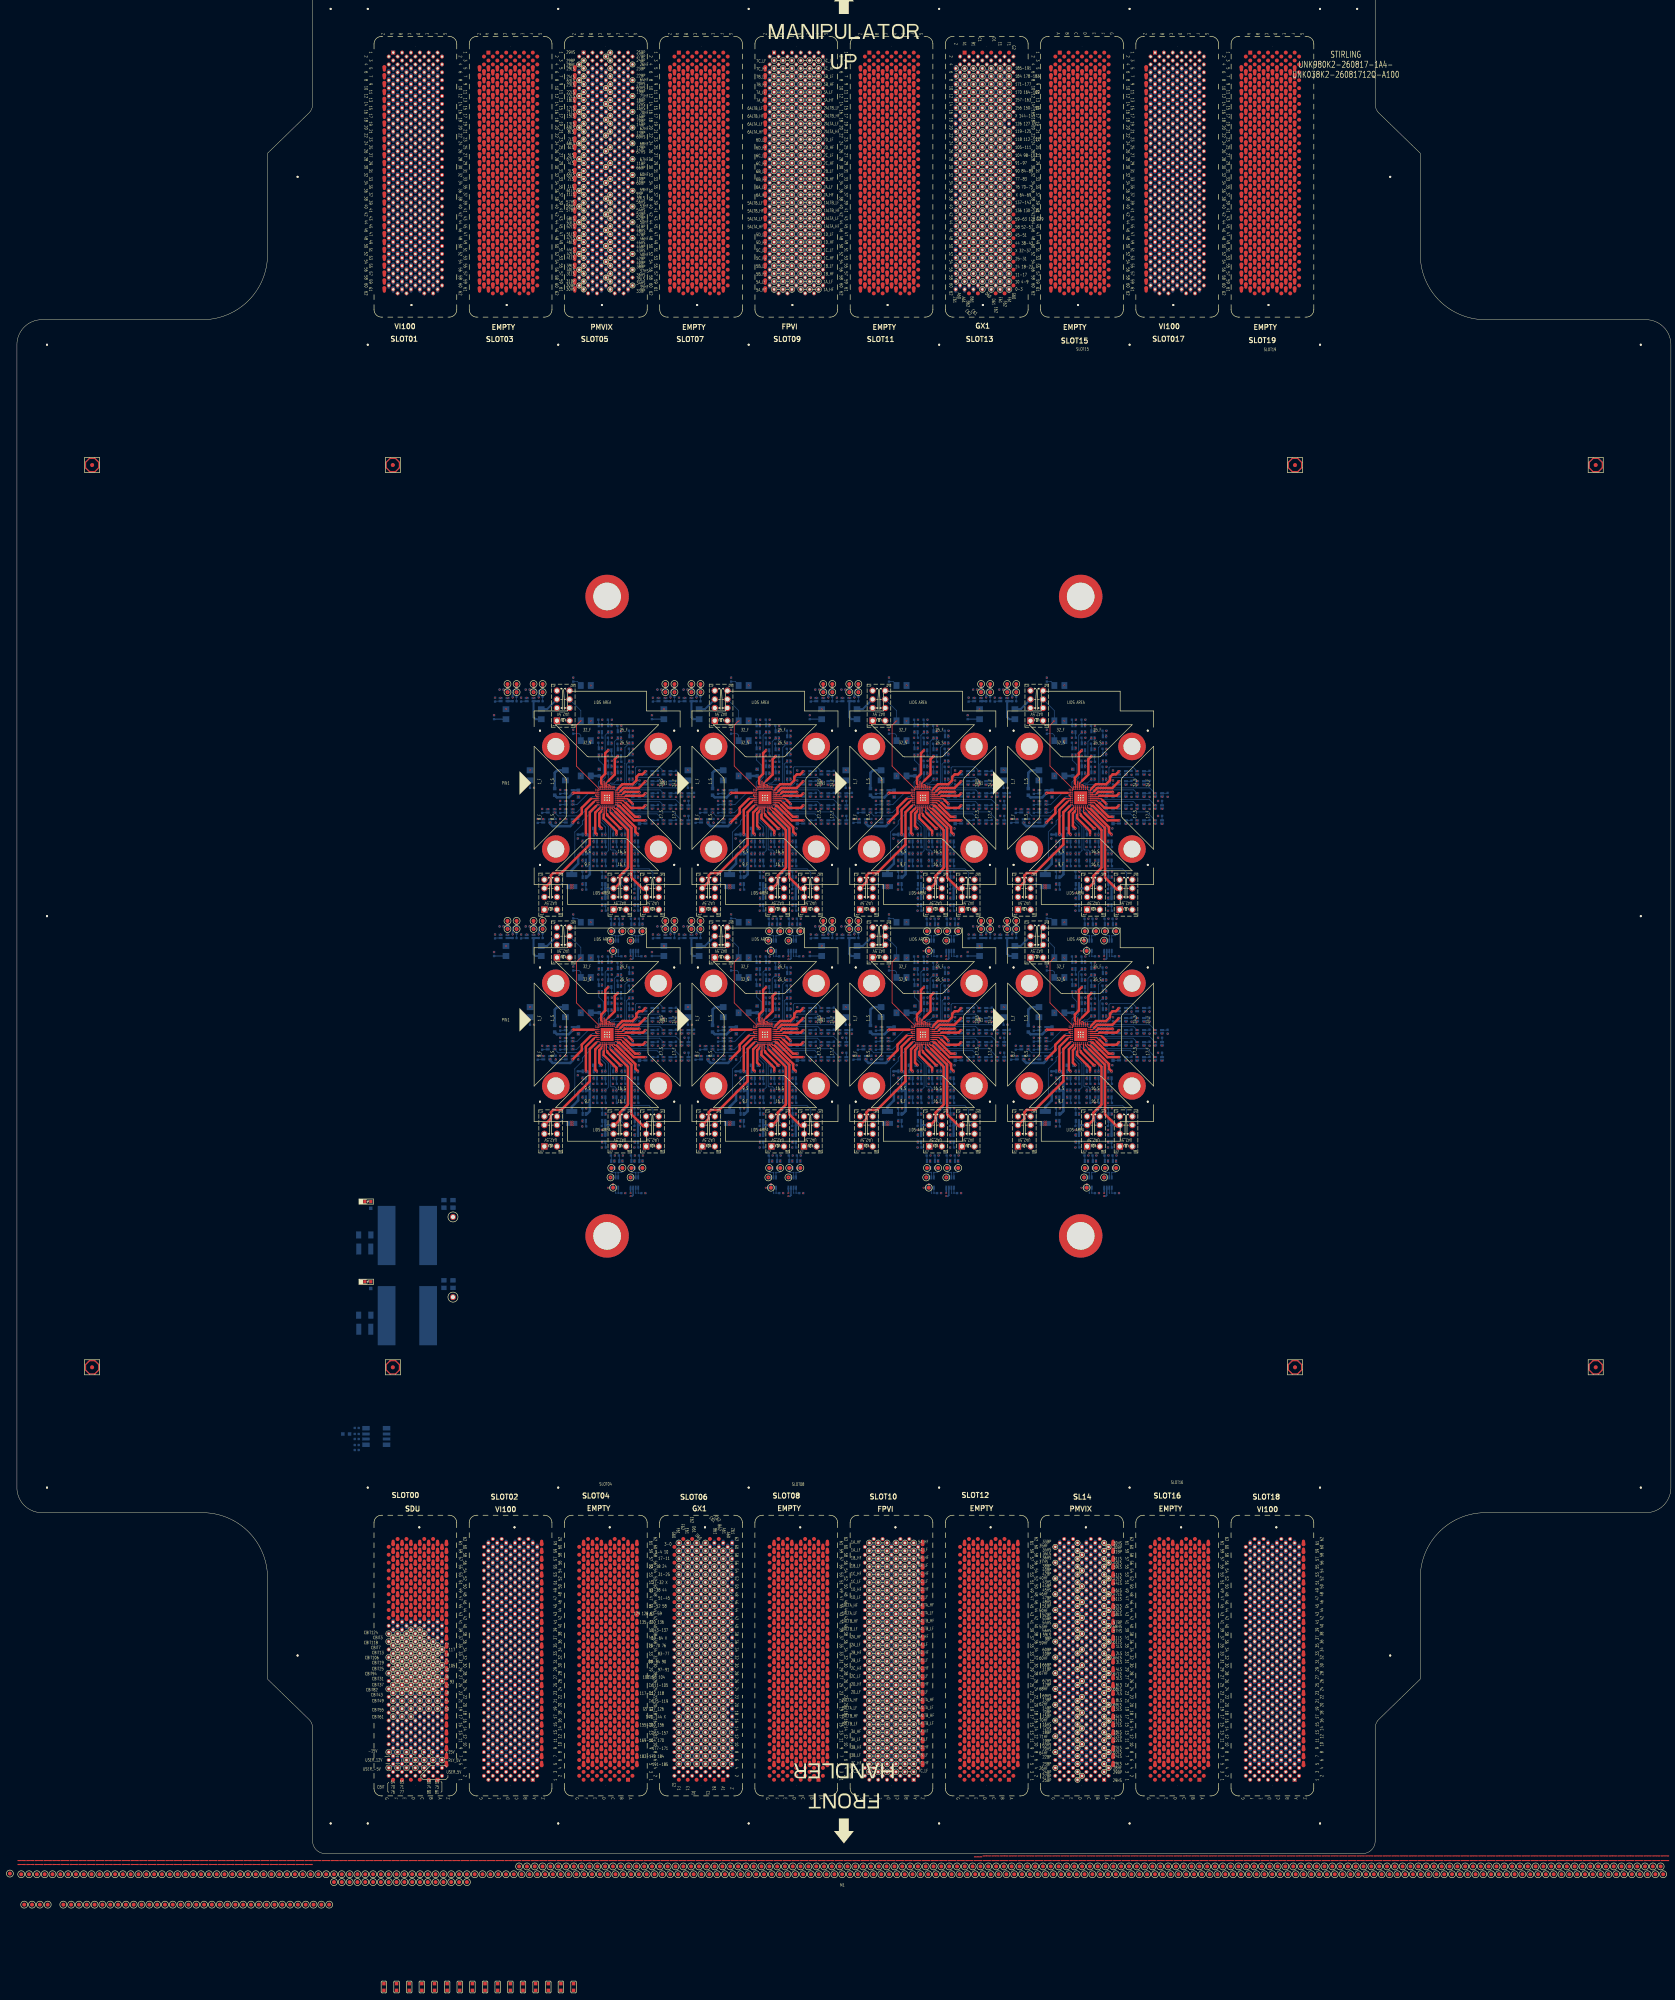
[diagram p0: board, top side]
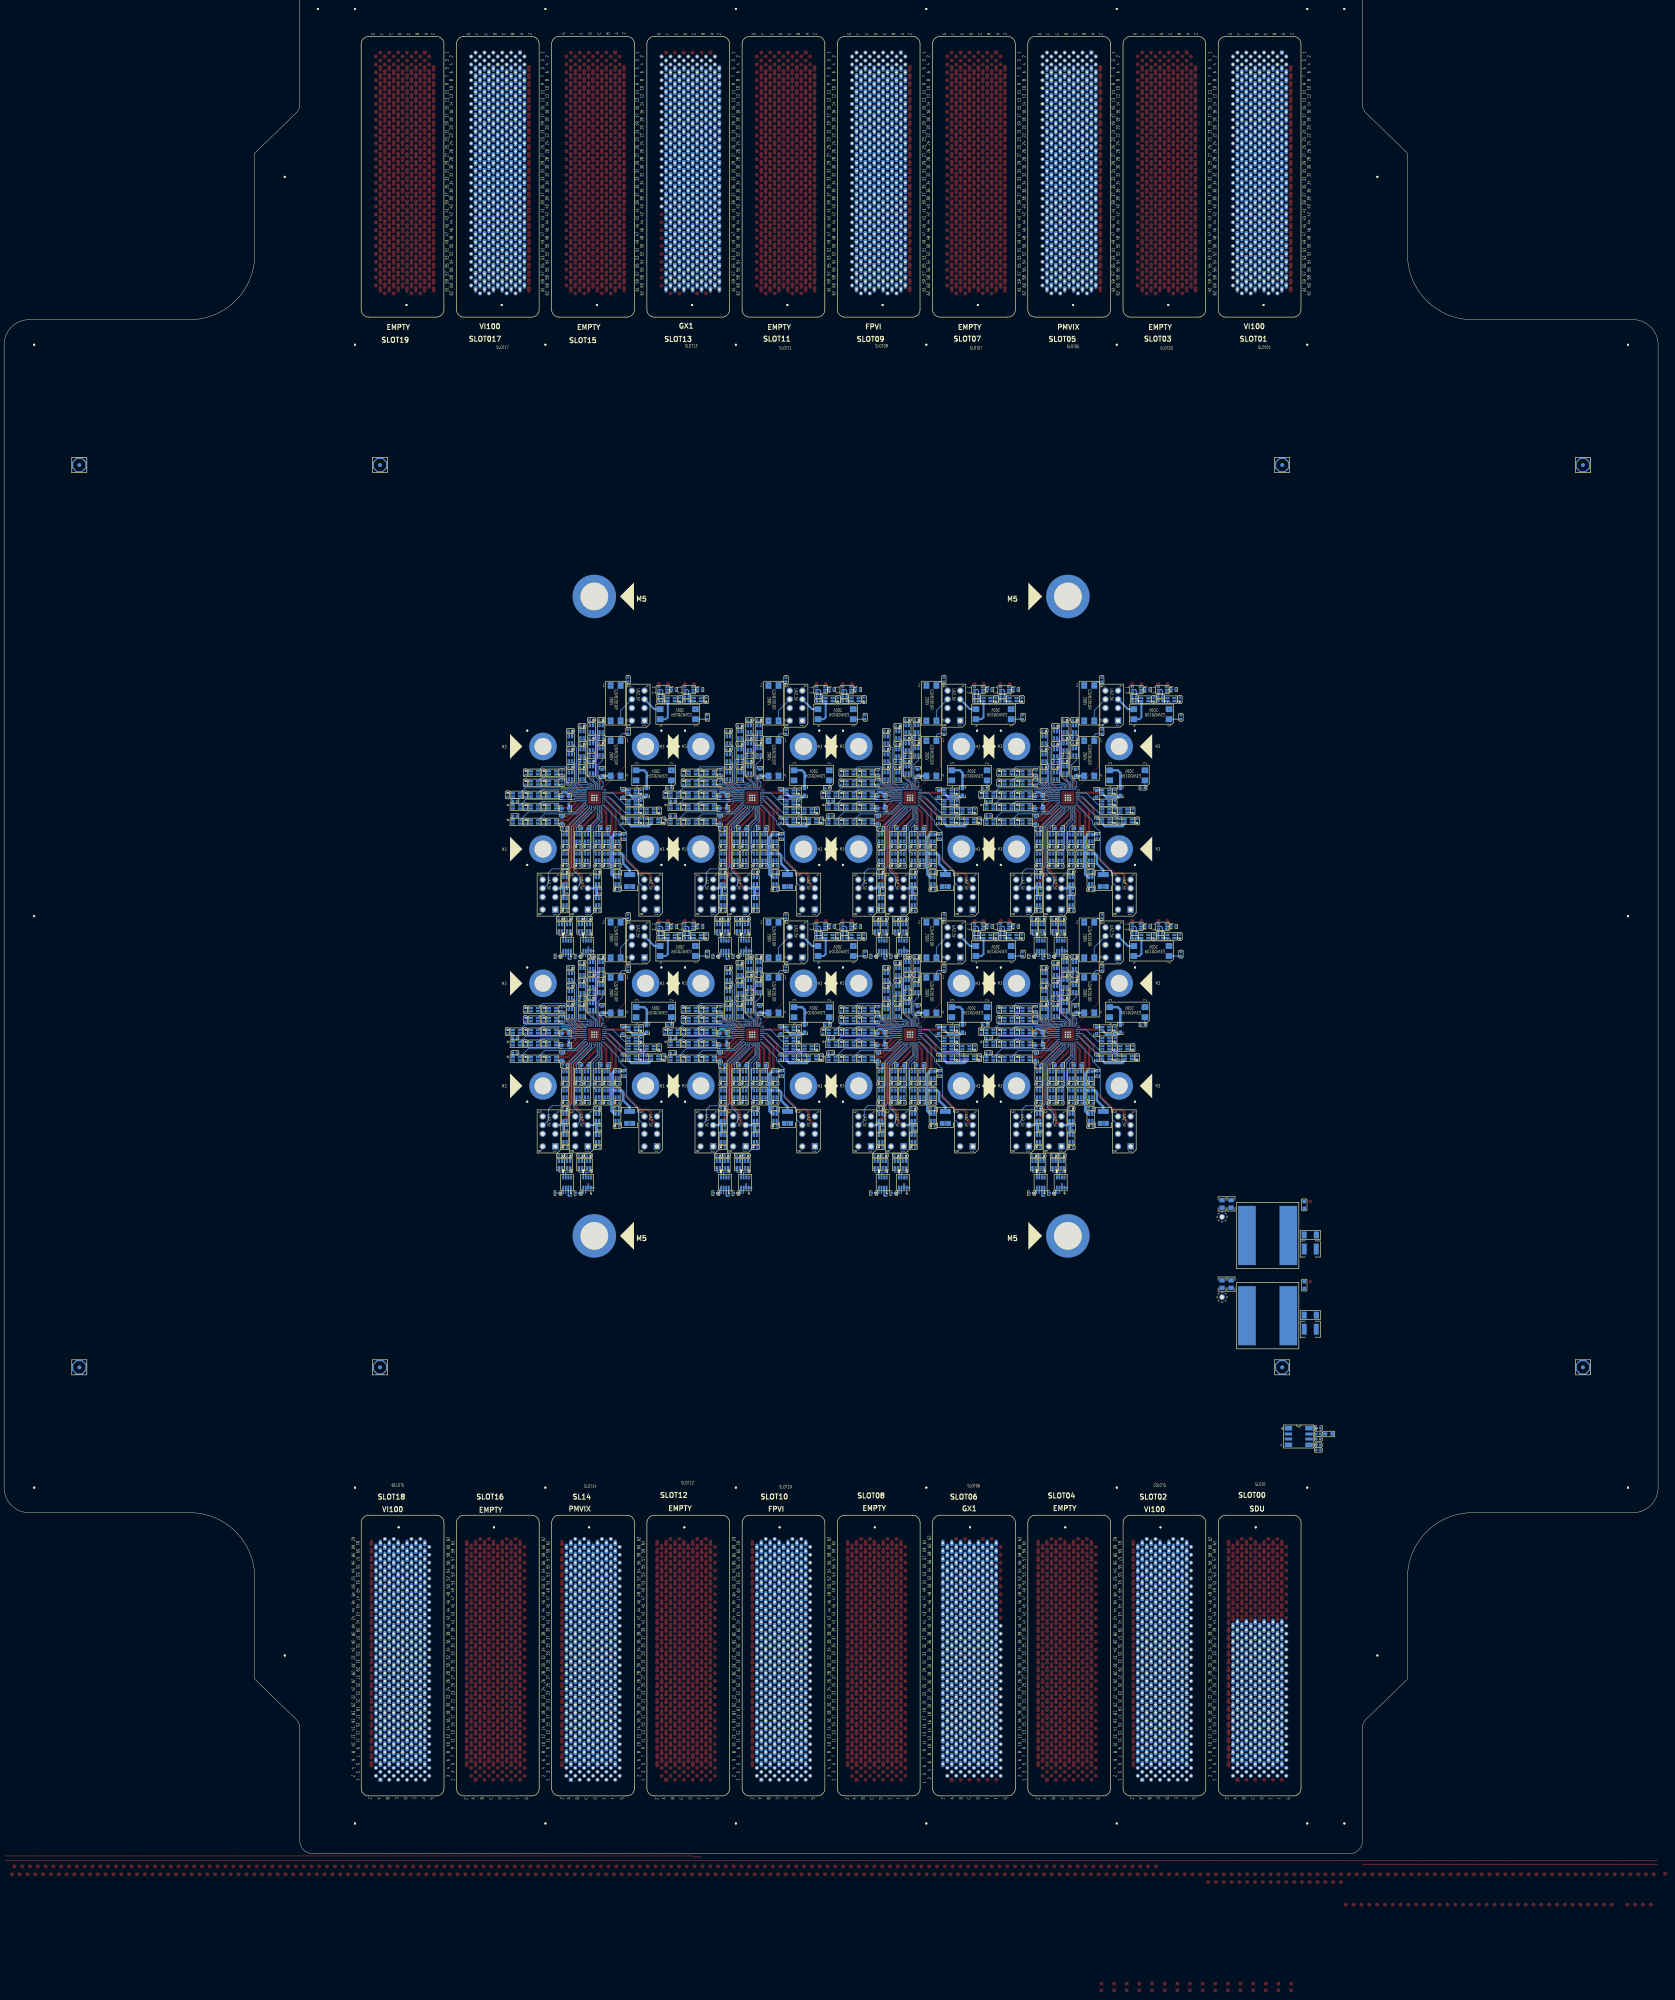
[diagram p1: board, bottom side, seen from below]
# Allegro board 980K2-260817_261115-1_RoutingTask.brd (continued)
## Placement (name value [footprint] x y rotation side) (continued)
NOREF#3645  -  []  244.95 264.23 90 top
NOREF#3646  -  []  271.95 178.07 0 top
NOREF#3647  -  []  269.12 251.6 90 top
NOREF#3648  -  []  163.84 264.78 90 top
NOREF#3649  -  []  188.78 288.49 0 top
NOREF#3650  -  []  277.37 240.3 90 top
NOREF#3651  -  []  168.42 265.58 0 top
NOREF#3652  -  []  279.72 274.65 90 top
NOREF#3653  -  []  146.88 283.95 0 top
NOREF#3654  -  []  152.72 197.6 0 top
NOREF#3655  -  []  237.37 251.6 90 top
NOREF#3656  -  []  216.83 227.03 0 top
NOREF#3657  -  []  133.36 201.22 0 top
NOREF#3658  -  []  268.44 181.72 90 top
NOREF#3659  -  []  195.05 218.82 0 top
NOREF#3660  -  []  149.78 228.3 0 top
NOREF#3661  -  []  243.84 204.78 90 top
NOREF#3662  -  []  180.95 268.91 90 top
NOREF#3663  -  []  232.13 284.66 0 top
NOREF#3664  -  []  268.32 245.63 0 top
NOREF#3665  -  []  159.06 178.07 0 top
NOREF#3666  -  []  196.7 257.85 90 top
NOREF#3667  -  []  209.17 291.95 0 top
NOREF#3668  -  []  271.11 258.18 0 top
NOREF#3669  -  []  176.26 203.76 90 top
NOREF#3670  -  []  192.25 218.02 90 top
NOREF#3671  -  []  164.61 234.89 90 top
NOREF#3672  -  []  150.77 279.22 90 top
NOREF#3673  -  []  272.25 282.59 90 top
NOREF#3674  -  []  268.32 245.63 90 top
NOREF#3675  -  []  142.03 229.03 90 top
NOREF#3676  -  []  169.05 292.28 0 top
NOREF#3677  -  []  269.55 188.99 90 top
NOREF#3678  -  []  188.32 193.35 0 top
NOREF#3679  -  []  148.32 182.05 0 top
NOREF#3680  -  []  228.32 245.63 90 top
NOREF#3681  -  []  269.84 273.7 0 top
NOREF#3682  -  []  270.97 250.88 90 top
NOREF#3683  -  []  251.05 245.49 90 top
NOREF#3684  -  []  214.04 270.63 90 top
NOREF#3685  -  []  179.73 178.35 0 top
NOREF#3686  -  []  201.75 269.17 0 top
NOREF#3687  -  []  266.83 191.93 0 top
NOREF#3688  -  []  147.43 278.27 90 top
NOREF#3689  -  []  237.71 232.86 0 top
NOREF#3690  -  []  147.77 197.6 0 top
NOREF#3691  -  []  232.13 220.09 0 top
NOREF#3692  -  []  219.08 265.79 0 top
NOREF#3693  -  []  147.3 286.19 0 top
NOREF#3694  -  []  253.36 261.22 0 top
NOREF#3695  -  []  203.84 204.78 90 top
NOREF#3696  -  []  149.72 226.19 0 top
NOREF#3697  -  []  233.94 256.75 0 top
NOREF#3698  -  []  251.21 294.89 90 top
NOREF#3699  -  []  192.72 197.6 0 top
NOREF#3700  -  []  170.89 202.32 0 top
NOREF#3701  -  []  213.64 239.09 0 top
NOREF#3702  -  []  156.57 182.05 0 top
NOREF#3703  -  []  138.83 292.23 0 top
NOREF#3704  -  []  199.4 214.54 0 top
NOREF#3705  -  []  228.81 255.7 90 top
NOREF#3706  -  []  179.55 294.49 0 top
NOREF#3707  -  []  234.07 191.6 90 top
NOREF#3708  -  []  265.42 274.72 90 top
NOREF#3709  -  []  189.72 286.19 0 top
NOREF#3710  -  []  154.62 252.5 90 top
NOREF#3711  -  []  143.36 247.38 0 top
NOREF#3712  -  []  100.95 17.15 90 top
NOREF#3713  -  []  148.32 253.35 0 top
NOREF#3714  -  []  135.15 263.21 90 top
NOREF#3715  -  []  242.2 178.35 0 top
NOREF#3716  -  []  163.92 289.94 0 top
NOREF#3717  -  []  200.23 236.17 90 top
NOREF#3718  -  []  208.42 207.82 90 top
NOREF#3719  -  []  191.79 191.93 0 top
NOREF#3720  -  []  214.43 292.23 0 top
NOREF#3721  -  []  136.55 220.49 0 top
NOREF#3722  -  []  195.92 250.88 90 top
NOREF#3723  -  []  157.71 232.86 0 top
NOREF#3724  -  []  134.04 210.63 90 top
NOREF#3725  -  []  163.04 176.5 90 top
NOREF#3726  -  []  191.71 171.3 0 top
NOREF#3727  -  []  117.23 452.29 90 top
NOREF#3728  -  []  293.99 17.15 0 top
NOREF#3729  -  []  191.91 196.43 90 top
NOREF#3730  -  []  241.75 262.32 0 top
NOREF#3731  -  []  307.65 17.78 0 top
NOREF#3732  -  []  276.57 182.05 0 top
NOREF#3733  -  []  243.84 211.67 0 top
NOREF#3734  -  []  243.84 207.82 90 top
NOREF#3735  -  []  279.4 204.45 90 top
NOREF#3736  -  []  188.35 283.79 90 top
NOREF#3737  -  []  261.55 209.94 90 top
NOREF#3738  -  []  196.7 181.72 90 top
NOREF#3739  -  []  231.19 228.49 0 top
NOREF#3740  -  []  133.45 244.35 0 top
NOREF#3741  -  []  233.18 211.85 90 top
NOREF#3742  -  []  148.32 198.18 0 top
NOREF#3743  -  []  143.49 257.85 90 top
NOREF#3744  -  []  155.05 274.25 0 top
NOREF#3745  -  []  186.43 296.46 90 top
NOREF#3746  -  []  151.19 223.92 0 top
NOREF#3747  -  []  261.85 292.49 0 top
NOREF#3748  -  []  193.6 216.55 0 top
NOREF#3749  -  []  277.04 244.35 0 top
NOREF#3750  -  []  272.63 173.69 90 top
NOREF#3751  -  []  279.27 211.67 0 top
NOREF#3752  -  []  214.38 264.09 0 top
NOREF#3753  -  []  164.95 210.32 90 top
NOREF#3754  -  []  144.04 185.96 0 top
NOREF#3755  -  []  228.81 195.7 90 top
R1  10K-0.1-S4  [R0402]  143.76 248.79 0 bottom
R7  4.7K-1-S4-WA  [R0402]  148.21 243.84 90 bottom
R8  4.7K-1-S4-WA  [R0402]  156.46 243.84 90 bottom
R11  5K-1-S4-YA  [R0402]  126.11 293.12 0 bottom
R14  5K-1-S4-YA  [R0402]  132.72 293.12 0 bottom
R15  0-0-S2-KOA  [R0201]  157.14 227.33 0 bottom
R16  5.1-1-S2  [R0201]  157.11 232.54 180 bottom
R17  0-0-S2-KOA  [R0201]  152.06 227.33 0 bottom
R18  5.1-1-S2  [R0201]  152.03 232.54 180 bottom
R19  100K-0.1-S4-YA  [R0402]  126.11 291.95 180 bottom
R20  100K-0.1-S4-YA  [R0402]  132.72 291.95 180 bottom
R41  0-5-S6  [R0603]  92.99 -33.82 270 top
R42  0-5-S6  [R0603]  141.05 -33.82 270 top
REF  VAL  [unnamed#2]  209.55 237.49 0 top
RK2  619-1-S4  [R0402]  140.97 284.23 90 bottom
RK3  619-1-S4  [R0402]  130.52 269.99 0 bottom
RK4  619-1-S4  [R0402]  140.97 297.43 90 bottom
RK5  619-1-S4  [R0402]  137.67 268.99 90 bottom
RK6  619-1-S4  [R0402]  137.67 266.19 90 bottom
RK7  619-1-S4  [R0402]  137.67 264.16 90 bottom
RK8  619-1-S4  [R0402]  137.67 261.62 90 bottom
RK9  619-1-S4  [R0402]  131.95 261.62 90 bottom
RK10  619-1-S4  [R0402]  133.1 264.16 90 bottom
RK11  619-1-S4  [R0402]  143.76 255.02 180 bottom
RK12  619-1-S4  [R0402]  143.76 250.19 180 bottom
RK13  619-1-S4  [R0402]  143.76 244.22 180 bottom
RK14  619-1-S4  [R0402]  146.56 250.19 180 bottom
RK16  619-1-S4  [R0402]  146.56 255.02 180 bottom
RK17  619-1-S4  [R0402]  148.72 255.02 180 bottom
RK18  619-1-S4  [R0402]  148.72 250.19 180 bottom
RK19  619-1-S4  [R0402]  151.51 255.02 180 bottom
RK20  619-1-S4  [R0402]  151.51 250.19 180 bottom
RK21  619-1-S4  [R0402]  153.67 255.02 180 bottom
RK22  619-1-S4  [R0402]  153.67 250.19 180 bottom
RK25  619-1-S4  [R0402]  156.97 255.02 180 bottom
RK26  619-1-S4  [R0402]  156.97 250.19 180 bottom
RK27  619-1-S4  [R0402]  162.43 261.37 270 bottom
RK28  619-1-S4  [R0402]  167 261.37 270 bottom
RK29  619-1-S4  [R0402]  169.67 262.89 180 bottom
RK30  619-1-S4  [R0402]  162.43 265.18 270 bottom
RK31  619-1-S4  [R0402]  167 265.18 270 bottom
RK32  619-1-S4  [R0402]  169.67 266.7 180 bottom
RK33  619-1-S4  [R0402]  162.43 268.22 270 bottom
RK34  619-1-S4  [R0402]  167 268.22 270 bottom
RK35  619-1-S4  [R0402]  171.58 268.22 270 bottom
RK36  619-1-S4  [R0402]  162.43 271.27 270 bottom
RK37  619-1-S4  [R0402]  167 271.27 270 bottom
RK38  619-1-S4  [R0402]  162.43 273.81 270 bottom
RK39  619-1-S4  [R0402]  167 273.81 270 bottom
RK40  619-1-S4  [R0402]  155.58 275.34 0 bottom
RK41  619-1-S4  [R0402]  155.58 279.91 0 bottom
RK42  619-1-S4  [R0402]  155.58 284.48 0 bottom
RK43  619-1-S4  [R0402]  152.65 275.34 0 bottom
RK44  619-1-S4  [R0402]  152.65 281.18 0 bottom
RK45  619-1-S4  [R0402]  152.65 285.75 0 bottom
RK46  619-1-S4  [R0402]  150.24 276.86 0 bottom
RK47  619-1-S4  [R0402]  150.24 282.7 0 bottom
RK48  619-1-S4  [R0402]  150.24 287.27 0 bottom
RK49  619-1-S4  [R0402]  147.83 287.27 0 bottom
RK50  619-1-S4  [R0402]  147.83 281.43 0 bottom
RK51  619-1-S4  [R0402]  148.72 248.79 0 bottom
RK52  619-1-S4  [R0402]  148.72 238.89 180 bottom
RK53  619-1-S4  [R0402]  156.97 248.79 0 bottom
RK54  619-1-S4  [R0402]  156.97 238.89 180 bottom
RK55  619-1-S4  [R0402]  158.12 236.86 180 bottom
RK56  619-1-S4  [R0402]  156.08 236.86 180 bottom
RK57  619-1-S4  [R0402]  153.04 236.86 180 bottom
RK58  619-1-S4  [R0402]  151 236.86 180 bottom
RK59  619-1-S4  [R0402]  121.16 292.35 90 bottom
RK60  619-1-S4  [R0402]  120.9 287.9 90 bottom
RK61  619-1-S4  [R0402]  127.76 292.35 90 bottom
RT1  330-1-S6  [R0603]  89.66 164.34 90 bottom
RT2  330-1-S6  [R0603]  89.66 144.02 90 bottom
SH1  SHORT  [DEFAULT_SHORT_SMALL]  36.45 -2.78 0 top
SH2  SHORT  [DEFAULT_SHORT_SMALL]  38.66 -2.78 0 top
SH3  SHORT  [DEFAULT_SHORT_SMALL]  40.86 -2.78 0 top
SH4  SHORT  [DEFAULT_SHORT_SMALL]  43.06 -2.78 0 top
SHORT1  SHORT  [DEFAULT_SHORT_SMALL]  45.27 -2.78 0 top
SHORT2  SHORT  [DEFAULT_SHORT_SMALL]  51.88 -2.78 0 top
SHORT3  SHORT  [DEFAULT_SHORT_SMALL]  54.08 -2.78 0 top
SHORT4  SHORT  [DEFAULT_SHORT_SMALL]  56.28 -2.78 0 top
SHORT6  SHORT  [DEFAULT_SHORT_SMALL]  58.49 -2.78 0 top
SHORT7  SHORT  [DEFAULT_SHORT_SMALL]  60.69 -2.78 0 top
SHORT8  SHORT  [DEFAULT_SHORT_SMALL]  62.89 -2.78 0 top
SHORT9  SHORT  [DEFAULT_SHORT_SMALL]  65.1 -2.78 0 top
SHORT10  SHORT  [DEFAULT_SHORT_SMALL]  47.47 -2.78 0 top
SHORT11  SHORT  [DEFAULT_SHORT_SMALL]  49.67 -2.78 0 top
SITE1  CU/260817-QFN32-5X5  [SK_QFN5X5_64P_0P5MM_JG_260817]  149.55 267.49 0 top
SITE2  CU/260817-QFN32-5X5  [SK_QFN5X5_64P_0P5MM_JG_260817]  189.55 267.49 0 top
SITE3  CU/260817-QFN32-5X5  [SK_QFN5X5_64P_0P5MM_JG_260817]  229.55 267.49 0 top
SITE4  CU/260817-QFN32-5X5  [SK_QFN5X5_64P_0P5MM_JG_260817]  269.55 267.49 0 top
SITE5  CU/260817-QFN32-5X5  [SK_QFN5X5_64P_0P5MM_JG_260817]  149.55 207.49 0 top
SITE6  CU/260817-QFN32-5X5  [SK_QFN5X5_64P_0P5MM_JG_260817]  189.55 207.49 0 top
SITE7  CU/260817-QFN32-5X5  [SK_QFN5X5_64P_0P5MM_JG_260817]  229.55 207.49 0 top
SITE8  CU/260817-QFN32-5X5  [SK_QFN5X5_64P_0P5MM_JG_260817]  269.55 207.49 0 top
SLOT0  DIAMONDX_X1_DUT  [PG_LTXDX_F_X1_SDU_SL00_V3]  209.55 237.49 0 top
SLOT01  VI100  [PG_LTXDX_F_X1_VI100_SL01_V3]  209.55 237.49 0 top
SLOT02  VI100  [PG_LTXDX_F_X1_VI100_SL02_V3]  209.55 237.49 0 top
SLOT03  DIAMONDX_X1_DUT  [PG_LTXDX_F_X1_PG400ND_SL03_V3]  209.55 237.49 0 top
SLOT04  DIAMONDX_X1_DUT  [PG_LTXDX_F_X1_PG400ND_SL04_V3]  209.55 237.49 0 top
SLOT05  PMVIX  [PG_LTXDX_F_X1_PMVI_SL05_V3]  209.55 237.49 0 top
SLOT06  GX1X  [PG_LTXDX_F_X1_GX1_SL06_V2]  209.55 237.49 0 top
SLOT07  DIAMONDX_X1_DUT  [PG_LTXDX_F_X1_PG400ND_SL07_V3]  209.55 237.49 0 top
SLOT08  DIAMONDX_X1_DUT  [PG_LTXDX_F_X1_PG400ND_SL08_V3]  209.55 237.49 0 top
SLOT09  FPVI_SL09  [PG_LTXDX_F_X1_FPVI_SL09_V3]  209.55 237.49 0 top
SLOT10  FPVI_SL10  [PG_LTXDX_F_X1_FPVI_SL10_V3]  209.55 237.49 0 top
SLOT11  DIAMONDX_X1_DUT  [PG_LTXDX_F_X1_PG400ND_SL11_V3]  209.55 237.49 0 top
SLOT12  DIAMONDX_X1_DUT  [PG_LTXDX_F_X1_PG400ND_SL12_V3]  209.55 237.49 0 top
SLOT13  GX1X  [PG_LTXDX_F_X1_GX1_SL13_V2]  209.55 237.49 0 top
SLOT14  PMVIX  [PG_LTXDX_F_X1_PMVI_SL14_V3]  209.55 237.49 0 top
SLOT15  DIAMONDX_X1_DUT  [PG_LTXDX_F_X1_PG400ND_SL15_V3]  209.55 237.49 0 top
SLOT16  DIAMONDX_X1_DUT  [PG_LTXDX_F_X1_PG400ND_SL16_V3]  209.55 237.49 0 top
SLOT17  VI100  [PG_LTXDX_F_X1_VI100_SL17_V3]  209.55 237.49 0 top
SLOT18  VI100  [PG_LTXDX_F_X1_VI100_SL18_V3]  209.55 237.49 0 top
SLOT19  DIAMONDX_X1_DUT  [PG_LTXDX_F_X1_PG400ND_SL19_V3]  209.55 237.49 0 top
ST1  SHORT  [DEFAULT_SHORT_SMALL]  67.3 -2.78 0 top
ST2  SHORT  [DEFAULT_SHORT_SMALL]  69.5 -2.78 0 top
STIRLING  REF-CODE-CHIP  [CHIP_CODE]  336.55 455.93 0 top
TP_ATT_F  TP01  [TP_040_T]  395.35 -5.25 0 top
TP_ATT_S  TP01  [TP_040_T]  397.33 -5.25 0 top
TP_C1A_F  TP01  [TP_040_T]  399.31 -5.25 0 top
TP_C1A_S  TP01  [TP_040_T]  401.29 -5.25 0 top
TP_C1B_F  TP01  [TP_040_T]  403.28 -5.25 0 top
TP_C1B_S  TP01  [TP_040_T]  405.26 -5.25 0 top
TP_C2A_F  TP01  [TP_040_T]  407.24 -5.25 0 top
TP_C2A_S  TP01  [TP_040_T]  409.22 -5.25 0 top
TP_C2B_F  TP01  [TP_040_T]  411.2 -5.25 0 top
TP_C2B_S  TP01  [TP_040_T]  413.18 -5.25 0 top
TP_C3A_F  TP01  [TP_040_T]  415.16 -5.25 0 top
TP_C3A_S  TP01  [TP_040_T]  417.14 -5.25 0 top
TP_C3B_F  TP01  [TP_040_T]  1.85 -12.95 0 top
TP_C3B_S  TP01  [TP_040_T]  3.84 -12.95 0 top
TP_GA1_S  TP01  [TP_040_T]  5.82 -12.95 0 top
TP_GA2_S  TP01  [TP_040_T]  7.8 -12.95 0 top
TP_GB1_S  TP01  [TP_040_T]  -1.78 -5.08 0 top
TP_GB2_S  TP01  [TP_040_T]  11.76 -12.95 0 top
TP_IN+_1  TP01  [TP_040_T]  126.61 294.24 0 top
TP_IN+_2  TP01  [TP_040_T]  133.22 294.24 0 top
TP_IN+_3  TP01  [TP_040_T]  155.68 233.69 180 top
TP_IN+_4  TP01  [TP_040_T]  150.6 233.69 180 top
TP_IN-_1  TP01  [TP_040_T]  124.31 294.24 0 top
TP_IN-_2  TP01  [TP_040_T]  130.91 294.24 0 top
TP_IN-_3  TP01  [TP_040_T]  158.52 233.69 180 top
TP_IN-_4  TP01  [TP_040_T]  153.44 233.69 180 top
TP_IS1N_F  TP01  [TP_040_T]  13.74 -12.95 0 top
TP_IS1N_S  TP01  [TP_040_T]  15.72 -12.95 0 top
TP_IS1P_F  TP01  [TP_040_T]  17.7 -12.95 0 top
TP_IS2N_F  TP01  [TP_040_T]  19.69 -12.95 0 top
TP_IS2N_S  TP01  [TP_040_T]  21.67 -12.95 0 top
TP_IS2P_S  TP01  [TP_040_T]  23.65 -12.95 0 top
TP_OPTO_F  TP01  [TP_040_T]  25.63 -12.95 0 top
TP_OPTO_S  TP01  [TP_040_T]  27.61 -12.95 0 top
TP_OUT+_1  TP01  [TP_040_T]  126.61 296.31 0 top
TP_OUT+_2  TP01  [TP_040_T]  133.22 296.31 0 top
TP_OUT-_1  TP01  [TP_040_T]  124.31 296.31 0 top
TP_OUT-_2  TP01  [TP_040_T]  130.91 296.31 0 top
TP_OUT_1  TP01  [TP_040_T]  155.49 231.3 180 top
TP_OUT_2  TP01  [TP_040_T]  150.41 231.3 180 top
TP_REF_1  TP01  [TP_040_T]  29.59 -12.95 0 top
TP_REF_2  TP01  [TP_040_T]  151.06 228.7 180 top
TP_SCL_F  TP01  [TP_040_T]  31.57 -12.95 0 top
TP_SDA_F  TP01  [TP_040_T]  33.55 -12.95 0 top
TP_SDA_S  TP01  [TP_040_T]  35.53 -12.95 0 top
TP_SDUP5V_FILTER  TP03-D  [TP_060_040]  110.49 161.29 0 top
TP_SDUR5V_FILTER  TP03-D  [TP_060_040]  110.49 140.97 0 top
TP_SRD_F  TP01  [TP_040_T]  37.52 -12.95 0 top
TP_SRD_S  TP01  [TP_040_T]  39.5 -12.95 0 top
TP_SRG_F  TP01  [TP_040_T]  41.48 -12.95 0 top
TP_SRG_S  TP01  [TP_040_T]  43.46 -12.95 0 top
TP_SRS_F  TP01  [TP_040_T]  45.44 -12.95 0 top
TP_SRS_S  TP01  [TP_040_T]  47.42 -12.95 0 top
TP_STB_F  TP01  [TP_040_T]  49.4 -12.95 0 top
TP_STB_S  TP01  [TP_040_T]  51.38 -12.95 0 top
TP_VCC_F  TP01  [TP_040_T]  53.37 -12.95 0 top
TP_VCC_S  TP01  [TP_040_T]  55.35 -12.95 0 top
TP_VDD0_F  TP01  [TP_040_T]  57.33 -12.95 0 top
TP_VDD0_S  TP01  [TP_040_T]  59.31 -12.95 0 top
TP_VDD1_S  TP01  [TP_040_T]  61.29 -12.95 0 top
TP_VDD2_S  TP01  [TP_040_T]  63.27 -12.95 0 top
TP_VDDI_F  TP01  [TP_040_T]  65.25 -12.95 0 top
TP_VDDI_S  TP01  [TP_040_T]  67.23 -12.95 0 top
TP_VIN_F  TP01  [TP_040_T]  69.22 -12.95 0 top
TP_VIN_S  TP01  [TP_040_T]  71.2 -12.95 0 top
TP_VO1_S  TP01  [TP_040_T]  73.18 -12.95 0 top
TP_VO2_S  TP01  [TP_040_T]  75.16 -12.95 0 top
TP_VSR_F  TP01  [TP_040_T]  77.14 -12.95 0 top
TP_VSR_S  TP01  [TP_040_T]  79.12 -12.95 0 top
U1  TLV3604DCKR-SC70  [SC70]  125.61 294.89 270 bottom
U2  TLV3604DCKR-SC70  [SC70]  132.22 294.89 270 bottom
U3  INA186A3QDDFRQ1-SOT23-8  [SOT23_8P_0P65MM_H1P3MM]  156.46 230 180 bottom
U4  INA186A3QDDFRQ1-SOT23-8  [SOT23_8P_0P65MM_H1P3MM]  151.38 230 180 bottom
UNK0BS1  SHORT  [DEFAULT_SHORT_SMALL]  296.43 -1.79 0 top
UNK0BS2  SHORT  [DEFAULT_SHORT_SMALL]  298.63 -1.79 0 top
UNK1SH1  SHORT  [DEFAULT_SHORT_SMALL]  73.91 -2.78 0 top
UNK1SH2  SHORT  [DEFAULT_SHORT_SMALL]  263.38 -0.6 0 top
UNK1SH3  SHORT  [DEFAULT_SHORT_SMALL]  283.21 -0.6 0 top
UNK1SH4  SHORT  [DEFAULT_SHORT_SMALL]  285.42 -0.6 0 top
UNK1SH5  SHORT  [DEFAULT_SHORT_SMALL]  287.62 -0.6 0 top
UNK1SH6  SHORT  [DEFAULT_SHORT_SMALL]  289.82 -0.6 0 top
UNK1SH7  SHORT  [DEFAULT_SHORT_SMALL]  292.03 -0.6 0 top
UNK1SH8  SHORT  [DEFAULT_SHORT_SMALL]  294.23 -0.6 0 top
UNK1SH9  SHORT  [DEFAULT_SHORT_SMALL]  296.43 -0.6 0 top
UNK1SH10  SHORT  [DEFAULT_SHORT_SMALL]  243.55 -0.84 0 top
UNK1SH11  SHORT  [DEFAULT_SHORT_SMALL]  71.71 -2.78 0 top
UNK1SH12  SHORT  [DEFAULT_SHORT_SMALL]  245.76 -0.6 0 top
UNK1SH13  SHORT  [DEFAULT_SHORT_SMALL]  247.96 -0.6 0 top
UNK1SH14  SHORT  [DEFAULT_SHORT_SMALL]  250.16 -0.6 0 top
UNK1SH15  SHORT  [DEFAULT_SHORT_SMALL]  252.37 -0.6 0 top
UNK1SH16  SHORT  [DEFAULT_SHORT_SMALL]  254.57 -0.6 0 top
UNK1SH17  SHORT  [DEFAULT_SHORT_SMALL]  256.77 -0.6 0 top
UNK1SH18  SHORT  [DEFAULT_SHORT_SMALL]  258.98 -0.6 0 top
UNK1SH19  SHORT  [DEFAULT_SHORT_SMALL]  261.18 -0.6 0 top
UNK1SH20  SHORT  [DEFAULT_SHORT_SMALL]  265.59 -0.6 0 top
UNK1SH21  SHORT  [DEFAULT_SHORT_SMALL]  267.79 -0.6 0 top
UNK1SH22  SHORT  [DEFAULT_SHORT_SMALL]  269.99 -0.6 0 top
UNK1SH23  SHORT  [DEFAULT_SHORT_SMALL]  272.2 -0.6 0 top
UNK1SH24  SHORT  [DEFAULT_SHORT_SMALL]  274.4 -0.6 0 top
UNK1SH25  SHORT  [DEFAULT_SHORT_SMALL]  276.6 -0.6 0 top
UNK1SH26  SHORT  [DEFAULT_SHORT_SMALL]  278.81 -0.6 0 top
UNK1SH27  SHORT  [DEFAULT_SHORT_SMALL]  281.01 -0.6 0 top
UNK2C48  0.01U-100-X7R-S6-MU  [C0603]  187.57 273.87 90 bottom
UNK2C49  0.01U-100-X7R-S6-MU  [C0603]  176.27 268.99 270 bottom
UNK2C50  0.01U-100-X7R-S6-MU  [C0603]  182.28 268.54 270 bottom
UNK2C53  1U-16-X5R-S4-YA  [C0402]  182.24 261.62 270 bottom
UNK2C54  2.2U-16-X-S4-MU  [C0402]  176.52 261.62 270 bottom
UNK2C58  1U-16-X5R-S4-YA  [C0402]  182.11 257.68 270 bottom
UNK2C59  4.7U-100-X-SB-MU  [C1210]  180.59 246.51 270 bottom
UNK2C60  0.01U-100-X7R-S6-MU  [C0603]  187.01 259.72 0 bottom
UNK2C61  0.01U-100-X7R-S6-MU  [C0603]  196.88 264.78 180 bottom
UNK2C62  2.2U-16-X-S4-MU  [C0402]  197.07 259.72 0 bottom
UNK2C63  0.01U-100-X7R-S6-MU  [C0603]  197.73 261.82 90 bottom
UNK2C64  0.01U-100-X7R-S6-MU  [C0603]  196.88 267.82 180 bottom
UNK2C65  0.1U-25-X7R-S4-MU  [C0402]  197.73 271.37 90 bottom
UNK2C66  0.1U-25-X7R-S4-MU  [C0402]  192.65 276.61 180 bottom
UNK2C67  0.1U-25-X7R-S4-MU  [C0402]  190.24 278.13 180 bottom
UNK2C68  0.1U-25-X7R-S4-MU  [C0402]  187.83 282.7 180 bottom
UNK2C69  0.01U-100-X7R-S6-MU  [C0603]  191.96 259.72 0 bottom
UNK2C70  0.1U-25-X7R-S4-MU  [C0402]  162.8 294.89 180 bottom
UNK2C71  0.1U-25-X7R-S4-MU  [C0402]  169.42 294.89 180 bottom
UNK2C72  0.1U-25-X7R-S4-MU  [C0402]  198.75 227.33 0 bottom
UNK2C73  0.1U-25-X7R-S4-MU  [C0402]  193.67 227.33 0 bottom
UNK2C74  0.1U-25-X7R-S4-MU  [C0402]  197.73 273.91 90 bottom
UNK2K1  UA2-5NJ-A-V3  [RL_NECUA2_5V_V3]  178.43 290.63 270 bottom
UNK2K2  G3VM-201DR  [RL_G3VM201DR_200V]  184.14 277.5 0 bottom
UNK2K3  G3VM-201DR  [RL_G3VM201DR_200V]  174.49 273.18 90 bottom
UNK2K4  G3VM-201DR  [RL_G3VM201DR_200V]  184.14 291.47 0 bottom
UNK2K5  G3VM-51UR-5V-VSON4  [RL_G3VM_4P_VSON4]  179.95 268.99 0 bottom
UNK2K6  G3VM-51UR-5V-VSON4  [RL_G3VM_4P_VSON4]  179.95 266.19 0 bottom
UNK2K7  G3VM-51UR-5V-VSON4  [RL_G3VM_4P_VSON4]  179.95 264.16 0 bottom
UNK2K8  G3VM-51UR-5V-VSON4  [RL_G3VM_4P_VSON4]  179.95 261.62 0 bottom
UNK2K9  G3VM-51UR-5V-VSON4  [RL_G3VM_4P_VSON4]  174.24 261.62 0 bottom
UNK2K10  G3VM-51UR-5V-VSON4  [RL_G3VM_4P_VSON4]  175.38 264.16 0 bottom
UNK2K11  G3VM-51UR-5V-VSON4  [RL_G3VM_4P_VSON4]  183.76 257.3 90 bottom
UNK2K12  G3VM-51UR-5V-VSON4  [RL_G3VM_4P_VSON4]  183.76 252.48 90 bottom
UNK2K13  G3VM-51UR-5V-VSON4  [RL_G3VM_4P_VSON4]  183.76 246.51 90 bottom
UNK2K14  G3VM-51UR-5V-VSON4  [RL_G3VM_4P_VSON4]  186.56 252.48 90 bottom
UNK2K15  UA2-5NJ-A-V3  [RL_NECUA2_5V_V3]  175.25 242.75 270 bottom
UNK2K16  G3VM-51UR-5V-VSON4  [RL_G3VM_4P_VSON4]  186.56 257.3 90 bottom
UNK2K17  G3VM-51UR-5V-VSON4  [RL_G3VM_4P_VSON4]  188.72 257.3 90 bottom
UNK2K18  G3VM-51UR-5V-VSON4  [RL_G3VM_4P_VSON4]  188.72 252.48 90 bottom
UNK2K19  G3VM-51UR-5V-VSON4  [RL_G3VM_4P_VSON4]  191.51 257.3 90 bottom
UNK2K20  G3VM-51UR-5V-VSON4  [RL_G3VM_4P_VSON4]  191.51 252.48 90 bottom
UNK2K21  G3VM-51UR-5V-VSON4  [RL_G3VM_4P_VSON4]  193.67 257.3 90 bottom
UNK2K22  G3VM-51UR-5V-VSON4  [RL_G3VM_4P_VSON4]  193.67 252.48 90 bottom
UNK2K23  UA2-5NJ-A-V3  [RL_NECUA2_5V_V3]  192.78 242.75 270 bottom
UNK2K24  UA2-5NJ-A-V3  [RL_NECUA2_5V_V3]  201.04 242.75 270 bottom
UNK2K25  G3VM-51UR-5V-VSON4  [RL_G3VM_4P_VSON4]  196.97 257.3 90 bottom
UNK2K26  G3VM-51UR-5V-VSON4  [RL_G3VM_4P_VSON4]  196.97 252.48 90 bottom
UNK2K27  G3VM-51UR-5V-VSON4  [RL_G3VM_4P_VSON4]  200.15 261.37 180 bottom
UNK2K28  G3VM-51UR-5V-VSON4  [RL_G3VM_4P_VSON4]  204.72 261.37 180 bottom
UNK2K29  G3VM-51UR-5V-VSON4  [RL_G3VM_4P_VSON4]  209.29 261.37 180 bottom
UNK2K30  G3VM-51UR-5V-VSON4  [RL_G3VM_4P_VSON4]  200.15 265.18 180 bottom
UNK2K31  G3VM-51UR-5V-VSON4  [RL_G3VM_4P_VSON4]  204.72 265.18 180 bottom
UNK2K32  G3VM-51UR-5V-VSON4  [RL_G3VM_4P_VSON4]  209.29 265.18 180 bottom
UNK2K33  G3VM-51UR-5V-VSON4  [RL_G3VM_4P_VSON4]  200.15 268.22 180 bottom
UNK2K34  G3VM-51UR-5V-VSON4  [RL_G3VM_4P_VSON4]  204.72 268.22 180 bottom
UNK2K35  G3VM-51UR-5V-VSON4  [RL_G3VM_4P_VSON4]  209.29 268.22 180 bottom
UNK2K36  G3VM-51UR-5V-VSON4  [RL_G3VM_4P_VSON4]  200.15 271.27 180 bottom
UNK2K37  G3VM-51UR-5V-VSON4  [RL_G3VM_4P_VSON4]  204.72 271.27 180 bottom
UNK2K38  G3VM-51UR-5V-VSON4  [RL_G3VM_4P_VSON4]  200.15 273.81 180 bottom
UNK2K39  G3VM-51UR-5V-VSON4  [RL_G3VM_4P_VSON4]  204.72 273.81 180 bottom
UNK2K40  G3VM-51UR-5V-VSON4  [RL_G3VM_4P_VSON4]  195.57 273.05 270 bottom
UNK2K41  G3VM-51UR-5V-VSON4  [RL_G3VM_4P_VSON4]  195.57 277.62 270 bottom
UNK2K42  G3VM-51UR-5V-VSON4  [RL_G3VM_4P_VSON4]  195.57 282.19 270 bottom
UNK2K43  G3VM-51UR-5V-VSON4  [RL_G3VM_4P_VSON4]  192.65 273.05 270 bottom
UNK2K44  G3VM-51UR-5V-VSON4  [RL_G3VM_4P_VSON4]  192.65 278.89 270 bottom
UNK2K45  G3VM-51UR-5V-VSON4  [RL_G3VM_4P_VSON4]  192.65 283.46 270 bottom
UNK2K46  G3VM-51UR-5V-VSON4  [RL_G3VM_4P_VSON4]  190.24 274.57 270 bottom
UNK2K47  G3VM-51UR-5V-VSON4  [RL_G3VM_4P_VSON4]  190.24 280.42 270 bottom
UNK2K48  G3VM-51UR-5V-VSON4  [RL_G3VM_4P_VSON4]  190.24 284.99 270 bottom
UNK2K49  G3VM-51UR-5V-VSON4  [RL_G3VM_4P_VSON4]  187.83 284.99 270 bottom
UNK2K50  G3VM-51UR-5V-VSON4  [RL_G3VM_4P_VSON4]  187.83 279.15 270 bottom
UNK2K51  G3VM-51UR-5V-VSON4  [RL_G3VM_4P_VSON4]  188.72 246.51 270 bottom
UNK2K52  G3VM-51UR-5V-VSON4  [RL_G3VM_4P_VSON4]  188.72 241.17 90 bottom
UNK2K53  G3VM-51UR-5V-VSON4  [RL_G3VM_4P_VSON4]  196.97 246.51 270 bottom
UNK2K54  G3VM-51UR-5V-VSON4  [RL_G3VM_4P_VSON4]  196.97 241.17 90 bottom
UNK2K55  G3VM-51UR-5V-VSON4  [RL_G3VM_4P_VSON4]  163.44 292.35 0 bottom
UNK2K56  G3VM-201DR  [RL_G3VM201DR_200V]  168.4 288.67 90 bottom
UNK2K57  G3VM-51UR-5V-VSON4  [RL_G3VM_4P_VSON4]  198.11 234.57 270 bottom
UNK2K58  G3VM-51UR-5V-VSON4  [RL_G3VM_4P_VSON4]  196.08 234.57 270 bottom
UNK2K59  G3VM-51UR-5V-VSON4  [RL_G3VM_4P_VSON4]  193.03 234.57 270 bottom
UNK2K60  G3VM-51UR-5V-VSON4  [RL_G3VM_4P_VSON4]  191 234.57 270 bottom
UNK2K61  G3VM-51UR-5V-VSON4  [RL_G3VM_4P_VSON4]  170.05 292.35 0 bottom
UNK2R1  10K-0.1-S4  [R0402]  183.76 248.79 0 bottom
UNK2R7  4.7K-1-S4-WA  [R0402]  188.21 243.84 90 bottom
UNK2R8  4.7K-1-S4-WA  [R0402]  196.46 243.84 90 bottom
UNK2R11  5K-1-S4-YA  [R0402]  166.11 293.12 0 bottom
UNK2R14  5K-1-S4-YA  [R0402]  172.71 293.12 0 bottom
UNK2R15  0-0-S2-KOA  [R0201]  197.14 227.33 0 bottom
UNK2R16  5.1-1-S2  [R0201]  197.11 232.54 180 bottom
UNK2R17  0-0-S2-KOA  [R0201]  192.06 227.33 0 bottom
UNK2R18  5.1-1-S2  [R0201]  192.03 232.54 180 bottom
UNK2R19  100K-0.1-S4-YA  [R0402]  166.11 291.95 180 bottom
UNK2R20  100K-0.1-S4-YA  [R0402]  172.71 291.95 180 bottom
UNK2R43  0-5-S6  [R0603]  137.84 -33.82 270 top
UNK2R44  0-5-S6  [R0603]  134.64 -33.82 270 top
UNK2RK2  619-1-S4  [R0402]  180.97 284.23 90 bottom
UNK2RK3  619-1-S4  [R0402]  170.52 269.99 0 bottom
UNK2RK4  619-1-S4  [R0402]  180.97 297.43 90 bottom
UNK2RK5  619-1-S4  [R0402]  177.67 268.99 90 bottom
UNK2RK6  619-1-S4  [R0402]  177.67 266.19 90 bottom
UNK2RK7  619-1-S4  [R0402]  177.67 264.16 90 bottom
UNK2RK8  619-1-S4  [R0402]  177.67 261.62 90 bottom
UNK2RK9  619-1-S4  [R0402]  171.95 261.62 90 bottom
UNK2RK10  619-1-S4  [R0402]  173.1 264.16 90 bottom
UNK2RK11  619-1-S4  [R0402]  183.76 255.02 180 bottom
UNK2RK12  619-1-S4  [R0402]  183.76 250.19 180 bottom
UNK2RK13  619-1-S4  [R0402]  183.76 244.22 180 bottom
UNK2RK14  619-1-S4  [R0402]  186.56 250.19 180 bottom
UNK2RK16  619-1-S4  [R0402]  186.56 255.02 180 bottom
UNK2RK17  619-1-S4  [R0402]  188.72 255.02 180 bottom
UNK2RK18  619-1-S4  [R0402]  188.72 250.19 180 bottom
UNK2RK19  619-1-S4  [R0402]  191.51 255.02 180 bottom
UNK2RK20  619-1-S4  [R0402]  191.51 250.19 180 bottom
UNK2RK21  619-1-S4  [R0402]  193.67 255.02 180 bottom
UNK2RK22  619-1-S4  [R0402]  193.67 250.19 180 bottom
UNK2RK25  619-1-S4  [R0402]  196.97 255.02 180 bottom
UNK2RK26  619-1-S4  [R0402]  196.97 250.19 180 bottom
UNK2RK27  619-1-S4  [R0402]  202.43 261.37 270 bottom
UNK2RK28  619-1-S4  [R0402]  207 261.37 270 bottom
UNK2RK29  619-1-S4  [R0402]  209.67 262.89 180 bottom
UNK2RK30  619-1-S4  [R0402]  202.43 265.18 270 bottom
UNK2RK31  619-1-S4  [R0402]  207 265.18 270 bottom
UNK2RK32  619-1-S4  [R0402]  209.67 266.7 180 bottom
UNK2RK33  619-1-S4  [R0402]  202.43 268.22 270 bottom
UNK2RK34  619-1-S4  [R0402]  207 268.22 270 bottom
UNK2RK35  619-1-S4  [R0402]  211.58 268.22 270 bottom
UNK2RK36  619-1-S4  [R0402]  202.43 271.27 270 bottom
UNK2RK37  619-1-S4  [R0402]  207 271.27 270 bottom
UNK2RK38  619-1-S4  [R0402]  202.43 273.81 270 bottom
UNK2RK39  619-1-S4  [R0402]  207 273.81 270 bottom
UNK2RK40  619-1-S4  [R0402]  195.57 275.34 0 bottom
UNK2RK41  619-1-S4  [R0402]  195.57 279.91 0 bottom
UNK2RK42  619-1-S4  [R0402]  195.57 284.48 0 bottom
UNK2RK43  619-1-S4  [R0402]  192.65 275.34 0 bottom
UNK2RK44  619-1-S4  [R0402]  192.65 281.18 0 bottom
UNK2RK45  619-1-S4  [R0402]  192.65 285.75 0 bottom
UNK2RK46  619-1-S4  [R0402]  190.24 276.86 0 bottom
UNK2RK47  619-1-S4  [R0402]  190.24 282.7 0 bottom
UNK2RK48  619-1-S4  [R0402]  190.24 287.27 0 bottom
UNK2RK49  619-1-S4  [R0402]  187.83 287.27 0 bottom
UNK2RK50  619-1-S4  [R0402]  187.83 281.43 0 bottom
UNK2RK51  619-1-S4  [R0402]  188.72 248.79 0 bottom
UNK2RK52  619-1-S4  [R0402]  188.72 238.89 180 bottom
UNK2RK53  619-1-S4  [R0402]  196.97 248.79 0 bottom
UNK2RK54  619-1-S4  [R0402]  196.97 238.89 180 bottom
UNK2RK55  619-1-S4  [R0402]  198.11 236.86 180 bottom
UNK2RK56  619-1-S4  [R0402]  196.08 236.86 180 bottom
UNK2RK57  619-1-S4  [R0402]  193.03 236.86 180 bottom
UNK2RK58  619-1-S4  [R0402]  191 236.86 180 bottom
UNK2RK59  619-1-S4  [R0402]  161.16 292.35 90 bottom
UNK2RK60  619-1-S4  [R0402]  160.9 287.9 90 bottom
UNK2RK61  619-1-S4  [R0402]  167.76 292.35 90 bottom
UNK2SH1  SHORT  [DEFAULT_SHORT_SMALL]  298.63 -0.6 0 top
UNK2SH2  SHORT  [DEFAULT_SHORT_SMALL]  322.87 -0.6 0 top
UNK2SH3  SHORT  [DEFAULT_SHORT_SMALL]  342.7 -0.6 0 top
UNK2SH4  SHORT  [DEFAULT_SHORT_SMALL]  344.9 -0.6 0 top
UNK2SH5  SHORT  [DEFAULT_SHORT_SMALL]  347.1 -0.6 0 top
UNK2SH6  SHORT  [DEFAULT_SHORT_SMALL]  349.31 -0.6 0 top
UNK2SH7  SHORT  [DEFAULT_SHORT_SMALL]  351.51 -0.6 0 top
UNK2SH8  SHORT  [DEFAULT_SHORT_SMALL]  353.71 -0.6 0 top
UNK2SH9  SHORT  [DEFAULT_SHORT_SMALL]  355.92 -0.6 0 top
UNK2SH10  SHORT  [DEFAULT_SHORT_SMALL]  300.84 -0.6 0 top
UNK2SH11  SHORT  [DEFAULT_SHORT_SMALL]  303.04 -0.6 0 top
UNK2SH12  SHORT  [DEFAULT_SHORT_SMALL]  305.24 -0.6 0 top
UNK2SH13  SHORT  [DEFAULT_SHORT_SMALL]  307.45 -0.6 0 top
UNK2SH14  SHORT  [DEFAULT_SHORT_SMALL]  309.65 -0.6 0 top
UNK2SH15  SHORT  [DEFAULT_SHORT_SMALL]  311.85 -0.6 0 top
UNK2SH16  SHORT  [DEFAULT_SHORT_SMALL]  314.06 -0.6 0 top
UNK2SH17  SHORT  [DEFAULT_SHORT_SMALL]  316.26 -0.6 0 top
UNK2SH18  SHORT  [DEFAULT_SHORT_SMALL]  318.46 -0.6 0 top
UNK2SH19  SHORT  [DEFAULT_SHORT_SMALL]  320.67 -0.6 0 top
UNK2SH20  SHORT  [DEFAULT_SHORT_SMALL]  325.07 -0.6 0 top
UNK2SH21  SHORT  [DEFAULT_SHORT_SMALL]  327.28 -0.6 0 top
UNK2SH22  SHORT  [DEFAULT_SHORT_SMALL]  329.48 -0.6 0 top
UNK2SH23  SHORT  [DEFAULT_SHORT_SMALL]  331.68 -0.6 0 top
UNK2SH24  SHORT  [DEFAULT_SHORT_SMALL]  333.89 -0.6 0 top
UNK2SH25  SHORT  [DEFAULT_SHORT_SMALL]  336.09 -0.6 0 top
UNK2SH26  SHORT  [DEFAULT_SHORT_SMALL]  338.29 -0.6 0 top
UNK2SH27  SHORT  [DEFAULT_SHORT_SMALL]  340.5 -0.6 0 top
UNK2SHORT1  SHORT  [DEFAULT_SHORT_SMALL]  300.84 -1.79 0 top
UNK2SHORT2  SHORT  [DEFAULT_SHORT_SMALL]  307.45 -1.79 0 top
UNK2SHORT3  SHORT  [DEFAULT_SHORT_SMALL]  309.65 -1.79 0 top
UNK2SHORT4  SHORT  [DEFAULT_SHORT_SMALL]  311.85 -1.79 0 top
UNK2SHORT6  SHORT  [DEFAULT_SHORT_SMALL]  314.06 -1.79 0 top
UNK2SHORT7  SHORT  [DEFAULT_SHORT_SMALL]  316.26 -1.79 0 top
UNK2SHORT8  SHORT  [DEFAULT_SHORT_SMALL]  318.46 -1.79 0 top
UNK2SHORT9  SHORT  [DEFAULT_SHORT_SMALL]  320.67 -1.79 0 top
UNK2SHORT10  SHORT  [DEFAULT_SHORT_SMALL]  303.04 -1.79 0 top
UNK2SHORT11  SHORT  [DEFAULT_SHORT_SMALL]  305.24 -1.79 0 top
UNK2TP_ATT_F  TP01  [TP_040_T]  112.04 -7.23 0 top
UNK2TP_ATT_S  TP01  [TP_040_T]  220.37 -3.27 0 top
UNK2TP_C1A_F  TP01  [TP_040_T]  108.08 -7.23 0 top
UNK2TP_C1A_S  TP01  [TP_040_T]  106.1 -7.23 0 top
UNK2TP_C1B_F  TP01  [TP_040_T]  104.11 -7.23 0 top
UNK2TP_C1B_S  TP01  [TP_040_T]  102.13 -7.23 0 top
UNK2TP_C2A_F  TP01  [TP_040_T]  100.15 -7.23 0 top
UNK2TP_C2A_S  TP01  [TP_040_T]  98.17 -7.23 0 top
UNK2TP_C2B_F  TP01  [TP_040_T]  96.19 -7.23 0 top
UNK2TP_C2B_S  TP01  [TP_040_T]  94.21 -7.23 0 top
UNK2TP_C3A_F  TP01  [TP_040_T]  92.23 -7.23 0 top
UNK2TP_C3A_S  TP01  [TP_040_T]  90.25 -7.23 0 top
UNK2TP_C3B_F  TP01  [TP_040_T]  88.27 -7.23 0 top
UNK2TP_C3B_S  TP01  [TP_040_T]  86.28 -7.23 0 top
UNK2TP_GA1_S  TP01  [TP_040_T]  84.3 -7.23 0 top
UNK2TP_GA2_S  TP01  [TP_040_T]  82.32 -7.23 0 top
UNK2TP_GB1_S  TP01  [TP_040_T]  80.34 -7.23 0 top
UNK2TP_GB2_S  TP01  [TP_040_T]  321.41 -3.27 0 top
UNK2TP_IN+_1  TP01  [TP_040_T]  166.61 294.24 0 top
UNK2TP_IN+_2  TP01  [TP_040_T]  173.22 294.24 0 top
UNK2TP_IN+_3  TP01  [TP_040_T]  195.68 233.69 180 top
UNK2TP_IN+_4  TP01  [TP_040_T]  190.6 233.69 180 top
UNK2TP_IN-_1  TP01  [TP_040_T]  164.31 294.24 0 top
UNK2TP_IN-_2  TP01  [TP_040_T]  170.91 294.24 0 top
UNK2TP_IN-_3  TP01  [TP_040_T]  198.51 233.69 180 top
UNK2TP_IN-_4  TP01  [TP_040_T]  193.43 233.69 180 top
UNK2TP_IS1N_F  TP01  [TP_040_T]  127.26 -3.27 0 top
UNK2TP_IS1N_S  TP01  [TP_040_T]  129.24 -3.27 0 top
UNK2TP_IS1P_F  TP01  [TP_040_T]  131.22 -3.27 0 top
UNK2TP_IS2N_F  TP01  [TP_040_T]  133.2 -3.27 0 top
UNK2TP_IS2N_S  TP01  [TP_040_T]  135.18 -3.27 0 top
UNK2TP_IS2P_S  TP01  [TP_040_T]  137.16 -3.27 0 top
UNK2TP_OPTO_F  TP01  [TP_040_T]  139.14 -3.27 0 top
UNK2TP_OPTO_S  TP01  [TP_040_T]  141.12 -3.27 0 top
UNK2TP_OUT+_1  TP01  [TP_040_T]  166.61 296.31 0 top
UNK2TP_OUT+_2  TP01  [TP_040_T]  173.22 296.31 0 top
UNK2TP_OUT-_1  TP01  [TP_040_T]  164.31 296.31 0 top
UNK2TP_OUT-_2  TP01  [TP_040_T]  170.91 296.31 0 top
UNK2TP_OUT_1  TP01  [TP_040_T]  195.49 231.3 180 top
UNK2TP_OUT_2  TP01  [TP_040_T]  190.41 231.3 180 top
UNK2TP_REF_1  TP01  [TP_040_T]  143.11 -3.27 0 top
UNK2TP_REF_2  TP01  [TP_040_T]  191.06 228.7 180 top
UNK2TP_SCL_F  TP01  [TP_040_T]  145.09 -3.27 0 top
UNK2TP_SDA_F  TP01  [TP_040_T]  147.07 -3.27 0 top
UNK2TP_SDA_S  TP01  [TP_040_T]  149.05 -3.27 0 top
UNK2TP_SRD_F  TP01  [TP_040_T]  151.03 -3.27 0 top
UNK2TP_SRD_S  TP01  [TP_040_T]  153.01 -3.27 0 top
UNK2TP_SRG_F  TP01  [TP_040_T]  154.99 -3.27 0 top
UNK2TP_SRG_S  TP01  [TP_040_T]  156.97 -3.27 0 top
UNK2TP_SRS_F  TP01  [TP_040_T]  158.96 -3.27 0 top
UNK2TP_SRS_S  TP01  [TP_040_T]  160.94 -3.27 0 top
UNK2TP_STB_F  TP01  [TP_040_T]  162.92 -3.27 0 top
UNK2TP_STB_S  TP01  [TP_040_T]  164.9 -3.27 0 top
UNK2TP_VCC_F  TP01  [TP_040_T]  166.88 -3.27 0 top
UNK2TP_VCC_S  TP01  [TP_040_T]  168.86 -3.27 0 top
UNK2TP_VDD0_F  TP01  [TP_040_T]  170.84 -3.27 0 top
UNK2TP_VDD0_S  TP01  [TP_040_T]  174.8 -3.27 0 top
UNK2TP_VDD1_S  TP01  [TP_040_T]  172.82 -3.27 0 top
UNK2TP_VDD2_S  TP01  [TP_040_T]  176.79 -3.27 0 top
UNK2TP_VDDI_F  TP01  [TP_040_T]  178.77 -3.27 0 top
UNK2TP_VDDI_S  TP01  [TP_040_T]  180.75 -3.27 0 top
UNK2TP_VIN_F  TP01  [TP_040_T]  182.73 -3.27 0 top
UNK2TP_VIN_S  TP01  [TP_040_T]  184.71 -3.27 0 top
UNK2TP_VO1_S  TP01  [TP_040_T]  186.69 -3.27 0 top
UNK2TP_VO2_S  TP01  [TP_040_T]  188.67 -3.27 0 top
UNK2TP_VSR_F  TP01  [TP_040_T]  190.65 -3.27 0 top
UNK2TP_VSR_S  TP01  [TP_040_T]  192.64 -3.27 0 top
UNK2U1  TLV3604DCKR-SC70  [SC70]  165.61 294.89 270 bottom
UNK2U2  TLV3604DCKR-SC70  [SC70]  172.22 294.89 270 bottom
UNK2U3  INA186A3QDDFRQ1-SOT23-8  [SOT23_8P_0P65MM_H1P3MM]  196.46 230 180 bottom
UNK2U4  INA186A3QDDFRQ1-SOT23-8  [SOT23_8P_0P65MM_H1P3MM]  191.38 230 180 bottom
UNK3C48  0.01U-100-X7R-S6-MU  [C0603]  227.57 273.87 90 bottom
UNK3C49  0.01U-100-X7R-S6-MU  [C0603]  216.27 268.99 270 bottom
UNK3C50  0.01U-100-X7R-S6-MU  [C0603]  222.28 268.54 270 bottom
UNK3C53  1U-16-X5R-S4-YA  [C0402]  222.24 261.62 270 bottom
UNK3C54  2.2U-16-X-S4-MU  [C0402]  216.52 261.62 270 bottom
UNK3C58  1U-16-X5R-S4-YA  [C0402]  222.11 257.68 270 bottom
UNK3C59  4.7U-100-X-SB-MU  [C1210]  220.59 246.51 270 bottom
UNK3C60  0.01U-100-X7R-S6-MU  [C0603]  227.01 259.72 0 bottom
UNK3C61  0.01U-100-X7R-S6-MU  [C0603]  236.88 264.78 180 bottom
UNK3C62  2.2U-16-X-S4-MU  [C0402]  237.07 259.72 0 bottom
UNK3C63  0.01U-100-X7R-S6-MU  [C0603]  237.73 261.82 90 bottom
UNK3C64  0.01U-100-X7R-S6-MU  [C0603]  236.88 267.82 180 bottom
UNK3C65  0.1U-25-X7R-S4-MU  [C0402]  237.73 271.37 90 bottom
UNK3C66  0.1U-25-X7R-S4-MU  [C0402]  232.65 276.61 180 bottom
UNK3C67  0.1U-25-X7R-S4-MU  [C0402]  230.24 278.13 180 bottom
UNK3C68  0.1U-25-X7R-S4-MU  [C0402]  227.83 282.7 180 bottom
UNK3C69  0.01U-100-X7R-S6-MU  [C0603]  231.96 259.72 0 bottom
UNK3C70  0.1U-25-X7R-S4-MU  [C0402]  202.8 294.89 180 bottom
UNK3C71  0.1U-25-X7R-S4-MU  [C0402]  209.42 294.89 180 bottom
UNK3C72  0.1U-25-X7R-S4-MU  [C0402]  238.75 227.33 0 bottom
UNK3C73  0.1U-25-X7R-S4-MU  [C0402]  233.67 227.33 0 bottom
UNK3C74  0.1U-25-X7R-S4-MU  [C0402]  237.73 273.91 90 bottom
UNK3K1  UA2-5NJ-A-V3  [RL_NECUA2_5V_V3]  218.43 290.63 270 bottom
UNK3K2  G3VM-201DR  [RL_G3VM201DR_200V]  224.14 277.5 0 bottom
UNK3K3  G3VM-201DR  [RL_G3VM201DR_200V]  214.49 273.18 90 bottom
UNK3K4  G3VM-201DR  [RL_G3VM201DR_200V]  224.14 291.47 0 bottom
UNK3K5  G3VM-51UR-5V-VSON4  [RL_G3VM_4P_VSON4]  219.95 268.99 0 bottom
UNK3K6  G3VM-51UR-5V-VSON4  [RL_G3VM_4P_VSON4]  219.95 266.19 0 bottom
UNK3K7  G3VM-51UR-5V-VSON4  [RL_G3VM_4P_VSON4]  219.95 264.16 0 bottom
UNK3K8  G3VM-51UR-5V-VSON4  [RL_G3VM_4P_VSON4]  219.95 261.62 0 bottom
UNK3K9  G3VM-51UR-5V-VSON4  [RL_G3VM_4P_VSON4]  214.24 261.62 0 bottom
UNK3K10  G3VM-51UR-5V-VSON4  [RL_G3VM_4P_VSON4]  215.38 264.16 0 bottom
UNK3K11  G3VM-51UR-5V-VSON4  [RL_G3VM_4P_VSON4]  223.76 257.3 90 bottom
UNK3K12  G3VM-51UR-5V-VSON4  [RL_G3VM_4P_VSON4]  223.76 252.48 90 bottom
UNK3K13  G3VM-51UR-5V-VSON4  [RL_G3VM_4P_VSON4]  223.76 246.51 90 bottom
UNK3K14  G3VM-51UR-5V-VSON4  [RL_G3VM_4P_VSON4]  226.56 252.48 90 bottom
UNK3K15  UA2-5NJ-A-V3  [RL_NECUA2_5V_V3]  215.25 242.75 270 bottom
UNK3K16  G3VM-51UR-5V-VSON4  [RL_G3VM_4P_VSON4]  226.56 257.3 90 bottom
UNK3K17  G3VM-51UR-5V-VSON4  [RL_G3VM_4P_VSON4]  228.72 257.3 90 bottom
UNK3K18  G3VM-51UR-5V-VSON4  [RL_G3VM_4P_VSON4]  228.72 252.48 90 bottom
UNK3K19  G3VM-51UR-5V-VSON4  [RL_G3VM_4P_VSON4]  231.51 257.3 90 bottom
UNK3K20  G3VM-51UR-5V-VSON4  [RL_G3VM_4P_VSON4]  231.51 252.48 90 bottom
UNK3K21  G3VM-51UR-5V-VSON4  [RL_G3VM_4P_VSON4]  233.67 257.3 90 bottom
UNK3K22  G3VM-51UR-5V-VSON4  [RL_G3VM_4P_VSON4]  233.67 252.48 90 bottom
UNK3K23  UA2-5NJ-A-V3  [RL_NECUA2_5V_V3]  232.78 242.75 270 bottom
UNK3K24  UA2-5NJ-A-V3  [RL_NECUA2_5V_V3]  241.04 242.75 270 bottom
UNK3K25  G3VM-51UR-5V-VSON4  [RL_G3VM_4P_VSON4]  236.97 257.3 90 bottom
UNK3K26  G3VM-51UR-5V-VSON4  [RL_G3VM_4P_VSON4]  236.97 252.48 90 bottom
UNK3K27  G3VM-51UR-5V-VSON4  [RL_G3VM_4P_VSON4]  240.15 261.37 180 bottom
UNK3K28  G3VM-51UR-5V-VSON4  [RL_G3VM_4P_VSON4]  244.72 261.37 180 bottom
UNK3K29  G3VM-51UR-5V-VSON4  [RL_G3VM_4P_VSON4]  249.29 261.37 180 bottom
UNK3K30  G3VM-51UR-5V-VSON4  [RL_G3VM_4P_VSON4]  240.15 265.18 180 bottom
UNK3K31  G3VM-51UR-5V-VSON4  [RL_G3VM_4P_VSON4]  244.72 265.18 180 bottom
UNK3K32  G3VM-51UR-5V-VSON4  [RL_G3VM_4P_VSON4]  249.29 265.18 180 bottom
UNK3K33  G3VM-51UR-5V-VSON4  [RL_G3VM_4P_VSON4]  240.15 268.22 180 bottom
UNK3K34  G3VM-51UR-5V-VSON4  [RL_G3VM_4P_VSON4]  244.72 268.22 180 bottom
UNK3K35  G3VM-51UR-5V-VSON4  [RL_G3VM_4P_VSON4]  249.29 268.22 180 bottom
UNK3K36  G3VM-51UR-5V-VSON4  [RL_G3VM_4P_VSON4]  240.15 271.27 180 bottom
UNK3K37  G3VM-51UR-5V-VSON4  [RL_G3VM_4P_VSON4]  244.72 271.27 180 bottom
UNK3K38  G3VM-51UR-5V-VSON4  [RL_G3VM_4P_VSON4]  240.15 273.81 180 bottom
UNK3K39  G3VM-51UR-5V-VSON4  [RL_G3VM_4P_VSON4]  244.72 273.81 180 bottom
UNK3K40  G3VM-51UR-5V-VSON4  [RL_G3VM_4P_VSON4]  235.57 273.05 270 bottom
UNK3K41  G3VM-51UR-5V-VSON4  [RL_G3VM_4P_VSON4]  235.57 277.62 270 bottom
UNK3K42  G3VM-51UR-5V-VSON4  [RL_G3VM_4P_VSON4]  235.57 282.19 270 bottom
UNK3K43  G3VM-51UR-5V-VSON4  [RL_G3VM_4P_VSON4]  232.65 273.05 270 bottom
UNK3K44  G3VM-51UR-5V-VSON4  [RL_G3VM_4P_VSON4]  232.65 278.89 270 bottom
UNK3K45  G3VM-51UR-5V-VSON4  [RL_G3VM_4P_VSON4]  232.65 283.46 270 bottom
UNK3K46  G3VM-51UR-5V-VSON4  [RL_G3VM_4P_VSON4]  230.24 274.57 270 bottom
UNK3K47  G3VM-51UR-5V-VSON4  [RL_G3VM_4P_VSON4]  230.24 280.42 270 bottom
UNK3K48  G3VM-51UR-5V-VSON4  [RL_G3VM_4P_VSON4]  230.24 284.99 270 bottom
UNK3K49  G3VM-51UR-5V-VSON4  [RL_G3VM_4P_VSON4]  227.83 284.99 270 bottom
UNK3K50  G3VM-51UR-5V-VSON4  [RL_G3VM_4P_VSON4]  227.83 279.15 270 bottom
UNK3K51  G3VM-51UR-5V-VSON4  [RL_G3VM_4P_VSON4]  228.72 246.51 270 bottom
UNK3K52  G3VM-51UR-5V-VSON4  [RL_G3VM_4P_VSON4]  228.72 241.17 90 bottom
UNK3K53  G3VM-51UR-5V-VSON4  [RL_G3VM_4P_VSON4]  236.97 246.51 270 bottom
UNK3K54  G3VM-51UR-5V-VSON4  [RL_G3VM_4P_VSON4]  236.97 241.17 90 bottom
UNK3K55  G3VM-51UR-5V-VSON4  [RL_G3VM_4P_VSON4]  203.44 292.35 0 bottom
UNK3K56  G3VM-201DR  [RL_G3VM201DR_200V]  208.4 288.67 90 bottom
UNK3K57  G3VM-51UR-5V-VSON4  [RL_G3VM_4P_VSON4]  238.11 234.57 270 bottom
UNK3K58  G3VM-51UR-5V-VSON4  [RL_G3VM_4P_VSON4]  236.08 234.57 270 bottom
UNK3K59  G3VM-51UR-5V-VSON4  [RL_G3VM_4P_VSON4]  233.03 234.57 270 bottom
UNK3K60  G3VM-51UR-5V-VSON4  [RL_G3VM_4P_VSON4]  231 234.57 270 bottom
UNK3K61  G3VM-51UR-5V-VSON4  [RL_G3VM_4P_VSON4]  210.05 292.35 0 bottom
UNK3R1  10K-0.1-S4  [R0402]  223.76 248.79 0 bottom
UNK3R7  4.7K-1-S4-WA  [R0402]  228.21 243.84 90 bottom
UNK3R8  4.7K-1-S4-WA  [R0402]  236.46 243.84 90 bottom
UNK3R11  5K-1-S4-YA  [R0402]  206.11 293.12 0 bottom
UNK3R14  5K-1-S4-YA  [R0402]  212.71 293.12 0 bottom
UNK3R15  0-0-S2-KOA  [R0201]  237.14 227.33 0 bottom
UNK3R16  5.1-1-S2  [R0201]  237.11 232.54 180 bottom
UNK3R17  0-0-S2-KOA  [R0201]  232.06 227.33 0 bottom
UNK3R18  5.1-1-S2  [R0201]  232.03 232.54 180 bottom
UNK3R19  100K-0.1-S4-YA  [R0402]  206.11 291.95 180 bottom
UNK3R20  100K-0.1-S4-YA  [R0402]  212.71 291.95 180 bottom
UNK3R41  0-5-S6  [R0603]  131.44 -33.82 270 top
UNK3R42  0-5-S6  [R0603]  128.23 -33.82 270 top
UNK3RK2  619-1-S4  [R0402]  220.97 284.23 90 bottom
UNK3RK3  619-1-S4  [R0402]  210.52 269.99 0 bottom
UNK3RK4  619-1-S4  [R0402]  220.97 297.43 90 bottom
UNK3RK5  619-1-S4  [R0402]  217.67 268.99 90 bottom
UNK3RK6  619-1-S4  [R0402]  217.67 266.19 90 bottom
UNK3RK7  619-1-S4  [R0402]  217.67 264.16 90 bottom
UNK3RK8  619-1-S4  [R0402]  217.67 261.62 90 bottom
UNK3RK9  619-1-S4  [R0402]  211.95 261.62 90 bottom
UNK3RK10  619-1-S4  [R0402]  213.1 264.16 90 bottom
UNK3RK11  619-1-S4  [R0402]  223.76 255.02 180 bottom
UNK3RK12  619-1-S4  [R0402]  223.76 250.19 180 bottom
UNK3RK13  619-1-S4  [R0402]  223.76 244.22 180 bottom
UNK3RK14  619-1-S4  [R0402]  226.56 250.19 180 bottom
UNK3RK16  619-1-S4  [R0402]  226.56 255.02 180 bottom
UNK3RK17  619-1-S4  [R0402]  228.72 255.02 180 bottom
UNK3RK18  619-1-S4  [R0402]  228.72 250.19 180 bottom
UNK3RK19  619-1-S4  [R0402]  231.51 255.02 180 bottom
UNK3RK20  619-1-S4  [R0402]  231.51 250.19 180 bottom
UNK3RK21  619-1-S4  [R0402]  233.67 255.02 180 bottom
UNK3RK22  619-1-S4  [R0402]  233.67 250.19 180 bottom
UNK3RK25  619-1-S4  [R0402]  236.97 255.02 180 bottom
UNK3RK26  619-1-S4  [R0402]  236.97 250.19 180 bottom
UNK3RK27  619-1-S4  [R0402]  242.43 261.37 270 bottom
UNK3RK28  619-1-S4  [R0402]  247 261.37 270 bottom
UNK3RK29  619-1-S4  [R0402]  249.67 262.89 180 bottom
UNK3RK30  619-1-S4  [R0402]  242.43 265.18 270 bottom
UNK3RK31  619-1-S4  [R0402]  247 265.18 270 bottom
UNK3RK32  619-1-S4  [R0402]  249.67 266.7 180 bottom
UNK3RK33  619-1-S4  [R0402]  242.43 268.22 270 bottom
UNK3RK34  619-1-S4  [R0402]  247 268.22 270 bottom
UNK3RK35  619-1-S4  [R0402]  251.58 268.22 270 bottom
UNK3RK36  619-1-S4  [R0402]  242.43 271.27 270 bottom
UNK3RK37  619-1-S4  [R0402]  247 271.27 270 bottom
UNK3RK38  619-1-S4  [R0402]  242.43 273.81 270 bottom
UNK3RK39  619-1-S4  [R0402]  247 273.81 270 bottom
UNK3RK40  619-1-S4  [R0402]  235.57 275.34 0 bottom
UNK3RK41  619-1-S4  [R0402]  235.57 279.91 0 bottom
UNK3RK42  619-1-S4  [R0402]  235.57 284.48 0 bottom
UNK3RK43  619-1-S4  [R0402]  232.65 275.34 0 bottom
UNK3RK44  619-1-S4  [R0402]  232.65 281.18 0 bottom
UNK3RK45  619-1-S4  [R0402]  232.65 285.75 0 bottom
UNK3RK46  619-1-S4  [R0402]  230.24 276.86 0 bottom
UNK3RK47  619-1-S4  [R0402]  230.24 282.7 0 bottom
UNK3RK48  619-1-S4  [R0402]  230.24 287.27 0 bottom
UNK3RK49  619-1-S4  [R0402]  227.83 287.27 0 bottom
UNK3RK50  619-1-S4  [R0402]  227.83 281.43 0 bottom
UNK3RK51  619-1-S4  [R0402]  228.72 248.79 0 bottom
UNK3RK52  619-1-S4  [R0402]  228.72 238.89 180 bottom
UNK3RK53  619-1-S4  [R0402]  236.97 248.79 0 bottom
UNK3RK54  619-1-S4  [R0402]  236.97 238.89 180 bottom
UNK3RK55  619-1-S4  [R0402]  238.11 236.86 180 bottom
UNK3RK56  619-1-S4  [R0402]  236.08 236.86 180 bottom
UNK3RK57  619-1-S4  [R0402]  233.03 236.86 180 bottom
UNK3RK58  619-1-S4  [R0402]  231 236.86 180 bottom
UNK3RK59  619-1-S4  [R0402]  201.16 292.35 90 bottom
UNK3RK60  619-1-S4  [R0402]  200.9 287.9 90 bottom
UNK3RK61  619-1-S4  [R0402]  207.76 292.35 90 bottom
UNK3SH1  SHORT  [DEFAULT_SHORT_SMALL]  358.12 -0.6 0 top
UNK3SH2  SHORT  [DEFAULT_SHORT_SMALL]  382.36 -0.6 0 top
UNK3SH3  SHORT  [DEFAULT_SHORT_SMALL]  402.18 -0.6 0 top
UNK3SH4  SHORT  [DEFAULT_SHORT_SMALL]  404.39 -0.6 0 top
UNK3SH5  SHORT  [DEFAULT_SHORT_SMALL]  406.59 -0.6 0 top
UNK3SH6  SHORT  [DEFAULT_SHORT_SMALL]  408.79 -0.6 0 top
UNK3SH7  SHORT  [DEFAULT_SHORT_SMALL]  411 -0.6 0 top
UNK3SH8  SHORT  [DEFAULT_SHORT_SMALL]  413.2 -0.6 0 top
UNK3SH9  SHORT  [DEFAULT_SHORT_SMALL]  415.4 -0.6 0 top
UNK3SH10  SHORT  [DEFAULT_SHORT_SMALL]  360.32 -0.6 0 top
UNK3SH11  SHORT  [DEFAULT_SHORT_SMALL]  362.53 -0.6 0 top
UNK3SH12  SHORT  [DEFAULT_SHORT_SMALL]  364.73 -0.6 0 top
UNK3SH13  SHORT  [DEFAULT_SHORT_SMALL]  366.93 -0.6 0 top
UNK3SH14  SHORT  [DEFAULT_SHORT_SMALL]  369.14 -0.6 0 top
UNK3SH15  SHORT  [DEFAULT_SHORT_SMALL]  371.34 -0.6 0 top
UNK3SH16  SHORT  [DEFAULT_SHORT_SMALL]  373.54 -0.6 0 top
UNK3SH17  SHORT  [DEFAULT_SHORT_SMALL]  375.75 -0.6 0 top
UNK3SH18  SHORT  [DEFAULT_SHORT_SMALL]  377.95 -0.6 0 top
UNK3SH19  SHORT  [DEFAULT_SHORT_SMALL]  380.15 -0.6 0 top
UNK3SH20  SHORT  [DEFAULT_SHORT_SMALL]  384.56 -0.6 0 top
UNK3SH21  SHORT  [DEFAULT_SHORT_SMALL]  386.76 -0.6 0 top
UNK3SH22  SHORT  [DEFAULT_SHORT_SMALL]  388.97 -0.6 0 top
UNK3SH23  SHORT  [DEFAULT_SHORT_SMALL]  391.17 -0.6 0 top
UNK3SH24  SHORT  [DEFAULT_SHORT_SMALL]  393.37 -0.6 0 top
UNK3SH25  SHORT  [DEFAULT_SHORT_SMALL]  395.58 -0.6 0 top
UNK3SH26  SHORT  [DEFAULT_SHORT_SMALL]  397.78 -0.6 0 top
UNK3SH27  SHORT  [DEFAULT_SHORT_SMALL]  399.98 -0.6 0 top
UNK3SHORT1  SHORT  [DEFAULT_SHORT_SMALL]  322.87 -1.79 0 top
UNK3SHORT2  SHORT  [DEFAULT_SHORT_SMALL]  329.48 -1.79 0 top
UNK3SHORT3  SHORT  [DEFAULT_SHORT_SMALL]  331.68 -1.79 0 top
UNK3SHORT4  SHORT  [DEFAULT_SHORT_SMALL]  333.89 -1.79 0 top
UNK3SHORT6  SHORT  [DEFAULT_SHORT_SMALL]  336.09 -1.79 0 top
UNK3SHORT7  SHORT  [DEFAULT_SHORT_SMALL]  338.29 -1.79 0 top
UNK3SHORT8  SHORT  [DEFAULT_SHORT_SMALL]  340.5 -1.79 0 top
UNK3SHORT9  SHORT  [DEFAULT_SHORT_SMALL]  342.7 -1.79 0 top
UNK3SHORT10  SHORT  [DEFAULT_SHORT_SMALL]  325.07 -1.79 0 top
UNK3SHORT11  SHORT  [DEFAULT_SHORT_SMALL]  327.28 -1.79 0 top
UNK3TP_ATT_F  TP01  [TP_040_T]  194.62 -3.27 0 top
UNK3TP_ATT_S  TP01  [TP_040_T]  196.6 -3.27 0 top
UNK3TP_C1A_F  TP01  [TP_040_T]  198.58 -3.27 0 top
UNK3TP_C1A_S  TP01  [TP_040_T]  200.56 -3.27 0 top
UNK3TP_C1B_F  TP01  [TP_040_T]  202.54 -3.27 0 top
UNK3TP_C1B_S  TP01  [TP_040_T]  204.52 -3.27 0 top
UNK3TP_C2A_F  TP01  [TP_040_T]  206.5 -3.27 0 top
UNK3TP_C2A_S  TP01  [TP_040_T]  208.49 -3.27 0 top
UNK3TP_C2B_F  TP01  [TP_040_T]  210.47 -3.27 0 top
UNK3TP_C2B_S  TP01  [TP_040_T]  212.45 -3.27 0 top
UNK3TP_C3A_F  TP01  [TP_040_T]  214.43 -3.27 0 top
UNK3TP_C3A_S  TP01  [TP_040_T]  216.41 -3.27 0 top
UNK3TP_C3B_F  TP01  [TP_040_T]  218.39 -3.27 0 top
UNK3TP_C3B_S  TP01  [TP_040_T]  114.02 -7.23 0 top
UNK3TP_GA1_S  TP01  [TP_040_T]  224.33 -3.27 0 top
UNK3TP_GA2_S  TP01  [TP_040_T]  222.35 -3.27 0 top
UNK3TP_GB1_S  TP01  [TP_040_T]  226.32 -3.27 0 top
UNK3TP_GB2_S  TP01  [TP_040_T]  228.3 -3.27 0 top
UNK3TP_IN+_1  TP01  [TP_040_T]  206.61 294.24 0 top
UNK3TP_IN+_2  TP01  [TP_040_T]  213.21 294.24 0 top
UNK3TP_IN+_3  TP01  [TP_040_T]  235.68 233.69 180 top
UNK3TP_IN+_4  TP01  [TP_040_T]  230.6 233.69 180 top
UNK3TP_IN-_1  TP01  [TP_040_T]  204.31 294.24 0 top
UNK3TP_IN-_2  TP01  [TP_040_T]  210.91 294.24 0 top
UNK3TP_IN-_3  TP01  [TP_040_T]  238.51 233.69 180 top
UNK3TP_IN-_4  TP01  [TP_040_T]  233.43 233.69 180 top
UNK3TP_IS1N_F  TP01  [TP_040_T]  230.28 -3.27 0 top
UNK3TP_IS1N_S  TP01  [TP_040_T]  232.26 -3.27 0 top
UNK3TP_IS1P_F  TP01  [TP_040_T]  234.24 -3.27 0 top
UNK3TP_IS2N_F  TP01  [TP_040_T]  236.22 -3.27 0 top
UNK3TP_IS2N_S  TP01  [TP_040_T]  238.2 -3.27 0 top
UNK3TP_IS2P_S  TP01  [TP_040_T]  240.18 -3.27 0 top
UNK3TP_OPTO_F  TP01  [TP_040_T]  242.17 -3.27 0 top
UNK3TP_OPTO_S  TP01  [TP_040_T]  244.15 -3.27 0 top
UNK3TP_OUT+_1  TP01  [TP_040_T]  206.61 296.31 0 top
UNK3TP_OUT+_2  TP01  [TP_040_T]  213.21 296.31 0 top
UNK3TP_OUT-_1  TP01  [TP_040_T]  204.31 296.31 0 top
UNK3TP_OUT-_2  TP01  [TP_040_T]  210.91 296.31 0 top
UNK3TP_OUT_1  TP01  [TP_040_T]  235.49 231.3 180 top
UNK3TP_OUT_2  TP01  [TP_040_T]  230.41 231.3 180 top
UNK3TP_REF_1  TP01  [TP_040_T]  246.13 -3.27 0 top
UNK3TP_REF_2  TP01  [TP_040_T]  231.06 228.7 180 top
UNK3TP_SCL_F  TP01  [TP_040_T]  248.11 -3.27 0 top
UNK3TP_SDA_F  TP01  [TP_040_T]  250.09 -3.27 0 top
UNK3TP_SDA_S  TP01  [TP_040_T]  252.07 -3.27 0 top
UNK3TP_SRD_F  TP01  [TP_040_T]  254.05 -3.27 0 top
UNK3TP_SRD_S  TP01  [TP_040_T]  256.03 -3.27 0 top
UNK3TP_SRG_F  TP01  [TP_040_T]  258.02 -3.27 0 top
UNK3TP_SRG_S  TP01  [TP_040_T]  260 -3.27 0 top
UNK3TP_SRS_F  TP01  [TP_040_T]  261.98 -3.27 0 top
UNK3TP_SRS_S  TP01  [TP_040_T]  263.96 -3.27 0 top
UNK3TP_STB_F  TP01  [TP_040_T]  265.94 -3.27 0 top
UNK3TP_STB_S  TP01  [TP_040_T]  267.92 -3.27 0 top
UNK3TP_VCC_F  TP01  [TP_040_T]  269.9 -3.27 0 top
UNK3TP_VCC_S  TP01  [TP_040_T]  271.88 -3.27 0 top
UNK3TP_VDD0_F  TP01  [TP_040_T]  273.86 -3.27 0 top
UNK3TP_VDD0_S  TP01  [TP_040_T]  275.85 -3.27 0 top
UNK3TP_VDD1_S  TP01  [TP_040_T]  277.83 -3.27 0 top
UNK3TP_VDD2_S  TP01  [TP_040_T]  279.81 -3.27 0 top
UNK3TP_VDDI_F  TP01  [TP_040_T]  281.79 -3.27 0 top
UNK3TP_VDDI_S  TP01  [TP_040_T]  283.77 -3.27 0 top
UNK3TP_VIN_F  TP01  [TP_040_T]  285.75 -3.27 0 top
UNK3TP_VIN_S  TP01  [TP_040_T]  287.73 -3.27 0 top
UNK3TP_VO1_S  TP01  [TP_040_T]  289.71 -3.27 0 top
UNK3TP_VO2_S  TP01  [TP_040_T]  291.7 -3.27 0 top
UNK3TP_VSR_F  TP01  [TP_040_T]  293.68 -3.27 0 top
UNK3TP_VSR_S  TP01  [TP_040_T]  295.66 -3.27 0 top
UNK3U1  TLV3604DCKR-SC70  [SC70]  205.61 294.89 270 bottom
UNK3U2  TLV3604DCKR-SC70  [SC70]  212.21 294.89 270 bottom
UNK3U3  INA186A3QDDFRQ1-SOT23-8  [SOT23_8P_0P65MM_H1P3MM]  236.46 230 180 bottom
UNK3U4  INA186A3QDDFRQ1-SOT23-8  [SOT23_8P_0P65MM_H1P3MM]  231.38 230 180 bottom
UNK4C48  0.01U-100-X7R-S6-MU  [C0603]  267.57 273.87 90 bottom
UNK4C49  0.01U-100-X7R-S6-MU  [C0603]  256.27 268.99 270 bottom
UNK4C50  0.01U-100-X7R-S6-MU  [C0603]  262.28 268.54 270 bottom
UNK4C53  1U-16-X5R-S4-YA  [C0402]  262.24 261.62 270 bottom
UNK4C54  2.2U-16-X-S4-MU  [C0402]  256.52 261.62 270 bottom
UNK4C58  1U-16-X5R-S4-YA  [C0402]  262.11 257.68 270 bottom
UNK4C59  4.7U-100-X-SB-MU  [C1210]  260.59 246.51 270 bottom
UNK4C60  0.01U-100-X7R-S6-MU  [C0603]  267.01 259.72 0 bottom
UNK4C61  0.01U-100-X7R-S6-MU  [C0603]  276.88 264.78 180 bottom
UNK4C62  2.2U-16-X-S4-MU  [C0402]  277.07 259.72 0 bottom
UNK4C63  0.01U-100-X7R-S6-MU  [C0603]  277.73 261.82 90 bottom
UNK4C64  0.01U-100-X7R-S6-MU  [C0603]  276.88 267.82 180 bottom
UNK4C65  0.1U-25-X7R-S4-MU  [C0402]  277.73 271.37 90 bottom
UNK4C66  0.1U-25-X7R-S4-MU  [C0402]  272.65 276.61 180 bottom
UNK4C67  0.1U-25-X7R-S4-MU  [C0402]  270.24 278.13 180 bottom
UNK4C68  0.1U-25-X7R-S4-MU  [C0402]  267.83 282.7 180 bottom
UNK4C69  0.01U-100-X7R-S6-MU  [C0603]  271.96 259.72 0 bottom
UNK4C70  0.1U-25-X7R-S4-MU  [C0402]  242.8 294.89 180 bottom
UNK4C71  0.1U-25-X7R-S4-MU  [C0402]  249.42 294.89 180 bottom
UNK4C72  0.1U-25-X7R-S4-MU  [C0402]  278.75 227.33 0 bottom
UNK4C73  0.1U-25-X7R-S4-MU  [C0402]  273.67 227.33 0 bottom
UNK4C74  0.1U-25-X7R-S4-MU  [C0402]  277.73 273.91 90 bottom
UNK4K1  UA2-5NJ-A-V3  [RL_NECUA2_5V_V3]  258.43 290.63 270 bottom
UNK4K2  G3VM-201DR  [RL_G3VM201DR_200V]  264.14 277.5 0 bottom
UNK4K3  G3VM-201DR  [RL_G3VM201DR_200V]  254.49 273.18 90 bottom
UNK4K4  G3VM-201DR  [RL_G3VM201DR_200V]  264.14 291.47 0 bottom
UNK4K5  G3VM-51UR-5V-VSON4  [RL_G3VM_4P_VSON4]  259.95 268.99 0 bottom
UNK4K6  G3VM-51UR-5V-VSON4  [RL_G3VM_4P_VSON4]  259.95 266.19 0 bottom
UNK4K7  G3VM-51UR-5V-VSON4  [RL_G3VM_4P_VSON4]  259.95 264.16 0 bottom
UNK4K8  G3VM-51UR-5V-VSON4  [RL_G3VM_4P_VSON4]  259.95 261.62 0 bottom
UNK4K9  G3VM-51UR-5V-VSON4  [RL_G3VM_4P_VSON4]  254.24 261.62 0 bottom
UNK4K10  G3VM-51UR-5V-VSON4  [RL_G3VM_4P_VSON4]  255.38 264.16 0 bottom
UNK4K11  G3VM-51UR-5V-VSON4  [RL_G3VM_4P_VSON4]  263.76 257.3 90 bottom
UNK4K12  G3VM-51UR-5V-VSON4  [RL_G3VM_4P_VSON4]  263.76 252.48 90 bottom
UNK4K13  G3VM-51UR-5V-VSON4  [RL_G3VM_4P_VSON4]  263.76 246.51 90 bottom
UNK4K14  G3VM-51UR-5V-VSON4  [RL_G3VM_4P_VSON4]  266.56 252.48 90 bottom
UNK4K15  UA2-5NJ-A-V3  [RL_NECUA2_5V_V3]  255.25 242.75 270 bottom
UNK4K16  G3VM-51UR-5V-VSON4  [RL_G3VM_4P_VSON4]  266.56 257.3 90 bottom
UNK4K17  G3VM-51UR-5V-VSON4  [RL_G3VM_4P_VSON4]  268.72 257.3 90 bottom
UNK4K18  G3VM-51UR-5V-VSON4  [RL_G3VM_4P_VSON4]  268.72 252.48 90 bottom
UNK4K19  G3VM-51UR-5V-VSON4  [RL_G3VM_4P_VSON4]  271.51 257.3 90 bottom
UNK4K20  G3VM-51UR-5V-VSON4  [RL_G3VM_4P_VSON4]  271.51 252.48 90 bottom
UNK4K21  G3VM-51UR-5V-VSON4  [RL_G3VM_4P_VSON4]  273.67 257.3 90 bottom
UNK4K22  G3VM-51UR-5V-VSON4  [RL_G3VM_4P_VSON4]  273.67 252.48 90 bottom
UNK4K23  UA2-5NJ-A-V3  [RL_NECUA2_5V_V3]  272.78 242.75 270 bottom
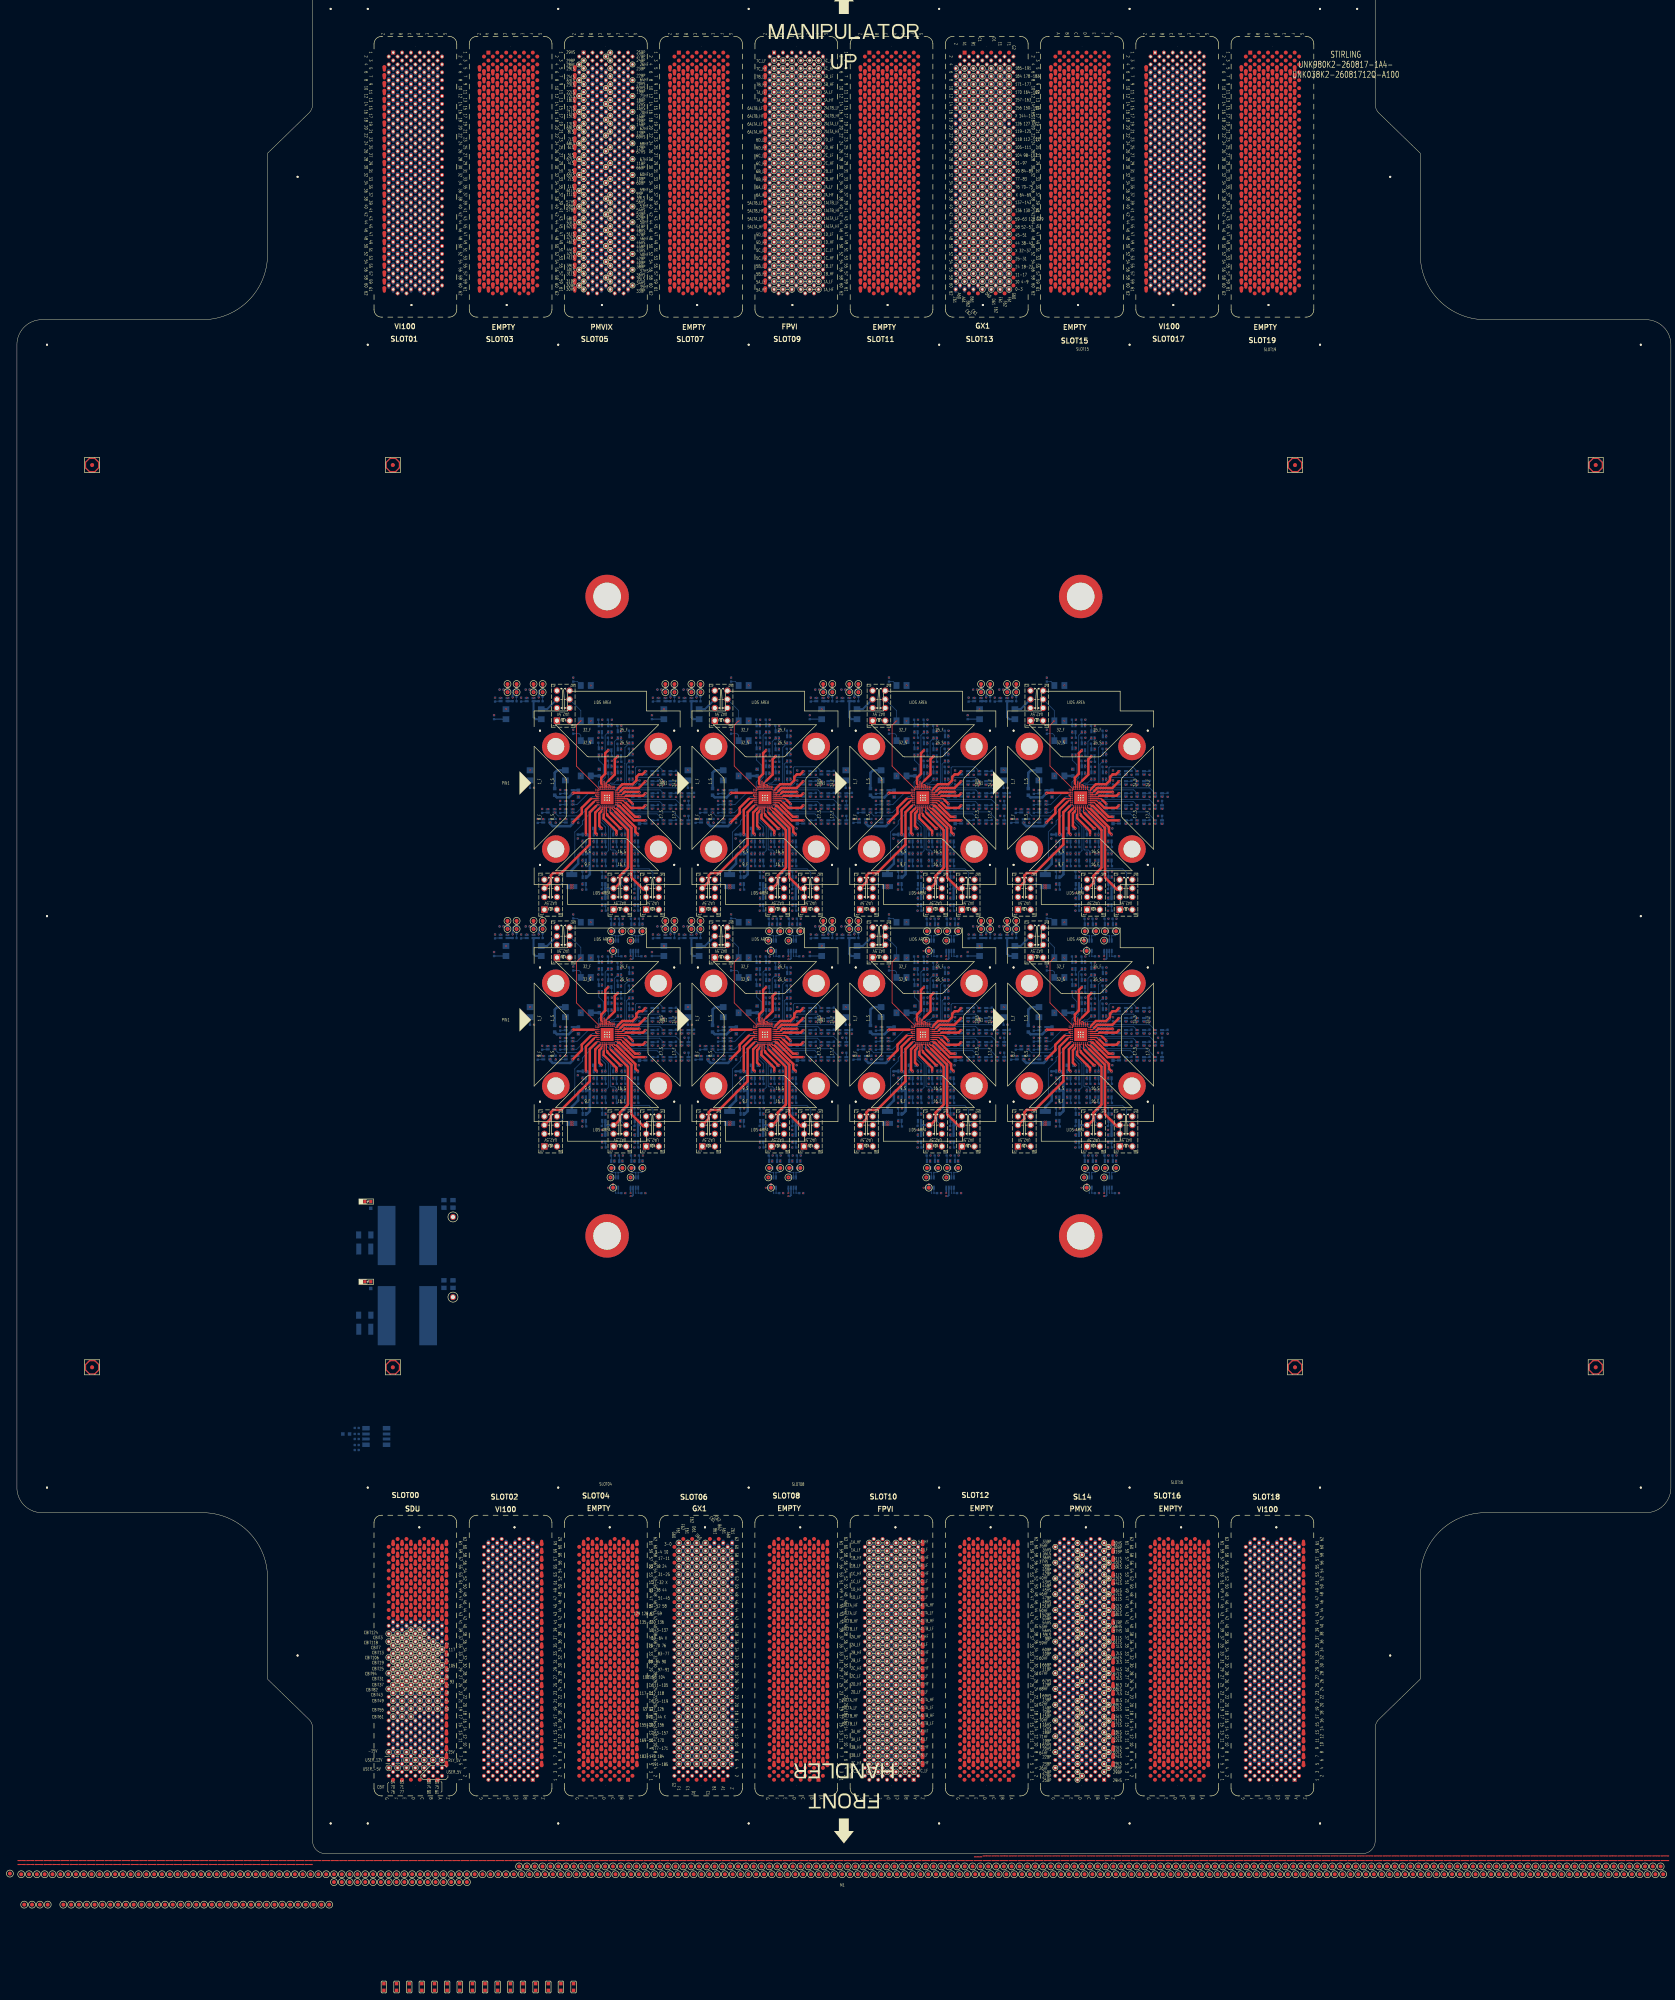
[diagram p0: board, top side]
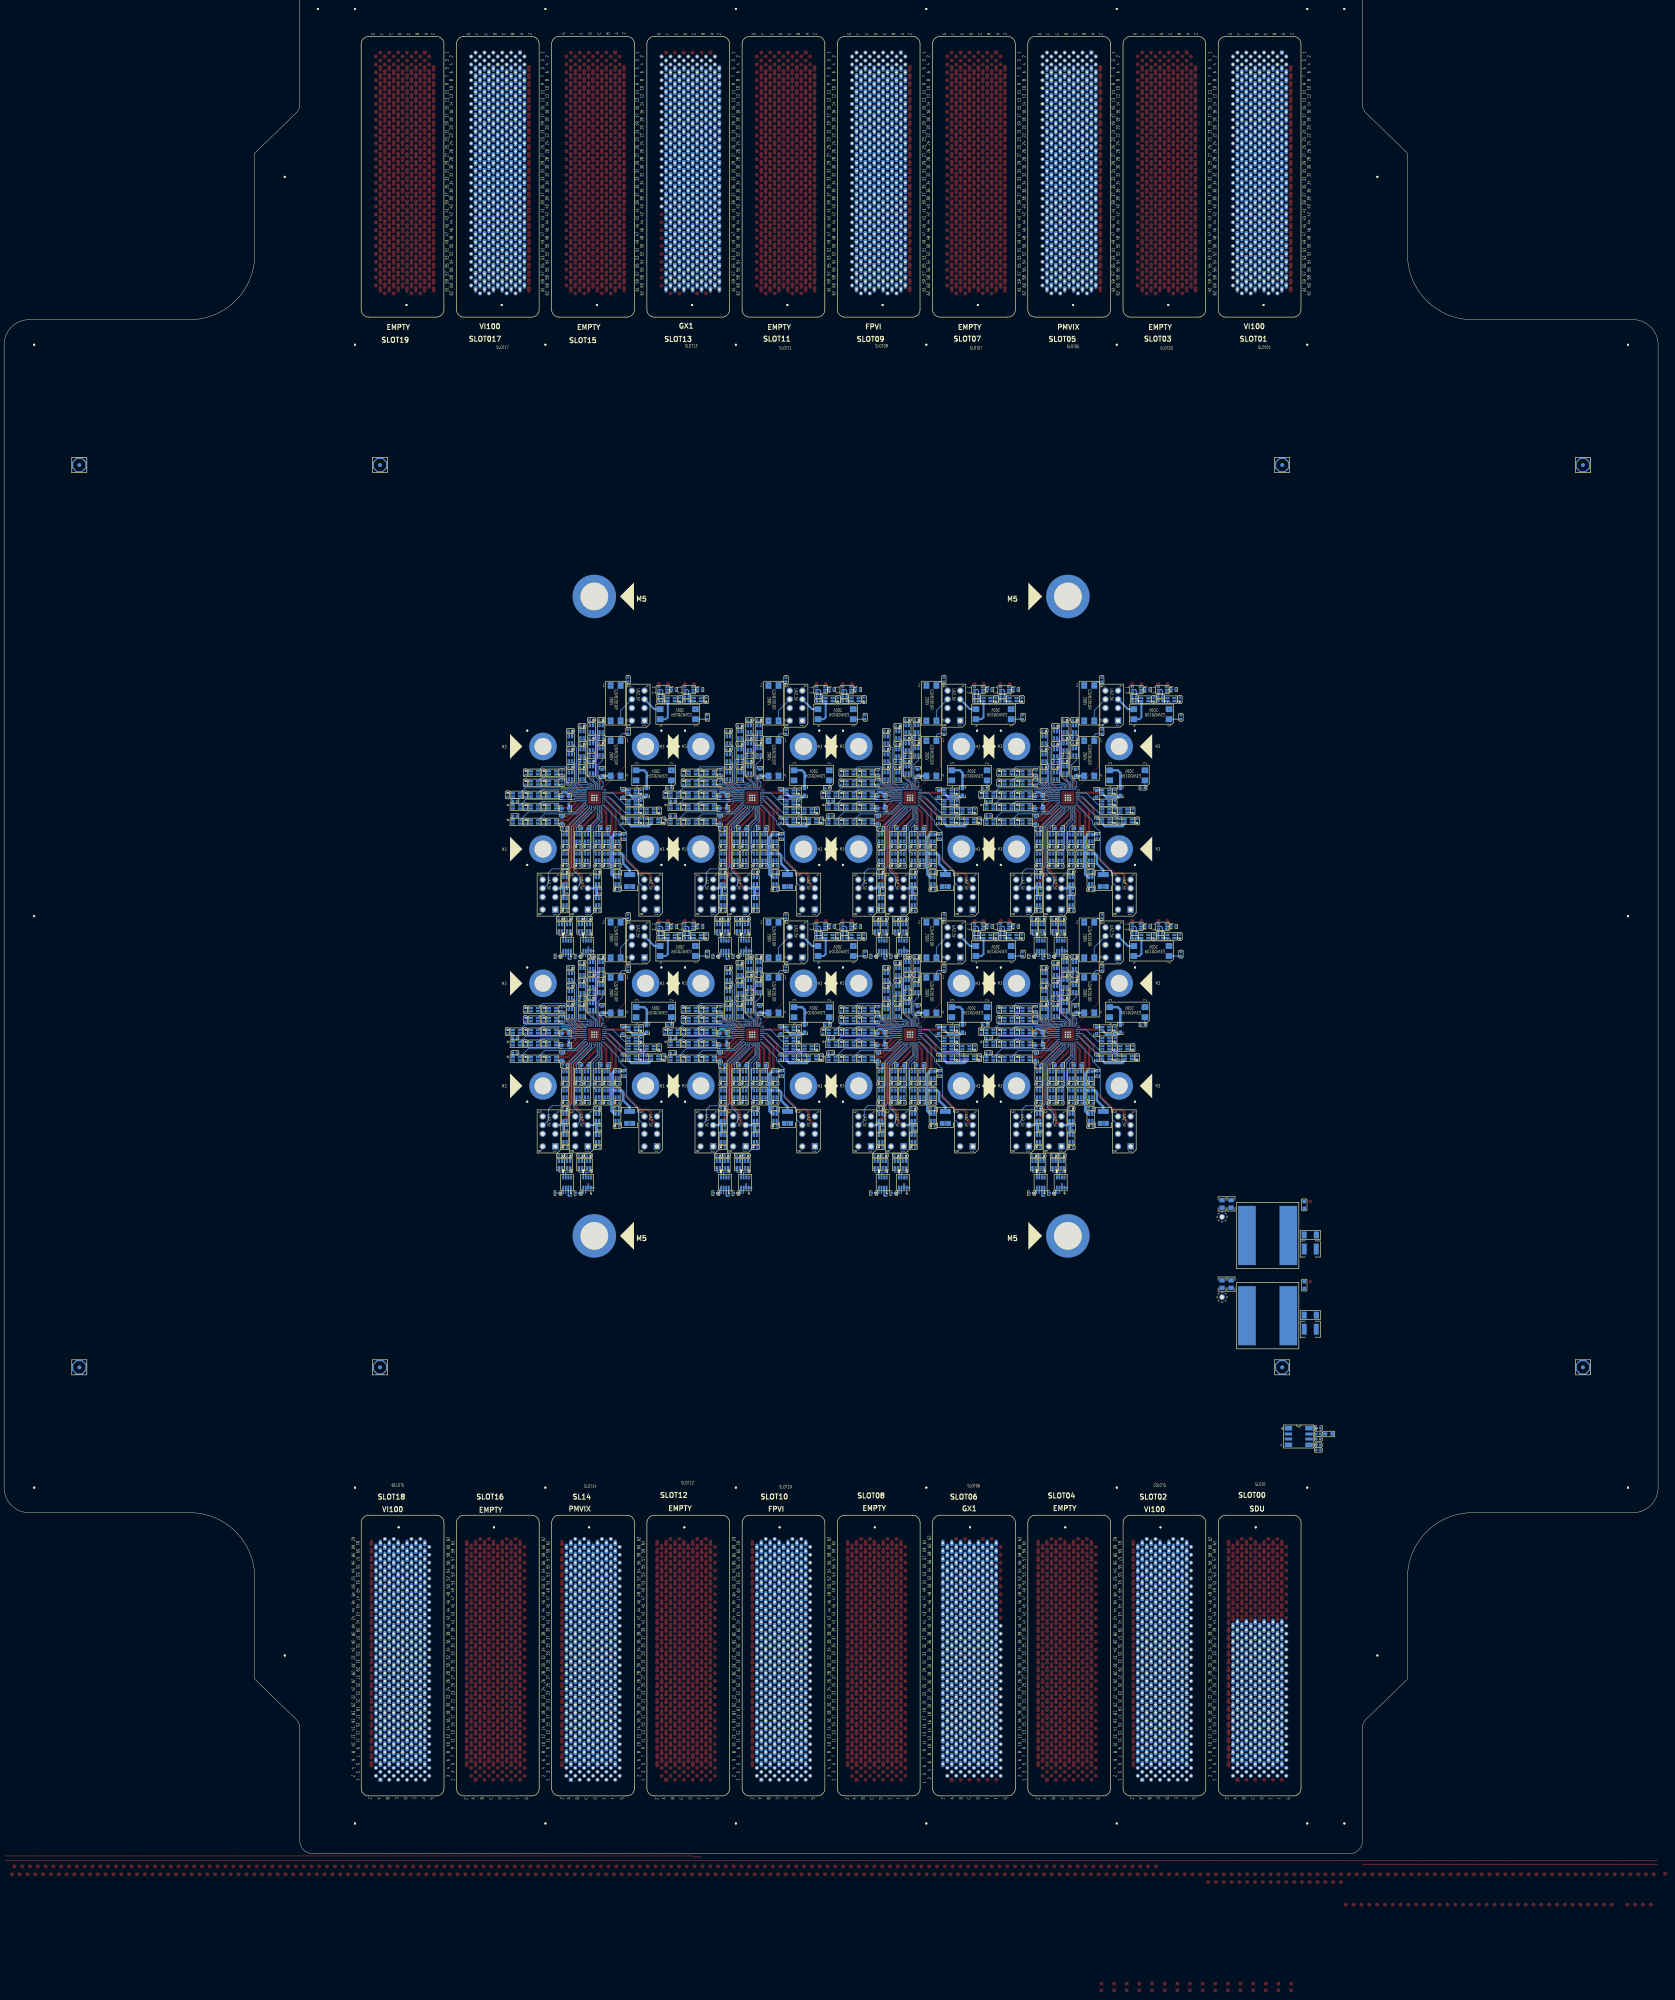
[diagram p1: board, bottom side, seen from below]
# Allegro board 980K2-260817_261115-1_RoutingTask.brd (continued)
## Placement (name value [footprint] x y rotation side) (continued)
UNK7RK8  619-1-S4  [R0402]  217.67 201.62 90 bottom
UNK7RK9  619-1-S4  [R0402]  211.95 201.62 90 bottom
UNK7RK10  619-1-S4  [R0402]  213.1 204.16 90 bottom
UNK7RK11  619-1-S4  [R0402]  223.76 195.02 180 bottom
UNK7RK12  619-1-S4  [R0402]  223.76 190.19 180 bottom
UNK7RK13  619-1-S4  [R0402]  223.76 184.22 180 bottom
UNK7RK14  619-1-S4  [R0402]  226.56 190.19 180 bottom
UNK7RK16  619-1-S4  [R0402]  226.56 195.02 180 bottom
UNK7RK17  619-1-S4  [R0402]  228.72 195.02 180 bottom
UNK7RK18  619-1-S4  [R0402]  228.72 190.19 180 bottom
UNK7RK19  619-1-S4  [R0402]  231.51 195.02 180 bottom
UNK7RK20  619-1-S4  [R0402]  231.51 190.19 180 bottom
UNK7RK21  619-1-S4  [R0402]  233.67 195.02 180 bottom
UNK7RK22  619-1-S4  [R0402]  233.67 190.19 180 bottom
UNK7RK25  619-1-S4  [R0402]  236.97 195.02 180 bottom
UNK7RK26  619-1-S4  [R0402]  236.97 190.19 180 bottom
UNK7RK27  619-1-S4  [R0402]  242.43 201.37 270 bottom
UNK7RK28  619-1-S4  [R0402]  247 201.37 270 bottom
UNK7RK29  619-1-S4  [R0402]  249.67 202.89 180 bottom
UNK7RK30  619-1-S4  [R0402]  242.43 205.18 270 bottom
UNK7RK31  619-1-S4  [R0402]  247 205.18 270 bottom
UNK7RK32  619-1-S4  [R0402]  249.67 206.7 180 bottom
UNK7RK33  619-1-S4  [R0402]  242.43 208.22 270 bottom
UNK7RK34  619-1-S4  [R0402]  247 208.22 270 bottom
UNK7RK35  619-1-S4  [R0402]  251.58 208.22 270 bottom
UNK7RK36  619-1-S4  [R0402]  242.43 211.27 270 bottom
UNK7RK37  619-1-S4  [R0402]  247 211.27 270 bottom
UNK7RK38  619-1-S4  [R0402]  242.43 213.81 270 bottom
UNK7RK39  619-1-S4  [R0402]  247 213.81 270 bottom
UNK7RK40  619-1-S4  [R0402]  235.57 215.34 0 bottom
UNK7RK41  619-1-S4  [R0402]  235.57 219.91 0 bottom
UNK7RK42  619-1-S4  [R0402]  235.57 224.48 0 bottom
UNK7RK43  619-1-S4  [R0402]  232.65 215.34 0 bottom
UNK7RK44  619-1-S4  [R0402]  232.65 221.18 0 bottom
UNK7RK45  619-1-S4  [R0402]  232.65 225.75 0 bottom
UNK7RK46  619-1-S4  [R0402]  230.24 216.86 0 bottom
UNK7RK47  619-1-S4  [R0402]  230.24 222.7 0 bottom
UNK7RK48  619-1-S4  [R0402]  230.24 227.27 0 bottom
UNK7RK49  619-1-S4  [R0402]  227.83 227.27 0 bottom
UNK7RK50  619-1-S4  [R0402]  227.83 221.43 0 bottom
UNK7RK51  619-1-S4  [R0402]  228.72 188.79 0 bottom
UNK7RK52  619-1-S4  [R0402]  228.72 178.89 180 bottom
UNK7RK53  619-1-S4  [R0402]  236.97 188.79 0 bottom
UNK7RK54  619-1-S4  [R0402]  236.97 178.89 180 bottom
UNK7RK55  619-1-S4  [R0402]  238.11 176.86 180 bottom
UNK7RK56  619-1-S4  [R0402]  236.08 176.86 180 bottom
UNK7RK57  619-1-S4  [R0402]  233.03 176.86 180 bottom
UNK7RK58  619-1-S4  [R0402]  231 176.86 180 bottom
UNK7RK59  619-1-S4  [R0402]  201.16 232.35 90 bottom
UNK7RK60  619-1-S4  [R0402]  200.9 227.9 90 bottom
UNK7RK61  619-1-S4  [R0402]  207.76 232.35 90 bottom
UNK7SH1  SHORT  [DEFAULT_SHORT_SMALL]  177.46 -1.79 0 top
UNK7SH2  SHORT  [DEFAULT_SHORT_SMALL]  201.69 -1.79 0 top
UNK7SH3  SHORT  [DEFAULT_SHORT_SMALL]  221.52 -1.79 0 top
UNK7SH4  SHORT  [DEFAULT_SHORT_SMALL]  223.73 -1.79 0 top
UNK7SH5  SHORT  [DEFAULT_SHORT_SMALL]  225.93 -1.79 0 top
UNK7SH6  SHORT  [DEFAULT_SHORT_SMALL]  228.13 -1.79 0 top
UNK7SH7  SHORT  [DEFAULT_SHORT_SMALL]  230.34 -1.79 0 top
UNK7SH8  SHORT  [DEFAULT_SHORT_SMALL]  232.54 -1.79 0 top
UNK7SH9  SHORT  [DEFAULT_SHORT_SMALL]  234.74 -1.79 0 top
UNK7SH10  SHORT  [DEFAULT_SHORT_SMALL]  179.66 -1.79 0 top
UNK7SH11  SHORT  [DEFAULT_SHORT_SMALL]  181.87 -1.79 0 top
UNK7SH12  SHORT  [DEFAULT_SHORT_SMALL]  184.07 -1.79 0 top
UNK7SH13  SHORT  [DEFAULT_SHORT_SMALL]  186.27 -1.79 0 top
UNK7SH14  SHORT  [DEFAULT_SHORT_SMALL]  188.47 -1.79 0 top
UNK7SH15  SHORT  [DEFAULT_SHORT_SMALL]  190.68 -1.79 0 top
UNK7SH16  SHORT  [DEFAULT_SHORT_SMALL]  192.88 -1.79 0 top
UNK7SH17  SHORT  [DEFAULT_SHORT_SMALL]  195.08 -1.79 0 top
UNK7SH18  SHORT  [DEFAULT_SHORT_SMALL]  197.29 -1.79 0 top
UNK7SH19  SHORT  [DEFAULT_SHORT_SMALL]  199.49 -1.79 0 top
UNK7SH20  SHORT  [DEFAULT_SHORT_SMALL]  203.9 -1.79 0 top
UNK7SH21  SHORT  [DEFAULT_SHORT_SMALL]  206.1 -1.79 0 top
UNK7SH22  SHORT  [DEFAULT_SHORT_SMALL]  208.3 -1.79 0 top
UNK7SH23  SHORT  [DEFAULT_SHORT_SMALL]  210.51 -1.79 0 top
UNK7SH24  SHORT  [DEFAULT_SHORT_SMALL]  212.71 -1.79 0 top
UNK7SH25  SHORT  [DEFAULT_SHORT_SMALL]  214.91 -1.79 0 top
UNK7SH26  SHORT  [DEFAULT_SHORT_SMALL]  217.12 -1.79 0 top
UNK7SH27  SHORT  [DEFAULT_SHORT_SMALL]  219.32 -1.79 0 top
UNK7SHORT1  SHORT  [DEFAULT_SHORT_SMALL]  411 -1.79 0 top
UNK7SHORT2  SHORT  [DEFAULT_SHORT_SMALL]  417.61 -1.79 0 top
UNK7SHORT3  SHORT  [DEFAULT_SHORT_SMALL]  1.2 -2.78 0 top
UNK7SHORT4  SHORT  [DEFAULT_SHORT_SMALL]  3.41 -2.78 0 top
UNK7SHORT6  SHORT  [DEFAULT_SHORT_SMALL]  5.61 -2.78 0 top
UNK7SHORT7  SHORT  [DEFAULT_SHORT_SMALL]  7.81 -2.78 0 top
UNK7SHORT8  SHORT  [DEFAULT_SHORT_SMALL]  10.02 -2.78 0 top
UNK7SHORT9  SHORT  [DEFAULT_SHORT_SMALL]  12.22 -2.78 0 top
UNK7SHORT10  SHORT  [DEFAULT_SHORT_SMALL]  413.2 -1.79 0 top
UNK7SHORT11  SHORT  [DEFAULT_SHORT_SMALL]  415.4 -1.79 0 top
UNK7TP_ATT_F  TP01  [TP_040_T]  189.31 -5.25 0 top
UNK7TP_ATT_S  TP01  [TP_040_T]  191.29 -5.25 0 top
UNK7TP_C1A_F  TP01  [TP_040_T]  193.27 -5.25 0 top
UNK7TP_C1A_S  TP01  [TP_040_T]  195.25 -5.25 0 top
UNK7TP_C1B_F  TP01  [TP_040_T]  197.23 -5.25 0 top
UNK7TP_C1B_S  TP01  [TP_040_T]  199.21 -5.25 0 top
UNK7TP_C2A_F  TP01  [TP_040_T]  201.19 -5.25 0 top
UNK7TP_C2A_S  TP01  [TP_040_T]  203.17 -5.25 0 top
UNK7TP_C2B_F  TP01  [TP_040_T]  205.16 -5.25 0 top
UNK7TP_C2B_S  TP01  [TP_040_T]  207.14 -5.25 0 top
UNK7TP_C3A_F  TP01  [TP_040_T]  209.12 -5.25 0 top
UNK7TP_C3A_S  TP01  [TP_040_T]  211.1 -5.25 0 top
UNK7TP_C3B_F  TP01  [TP_040_T]  213.08 -5.25 0 top
UNK7TP_C3B_S  TP01  [TP_040_T]  215.06 -5.25 0 top
UNK7TP_GA1_S  TP01  [TP_040_T]  217.04 -5.25 0 top
UNK7TP_GA2_S  TP01  [TP_040_T]  219.02 -5.25 0 top
UNK7TP_GB1_S  TP01  [TP_040_T]  221.01 -5.25 0 top
UNK7TP_GB2_S  TP01  [TP_040_T]  222.99 -5.25 0 top
UNK7TP_IN+_1  TP01  [TP_040_T]  206.61 234.24 0 top
UNK7TP_IN+_2  TP01  [TP_040_T]  213.21 234.24 0 top
UNK7TP_IN+_3  TP01  [TP_040_T]  235.68 173.69 180 top
UNK7TP_IN+_4  TP01  [TP_040_T]  230.6 173.69 180 top
UNK7TP_IN-_1  TP01  [TP_040_T]  204.31 234.24 0 top
UNK7TP_IN-_2  TP01  [TP_040_T]  210.91 234.24 0 top
UNK7TP_IN-_3  TP01  [TP_040_T]  238.51 173.69 180 top
UNK7TP_IN-_4  TP01  [TP_040_T]  233.43 173.69 180 top
UNK7TP_IS1N_F  TP01  [TP_040_T]  224.97 -5.25 0 top
UNK7TP_IS1N_S  TP01  [TP_040_T]  226.95 -5.25 0 top
UNK7TP_IS1P_F  TP01  [TP_040_T]  228.93 -5.25 0 top
UNK7TP_IS2N_F  TP01  [TP_040_T]  230.91 -5.25 0 top
UNK7TP_IS2N_S  TP01  [TP_040_T]  232.89 -5.25 0 top
UNK7TP_IS2P_S  TP01  [TP_040_T]  234.87 -5.25 0 top
UNK7TP_OPTO_F  TP01  [TP_040_T]  236.86 -5.25 0 top
UNK7TP_OPTO_S  TP01  [TP_040_T]  238.84 -5.25 0 top
UNK7TP_OUT+_1  TP01  [TP_040_T]  206.61 236.31 0 top
UNK7TP_OUT+_2  TP01  [TP_040_T]  213.21 236.31 0 top
UNK7TP_OUT-_1  TP01  [TP_040_T]  204.31 236.31 0 top
UNK7TP_OUT-_2  TP01  [TP_040_T]  210.91 236.31 0 top
UNK7TP_OUT_1  TP01  [TP_040_T]  235.49 171.3 180 top
UNK7TP_OUT_2  TP01  [TP_040_T]  230.41 171.3 180 top
UNK7TP_REF_1  TP01  [TP_040_T]  240.82 -5.25 0 top
UNK7TP_REF_2  TP01  [TP_040_T]  231.06 168.7 180 top
UNK7TP_SCL_F  TP01  [TP_040_T]  242.8 -5.25 0 top
UNK7TP_SDA_F  TP01  [TP_040_T]  244.78 -5.25 0 top
UNK7TP_SDA_S  TP01  [TP_040_T]  246.76 -5.25 0 top
UNK7TP_SRD_F  TP01  [TP_040_T]  248.74 -5.25 0 top
UNK7TP_SRD_S  TP01  [TP_040_T]  250.72 -5.25 0 top
UNK7TP_SRG_F  TP01  [TP_040_T]  252.7 -5.25 0 top
UNK7TP_SRG_S  TP01  [TP_040_T]  254.69 -5.25 0 top
UNK7TP_SRS_F  TP01  [TP_040_T]  256.67 -5.25 0 top
UNK7TP_SRS_S  TP01  [TP_040_T]  258.65 -5.25 0 top
UNK7TP_STB_F  TP01  [TP_040_T]  260.63 -5.25 0 top
UNK7TP_STB_S  TP01  [TP_040_T]  262.61 -5.25 0 top
UNK7TP_VCC_F  TP01  [TP_040_T]  264.59 -5.25 0 top
UNK7TP_VCC_S  TP01  [TP_040_T]  266.57 -5.25 0 top
UNK7TP_VDD0_F  TP01  [TP_040_T]  268.55 -5.25 0 top
UNK7TP_VDD0_S  TP01  [TP_040_T]  270.54 -5.25 0 top
UNK7TP_VDD1_S  TP01  [TP_040_T]  272.52 -5.25 0 top
UNK7TP_VDD2_S  TP01  [TP_040_T]  274.5 -5.25 0 top
UNK7TP_VDDI_F  TP01  [TP_040_T]  276.48 -5.25 0 top
UNK7TP_VDDI_S  TP01  [TP_040_T]  278.46 -5.25 0 top
UNK7TP_VIN_F  TP01  [TP_040_T]  280.44 -5.25 0 top
UNK7TP_VIN_S  TP01  [TP_040_T]  282.42 -5.25 0 top
UNK7TP_VO1_S  TP01  [TP_040_T]  284.4 -5.25 0 top
UNK7TP_VO2_S  TP01  [TP_040_T]  286.38 -5.25 0 top
UNK7TP_VSR_F  TP01  [TP_040_T]  288.37 -5.25 0 top
UNK7TP_VSR_S  TP01  [TP_040_T]  290.35 -5.25 0 top
UNK7U1  TLV3604DCKR-SC70  [SC70]  205.61 234.89 270 bottom
UNK7U2  TLV3604DCKR-SC70  [SC70]  212.21 234.89 270 bottom
UNK7U3  INA186A3QDDFRQ1-SOT23-8  [SOT23_8P_0P65MM_H1P3MM]  236.46 170 180 bottom
UNK7U4  INA186A3QDDFRQ1-SOT23-8  [SOT23_8P_0P65MM_H1P3MM]  231.38 170 180 bottom
UNK8C48  0.01U-100-X7R-S6-MU  [C0603]  267.57 213.87 90 bottom
UNK8C49  0.01U-100-X7R-S6-MU  [C0603]  256.27 208.99 270 bottom
UNK8C50  0.01U-100-X7R-S6-MU  [C0603]  262.28 208.54 270 bottom
UNK8C53  1U-16-X5R-S4-YA  [C0402]  262.24 201.62 270 bottom
UNK8C54  2.2U-16-X-S4-MU  [C0402]  256.52 201.62 270 bottom
UNK8C58  1U-16-X5R-S4-YA  [C0402]  262.11 197.68 270 bottom
UNK8C59  4.7U-100-X-SB-MU  [C1210]  260.59 186.51 270 bottom
UNK8C60  0.01U-100-X7R-S6-MU  [C0603]  267.01 199.72 0 bottom
UNK8C61  0.01U-100-X7R-S6-MU  [C0603]  276.88 204.78 180 bottom
UNK8C62  2.2U-16-X-S4-MU  [C0402]  277.07 199.72 0 bottom
UNK8C63  0.01U-100-X7R-S6-MU  [C0603]  277.73 201.82 90 bottom
UNK8C64  0.01U-100-X7R-S6-MU  [C0603]  276.88 207.82 180 bottom
UNK8C65  0.1U-25-X7R-S4-MU  [C0402]  277.73 211.37 90 bottom
UNK8C66  0.1U-25-X7R-S4-MU  [C0402]  272.65 216.61 180 bottom
UNK8C67  0.1U-25-X7R-S4-MU  [C0402]  270.24 218.13 180 bottom
UNK8C68  0.1U-25-X7R-S4-MU  [C0402]  267.83 222.7 180 bottom
UNK8C69  0.01U-100-X7R-S6-MU  [C0603]  271.96 199.72 0 bottom
UNK8C70  0.1U-25-X7R-S4-MU  [C0402]  242.8 234.89 180 bottom
UNK8C71  0.1U-25-X7R-S4-MU  [C0402]  249.42 234.89 180 bottom
UNK8C72  0.1U-25-X7R-S4-MU  [C0402]  278.75 167.33 0 bottom
UNK8C73  0.1U-25-X7R-S4-MU  [C0402]  273.67 167.33 0 bottom
UNK8C74  0.1U-25-X7R-S4-MU  [C0402]  277.73 213.91 90 bottom
UNK8K1  UA2-5NJ-A-V3  [RL_NECUA2_5V_V3]  258.43 230.63 270 bottom
UNK8K2  G3VM-201DR  [RL_G3VM201DR_200V]  264.14 217.5 0 bottom
UNK8K3  G3VM-201DR  [RL_G3VM201DR_200V]  254.49 213.18 90 bottom
UNK8K4  G3VM-201DR  [RL_G3VM201DR_200V]  264.14 231.47 0 bottom
UNK8K5  G3VM-51UR-5V-VSON4  [RL_G3VM_4P_VSON4]  259.95 208.99 0 bottom
UNK8K6  G3VM-51UR-5V-VSON4  [RL_G3VM_4P_VSON4]  259.95 206.19 0 bottom
UNK8K7  G3VM-51UR-5V-VSON4  [RL_G3VM_4P_VSON4]  259.95 204.16 0 bottom
UNK8K8  G3VM-51UR-5V-VSON4  [RL_G3VM_4P_VSON4]  259.95 201.62 0 bottom
UNK8K9  G3VM-51UR-5V-VSON4  [RL_G3VM_4P_VSON4]  254.24 201.62 0 bottom
UNK8K10  G3VM-51UR-5V-VSON4  [RL_G3VM_4P_VSON4]  255.38 204.16 0 bottom
UNK8K11  G3VM-51UR-5V-VSON4  [RL_G3VM_4P_VSON4]  263.76 197.3 90 bottom
UNK8K12  G3VM-51UR-5V-VSON4  [RL_G3VM_4P_VSON4]  263.76 192.48 90 bottom
UNK8K13  G3VM-51UR-5V-VSON4  [RL_G3VM_4P_VSON4]  263.76 186.51 90 bottom
UNK8K14  G3VM-51UR-5V-VSON4  [RL_G3VM_4P_VSON4]  266.56 192.48 90 bottom
UNK8K15  UA2-5NJ-A-V3  [RL_NECUA2_5V_V3]  255.25 182.75 270 bottom
UNK8K16  G3VM-51UR-5V-VSON4  [RL_G3VM_4P_VSON4]  266.56 197.3 90 bottom
UNK8K17  G3VM-51UR-5V-VSON4  [RL_G3VM_4P_VSON4]  268.72 197.3 90 bottom
UNK8K18  G3VM-51UR-5V-VSON4  [RL_G3VM_4P_VSON4]  268.72 192.48 90 bottom
UNK8K19  G3VM-51UR-5V-VSON4  [RL_G3VM_4P_VSON4]  271.51 197.3 90 bottom
UNK8K20  G3VM-51UR-5V-VSON4  [RL_G3VM_4P_VSON4]  271.51 192.48 90 bottom
UNK8K21  G3VM-51UR-5V-VSON4  [RL_G3VM_4P_VSON4]  273.67 197.3 90 bottom
UNK8K22  G3VM-51UR-5V-VSON4  [RL_G3VM_4P_VSON4]  273.67 192.48 90 bottom
UNK8K23  UA2-5NJ-A-V3  [RL_NECUA2_5V_V3]  272.78 182.75 270 bottom
UNK8K24  UA2-5NJ-A-V3  [RL_NECUA2_5V_V3]  281.04 182.75 270 bottom
UNK8K25  G3VM-51UR-5V-VSON4  [RL_G3VM_4P_VSON4]  276.97 197.3 90 bottom
UNK8K26  G3VM-51UR-5V-VSON4  [RL_G3VM_4P_VSON4]  276.97 192.48 90 bottom
UNK8K27  G3VM-51UR-5V-VSON4  [RL_G3VM_4P_VSON4]  280.15 201.37 180 bottom
UNK8K28  G3VM-51UR-5V-VSON4  [RL_G3VM_4P_VSON4]  284.72 201.37 180 bottom
UNK8K29  G3VM-51UR-5V-VSON4  [RL_G3VM_4P_VSON4]  289.29 201.37 180 bottom
UNK8K30  G3VM-51UR-5V-VSON4  [RL_G3VM_4P_VSON4]  280.15 205.18 180 bottom
UNK8K31  G3VM-51UR-5V-VSON4  [RL_G3VM_4P_VSON4]  284.72 205.18 180 bottom
UNK8K32  G3VM-51UR-5V-VSON4  [RL_G3VM_4P_VSON4]  289.29 205.18 180 bottom
UNK8K33  G3VM-51UR-5V-VSON4  [RL_G3VM_4P_VSON4]  280.15 208.22 180 bottom
UNK8K34  G3VM-51UR-5V-VSON4  [RL_G3VM_4P_VSON4]  284.72 208.22 180 bottom
UNK8K35  G3VM-51UR-5V-VSON4  [RL_G3VM_4P_VSON4]  289.29 208.22 180 bottom
UNK8K36  G3VM-51UR-5V-VSON4  [RL_G3VM_4P_VSON4]  280.15 211.27 180 bottom
UNK8K37  G3VM-51UR-5V-VSON4  [RL_G3VM_4P_VSON4]  284.72 211.27 180 bottom
UNK8K38  G3VM-51UR-5V-VSON4  [RL_G3VM_4P_VSON4]  280.15 213.81 180 bottom
UNK8K39  G3VM-51UR-5V-VSON4  [RL_G3VM_4P_VSON4]  284.72 213.81 180 bottom
UNK8K40  G3VM-51UR-5V-VSON4  [RL_G3VM_4P_VSON4]  275.57 213.05 270 bottom
UNK8K41  G3VM-51UR-5V-VSON4  [RL_G3VM_4P_VSON4]  275.57 217.62 270 bottom
UNK8K42  G3VM-51UR-5V-VSON4  [RL_G3VM_4P_VSON4]  275.57 222.19 270 bottom
UNK8K43  G3VM-51UR-5V-VSON4  [RL_G3VM_4P_VSON4]  272.65 213.05 270 bottom
UNK8K44  G3VM-51UR-5V-VSON4  [RL_G3VM_4P_VSON4]  272.65 218.89 270 bottom
UNK8K45  G3VM-51UR-5V-VSON4  [RL_G3VM_4P_VSON4]  272.65 223.46 270 bottom
UNK8K46  G3VM-51UR-5V-VSON4  [RL_G3VM_4P_VSON4]  270.24 214.57 270 bottom
UNK8K47  G3VM-51UR-5V-VSON4  [RL_G3VM_4P_VSON4]  270.24 220.42 270 bottom
UNK8K48  G3VM-51UR-5V-VSON4  [RL_G3VM_4P_VSON4]  270.24 224.99 270 bottom
UNK8K49  G3VM-51UR-5V-VSON4  [RL_G3VM_4P_VSON4]  267.83 224.99 270 bottom
UNK8K50  G3VM-51UR-5V-VSON4  [RL_G3VM_4P_VSON4]  267.83 219.15 270 bottom
UNK8K51  G3VM-51UR-5V-VSON4  [RL_G3VM_4P_VSON4]  268.72 186.51 270 bottom
UNK8K52  G3VM-51UR-5V-VSON4  [RL_G3VM_4P_VSON4]  268.72 181.17 90 bottom
UNK8K53  G3VM-51UR-5V-VSON4  [RL_G3VM_4P_VSON4]  276.97 186.51 270 bottom
UNK8K54  G3VM-51UR-5V-VSON4  [RL_G3VM_4P_VSON4]  276.97 181.17 90 bottom
UNK8K55  G3VM-51UR-5V-VSON4  [RL_G3VM_4P_VSON4]  243.44 232.35 0 bottom
UNK8K56  G3VM-201DR  [RL_G3VM201DR_200V]  248.4 228.67 90 bottom
UNK8K57  G3VM-51UR-5V-VSON4  [RL_G3VM_4P_VSON4]  278.11 174.57 270 bottom
UNK8K58  G3VM-51UR-5V-VSON4  [RL_G3VM_4P_VSON4]  276.08 174.57 270 bottom
UNK8K59  G3VM-51UR-5V-VSON4  [RL_G3VM_4P_VSON4]  273.03 174.57 270 bottom
UNK8K60  G3VM-51UR-5V-VSON4  [RL_G3VM_4P_VSON4]  271 174.57 270 bottom
UNK8K61  G3VM-51UR-5V-VSON4  [RL_G3VM_4P_VSON4]  250.05 232.35 0 bottom
UNK8R1  10K-0.1-S4  [R0402]  263.76 188.79 0 bottom
UNK8R7  4.7K-1-S4-WA  [R0402]  268.21 183.84 90 bottom
UNK8R8  4.7K-1-S4-WA  [R0402]  276.46 183.84 90 bottom
UNK8R11  5K-1-S4-YA  [R0402]  246.11 233.12 0 bottom
UNK8R14  5K-1-S4-YA  [R0402]  252.71 233.12 0 bottom
UNK8R15  0-0-S2-KOA  [R0201]  277.14 167.33 0 bottom
UNK8R16  5.1-1-S2  [R0201]  277.11 172.54 180 bottom
UNK8R17  0-0-S2-KOA  [R0201]  272.06 167.33 0 bottom
UNK8R18  5.1-1-S2  [R0201]  272.03 172.54 180 bottom
UNK8R19  100K-0.1-S4-YA  [R0402]  246.11 231.95 180 bottom
UNK8R20  100K-0.1-S4-YA  [R0402]  252.71 231.95 180 bottom
UNK8R41  0-5-S6  [R0603]  99.4 -33.82 270 top
UNK8R42  0-5-S6  [R0603]  96.2 -33.82 270 top
UNK8RK2  619-1-S4  [R0402]  260.97 224.23 90 bottom
UNK8RK3  619-1-S4  [R0402]  250.52 209.99 0 bottom
UNK8RK4  619-1-S4  [R0402]  260.97 237.43 90 bottom
UNK8RK5  619-1-S4  [R0402]  257.67 208.99 90 bottom
UNK8RK6  619-1-S4  [R0402]  257.67 206.19 90 bottom
UNK8RK7  619-1-S4  [R0402]  257.67 204.16 90 bottom
UNK8RK8  619-1-S4  [R0402]  257.67 201.62 90 bottom
UNK8RK9  619-1-S4  [R0402]  251.95 201.62 90 bottom
UNK8RK10  619-1-S4  [R0402]  253.1 204.16 90 bottom
UNK8RK11  619-1-S4  [R0402]  263.76 195.02 180 bottom
UNK8RK12  619-1-S4  [R0402]  263.76 190.19 180 bottom
UNK8RK13  619-1-S4  [R0402]  263.76 184.22 180 bottom
UNK8RK14  619-1-S4  [R0402]  266.56 190.19 180 bottom
UNK8RK16  619-1-S4  [R0402]  266.56 195.02 180 bottom
UNK8RK17  619-1-S4  [R0402]  268.72 195.02 180 bottom
UNK8RK18  619-1-S4  [R0402]  268.72 190.19 180 bottom
UNK8RK19  619-1-S4  [R0402]  271.51 195.02 180 bottom
UNK8RK20  619-1-S4  [R0402]  271.51 190.19 180 bottom
UNK8RK21  619-1-S4  [R0402]  273.67 195.02 180 bottom
UNK8RK22  619-1-S4  [R0402]  273.67 190.19 180 bottom
UNK8RK25  619-1-S4  [R0402]  276.97 195.02 180 bottom
UNK8RK26  619-1-S4  [R0402]  276.97 190.19 180 bottom
UNK8RK27  619-1-S4  [R0402]  282.43 201.37 270 bottom
UNK8RK28  619-1-S4  [R0402]  287 201.37 270 bottom
UNK8RK29  619-1-S4  [R0402]  289.67 202.89 180 bottom
UNK8RK30  619-1-S4  [R0402]  282.43 205.18 270 bottom
UNK8RK31  619-1-S4  [R0402]  287 205.18 270 bottom
UNK8RK32  619-1-S4  [R0402]  289.67 206.7 180 bottom
UNK8RK33  619-1-S4  [R0402]  282.43 208.22 270 bottom
UNK8RK34  619-1-S4  [R0402]  287 208.22 270 bottom
UNK8RK35  619-1-S4  [R0402]  291.58 208.22 270 bottom
UNK8RK36  619-1-S4  [R0402]  282.43 211.27 270 bottom
UNK8RK37  619-1-S4  [R0402]  287 211.27 270 bottom
UNK8RK38  619-1-S4  [R0402]  282.43 213.81 270 bottom
UNK8RK39  619-1-S4  [R0402]  287 213.81 270 bottom
UNK8RK40  619-1-S4  [R0402]  275.57 215.34 0 bottom
UNK8RK41  619-1-S4  [R0402]  275.57 219.91 0 bottom
UNK8RK42  619-1-S4  [R0402]  275.57 224.48 0 bottom
UNK8RK43  619-1-S4  [R0402]  272.65 215.34 0 bottom
UNK8RK44  619-1-S4  [R0402]  272.65 221.18 0 bottom
UNK8RK45  619-1-S4  [R0402]  272.65 225.75 0 bottom
UNK8RK46  619-1-S4  [R0402]  270.24 216.86 0 bottom
UNK8RK47  619-1-S4  [R0402]  270.24 222.7 0 bottom
UNK8RK48  619-1-S4  [R0402]  270.24 227.27 0 bottom
UNK8RK49  619-1-S4  [R0402]  267.83 227.27 0 bottom
UNK8RK50  619-1-S4  [R0402]  267.83 221.43 0 bottom
UNK8RK51  619-1-S4  [R0402]  268.72 188.79 0 bottom
UNK8RK52  619-1-S4  [R0402]  268.72 178.89 180 bottom
UNK8RK53  619-1-S4  [R0402]  276.97 188.79 0 bottom
UNK8RK54  619-1-S4  [R0402]  276.97 178.89 180 bottom
UNK8RK55  619-1-S4  [R0402]  278.11 176.86 180 bottom
UNK8RK56  619-1-S4  [R0402]  276.08 176.86 180 bottom
UNK8RK57  619-1-S4  [R0402]  273.03 176.86 180 bottom
UNK8RK58  619-1-S4  [R0402]  271 176.86 180 bottom
UNK8RK59  619-1-S4  [R0402]  241.16 232.35 90 bottom
UNK8RK60  619-1-S4  [R0402]  240.9 227.9 90 bottom
UNK8RK61  619-1-S4  [R0402]  247.76 232.35 90 bottom
UNK8SH1  SHORT  [DEFAULT_SHORT_SMALL]  236.95 -1.79 0 top
UNK8SH2  SHORT  [DEFAULT_SHORT_SMALL]  261.18 -1.79 0 top
UNK8SH3  SHORT  [DEFAULT_SHORT_SMALL]  281.01 -1.79 0 top
UNK8SH4  SHORT  [DEFAULT_SHORT_SMALL]  283.21 -1.79 0 top
UNK8SH5  SHORT  [DEFAULT_SHORT_SMALL]  285.42 -1.79 0 top
UNK8SH6  SHORT  [DEFAULT_SHORT_SMALL]  287.62 -1.79 0 top
UNK8SH7  SHORT  [DEFAULT_SHORT_SMALL]  289.82 -1.79 0 top
UNK8SH8  SHORT  [DEFAULT_SHORT_SMALL]  292.03 -1.79 0 top
UNK8SH9  SHORT  [DEFAULT_SHORT_SMALL]  294.23 -1.79 0 top
UNK8SH10  SHORT  [DEFAULT_SHORT_SMALL]  239.15 -1.79 0 top
UNK8SH11  SHORT  [DEFAULT_SHORT_SMALL]  241.35 -1.79 0 top
UNK8SH12  SHORT  [DEFAULT_SHORT_SMALL]  243.55 -1.79 0 top
UNK8SH13  SHORT  [DEFAULT_SHORT_SMALL]  245.76 -1.79 0 top
UNK8SH14  SHORT  [DEFAULT_SHORT_SMALL]  247.96 -1.79 0 top
UNK8SH15  SHORT  [DEFAULT_SHORT_SMALL]  250.16 -1.79 0 top
UNK8SH16  SHORT  [DEFAULT_SHORT_SMALL]  252.37 -1.79 0 top
UNK8SH17  SHORT  [DEFAULT_SHORT_SMALL]  254.57 -1.79 0 top
UNK8SH18  SHORT  [DEFAULT_SHORT_SMALL]  256.77 -1.79 0 top
UNK8SH19  SHORT  [DEFAULT_SHORT_SMALL]  258.98 -1.79 0 top
UNK8SH20  SHORT  [DEFAULT_SHORT_SMALL]  263.38 -1.79 0 top
UNK8SH21  SHORT  [DEFAULT_SHORT_SMALL]  265.59 -1.79 0 top
UNK8SH22  SHORT  [DEFAULT_SHORT_SMALL]  267.79 -1.79 0 top
UNK8SH23  SHORT  [DEFAULT_SHORT_SMALL]  269.99 -1.79 0 top
UNK8SH24  SHORT  [DEFAULT_SHORT_SMALL]  272.2 -1.79 0 top
UNK8SH25  SHORT  [DEFAULT_SHORT_SMALL]  274.4 -1.79 0 top
UNK8SH26  SHORT  [DEFAULT_SHORT_SMALL]  276.6 -1.79 0 top
UNK8SH27  SHORT  [DEFAULT_SHORT_SMALL]  278.81 -1.79 0 top
UNK8SHORT1  SHORT  [DEFAULT_SHORT_SMALL]  14.42 -2.78 0 top
UNK8SHORT2  SHORT  [DEFAULT_SHORT_SMALL]  21.03 -2.78 0 top
UNK8SHORT3  SHORT  [DEFAULT_SHORT_SMALL]  23.24 -2.78 0 top
UNK8SHORT4  SHORT  [DEFAULT_SHORT_SMALL]  25.44 -2.78 0 top
UNK8SHORT6  SHORT  [DEFAULT_SHORT_SMALL]  27.64 -2.78 0 top
UNK8SHORT7  SHORT  [DEFAULT_SHORT_SMALL]  29.84 -2.78 0 top
UNK8SHORT8  SHORT  [DEFAULT_SHORT_SMALL]  32.05 -2.78 0 top
UNK8SHORT9  SHORT  [DEFAULT_SHORT_SMALL]  34.25 -2.78 0 top
UNK8SHORT10  SHORT  [DEFAULT_SHORT_SMALL]  16.63 -2.78 0 top
UNK8SHORT11  SHORT  [DEFAULT_SHORT_SMALL]  18.83 -2.78 0 top
UNK8TP_ATT_F  TP01  [TP_040_T]  292.33 -5.25 0 top
UNK8TP_ATT_S  TP01  [TP_040_T]  294.31 -5.25 0 top
UNK8TP_C1A_F  TP01  [TP_040_T]  296.29 -5.25 0 top
UNK8TP_C1A_S  TP01  [TP_040_T]  298.27 -5.25 0 top
UNK8TP_C1B_F  TP01  [TP_040_T]  300.25 -5.25 0 top
UNK8TP_C1B_S  TP01  [TP_040_T]  302.23 -5.25 0 top
UNK8TP_C2A_F  TP01  [TP_040_T]  304.22 -5.25 0 top
UNK8TP_C2A_S  TP01  [TP_040_T]  306.2 -5.25 0 top
UNK8TP_C2B_F  TP01  [TP_040_T]  308.18 -5.25 0 top
UNK8TP_C2B_S  TP01  [TP_040_T]  310.16 -5.25 0 top
UNK8TP_C3A_F  TP01  [TP_040_T]  312.14 -5.25 0 top
UNK8TP_C3A_S  TP01  [TP_040_T]  314.12 -5.25 0 top
UNK8TP_C3B_F  TP01  [TP_040_T]  316.1 -5.25 0 top
UNK8TP_C3B_S  TP01  [TP_040_T]  318.08 -5.25 0 top
UNK8TP_GA1_S  TP01  [TP_040_T]  320.07 -5.25 0 top
UNK8TP_GA2_S  TP01  [TP_040_T]  322.05 -5.25 0 top
UNK8TP_GB1_S  TP01  [TP_040_T]  324.03 -5.25 0 top
UNK8TP_GB2_S  TP01  [TP_040_T]  326.01 -5.25 0 top
UNK8TP_IN+_1  TP01  [TP_040_T]  246.61 234.24 0 top
UNK8TP_IN+_2  TP01  [TP_040_T]  253.21 234.24 0 top
UNK8TP_IN+_3  TP01  [TP_040_T]  275.68 173.69 180 top
UNK8TP_IN+_4  TP01  [TP_040_T]  270.6 173.69 180 top
UNK8TP_IN-_1  TP01  [TP_040_T]  244.31 234.24 0 top
UNK8TP_IN-_2  TP01  [TP_040_T]  250.91 234.24 0 top
UNK8TP_IN-_3  TP01  [TP_040_T]  278.51 173.69 180 top
UNK8TP_IN-_4  TP01  [TP_040_T]  273.43 173.69 180 top
UNK8TP_IS1N_F  TP01  [TP_040_T]  327.99 -5.25 0 top
UNK8TP_IS1N_S  TP01  [TP_040_T]  329.97 -5.25 0 top
UNK8TP_IS1P_F  TP01  [TP_040_T]  331.95 -5.25 0 top
UNK8TP_IS2N_F  TP01  [TP_040_T]  333.93 -5.25 0 top
UNK8TP_IS2N_S  TP01  [TP_040_T]  335.92 -5.25 0 top
UNK8TP_IS2P_S  TP01  [TP_040_T]  337.9 -5.25 0 top
UNK8TP_OPTO_F  TP01  [TP_040_T]  339.88 -5.25 0 top
UNK8TP_OPTO_S  TP01  [TP_040_T]  341.86 -5.25 0 top
UNK8TP_OUT+_1  TP01  [TP_040_T]  246.61 236.31 0 top
UNK8TP_OUT+_2  TP01  [TP_040_T]  253.21 236.31 0 top
UNK8TP_OUT-_1  TP01  [TP_040_T]  244.31 236.31 0 top
UNK8TP_OUT-_2  TP01  [TP_040_T]  250.91 236.31 0 top
UNK8TP_OUT_1  TP01  [TP_040_T]  275.49 171.3 180 top
UNK8TP_OUT_2  TP01  [TP_040_T]  270.41 171.3 180 top
UNK8TP_REF_1  TP01  [TP_040_T]  343.84 -5.25 0 top
UNK8TP_REF_2  TP01  [TP_040_T]  271.06 168.7 180 top
UNK8TP_SCL_F  TP01  [TP_040_T]  345.82 -5.25 0 top
UNK8TP_SDA_F  TP01  [TP_040_T]  347.8 -5.25 0 top
UNK8TP_SDA_S  TP01  [TP_040_T]  349.78 -5.25 0 top
UNK8TP_SRD_F  TP01  [TP_040_T]  351.76 -5.25 0 top
UNK8TP_SRD_S  TP01  [TP_040_T]  353.75 -5.25 0 top
UNK8TP_SRG_F  TP01  [TP_040_T]  355.73 -5.25 0 top
UNK8TP_SRG_S  TP01  [TP_040_T]  357.71 -5.25 0 top
UNK8TP_SRS_F  TP01  [TP_040_T]  359.69 -5.25 0 top
UNK8TP_SRS_S  TP01  [TP_040_T]  361.67 -5.25 0 top
UNK8TP_STB_F  TP01  [TP_040_T]  363.65 -5.25 0 top
UNK8TP_STB_S  TP01  [TP_040_T]  365.63 -5.25 0 top
UNK8TP_VCC_F  TP01  [TP_040_T]  367.61 -5.25 0 top
UNK8TP_VCC_S  TP01  [TP_040_T]  369.6 -5.25 0 top
UNK8TP_VDD0_F  TP01  [TP_040_T]  371.58 -5.25 0 top
UNK8TP_VDD0_S  TP01  [TP_040_T]  373.56 -5.25 0 top
UNK8TP_VDD1_S  TP01  [TP_040_T]  375.54 -5.25 0 top
UNK8TP_VDD2_S  TP01  [TP_040_T]  377.52 -5.25 0 top
UNK8TP_VDDI_F  TP01  [TP_040_T]  379.5 -5.25 0 top
UNK8TP_VDDI_S  TP01  [TP_040_T]  381.48 -5.25 0 top
UNK8TP_VIN_F  TP01  [TP_040_T]  383.46 -5.25 0 top
UNK8TP_VIN_S  TP01  [TP_040_T]  385.45 -5.25 0 top
UNK8TP_VO1_S  TP01  [TP_040_T]  387.43 -5.25 0 top
UNK8TP_VO2_S  TP01  [TP_040_T]  389.41 -5.25 0 top
UNK8TP_VSR_F  TP01  [TP_040_T]  391.39 -5.25 0 top
UNK8TP_VSR_S  TP01  [TP_040_T]  393.37 -5.25 0 top
UNK8U1  TLV3604DCKR-SC70  [SC70]  245.61 234.89 270 bottom
UNK8U2  TLV3604DCKR-SC70  [SC70]  252.21 234.89 270 bottom
UNK8U3  INA186A3QDDFRQ1-SOT23-8  [SOT23_8P_0P65MM_H1P3MM]  276.46 170 180 bottom
UNK8U4  INA186A3QDDFRQ1-SOT23-8  [SOT23_8P_0P65MM_H1P3MM]  271.38 170 180 bottom
UNK038K2-26081712Q-A100  REF-CODE-PCB  [PCB_CODE]  336.55 450.85 0 top
UNK980K2-260817-1A4-  REF-CODE-PCB  [PCB_CODE]  336.55 453.39 0 top

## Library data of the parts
BC9 = 0.1U-50-X-S4-TDK: User Part Number: PNXXXXXXXXXX; Tolerance: TOL
BR5 BR6 = 1K-1-S4: User Part Number: PNXXXXXXXXXX; Tolerance: TOL
BR7 R41 R42 UNK2R43 UNK2R44 UNK3R41 UNK3R42 UNK4R41 UNK4R42 UNK5R41 UNK5R42 UNK6R41 UNK6R42 UNK7R41 UNK7R42 UNK8R41 UNK8R42 = 0-5-S6: User Part Number: PNXXXXXXXXXX; Tolerance: TOL
BR8 BR9 = 0-5-S4: User Part Number: PNXXXXXXXXXX; Tolerance: TOL
BU1 = AT24C512C-SSHM-T-SOIC8: User Part Number: PNXXXXXXXXXX; Tolerance: TOL
C48-C50 C60 C61 C63 C64 C69 UNK2C48-UNK2C50 UNK2C60 UNK2C61 UNK2C63 UNK2C64 UNK2C69 UNK3C48-UNK3C50 UNK3C60 UNK3C61 UNK3C63 UNK3C64 UNK3C69 UNK4C48-UNK4C50 UNK4C60 UNK4C61 UNK4C63 UNK4C64 UNK4C69 UNK5C48-UNK5C50 UNK5C60 UNK5C61 UNK5C63 UNK5C64 UNK5C69 UNK6C48-UNK6C50 UNK6C60 UNK6C61 UNK6C63 UNK6C64 UNK6C69 UNK7C48-UNK7C50 UNK7C60 UNK7C61 UNK7C63 UNK7C64 UNK7C69 UNK8C48-UNK8C50 UNK8C60 UNK8C61 UNK8C63 UNK8C64 UNK8C69 = 0.01U-100-X7R-S6-MU: User Part Number: PNXXXXXXXXXX; Tolerance: TOL
C53 C58 UNK2C53 UNK2C58 UNK3C53 UNK3C58 UNK4C53 UNK4C58 UNK5C53 UNK5C58 UNK6C53 UNK6C58 UNK7C53 UNK7C58 UNK8C53 UNK8C58 = 1U-16-X5R-S4-YA: User Part Number: PNXXXXXXXXXX; Tolerance: TOL
C54 C62 UNK2C54 UNK2C62 UNK3C54 UNK3C62 UNK4C54 UNK4C62 UNK5C54 UNK5C62 UNK6C54 UNK6C62 UNK7C54 UNK7C62 UNK8C54 UNK8C62 = 2.2U-16-X-S4-MU: User Part Number: PNXXXXXXXXXX; Tolerance: TOL
C59 UNK2C59 UNK3C59 UNK4C59 UNK5C59 UNK6C59 UNK7C59 UNK8C59 = 4.7U-100-X-SB-MU: User Part Number: PNXXXXXXXXXX; Tolerance: TOL
C65-C68 C70-C74 UNK2C65-UNK2C68 UNK2C70-UNK2C74 UNK3C65-UNK3C68 UNK3C70-UNK3C74 UNK4C65-UNK4C68 UNK4C70-UNK4C74 UNK5C65-UNK5C68 UNK5C70-UNK5C74 UNK6C65-UNK6C68 UNK6C70-UNK6C74 UNK7C65-UNK7C68 UNK7C70-UNK7C74 UNK8C65-UNK8C68 UNK8C70-UNK8C74 = 0.1U-25-X7R-S4-MU: User Part Number: PNXXXXXXXXXX; Tolerance: TOL
CT1 CT7 = 47U-16-X5R-SB-MU: User Part Number: PNXXXXXXXXXX; Tolerance: TOL
CT2 CT8 = 10U-16-X5R-S8-TY: User Part Number: PNXXXXXXXXXX; Tolerance: TOL
CT3 CT9 = 22U-16-X-S8-MU: User Part Number: PNXXXXXXXXXX; Tolerance: TOL
F1 F2 = C1F8-0.25A-SA: User Part Number: PNXXXXXXXXXX; Tolerance: TOL
FD1-FD16 TP_ATT_F TP_ATT_S TP_C1A_F TP_C1A_S TP_C1B_F TP_C1B_S TP_C2A_F TP_C2A_S TP_C2B_F TP_C2B_S TP_C3A_F TP_C3A_S TP_C3B_F TP_C3B_S TP_GA1_S TP_GA2_S TP_GB1_S TP_GB2_S TP_IN+_1-TP_IN+_4 TP_IN-_1-TP_IN-_4 TP_IS1N_F TP_IS1N_S TP_IS1P_F TP_IS2N_F TP_IS2N_S TP_IS2P_S TP_OPTO_F TP_OPTO_S TP_OUT+_1 TP_OUT+_2 TP_OUT-_1 TP_OUT-_2 TP_OUT_1 TP_OUT_2 TP_REF_1 TP_REF_2 TP_SCL_F TP_SDA_F TP_SDA_S TP_SRD_F TP_SRD_S TP_SRG_F TP_SRG_S TP_SRS_F TP_SRS_S TP_STB_F TP_STB_S TP_VCC_F TP_VCC_S TP_VDD0_F TP_VDD0_S TP_VDD1_S TP_VDD2_S TP_VDDI_F TP_VDDI_S TP_VIN_F TP_VIN_S TP_VO1_S TP_VO2_S TP_VSR_F TP_VSR_S UNK2TP_ATT_F UNK2TP_ATT_S UNK2TP_C1A_F UNK2TP_C1A_S UNK2TP_C1B_F UNK2TP_C1B_S UNK2TP_C2A_F UNK2TP_C2A_S UNK2TP_C2B_F UNK2TP_C2B_S UNK2TP_C3A_F UNK2TP_C3A_S UNK2TP_C3B_F UNK2TP_C3B_S UNK2TP_GA1_S UNK2TP_GA2_S UNK2TP_GB1_S UNK2TP_GB2_S UNK2TP_IN+_1-UNK2TP_IN+_4 UNK2TP_IN-_1-UNK2TP_IN-_4 UNK2TP_IS1N_F UNK2TP_IS1N_S UNK2TP_IS1P_F UNK2TP_IS2N_F UNK2TP_IS2N_S UNK2TP_IS2P_S UNK2TP_OPTO_F UNK2TP_OPTO_S UNK2TP_OUT+_1 UNK2TP_OUT+_2 UNK2TP_OUT-_1 UNK2TP_OUT-_2 UNK2TP_OUT_1 UNK2TP_OUT_2 UNK2TP_REF_1 UNK2TP_REF_2 UNK2TP_SCL_F UNK2TP_SDA_F UNK2TP_SDA_S UNK2TP_SRD_F UNK2TP_SRD_S UNK2TP_SRG_F UNK2TP_SRG_S UNK2TP_SRS_F UNK2TP_SRS_S UNK2TP_STB_F UNK2TP_STB_S UNK2TP_VCC_F UNK2TP_VCC_S UNK2TP_VDD0_F UNK2TP_VDD0_S UNK2TP_VDD1_S UNK2TP_VDD2_S UNK2TP_VDDI_F UNK2TP_VDDI_S UNK2TP_VIN_F UNK2TP_VIN_S UNK2TP_VO1_S UNK2TP_VO2_S UNK2TP_VSR_F UNK2TP_VSR_S UNK3TP_ATT_F UNK3TP_ATT_S UNK3TP_C1A_F UNK3TP_C1A_S UNK3TP_C1B_F UNK3TP_C1B_S UNK3TP_C2A_F UNK3TP_C2A_S UNK3TP_C2B_F UNK3TP_C2B_S UNK3TP_C3A_F UNK3TP_C3A_S UNK3TP_C3B_F UNK3TP_C3B_S UNK3TP_GA1_S UNK3TP_GA2_S UNK3TP_GB1_S UNK3TP_GB2_S UNK3TP_IN+_1-UNK3TP_IN+_4 UNK3TP_IN-_1-UNK3TP_IN-_4 UNK3TP_IS1N_F UNK3TP_IS1N_S UNK3TP_IS1P_F UNK3TP_IS2N_F UNK3TP_IS2N_S UNK3TP_IS2P_S UNK3TP_OPTO_F UNK3TP_OPTO_S UNK3TP_OUT+_1 UNK3TP_OUT+_2 UNK3TP_OUT-_1 UNK3TP_OUT-_2 UNK3TP_OUT_1 UNK3TP_OUT_2 UNK3TP_REF_1 UNK3TP_REF_2 UNK3TP_SCL_F UNK3TP_SDA_F UNK3TP_SDA_S UNK3TP_SRD_F UNK3TP_SRD_S UNK3TP_SRG_F UNK3TP_SRG_S UNK3TP_SRS_F UNK3TP_SRS_S UNK3TP_STB_F UNK3TP_STB_S UNK3TP_VCC_F UNK3TP_VCC_S UNK3TP_VDD0_F UNK3TP_VDD0_S UNK3TP_VDD1_S UNK3TP_VDD2_S UNK3TP_VDDI_F UNK3TP_VDDI_S UNK3TP_VIN_F UNK3TP_VIN_S UNK3TP_VO1_S UNK3TP_VO2_S UNK3TP_VSR_F UNK3TP_VSR_S UNK4TP_ATT_F UNK4TP_ATT_S UNK4TP_C1A_F UNK4TP_C1A_S UNK4TP_C1B_F UNK4TP_C1B_S UNK4TP_C2A_F UNK4TP_C2A_S UNK4TP_C2B_F UNK4TP_C2B_S UNK4TP_C3A_F UNK4TP_C3A_S UNK4TP_C3B_F UNK4TP_C3B_S UNK4TP_GA1_S UNK4TP_GA2_S UNK4TP_GB1_S UNK4TP_GB2_S UNK4TP_IN+_1-UNK4TP_IN+_4 UNK4TP_IN-_1-UNK4TP_IN-_4 UNK4TP_IS1N_F UNK4TP_IS1N_S UNK4TP_IS1P_F UNK4TP_IS2N_F UNK4TP_IS2N_S UNK4TP_IS2P_S UNK4TP_OPTO_F UNK4TP_OPTO_S UNK4TP_OUT+_1 UNK4TP_OUT+_2 UNK4TP_OUT-_1 UNK4TP_OUT-_2 UNK4TP_OUT_1 UNK4TP_OUT_2 UNK4TP_REF_1 UNK4TP_REF_2 UNK4TP_SCL_F UNK4TP_SDA_F UNK4TP_SDA_S UNK4TP_SRD_F UNK4TP_SRD_S UNK4TP_SRG_F UNK4TP_SRG_S UNK4TP_SRS_F UNK4TP_SRS_S UNK4TP_STB_F UNK4TP_STB_S UNK4TP_VCC_F UNK4TP_VCC_S UNK4TP_VDD0_F UNK4TP_VDD0_S UNK4TP_VDD1_S UNK4TP_VDD2_S UNK4TP_VDDI_F UNK4TP_VDDI_S UNK4TP_VIN_F UNK4TP_VIN_S UNK4TP_VO1_S UNK4TP_VO2_S UNK4TP_VSR_F UNK4TP_VSR_S UNK5TP_ATT_F UNK5TP_ATT_S UNK5TP_C1A_F UNK5TP_C1A_S UNK5TP_C1B_F UNK5TP_C1B_S UNK5TP_C2A_F UNK5TP_C2A_S UNK5TP_C2B_F UNK5TP_C2B_S UNK5TP_C3A_F UNK5TP_C3A_S UNK5TP_C3B_F UNK5TP_C3B_S UNK5TP_GA1_S UNK5TP_GA2_S UNK5TP_GB1_S UNK5TP_GB2_S UNK5TP_IN+_1-UNK5TP_IN+_4 UNK5TP_IN-_1-UNK5TP_IN-_4 UNK5TP_IS1N_F UNK5TP_IS1N_S UNK5TP_IS1P_F UNK5TP_IS2N_F UNK5TP_IS2N_S UNK5TP_IS2P_S UNK5TP_OPTO_F UNK5TP_OPTO_S UNK5TP_OUT+_1 UNK5TP_OUT+_2 UNK5TP_OUT-_1 UNK5TP_OUT-_2 UNK5TP_OUT_1 UNK5TP_OUT_2 UNK5TP_REF_1 UNK5TP_REF_2 UNK5TP_SCL_F UNK5TP_SDA_F UNK5TP_SDA_S UNK5TP_SRD_F UNK5TP_SRD_S UNK5TP_SRG_F UNK5TP_SRG_S UNK5TP_SRS_F UNK5TP_SRS_S UNK5TP_STB_F UNK5TP_STB_S UNK5TP_VCC_F UNK5TP_VCC_S UNK5TP_VDD0_F UNK5TP_VDD0_S UNK5TP_VDD1_S UNK5TP_VDD2_S UNK5TP_VDDI_F UNK5TP_VDDI_S UNK5TP_VIN_F UNK5TP_VIN_S UNK5TP_VO1_S UNK5TP_VO2_S UNK5TP_VSR_F UNK5TP_VSR_S UNK6TP_ATT_F UNK6TP_ATT_S UNK6TP_C1A_F UNK6TP_C1A_S UNK6TP_C1B_F UNK6TP_C1B_S UNK6TP_C2A_F UNK6TP_C2A_S UNK6TP_C2B_F UNK6TP_C2B_S UNK6TP_C3A_F UNK6TP_C3A_S UNK6TP_C3B_F UNK6TP_C3B_S UNK6TP_GA1_S UNK6TP_GA2_S UNK6TP_GB1_S UNK6TP_GB2_S UNK6TP_IN+_1-UNK6TP_IN+_4 UNK6TP_IN-_1-UNK6TP_IN-_4 UNK6TP_IS1N_F UNK6TP_IS1N_S UNK6TP_IS1P_F UNK6TP_IS2N_F UNK6TP_IS2N_S UNK6TP_IS2P_S UNK6TP_OPTO_F UNK6TP_OPTO_S UNK6TP_OUT+_1 UNK6TP_OUT+_2 UNK6TP_OUT-_1 UNK6TP_OUT-_2 UNK6TP_OUT_1 UNK6TP_OUT_2 UNK6TP_REF_1 UNK6TP_REF_2 UNK6TP_SCL_F UNK6TP_SDA_F UNK6TP_SDA_S UNK6TP_SRD_F UNK6TP_SRD_S UNK6TP_SRG_F UNK6TP_SRG_S UNK6TP_SRS_F UNK6TP_SRS_S UNK6TP_STB_F UNK6TP_STB_S UNK6TP_VCC_F UNK6TP_VCC_S UNK6TP_VDD0_F UNK6TP_VDD0_S UNK6TP_VDD1_S UNK6TP_VDD2_S UNK6TP_VDDI_F UNK6TP_VDDI_S UNK6TP_VIN_F UNK6TP_VIN_S UNK6TP_VO1_S UNK6TP_VO2_S UNK6TP_VSR_F UNK6TP_VSR_S UNK7TP_ATT_F UNK7TP_ATT_S UNK7TP_C1A_F UNK7TP_C1A_S UNK7TP_C1B_F UNK7TP_C1B_S UNK7TP_C2A_F UNK7TP_C2A_S UNK7TP_C2B_F UNK7TP_C2B_S UNK7TP_C3A_F UNK7TP_C3A_S UNK7TP_C3B_F UNK7TP_C3B_S UNK7TP_GA1_S UNK7TP_GA2_S UNK7TP_GB1_S UNK7TP_GB2_S UNK7TP_IN+_1-UNK7TP_IN+_4 UNK7TP_IN-_1-UNK7TP_IN-_4 UNK7TP_IS1N_F UNK7TP_IS1N_S UNK7TP_IS1P_F UNK7TP_IS2N_F UNK7TP_IS2N_S UNK7TP_IS2P_S UNK7TP_OPTO_F UNK7TP_OPTO_S UNK7TP_OUT+_1 UNK7TP_OUT+_2 UNK7TP_OUT-_1 UNK7TP_OUT-_2 UNK7TP_OUT_1 UNK7TP_OUT_2 UNK7TP_REF_1 UNK7TP_REF_2 UNK7TP_SCL_F UNK7TP_SDA_F UNK7TP_SDA_S UNK7TP_SRD_F UNK7TP_SRD_S UNK7TP_SRG_F UNK7TP_SRG_S UNK7TP_SRS_F UNK7TP_SRS_S UNK7TP_STB_F UNK7TP_STB_S UNK7TP_VCC_F UNK7TP_VCC_S UNK7TP_VDD0_F UNK7TP_VDD0_S UNK7TP_VDD1_S UNK7TP_VDD2_S UNK7TP_VDDI_F UNK7TP_VDDI_S UNK7TP_VIN_F UNK7TP_VIN_S UNK7TP_VO1_S UNK7TP_VO2_S UNK7TP_VSR_F UNK7TP_VSR_S UNK8TP_ATT_F UNK8TP_ATT_S UNK8TP_C1A_F UNK8TP_C1A_S UNK8TP_C1B_F UNK8TP_C1B_S UNK8TP_C2A_F UNK8TP_C2A_S UNK8TP_C2B_F UNK8TP_C2B_S UNK8TP_C3A_F UNK8TP_C3A_S UNK8TP_C3B_F UNK8TP_C3B_S UNK8TP_GA1_S UNK8TP_GA2_S UNK8TP_GB1_S UNK8TP_GB2_S UNK8TP_IN+_1-UNK8TP_IN+_4 UNK8TP_IN-_1-UNK8TP_IN-_4 UNK8TP_IS1N_F UNK8TP_IS1N_S UNK8TP_IS1P_F UNK8TP_IS2N_F UNK8TP_IS2N_S UNK8TP_IS2P_S UNK8TP_OPTO_F UNK8TP_OPTO_S UNK8TP_OUT+_1 UNK8TP_OUT+_2 UNK8TP_OUT-_1 UNK8TP_OUT-_2 UNK8TP_OUT_1 UNK8TP_OUT_2 UNK8TP_REF_1 UNK8TP_REF_2 UNK8TP_SCL_F UNK8TP_SDA_F UNK8TP_SDA_S UNK8TP_SRD_F UNK8TP_SRD_S UNK8TP_SRG_F UNK8TP_SRG_S UNK8TP_SRS_F UNK8TP_SRS_S UNK8TP_STB_F UNK8TP_STB_S UNK8TP_VCC_F UNK8TP_VCC_S UNK8TP_VDD0_F UNK8TP_VDD0_S UNK8TP_VDD1_S UNK8TP_VDD2_S UNK8TP_VDDI_F UNK8TP_VDDI_S UNK8TP_VIN_F UNK8TP_VIN_S UNK8TP_VO1_S UNK8TP_VO2_S UNK8TP_VSR_F UNK8TP_VSR_S = TP01: Tolerance: TOL; User Part Number: PNXXXXXXXXXX
K1 K15 K23 K24 UNK2K1 UNK2K15 UNK2K23 UNK2K24 UNK3K1 UNK3K15 UNK3K23 UNK3K24 UNK4K1 UNK4K15 UNK4K23 UNK4K24 UNK5K1 UNK5K15 UNK5K23 UNK5K24 UNK6K1 UNK6K15 UNK6K23 UNK6K24 UNK7K1 UNK7K15 UNK7K23 UNK7K24 UNK8K1 UNK8K15 UNK8K23 UNK8K24 = UA2-5NJ-A-V3: Tolerance: TOL; User Part Number: PNXXXXXXXXXX
K2-K4 K56 UNK2K2-UNK2K4 UNK2K56 UNK3K2-UNK3K4 UNK3K56 UNK4K2-UNK4K4 UNK4K56 UNK5K2-UNK5K4 UNK5K56 UNK6K2-UNK6K4 UNK6K56 UNK7K2-UNK7K4 UNK7K56 UNK8K2-UNK8K4 UNK8K56 = G3VM-201DR: Tolerance: TOL; User Part Number: PNXXXXXXXXXX
K5-K14 K16-K22 K25-K55 K57-K61 UNK2K5-UNK2K14 UNK2K16-UNK2K22 UNK2K25-UNK2K55 UNK2K57-UNK2K61 UNK3K5-UNK3K14 UNK3K16-UNK3K22 UNK3K25-UNK3K55 UNK3K57-UNK3K61 UNK4K5-UNK4K14 UNK4K16-UNK4K22 UNK4K25-UNK4K55 UNK4K57-UNK4K61 UNK5K5-UNK5K14 UNK5K16-UNK5K22 UNK5K25-UNK5K55 UNK5K57-UNK5K61 UNK6K5-UNK6K14 UNK6K16-UNK6K22 UNK6K25-UNK6K55 UNK6K57-UNK6K61 UNK7K5-UNK7K14 UNK7K16-UNK7K22 UNK7K25-UNK7K55 UNK7K57-UNK7K61 UNK8K5-UNK8K14 UNK8K16-UNK8K22 UNK8K25-UNK8K55 UNK8K57-UNK8K61 = G3VM-51UR-5V-VSON4: User Part Number: PNXXXXXXXXXX; Tolerance: TOL
LD1 LD3 = LDG-2-S6: Tolerance: TOL; User Part Number: PNXXXXXXXXXX
LT1 LT3 = L10U-16A-S16.5X15.5-PU: User Part Number: PNXXXXXXXXXX; Tolerance: TOL
M1 = PG_LTXDX_F_X1_OUTLINE_6042: User Part Number: PNXXXXXXXXXX; Tolerance: TOL
R1 UNK2R1 UNK3R1 UNK4R1 UNK5R1 UNK6R1 UNK7R1 UNK8R1 = 10K-0.1-S4: User Part Number: PNXXXXXXXXXX; Tolerance: TOL
R7 R8 UNK2R7 UNK2R8 UNK3R7 UNK3R8 UNK4R7 UNK4R8 UNK5R7 UNK5R8 UNK6R7 UNK6R8 UNK7R7 UNK7R8 UNK8R7 UNK8R8 = 4.7K-1-S4-WA: User Part Number: PNXXXXXXXXXX; Tolerance: TOL
R11 R14 UNK2R11 UNK2R14 UNK3R11 UNK3R14 UNK4R11 UNK4R14 UNK5R11 UNK5R14 UNK6R11 UNK6R14 UNK7R11 UNK7R14 UNK8R11 UNK8R14 = 5K-1-S4-YA: User Part Number: RC0402FR-07604RL; Tolerance: TOL
R15 R17 UNK2R15 UNK2R17 UNK3R15 UNK3R17 UNK4R15 UNK4R17 UNK5R15 UNK5R17 UNK6R15 UNK6R17 UNK7R15 UNK7R17 UNK8R15 UNK8R17 = 0-0-S2-KOA: User Part Number: PNXXXXXXXXXX; Tolerance: TOL
R16 R18 UNK2R16 UNK2R18 UNK3R16 UNK3R18 UNK4R16 UNK4R18 UNK5R16 UNK5R18 UNK6R16 UNK6R18 UNK7R16 UNK7R18 UNK8R16 UNK8R18 = 5.1-1-S2: User Part Number: PNXXXXXXXXXX; Tolerance: TOL
R19 R20 UNK2R19 UNK2R20 UNK3R19 UNK3R20 UNK4R19 UNK4R20 UNK5R19 UNK5R20 UNK6R19 UNK6R20 UNK7R19 UNK7R20 UNK8R19 UNK8R20 = 100K-0.1-S4-YA: User Part Number: PNXXXXXXXXXX; Tolerance: TOL
REF = -: User Part Number: PNXXXXXXXXXX; Tolerance: TOL
RK2-RK14 RK16-RK22 RK25-RK61 UNK2RK2-UNK2RK14 UNK2RK16-UNK2RK22 UNK2RK25-UNK2RK61 UNK3RK2-UNK3RK14 UNK3RK16-UNK3RK22 UNK3RK25-UNK3RK61 UNK4RK2-UNK4RK14 UNK4RK16-UNK4RK22 UNK4RK25-UNK4RK61 UNK5RK2-UNK5RK14 UNK5RK16-UNK5RK22 UNK5RK25-UNK5RK61 UNK6RK2-UNK6RK14 UNK6RK16-UNK6RK22 UNK6RK25-UNK6RK61 UNK7RK2-UNK7RK14 UNK7RK16-UNK7RK22 UNK7RK25-UNK7RK61 UNK8RK2-UNK8RK14 UNK8RK16-UNK8RK22 UNK8RK25-UNK8RK61 = 619-1-S4: User Part Number: PNXXXXXXXXXX; Tolerance: TOL
RT1 RT2 = 330-1-S6: User Part Number: PNXXXXXXXXXX; Tolerance: TOL
SH1-SH4 SHORT1-SHORT4 SHORT6-SHORT11 ST1 ST2 UNK0BS1 UNK0BS2 UNK1SH1-UNK1SH27 UNK2SH1-UNK2SH27 UNK2SHORT1-UNK2SHORT4 UNK2SHORT6-UNK2SHORT11 UNK3SH1-UNK3SH27 UNK3SHORT1-UNK3SHORT4 UNK3SHORT6-UNK3SHORT11 UNK4SH1-UNK4SH27 UNK4SHORT1-UNK4SHORT4 UNK4SHORT6-UNK4SHORT11 UNK5SH1-UNK5SH27 UNK5SHORT1-UNK5SHORT4 UNK5SHORT6-UNK5SHORT11 UNK6SH1-UNK6SH27 UNK6SHORT1-UNK6SHORT4 UNK6SHORT6-UNK6SHORT11 UNK7SH1-UNK7SH27 UNK7SHORT1-UNK7SHORT4 UNK7SHORT6-UNK7SHORT11 UNK8SH1-UNK8SH27 UNK8SHORT1-UNK8SHORT4 UNK8SHORT6-UNK8SHORT11 = SHORT: User Part Number: PNXXXXXXXXXX; Tolerance: TOL
SITE1-SITE8 = CU/260817-QFN32-5X5: Tolerance: TOL; User Part Number: PNXXXXXXXXXX
SLOT0 SLOT03 SLOT07 SLOT11 SLOT12 = DIAMONDX_X1_DUT_1: Tolerance: TOL; User Part Number: PNXXXXXXXXXX
SLOT01 SLOT02 SLOT17 SLOT18 = VI100_SL01: Tolerance: TOL; User Part Number: PNXXXXXXXXXX
SLOT04 SLOT08 SLOT15 SLOT16 SLOT19 = DIAMONDX_X1_DUT_1: User Part Number: PNXXXXXXXXXX; Tolerance: TOL
SLOT05 SLOT14 = DIAMONDX_SLOT8_PMVIX: Tolerance: TOL; User Part Number: PNXXXXXXXXXX
SLOT06 SLOT13 = DIAMONDX_SLOT17_GX1X: Tolerance: TOL; User Part Number: PNXXXXXXXXXX
SLOT09 = FPVI_SL09: Tolerance: TOL; User Part Number: PNXXXXXXXXXX
SLOT10 = FPVI_SL10: Tolerance: TOL; User Part Number: PNXXXXXXXXXX
STIRLING = REF-CODE-CHIP
TP_SDUP5V_FILTER TP_SDUR5V_FILTER = TP03-D: Tolerance: TOL; User Part Number: PNXXXXXXXXXX
U1 U2 UNK2U1 UNK2U2 UNK3U1 UNK3U2 UNK4U1 UNK4U2 UNK5U1 UNK5U2 UNK6U1 UNK6U2 UNK7U1 UNK7U2 UNK8U1 UNK8U2 = TLV3604DCKR-SC70: User Part Number: PNXXXXXXXXXX; Tolerance: TOL
U3 U4 UNK2U3 UNK2U4 UNK3U3 UNK3U4 UNK4U3 UNK4U4 UNK5U3 UNK5U4 UNK6U3 UNK6U4 UNK7U3 UNK7U4 UNK8U3 UNK8U4 = INA186A3QDDFRQ1-SOT23-8: Tolerance: TOL; User Part Number: PNXXXXXXXXXX
UNK038K2-26081712Q-A100 UNK980K2-260817-1A4- = REF-CODE-PCB

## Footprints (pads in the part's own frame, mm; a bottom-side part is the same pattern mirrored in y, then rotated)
C0402
  custom 0.15x0.15 smd: 1(-0.5,0) 2(0.5,0)
C0603
  rect 0.889x0.889 smd: 1(-0.85,0) 2(0.85,0)
C0805
  rect 1.118x1.372 smd: 1(-0.95,0) 2(0.95,0)
C1210
  rect 1.27x2.794 smd: 1(-1.524,0) 2(1.524,0)
CHIP_CODE
  round 0.051 smd: 1(0,0)
DEFAULT_SHORT_SMALL
  custom 0.07x0.07 smd: 1(-0.5,0) 2(0.5,0)
FD_040_V2
  round 1.016 smd: 1(0,0)
FUSE_1206_H1P05MM
  rect 1.3x1.8 smd: 1(-1.55,0) 2(1.55,0)
IND_16P5X15P5MM
  rect 4.5x15 smd: 1(-5.25,0) 2(5.25,0)
LED_0603
  rect 0.8x0.8 smd: 1(0.749,0) 2(-0.749,0)
PCB_CODE
  round 0.051 smd: 1(0,0)
PG_LTXDX_F_X1_FPVI_SL09_V3
  round 0.508 hole 3.2 unplated: (-13.054,154.842)
  round 0.051 hole 2.489x2.21 unplated: (-12.055,220.342)
  rect 1.016x1.016 hole 0.559: A1(-17.684,218.796)
  round 1.016 hole 0.559: A2(-18.809,217.796) A3(-17.684,216.796) A4(-18.809,215.796) A5(-17.684,214.796) A6(-18.809,213.796) A7(-17.684,212.796) A8(-18.809,211.796) A9(-17.684,210.796) A10(-18.809,209.796) A11(-17.684,208.796) A12(-18.809,207.796) A13(-17.684,206.796) A14(-18.809,205.796) A15(-17.684,204.796) A16(-18.809,203.796) A17(-17.684,202.796) A18(-18.809,201.796) A19(-17.684,200.796) A20(-18.809,199.796) A21(-17.684,198.796) A22(-18.809,197.796) A23(-17.684,196.796) A24(-18.809,195.796) A25(-17.684,194.796) A26(-18.809,193.796) A27(-17.684,192.796) A28(-18.809,191.796) A29(-17.684,190.796) A30(-18.809,189.796) A31(-17.684,188.796) A32(-18.809,187.796) A33(-17.684,186.796) A34(-18.809,185.796) A35(-17.684,184.796) A36(-18.809,183.796) A37(-17.684,182.796) A38(-18.809,181.796) A39(-17.684,180.796) A40(-18.809,179.796) A41(-17.684,178.796) A42(-18.809,177.796) A43(-17.684,176.796) A44(-18.809,175.796) A45(-17.684,174.796) A46(-18.809,173.796) A47(-17.684,172.796) A48(-18.809,171.796) A49(-17.684,170.796) A50(-18.809,169.796) A51(-17.684,168.796) A52(-18.809,167.796) A53(-17.684,166.796) A54(-18.809,165.796) A55(-17.684,164.796) A56(-18.809,163.796) A57(-17.684,162.796) A58(-18.809,161.796) A59(-17.684,160.796) A60(-18.809,159.796) A61(-17.684,158.796) B1(-15.435,218.796) B2(-16.56,217.796) B3(-15.435,216.796) B4(-16.56,215.796) B5(-15.435,214.796) B6(-16.56,213.796) B7(-15.435,212.796) B8(-16.56,211.796) B9(-15.435,210.796) B10(-16.56,209.796) B11(-15.435,208.796) B12(-16.56,207.796) B13(-15.435,206.796) B14(-16.56,205.796) B15(-15.435,204.796) B16(-16.56,203.796) B17(-15.435,202.796) B18(-16.56,201.796) B19(-15.435,200.796) B20(-16.56,199.796) B21(-15.435,198.796) B22(-16.56,197.796) B23(-15.435,196.796) B24(-16.56,195.796) B25(-15.435,194.796) B26(-16.56,193.796) B27(-15.435,192.796) B28(-16.56,191.796) B29(-15.435,190.796) B30(-16.56,189.796) B31(-15.435,188.796) B32(-16.56,187.796) B33(-15.435,186.796) B34(-16.56,185.796) B35(-15.435,184.796) B36(-16.56,183.796) B37(-15.435,182.796) B38(-16.56,181.796) B39(-15.435,180.796) B40(-16.56,179.796) B41(-15.435,178.796) B42(-16.56,177.796) B43(-15.435,176.796) B44(-16.56,175.796) B45(-15.435,174.796) B46(-16.56,173.796) B47(-15.435,172.796) B48(-16.56,171.796) B49(-15.435,170.796) B50(-16.56,169.796) B51(-15.435,168.796) B52(-16.56,167.796) B53(-15.435,166.796) B54(-16.56,165.796) B55(-15.435,164.796) B56(-16.56,163.796) B57(-15.435,162.796) B58(-16.56,161.796) B59(-15.435,160.796) B60(-16.56,159.796) B61(-15.435,158.796) B62(-16.56,157.796) C1(-13.184,218.796) C2(-14.31,217.796) C3(-13.184,216.796) C4(-14.31,215.796) C5(-13.184,214.796) C6(-14.31,213.796) C7(-13.184,212.796) C8(-14.31,211.796) C9(-13.184,210.796) C10(-14.31,209.796) C11(-13.184,208.796) C12(-14.31,207.796) C13(-13.184,206.796) C14(-14.31,205.796) C15(-13.184,204.796) C16(-14.31,203.796) C17(-13.184,202.796) C18(-14.31,201.796) C19(-13.184,200.796) C20(-14.31,199.796) C21(-13.184,198.796) C22(-14.31,197.796) C23(-13.184,196.796) C24(-14.31,195.796) C25(-13.184,194.796) C26(-14.31,193.796) C27(-13.184,192.796) C28(-14.31,191.796) C29(-13.184,190.796) C30(-14.31,189.796) C31(-13.184,188.796) C32(-14.31,187.796) C33(-13.184,186.796) C34(-14.31,185.796) C35(-13.184,184.796) C36(-14.31,183.796) C37(-13.184,182.796) C38(-14.31,181.796) C39(-13.184,180.796) C40(-14.31,179.796) C41(-13.184,178.796) C42(-14.31,177.796) C43(-13.184,176.796) C44(-14.31,175.796) C45(-13.184,174.796) C46(-14.31,173.796) C47(-13.184,172.796) C48(-14.31,171.796) C49(-13.184,170.796) C50(-14.31,169.796) C51(-13.184,168.796) C52(-14.31,167.796) C53(-13.184,166.796) C54(-14.31,165.796) C55(-13.184,164.796) C56(-14.31,163.796) C57(-13.184,162.796) C58(-14.31,161.796) C59(-13.184,160.796) C60(-14.31,159.796) C61(-13.184,158.796) C62(-14.31,157.796) D1(-10.934,218.796) D2(-12.059,217.796) D3(-10.934,216.796) D4(-12.059,215.796) D5(-10.934,214.796) D6(-12.059,213.796) D7(-10.934,212.796) D8(-12.059,211.796) D9(-10.934,210.796) D10(-12.059,209.796) D11(-10.934,208.796) D12(-12.059,207.796) D13(-10.934,206.796) D14(-12.059,205.796) D15(-10.934,204.796) D16(-12.059,203.796) D17(-10.934,202.796) D18(-12.059,201.796) D19(-10.934,200.796) D20(-12.059,199.796) D21(-10.934,198.796) D22(-12.059,197.796) D23(-10.934,196.796) D24(-12.059,195.796) D25(-10.934,194.796) D26(-12.059,193.796) D27(-10.934,192.796) D28(-12.059,191.796) D29(-10.934,190.796) D30(-12.059,189.796) D31(-10.934,188.796) D32(-12.059,187.796) D33(-10.934,186.796) D34(-12.059,185.796) D35(-10.934,184.796) D36(-12.059,183.796) D37(-10.934,182.796) D38(-12.059,181.796) D39(-10.934,180.796) D40(-12.059,179.796) D41(-10.934,178.796) D42(-12.059,177.796) D43(-10.934,176.796) D44(-12.059,175.796) D45(-10.934,174.796) D46(-12.059,173.796) D47(-10.934,172.796) D48(-12.059,171.796) D49(-10.934,170.796) D50(-12.059,169.796) D51(-10.934,168.796) D52(-12.059,167.796) D53(-10.934,166.796) D54(-12.059,165.796) D55(-10.934,164.796) D56(-12.059,163.796) D57(-10.934,162.796) D58(-12.059,161.796) D59(-10.934,160.796) D60(-12.059,159.796) D61(-10.934,158.796) E1(-8.685,218.796) E2(-9.809,217.796) E3(-8.685,216.796) E4(-9.809,215.796) E5(-8.685,214.796) E6(-9.809,213.796) E7(-8.685,212.796) E8(-9.809,211.796) E9(-8.685,210.796) E10(-9.809,209.796) E11(-8.685,208.796) E12(-9.809,207.796) E13(-8.685,206.796) E14(-9.809,205.796) E15(-8.685,204.796) E16(-9.809,203.796) E17(-8.685,202.796) E18(-9.809,201.796) E19(-8.685,200.796) E20(-9.809,199.796) E21(-8.685,198.796) E22(-9.809,197.796) E23(-8.685,196.796) E24(-9.809,195.796) E25(-8.685,194.796) E26(-9.809,193.796) E27(-8.685,192.796) E28(-9.809,191.796) E29(-8.685,190.796) E30(-9.809,189.796) E31(-8.685,188.796) E32(-9.809,187.796) E33(-8.685,186.796) E34(-9.809,185.796) E35(-8.685,184.796) E36(-9.809,183.796) E37(-8.685,182.796) E38(-9.809,181.796) E39(-8.685,180.796) E40(-9.809,179.796) E41(-8.685,178.796) E42(-9.809,177.796) E43(-8.685,176.796) E44(-9.809,175.796) E45(-8.685,174.796) E46(-9.809,173.796) E47(-8.685,172.796) E48(-9.809,171.796) E49(-8.685,170.796) E50(-9.809,169.796) E51(-8.685,168.796) E52(-9.809,167.796) E53(-8.685,166.796) E54(-9.809,165.796) E55(-8.685,164.796) E56(-9.809,163.796) E57(-8.685,162.796) E58(-9.809,161.796) E59(-8.685,160.796) E60(-9.809,159.796) E61(-8.685,158.796) E62(-9.809,157.796) F1(-6.435,218.796) F2(-7.56,217.796) F3(-6.435,216.796) F4(-7.56,215.796) F5(-6.435,214.796) F6(-7.56,213.796) F7(-6.435,212.796) F8(-7.56,211.796) F9(-6.435,210.796) F10(-7.56,209.796) F11(-6.435,208.796) F12(-7.56,207.796) F13(-6.435,206.796) F14(-7.56,205.796) F15(-6.435,204.796) F16(-7.56,203.796) F17(-6.435,202.796) F18(-7.56,201.796) F19(-6.435,200.796) F20(-7.56,199.796) F21(-6.435,198.796) F22(-7.56,197.796) F23(-6.435,196.796) F24(-7.56,195.796) F25(-6.435,194.796) F26(-7.56,193.796) F27(-6.435,192.796) F28(-7.56,191.796) F29(-6.435,190.796) F30(-7.56,189.796) F31(-6.435,188.796) F32(-7.56,187.796) F33(-6.435,186.796) F34(-7.56,185.796) F35(-6.435,184.796) F36(-7.56,183.796) F37(-6.435,182.796) F38(-7.56,181.796) F39(-6.435,180.796) F40(-7.56,179.796) F41(-6.435,178.796) F42(-7.56,177.796) F43(-6.435,176.796) F44(-7.56,175.796) F45(-6.435,174.796) F46(-7.56,173.796) F47(-6.435,172.796) F48(-7.56,171.796) F49(-6.435,170.796) F50(-7.56,169.796) F51(-6.435,168.796) F52(-7.56,167.796) F53(-6.435,166.796) F54(-7.56,165.796) F55(-6.435,164.796) F56(-7.56,163.796) F57(-6.435,162.796) F58(-7.56,161.796) F59(-6.435,160.796) F60(-7.56,159.796) F61(-6.435,158.796) F62(-7.56,157.796) G2(-5.31,217.796) G4(-5.31,215.796) G6(-5.31,213.796) G8(-5.31,211.796) G10(-5.31,209.796) G12(-5.31,207.796) G14(-5.31,205.796) G16(-5.31,203.796) G18(-5.31,201.796) G20(-5.31,199.796) G22(-5.31,197.796) G24(-5.31,195.796) G26(-5.31,193.796) G28(-5.31,191.796) G30(-5.31,189.796) G32(-5.31,187.796) G34(-5.31,185.796) G36(-5.31,183.796) G38(-5.31,181.796) G40(-5.31,179.796) G42(-5.31,177.796) G44(-5.31,175.796) G46(-5.31,173.796) G48(-5.31,171.796) G50(-5.31,169.796) G52(-5.31,167.796) G54(-5.31,165.796) G56(-5.31,163.796) G58(-5.31,161.796) G60(-5.31,159.796)
  custom 0.257x0.257 smd: Z5(-19.934,214.796) Z7(-19.934,212.796) Z9(-19.934,210.796) Z11(-19.934,208.796) Z13(-19.934,206.796) Z15(-19.934,204.796) Z17(-19.934,202.796) Z19(-19.934,200.796) Z21(-19.934,198.796) Z23(-19.934,196.796) Z25(-19.934,194.796) Z27(-19.934,192.796) Z29(-19.934,190.796) Z31(-19.934,188.796) Z33(-19.934,186.796) Z35(-19.934,184.796) Z37(-19.934,182.796) Z39(-19.934,180.796) Z41(-19.934,178.796) Z43(-19.934,176.796) Z45(-19.934,174.796) Z47(-19.934,172.796) Z49(-19.934,170.796) Z51(-19.934,168.796) Z53(-19.934,166.796) Z55(-19.934,164.796) Z57(-19.934,162.796) Z59(-19.934,160.796) Z61(-19.934,158.796)
PG_LTXDX_F_X1_FPVI_SL10_V3
  round 0.051 hole 2.489x2.21 unplated: (12.055,-220.342)
  round 0.508 hole 3.2 unplated: (13.054,-154.842)
  rect 1.016x1.016 hole 0.559: A1(17.684,-218.796)
  round 1.016 hole 0.559: A2(18.809,-217.796) A3(17.684,-216.796) A4(18.809,-215.796) A5(17.684,-214.796) A6(18.809,-213.796) A7(17.684,-212.796) A8(18.809,-211.796) A9(17.684,-210.796) A10(18.809,-209.796) A11(17.684,-208.796) A12(18.809,-207.796) A13(17.684,-206.796) A14(18.809,-205.796) A15(17.684,-204.796) A16(18.809,-203.796) A17(17.684,-202.796) A18(18.809,-201.796) A19(17.684,-200.796) A20(18.809,-199.796) A21(17.684,-198.796) A22(18.809,-197.796) A23(17.684,-196.796) A24(18.809,-195.796) A25(17.684,-194.796) A26(18.809,-193.796) A27(17.684,-192.796) A28(18.809,-191.796) A29(17.684,-190.796) A30(18.809,-189.796) A31(17.684,-188.796) A32(18.809,-187.796) A33(17.684,-186.796) A34(18.809,-185.796) A35(17.684,-184.796) A36(18.809,-183.796) A37(17.684,-182.796) A38(18.809,-181.796) A39(17.684,-180.796) A40(18.809,-179.796) A41(17.684,-178.796) A42(18.809,-177.796) A43(17.684,-176.796) A44(18.809,-175.796) A45(17.684,-174.796) A46(18.809,-173.796) A47(17.684,-172.796) A48(18.809,-171.796) A49(17.684,-170.796) A50(18.809,-169.796) A51(17.684,-168.796) A52(18.809,-167.796) A53(17.684,-166.796) A54(18.809,-165.796) A55(17.684,-164.796) A56(18.809,-163.796) A57(17.684,-162.796) A58(18.809,-161.796) A59(17.684,-160.796) A60(18.809,-159.796) A61(17.684,-158.796) B1(15.435,-218.796) B2(16.56,-217.796) B3(15.435,-216.796) B4(16.56,-215.796) B5(15.435,-214.796) B6(16.56,-213.796) B7(15.435,-212.796) B8(16.56,-211.796) B9(15.435,-210.796) B10(16.56,-209.796) B11(15.435,-208.796) B12(16.56,-207.796) B13(15.435,-206.796) B14(16.56,-205.796) B15(15.435,-204.796) B16(16.56,-203.796) B17(15.435,-202.796) B18(16.56,-201.796) B19(15.435,-200.796) B20(16.56,-199.796) B21(15.435,-198.796) B22(16.56,-197.796) B23(15.435,-196.796) B24(16.56,-195.796) B25(15.435,-194.796) B26(16.56,-193.796) B27(15.435,-192.796) B28(16.56,-191.796) B29(15.435,-190.796) B30(16.56,-189.796) B31(15.435,-188.796) B32(16.56,-187.796) B33(15.435,-186.796) B34(16.56,-185.796) B35(15.435,-184.796) B36(16.56,-183.796) B37(15.435,-182.796) B38(16.56,-181.796) B39(15.435,-180.796) B40(16.56,-179.796) B41(15.435,-178.796) B42(16.56,-177.796) B43(15.435,-176.796) B44(16.56,-175.796) B45(15.435,-174.796) B46(16.56,-173.796) B47(15.435,-172.796) B48(16.56,-171.796) B49(15.435,-170.796) B50(16.56,-169.796) B51(15.435,-168.796) B52(16.56,-167.796) B53(15.435,-166.796) B54(16.56,-165.796) B55(15.435,-164.796) B56(16.56,-163.796) B57(15.435,-162.796) B58(16.56,-161.796) B59(15.435,-160.796) B60(16.56,-159.796) B61(15.435,-158.796) B62(16.56,-157.796) C1(13.184,-218.796) C2(14.31,-217.796) C3(13.184,-216.796) C4(14.31,-215.796) C5(13.184,-214.796) C6(14.31,-213.796) C7(13.184,-212.796) C8(14.31,-211.796) C9(13.184,-210.796) C10(14.31,-209.796) C11(13.184,-208.796) C12(14.31,-207.796) C13(13.184,-206.796) C14(14.31,-205.796) C15(13.184,-204.796) C16(14.31,-203.796) C17(13.184,-202.796) C18(14.31,-201.796) C19(13.184,-200.796) C20(14.31,-199.796) C21(13.184,-198.796) C22(14.31,-197.796) C23(13.184,-196.796) C24(14.31,-195.796) C25(13.184,-194.796) C26(14.31,-193.796) C27(13.184,-192.796) C28(14.31,-191.796) C29(13.184,-190.796) C30(14.31,-189.796) C31(13.184,-188.796) C32(14.31,-187.796) C33(13.184,-186.796) C34(14.31,-185.796) C35(13.184,-184.796) C36(14.31,-183.796) C37(13.184,-182.796) C38(14.31,-181.796) C39(13.184,-180.796) C40(14.31,-179.796) C41(13.184,-178.796) C42(14.31,-177.796) C43(13.184,-176.796) C44(14.31,-175.796) C45(13.184,-174.796) C46(14.31,-173.796) C47(13.184,-172.796) C48(14.31,-171.796) C49(13.184,-170.796) C50(14.31,-169.796) C51(13.184,-168.796) C52(14.31,-167.796) C53(13.184,-166.796) C54(14.31,-165.796) C55(13.184,-164.796) C56(14.31,-163.796) C57(13.184,-162.796) C58(14.31,-161.796) C59(13.184,-160.796) C60(14.31,-159.796) C61(13.184,-158.796) C62(14.31,-157.796) D1(10.934,-218.796) D2(12.059,-217.796) D3(10.934,-216.796) D4(12.059,-215.796) D5(10.934,-214.796) D6(12.059,-213.796) D7(10.934,-212.796) D8(12.059,-211.796) D9(10.934,-210.796) D10(12.059,-209.796) D11(10.934,-208.796) D12(12.059,-207.796) D13(10.934,-206.796) D14(12.059,-205.796) D15(10.934,-204.796) D16(12.059,-203.796) D17(10.934,-202.796) D18(12.059,-201.796) D19(10.934,-200.796) D20(12.059,-199.796) D21(10.934,-198.796) D22(12.059,-197.796) D23(10.934,-196.796) D24(12.059,-195.796) D25(10.934,-194.796) D26(12.059,-193.796) D27(10.934,-192.796) D28(12.059,-191.796) D29(10.934,-190.796) D30(12.059,-189.796) D31(10.934,-188.796) D32(12.059,-187.796) D33(10.934,-186.796) D34(12.059,-185.796) D35(10.934,-184.796) D36(12.059,-183.796) D37(10.934,-182.796) D38(12.059,-181.796) D39(10.934,-180.796) D40(12.059,-179.796) D41(10.934,-178.796) D42(12.059,-177.796) D43(10.934,-176.796) D44(12.059,-175.796) D45(10.934,-174.796) D46(12.059,-173.796) D47(10.934,-172.796) D48(12.059,-171.796) D49(10.934,-170.796) D50(12.059,-169.796) D51(10.934,-168.796) D52(12.059,-167.796) D53(10.934,-166.796) D54(12.059,-165.796) D55(10.934,-164.796) D56(12.059,-163.796) D57(10.934,-162.796) D58(12.059,-161.796) D59(10.934,-160.796) D60(12.059,-159.796) D61(10.934,-158.796) E1(8.685,-218.796) E2(9.809,-217.796) E3(8.685,-216.796) E4(9.809,-215.796) E5(8.685,-214.796) E6(9.809,-213.796) E7(8.685,-212.796) E8(9.809,-211.796) E9(8.685,-210.796) E10(9.809,-209.796) E11(8.685,-208.796) E12(9.809,-207.796) E13(8.685,-206.796) E14(9.809,-205.796) E15(8.685,-204.796) E16(9.809,-203.796) E17(8.685,-202.796) E18(9.809,-201.796) E19(8.685,-200.796) E20(9.809,-199.796) E21(8.685,-198.796) E22(9.809,-197.796) E23(8.685,-196.796) E24(9.809,-195.796) E25(8.685,-194.796) E26(9.809,-193.796) E27(8.685,-192.796) E28(9.809,-191.796) E29(8.685,-190.796) E30(9.809,-189.796) E31(8.685,-188.796) E32(9.809,-187.796) E33(8.685,-186.796) E34(9.809,-185.796) E35(8.685,-184.796) E36(9.809,-183.796) E37(8.685,-182.796) E38(9.809,-181.796) E39(8.685,-180.796) E40(9.809,-179.796) E41(8.685,-178.796) E42(9.809,-177.796) E43(8.685,-176.796) E44(9.809,-175.796) E45(8.685,-174.796) E46(9.809,-173.796) E47(8.685,-172.796) E48(9.809,-171.796) E49(8.685,-170.796) E50(9.809,-169.796) E51(8.685,-168.796) E52(9.809,-167.796) E53(8.685,-166.796) E54(9.809,-165.796) E55(8.685,-164.796) E56(9.809,-163.796) E57(8.685,-162.796) E58(9.809,-161.796) E59(8.685,-160.796) E60(9.809,-159.796) E61(8.685,-158.796) E62(9.809,-157.796) F1(6.435,-218.796) F2(7.56,-217.796) F3(6.435,-216.796) F4(7.56,-215.796) F5(6.435,-214.796) F6(7.56,-213.796) F7(6.435,-212.796) F8(7.56,-211.796) F9(6.435,-210.796) F10(7.56,-209.796) F11(6.435,-208.796) F12(7.56,-207.796) F13(6.435,-206.796) F14(7.56,-205.796) F15(6.435,-204.796) F16(7.56,-203.796) F17(6.435,-202.796) F18(7.56,-201.796) F19(6.435,-200.796) F20(7.56,-199.796) F21(6.435,-198.796) F22(7.56,-197.796) F23(6.435,-196.796) F24(7.56,-195.796) F25(6.435,-194.796) F26(7.56,-193.796) F27(6.435,-192.796) F28(7.56,-191.796) F29(6.435,-190.796) F30(7.56,-189.796) F31(6.435,-188.796) F32(7.56,-187.796) F33(6.435,-186.796) F34(7.56,-185.796) F35(6.435,-184.796) F36(7.56,-183.796) F37(6.435,-182.796) F38(7.56,-181.796) F39(6.435,-180.796) F40(7.56,-179.796) F41(6.435,-178.796) F42(7.56,-177.796) F43(6.435,-176.796) F44(7.56,-175.796) F45(6.435,-174.796) F46(7.56,-173.796) F47(6.435,-172.796) F48(7.56,-171.796) F49(6.435,-170.796) F50(7.56,-169.796) F51(6.435,-168.796) F52(7.56,-167.796) F53(6.435,-166.796) F54(7.56,-165.796) F55(6.435,-164.796) F56(7.56,-163.796) F57(6.435,-162.796) F58(7.56,-161.796) F59(6.435,-160.796) F60(7.56,-159.796) F61(6.435,-158.796) F62(7.56,-157.796) G2(5.31,-217.796) G4(5.31,-215.796) G6(5.31,-213.796) G8(5.31,-211.796) G10(5.31,-209.796) G12(5.31,-207.796) G14(5.31,-205.796) G16(5.31,-203.796) G18(5.31,-201.796) G20(5.31,-199.796) G22(5.31,-197.796) G24(5.31,-195.796) G26(5.31,-193.796) G28(5.31,-191.796) G30(5.31,-189.796) G32(5.31,-187.796) G34(5.31,-185.796) G36(5.31,-183.796) G38(5.31,-181.796) G40(5.31,-179.796) G42(5.31,-177.796) G44(5.31,-175.796) G46(5.31,-173.796) G48(5.31,-171.796) G50(5.31,-169.796) G52(5.31,-167.796) G54(5.31,-165.796) G56(5.31,-163.796) G58(5.31,-161.796) G60(5.31,-159.796)
  custom 0.257x0.257 smd: Z5(19.934,-214.796) Z7(19.934,-212.796) Z9(19.934,-210.796) Z11(19.934,-208.796) Z13(19.934,-206.796) Z15(19.934,-204.796) Z17(19.934,-202.796) Z19(19.934,-200.796) Z21(19.934,-198.796) Z23(19.934,-196.796) Z25(19.934,-194.796) Z27(19.934,-192.796) Z29(19.934,-190.796) Z31(19.934,-188.796) Z33(19.934,-186.796) Z35(19.934,-184.796) Z37(19.934,-182.796) Z39(19.934,-180.796) Z41(19.934,-178.796) Z43(19.934,-176.796) Z45(19.934,-174.796) Z47(19.934,-172.796) Z49(19.934,-170.796) Z51(19.934,-168.796) Z53(19.934,-166.796) Z55(19.934,-164.796) Z57(19.934,-162.796) Z59(19.934,-160.796) Z61(19.934,-158.796)
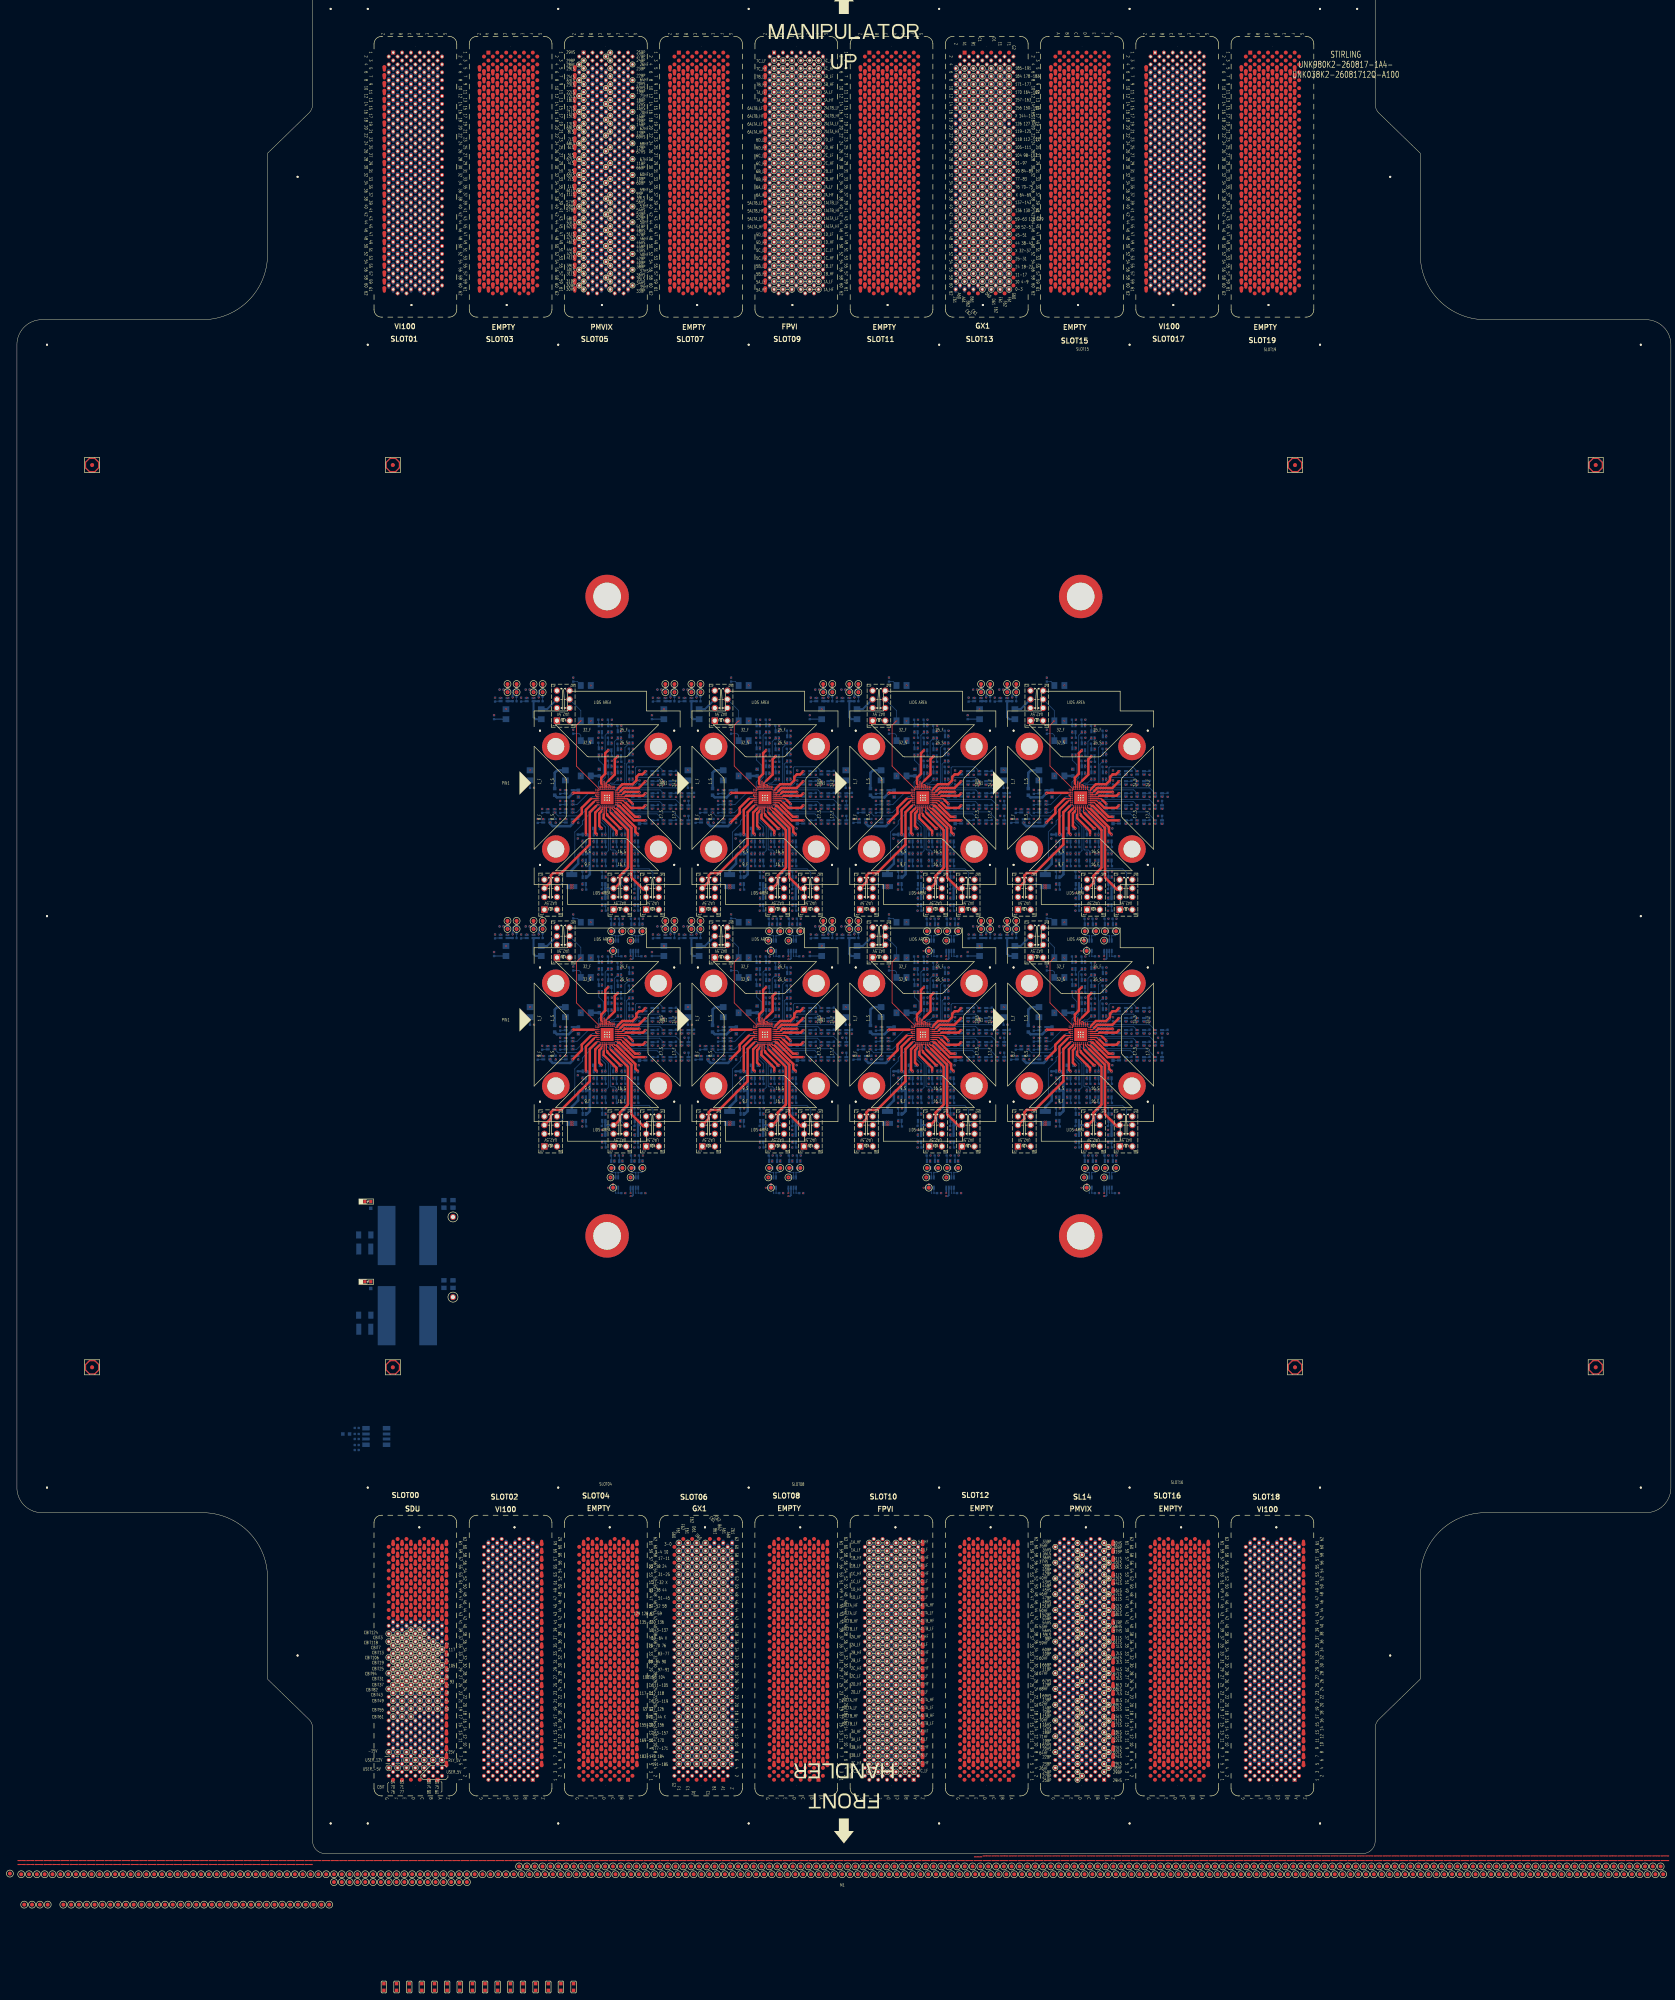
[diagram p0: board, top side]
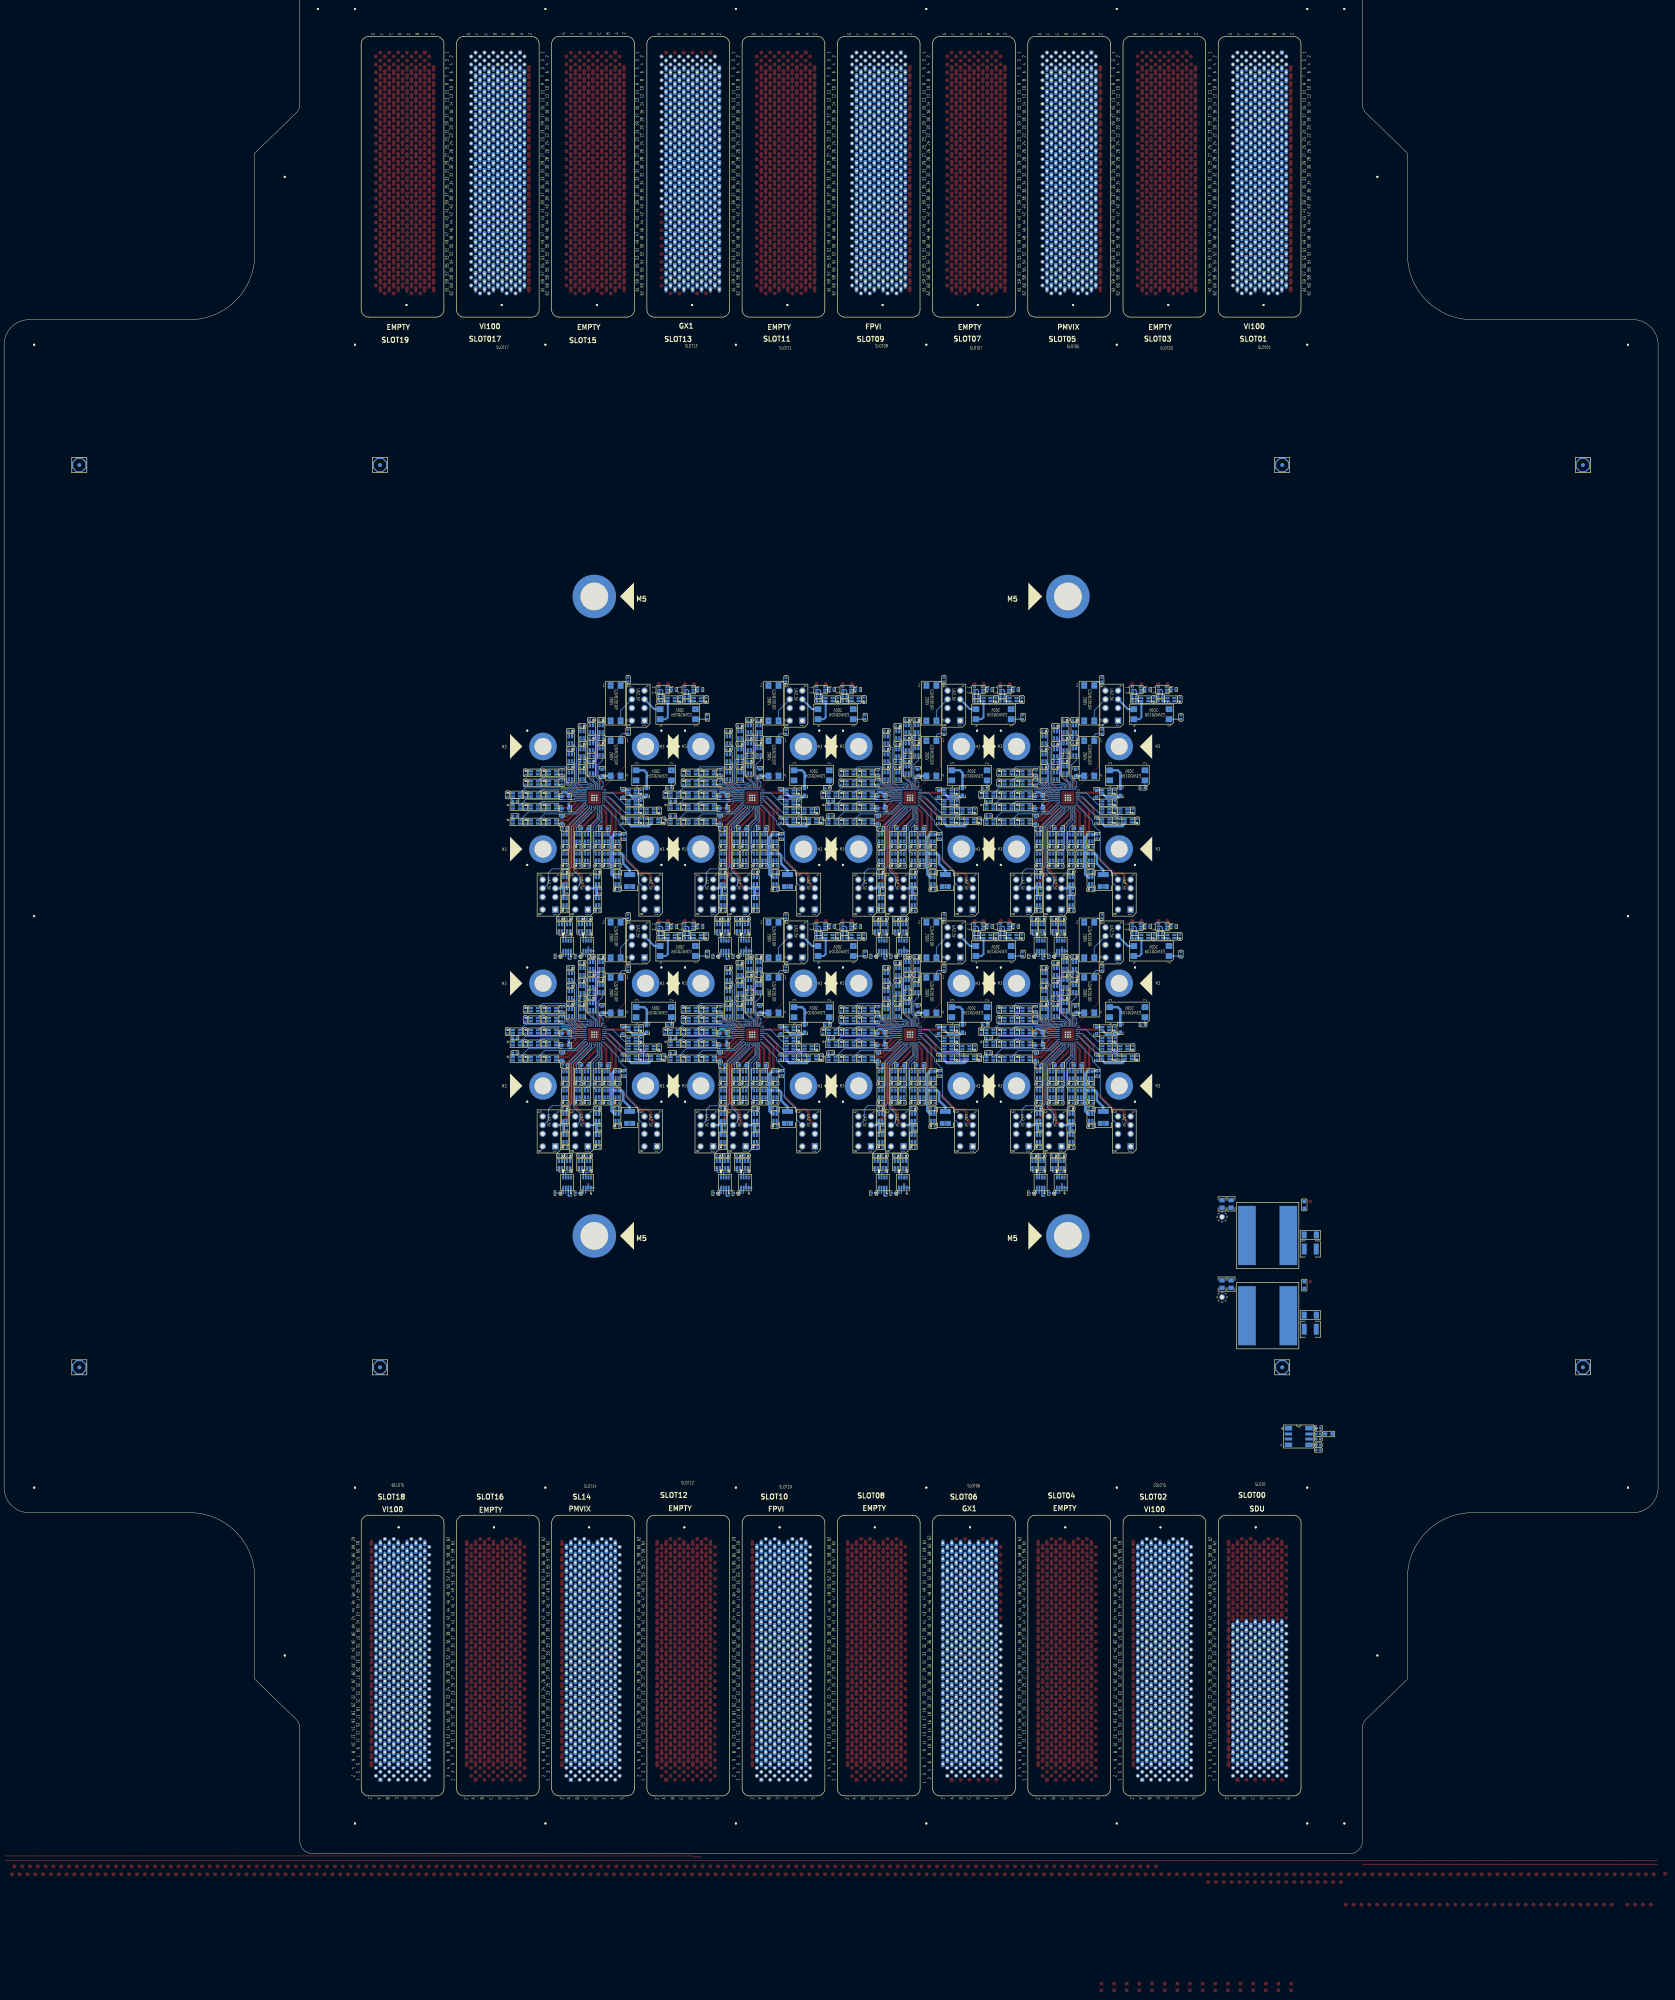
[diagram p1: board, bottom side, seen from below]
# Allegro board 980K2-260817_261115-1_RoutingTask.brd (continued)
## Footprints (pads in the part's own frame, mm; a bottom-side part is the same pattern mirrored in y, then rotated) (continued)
PG_LTXDX_F_X1_GX1_SL06_V2
  round 0.051 hole 2.489x2.21 unplated: (-36.205,-220.342)
  round 0.508 hole 3.2 unplated: (-35.206,-154.842)
  rect 1.016x1.016 smd: A1(-30.576,-218.796)
  round 1.016 hole 0.559: A2(-29.451,-217.796) A3(-30.576,-216.796) A4(-29.451,-215.796) A5(-30.576,-214.796) A6(-29.451,-213.796) A7(-30.576,-212.796) A8(-29.451,-211.796) A9(-30.576,-210.796) A10(-29.451,-209.796) A11(-30.576,-208.796) A12(-29.451,-207.796) A13(-30.576,-206.796) A14(-29.451,-205.796) A15(-30.576,-204.796) A16(-29.451,-203.796) A17(-30.576,-202.796) A18(-29.451,-201.796) A19(-30.576,-200.796) A20(-29.451,-199.796) A21(-30.576,-198.796) A22(-29.451,-197.796) A23(-30.576,-196.796) A24(-29.451,-195.796) A25(-30.576,-194.796) A26(-29.451,-193.796) A27(-30.576,-192.796) A28(-29.451,-191.796) A29(-30.576,-190.796) A30(-29.451,-189.796) A31(-30.576,-188.796) A32(-29.451,-187.796) A33(-30.576,-186.796) A34(-29.451,-185.796) A35(-30.576,-184.796) A36(-29.451,-183.796) A37(-30.576,-182.796) A38(-29.451,-181.796) A39(-30.576,-180.796) A40(-29.451,-179.796) A41(-30.576,-178.796) A42(-29.451,-177.796) A43(-30.576,-176.796) A44(-29.451,-175.796) A45(-30.576,-174.796) A46(-29.451,-173.796) A47(-30.576,-172.796) A48(-29.451,-171.796) A49(-30.576,-170.796) A50(-29.451,-169.796) A51(-30.576,-168.796) A52(-29.451,-167.796) A53(-30.576,-166.796) A54(-29.451,-165.796) A55(-30.576,-164.796) A56(-29.451,-163.796) A57(-30.576,-162.796) A58(-29.451,-161.796) A59(-30.576,-160.796) A60(-29.451,-159.796) A61(-30.576,-158.796) B2(-31.7,-217.796) B3(-32.825,-216.796) B4(-31.7,-215.796) B5(-32.825,-214.796) B6(-31.7,-213.796) B7(-32.825,-212.796) B8(-31.7,-211.796) B9(-32.825,-210.796) B10(-31.7,-209.796) B11(-32.825,-208.796) B12(-31.7,-207.796) B13(-32.825,-206.796) B14(-31.7,-205.796) B15(-32.825,-204.796) B16(-31.7,-203.796) B17(-32.825,-202.796) B18(-31.7,-201.796) B19(-32.825,-200.796) B20(-31.7,-199.796) B21(-32.825,-198.796) B22(-31.7,-197.796) B23(-32.825,-196.796) B24(-31.7,-195.796) B25(-32.825,-194.796) B26(-31.7,-193.796) B27(-32.825,-192.796) B28(-31.7,-191.796) B29(-32.825,-190.796) B30(-31.7,-189.796) B31(-32.825,-188.796) B32(-31.7,-187.796) B33(-32.825,-186.796) B34(-31.7,-185.796) B35(-32.825,-184.796) B36(-31.7,-183.796) B37(-32.825,-182.796) B38(-31.7,-181.796) B39(-32.825,-180.796) B40(-31.7,-179.796) B41(-32.825,-178.796) B42(-31.7,-177.796) B43(-32.825,-176.796) B44(-31.7,-175.796) B45(-32.825,-174.796) B46(-31.7,-173.796) B47(-32.825,-172.796) B48(-31.7,-171.796) B49(-32.825,-170.796) B50(-31.7,-169.796) B51(-32.825,-168.796) B52(-31.7,-167.796) B53(-32.825,-166.796) B54(-31.7,-165.796) B55(-32.825,-164.796) B56(-31.7,-163.796) B57(-32.825,-162.796) B58(-31.7,-161.796) B59(-32.825,-160.796) B60(-31.7,-159.796) B61(-32.825,-158.796) C2(-33.95,-217.796) C3(-35.075,-216.796) C4(-33.95,-215.796) C5(-35.075,-214.796) C6(-33.95,-213.796) C7(-35.075,-212.796) C8(-33.95,-211.796) C9(-35.075,-210.796) C10(-33.95,-209.796) C11(-35.075,-208.796) C12(-33.95,-207.796) C13(-35.075,-206.796) C14(-33.95,-205.796) C15(-35.075,-204.796) C16(-33.95,-203.796) C17(-35.075,-202.796) C18(-33.95,-201.796) C19(-35.075,-200.796) C20(-33.95,-199.796) C21(-35.075,-198.796) C22(-33.95,-197.796) C23(-35.075,-196.796) C24(-33.95,-195.796) C25(-35.075,-194.796) C26(-33.95,-193.796) C27(-35.075,-192.796) C28(-33.95,-191.796) C29(-35.075,-190.796) C30(-33.95,-189.796) C31(-35.075,-188.796) C32(-33.95,-187.796) C33(-35.075,-186.796) C34(-33.95,-185.796) C35(-35.075,-184.796) C36(-33.95,-183.796) C37(-35.075,-182.796) C38(-33.95,-181.796) C39(-35.075,-180.796) C40(-33.95,-179.796) C41(-35.075,-178.796) C42(-33.95,-177.796) C43(-35.075,-176.796) C44(-33.95,-175.796) C45(-35.075,-174.796) C46(-33.95,-173.796) C47(-35.075,-172.796) C48(-33.95,-171.796) C49(-35.075,-170.796) C50(-33.95,-169.796) C51(-35.075,-168.796) C52(-33.95,-167.796) C53(-35.075,-166.796) C54(-33.95,-165.796) C55(-35.075,-164.796) C56(-33.95,-163.796) C57(-35.075,-162.796) C58(-33.95,-161.796) C59(-35.075,-160.796) C60(-33.95,-159.796) C61(-35.075,-158.796) D2(-36.2,-217.796) D3(-37.325,-216.796) D4(-36.2,-215.796) D5(-37.325,-214.796) D6(-36.2,-213.796) D7(-37.325,-212.796) D8(-36.2,-211.796) D9(-37.325,-210.796) D10(-36.2,-209.796) D11(-37.325,-208.796) D12(-36.2,-207.796) D13(-37.325,-206.796) D14(-36.2,-205.796) D15(-37.325,-204.796) D16(-36.2,-203.796) D17(-37.325,-202.796) D18(-36.2,-201.796) D19(-37.325,-200.796) D20(-36.2,-199.796) D21(-37.325,-198.796) D22(-36.2,-197.796) D23(-37.325,-196.796) D24(-36.2,-195.796) D25(-37.325,-194.796) D26(-36.2,-193.796) D27(-37.325,-192.796) D28(-36.2,-191.796) D29(-37.325,-190.796) D30(-36.2,-189.796) D31(-37.325,-188.796) D32(-36.2,-187.796) D33(-37.325,-186.796) D34(-36.2,-185.796) D35(-37.325,-184.796) D36(-36.2,-183.796) D37(-37.325,-182.796) D38(-36.2,-181.796) D39(-37.325,-180.796) D40(-36.2,-179.796) D41(-37.325,-178.796) D42(-36.2,-177.796) D43(-37.325,-176.796) D44(-36.2,-175.796) D45(-37.325,-174.796) D46(-36.2,-173.796) D47(-37.325,-172.796) D48(-36.2,-171.796) D49(-37.325,-170.796) D50(-36.2,-169.796) D51(-37.325,-168.796) D52(-36.2,-167.796) D53(-37.325,-166.796) D54(-36.2,-165.796) D55(-37.325,-164.796) D56(-36.2,-163.796) D57(-37.325,-162.796) D58(-36.2,-161.796) D59(-37.325,-160.796) D60(-36.2,-159.796) D61(-37.325,-158.796) E2(-38.451,-217.796) E3(-39.575,-216.796) E4(-38.451,-215.796) E5(-39.575,-214.796) E6(-38.45,-213.796) E7(-39.575,-212.796) E8(-38.45,-211.796) E9(-39.575,-210.796) E10(-38.45,-209.796) E11(-39.575,-208.796) E12(-38.45,-207.796) E13(-39.575,-206.796) E14(-38.45,-205.796) E15(-39.575,-204.796) E16(-38.45,-203.796) E17(-39.575,-202.796) E18(-38.45,-201.796) E19(-39.575,-200.796) E20(-38.45,-199.796) E21(-39.575,-198.796) E22(-38.45,-197.796) E23(-39.575,-196.796) E24(-38.45,-195.796) E25(-39.575,-194.796) E26(-38.45,-193.796) E27(-39.575,-192.796) E28(-38.45,-191.796) E29(-39.575,-190.796) E30(-38.45,-189.796) E31(-39.575,-188.796) E32(-38.45,-187.796) E33(-39.575,-186.796) E34(-38.45,-185.796) E35(-39.575,-184.796) E36(-38.45,-183.796) E37(-39.575,-182.796) E38(-38.45,-181.796) E39(-39.575,-180.796) E40(-38.45,-179.796) E41(-39.575,-178.796) E42(-38.45,-177.796) E43(-39.575,-176.796) E44(-38.45,-175.796) E45(-39.575,-174.796) E46(-38.45,-173.796) E47(-39.575,-172.796) E48(-38.45,-171.796) E49(-39.575,-170.796) E50(-38.45,-169.796) E51(-39.575,-168.796) E52(-38.45,-167.796) E53(-39.575,-166.796) E54(-38.45,-165.796) E55(-39.575,-164.796) E56(-38.45,-163.796) E57(-39.575,-162.796) E58(-38.45,-161.796) E59(-39.575,-160.796) E60(-38.45,-159.796) E61(-39.575,-158.796) F2(-40.7,-217.796) F3(-41.825,-216.796) F4(-40.7,-215.796) F5(-41.826,-214.796) F6(-40.7,-213.796) F7(-41.826,-212.796) F8(-40.7,-211.796) F9(-41.826,-210.796) F10(-40.7,-209.796) F11(-41.826,-208.796) F12(-40.7,-207.796) F13(-41.826,-206.796) F14(-40.7,-205.796) F15(-41.826,-204.796) F16(-40.7,-203.796) F17(-41.826,-202.796) F18(-40.7,-201.796) F19(-41.826,-200.796) F20(-40.7,-199.796) F21(-41.826,-198.796) F22(-40.7,-197.796) F23(-41.826,-196.796) F24(-40.7,-195.796) F25(-41.826,-194.796) F26(-40.7,-193.796) F27(-41.826,-192.796) F28(-40.7,-191.796) F29(-41.826,-190.796) F30(-40.7,-189.796) F31(-41.826,-188.796) F32(-40.7,-187.796) F33(-41.826,-186.796) F34(-40.7,-185.796) F35(-41.826,-184.796) F36(-40.7,-183.796) F37(-41.826,-182.796) F38(-40.7,-181.796) F39(-41.826,-180.796) F40(-40.7,-179.796) F41(-41.826,-178.796) F42(-40.7,-177.796) F43(-41.826,-176.796) F44(-40.7,-175.796) F45(-41.826,-174.796) F46(-40.7,-173.796) F47(-41.826,-172.796) F48(-40.7,-171.796) F49(-41.826,-170.796) F50(-40.7,-169.796) F51(-41.826,-168.796) F52(-40.7,-167.796) F53(-41.826,-166.796) F54(-40.7,-165.796) F55(-41.826,-164.796) F56(-40.7,-163.796) F57(-41.826,-162.796) F58(-40.7,-161.796) F59(-41.826,-160.796) F60(-40.7,-159.796) F61(-41.826,-158.796) G2(-42.951,-217.796) G4(-42.951,-215.796) G6(-42.951,-213.796) G8(-42.951,-211.796) G10(-42.951,-209.796) G12(-42.951,-207.796) G14(-42.951,-205.796) G16(-42.951,-203.796) G18(-42.951,-201.796) G20(-42.951,-199.796) G22(-42.951,-197.796) G24(-42.951,-195.796) G26(-42.951,-193.796) G28(-42.951,-191.796) G30(-42.951,-189.796) G32(-42.951,-187.796) G34(-42.951,-185.796) G36(-42.951,-183.796) G38(-42.951,-181.796) G40(-42.951,-179.796) Z5(-28.326,-214.796) Z7(-28.326,-212.796) Z9(-28.326,-210.796) Z11(-28.326,-208.796) Z13(-28.326,-206.796) Z15(-28.326,-204.796) Z17(-28.326,-202.796) Z19(-28.326,-200.796) Z21(-28.326,-198.796) Z23(-28.326,-196.796) Z25(-28.326,-194.796) Z27(-28.326,-192.796) Z29(-28.326,-190.796) Z31(-28.326,-188.796) Z33(-28.326,-186.796) Z35(-28.326,-184.796) Z37(-28.326,-182.796) Z39(-28.326,-180.796) Z41(-28.326,-178.796) Z43(-28.326,-176.796) Z45(-28.326,-174.796) Z47(-28.326,-172.796) Z49(-28.326,-170.796) Z51(-28.326,-168.796) Z53(-28.326,-166.796) Z55(-28.326,-164.796) Z57(-28.326,-162.796) Z59(-28.326,-160.796) Z61(-28.326,-158.796)
  round 1.016 smd: B1(-32.825,-218.796) B62(-31.7,-157.796) C1(-35.076,-218.796) C62(-33.95,-157.796) D1(-37.326,-218.796) E1(-39.575,-218.796) E62(-38.45,-157.796) F1(-41.825,-218.796) F62(-40.7,-157.796) G42(-42.951,-177.796) G44(-42.951,-175.796) G46(-42.951,-173.796) G48(-42.951,-171.796) G50(-42.951,-169.796) G52(-42.951,-167.796) G54(-42.951,-165.796) G56(-42.951,-163.796) G58(-42.951,-161.796) G60(-42.951,-159.796)
PG_LTXDX_F_X1_GX1_SL13_V2
  round 0.508 hole 3.2 unplated: (35.206,154.842)
  round 0.051 hole 2.489x2.21 unplated: (36.205,220.342)
  rect 1.016x1.016 smd: A1(30.576,218.796)
  round 1.016 hole 0.559: A2(29.451,217.796) A3(30.576,216.796) A4(29.451,215.796) A5(30.576,214.796) A6(29.451,213.796) A7(30.576,212.796) A8(29.451,211.796) A9(30.576,210.796) A10(29.451,209.796) A11(30.576,208.796) A12(29.451,207.796) A13(30.576,206.796) A14(29.451,205.796) A15(30.576,204.796) A16(29.451,203.796) A17(30.576,202.796) A18(29.451,201.796) A19(30.576,200.796) A20(29.451,199.796) A21(30.576,198.796) A22(29.451,197.796) A23(30.576,196.796) A24(29.451,195.796) A25(30.576,194.796) A26(29.451,193.796) A27(30.576,192.796) A28(29.451,191.796) A29(30.576,190.796) A30(29.451,189.796) A31(30.576,188.796) A32(29.451,187.796) A33(30.576,186.796) A34(29.451,185.796) A35(30.576,184.796) A36(29.451,183.796) A37(30.576,182.796) A38(29.451,181.796) A39(30.576,180.796) A40(29.451,179.796) A41(30.576,178.796) A42(29.451,177.796) A43(30.576,176.796) A44(29.451,175.796) A45(30.576,174.796) A46(29.451,173.796) A47(30.576,172.796) A48(29.451,171.796) A49(30.576,170.796) A50(29.451,169.796) A51(30.576,168.796) A52(29.451,167.796) A53(30.576,166.796) A54(29.451,165.796) A55(30.576,164.796) A56(29.451,163.796) A57(30.576,162.796) A58(29.451,161.796) A59(30.576,160.796) A60(29.451,159.796) A61(30.576,158.796) B2(31.7,217.796) B3(32.825,216.796) B4(31.7,215.796) B5(32.825,214.796) B6(31.7,213.796) B7(32.825,212.796) B8(31.7,211.796) B9(32.825,210.796) B10(31.7,209.796) B11(32.825,208.796) B12(31.7,207.796) B13(32.825,206.796) B14(31.7,205.796) B15(32.825,204.796) B16(31.7,203.796) B17(32.825,202.796) B18(31.7,201.796) B19(32.825,200.796) B20(31.7,199.796) B21(32.825,198.796) B22(31.7,197.796) B23(32.825,196.796) B24(31.7,195.796) B25(32.825,194.796) B26(31.7,193.796) B27(32.825,192.796) B28(31.7,191.796) B29(32.825,190.796) B30(31.7,189.796) B31(32.825,188.796) B32(31.7,187.796) B33(32.825,186.796) B34(31.7,185.796) B35(32.825,184.796) B36(31.7,183.796) B37(32.825,182.796) B38(31.7,181.796) B39(32.825,180.796) B40(31.7,179.796) B41(32.825,178.796) B42(31.7,177.796) B43(32.825,176.796) B44(31.7,175.796) B45(32.825,174.796) B46(31.7,173.796) B47(32.825,172.796) B48(31.7,171.796) B49(32.825,170.796) B50(31.7,169.796) B51(32.825,168.796) B52(31.7,167.796) B53(32.825,166.796) B54(31.7,165.796) B55(32.825,164.796) B56(31.7,163.796) B57(32.825,162.796) B58(31.7,161.796) B59(32.825,160.796) B60(31.7,159.796) B61(32.825,158.796) C2(33.95,217.796) C3(35.076,216.796) C4(33.95,215.796) C5(35.076,214.796) C6(33.95,213.796) C7(35.076,212.796) C8(33.95,211.796) C9(35.076,210.796) C10(33.95,209.796) C11(35.076,208.796) C12(33.95,207.796) C13(35.076,206.796) C14(33.95,205.796) C15(35.076,204.796) C16(33.95,203.796) C17(35.076,202.796) C18(33.95,201.796) C19(35.076,200.796) C20(33.95,199.796) C21(35.076,198.796) C22(33.95,197.796) C23(35.076,196.796) C24(33.95,195.796) C25(35.076,194.796) C26(33.95,193.796) C27(35.076,192.796) C28(33.95,191.796) C29(35.076,190.796) C30(33.95,189.796) C31(35.076,188.796) C32(33.95,187.796) C33(35.076,186.796) C34(33.95,185.796) C35(35.076,184.796) C36(33.95,183.796) C37(35.076,182.796) C38(33.95,181.796) C39(35.076,180.796) C40(33.95,179.796) C41(35.076,178.796) C42(33.95,177.796) C43(35.076,176.796) C44(33.95,175.796) C45(35.076,174.796) C46(33.95,173.796) C47(35.076,172.796) C48(33.95,171.796) C49(35.076,170.796) C50(33.95,169.796) C51(35.076,168.796) C52(33.95,167.796) C53(35.076,166.796) C54(33.95,165.796) C55(35.076,164.796) C56(33.95,163.796) C57(35.076,162.796) C58(33.95,161.796) C59(35.076,160.796) C60(33.95,159.796) C61(35.076,158.796) D2(36.201,217.796) D3(37.326,216.796) D4(36.201,215.796) D5(37.326,214.796) D6(36.201,213.796) D7(37.326,212.796) D8(36.201,211.796) D9(37.326,210.796) D10(36.201,209.796) D11(37.326,208.796) D12(36.201,207.796) D13(37.326,206.796) D14(36.201,205.796) D15(37.326,204.796) D16(36.201,203.796) D17(37.326,202.796) D18(36.201,201.796) D19(37.326,200.796) D20(36.201,199.796) D21(37.326,198.796) D22(36.201,197.796) D23(37.326,196.796) D24(36.201,195.796) D25(37.326,194.796) D26(36.201,193.796) D27(37.326,192.796) D28(36.201,191.796) D29(37.326,190.796) D30(36.201,189.796) D31(37.326,188.796) D32(36.201,187.796) D33(37.326,186.796) D34(36.201,185.796) D35(37.326,184.796) D36(36.201,183.796) D37(37.326,182.796) D38(36.201,181.796) D39(37.326,180.796) D40(36.201,179.796) D41(37.326,178.796) D42(36.201,177.796) D43(37.326,176.796) D44(36.201,175.796) D45(37.326,174.796) D46(36.201,173.796) D47(37.326,172.796) D48(36.201,171.796) D49(37.326,170.796) D50(36.201,169.796) D51(37.326,168.796) D52(36.201,167.796) D53(37.326,166.796) D54(36.201,165.796) D55(37.326,164.796) D56(36.201,163.796) D57(37.326,162.796) D58(36.201,161.796) D59(37.326,160.796) D60(36.201,159.796) D61(37.326,158.796) E2(38.451,217.796) E3(39.575,216.796) E4(38.451,215.796) E5(39.575,214.796) E6(38.451,213.796) E7(39.575,212.796) E8(38.451,211.796) E9(39.575,210.796) E10(38.451,209.796) E11(39.575,208.796) E12(38.451,207.796) E13(39.575,206.796) E14(38.451,205.796) E15(39.575,204.796) E16(38.451,203.796) E17(39.575,202.796) E18(38.451,201.796) E19(39.575,200.796) E20(38.451,199.796) E21(39.575,198.796) E22(38.451,197.796) E23(39.575,196.796) E24(38.451,195.796) E25(39.575,194.796) E26(38.451,193.796) E27(39.575,192.796) E28(38.451,191.796) E29(39.575,190.796) E30(38.451,189.796) E31(39.575,188.796) E32(38.451,187.796) E33(39.575,186.796) E34(38.451,185.796) E35(39.575,184.796) E36(38.451,183.796) E37(39.575,182.796) E38(38.451,181.796) E39(39.575,180.796) E40(38.451,179.796) E41(39.575,178.796) E42(38.451,177.796) E43(39.575,176.796) E44(38.451,175.796) E45(39.575,174.796) E46(38.451,173.796) E47(39.575,172.796) E48(38.451,171.796) E49(39.575,170.796) E50(38.451,169.796) E51(39.575,168.796) E52(38.451,167.796) E53(39.575,166.796) E54(38.451,165.796) E55(39.575,164.796) E56(38.451,163.796) E57(39.575,162.796) E58(38.451,161.796) E59(39.575,160.796) E60(38.451,159.796) E61(39.575,158.796) F2(40.7,217.796) F3(41.825,216.796) F4(40.7,215.796) F5(41.825,214.796) F6(40.7,213.796) F7(41.825,212.796) F8(40.7,211.796) F9(41.825,210.796) F10(40.7,209.796) F11(41.825,208.796) F12(40.7,207.796) F13(41.825,206.796) F14(40.7,205.796) F15(41.825,204.796) F16(40.7,203.796) F17(41.825,202.796) F18(40.7,201.796) F19(41.825,200.796) F20(40.7,199.796) F21(41.825,198.796) F22(40.7,197.796) F23(41.825,196.796) F24(40.7,195.796) F25(41.825,194.796) F26(40.7,193.796) F27(41.825,192.796) F28(40.7,191.796) F29(41.825,190.796) F30(40.7,189.796) F31(41.825,188.796) F32(40.7,187.796) F33(41.825,186.796) F34(40.7,185.796) F35(41.825,184.796) F36(40.7,183.796) F37(41.825,182.796) F38(40.7,181.796) F39(41.825,180.796) F40(40.7,179.796) F41(41.825,178.796) F42(40.7,177.796) F43(41.825,176.796) F44(40.7,175.796) F45(41.825,174.796) F46(40.7,173.796) F47(41.825,172.796) F48(40.7,171.796) F49(41.825,170.796) F50(40.7,169.796) F51(41.825,168.796) F52(40.7,167.796) F53(41.825,166.796) F54(40.7,165.796) F55(41.825,164.796) F56(40.7,163.796) F57(41.825,162.796) F58(40.7,161.796) F59(41.825,160.796) F60(40.7,159.796) F61(41.825,158.796) G2(42.95,217.796) G4(42.95,215.796) G6(42.95,213.796) G8(42.95,211.796) G10(42.95,209.796) G12(42.95,207.796) G14(42.95,205.796) G16(42.95,203.796) G18(42.95,201.796) G20(42.95,199.796) G22(42.95,197.796) G24(42.95,195.796) G26(42.95,193.796) G28(42.95,191.796) G30(42.95,189.796) G32(42.95,187.796) G34(42.95,185.796) G36(42.95,183.796) G38(42.95,181.796) G40(42.95,179.796) Z5(28.326,214.796) Z7(28.326,212.796) Z9(28.326,210.796) Z11(28.326,208.796) Z13(28.326,206.796) Z15(28.326,204.796) Z17(28.326,202.796) Z19(28.326,200.796) Z21(28.326,198.796) Z23(28.326,196.796) Z25(28.326,194.796) Z27(28.326,192.796) Z29(28.326,190.796) Z31(28.326,188.796) Z33(28.326,186.796) Z35(28.326,184.796) Z37(28.326,182.796) Z39(28.326,180.796) Z41(28.326,178.796) Z43(28.326,176.796) Z45(28.326,174.796) Z47(28.326,172.796) Z49(28.326,170.796) Z51(28.326,168.796) Z53(28.326,166.796) Z55(28.326,164.796) Z57(28.326,162.796) Z59(28.326,160.796) Z61(28.326,158.796)
  round 1.016 smd: B1(32.825,218.796) B62(31.7,157.796) C1(35.076,218.796) C62(33.95,157.796) D1(37.326,218.796) E1(39.575,218.796) E62(38.451,157.796) F1(41.825,218.796) F62(40.7,157.796) G42(42.95,177.796) G44(42.95,175.796) G46(42.95,173.796) G48(42.95,171.796) G50(42.95,169.796) G52(42.95,167.796) G54(42.95,165.796) G56(42.95,163.796) G58(42.95,161.796) G60(42.95,159.796)
PG_LTXDX_F_X1_OUTLINE_TD_COHU
  round 0.508 hole 4.623 unplated: (-201.93,144.78) (-201.93,0) (-201.93,-144.78) (-138.426,187.32) (-138.426,-187.32) (-120.65,229.87) (-120.65,144.78) (-120.65,-144.78) (-120.65,-229.87) (-72.39,229.87) (-72.39,144.78) (-72.39,-144.78) (-72.39,-229.87) (-24.13,229.87) (-24.13,144.78) (-24.13,-144.78) (-24.13,-229.87) (24.13,229.87) (24.13,144.78) (24.13,-144.78) (24.13,-229.87) (72.39,229.87) (72.39,144.78) (72.39,-144.78) (72.39,-229.87) (120.65,229.87) (120.65,144.78) (120.65,-144.78) (120.65,-229.87) (138.427,187.32) (138.427,-187.32) (201.93,144.78) (201.93,0) (201.93,-144.78)
  round 0.508 hole 3.048 unplated: (-130.048,229.87)
  round 0.508 hole 3.099x4.572 unplated: (-130.048,-229.87)
  round 0.508 hole 3.404 unplated: (130.048,229.87)
PG_LTXDX_F_X1_PG400ND_SL03_V3
  round 0.508 hole 3.2 unplated: (-85.444,154.842)
  round 0.051 hole 2.489x2.21 unplated: (-84.444,220.342)
  rect 1.016x1.016 smd: A1(-90.074,218.796)
  round 1.016 smd: A2(-91.199,217.796) A3(-90.074,216.796) A4(-91.199,215.796) B1(-87.825,218.796) B2(-88.95,217.796) B3(-87.825,216.796) B4(-88.95,215.796) B62(-88.95,157.796) C1(-85.574,218.796) C2(-86.7,217.796) C3(-85.574,216.796) C4(-86.7,215.796) C62(-86.7,157.796) D1(-83.324,218.796) D2(-84.449,217.796) D3(-83.324,216.796) D4(-84.449,215.796) E1(-81.075,218.796) E2(-82.199,217.796) E3(-81.075,216.796) E4(-82.199,215.796) E62(-82.199,157.796) F1(-78.825,218.796) F2(-79.95,217.796) F3(-78.825,216.796) F4(-79.95,215.796) F62(-79.95,157.796) G2(-77.7,217.796) G4(-77.7,215.796) G6(-77.7,213.796) G8(-77.7,211.796) G10(-77.7,209.796) G12(-77.7,207.796) G14(-77.7,205.796) G16(-77.7,203.796) G18(-77.7,201.796) G20(-77.7,199.796) G22(-77.7,197.796) G24(-77.7,195.796) G26(-77.7,193.796) G28(-77.7,191.796) G30(-77.7,189.796) G32(-77.7,187.796) G34(-77.7,185.796) G36(-77.7,183.796) G38(-77.7,181.796) G40(-77.7,179.796) G42(-77.7,177.796) G44(-77.7,175.796) G46(-77.7,173.796) G48(-77.7,171.796) G50(-77.7,169.796) G52(-77.7,167.796) G54(-77.7,165.796) G56(-77.7,163.796) G58(-77.7,161.796) G60(-77.7,159.796)
  custom 0.257x0.257 smd: A5(-90.074,214.796) A6(-91.199,213.796) A7(-90.074,212.796) A8(-91.199,211.796) A9(-90.074,210.796) A10(-91.199,209.796) A11(-90.074,208.796) A12(-91.199,207.796) A13(-90.074,206.796) A14(-91.199,205.796) A15(-90.074,204.796) A16(-91.199,203.796) A17(-90.074,202.796) A18(-91.199,201.796) A19(-90.074,200.796) A20(-91.199,199.796) A21(-90.074,198.796) A22(-91.199,197.796) A23(-90.074,196.796) A24(-91.199,195.796) A25(-90.074,194.796) A26(-91.199,193.796) A27(-90.074,192.796) A28(-91.199,191.796) A29(-90.074,190.796) A30(-91.199,189.796) A31(-90.074,188.796) A32(-91.199,187.796) A33(-90.074,186.796) A34(-91.199,185.796) A35(-90.074,184.796) A36(-91.199,183.796) A37(-90.074,182.796) A38(-91.199,181.796) A39(-90.074,180.796) A40(-91.199,179.796) A41(-90.074,178.796) A42(-91.199,177.796) A43(-90.074,176.796) A44(-91.199,175.796) A45(-90.074,174.796) A46(-91.199,173.796) A47(-90.074,172.796) A48(-91.199,171.796) A49(-90.074,170.796) A50(-91.199,169.796) A51(-90.074,168.796) A52(-91.199,167.796) A53(-90.074,166.796) A54(-91.199,165.796) A55(-90.074,164.796) A56(-91.199,163.796) A57(-90.074,162.796) A58(-91.199,161.796) A59(-90.074,160.796) A60(-91.199,159.796) A61(-90.074,158.796) B5(-87.825,214.796) B6(-88.95,213.796) B7(-87.825,212.796) B8(-88.95,211.796) B9(-87.825,210.796) B10(-88.95,209.796) B11(-87.825,208.796) B12(-88.95,207.796) B13(-87.825,206.796) B14(-88.95,205.796) B15(-87.825,204.796) B16(-88.95,203.796) B17(-87.825,202.796) B18(-88.95,201.796) B19(-87.825,200.796) B20(-88.95,199.796) B21(-87.825,198.796) B22(-88.95,197.796) B23(-87.825,196.796) B24(-88.95,195.796) B25(-87.825,194.796) B26(-88.95,193.796) B27(-87.825,192.796) B28(-88.95,191.796) B29(-87.825,190.796) B30(-88.95,189.796) B31(-87.825,188.796) B32(-88.95,187.796) B33(-87.825,186.796) B34(-88.95,185.796) B35(-87.825,184.796) B36(-88.95,183.796) B37(-87.825,182.796) B38(-88.95,181.796) B39(-87.825,180.796) B40(-88.95,179.796) B41(-87.825,178.796) B42(-88.95,177.796) B43(-87.825,176.796) B44(-88.95,175.796) B45(-87.825,174.796) B46(-88.95,173.796) B47(-87.825,172.796) B48(-88.95,171.796) B49(-87.825,170.796) B50(-88.95,169.796) B51(-87.825,168.796) B52(-88.95,167.796) B53(-87.825,166.796) B54(-88.95,165.796) B55(-87.825,164.796) B56(-88.95,163.796) B57(-87.825,162.796) B58(-88.95,161.796) B59(-87.825,160.796) B60(-88.95,159.796) B61(-87.825,158.796) C5(-85.574,214.796) C6(-86.7,213.796) C7(-85.574,212.796) C8(-86.7,211.796) C9(-85.574,210.796) C10(-86.7,209.796) C11(-85.574,208.796) C12(-86.7,207.796) C13(-85.574,206.796) C14(-86.7,205.796) C15(-85.574,204.796) C16(-86.7,203.796) C17(-85.574,202.796) C18(-86.7,201.796) C19(-85.574,200.796) C20(-86.7,199.796) C21(-85.574,198.796) C22(-86.7,197.796) C23(-85.574,196.796) C24(-86.7,195.796) C25(-85.574,194.796) C26(-86.7,193.796) C27(-85.574,192.796) C28(-86.7,191.796) C29(-85.574,190.796) C30(-86.7,189.796) C31(-85.574,188.796) C32(-86.7,187.796) C33(-85.574,186.796) C34(-86.7,185.796) C35(-85.574,184.796) C36(-86.7,183.796) C37(-85.574,182.796) C38(-86.7,181.796) C39(-85.574,180.796) C40(-86.7,179.796) C41(-85.574,178.796) C42(-86.7,177.796) C43(-85.574,176.796) C44(-86.7,175.796) C45(-85.574,174.796) C46(-86.7,173.796) C47(-85.574,172.796) C48(-86.7,171.796) C49(-85.574,170.796) C50(-86.7,169.796) C51(-85.574,168.796) C52(-86.7,167.796) C53(-85.574,166.796) C54(-86.7,165.796) C55(-85.574,164.796) C56(-86.7,163.796) C57(-85.574,162.796) C58(-86.7,161.796) C59(-85.574,160.796) C60(-86.7,159.796) C61(-85.574,158.796) D5(-83.324,214.796) D6(-84.449,213.796) D7(-83.324,212.796) D8(-84.449,211.796) D9(-83.324,210.796) D10(-84.449,209.796) D11(-83.324,208.796) D12(-84.449,207.796) D13(-83.324,206.796) D14(-84.449,205.796) D15(-83.324,204.796) D16(-84.449,203.796) D17(-83.324,202.796) D18(-84.449,201.796) D19(-83.324,200.796) D20(-84.449,199.796) D21(-83.324,198.796) D22(-84.449,197.796) D23(-83.324,196.796) D24(-84.449,195.796) D25(-83.324,194.796) D26(-84.449,193.796) D27(-83.324,192.796) D28(-84.449,191.796) D29(-83.324,190.796) D30(-84.449,189.796) D31(-83.324,188.796) D32(-84.449,187.796) D33(-83.324,186.796) D34(-84.449,185.796) D35(-83.324,184.796) D36(-84.449,183.796) D37(-83.324,182.796) D38(-84.449,181.796) D39(-83.324,180.796) D40(-84.449,179.796) D41(-83.324,178.796) D42(-84.449,177.796) D43(-83.324,176.796) D44(-84.449,175.796) D45(-83.324,174.796) D46(-84.449,173.796) D47(-83.324,172.796) D48(-84.449,171.796) D49(-83.324,170.796) D50(-84.449,169.796) D51(-83.324,168.796) D52(-84.449,167.796) D53(-83.324,166.796) D54(-84.449,165.796) D55(-83.324,164.796) D56(-84.449,163.796) D57(-83.324,162.796) D58(-84.449,161.796) D59(-83.324,160.796) D60(-84.449,159.796) D61(-83.324,158.796) E5(-81.075,214.796) E6(-82.199,213.796) E7(-81.075,212.796) E8(-82.199,211.796) E9(-81.075,210.796) E10(-82.199,209.796) E11(-81.075,208.796) E12(-82.199,207.796) E13(-81.075,206.796) E14(-82.199,205.796) E15(-81.075,204.796) E16(-82.199,203.796) E17(-81.075,202.796) E18(-82.199,201.796) E19(-81.075,200.796) E20(-82.199,199.796) E21(-81.075,198.796) E22(-82.199,197.796) E23(-81.075,196.796) E24(-82.199,195.796) E25(-81.075,194.796) E26(-82.199,193.796) E27(-81.075,192.796) E28(-82.199,191.796) E29(-81.075,190.796) E30(-82.199,189.796) E31(-81.075,188.796) E32(-82.199,187.796) E33(-81.075,186.796) E34(-82.199,185.796) E35(-81.075,184.796) E36(-82.199,183.796) E37(-81.075,182.796) E38(-82.199,181.796) E39(-81.075,180.796) E40(-82.199,179.796) E41(-81.075,178.796) E42(-82.199,177.796) E43(-81.075,176.796) E44(-82.199,175.796) E45(-81.075,174.796) E46(-82.199,173.796) E47(-81.075,172.796) E48(-82.199,171.796) E49(-81.075,170.796) E50(-82.199,169.796) E51(-81.075,168.796) E52(-82.199,167.796) E53(-81.075,166.796) E54(-82.199,165.796) E55(-81.075,164.796) E56(-82.199,163.796) E57(-81.075,162.796) E58(-82.199,161.796) E59(-81.075,160.796) E60(-82.199,159.796) E61(-81.075,158.796) F5(-78.825,214.796) F6(-79.95,213.796) F7(-78.825,212.796) F8(-79.95,211.796) F9(-78.825,210.796) F10(-79.95,209.796) F11(-78.825,208.796) F12(-79.95,207.796) F13(-78.825,206.796) F14(-79.95,205.796) F15(-78.825,204.796) F16(-79.95,203.796) F17(-78.825,202.796) F18(-79.95,201.796) F19(-78.825,200.796) F20(-79.95,199.796) F21(-78.825,198.796) F22(-79.95,197.796) F23(-78.825,196.796) F24(-79.95,195.796) F25(-78.825,194.796) F26(-79.95,193.796) F27(-78.825,192.796) F28(-79.95,191.796) F29(-78.825,190.796) F30(-79.95,189.796) F31(-78.825,188.796) F32(-79.95,187.796) F33(-78.825,186.796) F34(-79.95,185.796) F35(-78.825,184.796) F36(-79.95,183.796) F37(-78.825,182.796) F38(-79.95,181.796) F39(-78.825,180.796) F40(-79.95,179.796) F41(-78.825,178.796) F42(-79.95,177.796) F43(-78.825,176.796) F44(-79.95,175.796) F45(-78.825,174.796) F46(-79.95,173.796) F47(-78.825,172.796) F48(-79.95,171.796) F49(-78.825,170.796) F50(-79.95,169.796) F51(-78.825,168.796) F52(-79.95,167.796) F53(-78.825,166.796) F54(-79.95,165.796) F55(-78.825,164.796) F56(-79.95,163.796) F57(-78.825,162.796) F58(-79.95,161.796) F59(-78.825,160.796) F60(-79.95,159.796) F61(-78.825,158.796) Z5(-92.324,214.796) Z7(-92.324,212.796) Z9(-92.324,210.796) Z11(-92.324,208.796) Z13(-92.324,206.796) Z15(-92.324,204.796) Z17(-92.324,202.796) Z19(-92.324,200.796) Z21(-92.324,198.796) Z23(-92.324,196.796) Z25(-92.324,194.796) Z27(-92.324,192.796) Z29(-92.324,190.796) Z31(-92.324,188.796) Z33(-92.324,186.796) Z35(-92.324,184.796) Z37(-92.324,182.796) Z39(-92.324,180.796) Z41(-92.324,178.796) Z43(-92.324,176.796) Z45(-92.324,174.796) Z47(-92.324,172.796) Z49(-92.324,170.796) Z51(-92.324,168.796) Z53(-92.324,166.796) Z55(-92.324,164.796) Z57(-92.324,162.796) Z59(-92.324,160.796) Z61(-92.324,158.796)
PG_LTXDX_F_X1_PG400ND_SL04_V3
  round 0.051 hole 2.489x2.21 unplated: (-60.335,-220.342)
  round 0.508 hole 3.2 unplated: (-59.335,-154.842)
  rect 1.016x1.016 smd: A1(-54.706,-218.796)
  round 1.016 smd: A2(-53.581,-217.796) A3(-54.706,-216.796) A4(-53.581,-215.796) B1(-56.955,-218.796) B2(-55.83,-217.796) B3(-56.955,-216.796) B4(-55.83,-215.796) B62(-55.83,-157.796) C1(-59.206,-218.796) C2(-58.08,-217.796) C3(-59.206,-216.796) C4(-58.08,-215.796) C62(-58.08,-157.796) D1(-61.456,-218.796) D2(-60.331,-217.796) D3(-61.456,-216.796) D4(-60.331,-215.796) E1(-63.705,-218.796) E2(-62.581,-217.796) E3(-63.705,-216.796) E4(-62.581,-215.796) E62(-62.581,-157.796) F1(-65.955,-218.796) F2(-64.83,-217.796) F3(-65.955,-216.796) F4(-64.83,-215.796) F62(-64.83,-157.796) G2(-67.08,-217.796) G4(-67.08,-215.796) G6(-67.08,-213.796) G8(-67.08,-211.796) G10(-67.08,-209.796) G12(-67.08,-207.796) G14(-67.08,-205.796) G16(-67.08,-203.796) G18(-67.08,-201.796) G20(-67.08,-199.796) G22(-67.08,-197.796) G24(-67.08,-195.796) G26(-67.08,-193.796) G28(-67.08,-191.796) G30(-67.08,-189.796) G32(-67.08,-187.796) G34(-67.08,-185.796) G36(-67.08,-183.796) G38(-67.08,-181.796) G40(-67.08,-179.796) G42(-67.08,-177.796) G44(-67.08,-175.796) G46(-67.08,-173.796) G48(-67.08,-171.796) G50(-67.08,-169.796) G52(-67.08,-167.796) G54(-67.08,-165.796) G56(-67.08,-163.796) G58(-67.08,-161.796) G60(-67.08,-159.796)
  custom 0.257x0.257 smd: A5(-54.706,-214.796) A6(-53.581,-213.796) A7(-54.706,-212.796) A8(-53.581,-211.796) A9(-54.706,-210.796) A10(-53.581,-209.796) A11(-54.706,-208.796) A12(-53.581,-207.796) A13(-54.706,-206.796) A14(-53.581,-205.796) A15(-54.706,-204.796) A16(-53.581,-203.796) A17(-54.706,-202.796) A18(-53.581,-201.796) A19(-54.706,-200.796) A20(-53.581,-199.796) A21(-54.706,-198.796) A22(-53.581,-197.796) A23(-54.706,-196.796) A24(-53.581,-195.796) A25(-54.706,-194.796) A26(-53.581,-193.796) A27(-54.706,-192.796) A28(-53.581,-191.796) A29(-54.706,-190.796) A30(-53.581,-189.796) A31(-54.706,-188.796) A32(-53.581,-187.796) A33(-54.706,-186.796) A34(-53.581,-185.796) A35(-54.706,-184.796) A36(-53.581,-183.796) A37(-54.706,-182.796) A38(-53.581,-181.796) A39(-54.706,-180.796) A40(-53.581,-179.796) A41(-54.706,-178.796) A42(-53.581,-177.796) A43(-54.706,-176.796) A44(-53.581,-175.796) A45(-54.706,-174.796) A46(-53.581,-173.796) A47(-54.706,-172.796) A48(-53.581,-171.796) A49(-54.706,-170.796) A50(-53.581,-169.796) A51(-54.706,-168.796) A52(-53.581,-167.796) A53(-54.706,-166.796) A54(-53.581,-165.796) A55(-54.706,-164.796) A56(-53.581,-163.796) A57(-54.706,-162.796) A58(-53.581,-161.796) A59(-54.706,-160.796) A60(-53.581,-159.796) A61(-54.706,-158.796) B5(-56.955,-214.796) B6(-55.83,-213.796) B7(-56.955,-212.796) B8(-55.83,-211.796) B9(-56.955,-210.796) B10(-55.83,-209.796) B11(-56.955,-208.796) B12(-55.83,-207.796) B13(-56.955,-206.796) B14(-55.83,-205.796) B15(-56.955,-204.796) B16(-55.83,-203.796) B17(-56.955,-202.796) B18(-55.83,-201.796) B19(-56.955,-200.796) B20(-55.83,-199.796) B21(-56.955,-198.796) B22(-55.83,-197.796) B23(-56.955,-196.796) B24(-55.83,-195.796) B25(-56.955,-194.796) B26(-55.83,-193.796) B27(-56.955,-192.796) B28(-55.83,-191.796) B29(-56.955,-190.796) B30(-55.83,-189.796) B31(-56.955,-188.796) B32(-55.83,-187.796) B33(-56.955,-186.796) B34(-55.83,-185.796) B35(-56.955,-184.796) B36(-55.83,-183.796) B37(-56.955,-182.796) B38(-55.83,-181.796) B39(-56.955,-180.796) B40(-55.83,-179.796) B41(-56.955,-178.796) B42(-55.83,-177.796) B43(-56.955,-176.796) B44(-55.83,-175.796) B45(-56.955,-174.796) B46(-55.83,-173.796) B47(-56.955,-172.796) B48(-55.83,-171.796) B49(-56.955,-170.796) B50(-55.83,-169.796) B51(-56.955,-168.796) B52(-55.83,-167.796) B53(-56.955,-166.796) B54(-55.83,-165.796) B55(-56.955,-164.796) B56(-55.83,-163.796) B57(-56.955,-162.796) B58(-55.83,-161.796) B59(-56.955,-160.796) B60(-55.83,-159.796) B61(-56.955,-158.796) C5(-59.206,-214.796) C6(-58.08,-213.796) C7(-59.206,-212.796) C8(-58.08,-211.796) C9(-59.206,-210.796) C10(-58.08,-209.796) C11(-59.206,-208.796) C12(-58.08,-207.796) C13(-59.206,-206.796) C14(-58.08,-205.796) C15(-59.206,-204.796) C16(-58.08,-203.796) C17(-59.206,-202.796) C18(-58.08,-201.796) C19(-59.206,-200.796) C20(-58.08,-199.796) C21(-59.206,-198.796) C22(-58.08,-197.796) C23(-59.206,-196.796) C24(-58.08,-195.796) C25(-59.206,-194.796) C26(-58.08,-193.796) C27(-59.206,-192.796) C28(-58.08,-191.796) C29(-59.206,-190.796) C30(-58.08,-189.796) C31(-59.206,-188.796) C32(-58.08,-187.796) C33(-59.206,-186.796) C34(-58.08,-185.796) C35(-59.206,-184.796) C36(-58.08,-183.796) C37(-59.206,-182.796) C38(-58.08,-181.796) C39(-59.206,-180.796) C40(-58.08,-179.796) C41(-59.206,-178.796) C42(-58.08,-177.796) C43(-59.206,-176.796) C44(-58.08,-175.796) C45(-59.206,-174.796) C46(-58.08,-173.796) C47(-59.206,-172.796) C48(-58.08,-171.796) C49(-59.206,-170.796) C50(-58.08,-169.796) C51(-59.206,-168.796) C52(-58.08,-167.796) C53(-59.206,-166.796) C54(-58.08,-165.796) C55(-59.206,-164.796) C56(-58.08,-163.796) C57(-59.206,-162.796) C58(-58.08,-161.796) C59(-59.206,-160.796) C60(-58.08,-159.796) C61(-59.206,-158.796) D5(-61.456,-214.796) D6(-60.331,-213.796) D7(-61.456,-212.796) D8(-60.331,-211.796) D9(-61.456,-210.796) D10(-60.331,-209.796) D11(-61.456,-208.796) D12(-60.331,-207.796) D13(-61.456,-206.796) D14(-60.331,-205.796) D15(-61.456,-204.796) D16(-60.331,-203.796) D17(-61.456,-202.796) D18(-60.331,-201.796) D19(-61.456,-200.796) D20(-60.331,-199.796) D21(-61.456,-198.796) D22(-60.331,-197.796) D23(-61.456,-196.796) D24(-60.331,-195.796) D25(-61.456,-194.796) D26(-60.331,-193.796) D27(-61.456,-192.796) D28(-60.331,-191.796) D29(-61.456,-190.796) D30(-60.331,-189.796) D31(-61.456,-188.796) D32(-60.331,-187.796) D33(-61.456,-186.796) D34(-60.331,-185.796) D35(-61.456,-184.796) D36(-60.331,-183.796) D37(-61.456,-182.796) D38(-60.331,-181.796) D39(-61.456,-180.796) D40(-60.331,-179.796) D41(-61.456,-178.796) D42(-60.331,-177.796) D43(-61.456,-176.796) D44(-60.331,-175.796) D45(-61.456,-174.796) D46(-60.331,-173.796) D47(-61.456,-172.796) D48(-60.331,-171.796) D49(-61.456,-170.796) D50(-60.331,-169.796) D51(-61.456,-168.796) D52(-60.331,-167.796) D53(-61.456,-166.796) D54(-60.331,-165.796) D55(-61.456,-164.796) D56(-60.331,-163.796) D57(-61.456,-162.796) D58(-60.331,-161.796) D59(-61.456,-160.796) D60(-60.331,-159.796) D61(-61.456,-158.796) E5(-63.705,-214.796) E6(-62.581,-213.796) E7(-63.705,-212.796) E8(-62.581,-211.796) E9(-63.705,-210.796) E10(-62.581,-209.796) E11(-63.705,-208.796) E12(-62.581,-207.796) E13(-63.705,-206.796) E14(-62.581,-205.796) E15(-63.705,-204.796) E16(-62.581,-203.796) E17(-63.705,-202.796) E18(-62.581,-201.796) E19(-63.705,-200.796) E20(-62.581,-199.796) E21(-63.705,-198.796) E22(-62.581,-197.796) E23(-63.705,-196.796) E24(-62.581,-195.796) E25(-63.705,-194.796) E26(-62.581,-193.796) E27(-63.705,-192.796) E28(-62.581,-191.796) E29(-63.705,-190.796) E30(-62.581,-189.796) E31(-63.705,-188.796) E32(-62.581,-187.796) E33(-63.705,-186.796) E34(-62.581,-185.796) E35(-63.705,-184.796) E36(-62.581,-183.796) E37(-63.705,-182.796) E38(-62.581,-181.796) E39(-63.705,-180.796) E40(-62.581,-179.796) E41(-63.705,-178.796) E42(-62.581,-177.796) E43(-63.705,-176.796) E44(-62.581,-175.796) E45(-63.705,-174.796) E46(-62.581,-173.796) E47(-63.705,-172.796) E48(-62.581,-171.796) E49(-63.705,-170.796) E50(-62.581,-169.796) E51(-63.705,-168.796) E52(-62.581,-167.796) E53(-63.705,-166.796) E54(-62.581,-165.796) E55(-63.705,-164.796) E56(-62.581,-163.796) E57(-63.705,-162.796) E58(-62.581,-161.796) E59(-63.705,-160.796) E60(-62.581,-159.796) E61(-63.705,-158.796) F5(-65.955,-214.796) F6(-64.83,-213.796) F7(-65.955,-212.796) F8(-64.83,-211.796) F9(-65.955,-210.796) F10(-64.83,-209.796) F11(-65.955,-208.796) F12(-64.83,-207.796) F13(-65.955,-206.796) F14(-64.83,-205.796) F15(-65.955,-204.796) F16(-64.83,-203.796) F17(-65.955,-202.796) F18(-64.83,-201.796) F19(-65.955,-200.796) F20(-64.83,-199.796) F21(-65.955,-198.796) F22(-64.83,-197.796) F23(-65.955,-196.796) F24(-64.83,-195.796) F25(-65.955,-194.796) F26(-64.83,-193.796) F27(-65.955,-192.796) F28(-64.83,-191.796) F29(-65.955,-190.796) F30(-64.83,-189.796) F31(-65.955,-188.796) F32(-64.83,-187.796) F33(-65.955,-186.796) F34(-64.83,-185.796) F35(-65.955,-184.796) F36(-64.83,-183.796) F37(-65.955,-182.796) F38(-64.83,-181.796) F39(-65.955,-180.796) F40(-64.83,-179.796) F41(-65.955,-178.796) F42(-64.83,-177.796) F43(-65.955,-176.796) F44(-64.83,-175.796) F45(-65.955,-174.796) F46(-64.83,-173.796) F47(-65.955,-172.796) F48(-64.83,-171.796) F49(-65.955,-170.796) F50(-64.83,-169.796) F51(-65.955,-168.796) F52(-64.83,-167.796) F53(-65.955,-166.796) F54(-64.83,-165.796) F55(-65.955,-164.796) F56(-64.83,-163.796) F57(-65.955,-162.796) F58(-64.83,-161.796) F59(-65.955,-160.796) F60(-64.83,-159.796) F61(-65.955,-158.796) Z5(-52.456,-214.796) Z7(-52.456,-212.796) Z9(-52.456,-210.796) Z11(-52.456,-208.796) Z13(-52.456,-206.796) Z15(-52.456,-204.796) Z17(-52.456,-202.796) Z19(-52.456,-200.796) Z21(-52.456,-198.796) Z23(-52.456,-196.796) Z25(-52.456,-194.796) Z27(-52.456,-192.796) Z29(-52.456,-190.796) Z31(-52.456,-188.796) Z33(-52.456,-186.796) Z35(-52.456,-184.796) Z37(-52.456,-182.796) Z39(-52.456,-180.796) Z41(-52.456,-178.796) Z43(-52.456,-176.796) Z45(-52.456,-174.796) Z47(-52.456,-172.796) Z49(-52.456,-170.796) Z51(-52.456,-168.796) Z53(-52.456,-166.796) Z55(-52.456,-164.796) Z57(-52.456,-162.796) Z59(-52.456,-160.796) Z61(-52.456,-158.796)
PG_LTXDX_F_X1_PG400ND_SL07_V3
  round 0.508 hole 3.2 unplated: (-37.184,154.842)
  round 0.051 hole 2.489x2.21 unplated: (-36.184,220.342)
  rect 1.016x1.016 smd: A1(-41.814,218.796)
  round 1.016 smd: A2(-42.939,217.796) A3(-41.814,216.796) A4(-42.939,215.796) B1(-39.565,218.796) B2(-40.69,217.796) B3(-39.565,216.796) B4(-40.69,215.796) B62(-40.69,157.796) C1(-37.314,218.796) C2(-38.44,217.796) C3(-37.314,216.796) C4(-38.44,215.796) C62(-38.44,157.796) D1(-35.064,218.796) D2(-36.189,217.796) D3(-35.064,216.796) D4(-36.189,215.796) E1(-32.815,218.796) E2(-33.939,217.796) E3(-32.815,216.796) E4(-33.939,215.796) E62(-33.939,157.796) F1(-30.565,218.796) F2(-31.69,217.796) F3(-30.565,216.796) F4(-31.69,215.796) F62(-31.69,157.796) G2(-29.44,217.796) G4(-29.44,215.796) G6(-29.44,213.796) G8(-29.44,211.796) G10(-29.44,209.796) G12(-29.44,207.796) G14(-29.44,205.796) G16(-29.44,203.796) G18(-29.44,201.796) G20(-29.44,199.796) G22(-29.44,197.796) G24(-29.44,195.796) G26(-29.44,193.796) G28(-29.44,191.796) G30(-29.44,189.796) G32(-29.44,187.796) G34(-29.44,185.796) G36(-29.44,183.796) G38(-29.44,181.796) G40(-29.44,179.796) G42(-29.44,177.796) G44(-29.44,175.796) G46(-29.44,173.796) G48(-29.44,171.796) G50(-29.44,169.796) G52(-29.44,167.796) G54(-29.44,165.796) G56(-29.44,163.796) G58(-29.44,161.796) G60(-29.44,159.796)
  custom 0.257x0.257 smd: A5(-41.814,214.796) A6(-42.939,213.796) A7(-41.814,212.796) A8(-42.939,211.796) A9(-41.814,210.796) A10(-42.939,209.796) A11(-41.814,208.796) A12(-42.939,207.796) A13(-41.814,206.796) A14(-42.939,205.796) A15(-41.814,204.796) A16(-42.939,203.796) A17(-41.814,202.796) A18(-42.939,201.796) A19(-41.814,200.796) A20(-42.939,199.796) A21(-41.814,198.796) A22(-42.939,197.796) A23(-41.814,196.796) A24(-42.939,195.796) A25(-41.814,194.796) A26(-42.939,193.796) A27(-41.814,192.796) A28(-42.939,191.796) A29(-41.814,190.796) A30(-42.939,189.796) A31(-41.814,188.796) A32(-42.939,187.796) A33(-41.814,186.796) A34(-42.939,185.796) A35(-41.814,184.796) A36(-42.939,183.796) A37(-41.814,182.796) A38(-42.939,181.796) A39(-41.814,180.796) A40(-42.939,179.796) A41(-41.814,178.796) A42(-42.939,177.796) A43(-41.814,176.796) A44(-42.939,175.796) A45(-41.814,174.796) A46(-42.939,173.796) A47(-41.814,172.796) A48(-42.939,171.796) A49(-41.814,170.796) A50(-42.939,169.796) A51(-41.814,168.796) A52(-42.939,167.796) A53(-41.814,166.796) A54(-42.939,165.796) A55(-41.814,164.796) A56(-42.939,163.796) A57(-41.814,162.796) A58(-42.939,161.796) A59(-41.814,160.796) A60(-42.939,159.796) A61(-41.814,158.796) B5(-39.565,214.796) B6(-40.69,213.796) B7(-39.565,212.796) B8(-40.69,211.796) B9(-39.565,210.796) B10(-40.69,209.796) B11(-39.565,208.796) B12(-40.69,207.796) B13(-39.565,206.796) B14(-40.69,205.796) B15(-39.565,204.796) B16(-40.69,203.796) B17(-39.565,202.796) B18(-40.69,201.796) B19(-39.565,200.796) B20(-40.69,199.796) B21(-39.565,198.796) B22(-40.69,197.796) B23(-39.565,196.796) B24(-40.69,195.796) B25(-39.565,194.796) B26(-40.69,193.796) B27(-39.565,192.796) B28(-40.69,191.796) B29(-39.565,190.796) B30(-40.69,189.796) B31(-39.565,188.796) B32(-40.69,187.796) B33(-39.565,186.796) B34(-40.69,185.796) B35(-39.565,184.796) B36(-40.69,183.796) B37(-39.565,182.796) B38(-40.69,181.796) B39(-39.565,180.796) B40(-40.69,179.796) B41(-39.565,178.796) B42(-40.69,177.796) B43(-39.565,176.796) B44(-40.69,175.796) B45(-39.565,174.796) B46(-40.69,173.796) B47(-39.565,172.796) B48(-40.69,171.796) B49(-39.565,170.796) B50(-40.69,169.796) B51(-39.565,168.796) B52(-40.69,167.796) B53(-39.565,166.796) B54(-40.69,165.796) B55(-39.565,164.796) B56(-40.69,163.796) B57(-39.565,162.796) B58(-40.69,161.796) B59(-39.565,160.796) B60(-40.69,159.796) B61(-39.565,158.796) C5(-37.314,214.796) C6(-38.44,213.796) C7(-37.314,212.796) C8(-38.44,211.796) C9(-37.314,210.796) C10(-38.44,209.796) C11(-37.314,208.796) C12(-38.44,207.796) C13(-37.314,206.796) C14(-38.44,205.796) C15(-37.314,204.796) C16(-38.44,203.796) C17(-37.314,202.796) C18(-38.44,201.796) C19(-37.314,200.796) C20(-38.44,199.796) C21(-37.314,198.796) C22(-38.44,197.796) C23(-37.314,196.796) C24(-38.44,195.796) C25(-37.314,194.796) C26(-38.44,193.796) C27(-37.314,192.796) C28(-38.44,191.796) C29(-37.314,190.796) C30(-38.44,189.796) C31(-37.314,188.796) C32(-38.44,187.796) C33(-37.314,186.796) C34(-38.44,185.796) C35(-37.314,184.796) C36(-38.44,183.796) C37(-37.314,182.796) C38(-38.44,181.796) C39(-37.314,180.796) C40(-38.44,179.796) C41(-37.314,178.796) C42(-38.44,177.796) C43(-37.314,176.796) C44(-38.44,175.796) C45(-37.314,174.796) C46(-38.44,173.796) C47(-37.314,172.796) C48(-38.44,171.796) C49(-37.314,170.796) C50(-38.44,169.796) C51(-37.314,168.796) C52(-38.44,167.796) C53(-37.314,166.796) C54(-38.44,165.796) C55(-37.314,164.796) C56(-38.44,163.796) C57(-37.314,162.796) C58(-38.44,161.796) C59(-37.314,160.796) C60(-38.44,159.796) C61(-37.314,158.796) D5(-35.064,214.796) D6(-36.189,213.796) D7(-35.064,212.796) D8(-36.189,211.796) D9(-35.064,210.796) D10(-36.189,209.796) D11(-35.064,208.796) D12(-36.189,207.796) D13(-35.064,206.796) D14(-36.189,205.796) D15(-35.064,204.796) D16(-36.189,203.796) D17(-35.064,202.796) D18(-36.189,201.796) D19(-35.064,200.796) D20(-36.189,199.796) D21(-35.064,198.796) D22(-36.189,197.796) D23(-35.064,196.796) D24(-36.189,195.796) D25(-35.064,194.796) D26(-36.189,193.796) D27(-35.064,192.796) D28(-36.189,191.796) D29(-35.064,190.796) D30(-36.189,189.796) D31(-35.064,188.796) D32(-36.189,187.796) D33(-35.064,186.796) D34(-36.189,185.796) D35(-35.064,184.796) D36(-36.189,183.796) D37(-35.064,182.796) D38(-36.189,181.796) D39(-35.064,180.796) D40(-36.189,179.796) D41(-35.064,178.796) D42(-36.189,177.796) D43(-35.064,176.796) D44(-36.189,175.796) D45(-35.064,174.796) D46(-36.189,173.796) D47(-35.064,172.796) D48(-36.189,171.796) D49(-35.064,170.796) D50(-36.189,169.796) D51(-35.064,168.796) D52(-36.189,167.796) D53(-35.064,166.796) D54(-36.189,165.796) D55(-35.064,164.796) D56(-36.189,163.796) D57(-35.064,162.796) D58(-36.189,161.796) D59(-35.064,160.796) D60(-36.189,159.796) D61(-35.064,158.796) E5(-32.815,214.796) E6(-33.939,213.796) E7(-32.815,212.796) E8(-33.939,211.796) E9(-32.815,210.796) E10(-33.939,209.796) E11(-32.815,208.796) E12(-33.939,207.796) E13(-32.815,206.796) E14(-33.939,205.796) E15(-32.815,204.796) E16(-33.939,203.796) E17(-32.815,202.796) E18(-33.939,201.796) E19(-32.815,200.796) E20(-33.939,199.796) E21(-32.815,198.796) E22(-33.939,197.796) E23(-32.815,196.796) E24(-33.939,195.796) E25(-32.815,194.796) E26(-33.939,193.796) E27(-32.815,192.796) E28(-33.939,191.796) E29(-32.815,190.796) E30(-33.939,189.796) E31(-32.815,188.796) E32(-33.939,187.796) E33(-32.815,186.796) E34(-33.939,185.796) E35(-32.815,184.796) E36(-33.939,183.796) E37(-32.815,182.796) E38(-33.939,181.796) E39(-32.815,180.796) E40(-33.939,179.796) E41(-32.815,178.796) E42(-33.939,177.796) E43(-32.815,176.796) E44(-33.939,175.796) E45(-32.815,174.796) E46(-33.939,173.796) E47(-32.815,172.796) E48(-33.939,171.796) E49(-32.815,170.796) E50(-33.939,169.796) E51(-32.815,168.796) E52(-33.939,167.796) E53(-32.815,166.796) E54(-33.939,165.796) E55(-32.815,164.796) E56(-33.939,163.796) E57(-32.815,162.796) E58(-33.939,161.796) E59(-32.815,160.796) E60(-33.939,159.796) E61(-32.815,158.796) F5(-30.565,214.796) F6(-31.69,213.796) F7(-30.565,212.796) F8(-31.69,211.796) F9(-30.565,210.796) F10(-31.69,209.796) F11(-30.565,208.796) F12(-31.69,207.796) F13(-30.565,206.796) F14(-31.69,205.796) F15(-30.565,204.796) F16(-31.69,203.796) F17(-30.565,202.796) F18(-31.69,201.796) F19(-30.565,200.796) F20(-31.69,199.796) F21(-30.565,198.796) F22(-31.69,197.796) F23(-30.565,196.796) F24(-31.69,195.796) F25(-30.565,194.796) F26(-31.69,193.796) F27(-30.565,192.796) F28(-31.69,191.796) F29(-30.565,190.796) F30(-31.69,189.796) F31(-30.565,188.796) F32(-31.69,187.796) F33(-30.565,186.796) F34(-31.69,185.796) F35(-30.565,184.796) F36(-31.69,183.796) F37(-30.565,182.796) F38(-31.69,181.796) F39(-30.565,180.796) F40(-31.69,179.796) F41(-30.565,178.796) F42(-31.69,177.796) F43(-30.565,176.796) F44(-31.69,175.796) F45(-30.565,174.796) F46(-31.69,173.796) F47(-30.565,172.796) F48(-31.69,171.796) F49(-30.565,170.796) F50(-31.69,169.796) F51(-30.565,168.796) F52(-31.69,167.796) F53(-30.565,166.796) F54(-31.69,165.796) F55(-30.565,164.796) F56(-31.69,163.796) F57(-30.565,162.796) F58(-31.69,161.796) F59(-30.565,160.796) F60(-31.69,159.796) F61(-30.565,158.796) Z5(-44.064,214.796) Z7(-44.064,212.796) Z9(-44.064,210.796) Z11(-44.064,208.796) Z13(-44.064,206.796) Z15(-44.064,204.796) Z17(-44.064,202.796) Z19(-44.064,200.796) Z21(-44.064,198.796) Z23(-44.064,196.796) Z25(-44.064,194.796) Z27(-44.064,192.796) Z29(-44.064,190.796) Z31(-44.064,188.796) Z33(-44.064,186.796) Z35(-44.064,184.796) Z37(-44.064,182.796) Z39(-44.064,180.796) Z41(-44.064,178.796) Z43(-44.064,176.796) Z45(-44.064,174.796) Z47(-44.064,172.796) Z49(-44.064,170.796) Z51(-44.064,168.796) Z53(-44.064,166.796) Z55(-44.064,164.796) Z57(-44.064,162.796) Z59(-44.064,160.796) Z61(-44.064,158.796)
PG_LTXDX_F_X1_PG400ND_SL08_V3
  round 0.051 hole 2.489x2.21 unplated: (-12.075,-220.342)
  round 0.508 hole 3.2 unplated: (-11.075,-154.842)
  rect 1.016x1.016 smd: A1(-6.446,-218.796)
  round 1.016 smd: A2(-5.321,-217.796) A3(-6.446,-216.796) A4(-5.321,-215.796) B1(-8.695,-218.796) B2(-7.57,-217.796) B3(-8.695,-216.796) B4(-7.57,-215.796) B62(-7.57,-157.796) C1(-10.946,-218.796) C2(-9.82,-217.796) C3(-10.946,-216.796) C4(-9.82,-215.796) C62(-9.82,-157.796) D1(-13.196,-218.796) D2(-12.071,-217.796) D3(-13.196,-216.796) D4(-12.071,-215.796) E1(-15.445,-218.796) E2(-14.321,-217.796) E3(-15.445,-216.796) E4(-14.321,-215.796) E62(-14.321,-157.796) F1(-17.695,-218.796) F2(-16.57,-217.796) F3(-17.695,-216.796) F4(-16.57,-215.796) F62(-16.57,-157.796) G2(-18.82,-217.796) G4(-18.82,-215.796) G6(-18.82,-213.796) G8(-18.82,-211.796) G10(-18.82,-209.796) G12(-18.82,-207.796) G14(-18.82,-205.796) G16(-18.82,-203.796) G18(-18.82,-201.796) G20(-18.82,-199.796) G22(-18.82,-197.796) G24(-18.82,-195.796) G26(-18.82,-193.796) G28(-18.82,-191.796) G30(-18.82,-189.796) G32(-18.82,-187.796) G34(-18.82,-185.796) G36(-18.82,-183.796) G38(-18.82,-181.796) G40(-18.82,-179.796) G42(-18.82,-177.796) G44(-18.82,-175.796) G46(-18.82,-173.796) G48(-18.82,-171.796) G50(-18.82,-169.796) G52(-18.82,-167.796) G54(-18.82,-165.796) G56(-18.82,-163.796) G58(-18.82,-161.796) G60(-18.82,-159.796)
  custom 0.257x0.257 smd: A5(-6.446,-214.796) A6(-5.321,-213.796) A7(-6.446,-212.796) A8(-5.321,-211.796) A9(-6.446,-210.796) A10(-5.321,-209.796) A11(-6.446,-208.796) A12(-5.321,-207.796) A13(-6.446,-206.796) A14(-5.321,-205.796) A15(-6.446,-204.796) A16(-5.321,-203.796) A17(-6.446,-202.796) A18(-5.321,-201.796) A19(-6.446,-200.796) A20(-5.321,-199.796) A21(-6.446,-198.796) A22(-5.321,-197.796) A23(-6.446,-196.796) A24(-5.321,-195.796) A25(-6.446,-194.796) A26(-5.321,-193.796) A27(-6.446,-192.796) A28(-5.321,-191.796) A29(-6.446,-190.796) A30(-5.321,-189.796) A31(-6.446,-188.796) A32(-5.321,-187.796) A33(-6.446,-186.796) A34(-5.321,-185.796) A35(-6.446,-184.796) A36(-5.321,-183.796) A37(-6.446,-182.796) A38(-5.321,-181.796) A39(-6.446,-180.796) A40(-5.321,-179.796) A41(-6.446,-178.796) A42(-5.321,-177.796) A43(-6.446,-176.796) A44(-5.321,-175.796) A45(-6.446,-174.796) A46(-5.321,-173.796) A47(-6.446,-172.796) A48(-5.321,-171.796) A49(-6.446,-170.796) A50(-5.321,-169.796) A51(-6.446,-168.796) A52(-5.321,-167.796) A53(-6.446,-166.796) A54(-5.321,-165.796) A55(-6.446,-164.796) A56(-5.321,-163.796) A57(-6.446,-162.796) A58(-5.321,-161.796) A59(-6.446,-160.796) A60(-5.321,-159.796) A61(-6.446,-158.796) B5(-8.695,-214.796) B6(-7.57,-213.796) B7(-8.695,-212.796) B8(-7.57,-211.796) B9(-8.695,-210.796) B10(-7.57,-209.796) B11(-8.695,-208.796) B12(-7.57,-207.796) B13(-8.695,-206.796) B14(-7.57,-205.796) B15(-8.695,-204.796) B16(-7.57,-203.796) B17(-8.695,-202.796) B18(-7.57,-201.796) B19(-8.695,-200.796) B20(-7.57,-199.796) B21(-8.695,-198.796) B22(-7.57,-197.796) B23(-8.695,-196.796) B24(-7.57,-195.796) B25(-8.695,-194.796) B26(-7.57,-193.796) B27(-8.695,-192.796) B28(-7.57,-191.796) B29(-8.695,-190.796) B30(-7.57,-189.796) B31(-8.695,-188.796) B32(-7.57,-187.796) B33(-8.695,-186.796) B34(-7.57,-185.796) B35(-8.695,-184.796) B36(-7.57,-183.796) B37(-8.695,-182.796) B38(-7.57,-181.796) B39(-8.695,-180.796) B40(-7.57,-179.796) B41(-8.695,-178.796) B42(-7.57,-177.796) B43(-8.695,-176.796) B44(-7.57,-175.796) B45(-8.695,-174.796) B46(-7.57,-173.796) B47(-8.695,-172.796) B48(-7.57,-171.796) B49(-8.695,-170.796) B50(-7.57,-169.796) B51(-8.695,-168.796) B52(-7.57,-167.796) B53(-8.695,-166.796) B54(-7.57,-165.796) B55(-8.695,-164.796) B56(-7.57,-163.796) B57(-8.695,-162.796) B58(-7.57,-161.796) B59(-8.695,-160.796) B60(-7.57,-159.796) B61(-8.695,-158.796) C5(-10.946,-214.796) C6(-9.82,-213.796) C7(-10.946,-212.796) C8(-9.82,-211.796) C9(-10.946,-210.796) C10(-9.82,-209.796) C11(-10.946,-208.796) C12(-9.82,-207.796) C13(-10.946,-206.796) C14(-9.82,-205.796) C15(-10.946,-204.796) C16(-9.82,-203.796) C17(-10.946,-202.796) C18(-9.82,-201.796) C19(-10.946,-200.796) C20(-9.82,-199.796) C21(-10.946,-198.796) C22(-9.82,-197.796) C23(-10.946,-196.796) C24(-9.82,-195.796) C25(-10.946,-194.796) C26(-9.82,-193.796) C27(-10.946,-192.796) C28(-9.82,-191.796) C29(-10.946,-190.796) C30(-9.82,-189.796) C31(-10.946,-188.796) C32(-9.82,-187.796) C33(-10.946,-186.796) C34(-9.82,-185.796) C35(-10.946,-184.796) C36(-9.82,-183.796) C37(-10.946,-182.796) C38(-9.82,-181.796) C39(-10.946,-180.796) C40(-9.82,-179.796) C41(-10.946,-178.796) C42(-9.82,-177.796) C43(-10.946,-176.796) C44(-9.82,-175.796) C45(-10.946,-174.796) C46(-9.82,-173.796) C47(-10.946,-172.796) C48(-9.82,-171.796) C49(-10.946,-170.796) C50(-9.82,-169.796) C51(-10.946,-168.796) C52(-9.82,-167.796) C53(-10.946,-166.796) C54(-9.82,-165.796) C55(-10.946,-164.796) C56(-9.82,-163.796) C57(-10.946,-162.796) C58(-9.82,-161.796) C59(-10.946,-160.796) C60(-9.82,-159.796) C61(-10.946,-158.796) D5(-13.196,-214.796) D6(-12.071,-213.796) D7(-13.196,-212.796) D8(-12.071,-211.796) D9(-13.196,-210.796) D10(-12.071,-209.796) D11(-13.196,-208.796) D12(-12.071,-207.796) D13(-13.196,-206.796) D14(-12.071,-205.796) D15(-13.196,-204.796) D16(-12.071,-203.796) D17(-13.196,-202.796) D18(-12.071,-201.796) D19(-13.196,-200.796) D20(-12.071,-199.796) D21(-13.196,-198.796) D22(-12.071,-197.796) D23(-13.196,-196.796) D24(-12.071,-195.796) D25(-13.196,-194.796) D26(-12.071,-193.796) D27(-13.196,-192.796) D28(-12.071,-191.796) D29(-13.196,-190.796) D30(-12.071,-189.796) D31(-13.196,-188.796) D32(-12.071,-187.796) D33(-13.196,-186.796) D34(-12.071,-185.796) D35(-13.196,-184.796) D36(-12.071,-183.796) D37(-13.196,-182.796) D38(-12.071,-181.796) D39(-13.196,-180.796) D40(-12.071,-179.796) D41(-13.196,-178.796) D42(-12.071,-177.796) D43(-13.196,-176.796) D44(-12.071,-175.796) D45(-13.196,-174.796) D46(-12.071,-173.796) D47(-13.196,-172.796) D48(-12.071,-171.796) D49(-13.196,-170.796) D50(-12.071,-169.796) D51(-13.196,-168.796) D52(-12.071,-167.796) D53(-13.196,-166.796) D54(-12.071,-165.796) D55(-13.196,-164.796) D56(-12.071,-163.796) D57(-13.196,-162.796) D58(-12.071,-161.796) D59(-13.196,-160.796) D60(-12.071,-159.796) D61(-13.196,-158.796) E5(-15.445,-214.796) E6(-14.321,-213.796) E7(-15.445,-212.796) E8(-14.321,-211.796) E9(-15.445,-210.796) E10(-14.321,-209.796) E11(-15.445,-208.796) E12(-14.321,-207.796) E13(-15.445,-206.796) E14(-14.321,-205.796) E15(-15.445,-204.796) E16(-14.321,-203.796) E17(-15.445,-202.796) E18(-14.321,-201.796) E19(-15.445,-200.796) E20(-14.321,-199.796) E21(-15.445,-198.796) E22(-14.321,-197.796) E23(-15.445,-196.796) E24(-14.321,-195.796) E25(-15.445,-194.796) E26(-14.321,-193.796) E27(-15.445,-192.796) E28(-14.321,-191.796) E29(-15.445,-190.796) E30(-14.321,-189.796) E31(-15.445,-188.796) E32(-14.321,-187.796) E33(-15.445,-186.796) E34(-14.321,-185.796) E35(-15.445,-184.796) E36(-14.321,-183.796) E37(-15.445,-182.796) E38(-14.321,-181.796) E39(-15.445,-180.796) E40(-14.321,-179.796) E41(-15.445,-178.796) E42(-14.321,-177.796) E43(-15.445,-176.796) E44(-14.321,-175.796) E45(-15.445,-174.796) E46(-14.321,-173.796) E47(-15.445,-172.796) E48(-14.321,-171.796) E49(-15.445,-170.796) E50(-14.321,-169.796) E51(-15.445,-168.796) E52(-14.321,-167.796) E53(-15.445,-166.796) E54(-14.321,-165.796) E55(-15.445,-164.796) E56(-14.321,-163.796) E57(-15.445,-162.796) E58(-14.321,-161.796) E59(-15.445,-160.796) E60(-14.321,-159.796) E61(-15.445,-158.796) F5(-17.695,-214.796) F6(-16.57,-213.796) F7(-17.695,-212.796) F8(-16.57,-211.796) F9(-17.695,-210.796) F10(-16.57,-209.796) F11(-17.695,-208.796) F12(-16.57,-207.796) F13(-17.695,-206.796) F14(-16.57,-205.796) F15(-17.695,-204.796) F16(-16.57,-203.796) F17(-17.695,-202.796) F18(-16.57,-201.796) F19(-17.695,-200.796) F20(-16.57,-199.796) F21(-17.695,-198.796) F22(-16.57,-197.796) F23(-17.695,-196.796) F24(-16.57,-195.796) F25(-17.695,-194.796) F26(-16.57,-193.796) F27(-17.695,-192.796) F28(-16.57,-191.796) F29(-17.695,-190.796) F30(-16.57,-189.796) F31(-17.695,-188.796) F32(-16.57,-187.796) F33(-17.695,-186.796) F34(-16.57,-185.796) F35(-17.695,-184.796) F36(-16.57,-183.796) F37(-17.695,-182.796) F38(-16.57,-181.796) F39(-17.695,-180.796) F40(-16.57,-179.796) F41(-17.695,-178.796) F42(-16.57,-177.796) F43(-17.695,-176.796) F44(-16.57,-175.796) F45(-17.695,-174.796) F46(-16.57,-173.796) F47(-17.695,-172.796) F48(-16.57,-171.796) F49(-17.695,-170.796) F50(-16.57,-169.796) F51(-17.695,-168.796) F52(-16.57,-167.796) F53(-17.695,-166.796) F54(-16.57,-165.796) F55(-17.695,-164.796) F56(-16.57,-163.796) F57(-17.695,-162.796) F58(-16.57,-161.796) F59(-17.695,-160.796) F60(-16.57,-159.796) F61(-17.695,-158.796) Z5(-4.196,-214.796) Z7(-4.196,-212.796) Z9(-4.196,-210.796) Z11(-4.196,-208.796) Z13(-4.196,-206.796) Z15(-4.196,-204.796) Z17(-4.196,-202.796) Z19(-4.196,-200.796) Z21(-4.196,-198.796) Z23(-4.196,-196.796) Z25(-4.196,-194.796) Z27(-4.196,-192.796) Z29(-4.196,-190.796) Z31(-4.196,-188.796) Z33(-4.196,-186.796) Z35(-4.196,-184.796) Z37(-4.196,-182.796) Z39(-4.196,-180.796) Z41(-4.196,-178.796) Z43(-4.196,-176.796) Z45(-4.196,-174.796) Z47(-4.196,-172.796) Z49(-4.196,-170.796) Z51(-4.196,-168.796) Z53(-4.196,-166.796) Z55(-4.196,-164.796) Z57(-4.196,-162.796) Z59(-4.196,-160.796) Z61(-4.196,-158.796)
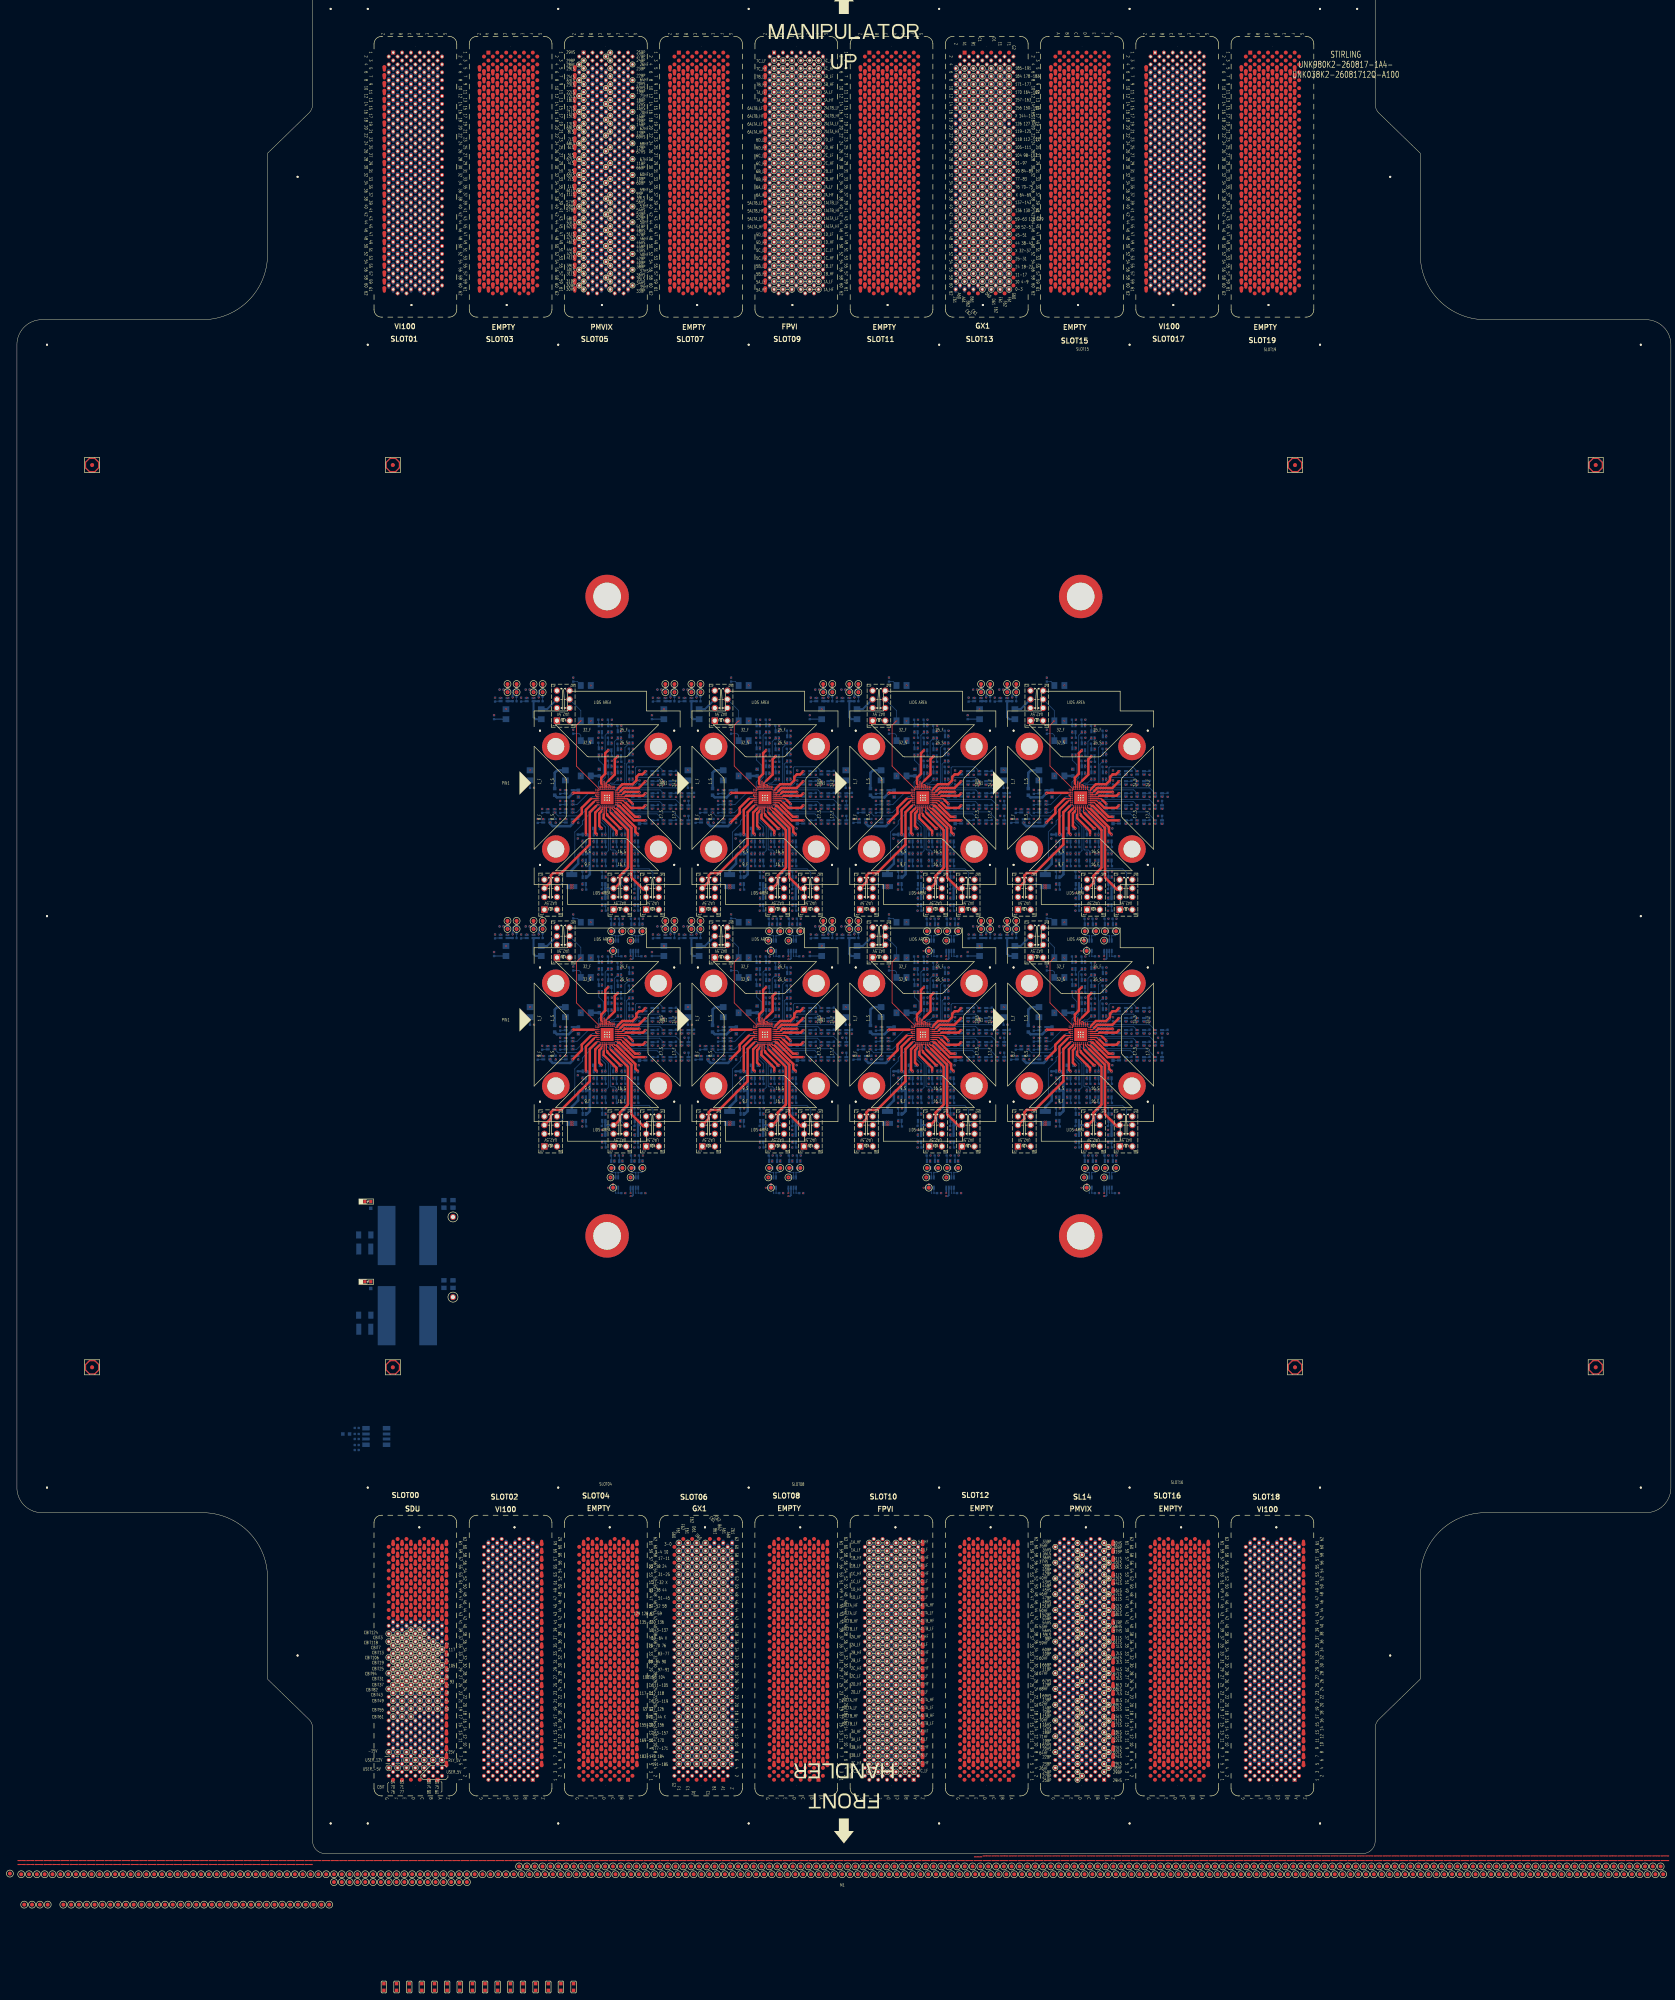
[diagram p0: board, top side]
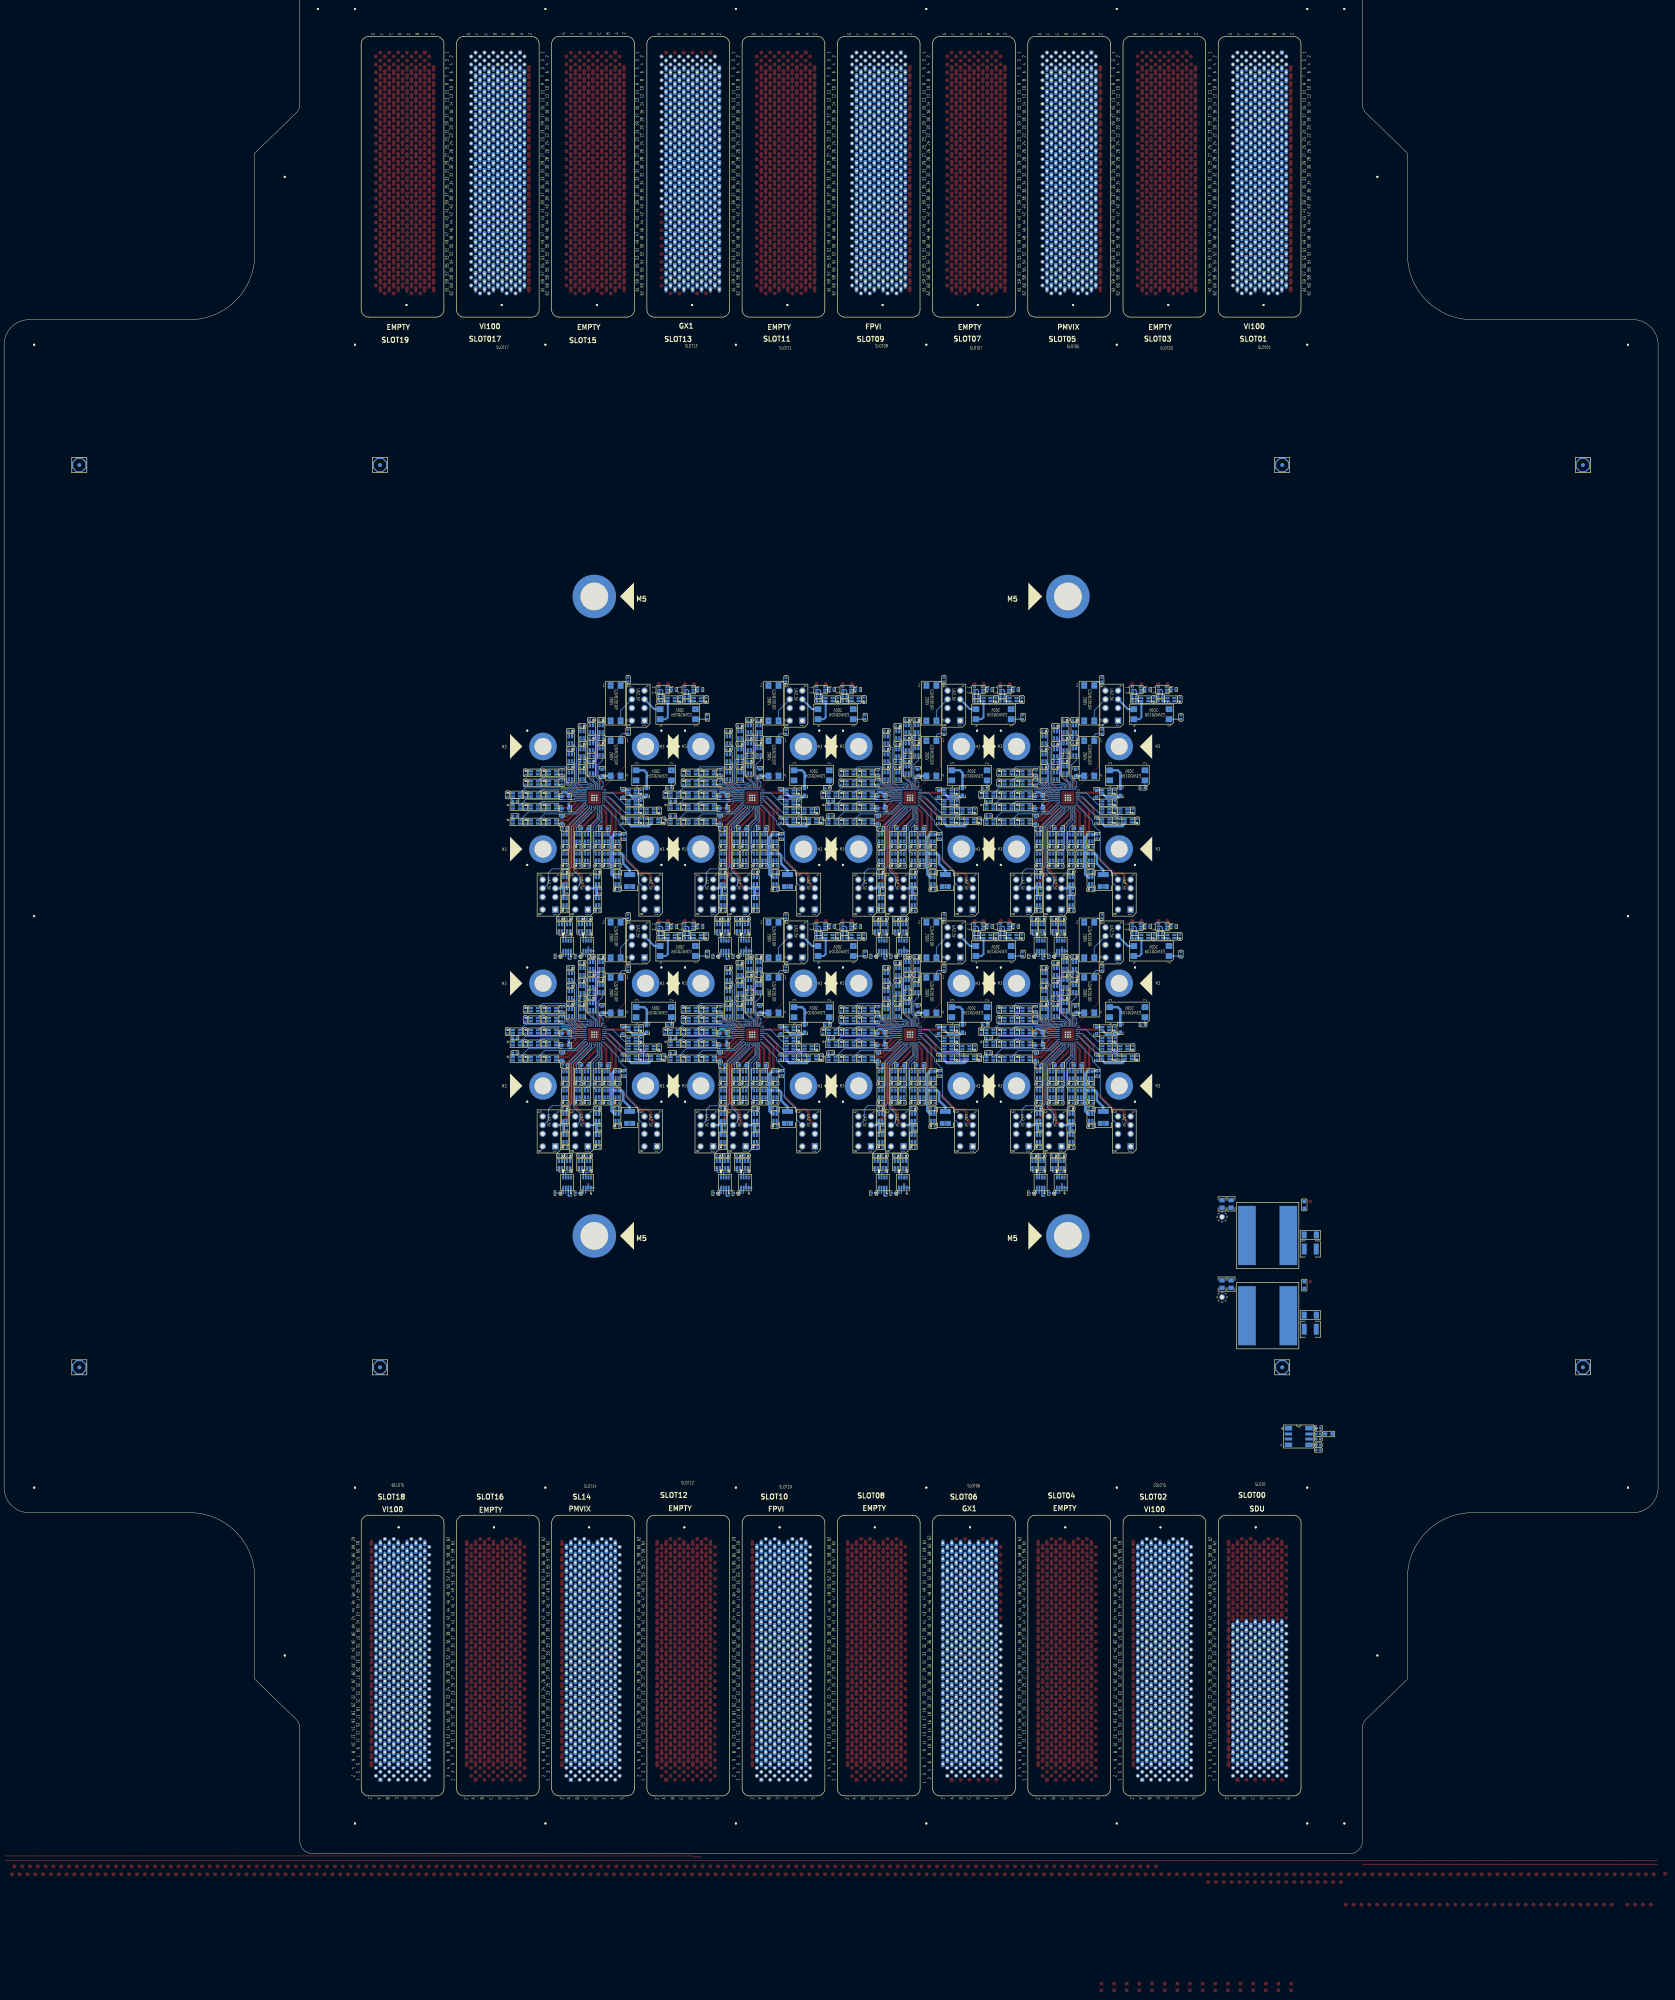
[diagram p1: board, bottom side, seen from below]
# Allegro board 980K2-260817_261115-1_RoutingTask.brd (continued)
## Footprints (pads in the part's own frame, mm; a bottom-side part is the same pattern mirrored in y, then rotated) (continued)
PG_LTXDX_F_X1_PMVI_SL14_V3
  round 0.051 hole 2.489x2.21 unplated: (60.315,-220.342)
  round 0.508 hole 3.2 unplated: (61.314,-154.842)
  rect 1.016x1.016 hole 0.559: A1(65.944,-218.796)
  round 1.016 hole 0.559: A2(67.069,-217.796) A3(65.944,-216.796) A4(67.069,-215.796) A5(65.944,-214.796) A6(67.069,-213.796) A7(65.944,-212.796) A8(67.069,-211.796) A9(65.944,-210.796) A10(67.069,-209.796) A11(65.944,-208.796) A12(67.069,-207.796) A13(65.944,-206.796) A14(67.069,-205.796) A15(65.944,-204.796) A16(67.069,-203.796) A17(65.944,-202.796) A18(67.069,-201.796) A19(65.944,-200.796) A20(67.069,-199.796) A21(65.944,-198.796) A22(67.069,-197.796) A23(65.944,-196.796) A24(67.069,-195.796) A25(65.944,-194.796) A26(67.069,-193.796) A27(65.944,-192.796) A28(67.069,-191.796) A29(65.944,-190.796) A30(67.069,-189.796) A31(65.944,-188.796) A32(67.069,-187.796) A33(65.944,-186.796) A34(67.069,-185.796) A35(65.944,-184.796) A36(67.069,-183.796) A37(65.944,-182.796) A38(67.069,-181.796) A39(65.944,-180.796) A40(67.069,-179.796) A41(65.944,-178.796) A42(67.069,-177.796) A43(65.944,-176.796) A44(67.069,-175.796) A45(65.944,-174.796) A46(67.069,-173.796) A47(65.944,-172.796) A48(67.069,-171.796) A49(65.944,-170.796) A50(67.069,-169.796) A51(65.944,-168.796) A52(67.069,-167.796) A53(65.944,-166.796) A54(67.069,-165.796) A55(65.944,-164.796) A56(67.069,-163.796) A57(65.944,-162.796) A58(67.069,-161.796) A59(65.944,-160.796) A60(67.069,-159.796) A61(65.944,-158.796) B1(63.695,-218.796) B2(64.82,-217.796) B3(63.695,-216.796) B4(64.82,-215.796) B5(63.695,-214.796) B6(64.82,-213.796) B7(63.695,-212.796) B8(64.82,-211.796) B9(63.695,-210.796) B10(64.82,-209.796) B11(63.695,-208.796) B12(64.82,-207.796) B13(63.695,-206.796) B14(64.82,-205.796) B15(63.695,-204.796) B16(64.82,-203.796) B17(63.695,-202.796) B18(64.82,-201.796) B19(63.695,-200.796) B20(64.82,-199.796) B21(63.695,-198.796) B22(64.82,-197.796) B23(63.695,-196.796) B24(64.82,-195.796) B25(63.695,-194.796) B26(64.82,-193.796) B27(63.695,-192.796) B28(64.82,-191.796) B29(63.695,-190.796) B30(64.82,-189.796) B31(63.695,-188.796) B32(64.82,-187.796) B33(63.695,-186.796) B34(64.82,-185.796) B35(63.695,-184.796) B36(64.82,-183.796) B37(63.695,-182.796) B38(64.82,-181.796) B39(63.695,-180.796) B40(64.82,-179.796) B41(63.695,-178.796) B42(64.82,-177.796) B43(63.695,-176.796) B44(64.82,-175.796) B45(63.695,-174.796) B46(64.82,-173.796) B47(63.695,-172.796) B48(64.82,-171.796) B49(63.695,-170.796) B50(64.82,-169.796) B51(63.695,-168.796) B52(64.82,-167.796) B53(63.695,-166.796) B54(64.82,-165.796) B55(63.695,-164.796) B56(64.82,-163.796) B57(63.695,-162.796) B58(64.82,-161.796) B59(63.695,-160.796) B60(64.82,-159.796) B61(63.695,-158.796) B62(64.82,-157.796) C1(61.444,-218.796) C2(62.57,-217.796) C3(61.444,-216.796) C4(62.57,-215.796) C5(61.444,-214.796) C6(62.57,-213.796) C7(61.444,-212.796) C8(62.57,-211.796) C9(61.444,-210.796) C10(62.57,-209.796) C11(61.444,-208.796) C12(62.57,-207.796) C13(61.444,-206.796) C14(62.57,-205.796) C15(61.444,-204.796) C16(62.57,-203.796) C17(61.444,-202.796) C18(62.57,-201.796) C19(61.444,-200.796) C20(62.57,-199.796) C21(61.444,-198.796) C22(62.57,-197.796) C23(61.444,-196.796) C24(62.57,-195.796) C25(61.444,-194.796) C26(62.57,-193.796) C27(61.444,-192.796) C28(62.57,-191.796) C29(61.444,-190.796) C30(62.57,-189.796) C31(61.444,-188.796) C32(62.57,-187.796) C33(61.444,-186.796) C34(62.57,-185.796) C35(61.444,-184.796) C36(62.57,-183.796) C37(61.444,-182.796) C38(62.57,-181.796) C39(61.444,-180.796) C40(62.57,-179.796) C41(61.444,-178.796) C42(62.57,-177.796) C43(61.444,-176.796) C44(62.57,-175.796) C45(61.444,-174.796) C46(62.57,-173.796) C47(61.444,-172.796) C48(62.57,-171.796) C49(61.444,-170.796) C50(62.57,-169.796) C51(61.444,-168.796) C52(62.57,-167.796) C53(61.444,-166.796) C54(62.57,-165.796) C55(61.444,-164.796) C56(62.57,-163.796) C57(61.444,-162.796) C58(62.57,-161.796) C59(61.444,-160.796) C60(62.57,-159.796) C61(61.444,-158.796) C62(62.57,-157.796) D1(59.194,-218.796) D2(60.319,-217.796) D3(59.194,-216.796) D4(60.319,-215.796) D5(59.194,-214.796) D6(60.319,-213.796) D7(59.194,-212.796) D8(60.319,-211.796) D9(59.194,-210.796) D10(60.319,-209.796) D11(59.194,-208.796) D12(60.319,-207.796) D13(59.194,-206.796) D14(60.319,-205.796) D15(59.194,-204.796) D16(60.319,-203.796) D17(59.194,-202.796) D18(60.319,-201.796) D19(59.194,-200.796) D20(60.319,-199.796) D21(59.194,-198.796) D22(60.319,-197.796) D23(59.194,-196.796) D24(60.319,-195.796) D25(59.194,-194.796) D26(60.319,-193.796) D27(59.194,-192.796) D28(60.319,-191.796) D29(59.194,-190.796) D30(60.319,-189.796) D31(59.194,-188.796) D32(60.319,-187.796) D33(59.194,-186.796) D34(60.319,-185.796) D35(59.194,-184.796) D36(60.319,-183.796) D37(59.194,-182.796) D38(60.319,-181.796) D39(59.194,-180.796) D40(60.319,-179.796) D41(59.194,-178.796) D42(60.319,-177.796) D43(59.194,-176.796) D44(60.319,-175.796) D45(59.194,-174.796) D46(60.319,-173.796) D47(59.194,-172.796) D48(60.319,-171.796) D49(59.194,-170.796) D50(60.319,-169.796) D51(59.194,-168.796) D52(60.319,-167.796) D53(59.194,-166.796) D54(60.319,-165.796) D55(59.194,-164.796) D56(60.319,-163.796) D57(59.194,-162.796) D58(60.319,-161.796) D59(59.194,-160.796) D60(60.319,-159.796) D61(59.194,-158.796) E1(56.945,-218.796) E2(58.069,-217.796) E3(56.945,-216.796) E4(58.069,-215.796) E5(56.945,-214.796) E6(58.069,-213.796) E7(56.945,-212.796) E8(58.069,-211.796) E9(56.945,-210.796) E10(58.069,-209.796) E11(56.945,-208.796) E12(58.069,-207.796) E13(56.945,-206.796) E14(58.069,-205.796) E15(56.945,-204.796) E16(58.069,-203.796) E17(56.945,-202.796) E18(58.069,-201.796) E19(56.945,-200.796) E20(58.069,-199.796) E21(56.945,-198.796) E22(58.069,-197.796) E23(56.945,-196.796) E24(58.069,-195.796) E25(56.945,-194.796) E26(58.069,-193.796) E27(56.945,-192.796) E28(58.069,-191.796) E29(56.945,-190.796) E30(58.069,-189.796) E31(56.945,-188.796) E32(58.069,-187.796) E33(56.945,-186.796) E34(58.069,-185.796) E35(56.945,-184.796) E36(58.069,-183.796) E37(56.945,-182.796) E38(58.069,-181.796) E39(56.945,-180.796) E40(58.069,-179.796) E41(56.945,-178.796) E42(58.069,-177.796) E43(56.945,-176.796) E44(58.069,-175.796) E45(56.945,-174.796) E46(58.069,-173.796) E47(56.945,-172.796) E48(58.069,-171.796) E49(56.945,-170.796) E50(58.069,-169.796) E51(56.945,-168.796) E52(58.069,-167.796) E53(56.945,-166.796) E54(58.069,-165.796) E55(56.945,-164.796) E56(58.069,-163.796) E57(56.945,-162.796) E58(58.069,-161.796) E59(56.945,-160.796) E60(58.069,-159.796) E61(56.945,-158.796) E62(58.069,-157.796) F1(54.695,-218.796) F2(55.82,-217.796) F3(54.695,-216.796) F4(55.82,-215.796) F5(54.695,-214.796) F6(55.82,-213.796) F7(54.695,-212.796) F8(55.82,-211.796) F9(54.695,-210.796) F10(55.82,-209.796) F11(54.695,-208.796) F12(55.82,-207.796) F13(54.695,-206.796) F14(55.82,-205.796) F15(54.695,-204.796) F16(55.82,-203.796) F17(54.695,-202.796) F18(55.82,-201.796) F19(54.695,-200.796) F20(55.82,-199.796) F21(54.695,-198.796) F22(55.82,-197.796) F23(54.695,-196.796) F24(55.82,-195.796) F25(54.695,-194.796) F26(55.82,-193.796) F27(54.695,-192.796) F28(55.82,-191.796) F29(54.695,-190.796) F30(55.82,-189.796) F31(54.695,-188.796) F32(55.82,-187.796) F33(54.695,-186.796) F34(55.82,-185.796) F35(54.695,-184.796) F36(55.82,-183.796) F37(54.695,-182.796) F38(55.82,-181.796) F39(54.695,-180.796) F40(55.82,-179.796) F41(54.695,-178.796) F42(55.82,-177.796) F43(54.695,-176.796) F44(55.82,-175.796) F45(54.695,-174.796) F46(55.82,-173.796) F47(54.695,-172.796) F48(55.82,-171.796) F49(54.695,-170.796) F50(55.82,-169.796) F51(54.695,-168.796) F52(55.82,-167.796) F53(54.695,-166.796) F54(55.82,-165.796) F55(54.695,-164.796) F56(55.82,-163.796) F57(54.695,-162.796) F58(55.82,-161.796) F59(54.695,-160.796) F60(55.82,-159.796) F61(54.695,-158.796) F62(55.82,-157.796) G2(53.57,-217.796) G4(53.57,-215.796) G6(53.57,-213.796) G8(53.57,-211.796) G10(53.57,-209.796) G12(53.57,-207.796) G14(53.57,-205.796) G16(53.57,-203.796) G18(53.57,-201.796) G20(53.57,-199.796) G22(53.57,-197.796) G24(53.57,-195.796) G26(53.57,-193.796) G28(53.57,-191.796) G30(53.57,-189.796) G32(53.57,-187.796) G34(53.57,-185.796) G36(53.57,-183.796) G38(53.57,-181.796) G40(53.57,-179.796) G42(53.57,-177.796) G44(53.57,-175.796) G46(53.57,-173.796) G48(53.57,-171.796) G50(53.57,-169.796) G52(53.57,-167.796) G54(53.57,-165.796) G56(53.57,-163.796) G58(53.57,-161.796) G60(53.57,-159.796)
  custom 0.257x0.257 smd: Z5(68.194,-214.796) Z7(68.194,-212.796) Z9(68.194,-210.796) Z11(68.194,-208.796) Z13(68.194,-206.796) Z15(68.194,-204.796) Z17(68.194,-202.796) Z19(68.194,-200.796) Z21(68.194,-198.796) Z23(68.194,-196.796) Z25(68.194,-194.796) Z27(68.194,-192.796) Z29(68.194,-190.796) Z31(68.194,-188.796) Z33(68.194,-186.796) Z35(68.194,-184.796) Z37(68.194,-182.796) Z39(68.194,-180.796) Z41(68.194,-178.796) Z43(68.194,-176.796) Z45(68.194,-174.796) Z47(68.194,-172.796) Z49(68.194,-170.796) Z51(68.194,-168.796) Z53(68.194,-166.796) Z55(68.194,-164.796) Z57(68.194,-162.796) Z59(68.194,-160.796) Z61(68.194,-158.796)
PG_LTXDX_F_X1_SDU_SL00_V3
  round 0.051 hole 2.489x2.21 unplated: (-108.595,-220.342)
  round 0.508 hole 3.2 unplated: (-107.596,-154.842)
  rect 1.016x1.016 smd: A1(-102.966,-218.796)
  round 1.016 hole 0.559: A2(-101.841,-217.796) A3(-102.966,-216.796) A4(-101.841,-215.796) A5(-102.966,-214.796) A6(-101.841,-213.796) A7(-102.966,-212.796) A8(-101.841,-211.796) A9(-102.966,-210.796) A10(-101.841,-209.796) A11(-102.966,-208.796) A12(-101.841,-207.796) A13(-102.966,-206.796) A14(-101.841,-205.796) A15(-102.966,-204.796) A16(-101.841,-203.796) A17(-102.966,-202.796) A18(-101.841,-201.796) A19(-102.966,-200.796) A20(-101.841,-199.796) A21(-102.966,-198.796) A22(-101.841,-197.796) A23(-102.966,-196.796) A24(-101.841,-195.796) A25(-102.966,-194.796) A26(-101.841,-193.796) A27(-102.966,-192.796) A28(-101.841,-191.796) A29(-102.966,-190.796) A30(-101.841,-189.796) A31(-102.966,-188.796) A32(-101.841,-187.796) A33(-102.966,-186.796) A34(-101.841,-185.796) A35(-102.966,-184.796) A36(-101.841,-183.796) A37(-102.966,-182.796) A38(-101.841,-181.796) A39(-102.966,-180.796) A40(-101.841,-179.796) A41(-102.966,-178.796) B2(-104.09,-217.796) B3(-105.215,-216.796) B4(-104.09,-215.796) B5(-105.215,-214.796) B6(-104.09,-213.796) B7(-105.215,-212.796) B8(-104.09,-211.796) B9(-105.215,-210.796) B10(-104.09,-209.796) B11(-105.215,-208.796) B12(-104.09,-207.796) B13(-105.215,-206.796) B14(-104.09,-205.796) B15(-105.215,-204.796) B16(-104.09,-203.796) B17(-105.215,-202.796) B18(-104.09,-201.796) B19(-105.215,-200.796) B20(-104.09,-199.796) B21(-105.215,-198.796) B22(-104.09,-197.796) B23(-105.215,-196.796) B24(-104.09,-195.796) B25(-105.215,-194.796) B26(-104.09,-193.796) B27(-105.215,-192.796) B28(-104.09,-191.796) B29(-105.215,-190.796) B30(-104.09,-189.796) B31(-105.215,-188.796) B32(-104.09,-187.796) B33(-105.215,-186.796) B34(-104.09,-185.796) B35(-105.215,-184.796) B36(-104.09,-183.796) B37(-105.215,-182.796) B38(-104.09,-181.796) B39(-105.215,-180.796) B40(-104.09,-179.796) B41(-105.215,-178.796) C2(-106.34,-217.796) C3(-107.466,-216.796) C4(-106.34,-215.796) C5(-107.466,-214.796) C6(-106.34,-213.796) C7(-107.466,-212.796) C8(-106.34,-211.796) C9(-107.466,-210.796) C10(-106.34,-209.796) C11(-107.466,-208.796) C12(-106.34,-207.796) C13(-107.466,-206.796) C14(-106.34,-205.796) C15(-107.466,-204.796) C16(-106.34,-203.796) C17(-107.466,-202.796) C18(-106.34,-201.796) C19(-107.466,-200.796) C20(-106.34,-199.796) C21(-107.466,-198.796) C22(-106.34,-197.796) C23(-107.466,-196.796) C24(-106.34,-195.796) C25(-107.466,-194.796) C26(-106.34,-193.796) C27(-107.466,-192.796) C28(-106.34,-191.796) C29(-107.466,-190.796) C30(-106.34,-189.796) C31(-107.466,-188.796) C32(-106.34,-187.796) C33(-107.466,-186.796) C34(-106.34,-185.796) C35(-107.466,-184.796) C36(-106.34,-183.796) C37(-107.466,-182.796) C38(-106.34,-181.796) C39(-107.466,-180.796) C40(-106.34,-179.796) C41(-107.466,-178.796) D2(-108.591,-217.796) D3(-109.716,-216.796) D4(-108.591,-215.796) D5(-109.716,-214.796) D6(-108.591,-213.796) D7(-109.716,-212.796) D8(-108.591,-211.796) D9(-109.716,-210.796) D10(-108.591,-209.796) D11(-109.716,-208.796) D12(-108.591,-207.796) D13(-109.716,-206.796) D14(-108.591,-205.796) D15(-109.716,-204.796) D16(-108.591,-203.796) D17(-109.716,-202.796) D18(-108.591,-201.796) D19(-109.716,-200.796) D20(-108.591,-199.796) D21(-109.716,-198.796) D22(-108.591,-197.796) D23(-109.716,-196.796) D24(-108.591,-195.796) D25(-109.716,-194.796) D26(-108.591,-193.796) D27(-109.716,-192.796) D28(-108.591,-191.796) D29(-109.716,-190.796) D30(-108.591,-189.796) D31(-109.716,-188.796) D32(-108.591,-187.796) D33(-109.716,-186.796) D34(-108.591,-185.796) D35(-109.716,-184.796) D36(-108.591,-183.796) D37(-109.716,-182.796) D38(-108.591,-181.796) D39(-109.716,-180.796) D40(-108.591,-179.796) D41(-109.716,-178.796) E2(-110.841,-217.796) E3(-111.965,-216.796) E4(-110.841,-215.796) E5(-111.965,-214.796) E6(-110.841,-213.796) E7(-111.965,-212.796) E8(-110.841,-211.796) E9(-111.965,-210.796) E10(-110.841,-209.796) E11(-111.965,-208.796) E12(-110.841,-207.796) E13(-111.965,-206.796) E14(-110.841,-205.796) E15(-111.965,-204.796) E16(-110.841,-203.796) E17(-111.965,-202.796) E18(-110.841,-201.796) E19(-111.965,-200.796) E20(-110.841,-199.796) E21(-111.965,-198.796) E22(-110.841,-197.796) E23(-111.965,-196.796) E24(-110.841,-195.796) E25(-111.965,-194.796) E26(-110.841,-193.796) E27(-111.965,-192.796) E28(-110.841,-191.796) E29(-111.965,-190.796) E30(-110.841,-189.796) E31(-111.965,-188.796) E32(-110.841,-187.796) E33(-111.965,-186.796) E34(-110.841,-185.796) E35(-111.965,-184.796) E36(-110.841,-183.796) E37(-111.965,-182.796) E38(-110.841,-181.796) E39(-111.965,-180.796) E40(-110.841,-179.796) E41(-111.965,-178.796) F2(-113.09,-217.796) F3(-114.215,-216.796) F4(-113.09,-215.796) F5(-114.215,-214.796) F6(-113.09,-213.796) F7(-114.215,-212.796) F8(-113.09,-211.796) F9(-114.215,-210.796) F10(-113.09,-209.796) F11(-114.215,-208.796) F12(-113.09,-207.796) F13(-114.215,-206.796) F14(-113.09,-205.796) F15(-114.215,-204.796) F16(-113.09,-203.796) F17(-114.215,-202.796) F18(-113.09,-201.796) F19(-114.215,-200.796) F20(-113.09,-199.796) F21(-114.215,-198.796) F22(-113.09,-197.796) F23(-114.215,-196.796) F24(-113.09,-195.796) F25(-114.215,-194.796) F26(-113.09,-193.796) F27(-114.215,-192.796) F28(-113.09,-191.796) F29(-114.215,-190.796) F30(-113.09,-189.796) F31(-114.215,-188.796) F32(-113.09,-187.796) F33(-114.215,-186.796) F34(-113.09,-185.796) F35(-114.215,-184.796) F36(-113.09,-183.796) F37(-114.215,-182.796) F38(-113.09,-181.796) F39(-114.215,-180.796) F40(-113.09,-179.796) F41(-114.215,-178.796) G2(-115.34,-217.796) G4(-115.34,-215.796) G6(-115.34,-213.796) G8(-115.34,-211.796) G10(-115.34,-209.796) G12(-115.34,-207.796) G14(-115.34,-205.796) G16(-115.34,-203.796) G18(-115.34,-201.796) G20(-115.34,-199.796) G22(-115.34,-197.796) G24(-115.34,-195.796) G26(-115.34,-193.796) G28(-115.34,-191.796) G30(-115.34,-189.796) G32(-115.34,-187.796) G34(-115.34,-185.796) G36(-115.34,-183.796) G38(-115.34,-181.796) G40(-115.34,-179.796)
  custom 0.257x0.257 smd: A42(-101.841,-177.796) A43(-102.966,-176.796) A44(-101.841,-175.796) A45(-102.966,-174.796) A46(-101.841,-173.796) A47(-102.966,-172.796) A48(-101.841,-171.796) A49(-102.966,-170.796) A50(-101.841,-169.796) A51(-102.966,-168.796) A52(-101.841,-167.796) A53(-102.966,-166.796) A54(-101.841,-165.796) A55(-102.966,-164.796) A56(-101.841,-163.796) A57(-102.966,-162.796) A58(-101.841,-161.796) A59(-102.966,-160.796) A60(-101.841,-159.796) A61(-102.966,-158.796) B42(-104.09,-177.796) B43(-105.215,-176.796) B44(-104.09,-175.796) B45(-105.215,-174.796) B46(-104.09,-173.796) B47(-105.215,-172.796) B48(-104.09,-171.796) B49(-105.215,-170.796) B50(-104.09,-169.796) B51(-105.215,-168.796) B52(-104.09,-167.796) B53(-105.215,-166.796) B54(-104.09,-165.796) B55(-105.215,-164.796) B56(-104.09,-163.796) B57(-105.215,-162.796) B58(-104.09,-161.796) B59(-105.215,-160.796) B60(-104.09,-159.796) B61(-105.215,-158.796) C42(-106.34,-177.796) C43(-107.466,-176.796) C44(-106.34,-175.796) C45(-107.466,-174.796) C46(-106.34,-173.796) C47(-107.466,-172.796) C48(-106.34,-171.796) C49(-107.466,-170.796) C50(-106.34,-169.796) C51(-107.466,-168.796) C52(-106.34,-167.796) C53(-107.466,-166.796) C54(-106.34,-165.796) C55(-107.466,-164.796) C56(-106.34,-163.796) C57(-107.466,-162.796) C58(-106.34,-161.796) C59(-107.466,-160.796) C60(-106.34,-159.796) C61(-107.466,-158.796) D42(-108.591,-177.796) D43(-109.716,-176.796) D44(-108.591,-175.796) D45(-109.716,-174.796) D46(-108.591,-173.796) D47(-109.716,-172.796) D48(-108.591,-171.796) D49(-109.716,-170.796) D50(-108.591,-169.796) D51(-109.716,-168.796) D52(-108.591,-167.796) D53(-109.716,-166.796) D54(-108.591,-165.796) D55(-109.716,-164.796) D56(-108.591,-163.796) D57(-109.716,-162.796) D58(-108.591,-161.796) D59(-109.716,-160.796) D60(-108.591,-159.796) D61(-109.716,-158.796) E42(-110.841,-177.796) E43(-111.965,-176.796) E44(-110.841,-175.796) E45(-111.965,-174.796) E46(-110.841,-173.796) E47(-111.965,-172.796) E48(-110.841,-171.796) E49(-111.965,-170.796) E50(-110.841,-169.796) E51(-111.965,-168.796) E52(-110.841,-167.796) E53(-111.965,-166.796) E54(-110.841,-165.796) E55(-111.965,-164.796) E56(-110.841,-163.796) E57(-111.965,-162.796) E58(-110.841,-161.796) E59(-111.965,-160.796) E60(-110.841,-159.796) E61(-111.965,-158.796) F42(-113.09,-177.796) F43(-114.215,-176.796) F44(-113.09,-175.796) F45(-114.215,-174.796) F46(-113.09,-173.796) F47(-114.215,-172.796) F48(-113.09,-171.796) F49(-114.215,-170.796) F50(-113.09,-169.796) F51(-114.215,-168.796) F52(-113.09,-167.796) F53(-114.215,-166.796) F54(-113.09,-165.796) F55(-114.215,-164.796) F56(-113.09,-163.796) F57(-114.215,-162.796) F58(-113.09,-161.796) F59(-114.215,-160.796) F60(-113.09,-159.796) F61(-114.215,-158.796) Z5(-100.716,-214.796) Z7(-100.716,-212.796) Z9(-100.716,-210.796) Z11(-100.716,-208.796) Z13(-100.716,-206.796) Z15(-100.716,-204.796) Z17(-100.716,-202.796) Z19(-100.716,-200.796) Z21(-100.716,-198.796) Z23(-100.716,-196.796) Z25(-100.716,-194.796) Z27(-100.716,-192.796) Z29(-100.716,-190.796) Z31(-100.716,-188.796) Z33(-100.716,-186.796) Z35(-100.716,-184.796) Z37(-100.716,-182.796) Z39(-100.716,-180.796) Z41(-100.716,-178.796) Z43(-100.716,-176.796) Z45(-100.716,-174.796) Z47(-100.716,-172.796) Z49(-100.716,-170.796) Z51(-100.716,-168.796) Z53(-100.716,-166.796) Z55(-100.716,-164.796) Z57(-100.716,-162.796) Z59(-100.716,-160.796) Z61(-100.716,-158.796)
  round 1.016 smd: B1(-105.215,-218.796) B62(-104.09,-157.796) C1(-107.466,-218.796) C62(-106.34,-157.796) D1(-109.716,-218.796) E1(-111.965,-218.796) E62(-110.841,-157.796) F1(-114.215,-218.796) F62(-113.09,-157.796) G42(-115.34,-177.796) G44(-115.34,-175.796) G46(-115.34,-173.796) G48(-115.34,-171.796) G50(-115.34,-169.796) G52(-115.34,-167.796) G54(-115.34,-165.796) G56(-115.34,-163.796) G58(-115.34,-161.796) G60(-115.34,-159.796)
PG_LTXDX_F_X1_VI100_SL01_V3
  round 0.508 hole 3.2 unplated: (-109.574,154.842)
  round 0.051 hole 2.489x2.21 unplated: (-108.575,220.342)
  rect 1.016x1.016 hole 0.559: A1(-114.204,218.796)
  round 1.016 hole 0.559: A2(-115.329,217.796) A3(-114.204,216.796) A4(-115.329,215.796) A5(-114.204,214.796) A6(-115.329,213.796) A7(-114.204,212.796) A8(-115.329,211.796) A9(-114.204,210.796) A10(-115.329,209.796) A11(-114.204,208.796) A12(-115.329,207.796) A13(-114.204,206.796) A14(-115.329,205.796) A15(-114.204,204.796) A16(-115.329,203.796) A17(-114.204,202.796) A18(-115.329,201.796) A19(-114.204,200.796) A20(-115.329,199.796) A21(-114.204,198.796) A22(-115.329,197.796) A23(-114.204,196.796) A24(-115.329,195.796) A25(-114.204,194.796) A26(-115.329,193.796) A27(-114.204,192.796) A28(-115.329,191.796) A29(-114.204,190.796) A30(-115.329,189.796) A31(-114.204,188.796) A32(-115.329,187.796) A33(-114.204,186.796) A34(-115.329,185.796) A35(-114.204,184.796) A36(-115.329,183.796) A37(-114.204,182.796) A38(-115.329,181.796) A39(-114.204,180.796) A40(-115.329,179.796) A41(-114.204,178.796) A42(-115.329,177.796) A43(-114.204,176.796) A44(-115.329,175.796) A45(-114.204,174.796) A46(-115.329,173.796) A47(-114.204,172.796) A48(-115.329,171.796) A49(-114.204,170.796) A50(-115.329,169.796) A51(-114.204,168.796) A52(-115.329,167.796) A53(-114.204,166.796) A54(-115.329,165.796) A55(-114.204,164.796) A56(-115.329,163.796) A57(-114.204,162.796) A58(-115.329,161.796) A59(-114.204,160.796) A60(-115.329,159.796) A61(-114.204,158.796) B1(-111.955,218.796) B2(-113.08,217.796) B3(-111.955,216.796) B4(-113.08,215.796) B5(-111.955,214.796) B6(-113.08,213.796) B7(-111.955,212.796) B8(-113.08,211.796) B9(-111.955,210.796) B10(-113.08,209.796) B11(-111.955,208.796) B12(-113.08,207.796) B13(-111.955,206.796) B14(-113.08,205.796) B15(-111.955,204.796) B16(-113.08,203.796) B17(-111.955,202.796) B18(-113.08,201.796) B19(-111.955,200.796) B20(-113.08,199.796) B21(-111.955,198.796) B22(-113.08,197.796) B23(-111.955,196.796) B24(-113.08,195.796) B25(-111.955,194.796) B26(-113.08,193.796) B27(-111.955,192.796) B28(-113.08,191.796) B29(-111.955,190.796) B30(-113.08,189.796) B31(-111.955,188.796) B32(-113.08,187.796) B33(-111.955,186.796) B34(-113.08,185.796) B35(-111.955,184.796) B36(-113.08,183.796) B37(-111.955,182.796) B38(-113.08,181.796) B39(-111.955,180.796) B40(-113.08,179.796) B41(-111.955,178.796) B42(-113.08,177.796) B43(-111.955,176.796) B44(-113.08,175.796) B45(-111.955,174.796) B46(-113.08,173.796) B47(-111.955,172.796) B48(-113.08,171.796) B49(-111.955,170.796) B50(-113.08,169.796) B51(-111.955,168.796) B52(-113.08,167.796) B53(-111.955,166.796) B54(-113.08,165.796) B55(-111.955,164.796) B56(-113.08,163.796) B57(-111.955,162.796) B58(-113.08,161.796) B59(-111.955,160.796) B60(-113.08,159.796) B61(-111.955,158.796) B62(-113.08,157.796) C1(-109.704,218.796) C2(-110.83,217.796) C3(-109.704,216.796) C4(-110.83,215.796) C5(-109.704,214.796) C6(-110.83,213.796) C7(-109.704,212.796) C8(-110.83,211.796) C9(-109.704,210.796) C10(-110.83,209.796) C11(-109.704,208.796) C12(-110.83,207.796) C13(-109.704,206.796) C14(-110.83,205.796) C15(-109.704,204.796) C16(-110.83,203.796) C17(-109.704,202.796) C18(-110.83,201.796) C19(-109.704,200.796) C20(-110.83,199.796) C21(-109.704,198.796) C22(-110.83,197.796) C23(-109.704,196.796) C24(-110.83,195.796) C25(-109.704,194.796) C26(-110.83,193.796) C27(-109.704,192.796) C28(-110.83,191.796) C29(-109.704,190.796) C30(-110.83,189.796) C31(-109.704,188.796) C32(-110.83,187.796) C33(-109.704,186.796) C34(-110.83,185.796) C35(-109.704,184.796) C36(-110.83,183.796) C37(-109.704,182.796) C38(-110.83,181.796) C39(-109.704,180.796) C40(-110.83,179.796) C41(-109.704,178.796) C42(-110.83,177.796) C43(-109.704,176.796) C44(-110.83,175.796) C45(-109.704,174.796) C46(-110.83,173.796) C47(-109.704,172.796) C48(-110.83,171.796) C49(-109.704,170.796) C50(-110.83,169.796) C51(-109.704,168.796) C52(-110.83,167.796) C53(-109.704,166.796) C54(-110.83,165.796) C55(-109.704,164.796) C56(-110.83,163.796) C57(-109.704,162.796) C58(-110.83,161.796) C59(-109.704,160.796) C60(-110.83,159.796) C61(-109.704,158.796) C62(-110.83,157.796) D1(-107.454,218.796) D2(-108.579,217.796) D3(-107.454,216.796) D4(-108.579,215.796) D5(-107.454,214.796) D6(-108.579,213.796) D7(-107.454,212.796) D8(-108.579,211.796) D9(-107.454,210.796) D10(-108.579,209.796) D11(-107.454,208.796) D12(-108.579,207.796) D13(-107.454,206.796) D14(-108.579,205.796) D15(-107.454,204.796) D16(-108.579,203.796) D17(-107.454,202.796) D18(-108.579,201.796) D19(-107.454,200.796) D20(-108.579,199.796) D21(-107.454,198.796) D22(-108.579,197.796) D23(-107.454,196.796) D24(-108.579,195.796) D25(-107.454,194.796) D26(-108.579,193.796) D27(-107.454,192.796) D28(-108.579,191.796) D29(-107.454,190.796) D30(-108.579,189.796) D31(-107.454,188.796) D32(-108.579,187.796) D33(-107.454,186.796) D34(-108.579,185.796) D35(-107.454,184.796) D36(-108.579,183.796) D37(-107.454,182.796) D38(-108.579,181.796) D39(-107.454,180.796) D40(-108.579,179.796) D41(-107.454,178.796) D42(-108.579,177.796) D43(-107.454,176.796) D44(-108.579,175.796) D45(-107.454,174.796) D46(-108.579,173.796) D47(-107.454,172.796) D48(-108.579,171.796) D49(-107.454,170.796) D50(-108.579,169.796) D51(-107.454,168.796) D52(-108.579,167.796) D53(-107.454,166.796) D54(-108.579,165.796) D55(-107.454,164.796) D56(-108.579,163.796) D57(-107.454,162.796) D58(-108.579,161.796) D59(-107.454,160.796) D60(-108.579,159.796) D61(-107.454,158.796) E1(-105.205,218.796) E2(-106.329,217.796) E3(-105.205,216.796) E4(-106.329,215.796) E5(-105.205,214.796) E6(-106.329,213.796) E7(-105.205,212.796) E8(-106.329,211.796) E9(-105.205,210.796) E10(-106.329,209.796) E11(-105.205,208.796) E12(-106.329,207.796) E13(-105.205,206.796) E14(-106.329,205.796) E15(-105.205,204.796) E16(-106.329,203.796) E17(-105.205,202.796) E18(-106.329,201.796) E19(-105.205,200.796) E20(-106.329,199.796) E21(-105.205,198.796) E22(-106.329,197.796) E23(-105.205,196.796) E24(-106.329,195.796) E25(-105.205,194.796) E26(-106.329,193.796) E27(-105.205,192.796) E28(-106.329,191.796) E29(-105.205,190.796) E30(-106.329,189.796) E31(-105.205,188.796) E32(-106.329,187.796) E33(-105.205,186.796) E34(-106.329,185.796) E35(-105.205,184.796) E36(-106.329,183.796) E37(-105.205,182.796) E38(-106.329,181.796) E39(-105.205,180.796) E40(-106.329,179.796) E41(-105.205,178.796) E42(-106.329,177.796) E43(-105.205,176.796) E44(-106.329,175.796) E45(-105.205,174.796) E46(-106.329,173.796) E47(-105.205,172.796) E48(-106.329,171.796) E49(-105.205,170.796) E50(-106.329,169.796) E51(-105.205,168.796) E52(-106.329,167.796) E53(-105.205,166.796) E54(-106.329,165.796) E55(-105.205,164.796) E56(-106.329,163.796) E57(-105.205,162.796) E58(-106.329,161.796) E59(-105.205,160.796) E60(-106.329,159.796) E61(-105.205,158.796) E62(-106.329,157.796) F1(-102.955,218.796) F2(-104.08,217.796) F3(-102.955,216.796) F4(-104.08,215.796) F5(-102.955,214.796) F6(-104.08,213.796) F7(-102.955,212.796) F8(-104.08,211.796) F9(-102.955,210.796) F10(-104.08,209.796) F11(-102.955,208.796) F12(-104.08,207.796) F13(-102.955,206.796) F14(-104.08,205.796) F15(-102.955,204.796) F16(-104.08,203.796) F17(-102.955,202.796) F18(-104.08,201.796) F19(-102.955,200.796) F20(-104.08,199.796) F21(-102.955,198.796) F22(-104.08,197.796) F23(-102.955,196.796) F24(-104.08,195.796) F25(-102.955,194.796) F26(-104.08,193.796) F27(-102.955,192.796) F28(-104.08,191.796) F29(-102.955,190.796) F30(-104.08,189.796) F31(-102.955,188.796) F32(-104.08,187.796) F33(-102.955,186.796) F34(-104.08,185.796) F35(-102.955,184.796) F36(-104.08,183.796) F37(-102.955,182.796) F38(-104.08,181.796) F39(-102.955,180.796) F40(-104.08,179.796) F41(-102.955,178.796) F42(-104.08,177.796) F43(-102.955,176.796) F44(-104.08,175.796) F45(-102.955,174.796) F46(-104.08,173.796) F47(-102.955,172.796) F48(-104.08,171.796) F49(-102.955,170.796) F50(-104.08,169.796) F51(-102.955,168.796) F52(-104.08,167.796) F53(-102.955,166.796) F54(-104.08,165.796) F55(-102.955,164.796) F56(-104.08,163.796) F57(-102.955,162.796) F58(-104.08,161.796) F59(-102.955,160.796) F60(-104.08,159.796) F61(-102.955,158.796) F62(-104.08,157.796) G2(-101.83,217.796) G4(-101.83,215.796) G6(-101.83,213.796) G8(-101.83,211.796) G10(-101.83,209.796) G12(-101.83,207.796) G14(-101.83,205.796) G16(-101.83,203.796) G18(-101.83,201.796) G20(-101.83,199.796) G22(-101.83,197.796) G24(-101.83,195.796) G26(-101.83,193.796) G28(-101.83,191.796) G30(-101.83,189.796) G32(-101.83,187.796) G34(-101.83,185.796) G36(-101.83,183.796) G38(-101.83,181.796) G40(-101.83,179.796) G42(-101.83,177.796) G44(-101.83,175.796) G46(-101.83,173.796) G48(-101.83,171.796) G50(-101.83,169.796) G52(-101.83,167.796) G54(-101.83,165.796) G56(-101.83,163.796) G58(-101.83,161.796) G60(-101.83,159.796)
  custom 0.257x0.257 smd: Z5(-116.454,214.796) Z7(-116.454,212.796) Z9(-116.454,210.796) Z11(-116.454,208.796) Z13(-116.454,206.796) Z15(-116.454,204.796) Z17(-116.454,202.796) Z19(-116.454,200.796) Z21(-116.454,198.796) Z23(-116.454,196.796) Z25(-116.454,194.796) Z27(-116.454,192.796) Z29(-116.454,190.796) Z31(-116.454,188.796) Z33(-116.454,186.796) Z35(-116.454,184.796) Z37(-116.454,182.796) Z39(-116.454,180.796) Z41(-116.454,178.796) Z43(-116.454,176.796) Z45(-116.454,174.796) Z47(-116.454,172.796) Z49(-116.454,170.796) Z51(-116.454,168.796) Z53(-116.454,166.796) Z55(-116.454,164.796) Z57(-116.454,162.796) Z59(-116.454,160.796) Z61(-116.454,158.796)
PG_LTXDX_F_X1_VI100_SL02_V3
  round 0.051 hole 2.489x2.21 unplated: (-84.465,-220.342)
  round 0.508 hole 3.2 unplated: (-83.466,-154.842)
  rect 1.016x1.016 hole 0.559: A1(-78.836,-218.796)
  round 1.016 hole 0.559: A2(-77.711,-217.796) A3(-78.836,-216.796) A4(-77.711,-215.796) A5(-78.836,-214.796) A6(-77.711,-213.796) A7(-78.836,-212.796) A8(-77.711,-211.796) A9(-78.836,-210.796) A10(-77.711,-209.796) A11(-78.836,-208.796) A12(-77.711,-207.796) A13(-78.836,-206.796) A14(-77.711,-205.796) A15(-78.836,-204.796) A16(-77.711,-203.796) A17(-78.836,-202.796) A18(-77.711,-201.796) A19(-78.836,-200.796) A20(-77.711,-199.796) A21(-78.836,-198.796) A22(-77.711,-197.796) A23(-78.836,-196.796) A24(-77.711,-195.796) A25(-78.836,-194.796) A26(-77.711,-193.796) A27(-78.836,-192.796) A28(-77.711,-191.796) A29(-78.836,-190.796) A30(-77.711,-189.796) A31(-78.836,-188.796) A32(-77.711,-187.796) A33(-78.836,-186.796) A34(-77.711,-185.796) A35(-78.836,-184.796) A36(-77.711,-183.796) A37(-78.836,-182.796) A38(-77.711,-181.796) A39(-78.836,-180.796) A40(-77.711,-179.796) A41(-78.836,-178.796) A42(-77.711,-177.796) A43(-78.836,-176.796) A44(-77.711,-175.796) A45(-78.836,-174.796) A46(-77.711,-173.796) A47(-78.836,-172.796) A48(-77.711,-171.796) A49(-78.836,-170.796) A50(-77.711,-169.796) A51(-78.836,-168.796) A52(-77.711,-167.796) A53(-78.836,-166.796) A54(-77.711,-165.796) A55(-78.836,-164.796) A56(-77.711,-163.796) A57(-78.836,-162.796) A58(-77.711,-161.796) A59(-78.836,-160.796) A60(-77.711,-159.796) A61(-78.836,-158.796) B1(-81.085,-218.796) B2(-79.96,-217.796) B3(-81.085,-216.796) B4(-79.96,-215.796) B5(-81.085,-214.796) B6(-79.96,-213.796) B7(-81.085,-212.796) B8(-79.96,-211.796) B9(-81.085,-210.796) B10(-79.96,-209.796) B11(-81.085,-208.796) B12(-79.96,-207.796) B13(-81.085,-206.796) B14(-79.96,-205.796) B15(-81.085,-204.796) B16(-79.96,-203.796) B17(-81.085,-202.796) B18(-79.96,-201.796) B19(-81.085,-200.796) B20(-79.96,-199.796) B21(-81.085,-198.796) B22(-79.96,-197.796) B23(-81.085,-196.796) B24(-79.96,-195.796) B25(-81.085,-194.796) B26(-79.96,-193.796) B27(-81.085,-192.796) B28(-79.96,-191.796) B29(-81.085,-190.796) B30(-79.96,-189.796) B31(-81.085,-188.796) B32(-79.96,-187.796) B33(-81.085,-186.796) B34(-79.96,-185.796) B35(-81.085,-184.796) B36(-79.96,-183.796) B37(-81.085,-182.796) B38(-79.96,-181.796) B39(-81.085,-180.796) B40(-79.96,-179.796) B41(-81.085,-178.796) B42(-79.96,-177.796) B43(-81.085,-176.796) B44(-79.96,-175.796) B45(-81.085,-174.796) B46(-79.96,-173.796) B47(-81.085,-172.796) B48(-79.96,-171.796) B49(-81.085,-170.796) B50(-79.96,-169.796) B51(-81.085,-168.796) B52(-79.96,-167.796) B53(-81.085,-166.796) B54(-79.96,-165.796) B55(-81.085,-164.796) B56(-79.96,-163.796) B57(-81.085,-162.796) B58(-79.96,-161.796) B59(-81.085,-160.796) B60(-79.96,-159.796) B61(-81.085,-158.796) B62(-79.96,-157.796) C1(-83.336,-218.796) C2(-82.21,-217.796) C3(-83.336,-216.796) C4(-82.21,-215.796) C5(-83.336,-214.796) C6(-82.21,-213.796) C7(-83.336,-212.796) C8(-82.21,-211.796) C9(-83.336,-210.796) C10(-82.21,-209.796) C11(-83.336,-208.796) C12(-82.21,-207.796) C13(-83.336,-206.796) C14(-82.21,-205.796) C15(-83.336,-204.796) C16(-82.21,-203.796) C17(-83.336,-202.796) C18(-82.21,-201.796) C19(-83.336,-200.796) C20(-82.21,-199.796) C21(-83.336,-198.796) C22(-82.21,-197.796) C23(-83.336,-196.796) C24(-82.21,-195.796) C25(-83.336,-194.796) C26(-82.21,-193.796) C27(-83.336,-192.796) C28(-82.21,-191.796) C29(-83.336,-190.796) C30(-82.21,-189.796) C31(-83.336,-188.796) C32(-82.21,-187.796) C33(-83.336,-186.796) C34(-82.21,-185.796) C35(-83.336,-184.796) C36(-82.21,-183.796) C37(-83.336,-182.796) C38(-82.21,-181.796) C39(-83.336,-180.796) C40(-82.21,-179.796) C41(-83.336,-178.796) C42(-82.21,-177.796) C43(-83.336,-176.796) C44(-82.21,-175.796) C45(-83.336,-174.796) C46(-82.21,-173.796) C47(-83.336,-172.796) C48(-82.21,-171.796) C49(-83.336,-170.796) C50(-82.21,-169.796) C51(-83.336,-168.796) C52(-82.21,-167.796) C53(-83.336,-166.796) C54(-82.21,-165.796) C55(-83.336,-164.796) C56(-82.21,-163.796) C57(-83.336,-162.796) C58(-82.21,-161.796) C59(-83.336,-160.796) C60(-82.21,-159.796) C61(-83.336,-158.796) C62(-82.21,-157.796) D1(-85.586,-218.796) D2(-84.461,-217.796) D3(-85.586,-216.796) D4(-84.461,-215.796) D5(-85.586,-214.796) D6(-84.461,-213.796) D7(-85.586,-212.796) D8(-84.461,-211.796) D9(-85.586,-210.796) D10(-84.461,-209.796) D11(-85.586,-208.796) D12(-84.461,-207.796) D13(-85.586,-206.796) D14(-84.461,-205.796) D15(-85.586,-204.796) D16(-84.461,-203.796) D17(-85.586,-202.796) D18(-84.461,-201.796) D19(-85.586,-200.796) D20(-84.461,-199.796) D21(-85.586,-198.796) D22(-84.461,-197.796) D23(-85.586,-196.796) D24(-84.461,-195.796) D25(-85.586,-194.796) D26(-84.461,-193.796) D27(-85.586,-192.796) D28(-84.461,-191.796) D29(-85.586,-190.796) D30(-84.461,-189.796) D31(-85.586,-188.796) D32(-84.461,-187.796) D33(-85.586,-186.796) D34(-84.461,-185.796) D35(-85.586,-184.796) D36(-84.461,-183.796) D37(-85.586,-182.796) D38(-84.461,-181.796) D39(-85.586,-180.796) D40(-84.461,-179.796) D41(-85.586,-178.796) D42(-84.461,-177.796) D43(-85.586,-176.796) D44(-84.461,-175.796) D45(-85.586,-174.796) D46(-84.461,-173.796) D47(-85.586,-172.796) D48(-84.461,-171.796) D49(-85.586,-170.796) D50(-84.461,-169.796) D51(-85.586,-168.796) D52(-84.461,-167.796) D53(-85.586,-166.796) D54(-84.461,-165.796) D55(-85.586,-164.796) D56(-84.461,-163.796) D57(-85.586,-162.796) D58(-84.461,-161.796) D59(-85.586,-160.796) D60(-84.461,-159.796) D61(-85.586,-158.796) E1(-87.835,-218.796) E2(-86.711,-217.796) E3(-87.835,-216.796) E4(-86.711,-215.796) E5(-87.835,-214.796) E6(-86.711,-213.796) E7(-87.835,-212.796) E8(-86.711,-211.796) E9(-87.835,-210.796) E10(-86.711,-209.796) E11(-87.835,-208.796) E12(-86.711,-207.796) E13(-87.835,-206.796) E14(-86.711,-205.796) E15(-87.835,-204.796) E16(-86.711,-203.796) E17(-87.835,-202.796) E18(-86.711,-201.796) E19(-87.835,-200.796) E20(-86.711,-199.796) E21(-87.835,-198.796) E22(-86.711,-197.796) E23(-87.835,-196.796) E24(-86.711,-195.796) E25(-87.835,-194.796) E26(-86.711,-193.796) E27(-87.835,-192.796) E28(-86.711,-191.796) E29(-87.835,-190.796) E30(-86.711,-189.796) E31(-87.835,-188.796) E32(-86.711,-187.796) E33(-87.835,-186.796) E34(-86.711,-185.796) E35(-87.835,-184.796) E36(-86.711,-183.796) E37(-87.835,-182.796) E38(-86.711,-181.796) E39(-87.835,-180.796) E40(-86.711,-179.796) E41(-87.835,-178.796) E42(-86.711,-177.796) E43(-87.835,-176.796) E44(-86.711,-175.796) E45(-87.835,-174.796) E46(-86.711,-173.796) E47(-87.835,-172.796) E48(-86.711,-171.796) E49(-87.835,-170.796) E50(-86.711,-169.796) E51(-87.835,-168.796) E52(-86.711,-167.796) E53(-87.835,-166.796) E54(-86.711,-165.796) E55(-87.835,-164.796) E56(-86.711,-163.796) E57(-87.835,-162.796) E58(-86.711,-161.796) E59(-87.835,-160.796) E60(-86.711,-159.796) E61(-87.835,-158.796) E62(-86.711,-157.796) F1(-90.085,-218.796) F2(-88.96,-217.796) F3(-90.085,-216.796) F4(-88.96,-215.796) F5(-90.085,-214.796) F6(-88.96,-213.796) F7(-90.085,-212.796) F8(-88.96,-211.796) F9(-90.085,-210.796) F10(-88.96,-209.796) F11(-90.085,-208.796) F12(-88.96,-207.796) F13(-90.085,-206.796) F14(-88.96,-205.796) F15(-90.085,-204.796) F16(-88.96,-203.796) F17(-90.085,-202.796) F18(-88.96,-201.796) F19(-90.085,-200.796) F20(-88.96,-199.796) F21(-90.085,-198.796) F22(-88.96,-197.796) F23(-90.085,-196.796) F24(-88.96,-195.796) F25(-90.085,-194.796) F26(-88.96,-193.796) F27(-90.085,-192.796) F28(-88.96,-191.796) F29(-90.085,-190.796) F30(-88.96,-189.796) F31(-90.085,-188.796) F32(-88.96,-187.796) F33(-90.085,-186.796) F34(-88.96,-185.796) F35(-90.085,-184.796) F36(-88.96,-183.796) F37(-90.085,-182.796) F38(-88.96,-181.796) F39(-90.085,-180.796) F40(-88.96,-179.796) F41(-90.085,-178.796) F42(-88.96,-177.796) F43(-90.085,-176.796) F44(-88.96,-175.796) F45(-90.085,-174.796) F46(-88.96,-173.796) F47(-90.085,-172.796) F48(-88.96,-171.796) F49(-90.085,-170.796) F50(-88.96,-169.796) F51(-90.085,-168.796) F52(-88.96,-167.796) F53(-90.085,-166.796) F54(-88.96,-165.796) F55(-90.085,-164.796) F56(-88.96,-163.796) F57(-90.085,-162.796) F58(-88.96,-161.796) F59(-90.085,-160.796) F60(-88.96,-159.796) F61(-90.085,-158.796) F62(-88.96,-157.796) G2(-91.21,-217.796) G4(-91.21,-215.796) G6(-91.21,-213.796) G8(-91.21,-211.796) G10(-91.21,-209.796) G12(-91.21,-207.796) G14(-91.21,-205.796) G16(-91.21,-203.796) G18(-91.21,-201.796) G20(-91.21,-199.796) G22(-91.21,-197.796) G24(-91.21,-195.796) G26(-91.21,-193.796) G28(-91.21,-191.796) G30(-91.21,-189.796) G32(-91.21,-187.796) G34(-91.21,-185.796) G36(-91.21,-183.796) G38(-91.21,-181.796) G40(-91.21,-179.796) G42(-91.21,-177.796) G44(-91.21,-175.796) G46(-91.21,-173.796) G48(-91.21,-171.796) G50(-91.21,-169.796) G52(-91.21,-167.796) G54(-91.21,-165.796) G56(-91.21,-163.796) G58(-91.21,-161.796) G60(-91.21,-159.796)
  custom 0.257x0.257 smd: Z5(-76.586,-214.796) Z7(-76.586,-212.796) Z9(-76.586,-210.796) Z11(-76.586,-208.796) Z13(-76.586,-206.796) Z15(-76.586,-204.796) Z17(-76.586,-202.796) Z19(-76.586,-200.796) Z21(-76.586,-198.796) Z23(-76.586,-196.796) Z25(-76.586,-194.796) Z27(-76.586,-192.796) Z29(-76.586,-190.796) Z31(-76.586,-188.796) Z33(-76.586,-186.796) Z35(-76.586,-184.796) Z37(-76.586,-182.796) Z39(-76.586,-180.796) Z41(-76.586,-178.796) Z43(-76.586,-176.796) Z45(-76.586,-174.796) Z47(-76.586,-172.796) Z49(-76.586,-170.796) Z51(-76.586,-168.796) Z53(-76.586,-166.796) Z55(-76.586,-164.796) Z57(-76.586,-162.796) Z59(-76.586,-160.796) Z61(-76.586,-158.796)
PG_LTXDX_F_X1_VI100_SL17_V3
  round 0.508 hole 3.2 unplated: (83.466,154.842)
  round 0.051 hole 2.489x2.21 unplated: (84.465,220.342)
  rect 1.016x1.016 hole 0.559: A1(78.836,218.796)
  round 1.016 hole 0.559: A2(77.711,217.796) A3(78.836,216.796) A4(77.711,215.796) A5(78.836,214.796) A6(77.711,213.796) A7(78.836,212.796) A8(77.711,211.796) A9(78.836,210.796) A10(77.711,209.796) A11(78.836,208.796) A12(77.711,207.796) A13(78.836,206.796) A14(77.711,205.796) A15(78.836,204.796) A16(77.711,203.796) A17(78.836,202.796) A18(77.711,201.796) A19(78.836,200.796) A20(77.711,199.796) A21(78.836,198.796) A22(77.711,197.796) A23(78.836,196.796) A24(77.711,195.796) A25(78.836,194.796) A26(77.711,193.796) A27(78.836,192.796) A28(77.711,191.796) A29(78.836,190.796) A30(77.711,189.796) A31(78.836,188.796) A32(77.711,187.796) A33(78.836,186.796) A34(77.711,185.796) A35(78.836,184.796) A36(77.711,183.796) A37(78.836,182.796) A38(77.711,181.796) A39(78.836,180.796) A40(77.711,179.796) A41(78.836,178.796) A42(77.711,177.796) A43(78.836,176.796) A44(77.711,175.796) A45(78.836,174.796) A46(77.711,173.796) A47(78.836,172.796) A48(77.711,171.796) A49(78.836,170.796) A50(77.711,169.796) A51(78.836,168.796) A52(77.711,167.796) A53(78.836,166.796) A54(77.711,165.796) A55(78.836,164.796) A56(77.711,163.796) A57(78.836,162.796) A58(77.711,161.796) A59(78.836,160.796) A60(77.711,159.796) A61(78.836,158.796) B1(81.085,218.796) B2(79.96,217.796) B3(81.085,216.796) B4(79.96,215.796) B5(81.085,214.796) B6(79.96,213.796) B7(81.085,212.796) B8(79.96,211.796) B9(81.085,210.796) B10(79.96,209.796) B11(81.085,208.796) B12(79.96,207.796) B13(81.085,206.796) B14(79.96,205.796) B15(81.085,204.796) B16(79.96,203.796) B17(81.085,202.796) B18(79.96,201.796) B19(81.085,200.796) B20(79.96,199.796) B21(81.085,198.796) B22(79.96,197.796) B23(81.085,196.796) B24(79.96,195.796) B25(81.085,194.796) B26(79.96,193.796) B27(81.085,192.796) B28(79.96,191.796) B29(81.085,190.796) B30(79.96,189.796) B31(81.085,188.796) B32(79.96,187.796) B33(81.085,186.796) B34(79.96,185.796) B35(81.085,184.796) B36(79.96,183.796) B37(81.085,182.796) B38(79.96,181.796) B39(81.085,180.796) B40(79.96,179.796) B41(81.085,178.796) B42(79.96,177.796) B43(81.085,176.796) B44(79.96,175.796) B45(81.085,174.796) B46(79.96,173.796) B47(81.085,172.796) B48(79.96,171.796) B49(81.085,170.796) B50(79.96,169.796) B51(81.085,168.796) B52(79.96,167.796) B53(81.085,166.796) B54(79.96,165.796) B55(81.085,164.796) B56(79.96,163.796) B57(81.085,162.796) B58(79.96,161.796) B59(81.085,160.796) B60(79.96,159.796) B61(81.085,158.796) B62(79.96,157.796) C1(83.336,218.796) C2(82.21,217.796) C3(83.336,216.796) C4(82.21,215.796) C5(83.336,214.796) C6(82.21,213.796) C7(83.336,212.796) C8(82.21,211.796) C9(83.336,210.796) C10(82.21,209.796) C11(83.336,208.796) C12(82.21,207.796) C13(83.336,206.796) C14(82.21,205.796) C15(83.336,204.796) C16(82.21,203.796) C17(83.336,202.796) C18(82.21,201.796) C19(83.336,200.796) C20(82.21,199.796) C21(83.336,198.796) C22(82.21,197.796) C23(83.336,196.796) C24(82.21,195.796) C25(83.336,194.796) C26(82.21,193.796) C27(83.336,192.796) C28(82.21,191.796) C29(83.336,190.796) C30(82.21,189.796) C31(83.336,188.796) C32(82.21,187.796) C33(83.336,186.796) C34(82.21,185.796) C35(83.336,184.796) C36(82.21,183.796) C37(83.336,182.796) C38(82.21,181.796) C39(83.336,180.796) C40(82.21,179.796) C41(83.336,178.796) C42(82.21,177.796) C43(83.336,176.796) C44(82.21,175.796) C45(83.336,174.796) C46(82.21,173.796) C47(83.336,172.796) C48(82.21,171.796) C49(83.336,170.796) C50(82.21,169.796) C51(83.336,168.796) C52(82.21,167.796) C53(83.336,166.796) C54(82.21,165.796) C55(83.336,164.796) C56(82.21,163.796) C57(83.336,162.796) C58(82.21,161.796) C59(83.336,160.796) C60(82.21,159.796) C61(83.336,158.796) C62(82.21,157.796) D1(85.586,218.796) D2(84.461,217.796) D3(85.586,216.796) D4(84.461,215.796) D5(85.586,214.796) D6(84.461,213.796) D7(85.586,212.796) D8(84.461,211.796) D9(85.586,210.796) D10(84.461,209.796) D11(85.586,208.796) D12(84.461,207.796) D13(85.586,206.796) D14(84.461,205.796) D15(85.586,204.796) D16(84.461,203.796) D17(85.586,202.796) D18(84.461,201.796) D19(85.586,200.796) D20(84.461,199.796) D21(85.586,198.796) D22(84.461,197.796) D23(85.586,196.796) D24(84.461,195.796) D25(85.586,194.796) D26(84.461,193.796) D27(85.586,192.796) D28(84.461,191.796) D29(85.586,190.796) D30(84.461,189.796) D31(85.586,188.796) D32(84.461,187.796) D33(85.586,186.796) D34(84.461,185.796) D35(85.586,184.796) D36(84.461,183.796) D37(85.586,182.796) D38(84.461,181.796) D39(85.586,180.796) D40(84.461,179.796) D41(85.586,178.796) D42(84.461,177.796) D43(85.586,176.796) D44(84.461,175.796) D45(85.586,174.796) D46(84.461,173.796) D47(85.586,172.796) D48(84.461,171.796) D49(85.586,170.796) D50(84.461,169.796) D51(85.586,168.796) D52(84.461,167.796) D53(85.586,166.796) D54(84.461,165.796) D55(85.586,164.796) D56(84.461,163.796) D57(85.586,162.796) D58(84.461,161.796) D59(85.586,160.796) D60(84.461,159.796) D61(85.586,158.796) E1(87.835,218.796) E2(86.711,217.796) E3(87.835,216.796) E4(86.711,215.796) E5(87.835,214.796) E6(86.711,213.796) E7(87.835,212.796) E8(86.711,211.796) E9(87.835,210.796) E10(86.711,209.796) E11(87.835,208.796) E12(86.711,207.796) E13(87.835,206.796) E14(86.711,205.796) E15(87.835,204.796) E16(86.711,203.796) E17(87.835,202.796) E18(86.711,201.796) E19(87.835,200.796) E20(86.711,199.796) E21(87.835,198.796) E22(86.711,197.796) E23(87.835,196.796) E24(86.711,195.796) E25(87.835,194.796) E26(86.711,193.796) E27(87.835,192.796) E28(86.711,191.796) E29(87.835,190.796) E30(86.711,189.796) E31(87.835,188.796) E32(86.711,187.796) E33(87.835,186.796) E34(86.711,185.796) E35(87.835,184.796) E36(86.711,183.796) E37(87.835,182.796) E38(86.711,181.796) E39(87.835,180.796) E40(86.711,179.796) E41(87.835,178.796) E42(86.711,177.796) E43(87.835,176.796) E44(86.711,175.796) E45(87.835,174.796) E46(86.711,173.796) E47(87.835,172.796) E48(86.711,171.796) E49(87.835,170.796) E50(86.711,169.796) E51(87.835,168.796) E52(86.711,167.796) E53(87.835,166.796) E54(86.711,165.796) E55(87.835,164.796) E56(86.711,163.796) E57(87.835,162.796) E58(86.711,161.796) E59(87.835,160.796) E60(86.711,159.796) E61(87.835,158.796) E62(86.711,157.796) F1(90.085,218.796) F2(88.96,217.796) F3(90.085,216.796) F4(88.96,215.796) F5(90.085,214.796) F6(88.96,213.796) F7(90.085,212.796) F8(88.96,211.796) F9(90.085,210.796) F10(88.96,209.796) F11(90.085,208.796) F12(88.96,207.796) F13(90.085,206.796) F14(88.96,205.796) F15(90.085,204.796) F16(88.96,203.796) F17(90.085,202.796) F18(88.96,201.796) F19(90.085,200.796) F20(88.96,199.796) F21(90.085,198.796) F22(88.96,197.796) F23(90.085,196.796) F24(88.96,195.796) F25(90.085,194.796) F26(88.96,193.796) F27(90.085,192.796) F28(88.96,191.796) F29(90.085,190.796) F30(88.96,189.796) F31(90.085,188.796) F32(88.96,187.796) F33(90.085,186.796) F34(88.96,185.796) F35(90.085,184.796) F36(88.96,183.796) F37(90.085,182.796) F38(88.96,181.796) F39(90.085,180.796) F40(88.96,179.796) F41(90.085,178.796) F42(88.96,177.796) F43(90.085,176.796) F44(88.96,175.796) F45(90.085,174.796) F46(88.96,173.796) F47(90.085,172.796) F48(88.96,171.796) F49(90.085,170.796) F50(88.96,169.796) F51(90.085,168.796) F52(88.96,167.796) F53(90.085,166.796) F54(88.96,165.796) F55(90.085,164.796) F56(88.96,163.796) F57(90.085,162.796) F58(88.96,161.796) F59(90.085,160.796) F60(88.96,159.796) F61(90.085,158.796) F62(88.96,157.796) G2(91.21,217.796) G4(91.21,215.796) G6(91.21,213.796) G8(91.21,211.796) G10(91.21,209.796) G12(91.21,207.796) G14(91.21,205.796) G16(91.21,203.796) G18(91.21,201.796) G20(91.21,199.796) G22(91.21,197.796) G24(91.21,195.796) G26(91.21,193.796) G28(91.21,191.796) G30(91.21,189.796) G32(91.21,187.796) G34(91.21,185.796) G36(91.21,183.796) G38(91.21,181.796) G40(91.21,179.796) G42(91.21,177.796) G44(91.21,175.796) G46(91.21,173.796) G48(91.21,171.796) G50(91.21,169.796) G52(91.21,167.796) G54(91.21,165.796) G56(91.21,163.796) G58(91.21,161.796) G60(91.21,159.796)
  custom 0.257x0.257 smd: Z5(76.586,214.796) Z7(76.586,212.796) Z9(76.586,210.796) Z11(76.586,208.796) Z13(76.586,206.796) Z15(76.586,204.796) Z17(76.586,202.796) Z19(76.586,200.796) Z21(76.586,198.796) Z23(76.586,196.796) Z25(76.586,194.796) Z27(76.586,192.796) Z29(76.586,190.796) Z31(76.586,188.796) Z33(76.586,186.796) Z35(76.586,184.796) Z37(76.586,182.796) Z39(76.586,180.796) Z41(76.586,178.796) Z43(76.586,176.796) Z45(76.586,174.796) Z47(76.586,172.796) Z49(76.586,170.796) Z51(76.586,168.796) Z53(76.586,166.796) Z55(76.586,164.796) Z57(76.586,162.796) Z59(76.586,160.796) Z61(76.586,158.796)
PG_LTXDX_F_X1_VI100_SL18_V3
  round 0.051 hole 2.489x2.21 unplated: (108.575,-220.342)
  round 0.508 hole 3.2 unplated: (109.574,-154.842)
  rect 1.016x1.016 hole 0.559: A1(114.204,-218.796)
  round 1.016 hole 0.559: A2(115.329,-217.796) A3(114.204,-216.796) A4(115.329,-215.796) A5(114.204,-214.796) A6(115.329,-213.796) A7(114.204,-212.796) A8(115.329,-211.796) A9(114.204,-210.796) A10(115.329,-209.796) A11(114.204,-208.796) A12(115.329,-207.796) A13(114.204,-206.796) A14(115.329,-205.796) A15(114.204,-204.796) A16(115.329,-203.796) A17(114.204,-202.796) A18(115.329,-201.796) A19(114.204,-200.796) A20(115.329,-199.796) A21(114.204,-198.796) A22(115.329,-197.796) A23(114.204,-196.796) A24(115.329,-195.796) A25(114.204,-194.796) A26(115.329,-193.796) A27(114.204,-192.796) A28(115.329,-191.796) A29(114.204,-190.796) A30(115.329,-189.796) A31(114.204,-188.796) A32(115.329,-187.796) A33(114.204,-186.796) A34(115.329,-185.796) A35(114.204,-184.796) A36(115.329,-183.796) A37(114.204,-182.796) A38(115.329,-181.796) A39(114.204,-180.796) A40(115.329,-179.796) A41(114.204,-178.796) A42(115.329,-177.796) A43(114.204,-176.796) A44(115.329,-175.796) A45(114.204,-174.796) A46(115.329,-173.796) A47(114.204,-172.796) A48(115.329,-171.796) A49(114.204,-170.796) A50(115.329,-169.796) A51(114.204,-168.796) A52(115.329,-167.796) A53(114.204,-166.796) A54(115.329,-165.796) A55(114.204,-164.796) A56(115.329,-163.796) A57(114.204,-162.796) A58(115.329,-161.796) A59(114.204,-160.796) A60(115.329,-159.796) A61(114.204,-158.796) B1(111.955,-218.796) B2(113.08,-217.796) B3(111.955,-216.796) B4(113.08,-215.796) B5(111.955,-214.796) B6(113.08,-213.796) B7(111.955,-212.796) B8(113.08,-211.796) B9(111.955,-210.796) B10(113.08,-209.796) B11(111.955,-208.796) B12(113.08,-207.796) B13(111.955,-206.796) B14(113.08,-205.796) B15(111.955,-204.796) B16(113.08,-203.796) B17(111.955,-202.796) B18(113.08,-201.796) B19(111.955,-200.796) B20(113.08,-199.796) B21(111.955,-198.796) B22(113.08,-197.796) B23(111.955,-196.796) B24(113.08,-195.796) B25(111.955,-194.796) B26(113.08,-193.796) B27(111.955,-192.796) B28(113.08,-191.796) B29(111.955,-190.796) B30(113.08,-189.796) B31(111.955,-188.796) B32(113.08,-187.796) B33(111.955,-186.796) B34(113.08,-185.796) B35(111.955,-184.796) B36(113.08,-183.796) B37(111.955,-182.796) B38(113.08,-181.796) B39(111.955,-180.796) B40(113.08,-179.796) B41(111.955,-178.796) B42(113.08,-177.796) B43(111.955,-176.796) B44(113.08,-175.796) B45(111.955,-174.796) B46(113.08,-173.796) B47(111.955,-172.796) B48(113.08,-171.796) B49(111.955,-170.796) B50(113.08,-169.796) B51(111.955,-168.796) B52(113.08,-167.796) B53(111.955,-166.796) B54(113.08,-165.796) B55(111.955,-164.796) B56(113.08,-163.796) B57(111.955,-162.796) B58(113.08,-161.796) B59(111.955,-160.796) B60(113.08,-159.796) B61(111.955,-158.796) B62(113.08,-157.796) C1(109.704,-218.796) C2(110.83,-217.796) C3(109.704,-216.796) C4(110.83,-215.796) C5(109.704,-214.796) C6(110.83,-213.796) C7(109.704,-212.796) C8(110.83,-211.796) C9(109.704,-210.796) C10(110.83,-209.796) C11(109.704,-208.796) C12(110.83,-207.796) C13(109.704,-206.796) C14(110.83,-205.796) C15(109.704,-204.796) C16(110.83,-203.796) C17(109.704,-202.796) C18(110.83,-201.796) C19(109.704,-200.796) C20(110.83,-199.796) C21(109.704,-198.796) C22(110.83,-197.796) C23(109.704,-196.796) C24(110.83,-195.796) C25(109.704,-194.796) C26(110.83,-193.796) C27(109.704,-192.796) C28(110.83,-191.796) C29(109.704,-190.796) C30(110.83,-189.796) C31(109.704,-188.796) C32(110.83,-187.796) C33(109.704,-186.796) C34(110.83,-185.796) C35(109.704,-184.796) C36(110.83,-183.796) C37(109.704,-182.796) C38(110.83,-181.796) C39(109.704,-180.796) C40(110.83,-179.796) C41(109.704,-178.796) C42(110.83,-177.796) C43(109.704,-176.796) C44(110.83,-175.796) C45(109.704,-174.796) C46(110.83,-173.796) C47(109.704,-172.796) C48(110.83,-171.796) C49(109.704,-170.796) C50(110.83,-169.796) C51(109.704,-168.796) C52(110.83,-167.796) C53(109.704,-166.796) C54(110.83,-165.796) C55(109.704,-164.796) C56(110.83,-163.796) C57(109.704,-162.796) C58(110.83,-161.796) C59(109.704,-160.796) C60(110.83,-159.796) C61(109.704,-158.796) C62(110.83,-157.796) D1(107.454,-218.796) D2(108.579,-217.796) D3(107.454,-216.796) D4(108.579,-215.796) D5(107.454,-214.796) D6(108.579,-213.796) D7(107.454,-212.796) D8(108.579,-211.796) D9(107.454,-210.796) D10(108.579,-209.796) D11(107.454,-208.796) D12(108.579,-207.796) D13(107.454,-206.796) D14(108.579,-205.796) D15(107.454,-204.796) D16(108.579,-203.796) D17(107.454,-202.796) D18(108.579,-201.796) D19(107.454,-200.796) D20(108.579,-199.796) D21(107.454,-198.796) D22(108.579,-197.796) D23(107.454,-196.796) D24(108.579,-195.796) D25(107.454,-194.796) D26(108.579,-193.796) D27(107.454,-192.796) D28(108.579,-191.796) D29(107.454,-190.796) D30(108.579,-189.796) D31(107.454,-188.796) D32(108.579,-187.796) D33(107.454,-186.796) D34(108.579,-185.796) D35(107.454,-184.796) D36(108.579,-183.796) D37(107.454,-182.796) D38(108.579,-181.796) D39(107.454,-180.796) D40(108.579,-179.796) D41(107.454,-178.796) D42(108.579,-177.796) D43(107.454,-176.796) D44(108.579,-175.796) D45(107.454,-174.796) D46(108.579,-173.796) D47(107.454,-172.796) D48(108.579,-171.796) D49(107.454,-170.796) D50(108.579,-169.796) D51(107.454,-168.796) D52(108.579,-167.796) D53(107.454,-166.796) D54(108.579,-165.796) D55(107.454,-164.796) D56(108.579,-163.796) D57(107.454,-162.796) D58(108.579,-161.796) D59(107.454,-160.796) D60(108.579,-159.796) D61(107.454,-158.796) E1(105.205,-218.796) E2(106.329,-217.796) E3(105.205,-216.796) E4(106.329,-215.796) E5(105.205,-214.796) E6(106.329,-213.796) E7(105.205,-212.796) E8(106.329,-211.796) E9(105.205,-210.796) E10(106.329,-209.796) E11(105.205,-208.796) E12(106.329,-207.796) E13(105.205,-206.796) E14(106.329,-205.796) E15(105.205,-204.796) E16(106.329,-203.796) E17(105.205,-202.796) E18(106.329,-201.796) E19(105.205,-200.796) E20(106.329,-199.796) E21(105.205,-198.796) E22(106.329,-197.796) E23(105.205,-196.796) E24(106.329,-195.796) E25(105.205,-194.796) E26(106.329,-193.796) E27(105.205,-192.796) E28(106.329,-191.796) E29(105.205,-190.796) E30(106.329,-189.796) E31(105.205,-188.796) E32(106.329,-187.796) E33(105.205,-186.796) E34(106.329,-185.796) E35(105.205,-184.796) E36(106.329,-183.796) E37(105.205,-182.796) E38(106.329,-181.796) E39(105.205,-180.796) E40(106.329,-179.796) E41(105.205,-178.796) E42(106.329,-177.796) E43(105.205,-176.796) E44(106.329,-175.796) E45(105.205,-174.796) E46(106.329,-173.796) E47(105.205,-172.796) E48(106.329,-171.796) E49(105.205,-170.796) E50(106.329,-169.796) E51(105.205,-168.796) E52(106.329,-167.796) E53(105.205,-166.796) E54(106.329,-165.796) E55(105.205,-164.796) E56(106.329,-163.796) E57(105.205,-162.796) E58(106.329,-161.796) E59(105.205,-160.796) E60(106.329,-159.796) E61(105.205,-158.796) E62(106.329,-157.796) F1(102.955,-218.796) F2(104.08,-217.796) F3(102.955,-216.796) F4(104.08,-215.796) F5(102.955,-214.796) F6(104.08,-213.796) F7(102.955,-212.796) F8(104.08,-211.796) F9(102.955,-210.796) F10(104.08,-209.796) F11(102.955,-208.796) F12(104.08,-207.796) F13(102.955,-206.796) F14(104.08,-205.796) F15(102.955,-204.796) F16(104.08,-203.796) F17(102.955,-202.796) F18(104.08,-201.796) F19(102.955,-200.796) F20(104.08,-199.796) F21(102.955,-198.796) F22(104.08,-197.796) F23(102.955,-196.796) F24(104.08,-195.796) F25(102.955,-194.796) F26(104.08,-193.796) F27(102.955,-192.796) F28(104.08,-191.796) F29(102.955,-190.796) F30(104.08,-189.796) F31(102.955,-188.796) F32(104.08,-187.796) F33(102.955,-186.796) F34(104.08,-185.796) F35(102.955,-184.796) F36(104.08,-183.796) F37(102.955,-182.796) F38(104.08,-181.796) F39(102.955,-180.796) F40(104.08,-179.796) F41(102.955,-178.796) F42(104.08,-177.796) F43(102.955,-176.796) F44(104.08,-175.796) F45(102.955,-174.796) F46(104.08,-173.796) F47(102.955,-172.796) F48(104.08,-171.796) F49(102.955,-170.796) F50(104.08,-169.796) F51(102.955,-168.796) F52(104.08,-167.796) F53(102.955,-166.796) F54(104.08,-165.796) F55(102.955,-164.796) F56(104.08,-163.796) F57(102.955,-162.796) F58(104.08,-161.796) F59(102.955,-160.796) F60(104.08,-159.796) F61(102.955,-158.796) F62(104.08,-157.796) G2(101.83,-217.796) G4(101.83,-215.796) G6(101.83,-213.796) G8(101.83,-211.796) G10(101.83,-209.796) G12(101.83,-207.796) G14(101.83,-205.796) G16(101.83,-203.796) G18(101.83,-201.796) G20(101.83,-199.796) G22(101.83,-197.796) G24(101.83,-195.796) G26(101.83,-193.796) G28(101.83,-191.796) G30(101.83,-189.796) G32(101.83,-187.796) G34(101.83,-185.796) G36(101.83,-183.796) G38(101.83,-181.796) G40(101.83,-179.796) G42(101.83,-177.796) G44(101.83,-175.796) G46(101.83,-173.796) G48(101.83,-171.796) G50(101.83,-169.796) G52(101.83,-167.796) G54(101.83,-165.796) G56(101.83,-163.796) G58(101.83,-161.796) G60(101.83,-159.796)
  custom 0.257x0.257 smd: Z5(116.454,-214.796) Z7(116.454,-212.796) Z9(116.454,-210.796) Z11(116.454,-208.796) Z13(116.454,-206.796) Z15(116.454,-204.796) Z17(116.454,-202.796) Z19(116.454,-200.796) Z21(116.454,-198.796) Z23(116.454,-196.796) Z25(116.454,-194.796) Z27(116.454,-192.796) Z29(116.454,-190.796) Z31(116.454,-188.796) Z33(116.454,-186.796) Z35(116.454,-184.796) Z37(116.454,-182.796) Z39(116.454,-180.796) Z41(116.454,-178.796) Z43(116.454,-176.796) Z45(116.454,-174.796) Z47(116.454,-172.796) Z49(116.454,-170.796) Z51(116.454,-168.796) Z53(116.454,-166.796) Z55(116.454,-164.796) Z57(116.454,-162.796) Z59(116.454,-160.796) Z61(116.454,-158.796)
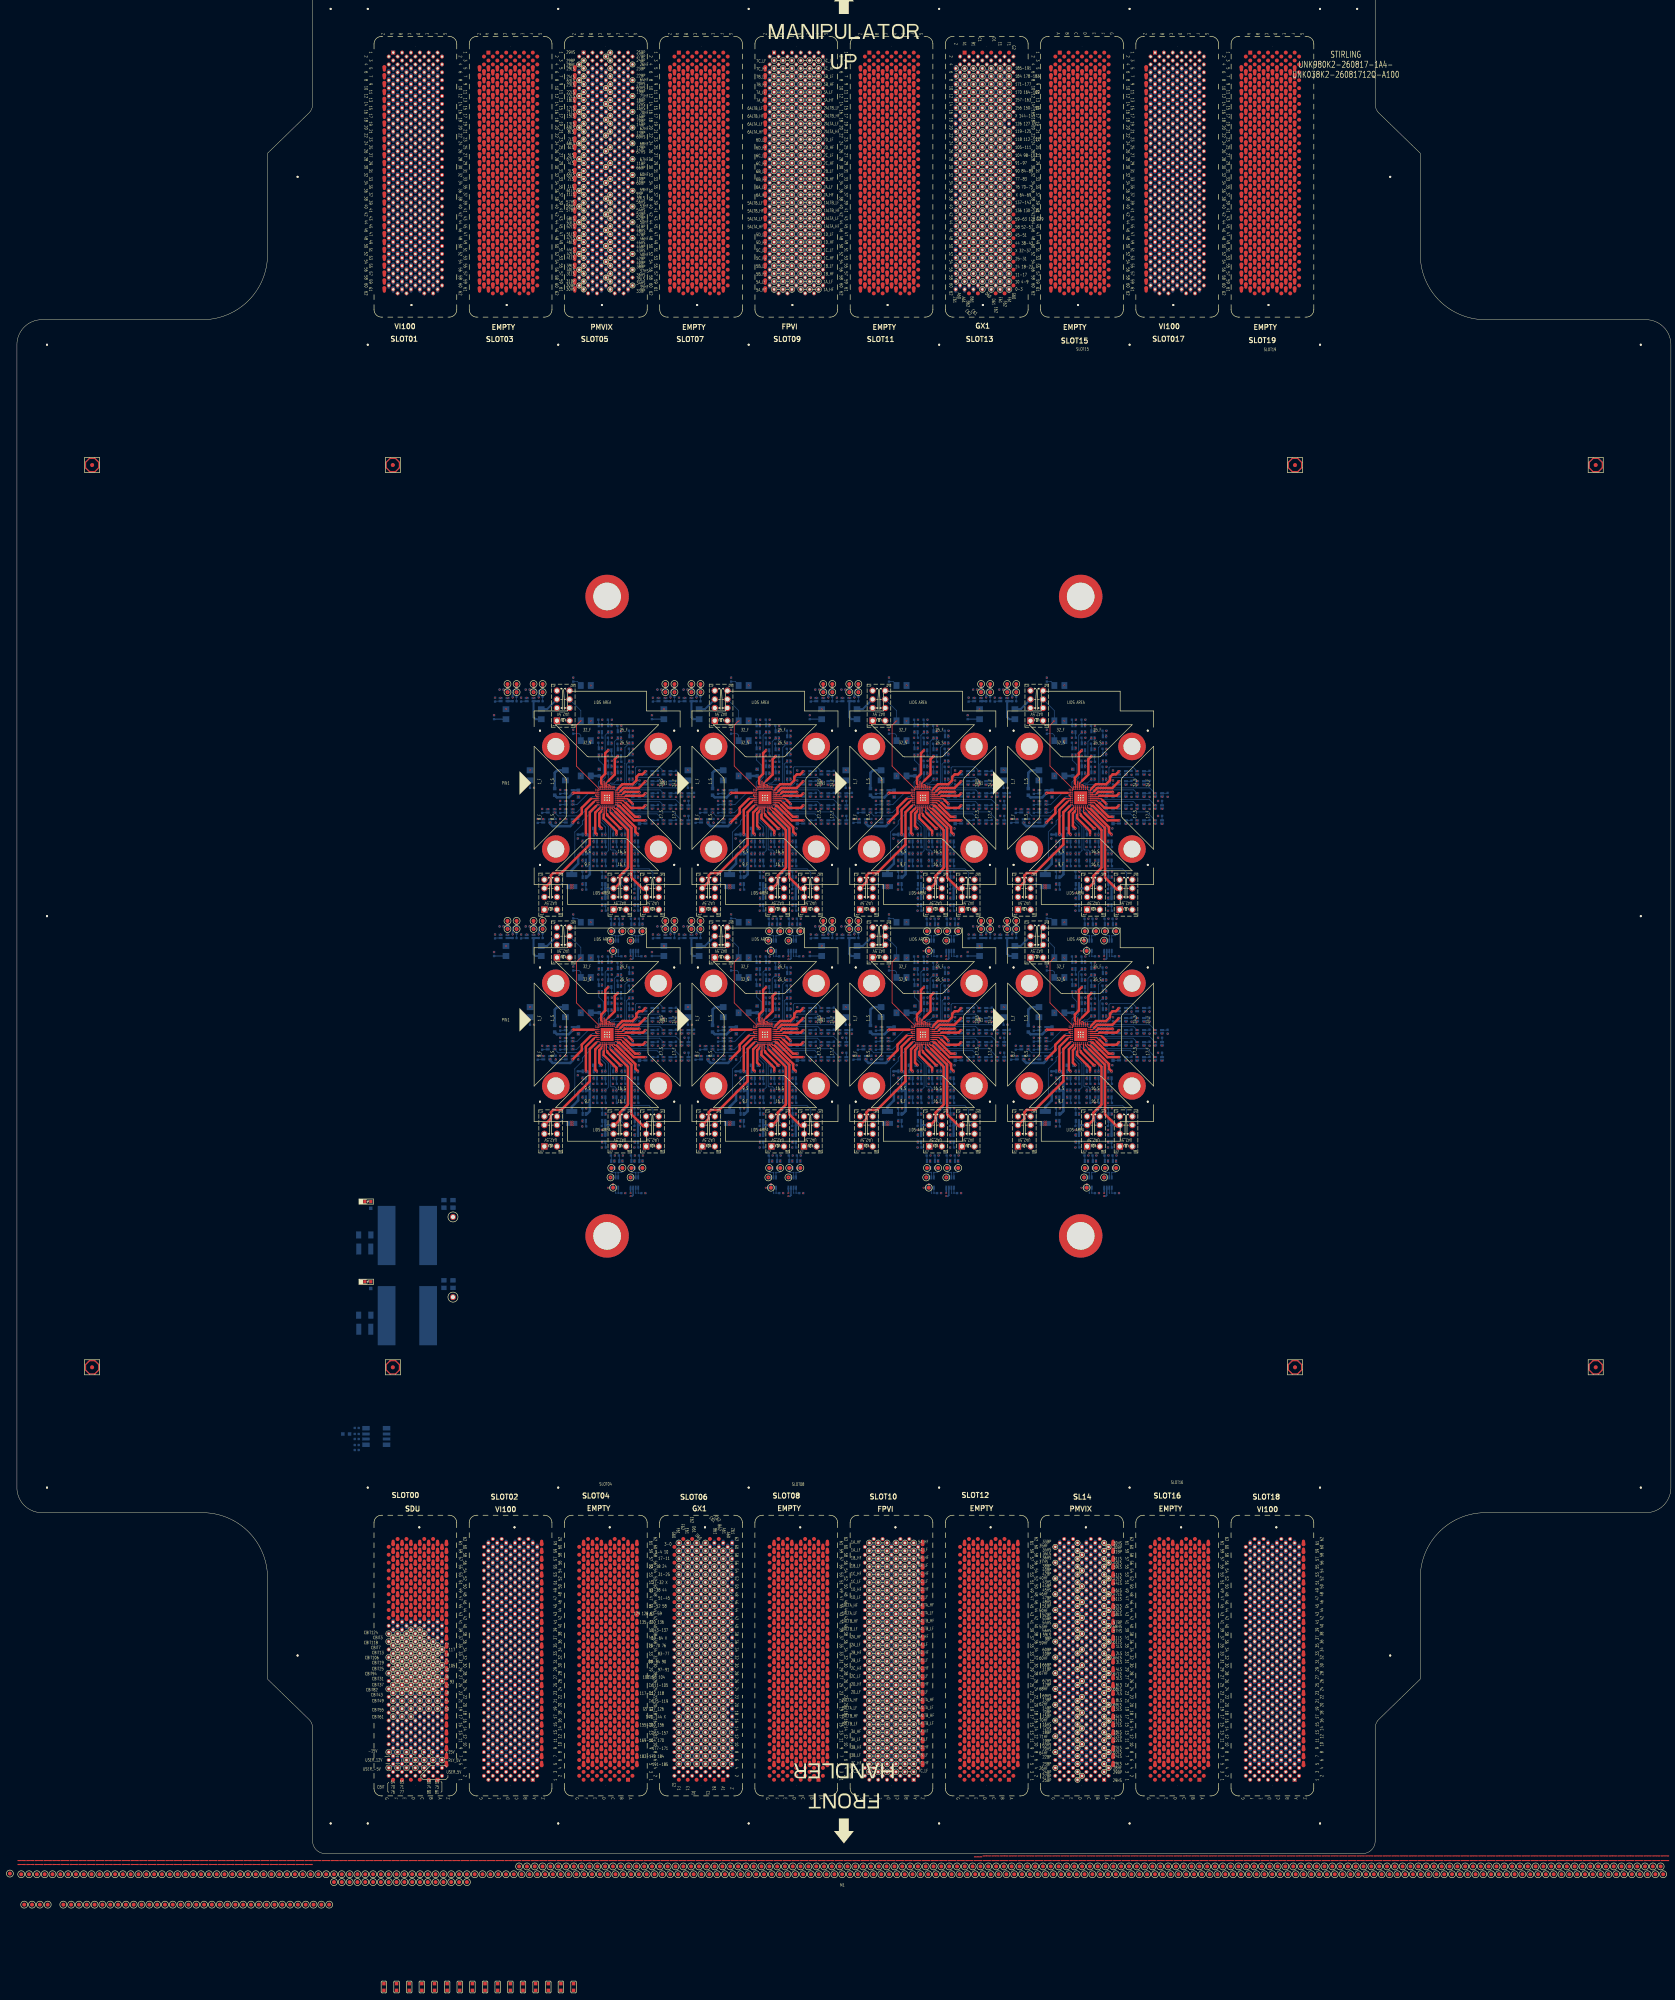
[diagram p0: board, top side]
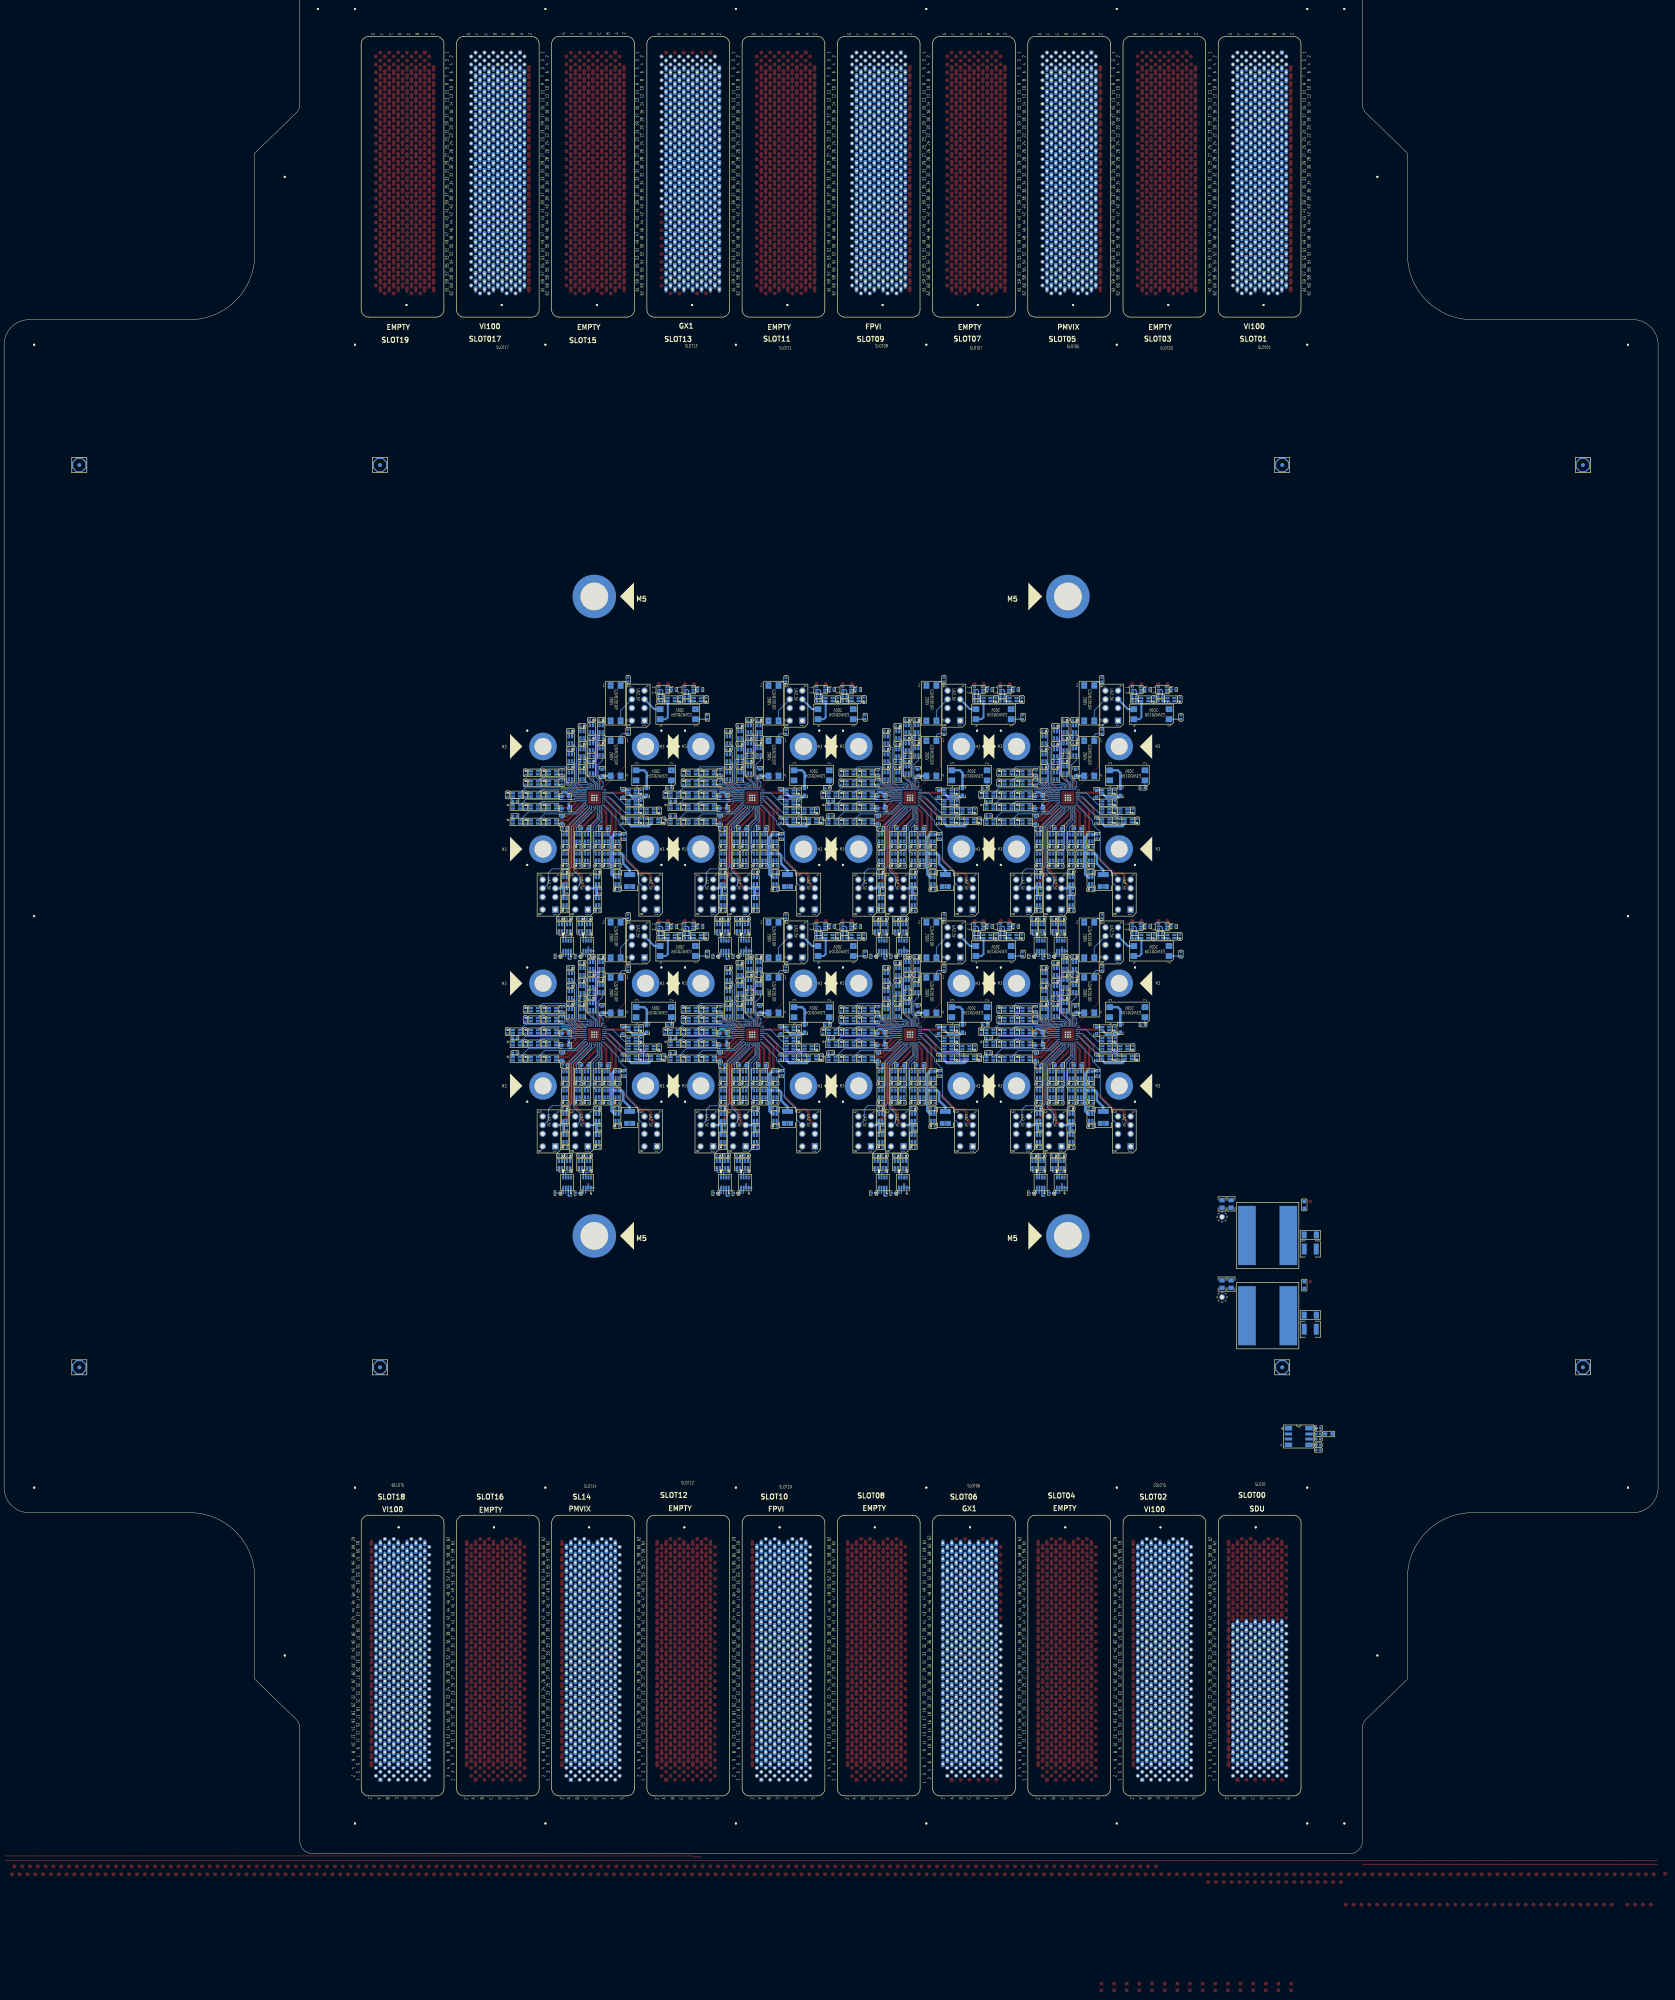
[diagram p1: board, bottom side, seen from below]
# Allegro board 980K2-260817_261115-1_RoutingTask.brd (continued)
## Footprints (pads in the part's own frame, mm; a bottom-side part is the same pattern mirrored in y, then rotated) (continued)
R0201
  rect 0.305x0.356 smd: 1(-0.3,0) 2(0.3,0)
R0402
  custom 0.15x0.15 smd: 1(-0.5,0) 2(0.5,0)
R0603
  rect 0.889x0.889 smd: 1(-0.85,0) 2(0.85,0)
RL_G3VM201DR_200V
  rect 1.5x1.7 smd: 1(-1.27,-4.475) 2(1.27,-4.475) 3(1.27,4.475) 4(-1.27,4.475)
RL_G3VM_4P_VSON4
  rect 1.016x0.559 smd: 1(-0.875,0.4) 2(-0.875,-0.4) 3(0.875,-0.4) 4(0.875,0.4)
RL_NECUA2_5V_V3
  rect 1.626x1.626 hole 1.041: 1(3.6,1.6)
  round 1.626 hole 1.041: 2(0.4,1.6) 3(-1.8,1.6) 4(-4,1.6) 5(-4,-1.6) 6(-1.8,-1.6) 7(0.4,-1.6) 8(3.6,-1.6)
SC70
  rect 0.406x0.762 smd: 1(-0.65,-1) 2(0,-1) 3(0.65,-1) 4(0.65,1) 5(0,1) 6(-0.65,1)
SK_QFN5X5_64P_0P5MM_JG_260817
  round 0.508 hole 1.61 unplated: (-17,17) (-17,-17) (17,17) (17,-17)
  round 0.3 smd: 1_F(-2.5,1.75) 1_S(-2.1,1.75) 2_F(-2.5,1.25) 2_S(-2.1,1.25) 3_F(-2.5,0.75) 3_S(-2.1,0.75) 4_F(-2.5,0.25) 4_S(-2.1,0.25) 5_F(-2.5,-0.25) 5_S(-2.1,-0.25) 6_F(-2.5,-0.75) 6_S(-2.1,-0.75) 7_F(-2.5,-1.25) 7_S(-2.1,-1.25) 8_F(-2.5,-1.75) 8_S(-2.1,-1.75) 9_F(-1.75,-2.5) 9_S(-1.75,-2.1) 10_F(-1.25,-2.5) 10_S(-1.25,-2.1) 11_F(-0.75,-2.5) 11_S(-0.75,-2.1) 12_F(-0.25,-2.5) 12_S(-0.25,-2.1) 13_F(0.25,-2.5) 13_S(0.25,-2.1) 14_F(0.75,-2.5) 14_S(0.75,-2.1) 15_F(1.25,-2.5) 15_S(1.25,-2.1) 16_F(1.75,-2.5) 16_S(1.75,-2.1) 17_F(2.5,-1.75) 17_S(2.1,-1.75) 18_F(2.5,-1.25) 18_S(2.1,-1.25) 19_F(2.5,-0.75) 19_S(2.1,-0.75) 20_F(2.5,-0.25) 20_S(2.1,-0.25) 21_F(2.5,0.25) 21_S(2.1,0.25) 22_F(2.5,0.75) 22_S(2.1,0.75) 23_F(2.5,1.25) 23_S(2.1,1.25) 24_F(2.5,1.75) 24_S(2.1,1.75) 25_F(1.75,2.5) 25_S(1.75,2.1) 26_F(1.25,2.5) 26_S(1.25,2.1) 27_F(0.75,2.5) 27_S(0.75,2.1) 28_F(0.25,2.5) 28_S(0.25,2.1) 29_F(-0.25,2.5) 29_S(-0.25,2.1) 30_F(-0.75,2.5) 30_S(-0.75,2.1) 31_F(-1.25,2.5) 31_S(-1.25,2.1) 32_F(-1.75,2.5) 32_S(-1.75,2.1)
  rect 3.3x3.3 smd: EPAD(0,0)
  round 0.508 hole 0.305: G1(-0.6,0.6) G2(0,0.6) G3(0.6,0.6) G4(-0.6,0) G5(0,0) G6(0.6,0) G7(-0.6,-0.6) G8(0,-0.6) G9(0.6,-0.6)
  round 7 hole 4.293: NUT1(-13,13) NUT2(13,13) NUT3(-13,-13) NUT4(13,-13)
SO8_206X127MM
  rect 1.905x1.143 smd: 1(-2.616,2.095) 4(-2.616,-2.095) 5(2.616,-2.095) 8(2.616,2.095)
  rect 1.905x0.762 smd: 2(-2.616,0.635) 3(-2.616,-0.635) 6(2.616,-0.635) 7(2.616,0.635)
SOT23_8P_0P65MM_H1P3MM
  rect 0.45x1.05 smd: 1(-0.975,-1.3) 2(-0.325,-1.3) 3(0.325,-1.3) 4(0.975,-1.3) 5(0.975,1.3) 6(0.325,1.3) 7(-0.325,1.3) 8(-0.975,1.3)
TP_040_T
  round 1.016 smd: 1(0,0)
TP_060_040
  round 1.524 hole 1.016: 1(0,0)
unnamed#2
  round 11.024 hole 7.01: NUT1(60,81) NUT2(-60,81) NUT3(60,-81) NUT4(-60,-81)

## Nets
48V: SLOT0.F2 SLOT0.G2
48V_RTN: SLOT0.D2 SLOT0.E2
+15V: SLOT0.B8 SLOT0.C8 SLOT0.D8
-15V: SLOT0.E8 SLOT0.F8 SLOT0.G8
GND: BC9.2 BU1.1(A0) BU1.2(A1) BU1.3(A2) BU1.4(GND) BU1.7(WP) CT1.2 CT2.2 CT3.2 CT7.2 CT8.2 CT9.2 LD1.2(B) LD3.2(B) R41.2 R42.2 SLOT0.A9 SLOT0.A10 SLOT0.A11 SLOT0.A12 SLOT0.A13 SLOT0.A14 SLOT0.A15 SLOT0.A17 SLOT0.A38 SLOT0.B9 SLOT0.B11 SLOT0.B13 SLOT0.B15 SLOT0.B17 SLOT0.B37 SLOT0.B38 SLOT0.C9 SLOT0.C11 SLOT0.C12 SLOT0.C13 SLOT0.C15 SLOT0.C17 SLOT0.D9 SLOT0.D10 SLOT0.D11 SLOT0.D13 SLOT0.D14 SLOT0.D15 SLOT0.E9 SLOT0.E11 SLOT0.E12 SLOT0.E13 SLOT0.E15 SLOT0.F9 SLOT0.F11 SLOT0.F13 SLOT0.F15 SLOT0.G10 SLOT0.G12 SLOT01.A2(GND#A2) SLOT01.A4(GND#A4) SLOT01.A6(GND#A6) SLOT01.A8(GND#A8) SLOT01.A10(GND#A10) SLOT01.A12(GND#A12) SLOT01.A14(GND#A14) SLOT01.A16(GND#A16) SLOT01.A18(GND#A18) SLOT01.A20(GND#A20) SLOT01.A22(GND#A22) SLOT01.A24(GND#A24) SLOT01.A26(GND#A26) SLOT01.A28(GND#A28) SLOT01.A30(GND#A30) SLOT01.A32(GND#A32) SLOT01.A34(GND#A34) SLOT01.A36(GND#A36) SLOT01.A38(GND#A38) SLOT01.A40(GND#A40) SLOT01.B2(GND#B2) SLOT01.B4(GND#B4) SLOT01.B6(GND#B6) SLOT01.B8(GND#B8) SLOT01.B10(GND#B10) SLOT01.B12(GND#B12) SLOT01.B14(GND#B14) SLOT01.B16(GND#B16) SLOT01.B18(GND#B18) SLOT01.B20(GND#B20) SLOT01.B22(GND#B22) SLOT01.B24(GND#B24) SLOT01.B26(GND#B26) SLOT01.B28(GND#B28) SLOT01.B30(GND#B30) SLOT01.B32(GND#B32) SLOT01.B34(GND#B34) SLOT01.B36(GND#B36) SLOT01.B38(GND#B38) SLOT01.B40(GND#B40) SLOT01.C2(GND#C2) SLOT01.C4(GND#C4) SLOT01.C6(GND#C6) SLOT01.C8(GND#C8) SLOT01.C10(GND#C10) SLOT01.C12(GND#C12) SLOT01.C14(GND#C14) SLOT01.C16(GND#C16) SLOT01.C18(GND#C18) SLOT01.C20(GND#C20) SLOT01.C22(GND#C22) SLOT01.C24(GND#C24) SLOT01.C26(GND#C26) SLOT01.C28(GND#C28) SLOT01.C30(GND#C30) SLOT01.C32(GND#C32) SLOT01.C34(GND#C34) SLOT01.C36(GND#C36) SLOT01.C38(GND#C38) SLOT01.C40(GND#C40) SLOT01.D2(GND#D2) SLOT01.D4(GND#D4) SLOT01.D6(GND#D6) SLOT01.D8(GND#D8) SLOT01.D10(GND#D10) SLOT01.D12(GND#D12) SLOT01.D14(GND#D14) SLOT01.D16(GND#D16) SLOT01.D18(GND#D18) SLOT01.D20(GND#D20) SLOT01.D22(GND#D22) SLOT01.D24(GND#D24) SLOT01.D26(GND#D26) SLOT01.D28(GND#D28) SLOT01.D30(GND#D30) SLOT01.D32(GND#D32) SLOT01.D34(GND#D34) SLOT01.D36(GND#D36) SLOT01.D38(GND#D38) SLOT01.D40(GND#D40) SLOT01.E2(GND#E2) SLOT01.E4(GND#E4) SLOT01.E6(GND#E6) SLOT01.E8(GND#E8) SLOT01.E10(GND#E10) SLOT01.E12(GND#E12) SLOT01.E14(GND#E14) SLOT01.E16(GND#E16) SLOT01.E18(GND#E18) SLOT01.E20(GND#E20) SLOT01.E22(GND#E22) SLOT01.E24(GND#E24) SLOT01.E26(GND#E26) SLOT01.E28(GND#E28) SLOT01.E30(GND#E30) SLOT01.E32(GND#E32) SLOT01.E34(GND#E34) SLOT01.E36(GND#E36) SLOT01.E38(GND#E38) SLOT01.E40(GND#E40) SLOT01.F2(GND#F2) SLOT01.F4(GND#F4) SLOT01.F6(GND#F6) SLOT01.F8(GND#F8) SLOT01.F10(GND#F10) SLOT01.F12(GND#F12) SLOT01.F14(GND#F14) SLOT01.F16(GND#F16) SLOT01.F18(GND#F18) SLOT01.F20(GND#F20) SLOT01.F22(GND#F22) SLOT01.F24(GND#F24) SLOT01.F26(GND#F26) SLOT01.F28(GND#F28) SLOT01.F30(GND#F30) SLOT01.F32(GND#F32) SLOT01.F34(GND#F34) SLOT01.F36(GND#F36) SLOT01.F38(GND#F38) SLOT01.F40(GND#F40) SLOT01.G2(GND#G2) SLOT01.G4(GND#G4) SLOT01.G6(GND#G6) SLOT01.G8(GND#G8) SLOT01.G10(GND#G10) SLOT01.G12(GND#G12) SLOT01.G14(GND#G14) SLOT01.G16(GND#G16) SLOT01.G18(GND#G18) SLOT01.G20(GND#G20) SLOT01.G22(GND#G22) SLOT01.G24(GND#G24) SLOT01.G26(GND#G26) SLOT01.G28(GND#G28) SLOT01.G30(GND#G30) SLOT01.G32(GND#G32) SLOT01.G34(GND#G34) SLOT01.G36(GND#G36) SLOT01.G38(GND#G38) SLOT01.G40(GND#G40) SLOT02.A2(GND#A2) SLOT02.A4(GND#A4) SLOT02.A6(GND#A6) SLOT02.A8(GND#A8) SLOT02.A10(GND#A10) SLOT02.A12(GND#A12) SLOT02.A14(GND#A14) SLOT02.A16(GND#A16) SLOT02.A18(GND#A18) SLOT02.A20(GND#A20) SLOT02.A22(GND#A22) SLOT02.A24(GND#A24) SLOT02.A26(GND#A26) SLOT02.A28(GND#A28) SLOT02.A30(GND#A30) SLOT02.A32(GND#A32) SLOT02.A34(GND#A34) SLOT02.A36(GND#A36) SLOT02.A38(GND#A38) SLOT02.A40(GND#A40) SLOT02.B2(GND#B2) SLOT02.B4(GND#B4) SLOT02.B6(GND#B6) SLOT02.B8(GND#B8) SLOT02.B10(GND#B10) SLOT02.B12(GND#B12) SLOT02.B14(GND#B14) SLOT02.B16(GND#B16) SLOT02.B18(GND#B18) SLOT02.B20(GND#B20) SLOT02.B22(GND#B22) SLOT02.B24(GND#B24) SLOT02.B26(GND#B26) SLOT02.B28(GND#B28) SLOT02.B30(GND#B30) SLOT02.B32(GND#B32) SLOT02.B34(GND#B34) SLOT02.B36(GND#B36) SLOT02.B38(GND#B38) SLOT02.B40(GND#B40) SLOT02.C2(GND#C2) SLOT02.C4(GND#C4) SLOT02.C6(GND#C6) SLOT02.C8(GND#C8) SLOT02.C10(GND#C10) SLOT02.C12(GND#C12) SLOT02.C14(GND#C14) SLOT02.C16(GND#C16) SLOT02.C18(GND#C18) SLOT02.C20(GND#C20) SLOT02.C22(GND#C22) SLOT02.C24(GND#C24) SLOT02.C26(GND#C26) SLOT02.C28(GND#C28) SLOT02.C30(GND#C30) SLOT02.C32(GND#C32) SLOT02.C34(GND#C34) SLOT02.C36(GND#C36) SLOT02.C38(GND#C38) SLOT02.C40(GND#C40) SLOT02.D2(GND#D2) SLOT02.D4(GND#D4) SLOT02.D6(GND#D6) SLOT02.D8(GND#D8) SLOT02.D10(GND#D10) SLOT02.D12(GND#D12) SLOT02.D14(GND#D14) SLOT02.D16(GND#D16) SLOT02.D18(GND#D18) SLOT02.D20(GND#D20) SLOT02.D22(GND#D22) SLOT02.D24(GND#D24) SLOT02.D26(GND#D26) SLOT02.D28(GND#D28) SLOT02.D30(GND#D30) SLOT02.D32(GND#D32) SLOT02.D34(GND#D34) SLOT02.D36(GND#D36) SLOT02.D38(GND#D38) SLOT02.D40(GND#D40) SLOT02.E2(GND#E2) SLOT02.E4(GND#E4) SLOT02.E6(GND#E6) SLOT02.E8(GND#E8) SLOT02.E10(GND#E10) SLOT02.E12(GND#E12) SLOT02.E14(GND#E14) SLOT02.E16(GND#E16) SLOT02.E18(GND#E18) SLOT02.E20(GND#E20) SLOT02.E22(GND#E22) SLOT02.E24(GND#E24) SLOT02.E26(GND#E26) SLOT02.E28(GND#E28) SLOT02.E30(GND#E30) SLOT02.E32(GND#E32) SLOT02.E34(GND#E34) SLOT02.E36(GND#E36) SLOT02.E38(GND#E38) SLOT02.E40(GND#E40) SLOT02.F2(GND#F2) SLOT02.F4(GND#F4) SLOT02.F6(GND#F6) SLOT02.F8(GND#F8) SLOT02.F10(GND#F10) SLOT02.F12(GND#F12) SLOT02.F14(GND#F14) SLOT02.F16(GND#F16) SLOT02.F18(GND#F18) SLOT02.F20(GND#F20) SLOT02.F22(GND#F22) SLOT02.F24(GND#F24) SLOT02.F26(GND#F26) SLOT02.F28(GND#F28) SLOT02.F30(GND#F30) SLOT02.F32(GND#F32) SLOT02.F34(GND#F34) SLOT02.F36(GND#F36) SLOT02.F38(GND#F38) SLOT02.F40(GND#F40) SLOT02.G2(GND#G2) SLOT02.G4(GND#G4) SLOT02.G6(GND#G6) SLOT02.G8(GND#G8) SLOT02.G10(GND#G10) SLOT02.G12(GND#G12) SLOT02.G14(GND#G14) SLOT02.G16(GND#G16) SLOT02.G18(GND#G18) SLOT02.G20(GND#G20) SLOT02.G22(GND#G22) SLOT02.G24(GND#G24) SLOT02.G26(GND#G26) SLOT02.G28(GND#G28) SLOT02.G30(GND#G30) SLOT02.G32(GND#G32) SLOT02.G34(GND#G34) SLOT02.G36(GND#G36) SLOT02.G38(GND#G38) SLOT02.G40(GND#G40) SLOT05.A2 SLOT05.A6 SLOT05.A10 SLOT05.A14 SLOT05.A18 SLOT05.A22 SLOT05.A26 SLOT05.A30 SLOT05.A34 SLOT05.A38 SLOT05.A42 SLOT05.A46 SLOT05.A50 SLOT05.A54 SLOT05.A58 SLOT05.B4 SLOT05.B8 SLOT05.B12 SLOT05.B16 SLOT05.B20 SLOT05.B24 SLOT05.B28 SLOT05.B32 SLOT05.B36 SLOT05.B40 SLOT05.B44 SLOT05.B48 SLOT05.B52 SLOT05.B56 SLOT05.B60 SLOT05.C2 SLOT05.C6 SLOT05.C10 SLOT05.C14 SLOT05.C18 SLOT05.C22 SLOT05.C26 SLOT05.C30 SLOT05.C34 SLOT05.C38 SLOT05.C42 SLOT05.C46 SLOT05.C50 SLOT05.C54 SLOT05.C58 SLOT05.D4 SLOT05.D8 SLOT05.D12 SLOT05.D16 SLOT05.D20 SLOT05.D24 SLOT05.D28 SLOT05.D32 SLOT05.D36 SLOT05.D40 SLOT05.D44 SLOT05.D48 SLOT05.D52 SLOT05.D56 SLOT05.D60 SLOT05.E2 SLOT05.E6 SLOT05.E10 SLOT05.E14 SLOT05.E18 SLOT05.E22 SLOT05.E26 SLOT05.E30 SLOT05.E34 SLOT05.E38 SLOT05.E42 SLOT05.E46 SLOT05.E50 SLOT05.E54 SLOT05.E58 SLOT05.F4 SLOT05.F8 SLOT05.F12 SLOT05.F16 SLOT05.F20 SLOT05.F24 SLOT05.F28 SLOT05.F32 SLOT05.F36 SLOT05.F40 SLOT05.F44 SLOT05.F48 SLOT05.F52 SLOT05.F56 SLOT05.F60 SLOT05.G2 SLOT05.G6 SLOT05.G10 SLOT05.G14 SLOT05.G18 SLOT05.G22 SLOT05.G26 SLOT05.G30 SLOT05.G34 SLOT05.G38 SLOT05.G42 SLOT05.G46 SLOT05.G50 SLOT05.G54 SLOT05.G58 SLOT06.A6 SLOT06.A8 SLOT06.A10 SLOT06.A12 SLOT06.A14 SLOT06.A16 SLOT06.A18 SLOT06.A20 SLOT06.A22 SLOT06.A24 SLOT06.A26 SLOT06.A28 SLOT06.A30 SLOT06.A32 SLOT06.A34 SLOT06.A36 SLOT06.A38 SLOT06.A40 SLOT06.A42 SLOT06.A44 SLOT06.A46 SLOT06.A48 SLOT06.A50 SLOT06.A52 SLOT06.A54 SLOT06.A56 SLOT06.A58 SLOT06.A60 SLOT06.B6 SLOT06.B8 SLOT06.B10 SLOT06.B12 SLOT06.B14 SLOT06.B16 SLOT06.B18 SLOT06.B20 SLOT06.B22 SLOT06.B24 SLOT06.B26 SLOT06.B28 SLOT06.B30 SLOT06.B32 SLOT06.B34 SLOT06.B36 SLOT06.B38 SLOT06.B40 SLOT06.B42 SLOT06.B44 SLOT06.B46 SLOT06.B48 SLOT06.B50 SLOT06.B52 SLOT06.B54 SLOT06.B56 SLOT06.B58 SLOT06.B60 SLOT06.C6 SLOT06.C8 SLOT06.C10 SLOT06.C12 SLOT06.C14 SLOT06.C16 SLOT06.C18 SLOT06.C20 SLOT06.C22 SLOT06.C24 SLOT06.C26 SLOT06.C28 SLOT06.C30 SLOT06.C32 SLOT06.C34 SLOT06.C36 SLOT06.C38 SLOT06.C40 SLOT06.C42 SLOT06.C44 SLOT06.C46 SLOT06.C48 SLOT06.C50 SLOT06.C52 SLOT06.C54 SLOT06.C56 SLOT06.C58 SLOT06.C60 SLOT06.D6 SLOT06.D8 SLOT06.D10 SLOT06.D12 SLOT06.D14 SLOT06.D16 SLOT06.D18 SLOT06.D20 SLOT06.D22 SLOT06.D24 SLOT06.D26 SLOT06.D28 SLOT06.D30 SLOT06.D32 SLOT06.D34 SLOT06.D36 SLOT06.D38 SLOT06.D40 SLOT06.D42 SLOT06.D44 SLOT06.D46 SLOT06.D48 SLOT06.D50 SLOT06.D52 SLOT06.D54 SLOT06.D56 SLOT06.D58 SLOT06.D60 SLOT06.E6 SLOT06.E8 SLOT06.E10 SLOT06.E12 SLOT06.E14 SLOT06.E16 SLOT06.E18 SLOT06.E20 SLOT06.E22 SLOT06.E24 SLOT06.E26 SLOT06.E28 SLOT06.E30 SLOT06.E32 SLOT06.E34 SLOT06.E36 SLOT06.E38 SLOT06.E40 SLOT06.E42 SLOT06.E44 SLOT06.E46 SLOT06.E48 SLOT06.E50 SLOT06.E52 SLOT06.E54 SLOT06.E56 SLOT06.E58 SLOT06.E60 SLOT06.F6 SLOT06.F8 SLOT06.F10 SLOT06.F12 SLOT06.F14 SLOT06.F16 SLOT06.F18 SLOT06.F20 SLOT06.F22 SLOT06.F24 SLOT06.F26 SLOT06.F28 SLOT06.F30 SLOT06.F32 SLOT06.F34 SLOT06.F36 SLOT06.F38 SLOT06.F40 SLOT06.F42 SLOT06.F44 SLOT06.F46 SLOT06.F48 SLOT06.F50 SLOT06.F52 SLOT06.F54 SLOT06.F56 SLOT06.F58 SLOT06.F60 SLOT09.A16(GND[1]) SLOT09.A30(GND[2]) SLOT09.A36(GND[3]) SLOT09.A50(GND[4]) SLOT09.A56(GND[5]) SLOT09.B62(GND[6]) SLOT09.C62(GND[7]) SLOT09.E62(GND[8]) SLOT09.F62(GND[9]) SLOT09.G16(GND[10]) SLOT09.G30(GND[11]) SLOT09.G36(GND[12]) SLOT09.G50(GND[13]) SLOT09.G56(GND[14]) SLOT10.A16(GND[1]) SLOT10.A30(GND[2]) SLOT10.A36(GND[3]) SLOT10.A50(GND[4]) SLOT10.A56(GND[5]) SLOT10.B62(GND[6]) SLOT10.C62(GND[7]) SLOT10.E62(GND[8]) SLOT10.F62(GND[9]) SLOT10.G16(GND[10]) SLOT10.G30(GND[11]) SLOT10.G36(GND[12]) SLOT10.G50(GND[13]) SLOT10.G56(GND[14]) SLOT13.A6 SLOT13.A8 SLOT13.A10 SLOT13.A12 SLOT13.A14 SLOT13.A16 SLOT13.A18 SLOT13.A20 SLOT13.A22 SLOT13.A24 SLOT13.A26 SLOT13.A28 SLOT13.A30 SLOT13.A32 SLOT13.A34 SLOT13.A36 SLOT13.A38 SLOT13.A40 SLOT13.A42 SLOT13.A44 SLOT13.A46 SLOT13.A48 SLOT13.A50 SLOT13.A52 SLOT13.A54 SLOT13.A56 SLOT13.A58 SLOT13.A60 SLOT13.B6 SLOT13.B8 SLOT13.B10 SLOT13.B12 SLOT13.B14 SLOT13.B16 SLOT13.B18 SLOT13.B20 SLOT13.B22 SLOT13.B24 SLOT13.B26 SLOT13.B28 SLOT13.B30 SLOT13.B32 SLOT13.B34 SLOT13.B36 SLOT13.B38 SLOT13.B40 SLOT13.B42 SLOT13.B44 SLOT13.B46 SLOT13.B48 SLOT13.B50 SLOT13.B52 SLOT13.B54 SLOT13.B56 SLOT13.B58 SLOT13.B60 SLOT13.C6 SLOT13.C8 SLOT13.C10 SLOT13.C12 SLOT13.C14 SLOT13.C16 SLOT13.C18 SLOT13.C20 SLOT13.C22 SLOT13.C24 SLOT13.C26 SLOT13.C28 SLOT13.C30 SLOT13.C32 SLOT13.C34 SLOT13.C36 SLOT13.C38 SLOT13.C40 SLOT13.C42 SLOT13.C44 SLOT13.C46 SLOT13.C48 SLOT13.C50 SLOT13.C52 SLOT13.C54 SLOT13.C56 SLOT13.C58 SLOT13.C60 SLOT13.D6 SLOT13.D8 SLOT13.D10 SLOT13.D12 SLOT13.D14 SLOT13.D16 SLOT13.D18 SLOT13.D20 SLOT13.D22 SLOT13.D24 SLOT13.D26 SLOT13.D28 SLOT13.D30 SLOT13.D32 SLOT13.D34 SLOT13.D36 SLOT13.D38 SLOT13.D40 SLOT13.D42 SLOT13.D44 SLOT13.D46 SLOT13.D48 SLOT13.D50 SLOT13.D52 SLOT13.D54 SLOT13.D56 SLOT13.D58 SLOT13.D60 SLOT13.E6 SLOT13.E8 SLOT13.E10 SLOT13.E12 SLOT13.E14 SLOT13.E16 SLOT13.E18 SLOT13.E20 SLOT13.E22 SLOT13.E24 SLOT13.E26 SLOT13.E28 SLOT13.E30 SLOT13.E32 SLOT13.E34 SLOT13.E36 SLOT13.E38 SLOT13.E40 SLOT13.E42 SLOT13.E44 SLOT13.E46 SLOT13.E48 SLOT13.E50 SLOT13.E52 SLOT13.E54 SLOT13.E56 SLOT13.E58 SLOT13.E60 SLOT13.F6 SLOT13.F8 SLOT13.F10 SLOT13.F12 SLOT13.F14 SLOT13.F16 SLOT13.F18 SLOT13.F20 SLOT13.F22 SLOT13.F24 SLOT13.F26 SLOT13.F28 SLOT13.F30 SLOT13.F32 SLOT13.F34 SLOT13.F36 SLOT13.F38 SLOT13.F40 SLOT13.F42 SLOT13.F44 SLOT13.F46 SLOT13.F48 SLOT13.F50 SLOT13.F52 SLOT13.F54 SLOT13.F56 SLOT13.F58 SLOT13.F60 SLOT14.A2 SLOT14.A6 SLOT14.A10 SLOT14.A14 SLOT14.A18 SLOT14.A22 SLOT14.A26 SLOT14.A30 SLOT14.A34 SLOT14.A38 SLOT14.A42 SLOT14.A46 SLOT14.A50 SLOT14.A54 SLOT14.A58 SLOT14.B4 SLOT14.B8 SLOT14.B12 SLOT14.B16 SLOT14.B20 SLOT14.B24 SLOT14.B28 SLOT14.B32 SLOT14.B36 SLOT14.B40 SLOT14.B44 SLOT14.B48 SLOT14.B52 SLOT14.B56 SLOT14.B60 SLOT14.C2 SLOT14.C6 SLOT14.C10 SLOT14.C14 SLOT14.C18 SLOT14.C22 SLOT14.C26 SLOT14.C30 SLOT14.C34 SLOT14.C38 SLOT14.C42 SLOT14.C46 SLOT14.C50 SLOT14.C54 SLOT14.C58 SLOT14.D4 SLOT14.D8 SLOT14.D12 SLOT14.D16 SLOT14.D20 SLOT14.D24 SLOT14.D28 SLOT14.D32 SLOT14.D36 SLOT14.D40 SLOT14.D44 SLOT14.D48 SLOT14.D52 SLOT14.D56 SLOT14.D60 SLOT14.E2 SLOT14.E6 SLOT14.E10 SLOT14.E14 SLOT14.E18 SLOT14.E22 SLOT14.E26 SLOT14.E30 SLOT14.E34 SLOT14.E38 SLOT14.E42 SLOT14.E46 SLOT14.E50 SLOT14.E54 SLOT14.E58 SLOT14.F4 SLOT14.F8 SLOT14.F12 SLOT14.F16 SLOT14.F20 SLOT14.F24 SLOT14.F28 SLOT14.F32 SLOT14.F36 SLOT14.F40 SLOT14.F44 SLOT14.F48 SLOT14.F52 SLOT14.F56 SLOT14.F60 SLOT14.G2 SLOT14.G6 SLOT14.G10 SLOT14.G14 SLOT14.G18 SLOT14.G22 SLOT14.G26 SLOT14.G30 SLOT14.G34 SLOT14.G38 SLOT14.G42 SLOT14.G46 SLOT14.G50 SLOT14.G54 SLOT14.G58 SLOT17.A2(GND#A2) SLOT17.A4(GND#A4) SLOT17.A6(GND#A6) SLOT17.A8(GND#A8) SLOT17.A10(GND#A10) SLOT17.A12(GND#A12) SLOT17.A14(GND#A14) SLOT17.A16(GND#A16) SLOT17.A18(GND#A18) SLOT17.A20(GND#A20) SLOT17.A22(GND#A22) SLOT17.A24(GND#A24) SLOT17.A26(GND#A26) SLOT17.A28(GND#A28) SLOT17.A30(GND#A30) SLOT17.A32(GND#A32) SLOT17.A34(GND#A34) SLOT17.A36(GND#A36) SLOT17.A38(GND#A38) SLOT17.A40(GND#A40) SLOT17.B2(GND#B2) SLOT17.B4(GND#B4) SLOT17.B6(GND#B6) SLOT17.B8(GND#B8) SLOT17.B10(GND#B10) SLOT17.B12(GND#B12) SLOT17.B14(GND#B14) SLOT17.B16(GND#B16) SLOT17.B18(GND#B18) SLOT17.B20(GND#B20) SLOT17.B22(GND#B22) SLOT17.B24(GND#B24) SLOT17.B26(GND#B26) SLOT17.B28(GND#B28) SLOT17.B30(GND#B30) SLOT17.B32(GND#B32) SLOT17.B34(GND#B34) SLOT17.B36(GND#B36) SLOT17.B38(GND#B38) SLOT17.B40(GND#B40) SLOT17.C2(GND#C2) SLOT17.C4(GND#C4) SLOT17.C6(GND#C6) SLOT17.C8(GND#C8) SLOT17.C10(GND#C10) SLOT17.C12(GND#C12) SLOT17.C14(GND#C14) SLOT17.C16(GND#C16) SLOT17.C18(GND#C18) SLOT17.C20(GND#C20) SLOT17.C22(GND#C22) SLOT17.C24(GND#C24) SLOT17.C26(GND#C26) SLOT17.C28(GND#C28) SLOT17.C30(GND#C30) SLOT17.C32(GND#C32) SLOT17.C34(GND#C34) SLOT17.C36(GND#C36) SLOT17.C38(GND#C38) SLOT17.C40(GND#C40) SLOT17.D2(GND#D2) SLOT17.D4(GND#D4) SLOT17.D6(GND#D6) SLOT17.D8(GND#D8) SLOT17.D10(GND#D10) SLOT17.D12(GND#D12) SLOT17.D14(GND#D14) SLOT17.D16(GND#D16) SLOT17.D18(GND#D18) SLOT17.D20(GND#D20) SLOT17.D22(GND#D22) SLOT17.D24(GND#D24) SLOT17.D26(GND#D26) SLOT17.D28(GND#D28) SLOT17.D30(GND#D30) SLOT17.D32(GND#D32) SLOT17.D34(GND#D34) SLOT17.D36(GND#D36) SLOT17.D38(GND#D38) SLOT17.D40(GND#D40) SLOT17.E2(GND#E2) SLOT17.E4(GND#E4) SLOT17.E6(GND#E6) SLOT17.E8(GND#E8) SLOT17.E10(GND#E10) SLOT17.E12(GND#E12) SLOT17.E14(GND#E14) SLOT17.E16(GND#E16) SLOT17.E18(GND#E18) SLOT17.E20(GND#E20) SLOT17.E22(GND#E22) SLOT17.E24(GND#E24) SLOT17.E26(GND#E26) SLOT17.E28(GND#E28) SLOT17.E30(GND#E30) SLOT17.E32(GND#E32) SLOT17.E34(GND#E34) SLOT17.E36(GND#E36) SLOT17.E38(GND#E38) SLOT17.E40(GND#E40) SLOT17.F2(GND#F2) SLOT17.F4(GND#F4) SLOT17.F6(GND#F6) SLOT17.F8(GND#F8) SLOT17.F10(GND#F10) SLOT17.F12(GND#F12) SLOT17.F14(GND#F14) SLOT17.F16(GND#F16) SLOT17.F18(GND#F18) SLOT17.F20(GND#F20) SLOT17.F22(GND#F22) SLOT17.F24(GND#F24) SLOT17.F26(GND#F26) SLOT17.F28(GND#F28) SLOT17.F30(GND#F30) SLOT17.F32(GND#F32) SLOT17.F34(GND#F34) SLOT17.F36(GND#F36) SLOT17.F38(GND#F38) SLOT17.F40(GND#F40) SLOT17.G2(GND#G2) SLOT17.G4(GND#G4) SLOT17.G6(GND#G6) SLOT17.G8(GND#G8) SLOT17.G10(GND#G10) SLOT17.G12(GND#G12) SLOT17.G14(GND#G14) SLOT17.G16(GND#G16) SLOT17.G18(GND#G18) SLOT17.G20(GND#G20) SLOT17.G22(GND#G22) SLOT17.G24(GND#G24) SLOT17.G26(GND#G26) SLOT17.G28(GND#G28) SLOT17.G30(GND#G30) SLOT17.G32(GND#G32) SLOT17.G34(GND#G34) SLOT17.G36(GND#G36) SLOT17.G38(GND#G38) SLOT17.G40(GND#G40) SLOT18.A2(GND#A2) SLOT18.A4(GND#A4) SLOT18.A6(GND#A6) SLOT18.A8(GND#A8) SLOT18.A10(GND#A10) SLOT18.A12(GND#A12) SLOT18.A14(GND#A14) SLOT18.A16(GND#A16) SLOT18.A18(GND#A18) SLOT18.A20(GND#A20) SLOT18.A22(GND#A22) SLOT18.A24(GND#A24) SLOT18.A26(GND#A26) SLOT18.A28(GND#A28) SLOT18.A30(GND#A30) SLOT18.A32(GND#A32) SLOT18.A34(GND#A34) SLOT18.A36(GND#A36) SLOT18.A38(GND#A38) SLOT18.A40(GND#A40) SLOT18.B2(GND#B2) SLOT18.B4(GND#B4) SLOT18.B6(GND#B6) SLOT18.B8(GND#B8) SLOT18.B10(GND#B10) SLOT18.B12(GND#B12) SLOT18.B14(GND#B14) SLOT18.B16(GND#B16) SLOT18.B18(GND#B18) SLOT18.B20(GND#B20) SLOT18.B22(GND#B22) SLOT18.B24(GND#B24) SLOT18.B26(GND#B26) SLOT18.B28(GND#B28) SLOT18.B30(GND#B30) SLOT18.B32(GND#B32) SLOT18.B34(GND#B34) SLOT18.B36(GND#B36) SLOT18.B38(GND#B38) SLOT18.B40(GND#B40) SLOT18.C2(GND#C2) SLOT18.C4(GND#C4) SLOT18.C6(GND#C6) SLOT18.C8(GND#C8) SLOT18.C10(GND#C10) SLOT18.C12(GND#C12) SLOT18.C14(GND#C14) SLOT18.C16(GND#C16) SLOT18.C18(GND#C18) SLOT18.C20(GND#C20) SLOT18.C22(GND#C22) SLOT18.C24(GND#C24) SLOT18.C26(GND#C26) SLOT18.C28(GND#C28) SLOT18.C30(GND#C30) SLOT18.C32(GND#C32) SLOT18.C34(GND#C34) SLOT18.C36(GND#C36) SLOT18.C38(GND#C38) SLOT18.C40(GND#C40) SLOT18.D2(GND#D2) SLOT18.D4(GND#D4) SLOT18.D6(GND#D6) SLOT18.D8(GND#D8) SLOT18.D10(GND#D10) SLOT18.D12(GND#D12) SLOT18.D14(GND#D14) SLOT18.D16(GND#D16) SLOT18.D18(GND#D18) SLOT18.D20(GND#D20) SLOT18.D22(GND#D22) SLOT18.D24(GND#D24) SLOT18.D26(GND#D26) SLOT18.D28(GND#D28) SLOT18.D30(GND#D30) SLOT18.D32(GND#D32) SLOT18.D34(GND#D34) SLOT18.D36(GND#D36) SLOT18.D38(GND#D38) SLOT18.D40(GND#D40) SLOT18.E2(GND#E2) SLOT18.E4(GND#E4) SLOT18.E6(GND#E6) SLOT18.E8(GND#E8) SLOT18.E10(GND#E10) SLOT18.E12(GND#E12) SLOT18.E14(GND#E14) SLOT18.E16(GND#E16) SLOT18.E18(GND#E18) SLOT18.E20(GND#E20) SLOT18.E22(GND#E22) SLOT18.E24(GND#E24) SLOT18.E26(GND#E26) SLOT18.E28(GND#E28) SLOT18.E30(GND#E30) SLOT18.E32(GND#E32) SLOT18.E34(GND#E34) SLOT18.E36(GND#E36) SLOT18.E38(GND#E38) SLOT18.E40(GND#E40) SLOT18.F2(GND#F2) SLOT18.F4(GND#F4) SLOT18.F6(GND#F6) SLOT18.F8(GND#F8) SLOT18.F10(GND#F10) SLOT18.F12(GND#F12) SLOT18.F14(GND#F14) SLOT18.F16(GND#F16) SLOT18.F18(GND#F18) SLOT18.F20(GND#F20) SLOT18.F22(GND#F22) SLOT18.F24(GND#F24) SLOT18.F26(GND#F26) SLOT18.F28(GND#F28) SLOT18.F30(GND#F30) SLOT18.F32(GND#F32) SLOT18.F34(GND#F34) SLOT18.F36(GND#F36) SLOT18.F38(GND#F38) SLOT18.F40(GND#F40) SLOT18.G2(GND#G2) SLOT18.G4(GND#G4) SLOT18.G6(GND#G6) SLOT18.G8(GND#G8) SLOT18.G10(GND#G10) SLOT18.G12(GND#G12) SLOT18.G14(GND#G14) SLOT18.G16(GND#G16) SLOT18.G18(GND#G18) SLOT18.G20(GND#G20) SLOT18.G22(GND#G22) SLOT18.G24(GND#G24) SLOT18.G26(GND#G26) SLOT18.G28(GND#G28) SLOT18.G30(GND#G30) SLOT18.G32(GND#G32) SLOT18.G34(GND#G34) SLOT18.G36(GND#G36) SLOT18.G38(GND#G38) SLOT18.G40(GND#G40) ST1.1 ST2.1 UNK0BS1.2 UNK0BS2.2 UNK2R43.2 UNK2R44.2 UNK3R41.2 UNK3R42.2 UNK4R41.2 UNK4R42.2 UNK5R41.2 UNK5R42.2 UNK6R41.2 UNK6R42.2 UNK7R41.2 UNK7R42.2 UNK8R41.2 UNK8R42.2
AB1: SLOT0.F41
AB2: SLOT0.E41
AB3: SLOT0.F39
AB4: SLOT0.E39
CAL_HF: SLOT0.A41
CAL_HG: SLOT0.A40 SLOT0.B40 SLOT0.C41
CAL_HS: SLOT0.B41
CAL_LF: SLOT0.A39
CAL_LS: SLOT0.B39
CBIT_1: K1.8(V-) SLOT0.D39 UNK3K1.8
CBIT_2: K2.2 SLOT0.C39 UNK3K2.2 UNK5K2.2 UNK7K2.2
CBIT_3: K3.2 SLOT0.F37 UNK3K3.2 UNK5K3.2 UNK7K3.2
CBIT_4: K4.2 SLOT0.E37 UNK3K4.2 UNK5K4.2 UNK7K4.2
CBIT_5: K5.2 SLOT0.D37 UNK3K5.2 UNK5K5.2 UNK7K5.2
CBIT_6: K6.2 SLOT0.C37 UNK3K6.2 UNK5K6.2 UNK7K6.2
CBIT_7: K7.2 SLOT0.F35 UNK3K7.2 UNK5K7.2 UNK7K7.2
CBIT_8: K8.2 SLOT0.E35 UNK3K8.2 UNK5K8.2 UNK7K8.2
CBIT_9: K9.2 SLOT0.D35 UNK3K9.2 UNK5K9.2 UNK7K9.2
CBIT_10: K10.2 SLOT0.C35 UNK3K10.2 UNK5K10.2 UNK7K10.2
CBIT_11: K11.2 SLOT0.B35 UNK3K11.2 UNK5K11.2 UNK7K11.2
CBIT_12: K12.2 SLOT0.A35 UNK3K12.2 UNK5K12.2 UNK7K12.2
CBIT_13: K13.2 SLOT0.F33 UNK3K13.2 UNK5K13.2 UNK7K13.2
CBIT_14: K14.2 SLOT0.E33 UNK3K14.2 UNK5K14.2 UNK7K14.2
CBIT_15: K15.8(V-) SLOT0.D33 UNK3K15.8
CBIT_16: K16.2 SLOT0.C33 UNK3K16.2 UNK5K16.2 UNK7K16.2
CBIT_17: K17.2 SLOT0.B33 UNK3K17.2 UNK5K17.2 UNK7K17.2
CBIT_18: K18.2 SLOT0.A33 UNK3K18.2 UNK5K18.2 UNK7K18.2
CBIT_19: K19.2 SLOT0.F31 UNK3K19.2 UNK5K19.2 UNK7K19.2
CBIT_20: K20.2 SLOT0.E31 UNK3K20.2 UNK5K20.2 UNK7K20.2
CBIT_21: K21.2 SLOT0.D31 UNK3K21.2 UNK5K21.2 UNK7K21.2
CBIT_22: K22.2 SLOT0.C31 UNK3K22.2 UNK5K22.2 UNK7K22.2
CBIT_23: K23.8(V-) SLOT0.B31 UNK3K23.8
CBIT_24: K24.8(V-) SLOT0.A31 UNK3K24.8
CBIT_25: K25.2 SLOT0.F29 UNK3K25.2 UNK5K25.2 UNK7K25.2
CBIT_26: K26.2 SLOT0.E29 UNK3K26.2 UNK5K26.2 UNK7K26.2
CBIT_27: K27.2 SLOT0.D29 UNK3K27.2 UNK5K27.2 UNK7K27.2
CBIT_28: K28.2 SLOT0.C29 UNK3K28.2 UNK5K28.2 UNK7K28.2
CBIT_29: K29.2 SLOT0.B29 UNK3K29.2 UNK5K29.2 UNK7K29.2
CBIT_30: K30.2 SLOT0.A29 UNK3K30.2 UNK5K30.2 UNK7K30.2
CBIT_31: K31.2 SLOT0.F27 UNK3K31.2 UNK5K31.2 UNK7K31.2
CBIT_32: K32.2 SLOT0.E27 UNK3K32.2 UNK5K32.2 UNK7K32.2
CBIT_33: K33.2 SLOT0.D27 UNK3K33.2 UNK5K33.2 UNK7K33.2
CBIT_34: K34.2 SLOT0.C27 UNK3K34.2 UNK5K34.2 UNK7K34.2
CBIT_35: K35.2 SLOT0.B27 UNK3K35.2 UNK5K35.2 UNK7K35.2
CBIT_36: K36.2 SLOT0.A27 UNK3K36.2 UNK5K36.2 UNK7K36.2
CBIT_37: K37.2 SLOT0.F25 UNK3K37.2 UNK5K37.2 UNK7K37.2
CBIT_38: K38.2 SLOT0.E25 UNK3K38.2 UNK5K38.2 UNK7K38.2
CBIT_39: K39.2 SLOT0.D25 UNK3K39.2 UNK5K39.2 UNK7K39.2
CBIT_40: K40.2 SLOT0.C25 UNK3K40.2 UNK5K40.2 UNK7K40.2
CBIT_41: K41.2 SLOT0.B25 UNK3K41.2 UNK5K41.2 UNK7K41.2
CBIT_42: K42.2 SLOT0.A25 UNK3K42.2 UNK5K42.2 UNK7K42.2
CBIT_43: K43.2 SLOT0.F23 UNK3K43.2 UNK5K43.2 UNK7K43.2
CBIT_44: K44.2 SLOT0.E23 UNK3K44.2 UNK5K44.2 UNK7K44.2
CBIT_45: K45.2 SLOT0.D23 UNK3K45.2 UNK5K45.2 UNK7K45.2
CBIT_46: K46.2 SLOT0.C23 UNK3K46.2 UNK5K46.2 UNK7K46.2
CBIT_47: K47.2 SLOT0.B23 UNK3K47.2 UNK5K47.2 UNK7K47.2
CBIT_48: K48.2 SLOT0.A23 UNK3K48.2 UNK5K48.2 UNK7K48.2
CBIT_49: K49.2 SLOT0.F21 UNK3K49.2 UNK5K49.2 UNK7K49.2
CBIT_50: K50.2 SLOT0.E21 UNK3K50.2 UNK5K50.2 UNK7K50.2
CBIT_51: K51.2 SLOT0.D21 UNK3K51.2 UNK5K51.2 UNK7K51.2
CBIT_52: K52.2 SLOT0.C21 UNK3K52.2 UNK5K52.2 UNK7K52.2
CBIT_53: K53.2 SLOT0.B21 UNK3K53.2 UNK5K53.2 UNK7K53.2
CBIT_54: K54.2 SLOT0.A21 UNK3K54.2 UNK5K54.2 UNK7K54.2
CBIT_55: K55.2 SLOT0.F19 UNK3K55.2 UNK5K55.2 UNK7K55.2
CBIT_56: K56.2 SLOT0.E19 UNK3K56.2 UNK5K56.2 UNK7K56.2
CBIT_57: K57.2 SLOT0.D19 UNK3K57.2 UNK5K57.2 UNK7K57.2
CBIT_58: K58.2 SLOT0.C19 UNK3K58.2 UNK5K58.2 UNK7K58.2
CBIT_59: K59.2 SLOT0.B19 UNK3K59.2 UNK5K59.2 UNK7K59.2
CBIT_60: K60.2 SLOT0.A19 UNK3K60.2 UNK5K60.2 UNK7K60.2
CBIT_61: SLOT0.F17 UNK2K1.8 UNK4K1.8
CBIT_62: SLOT0.E17 UNK2K2.2 UNK4K2.2 UNK6K2.2 UNK8K2.2
CBIT_63: SLOT0.D17 UNK2K3.2 UNK4K3.2 UNK6K3.2 UNK8K3.2
CBIT_64: SLOT0.F7 UNK2K4.2 UNK4K4.2 UNK6K4.2 UNK8K4.2
CBIT_65: SLOT0.E7 UNK2K5.2 UNK4K5.2 UNK6K5.2 UNK8K5.2
CBIT_66: SLOT0.D7 UNK2K6.2 UNK4K6.2 UNK6K6.2 UNK8K6.2
CBIT_67: SLOT0.C7 UNK2K7.2 UNK4K7.2 UNK6K7.2 UNK8K7.2
CBIT_68: SLOT0.B7 UNK2K8.2 UNK4K8.2 UNK6K8.2 UNK8K8.2
CBIT_69: SLOT0.A7 UNK2K9.2 UNK4K9.2 UNK6K9.2 UNK8K9.2
CBIT_70: SLOT0.F5 UNK2K10.2 UNK4K10.2 UNK6K10.2 UNK8K10.2
CBIT_71: SLOT0.E5 UNK2K11.2 UNK4K11.2 UNK6K11.2 UNK8K11.2
CBIT_72: SLOT0.D5 UNK2K12.2 UNK4K12.2 UNK6K12.2 UNK8K12.2
CBIT_73: SLOT0.C5 UNK2K13.2 UNK4K13.2 UNK6K13.2 UNK8K13.2
CBIT_74: SLOT0.B5 UNK2K14.2 UNK4K14.2 UNK6K14.2 UNK8K14.2
CBIT_75: SLOT0.A5 UNK2K15.8 UNK4K15.8
CBIT_76: SLOT0.F3 UNK2K16.2 UNK4K16.2 UNK6K16.2 UNK8K16.2
CBIT_77: SLOT0.E3 UNK2K17.2 UNK4K17.2 UNK6K17.2 UNK8K17.2
CBIT_78: SLOT0.D3 UNK2K18.2 UNK4K18.2 UNK6K18.2 UNK8K18.2
CBIT_79: SLOT0.C3 UNK2K19.2 UNK4K19.2 UNK6K19.2 UNK8K19.2
CBIT_80: SLOT0.B3 UNK2K20.2 UNK4K20.2 UNK6K20.2 UNK8K20.2
CBIT_81: SLOT0.A3 UNK2K21.2 UNK4K21.2 UNK6K21.2 UNK8K21.2
CBIT_82: SLOT0.G24 UNK2K22.2 UNK4K22.2 UNK6K22.2 UNK8K22.2
CBIT_83: SLOT0.F24 UNK2K23.8 UNK4K23.8
CBIT_84: SLOT0.E24 UNK2K24.8 UNK4K24.8
CBIT_85: SLOT0.D24 UNK2K25.2 UNK4K25.2 UNK6K25.2 UNK8K25.2
CBIT_86: SLOT0.C24 UNK2K26.2 UNK4K26.2 UNK6K26.2 UNK8K26.2
CBIT_87: SLOT0.B24 UNK2K27.2 UNK4K27.2 UNK6K27.2 UNK8K27.2
CBIT_88: SLOT0.F26 UNK2K28.2 UNK4K28.2 UNK6K28.2 UNK8K28.2
CBIT_89: SLOT0.E26 UNK2K29.2 UNK4K29.2 UNK6K29.2 UNK8K29.2
CBIT_90: SLOT0.D26 UNK2K30.2 UNK4K30.2 UNK6K30.2 UNK8K30.2
CBIT_91: SLOT0.C26 UNK2K31.2 UNK4K31.2 UNK6K31.2 UNK8K31.2
CBIT_92: SLOT0.B26 UNK2K32.2 UNK4K32.2 UNK6K32.2 UNK8K32.2
CBIT_93: SLOT0.A26 UNK2K33.2 UNK4K33.2 UNK6K33.2 UNK8K33.2
CBIT_94: SLOT0.G28 UNK2K34.2 UNK4K34.2 UNK6K34.2 UNK8K34.2
CBIT_95: SLOT0.F28 UNK2K35.2 UNK4K35.2 UNK6K35.2 UNK8K35.2
CBIT_96: SLOT0.E28 UNK2K36.2 UNK4K36.2 UNK6K36.2 UNK8K36.2
CBIT_97: SLOT0.D28 UNK2K37.2 UNK4K37.2 UNK6K37.2 UNK8K37.2
CBIT_98: SLOT0.C28 UNK2K38.2 UNK4K38.2 UNK6K38.2 UNK8K38.2
CBIT_99: SLOT0.B28 UNK2K39.2 UNK4K39.2 UNK6K39.2 UNK8K39.2
CBIT_100: SLOT0.F30 UNK2K40.2 UNK4K40.2 UNK6K40.2 UNK8K40.2
CBIT_101: SLOT0.E30 UNK2K41.2 UNK4K41.2 UNK6K41.2 UNK8K41.2
CBIT_102: SLOT0.D30 UNK2K42.2 UNK4K42.2 UNK6K42.2 UNK8K42.2
CBIT_103: SLOT0.C30 UNK2K43.2 UNK4K43.2 UNK6K43.2 UNK8K43.2
CBIT_104: SLOT0.B30 UNK2K44.2 UNK4K44.2 UNK6K44.2 UNK8K44.2
CBIT_105: SLOT0.A30 UNK2K45.2 UNK4K45.2 UNK6K45.2 UNK8K45.2
CBIT_106: SLOT0.G32 UNK2K46.2 UNK4K46.2 UNK6K46.2 UNK8K46.2
CBIT_107: SLOT0.F32 UNK2K47.2 UNK4K47.2 UNK6K47.2 UNK8K47.2
CBIT_108: SLOT0.E32 UNK2K48.2 UNK4K48.2 UNK6K48.2 UNK8K48.2
CBIT_109: SLOT0.D32 UNK2K49.2 UNK4K49.2 UNK6K49.2 UNK8K49.2
CBIT_110: SLOT0.C32 UNK2K50.2 UNK4K50.2 UNK6K50.2 UNK8K50.2
CBIT_111: SLOT0.B32 UNK2K51.2 UNK4K51.2 UNK6K51.2 UNK8K51.2
CBIT_112: SLOT0.F34 UNK2K52.2 UNK4K52.2 UNK6K52.2 UNK8K52.2
CBIT_113: SLOT0.E34 UNK2K53.2 UNK4K53.2 UNK6K53.2 UNK8K53.2
CBIT_114: SLOT0.D34 UNK2K54.2 UNK4K54.2 UNK6K54.2 UNK8K54.2
CBIT_115: SLOT0.C34 UNK2K55.2 UNK4K55.2 UNK6K55.2 UNK8K55.2
CBIT_116: SLOT0.B34 UNK2K56.2 UNK4K56.2 UNK6K56.2 UNK8K56.2
CBIT_117: SLOT0.A34 UNK2K57.2 UNK4K57.2 UNK6K57.2 UNK8K57.2
CBIT_118: SLOT0.G36 UNK2K58.2 UNK4K58.2 UNK6K58.2 UNK8K58.2
CBIT_119: SLOT0.F36 UNK2K59.2 UNK4K59.2 UNK6K59.2 UNK8K59.2
CBIT_120: SLOT0.E36 UNK2K60.2 UNK4K60.2 UNK6K60.2 UNK8K60.2
CBIT_121: SLOT0.D36 UNK5K1.8 UNK7K1.8
CBIT_122: SLOT0.C36 UNK6K1.8 UNK8K1.8
CBIT_123: SLOT0.B36 UNK5K23.8 UNK7K23.8
CBIT_124: SLOT0.G38 UNK6K23.8 UNK8K23.8
CBIT_125: SLOT0.F38 UNK5K24.8 UNK6K24.8 UNK7K24.8 UNK8K24.8
CBIT_126: SLOT0.E38 UNK5K15.8 UNK6K15.8 UNK7K15.8 UNK8K15.8
CBIT_127: K61.2 SLOT0.D38 UNK3K61.2 UNK5K61.2 UNK7K61.2
CBIT_128: SLOT0.C38 UNK2K61.2 UNK4K61.2 UNK6K61.2 UNK8K61.2
CLK100_N: SLOT0.E10
CLK100_P: SLOT0.F10
CLKREF50_N: SLOT0.B10
CLKREF50_P: SLOT0.C10
DUT1_GND: C48.2 C50.2 C53.2 C54.2 C58.2 C59.2 C62.2 C65.2 C66.2 C67.2 C68.2 C70.2 C71.2 C72.2 C73.2 C74.2 K52.3 K54.3 R1.2 R11.1 R14.1 R41.1 R42.1 SITE1.3_F(GND_F) SITE1.3_S(GND_S) SITE1.EPAD SITE1.G1 SITE1.G2 SITE1.G3 SITE1.G4 SITE1.G5 SITE1.G6 SITE1.G7 SITE1.G8 SITE1.G9 U1.2(VEE) U2.2(VEE) U3.4(GND) U4.4(GND) UNK1SH1.2 UNK1SH2.2 UNK1SH3.2 UNK1SH4.2 UNK1SH5.2 UNK1SH6.2 UNK1SH7.2 UNK1SH8.2 UNK1SH9.2 UNK1SH10.2 UNK1SH11.2 UNK1SH12.2 UNK1SH13.2 UNK1SH14.2 UNK1SH15.2 UNK1SH16.2 UNK1SH17.2 UNK1SH18.2 UNK1SH19.2 UNK1SH20.2 UNK1SH21.2 UNK1SH22.2 UNK1SH23.2 UNK1SH24.2 UNK1SH25.2 UNK1SH26.2 UNK1SH27.2
DUT2_GND: SITE2.3_F(GND_F) SITE2.3_S(GND_S) SITE2.EPAD SITE2.G1 SITE2.G2 SITE2.G3 SITE2.G4 SITE2.G5 SITE2.G6 SITE2.G7 SITE2.G8 SITE2.G9 UNK2C48.2 UNK2C50.2 UNK2C53.2 UNK2C54.2 UNK2C58.2 UNK2C59.2 UNK2C62.2 UNK2C65.2 UNK2C66.2 UNK2C67.2 UNK2C68.2 UNK2C70.2 UNK2C71.2 UNK2C72.2 UNK2C73.2 UNK2C74.2 UNK2K52.3 UNK2K54.3 UNK2R1.2 UNK2R11.1 UNK2R14.1 UNK2R43.1 UNK2R44.1 UNK2SH1.2 UNK2SH2.2 UNK2SH3.2 UNK2SH4.2 UNK2SH5.2 UNK2SH6.2 UNK2SH7.2 UNK2SH8.2 UNK2SH9.2 UNK2SH10.2 UNK2SH11.2 UNK2SH12.2 UNK2SH13.2 UNK2SH14.2 UNK2SH15.2 UNK2SH16.2 UNK2SH17.2 UNK2SH18.2 UNK2SH19.2 UNK2SH20.2 UNK2SH21.2 UNK2SH22.2 UNK2SH23.2 UNK2SH24.2 UNK2SH25.2 UNK2SH26.2 UNK2SH27.2 UNK2U1.2 UNK2U2.2 UNK2U3.4 UNK2U4.4
DUT3_GND: SITE3.3_F(GND_F) SITE3.3_S(GND_S) SITE3.EPAD SITE3.G1 SITE3.G2 SITE3.G3 SITE3.G4 SITE3.G5 SITE3.G6 SITE3.G7 SITE3.G8 SITE3.G9 UNK3C48.2 UNK3C50.2 UNK3C53.2 UNK3C54.2 UNK3C58.2 UNK3C59.2 UNK3C62.2 UNK3C65.2 UNK3C66.2 UNK3C67.2 UNK3C68.2 UNK3C70.2 UNK3C71.2 UNK3C72.2 UNK3C73.2 UNK3C74.2 UNK3K52.3 UNK3K54.3 UNK3R1.2 UNK3R11.1 UNK3R14.1 UNK3R41.1 UNK3R42.1 UNK3SH1.2 UNK3SH2.2 UNK3SH3.2 UNK3SH4.2 UNK3SH5.2 UNK3SH6.2 UNK3SH7.2 UNK3SH8.2 UNK3SH9.2 UNK3SH10.2 UNK3SH11.2 UNK3SH12.2 UNK3SH13.2 UNK3SH14.2 UNK3SH15.2 UNK3SH16.2 UNK3SH17.2 UNK3SH18.2 UNK3SH19.2 UNK3SH20.2 UNK3SH21.2 UNK3SH22.2 UNK3SH23.2 UNK3SH24.2 UNK3SH25.2 UNK3SH26.2 UNK3SH27.2 UNK3U1.2 UNK3U2.2 UNK3U3.4 UNK3U4.4
DUT4_GND: SITE4.3_F(GND_F) SITE4.3_S(GND_S) SITE4.EPAD SITE4.G1 SITE4.G2 SITE4.G3 SITE4.G4 SITE4.G5 SITE4.G6 SITE4.G7 SITE4.G8 SITE4.G9 UNK4C48.2 UNK4C50.2 UNK4C53.2 UNK4C54.2 UNK4C58.2 UNK4C59.2 UNK4C62.2 UNK4C65.2 UNK4C66.2 UNK4C67.2 UNK4C68.2 UNK4C70.2 UNK4C71.2 UNK4C72.2 UNK4C73.2 UNK4C74.2 UNK4K52.3 UNK4K54.3 UNK4R1.2 UNK4R11.1 UNK4R14.1 UNK4R41.1 UNK4R42.1 UNK4SH1.2 UNK4SH2.2 UNK4SH3.2 UNK4SH4.2 UNK4SH5.2 UNK4SH6.2 UNK4SH7.2 UNK4SH8.2 UNK4SH9.2 UNK4SH10.2 UNK4SH11.2 UNK4SH12.2 UNK4SH13.2 UNK4SH14.2 UNK4SH15.2 UNK4SH16.2 UNK4SH17.2 UNK4SH18.2 UNK4SH19.2 UNK4SH20.2 UNK4SH21.2 UNK4SH22.2 UNK4SH23.2 UNK4SH24.2 UNK4SH25.2 UNK4SH26.2 UNK4SH27.2 UNK4U1.2 UNK4U2.2 UNK4U3.4 UNK4U4.4
DUT5_GND: SITE5.3_F(GND_F) SITE5.3_S(GND_S) SITE5.EPAD SITE5.G1 SITE5.G2 SITE5.G3 SITE5.G4 SITE5.G5 SITE5.G6 SITE5.G7 SITE5.G8 SITE5.G9 UNK5C48.2 UNK5C50.2 UNK5C53.2 UNK5C54.2 UNK5C58.2 UNK5C59.2 UNK5C62.2 UNK5C65.2 UNK5C66.2 UNK5C67.2 UNK5C68.2 UNK5C70.2 UNK5C71.2 UNK5C72.2 UNK5C73.2 UNK5C74.2 UNK5K52.3 UNK5K54.3 UNK5R1.2 UNK5R11.1 UNK5R14.1 UNK5R41.1 UNK5R42.1 UNK5SH1.2 UNK5SH2.2 UNK5SH3.2 UNK5SH4.2 UNK5SH5.2 UNK5SH6.2 UNK5SH7.2 UNK5SH8.2 UNK5SH9.2 UNK5SH10.2 UNK5SH11.2 UNK5SH12.2 UNK5SH13.2 UNK5SH14.2 UNK5SH15.2 UNK5SH16.2 UNK5SH17.2 UNK5SH18.2 UNK5SH19.2 UNK5SH20.2 UNK5SH21.2 UNK5SH22.2 UNK5SH23.2 UNK5SH24.2 UNK5SH25.2 UNK5SH26.2 UNK5SH27.2 UNK5U1.2 UNK5U2.2 UNK5U3.4 UNK5U4.4
DUT6_GND: SITE6.3_F(GND_F) SITE6.3_S(GND_S) SITE6.EPAD SITE6.G1 SITE6.G2 SITE6.G3 SITE6.G4 SITE6.G5 SITE6.G6 SITE6.G7 SITE6.G8 SITE6.G9 UNK6C48.2 UNK6C50.2 UNK6C53.2 UNK6C54.2 UNK6C58.2 UNK6C59.2 UNK6C62.2 UNK6C65.2 UNK6C66.2 UNK6C67.2 UNK6C68.2 UNK6C70.2 UNK6C71.2 UNK6C72.2 UNK6C73.2 UNK6C74.2 UNK6K52.3 UNK6K54.3 UNK6R1.2 UNK6R11.1 UNK6R14.1 UNK6R41.1 UNK6R42.1 UNK6SH1.2 UNK6SH2.2 UNK6SH3.2 UNK6SH4.2 UNK6SH5.2 UNK6SH6.2 UNK6SH7.2 UNK6SH8.2 UNK6SH9.2 UNK6SH10.2 UNK6SH11.2 UNK6SH12.2 UNK6SH13.2 UNK6SH14.2 UNK6SH15.2 UNK6SH16.2 UNK6SH17.2 UNK6SH18.2 UNK6SH19.2 UNK6SH20.2 UNK6SH21.2 UNK6SH22.2 UNK6SH23.2 UNK6SH24.2 UNK6SH25.2 UNK6SH26.2 UNK6SH27.2 UNK6U1.2 UNK6U2.2 UNK6U3.4 UNK6U4.4
DUT7_GND: SITE7.3_F(GND_F) SITE7.3_S(GND_S) SITE7.EPAD SITE7.G1 SITE7.G2 SITE7.G3 SITE7.G4 SITE7.G5 SITE7.G6 SITE7.G7 SITE7.G8 SITE7.G9 UNK7C48.2 UNK7C50.2 UNK7C53.2 UNK7C54.2 UNK7C58.2 UNK7C59.2 UNK7C62.2 UNK7C65.2 UNK7C66.2 UNK7C67.2 UNK7C68.2 UNK7C70.2 UNK7C71.2 UNK7C72.2 UNK7C73.2 UNK7C74.2 UNK7K52.3 UNK7K54.3 UNK7R1.2 UNK7R11.1 UNK7R14.1 UNK7R41.1 UNK7R42.1 UNK7SH1.2 UNK7SH2.2 UNK7SH3.2 UNK7SH4.2 UNK7SH5.2 UNK7SH6.2 UNK7SH7.2 UNK7SH8.2 UNK7SH9.2 UNK7SH10.2 UNK7SH11.2 UNK7SH12.2 UNK7SH13.2 UNK7SH14.2 UNK7SH15.2 UNK7SH16.2 UNK7SH17.2 UNK7SH18.2 UNK7SH19.2 UNK7SH20.2 UNK7SH21.2 UNK7SH22.2 UNK7SH23.2 UNK7SH24.2 UNK7SH25.2 UNK7SH26.2 UNK7SH27.2 UNK7U1.2 UNK7U2.2 UNK7U3.4 UNK7U4.4
DUT8_GND: SITE8.3_F(GND_F) SITE8.3_S(GND_S) SITE8.EPAD SITE8.G1 SITE8.G2 SITE8.G3 SITE8.G4 SITE8.G5 SITE8.G6 SITE8.G7 SITE8.G8 SITE8.G9 UNK8C48.2 UNK8C50.2 UNK8C53.2 UNK8C54.2 UNK8C58.2 UNK8C59.2 UNK8C62.2 UNK8C65.2 UNK8C66.2 UNK8C67.2 UNK8C68.2 UNK8C70.2 UNK8C71.2 UNK8C72.2 UNK8C73.2 UNK8C74.2 UNK8K52.3 UNK8K54.3 UNK8R1.2 UNK8R11.1 UNK8R14.1 UNK8R41.1 UNK8R42.1 UNK8SH1.2 UNK8SH2.2 UNK8SH3.2 UNK8SH4.2 UNK8SH5.2 UNK8SH6.2 UNK8SH7.2 UNK8SH8.2 UNK8SH9.2 UNK8SH10.2 UNK8SH11.2 UNK8SH12.2 UNK8SH13.2 UNK8SH14.2 UNK8SH15.2 UNK8SH16.2 UNK8SH17.2 UNK8SH18.2 UNK8SH19.2 UNK8SH20.2 UNK8SH21.2 UNK8SH22.2 UNK8SH23.2 UNK8SH24.2 UNK8SH25.2 UNK8SH26.2 UNK8SH27.2 UNK8U1.2 UNK8U2.2 UNK8U3.4 UNK8U4.4
EVENT_A: SLOT0.C14
EVENT_B: SLOT0.B14
I2C_IDPROM_P3V3: BR7.2 SLOT0.G16
LB_PRESENT_N: SLOT0.D41 UNK0BS2.1
LB_REG_ADDR0: SLOT0.A18
LB_REG_ADDR1: SLOT0.B18
LB_REG_ADDR2: SLOT0.C18
LB_REG_ADDR3: SLOT0.D18
LB_REG_ADDR4: SLOT0.D20
LB_REG_ADDR5: SLOT0.E20
LB_REG_ADDR6: SLOT0.F20
LB_REG_ADDR7: SLOT0.G20
LB_REG_DATA0: SLOT0.B20
LB_REG_DATA1: SLOT0.C20
LB_REG_DATA2: SLOT0.A22
LB_REG_DATA3: SLOT0.B22
LB_REG_DATA4: SLOT0.C22
LB_REG_DATA5: SLOT0.D22
LB_REG_DATA6: SLOT0.E22
LB_REG_DATA7: SLOT0.F22
LB_REG_RD_N: SLOT0.D16
LB_REG_WR_N: SLOT0.C16
S1_C1B_F: K27.4 K61.3 SITE1.17_F(C1B_F) SLOT01.E29(4_B_HF) TP_C1B_F.1(TP)
S1_IS1N_F: C69.2 K57.4 SITE1.12_F(IS1N_F) SLOT01.E9(14_B_HF) TP_IS1N_F.1(TP)
S1_IS1P_F: K19.4 K58.3 SITE1.11_F(IS1P_F) SLOT01.E7(15_B_HF) TP_IS1P_F.1(TP)
S1_IS2N_F: C60.2 K59.4 SITE1.10_F(IS2N_F) SLOT01.E31(3_B_HF) TP_IS2N_F.1(TP)
S1_IS2P_F: K16.4 K60.3 SITE1.9_F(IS2P_F) SLOT01.E5(16_B_HF)
S1_SCL_F: K24.3 K53.3 K54.4 SITE1.15_F(SCL_F) TP_SCL_F.1(TP)
S1_SDA_F: K23.3 K51.3 K52.4 SITE1.14_F(SDA_F) TP_SDA_F.1(TP)
S1_SRD_F: K1.3 K2.4 K3.4 K56.3 SITE1.1_F(SRD_F) TP_SRD_F.1(TP)
S1_SRD_S: K1.6 K4.4 SITE1.1_S(SRD_S) TP_SRD_S.1(TP)
S1_SRG_F: K55.3 SITE1.4_F(SRG_F) SLOT01.D29(4_A_HF) TP_SRG_F.1(TP)
S2_C1B_F: SITE2.17_F(C1B_F) SLOT02.E29(4_B_HF) UNK2K27.4 UNK2K61.3 UNK2TP_C1B_F.1
S2_IS1N_F: SITE2.12_F(IS1N_F) SLOT02.E9(14_B_HF) UNK2C69.2 UNK2K57.4 UNK2TP_IS1N_F.1
S2_IS1P_F: SITE2.11_F(IS1P_F) SLOT02.E7(15_B_HF) UNK2K19.4 UNK2K58.3 UNK2TP_IS1P_F.1
S2_IS2N_F: SITE2.10_F(IS2N_F) SLOT02.E31(3_B_HF) UNK2C60.2 UNK2K59.4 UNK2TP_IS2N_F.1
S2_IS2P_F: SITE2.9_F(IS2P_F) SLOT02.E5(16_B_HF) UNK2K16.4 UNK2K60.3
S2_SCL_F: SITE2.15_F(SCL_F) UNK2K24.3 UNK2K53.3 UNK2K54.4 UNK2TP_SCL_F.1
S2_SDA_F: SITE2.14_F(SDA_F) UNK2K23.3 UNK2K51.3 UNK2K52.4 UNK2TP_SDA_F.1
S2_SRD_F: SITE2.1_F(SRD_F) UNK2K1.3 UNK2K2.4 UNK2K3.4 UNK2K56.3 UNK2TP_SRD_F.1
S2_SRD_S: SITE2.1_S(SRD_S) UNK2K1.6 UNK2K4.4 UNK2TP_SRD_S.1
S2_SRG_F: SITE2.4_F(SRG_F) SLOT02.D29(4_A_HF) UNK2K55.3 UNK2TP_SRG_F.1
S3_C1B_F: SITE3.17_F(C1B_F) SLOT01.F53(20_B_HF) UNK3K27.4 UNK3K61.3 UNK3TP_C1B_F.1
S3_IS1N_F: SITE3.12_F(IS1N_F) SLOT01.A43(30_B_HF) UNK3C69.2 UNK3K57.4 UNK3TP_IS1N_F.1
S3_IS1P_F: SITE3.11_F(IS1P_F) SLOT01.F19(31_B_HF) UNK3K19.4 UNK3K58.3 UNK3TP_IS1P_F.1
S3_IS2N_F: SITE3.10_F(IS2N_F) SLOT01.F55(19_B_HF) UNK3C60.2 UNK3K59.4 UNK3TP_IS2N_F.1
S3_IS2P_F: SITE3.9_F(IS2P_F) SLOT01.F3(32_B_HF) UNK3K16.4 UNK3K60.3
S3_SCL_F: SITE3.15_F(SCL_F) UNK3K24.3 UNK3K53.3 UNK3K54.4 UNK3TP_SCL_F.1
S3_SDA_F: SITE3.14_F(SDA_F) UNK3K23.3 UNK3K51.3 UNK3K52.4 UNK3TP_SDA_F.1
S3_SRD_F: SITE3.1_F(SRD_F) UNK3K1.3 UNK3K2.4 UNK3K3.4 UNK3K56.3 UNK3TP_SRD_F.1
S3_SRD_S: SITE3.1_S(SRD_S) UNK3K1.6 UNK3K4.4 UNK3TP_SRD_S.1
S3_SRG_F: SITE3.4_F(SRG_F) SLOT01.F29(20_A_HF) UNK3K55.3 UNK3TP_SRG_F.1
S4_C1B_F: SITE4.17_F(C1B_F) SLOT02.F53(20_B_HF) UNK4K27.4 UNK4K61.3 UNK4TP_C1B_F.1
S4_IS1N_F: SITE4.12_F(IS1N_F) SLOT02.A43(30_B_HF) UNK4C69.2 UNK4K57.4 UNK4TP_IS1N_F.1
S4_IS1P_F: SITE4.11_F(IS1P_F) SLOT02.F19(31_B_HF) UNK4K19.4 UNK4K58.3 UNK4TP_IS1P_F.1
S4_IS2N_F: SITE4.10_F(IS2N_F) SLOT02.F55(19_B_HF) UNK4C60.2 UNK4K59.4 UNK4TP_IS2N_F.1
S4_IS2P_F: SITE4.9_F(IS2P_F) SLOT02.F3(32_B_HF) UNK4K16.4 UNK4K60.3
S4_SCL_F: SITE4.15_F(SCL_F) UNK4K24.3 UNK4K53.3 UNK4K54.4 UNK4TP_SCL_F.1
S4_SDA_F: SITE4.14_F(SDA_F) UNK4K23.3 UNK4K51.3 UNK4K52.4 UNK4TP_SDA_F.1
S4_SRD_F: SITE4.1_F(SRD_F) UNK4K1.3 UNK4K2.4 UNK4K3.4 UNK4K56.3 UNK4TP_SRD_F.1
S4_SRD_S: SITE4.1_S(SRD_S) UNK4K1.6 UNK4K4.4 UNK4TP_SRD_S.1
S4_SRG_F: SITE4.4_F(SRG_F) SLOT02.F29(20_A_HF) UNK4K55.3 UNK4TP_SRG_F.1
S5_C1B_F: SITE5.17_F(C1B_F) SLOT17.E29(4_B_HF) UNK5K27.4 UNK5K61.3 UNK5TP_C1B_F.1
S5_IS1N_F: SITE5.12_F(IS1N_F) SLOT17.E9(14_B_HF) UNK5C69.2 UNK5K57.4 UNK5TP_IS1N_F.1
S5_IS1P_F: SITE5.11_F(IS1P_F) SLOT17.E7(15_B_HF) UNK5K19.4 UNK5K58.3 UNK5TP_IS1P_F.1
S5_IS2N_F: SITE5.10_F(IS2N_F) SLOT17.E31(3_B_HF) UNK5C60.2 UNK5K59.4 UNK5TP_IS2N_F.1
S5_IS2P_F: SITE5.9_F(IS2P_F) SLOT17.E5(16_B_HF) UNK5K16.4 UNK5K60.3
S5_SCL_F: SITE5.15_F(SCL_F) UNK5K24.3 UNK5K53.3 UNK5K54.4 UNK5TP_SCL_F.1
S5_SDA_F: SITE5.14_F(SDA_F) UNK5K23.3 UNK5K51.3 UNK5K52.4 UNK5TP_SDA_F.1
S5_SRD_F: SITE5.1_F(SRD_F) UNK5K1.3 UNK5K2.4 UNK5K3.4 UNK5K56.3 UNK5TP_SRD_F.1
S5_SRD_S: SITE5.1_S(SRD_S) UNK5K1.6 UNK5K4.4 UNK5TP_SRD_S.1
S5_SRG_F: SITE5.4_F(SRG_F) SLOT17.D29(4_A_HF) UNK5K55.3 UNK5TP_SRG_F.1
S6_C1B_F: SITE6.17_F(C1B_F) SLOT18.E29(4_B_HF) UNK6K27.4 UNK6K61.3 UNK6TP_C1B_F.1
S6_IS1N_F: SITE6.12_F(IS1N_F) SLOT18.E9(14_B_HF) UNK6C69.2 UNK6K57.4 UNK6TP_IS1N_F.1
S6_IS1P_F: SITE6.11_F(IS1P_F) SLOT18.E7(15_B_HF) UNK6K19.4 UNK6K58.3 UNK6TP_IS1P_F.1
S6_IS2N_F: SITE6.10_F(IS2N_F) SLOT18.E31(3_B_HF) UNK6C60.2 UNK6K59.4 UNK6TP_IS2N_F.1
S6_IS2P_F: SITE6.9_F(IS2P_F) SLOT18.E5(16_B_HF) UNK6K16.4 UNK6K60.3
S6_SCL_F: SITE6.15_F(SCL_F) UNK6K24.3 UNK6K53.3 UNK6K54.4 UNK6TP_SCL_F.1
S6_SDA_F: SITE6.14_F(SDA_F) UNK6K23.3 UNK6K51.3 UNK6K52.4 UNK6TP_SDA_F.1
S6_SRD_F: SITE6.1_F(SRD_F) UNK6K1.3 UNK6K2.4 UNK6K3.4 UNK6K56.3 UNK6TP_SRD_F.1
S6_SRD_S: SITE6.1_S(SRD_S) UNK6K1.6 UNK6K4.4 UNK6TP_SRD_S.1
S6_SRG_F: SITE6.4_F(SRG_F) SLOT18.D29(4_A_HF) UNK6K55.3 UNK6TP_SRG_F.1
S7_C1B_F: SITE7.17_F(C1B_F) SLOT17.F53(20_B_HF) UNK7K27.4 UNK7K61.3 UNK7TP_C1B_F.1
S7_IS1N_F: SITE7.12_F(IS1N_F) SLOT17.A43(30_B_HF) UNK7C69.2 UNK7K57.4 UNK7TP_IS1N_F.1
S7_IS1P_F: SITE7.11_F(IS1P_F) SLOT17.F19(31_B_HF) UNK7K19.4 UNK7K58.3 UNK7TP_IS1P_F.1
S7_IS2N_F: SITE7.10_F(IS2N_F) SLOT17.F55(19_B_HF) UNK7C60.2 UNK7K59.4 UNK7TP_IS2N_F.1
S7_IS2P_F: SITE7.9_F(IS2P_F) SLOT17.F3(32_B_HF) UNK7K16.4 UNK7K60.3
S7_SCL_F: SITE7.15_F(SCL_F) UNK7K24.3 UNK7K53.3 UNK7K54.4 UNK7TP_SCL_F.1
S7_SDA_F: SITE7.14_F(SDA_F) UNK7K23.3 UNK7K51.3 UNK7K52.4 UNK7TP_SDA_F.1
S7_SRD_F: SITE7.1_F(SRD_F) UNK7K1.3 UNK7K2.4 UNK7K3.4 UNK7K56.3 UNK7TP_SRD_F.1
S7_SRD_S: SITE7.1_S(SRD_S) UNK7K1.6 UNK7K4.4 UNK7TP_SRD_S.1
S7_SRG_F: SITE7.4_F(SRG_F) SLOT17.F29(20_A_HF) UNK7K55.3 UNK7TP_SRG_F.1
S8_C1B_F: SITE8.17_F(C1B_F) SLOT18.F53(20_B_HF) UNK8K27.4 UNK8K61.3 UNK8TP_C1B_F.1
S8_IS1N_F: SITE8.12_F(IS1N_F) SLOT18.A43(30_B_HF) UNK8C69.2 UNK8K57.4 UNK8TP_IS1N_F.1
S8_IS1P_F: SITE8.11_F(IS1P_F) SLOT18.F19(31_B_HF) UNK8K19.4 UNK8K58.3 UNK8TP_IS1P_F.1
S8_IS2N_F: SITE8.10_F(IS2N_F) SLOT18.F55(19_B_HF) UNK8C60.2 UNK8K59.4 UNK8TP_IS2N_F.1
S8_IS2P_F: SITE8.9_F(IS2P_F) SLOT18.F3(32_B_HF) UNK8K16.4 UNK8K60.3
S8_SCL_F: SITE8.15_F(SCL_F) UNK8K24.3 UNK8K53.3 UNK8K54.4 UNK8TP_SCL_F.1
S8_SDA_F: SITE8.14_F(SDA_F) UNK8K23.3 UNK8K51.3 UNK8K52.4 UNK8TP_SDA_F.1
S8_SRD_F: SITE8.1_F(SRD_F) UNK8K1.3 UNK8K2.4 UNK8K3.4 UNK8K56.3 UNK8TP_SRD_F.1
S8_SRD_S: SITE8.1_S(SRD_S) UNK8K1.6 UNK8K4.4 UNK8TP_SRD_S.1
S8_SRG_F: SITE8.4_F(SRG_F) SLOT18.F29(20_A_HF) UNK8K55.3 UNK8TP_SRG_F.1
SCOPE_TP0: SLOT0.B16
SCOPE_TP1: SLOT0.A16
SDUN5V: SLOT0.C4 SLOT0.D4 SLOT0.E4 SLOT0.F4 SLOT0.G4
SDUP5V: F1.1 SLOT0.A2 SLOT0.A4 SLOT0.B2 SLOT0.B4 SLOT0.C2
SDUP5V_FILTER: C70.1 C71.1 CT2.1 CT3.1 LT1.2 TP_SDUP5V_FILTER.1(TP) U1.5(VCCI/VCCO) U2.5(VCCI/VCCO) UNK2C70.1 UNK2C71.1 UNK2U1.5 UNK2U2.5 UNK3C70.1 UNK3C71.1 UNK3U1.5 UNK3U2.5 UNK4C70.1 UNK4C71.1 UNK4U1.5 UNK4U2.5 UNK5C70.1 UNK5C71.1 UNK5U1.5 UNK5U2.5 UNK6C70.1 UNK6C71.1 UNK6U1.5 UNK6U2.5 UNK7C70.1 UNK7C71.1 UNK7U1.5 UNK7U2.5 UNK8C70.1 UNK8C71.1 UNK8U1.5 UNK8U2.5
SDUR5V: F2.1 SLOT0.A6 SLOT0.B6 SLOT0.C6 SLOT0.D6 SLOT0.E6
SDUR5V_FILTER: CT8.1 CT9.1 K1.1(V+) K15.1(V+) K23.1(V+) K24.1(V+) LT3.2 RK2.2 RK3.2 RK4.2 RK5.2 RK6.2 RK7.2 RK8.2 RK9.2 RK10.2 RK11.2 RK12.2 RK13.2 RK14.2 RK16.2 RK17.2 RK18.2 RK19.2 RK20.2 RK21.2 RK22.2 RK25.2 RK26.2 RK27.2 RK28.2 RK29.2 RK30.2 RK31.2 RK32.2 RK33.2 RK34.2 RK35.2 RK36.2 RK37.2 RK38.2 RK39.2 RK40.2 RK41.2 RK42.2 RK43.2 RK44.2 RK45.2 RK46.2 RK47.2 RK48.2 RK49.2 RK50.2 RK51.2 RK52.2 RK53.2 RK54.2 RK55.1 RK56.1 RK57.1 RK58.1 RK59.2 RK60.2 RK61.2 TP_SDUR5V_FILTER.1(TP) UNK2K1.1 UNK2K15.1 UNK2K23.1 UNK2K24.1 UNK2RK2.2 UNK2RK3.2 UNK2RK4.2 UNK2RK5.2 UNK2RK6.2 UNK2RK7.2 UNK2RK8.2 UNK2RK9.2 UNK2RK10.2 UNK2RK11.2 UNK2RK12.2 UNK2RK13.2 UNK2RK14.2 UNK2RK16.2 UNK2RK17.2 UNK2RK18.2 UNK2RK19.2 UNK2RK20.2 UNK2RK21.2 UNK2RK22.2 UNK2RK25.2 UNK2RK26.2 UNK2RK27.2 UNK2RK28.2 UNK2RK29.2 UNK2RK30.2 UNK2RK31.2 UNK2RK32.2 UNK2RK33.2 UNK2RK34.2 UNK2RK35.2 UNK2RK36.2 UNK2RK37.2 UNK2RK38.2 UNK2RK39.2 UNK2RK40.2 UNK2RK41.2 UNK2RK42.2 UNK2RK43.2 UNK2RK44.2 UNK2RK45.2 UNK2RK46.2 UNK2RK47.2 UNK2RK48.2 UNK2RK49.2 UNK2RK50.2 UNK2RK51.2 UNK2RK52.2 UNK2RK53.2 UNK2RK54.2 UNK2RK55.1 UNK2RK56.1 UNK2RK57.1 UNK2RK58.1 UNK2RK59.2 UNK2RK60.2 UNK2RK61.2 UNK3K1.1 UNK3K15.1 UNK3K23.1 UNK3K24.1 UNK3RK2.2 UNK3RK3.2 UNK3RK4.2 UNK3RK5.2 UNK3RK6.2 UNK3RK7.2 UNK3RK8.2 UNK3RK9.2 UNK3RK10.2 UNK3RK11.2 UNK3RK12.2 UNK3RK13.2 UNK3RK14.2 UNK3RK16.2 UNK3RK17.2 UNK3RK18.2 UNK3RK19.2 UNK3RK20.2 UNK3RK21.2 UNK3RK22.2 UNK3RK25.2 UNK3RK26.2 UNK3RK27.2 UNK3RK28.2 UNK3RK29.2 UNK3RK30.2 UNK3RK31.2 UNK3RK32.2 UNK3RK33.2 UNK3RK34.2 UNK3RK35.2 UNK3RK36.2 UNK3RK37.2 UNK3RK38.2 UNK3RK39.2 UNK3RK40.2 UNK3RK41.2 UNK3RK42.2 UNK3RK43.2 UNK3RK44.2 UNK3RK45.2 UNK3RK46.2 UNK3RK47.2 UNK3RK48.2 UNK3RK49.2 UNK3RK50.2 UNK3RK51.2 UNK3RK52.2 UNK3RK53.2 UNK3RK54.2 UNK3RK55.1 UNK3RK56.1 UNK3RK57.1 UNK3RK58.1 UNK3RK59.2 UNK3RK60.2 UNK3RK61.2 UNK4K1.1 UNK4K15.1 UNK4K23.1 UNK4K24.1 UNK4RK2.2 UNK4RK3.2 UNK4RK4.2 UNK4RK5.2 UNK4RK6.2 UNK4RK7.2 UNK4RK8.2 UNK4RK9.2 UNK4RK10.2 UNK4RK11.2 UNK4RK12.2 UNK4RK13.2 UNK4RK14.2 UNK4RK16.2 UNK4RK17.2 UNK4RK18.2 UNK4RK19.2 UNK4RK20.2 UNK4RK21.2 UNK4RK22.2 UNK4RK25.2 UNK4RK26.2 UNK4RK27.2 UNK4RK28.2 UNK4RK29.2 UNK4RK30.2 UNK4RK31.2 UNK4RK32.2 UNK4RK33.2 UNK4RK34.2 UNK4RK35.2 UNK4RK36.2 UNK4RK37.2 UNK4RK38.2 UNK4RK39.2 UNK4RK40.2 UNK4RK41.2 UNK4RK42.2 UNK4RK43.2 UNK4RK44.2 UNK4RK45.2 UNK4RK46.2 UNK4RK47.2 UNK4RK48.2 UNK4RK49.2 UNK4RK50.2 UNK4RK51.2 UNK4RK52.2 UNK4RK53.2 UNK4RK54.2 UNK4RK55.1 UNK4RK56.1 UNK4RK57.1 UNK4RK58.1 UNK4RK59.2 UNK4RK60.2 UNK4RK61.2 UNK5K1.1 UNK5K15.1 UNK5K23.1 UNK5K24.1 UNK5RK2.2 UNK5RK3.2 UNK5RK4.2 UNK5RK5.2 UNK5RK6.2 UNK5RK7.2 UNK5RK8.2 UNK5RK9.2 UNK5RK10.2 UNK5RK11.2 UNK5RK12.2 UNK5RK13.2 UNK5RK14.2 UNK5RK16.2 UNK5RK17.2 UNK5RK18.2 UNK5RK19.2 UNK5RK20.2 UNK5RK21.2 UNK5RK22.2 UNK5RK25.2 UNK5RK26.2 UNK5RK27.2 UNK5RK28.2 UNK5RK29.2 UNK5RK30.2 UNK5RK31.2 UNK5RK32.2 UNK5RK33.2 UNK5RK34.2 UNK5RK35.2 UNK5RK36.2 UNK5RK37.2 UNK5RK38.2 UNK5RK39.2 UNK5RK40.2 UNK5RK41.2 UNK5RK42.2 UNK5RK43.2 UNK5RK44.2 UNK5RK45.2 UNK5RK46.2 UNK5RK47.2 UNK5RK48.2 UNK5RK49.2 UNK5RK50.2 UNK5RK51.2 UNK5RK52.2 UNK5RK53.2 UNK5RK54.2 UNK5RK55.1 UNK5RK56.1 UNK5RK57.1 UNK5RK58.1 UNK5RK59.2 UNK5RK60.2 UNK5RK61.2 UNK6K1.1 UNK6K15.1 UNK6K23.1 UNK6K24.1 UNK6RK2.2 UNK6RK3.2 UNK6RK4.2 UNK6RK5.2 UNK6RK6.2 UNK6RK7.2 UNK6RK8.2 UNK6RK9.2 UNK6RK10.2 UNK6RK11.2 UNK6RK12.2 UNK6RK13.2 UNK6RK14.2 UNK6RK16.2 UNK6RK17.2 UNK6RK18.2 UNK6RK19.2 UNK6RK20.2 UNK6RK21.2 UNK6RK22.2 UNK6RK25.2 UNK6RK26.2 UNK6RK27.2 UNK6RK28.2 UNK6RK29.2 UNK6RK30.2 UNK6RK31.2 UNK6RK32.2 UNK6RK33.2 UNK6RK34.2 UNK6RK35.2 UNK6RK36.2 UNK6RK37.2 UNK6RK38.2 UNK6RK39.2 UNK6RK40.2 UNK6RK41.2 UNK6RK42.2 UNK6RK43.2 UNK6RK44.2 UNK6RK45.2 UNK6RK46.2 UNK6RK47.2 UNK6RK48.2 UNK6RK49.2 UNK6RK50.2 UNK6RK51.2 UNK6RK52.2 UNK6RK53.2 UNK6RK54.2 UNK6RK55.1 UNK6RK56.1 UNK6RK57.1 UNK6RK58.1 UNK6RK59.2 UNK6RK60.2 UNK6RK61.2 UNK7K1.1 UNK7K15.1 UNK7K23.1 UNK7K24.1 UNK7RK2.2 UNK7RK3.2 UNK7RK4.2 UNK7RK5.2 UNK7RK6.2 UNK7RK7.2 UNK7RK8.2 UNK7RK9.2 UNK7RK10.2 UNK7RK11.2 UNK7RK12.2 UNK7RK13.2 UNK7RK14.2 UNK7RK16.2 UNK7RK17.2 UNK7RK18.2 UNK7RK19.2 UNK7RK20.2 UNK7RK21.2 UNK7RK22.2 UNK7RK25.2 UNK7RK26.2 UNK7RK27.2 UNK7RK28.2 UNK7RK29.2 UNK7RK30.2 UNK7RK31.2 UNK7RK32.2 UNK7RK33.2 UNK7RK34.2 UNK7RK35.2 UNK7RK36.2 UNK7RK37.2 UNK7RK38.2 UNK7RK39.2 UNK7RK40.2 UNK7RK41.2 UNK7RK42.2 UNK7RK43.2 UNK7RK44.2 UNK7RK45.2 UNK7RK46.2 UNK7RK47.2 UNK7RK48.2 UNK7RK49.2 UNK7RK50.2 UNK7RK51.2 UNK7RK52.2 UNK7RK53.2 UNK7RK54.2 UNK7RK55.1 UNK7RK56.1 UNK7RK57.1 UNK7RK58.1 UNK7RK59.2 UNK7RK60.2 UNK7RK61.2 UNK8K1.1 UNK8K15.1 UNK8K23.1 UNK8K24.1 UNK8RK2.2 UNK8RK3.2 UNK8RK4.2 UNK8RK5.2 UNK8RK6.2 UNK8RK7.2 UNK8RK8.2 UNK8RK9.2 UNK8RK10.2 UNK8RK11.2 UNK8RK12.2 UNK8RK13.2 UNK8RK14.2 UNK8RK16.2 UNK8RK17.2 UNK8RK18.2 UNK8RK19.2 UNK8RK20.2 UNK8RK21.2 UNK8RK22.2 UNK8RK25.2 UNK8RK26.2 UNK8RK27.2 UNK8RK28.2 UNK8RK29.2 UNK8RK30.2 UNK8RK31.2 UNK8RK32.2 UNK8RK33.2 UNK8RK34.2 UNK8RK35.2 UNK8RK36.2 UNK8RK37.2 UNK8RK38.2 UNK8RK39.2 UNK8RK40.2 UNK8RK41.2 UNK8RK42.2 UNK8RK43.2 UNK8RK44.2 UNK8RK45.2 UNK8RK46.2 UNK8RK47.2 UNK8RK48.2 UNK8RK49.2 UNK8RK50.2 UNK8RK51.2 UNK8RK52.2 UNK8RK53.2 UNK8RK54.2 UNK8RK55.1 UNK8RK56.1 UNK8RK57.1 UNK8RK58.1 UNK8RK59.2 UNK8RK60.2 UNK8RK61.2
SL01_VI100_1_A_HF: K1.2 SLOT01.D35(1_A_HF)
SL01_VI100_1_A_HG: SLOT01.B35(1_A_HG)
SL01_VI100_1_A_HS: K1.7 SLOT01.C35(1_A_HS)
SL01_VI100_1_B_HF: SH3.2 SLOT01.E35(1_B_HF) SLOT09.A59(VI_5_A_LF[1]) SLOT09.B59(VI_5_A_LF[2]) SLOT09.C59(VI_5_A_LF[3]) SLOT09.D59(VI_1_A_LF[1]) SLOT09.E59(VI_1_A_LF[2]) SLOT09.F59(VI_1_A_LF[3])
SL01_VI100_1_B_HG: SLOT01.C59(1_B_HG)
SL01_VI100_1_B_HS: SH3.1 SLOT01.C60(1_B_HS) SLOT09.B24(VI_5_A_LS) SLOT09.D24(VI_1_A_LS)
SL01_VI100_1_LS: SLOT01.A35(1_LS) UNK1SH1.1
SL01_VI100_2_A_HF: C49.2 K5.4 SITE1.2_F(SRS_F) SLOT01.D33(2_A_HF) TP_SRS_F.1(TP)
SL01_VI100_2_A_HG: SLOT01.B33(2_A_HG)
SL01_VI100_2_A_HS: K6.4 SITE1.2_S(SRS_S) SLOT01.C33(2_A_HS) TP_SRS_S.1(TP)
SL01_VI100_2_B_HF: K44.4 SITE1.29_F(VDD1_F) SLOT01.E33(2_B_HF)
SL01_VI100_2_B_HG: SLOT01.C57(2_B_HG)
SL01_VI100_2_B_HS: K45.4 SITE1.29_S(VDD1_S) SLOT01.C58(2_B_HS) TP_VDD1_S.1(TP)
SL01_VI100_2_LS: SLOT01.A33(2_LS) UNK1SH2.1
SL01_VI100_3_A_HF: K8.4 K9.4 SITE1.5_F(VSR_F) SLOT01.D31(3_A_HF) TP_VSR_F.1(TP)
SL01_VI100_3_A_HG: SLOT01.B31(3_A_HG)
SL01_VI100_3_A_HS: K10.4 SITE1.5_S(VSR_S) SLOT01.C31(3_A_HS) TP_VSR_S.1(TP)
SL01_VI100_3_B_HG: SLOT01.C55(3_B_HG)
SL01_VI100_3_B_HS: K18.4 SITE1.10_S(IS2N_S) SLOT01.C56(3_B_HS) TP_IS2N_S.1(TP)
SL01_VI100_3_LS: SLOT01.A31(3_LS) UNK1SH3.1
SL01_VI100_4_A_HG: SLOT01.B29(4_A_HG)
SL01_VI100_4_A_HS: K7.4 SITE1.4_S(SRG_S) SLOT01.C29(4_A_HS) TP_SRG_S.1(TP)
SL01_VI100_4_B_HG: SLOT01.C53(4_B_HG)
SL01_VI100_4_B_HS: K28.4 SITE1.17_S(C1B_S) SLOT01.C54(4_B_HS) TP_C1B_S.1(TP)
SL01_VI100_4_LS: SLOT01.A29(4_LS) UNK1SH4.1
SL01_VI100_5_A_HF: K11.4 K12.4 K13.4 SITE1.6_F(VCC_F) SLOT01.D27(5_A_HF) TP_VCC_F.1(TP)
SL01_VI100_5_A_HG: SLOT01.B27(5_A_HG)
SL01_VI100_5_A_HS: SITE1.6_S(VCC_S) SLOT01.C27(5_A_HS) TP_VCC_S.1(TP)
SL01_VI100_5_B_HF: SLOT01.E27(5_B_HF)
SL01_VI100_5_B_HG: SLOT01.C51(5_B_HG)
SL01_VI100_5_B_HS: SLOT01.C52(5_B_HS)
SL01_VI100_5_LS: SLOT01.A27(5_LS) UNK1SH5.1
SL01_VI100_6_A_HF: SITE1.7_F(OPTO_F) SLOT01.D25(6_A_HF) TP_OPTO_F.1(TP)
SL01_VI100_6_A_HG: SLOT01.B25(6_A_HG)
SL01_VI100_6_A_HS: K14.4 SITE1.7_S(OPTO_S) SLOT01.C25(6_A_HS) TP_OPTO_S.1(TP)
SL01_VI100_6_B_HF: SITE1.30_F(GB2_F) SLOT01.E25(6_B_HF)
SL01_VI100_6_B_HG: SLOT01.C49(6_B_HG)
SL01_VI100_6_B_HS: K46.4 SITE1.30_S(GB2_S) SLOT01.C50(6_B_HS) TP_GB2_S.1(TP)
SL01_VI100_6_LS: SLOT01.A25(6_LS) UNK1SH6.1
SL01_VI100_7_A_HF: SITE1.13_F(STB_F) SLOT01.D23(7_A_HF) TP_STB_F.1(TP)
SL01_VI100_7_A_HG: SLOT01.B23(7_A_HG)
SL01_VI100_7_A_HS: K22.4 SITE1.13_S(STB_S) SLOT01.C23(7_A_HS) TP_STB_S.1(TP)
SL01_VI100_7_B_HF: K47.4 SITE1.31_F(VO2_F) SLOT01.E23(7_B_HF)
SL01_VI100_7_B_HG: SLOT01.C47(7_B_HG)
SL01_VI100_7_B_HS: K48.4 SITE1.31_S(VO2_S) SLOT01.C48(7_B_HS) TP_VO2_S.1(TP)
SL01_VI100_7_LS: SLOT01.A23(7_LS) UNK1SH7.1
SL01_VI100_8_A_HF: K23.4 SLOT01.D21(8_A_HF)
SL01_VI100_8_A_HG: SLOT01.B21(8_A_HG)
SL01_VI100_8_A_HS: K23.5 SLOT01.C21(8_A_HS)
SL01_VI100_8_B_HF: C61.2 SITE1.20_F(C2B_F) SLOT01.E21(8_B_HF) TP_C2B_F.1(TP)
SL01_VI100_8_B_HG: SLOT01.C45(8_B_HG)
SL01_VI100_8_B_HS: K32.4 SITE1.20_S(C2B_S) SLOT01.C46(8_B_HS) TP_C2B_S.1(TP)
SL01_VI100_8_LS: SLOT01.A21(8_LS) UNK1SH8.1
SL01_VI100_9_A_HF: K24.4 SLOT01.D39(9_A_HF)
SL01_VI100_9_A_HG: SLOT01.B39(9_A_HG)
SL01_VI100_9_A_HS: K24.5 SLOT01.C39(9_A_HS)
SL01_VI100_9_B_HF: K33.4 SITE1.21_F(C3B_F) SLOT01.E39(9_B_HF) TP_C3B_F.1(TP)
SL01_VI100_9_B_HG: SLOT01.C61(9_B_HG)
SL01_VI100_9_B_HS: K34.4 SITE1.21_S(C3B_S) SLOT01.F37(9_B_HS) TP_C3B_S.1(TP)
SL01_VI100_9_LS: SLOT01.A39(9_LS) UNK1SH9.1
SL01_VI100_10_A_HF: K25.4 SITE1.16_F(VDD0_F) SLOT01.D17(10_A_HF) TP_VDD0_F.1(TP)
SL01_VI100_10_A_HG: SLOT01.B17(10_A_HG)
SL01_VI100_10_A_HS: K26.4 SITE1.16_S(VDD0_S) SLOT01.C17(10_A_HS) TP_VDD0_S.1(TP)
SL01_VI100_10_B_HF: SITE1.25_F(GA2_F) SLOT01.E17(10_B_HF)
SL01_VI100_10_B_HG: SLOT01.C43(10_B_HG)
SL01_VI100_10_B_HS: K40.4 SITE1.25_S(GA2_S) SLOT01.C44(10_B_HS) TP_GA2_S.1(TP)
SL01_VI100_10_LS: SLOT01.A17(10_LS) UNK1SH10.1
SL01_VI100_11_A_HF: C63.2 SITE1.18_F(C1A_F) SLOT01.D15(11_A_HF) TP_C1A_F.1(TP)
SL01_VI100_11_A_HG: SLOT01.B15(11_A_HG)
SL01_VI100_11_A_HS: K29.4 SITE1.18_S(C1A_S) SLOT01.C15(11_A_HS) TP_C1A_S.1(TP)
SL01_VI100_11_B_HF: SITE1.26_F(GA1_F) SLOT01.E15(11_B_HF)
SL01_VI100_11_B_HG: SLOT01.C41(11_B_HG)
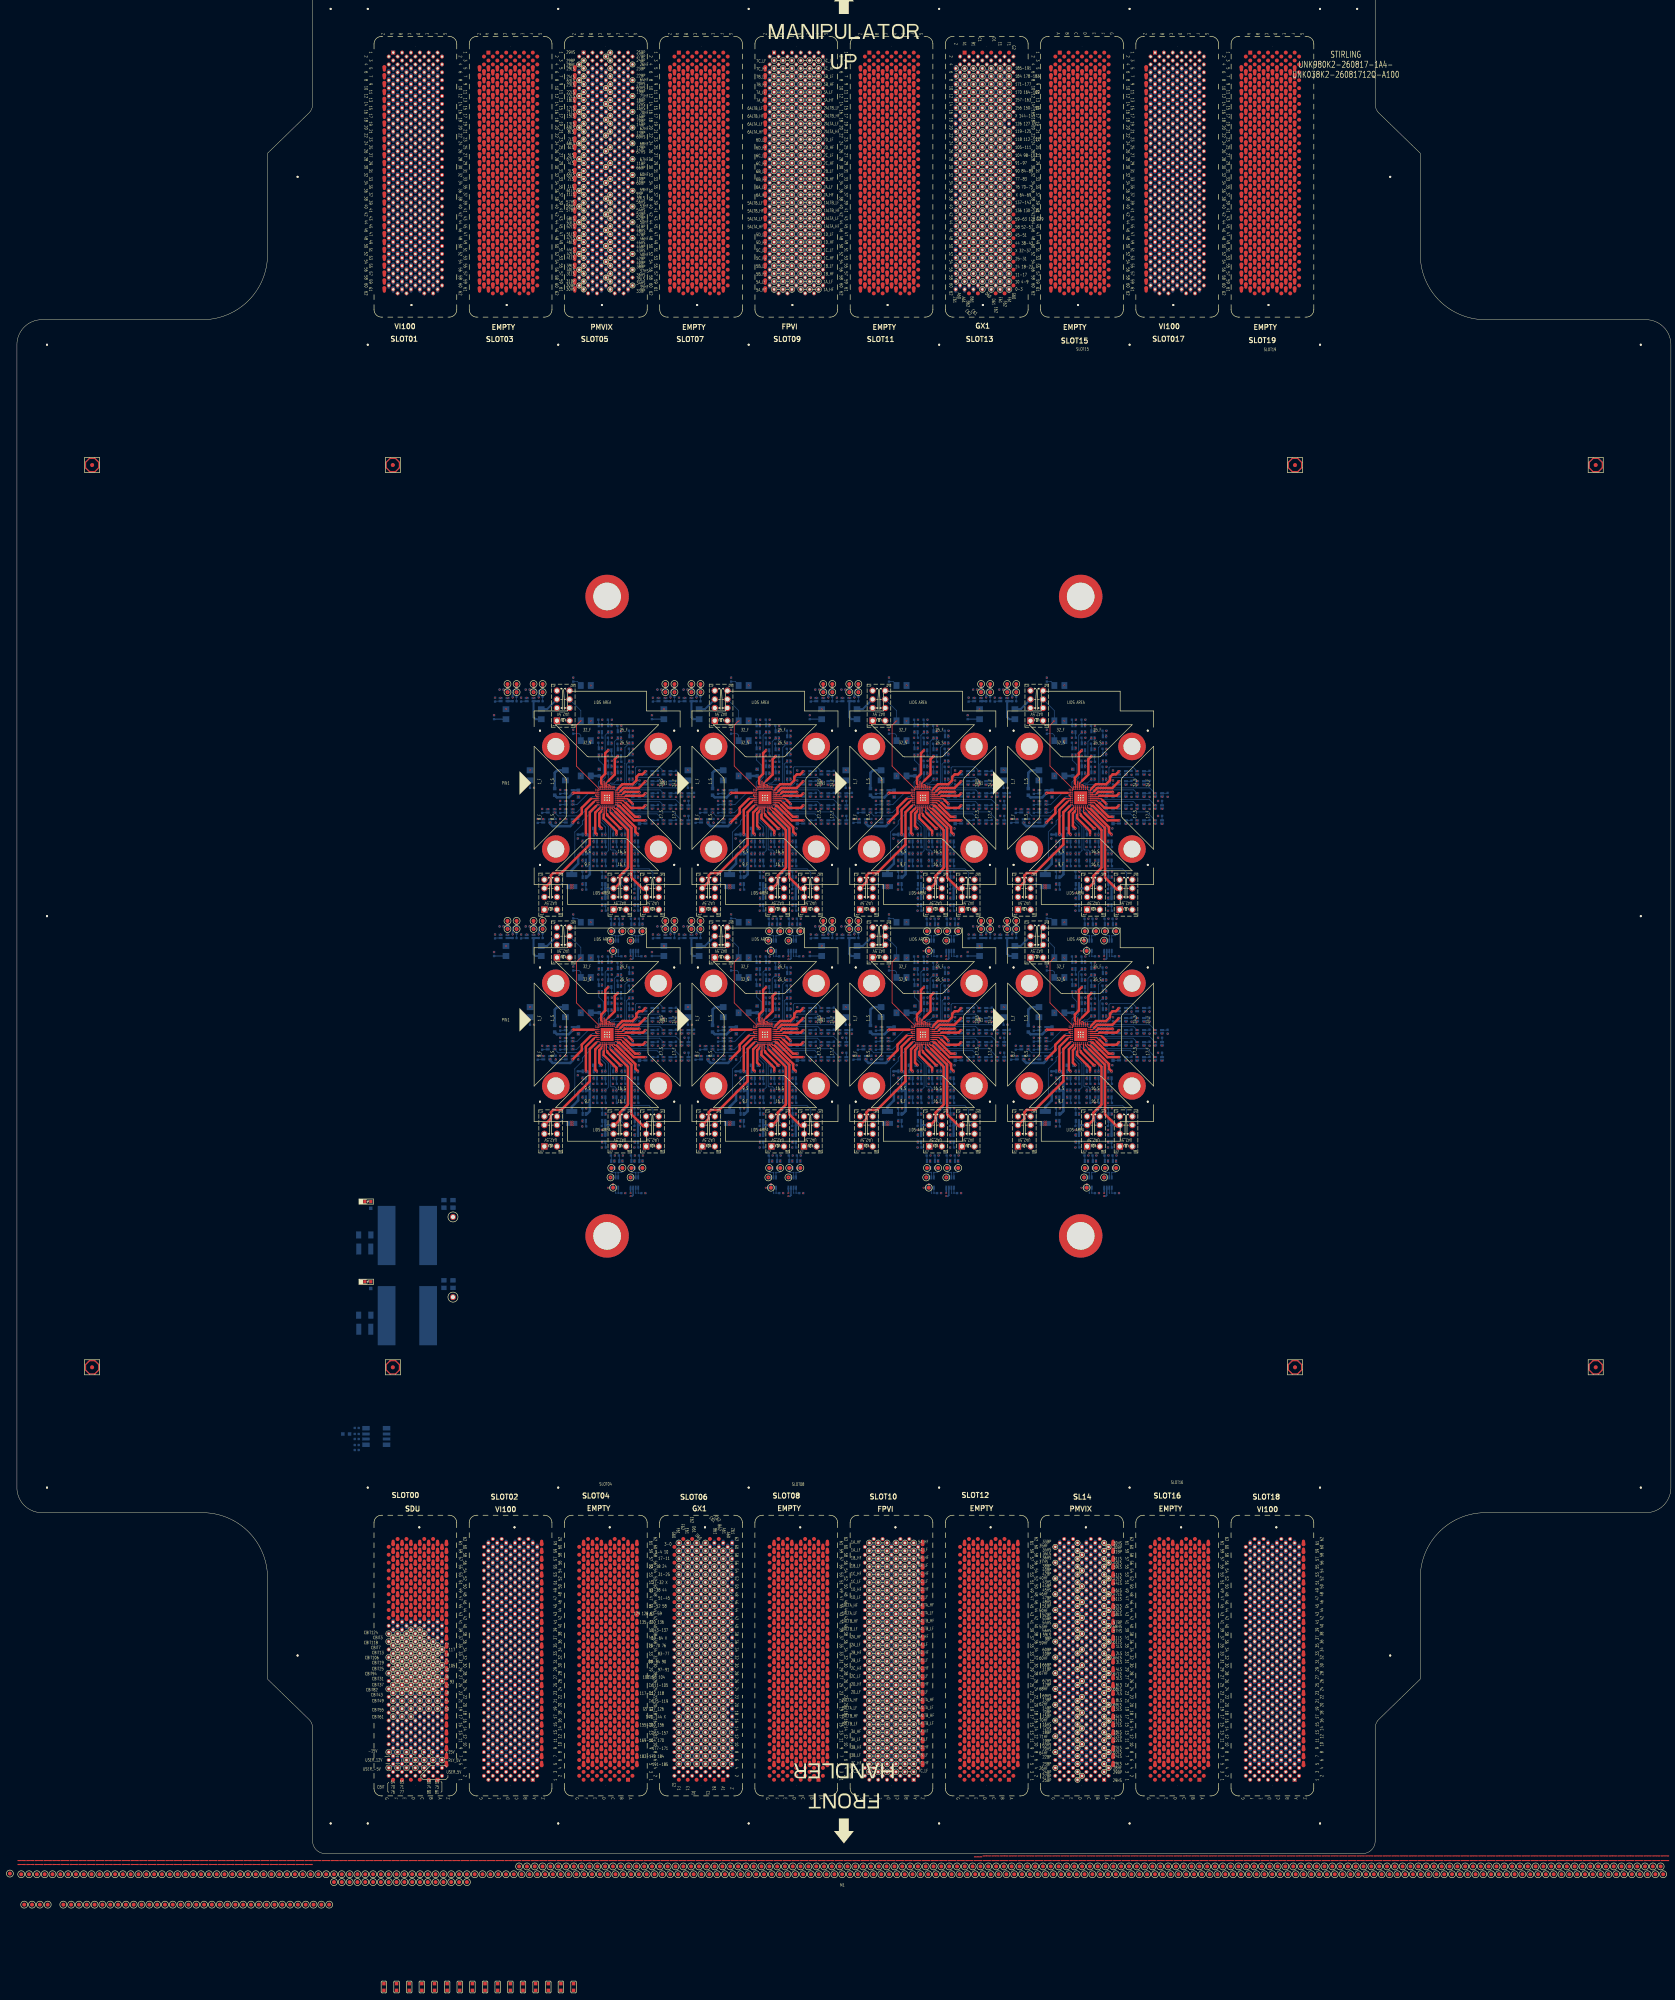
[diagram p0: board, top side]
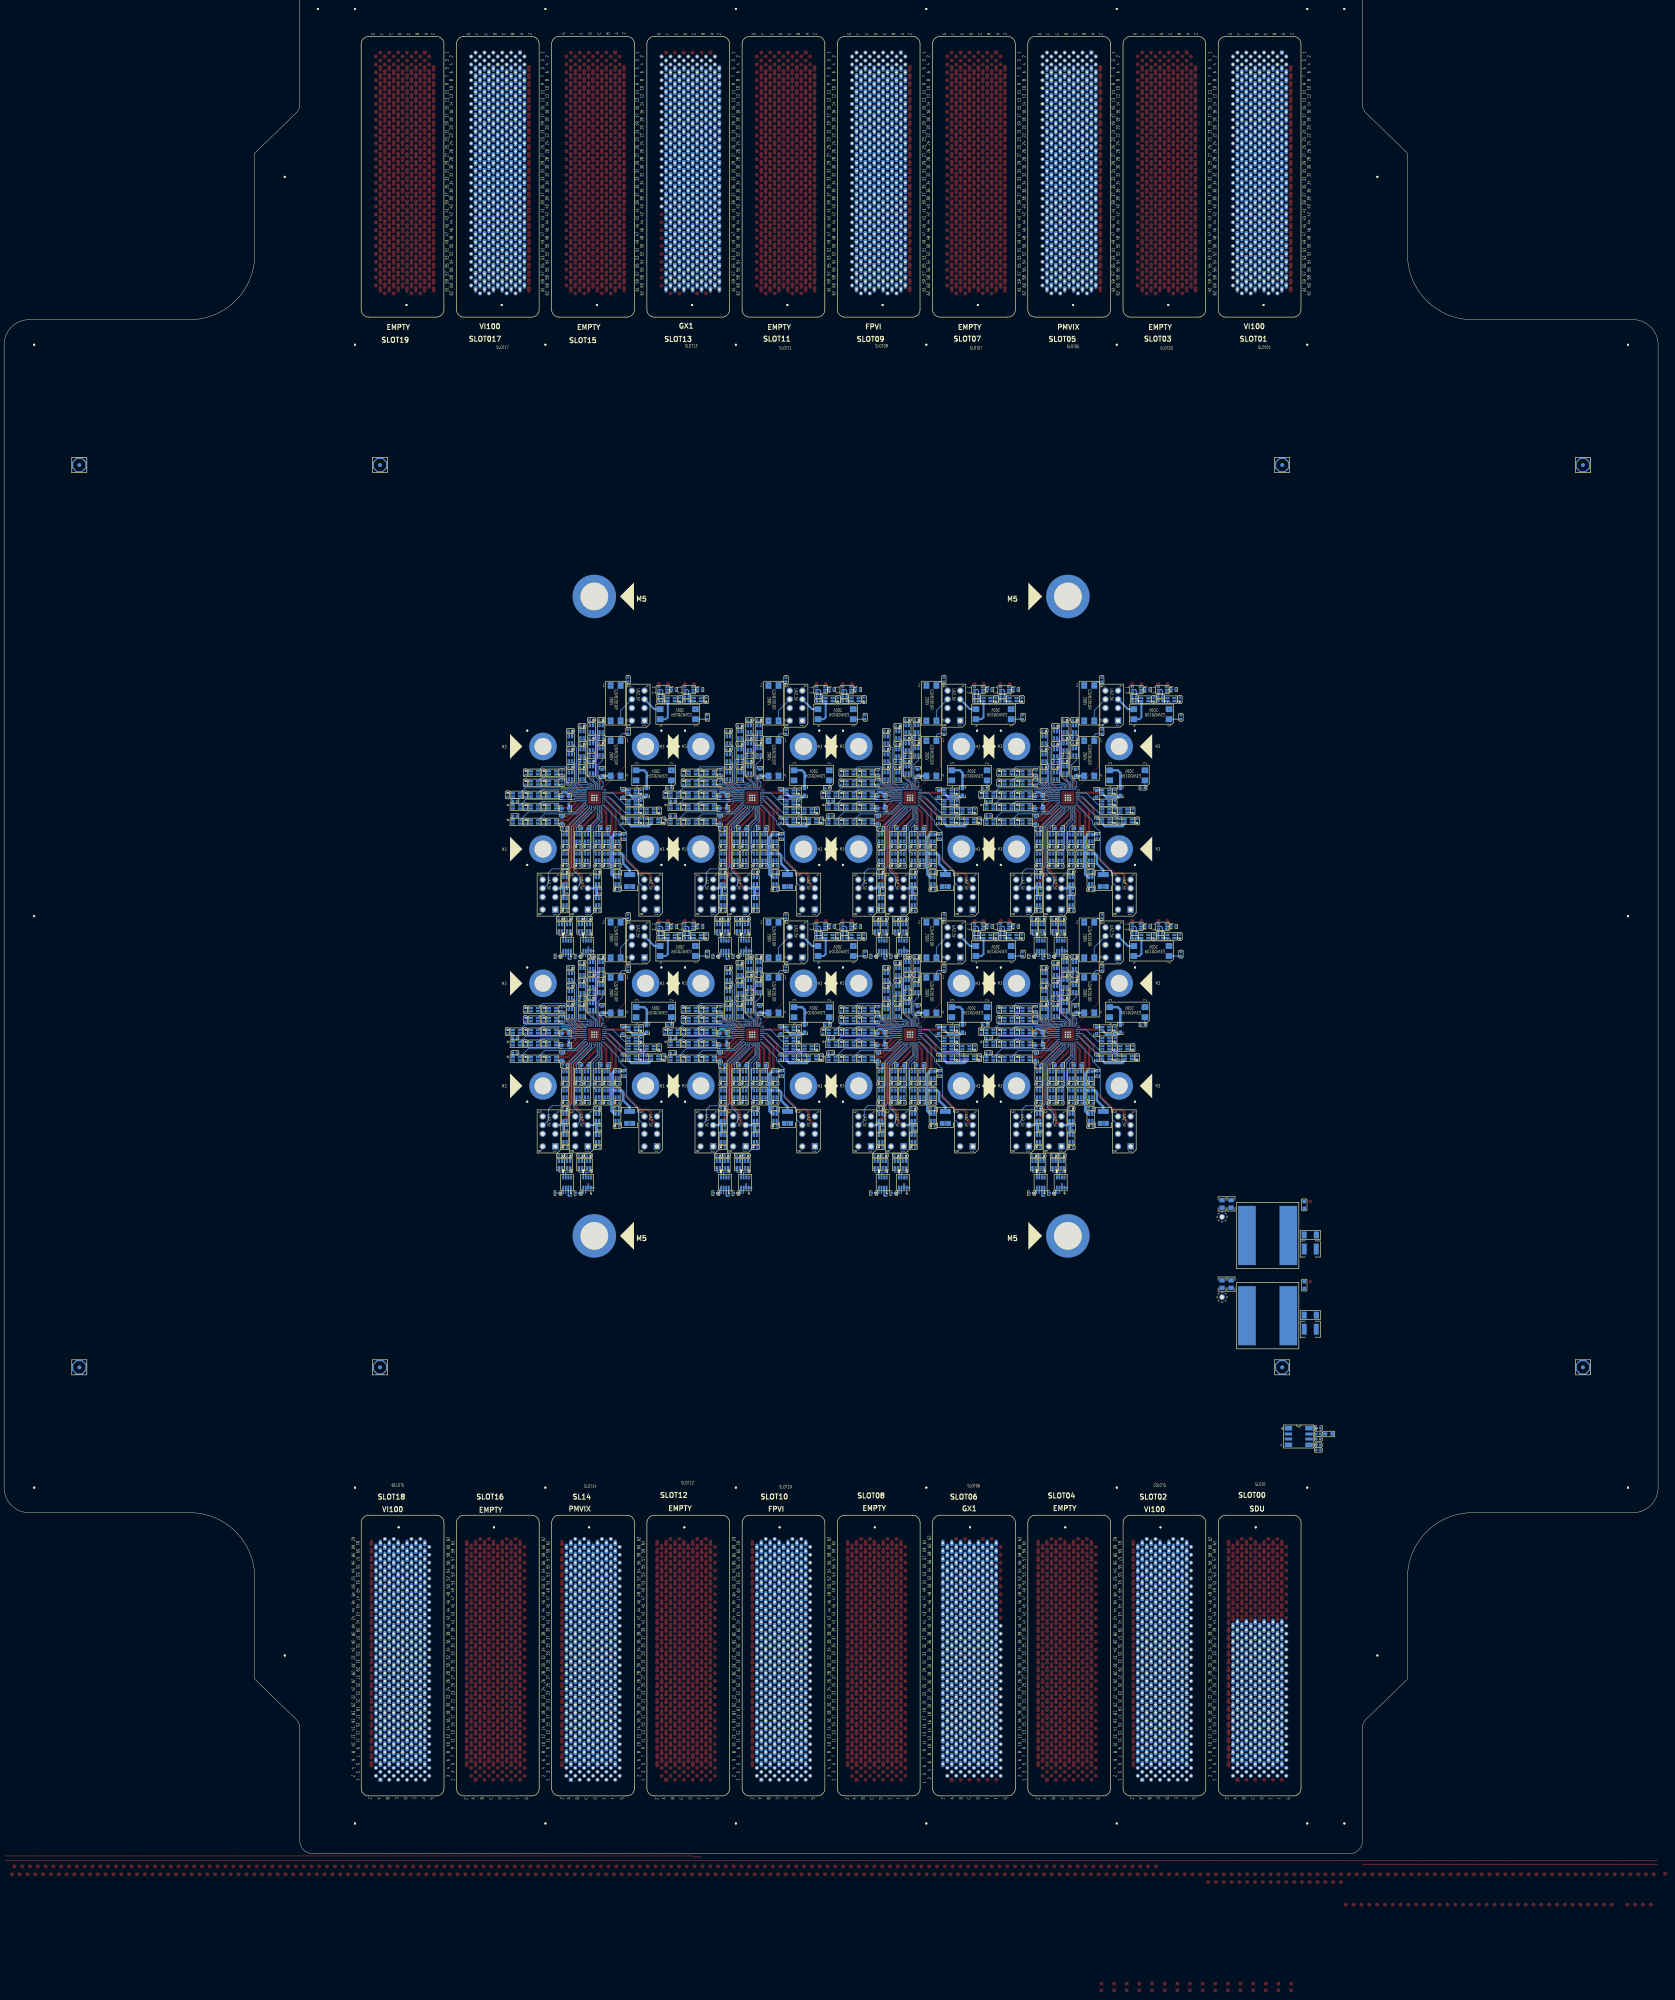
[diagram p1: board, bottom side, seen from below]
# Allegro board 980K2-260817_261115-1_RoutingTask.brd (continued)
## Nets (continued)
SL09_FPVI_8_ALTB_LS: SLOT09.A1(VI_8_ALTB_LS)
SL09_FPVI_8_B_HF: SLOT09.B44(VI_8_B_HF[1]) SLOT09.C44(VI_8_B_HF[2]) SLOT09.D46(VI_8_B_HF[3])
SL09_FPVI_8_B_HS: SLOT09.G4(VI_8_B_HS)
SL09_FPVI_8_B_LF: SLOT09.A42(VI_8_B_LF[1]) SLOT09.A44(VI_8_B_LF[2]) SLOT09.B42(VI_8_B_LF[3])
SL09_FPVI_8_B_LS: SLOT09.E1(VI_8_B_LS)
SL09_FPVI_8_C_HF: SLOT09.C42(VI_8_C_HF[1]) SLOT09.D42(VI_8_C_HF[2]) SLOT09.E42(VI_8_C_HF[3])
SL09_FPVI_8_C_HS: SLOT09.F2(VI_8_C_HS)
SL09_FPVI_8_C_LF: SLOT09.A40(VI_8_C_LF[1]) SLOT09.B40(VI_8_C_LF[2]) SLOT09.C40(VI_8_C_LF[3])
SL09_FPVI_8_C_LS: SLOT09.D1(VI_8_C_LS)
SL09_FPVI_8_D_HF: SLOT09.A38(VI_8_D_HF[1]) SLOT09.B38(VI_8_D_HF[2]) SLOT09.C38(VI_8_D_HF[3])
SL09_FPVI_8_D_HS: SLOT09.E2(VI_8_D_HS)
SL09_FPVI_8_D_LF: SLOT09.C36(VI_8_D_LF[1]) SLOT09.D36(VI_8_D_LF[2]) SLOT09.E36(VI_8_D_LF[3])
SL09_FPVI_8_D_LS: SLOT09.C1(VI_8_D_LS)
SL10_FPVI_1_A_HF: SLOT10.D61(VI_1_A_HF[1]) SLOT10.E61(VI_1_A_HF[2]) SLOT10.F61(VI_1_A_HF[3]) UNK2K1.4
SL10_FPVI_1_A_HS: SLOT10.E28(VI_1_A_HS) UNK2K1.5
SL10_FPVI_1_ALTA_HF: SLOT10.D45(VI_1_ALTA_HF[1]) SLOT10.E45(VI_1_ALTA_HF[2]) SLOT10.F45(VI_1_ALTA_HF[3])
SL10_FPVI_1_ALTA_HS: SLOT10.F24(VI_1_ALTA_HS)
SL10_FPVI_1_ALTA_LF: SLOT10.D43(VI_1_ALTA_LF[1]) SLOT10.E43(VI_1_ALTA_LF[2]) SLOT10.F43(VI_1_ALTA_LF[3])
SL10_FPVI_1_ALTA_LS: SLOT10.G24(VI_1_ALTA_LS)
SL10_FPVI_1_ALTB_HF: SLOT10.D41(VI_1_ALTB_HF[1]) SLOT10.E41(VI_1_ALTB_HF[2]) SLOT10.F41(VI_1_ALTB_HF[3])
SL10_FPVI_1_ALTB_HS: SLOT10.G26(VI_1_ALTB_HS)
SL10_FPVI_1_ALTB_LF: SLOT10.D39(VI_1_ALTB_LF[1]) SLOT10.E39(VI_1_ALTB_LF[2]) SLOT10.F39(VI_1_ALTB_LF[3])
SL10_FPVI_1_ALTB_LS: SLOT10.G22(VI_1_ALTB_LS)
SL10_FPVI_1_B_HF: SLOT10.D57(VI_1_B_HF[1]) SLOT10.E57(VI_1_B_HF[2]) SLOT10.F57(VI_1_B_HF[3])
SL10_FPVI_1_B_HS: SLOT10.F28(VI_1_B_HS)
SL10_FPVI_1_B_LF: SLOT10.D55(VI_1_B_LF[1]) SLOT10.E55(VI_1_B_LF[2]) SLOT10.F55(VI_1_B_LF[3])
SL10_FPVI_1_B_LS: SLOT10.E26(VI_1_B_LS)
SL10_FPVI_1_C_HF: SLOT10.D53(VI_1_C_HF[1]) SLOT10.E53(VI_1_C_HF[2]) SLOT10.F53(VI_1_C_HF[3])
SL10_FPVI_1_C_HS: SLOT10.G28(VI_1_C_HS)
SL10_FPVI_1_C_LF: SLOT10.D51(VI_1_C_LF[1]) SLOT10.E51(VI_1_C_LF[2]) SLOT10.F51(VI_1_C_LF[3])
SL10_FPVI_1_C_LS: SLOT10.F26(VI_1_C_LS)
SL10_FPVI_1_D_HF: SLOT10.D49(VI_1_D_HF[1]) SLOT10.E49(VI_1_D_HF[2]) SLOT10.F49(VI_1_D_HF[3])
SL10_FPVI_1_D_HS: SLOT10.E24(VI_1_D_HS)
SL10_FPVI_1_D_LF: SLOT10.D47(VI_1_D_LF[1]) SLOT10.E47(VI_1_D_LF[2]) SLOT10.F47(VI_1_D_LF[3])
SL10_FPVI_1_D_LS: SLOT10.F22(VI_1_D_LS)
SL10_FPVI_2_6_A_LF: SH2.2 SLOT10.A35(VI_6_A_LF[1]) SLOT10.B35(VI_6_A_LF[2]) SLOT10.C35(VI_6_A_LF[3]) SLOT10.D35(VI_2_A_LF[1]) SLOT10.E35(VI_2_A_LF[2]) SLOT10.F35(VI_2_A_LF[3]) SLOT18.E35(1_B_HF)
SL10_FPVI_2_A_HF: SLOT10.D37(VI_2_A_HF[1]) SLOT10.E37(VI_2_A_HF[2]) SLOT10.F37(VI_2_A_HF[3]) UNK6K1.4
SL10_FPVI_2_A_HS: SLOT10.D20(VI_2_A_HS) UNK6K1.5
SL10_FPVI_2_A_LS: SH2.1 SLOT10.A18(VI_6_A_LS) SLOT10.D18(VI_2_A_LS) SLOT18.C60(1_B_HS)
SL10_FPVI_2_ALTA_HF: SLOT10.D21(VI_2_ALTA_HF[1]) SLOT10.E21(VI_2_ALTA_HF[2]) SLOT10.F21(VI_2_ALTA_HF[3])
SL10_FPVI_2_ALTA_HS: SLOT10.F18(VI_2_ALTA_HS)
SL10_FPVI_2_ALTA_LF: SLOT10.D19(VI_2_ALTA_LF[1]) SLOT10.E19(VI_2_ALTA_LF[2]) SLOT10.F19(VI_2_ALTA_LF[3])
SL10_FPVI_2_ALTA_LS: SLOT10.D14(VI_2_ALTA_LS)
SL10_FPVI_2_ALTB_HF: SLOT10.D17(VI_2_ALTB_HF[1]) SLOT10.E17(VI_2_ALTB_HF[2]) SLOT10.F17(VI_2_ALTB_HF[3])
SL10_FPVI_2_ALTB_HS: SLOT10.G18(VI_2_ALTB_HS)
SL10_FPVI_2_ALTB_LF: SLOT10.D15(VI_2_ALTB_LF[1]) SLOT10.E15(VI_2_ALTB_LF[2]) SLOT10.F15(VI_2_ALTB_LF[3])
SL10_FPVI_2_ALTB_LS: SLOT10.E14(VI_2_ALTB_LS)
SL10_FPVI_2_B_HF: SLOT10.D33(VI_2_B_HF[1]) SLOT10.E33(VI_2_B_HF[2]) SLOT10.F33(VI_2_B_HF[3])
SL10_FPVI_2_B_HS: SLOT10.E20(VI_2_B_HS)
SL10_FPVI_2_B_LF: SLOT10.D31(VI_2_B_LF[1]) SLOT10.E31(VI_2_B_LF[2]) SLOT10.F31(VI_2_B_LF[3])
SL10_FPVI_2_B_LS: SLOT10.E18(VI_2_B_LS)
SL10_FPVI_2_C_HF: SLOT10.D29(VI_2_C_HF[1]) SLOT10.E29(VI_2_C_HF[2]) SLOT10.F29(VI_2_C_HF[3])
SL10_FPVI_2_C_HS: SLOT10.F20(VI_2_C_HS)
SL10_FPVI_2_C_LF: SLOT10.D27(VI_2_C_LF[1]) SLOT10.E27(VI_2_C_LF[2]) SLOT10.F27(VI_2_C_LF[3])
SL10_FPVI_2_C_LS: SLOT10.G20(VI_2_C_LS)
SL10_FPVI_2_D_HF: SLOT10.D25(VI_2_D_HF[1]) SLOT10.E25(VI_2_D_HF[2]) SLOT10.F25(VI_2_D_HF[3])
SL10_FPVI_2_D_HS: SLOT10.F16(VI_2_D_HS)
SL10_FPVI_2_D_LF: SLOT10.D23(VI_2_D_LF[1]) SLOT10.E23(VI_2_D_LF[2]) SLOT10.F23(VI_2_D_LF[3])
SL10_FPVI_2_D_LS: SLOT10.C14(VI_2_D_LS)
SL10_FPVI_3_A_HF: SLOT10.D13(VI_3_A_HF[1]) SLOT10.E13(VI_3_A_HF[2]) SLOT10.F13(VI_3_A_HF[3])
SL10_FPVI_3_A_HS: SLOT10.F14(VI_3_A_HS)
SL10_FPVI_3_A_LF: SLOT10.D11(VI_3_A_LF[1]) SLOT10.E11(VI_3_A_LF[2]) SLOT10.F11(VI_3_A_LF[3])
SL10_FPVI_3_A_LS: SLOT10.D10(VI_3_A_LS)
SL10_FPVI_3_ALTA_HF: SLOT10.F56(VI_3_ALTA_HF[1]) SLOT10.F58(VI_3_ALTA_HF[2]) SLOT10.G58(VI_3_ALTA_HF[3])
SL10_FPVI_3_ALTA_HS: SLOT10.E10(VI_3_ALTA_HS)
SL10_FPVI_3_ALTA_LF: SLOT10.C54(VI_3_ALTA_LF[1]) SLOT10.D54(VI_3_ALTA_LF[2]) SLOT10.E54(VI_3_ALTA_LF[3])
SL10_FPVI_3_ALTA_LS: SLOT10.F8(VI_3_ALTA_LS)
SL10_FPVI_3_ALTB_HF: SLOT10.F54(VI_3_ALTB_HF[1]) SLOT10.G52(VI_3_ALTB_HF[2]) SLOT10.G54(VI_3_ALTB_HF[3])
SL10_FPVI_3_ALTB_HS: SLOT10.F10(VI_3_ALTB_HS)
SL10_FPVI_3_ALTB_LF: SLOT10.D50(VI_3_ALTB_LF[1]) SLOT10.E52(VI_3_ALTB_LF[2]) SLOT10.F52(VI_3_ALTB_LF[3])
SL10_FPVI_3_ALTB_LS: SLOT10.G8(VI_3_ALTB_LS)
SL10_FPVI_3_B_HF: SLOT10.D9(VI_3_B_HF[1]) SLOT10.E9(VI_3_B_HF[2]) SLOT10.F9(VI_3_B_HF[3])
SL10_FPVI_3_B_HS: SLOT10.G12(VI_3_B_HS)
SL10_FPVI_3_B_LF: SLOT10.D7(VI_3_B_LF[1]) SLOT10.E7(VI_3_B_LF[2]) SLOT10.F7(VI_3_B_LF[3])
SL10_FPVI_3_B_LS: SLOT10.E12(VI_3_B_LS)
SL10_FPVI_3_C_HF: SLOT10.D5(VI_3_C_HF[1]) SLOT10.E5(VI_3_C_HF[2]) SLOT10.F5(VI_3_C_HF[3])
SL10_FPVI_3_C_HS: SLOT10.G14(VI_3_C_HS)
SL10_FPVI_3_C_LF: SLOT10.D3(VI_3_C_LF[1]) SLOT10.E3(VI_3_C_LF[2]) SLOT10.F3(VI_3_C_LF[3])
SL10_FPVI_3_C_LS: SLOT10.F12(VI_3_C_LS)
SL10_FPVI_3_D_HF: SLOT10.D60(VI_3_D_HF[1]) SLOT10.E60(VI_3_D_HF[2]) SLOT10.F60(VI_3_D_HF[3])
SL10_FPVI_3_D_HS: SLOT10.D8(VI_3_D_HS)
SL10_FPVI_3_D_LF: SLOT10.D58(VI_3_D_LF[1]) SLOT10.E58(VI_3_D_LF[2]) SLOT10.G60(VI_3_D_LF[3])
SL10_FPVI_3_D_LS: SLOT10.E8(VI_3_D_LS)
SL10_FPVI_4_A_HF: SLOT10.D48(VI_4_A_HF[1]) SLOT10.E50(VI_4_A_HF[2]) SLOT10.F50(VI_4_A_HF[3])
SL10_FPVI_4_A_HS: SLOT10.F6(VI_4_A_HS)
SL10_FPVI_4_A_LF: SLOT10.E48(VI_4_A_LF[1]) SLOT10.F48(VI_4_A_LF[2]) SLOT10.G48(VI_4_A_LF[3])
SL10_FPVI_4_A_LS: SLOT10.G6(VI_4_A_LS)
SL10_FPVI_4_ALTA_HF: SLOT10.C34(VI_4_ALTA_HF[1]) SLOT10.D34(VI_4_ALTA_HF[2]) SLOT10.E34(VI_4_ALTA_HF[3])
SL10_FPVI_4_ALTA_HS: SLOT10.C4(VI_4_ALTA_HS)
SL10_FPVI_4_ALTA_LF: SLOT10.F34(VI_4_ALTA_LF[1]) SLOT10.G32(VI_4_ALTA_LF[2]) SLOT10.G34(VI_4_ALTA_LF[3])
SL10_FPVI_4_ALTA_LS: SLOT10.A2(VI_4_ALTA_LS)
SL10_FPVI_4_ALTB_HF: SLOT10.D30(VI_4_ALTB_HF[1]) SLOT10.E32(VI_4_ALTB_HF[2]) SLOT10.F32(VI_4_ALTB_HF[3])
SL10_FPVI_4_ALTB_HS: SLOT10.B4(VI_4_ALTB_HS)
SL10_FPVI_4_ALTB_LF: SLOT10.D28(VI_4_ALTB_LF[1]) SLOT10.E30(VI_4_ALTB_LF[2]) SLOT10.F30(VI_4_ALTB_LF[3])
SL10_FPVI_4_ALTB_LS: SLOT10.A4(VI_4_ALTB_LS)
SL10_FPVI_4_B_HF: SLOT10.D44(VI_4_B_HF[1]) SLOT10.E46(VI_4_B_HF[2]) SLOT10.F46(VI_4_B_HF[3])
SL10_FPVI_4_B_HS: SLOT10.E6(VI_4_B_HS)
SL10_FPVI_4_B_LF: SLOT10.E44(VI_4_B_LF[1]) SLOT10.F44(VI_4_B_LF[2]) SLOT10.G46(VI_4_B_LF[3])
SL10_FPVI_4_B_LS: SLOT10.F4(VI_4_B_LS)
SL10_FPVI_4_C_HF: SLOT10.F42(VI_4_C_HF[1]) SLOT10.G42(VI_4_C_HF[2]) SLOT10.G44(VI_4_C_HF[3])
SL10_FPVI_4_C_HS: SLOT10.D4(VI_4_C_HS)
SL10_FPVI_4_C_LF: SLOT10.D40(VI_4_C_LF[1]) SLOT10.E40(VI_4_C_LF[2]) SLOT10.F40(VI_4_C_LF[3])
SL10_FPVI_4_C_LS: SLOT10.E4(VI_4_C_LS)
SL10_FPVI_4_D_HF: SLOT10.D38(VI_4_D_HF[1]) SLOT10.E38(VI_4_D_HF[2]) SLOT10.G40(VI_4_D_HF[3])
SL10_FPVI_4_D_HS: SLOT10.D6(VI_4_D_HS)
SL10_FPVI_4_D_LF: SLOT10.F36(VI_4_D_LF[1]) SLOT10.F38(VI_4_D_LF[2]) SLOT10.G38(VI_4_D_LF[3])
SL10_FPVI_4_D_LS: SLOT10.B2(VI_4_D_LS)
SL10_FPVI_5_A_HF: SLOT10.A61(VI_5_A_HF[1]) SLOT10.B61(VI_5_A_HF[2]) SLOT10.C61(VI_5_A_HF[3]) UNK4K1.4
SL10_FPVI_5_A_HS: SLOT10.A26(VI_5_A_HS) UNK4K1.5
SL10_FPVI_5_ALTA_HF: SLOT10.A45(VI_5_ALTA_HF[1]) SLOT10.B45(VI_5_ALTA_HF[2]) SLOT10.C45(VI_5_ALTA_HF[3])
SL10_FPVI_5_ALTA_HS: SLOT10.A22(VI_5_ALTA_HS)
SL10_FPVI_5_ALTA_LF: SLOT10.A43(VI_5_ALTA_LF[1]) SLOT10.B43(VI_5_ALTA_LF[2]) SLOT10.C43(VI_5_ALTA_LF[3])
SL10_FPVI_5_ALTA_LS: SLOT10.D22(VI_5_ALTA_LS)
SL10_FPVI_5_ALTB_HF: SLOT10.A41(VI_5_ALTB_HF[1]) SLOT10.B41(VI_5_ALTB_HF[2]) SLOT10.C41(VI_5_ALTB_HF[3])
SL10_FPVI_5_ALTB_HS: SLOT10.B22(VI_5_ALTB_HS)
SL10_FPVI_5_ALTB_LF: SLOT10.A39(VI_5_ALTB_LF[1]) SLOT10.B39(VI_5_ALTB_LF[2]) SLOT10.C39(VI_5_ALTB_LF[3])
SL10_FPVI_5_ALTB_LS: SLOT10.E22(VI_5_ALTB_LS)
SL10_FPVI_5_B_HF: SLOT10.A57(VI_5_B_HF[1]) SLOT10.B57(VI_5_B_HF[2]) SLOT10.C57(VI_5_B_HF[3])
SL10_FPVI_5_B_HS: SLOT10.B26(VI_5_B_HS)
SL10_FPVI_5_B_LF: SLOT10.A55(VI_5_B_LF[1]) SLOT10.B55(VI_5_B_LF[2]) SLOT10.C55(VI_5_B_LF[3])
SL10_FPVI_5_B_LS: SLOT10.C24(VI_5_B_LS)
SL10_FPVI_5_C_HF: SLOT10.A53(VI_5_C_HF[1]) SLOT10.B53(VI_5_C_HF[2]) SLOT10.C53(VI_5_C_HF[3])
SL10_FPVI_5_C_HS: SLOT10.C26(VI_5_C_HS)
SL10_FPVI_5_C_LF: SLOT10.A51(VI_5_C_LF[1]) SLOT10.B51(VI_5_C_LF[2]) SLOT10.C51(VI_5_C_LF[3])
SL10_FPVI_5_C_LS: SLOT10.D26(VI_5_C_LS)
SL10_FPVI_5_D_HF: SLOT10.A49(VI_5_D_HF[1]) SLOT10.B49(VI_5_D_HF[2]) SLOT10.C49(VI_5_D_HF[3])
SL10_FPVI_5_D_HS: SLOT10.A24(VI_5_D_HS)
SL10_FPVI_5_D_LF: SLOT10.A47(VI_5_D_LF[1]) SLOT10.B47(VI_5_D_LF[2]) SLOT10.C47(VI_5_D_LF[3])
SL10_FPVI_5_D_LS: SLOT10.C22(VI_5_D_LS)
SL10_FPVI_6_A_HF: SLOT10.A37(VI_6_A_HF[1]) SLOT10.B37(VI_6_A_HF[2]) SLOT10.C37(VI_6_A_HF[3]) UNK8K1.4
SL10_FPVI_6_A_HS: SLOT10.A20(VI_6_A_HS) UNK8K1.5
SL10_FPVI_6_ALTA_HF: SLOT10.A21(VI_6_ALTA_HF[1]) SLOT10.B21(VI_6_ALTA_HF[2]) SLOT10.C21(VI_6_ALTA_HF[3])
SL10_FPVI_6_ALTA_HS: SLOT10.D16(VI_6_ALTA_HS)
SL10_FPVI_6_ALTA_LF: SLOT10.A19(VI_6_ALTA_LF[1]) SLOT10.B19(VI_6_ALTA_LF[2]) SLOT10.C19(VI_6_ALTA_LF[3])
SL10_FPVI_6_ALTA_LS: SLOT10.B16(VI_6_ALTA_LS)
SL10_FPVI_6_ALTB_HF: SLOT10.A17(VI_6_ALTB_HF[1]) SLOT10.B17(VI_6_ALTB_HF[2]) SLOT10.C17(VI_6_ALTB_HF[3])
SL10_FPVI_6_ALTB_HS: SLOT10.E16(VI_6_ALTB_HS)
SL10_FPVI_6_ALTB_LF: SLOT10.A15(VI_6_ALTB_LF[1]) SLOT10.B15(VI_6_ALTB_LF[2]) SLOT10.C15(VI_6_ALTB_LF[3])
SL10_FPVI_6_ALTB_LS: SLOT10.B14(VI_6_ALTB_LS)
SL10_FPVI_6_B_HF: SLOT10.A33(VI_6_B_HF[1]) SLOT10.B33(VI_6_B_HF[2]) SLOT10.C33(VI_6_B_HF[3])
SL10_FPVI_6_B_HS: SLOT10.B20(VI_6_B_HS)
SL10_FPVI_6_B_LF: SLOT10.A31(VI_6_B_LF[1]) SLOT10.B31(VI_6_B_LF[2]) SLOT10.C31(VI_6_B_LF[3])
SL10_FPVI_6_B_LS: SLOT10.B18(VI_6_B_LS)
SL10_FPVI_6_C_HF: SLOT10.A29(VI_6_C_HF[1]) SLOT10.B29(VI_6_C_HF[2]) SLOT10.C29(VI_6_C_HF[3])
SL10_FPVI_6_C_HS: SLOT10.C20(VI_6_C_HS)
SL10_FPVI_6_C_LF: SLOT10.A27(VI_6_C_LF[1]) SLOT10.B27(VI_6_C_LF[2]) SLOT10.C27(VI_6_C_LF[3])
SL10_FPVI_6_C_LS: SLOT10.C18(VI_6_C_LS)
SL10_FPVI_6_D_HF: SLOT10.A25(VI_6_D_HF[1]) SLOT10.B25(VI_6_D_HF[2]) SLOT10.C25(VI_6_D_HF[3])
SL10_FPVI_6_D_HS: SLOT10.C16(VI_6_D_HS)
SL10_FPVI_6_D_LF: SLOT10.A23(VI_6_D_LF[1]) SLOT10.B23(VI_6_D_LF[2]) SLOT10.C23(VI_6_D_LF[3])
SL10_FPVI_6_D_LS: SLOT10.A14(VI_6_D_LS)
SL10_FPVI_7_A_HF: SLOT10.A13(VI_7_A_HF[1]) SLOT10.B13(VI_7_A_HF[2]) SLOT10.C13(VI_7_A_HF[3])
SL10_FPVI_7_A_HS: SLOT10.A12(VI_7_A_HS)
SL10_FPVI_7_A_LF: SLOT10.A11(VI_7_A_LF[1]) SLOT10.B11(VI_7_A_LF[2]) SLOT10.C11(VI_7_A_LF[3])
SL10_FPVI_7_A_LS: SLOT10.B10(VI_7_A_LS)
SL10_FPVI_7_ALTA_HF: SLOT10.C56(VI_7_ALTA_HF[1]) SLOT10.D56(VI_7_ALTA_HF[2]) SLOT10.E56(VI_7_ALTA_HF[3])
SL10_FPVI_7_ALTA_HS: SLOT10.B8(VI_7_ALTA_HS)
SL10_FPVI_7_ALTA_LF: SLOT10.A54(VI_7_ALTA_LF[1]) SLOT10.B54(VI_7_ALTA_LF[2]) SLOT10.B56(VI_7_ALTA_LF[3])
SL10_FPVI_7_ALTA_LS: SLOT10.B6(VI_7_ALTA_LS)
SL10_FPVI_7_ALTB_HF: SLOT10.A52(VI_7_ALTB_HF[1]) SLOT10.B52(VI_7_ALTB_HF[2]) SLOT10.C52(VI_7_ALTB_HF[3])
SL10_FPVI_7_ALTB_HS: SLOT10.C8(VI_7_ALTB_HS)
SL10_FPVI_7_ALTB_LF: SLOT10.B50(VI_7_ALTB_LF[1]) SLOT10.C50(VI_7_ALTB_LF[2]) SLOT10.D52(VI_7_ALTB_LF[3])
SL10_FPVI_7_ALTB_LS: SLOT10.C6(VI_7_ALTB_LS)
SL10_FPVI_7_B_HF: SLOT10.A9(VI_7_B_HF[1]) SLOT10.B9(VI_7_B_HF[2]) SLOT10.C9(VI_7_B_HF[3])
SL10_FPVI_7_B_HS: SLOT10.B12(VI_7_B_HS)
SL10_FPVI_7_B_LF: SLOT10.A7(VI_7_B_LF[1]) SLOT10.B7(VI_7_B_LF[2]) SLOT10.C7(VI_7_B_LF[3])
SL10_FPVI_7_B_LS: SLOT10.C10(VI_7_B_LS)
SL10_FPVI_7_C_HF: SLOT10.A5(VI_7_C_HF[1]) SLOT10.B5(VI_7_C_HF[2]) SLOT10.C5(VI_7_C_HF[3])
SL10_FPVI_7_C_HS: SLOT10.C12(VI_7_C_HS)
SL10_FPVI_7_C_LF: SLOT10.A3(VI_7_C_LF[1]) SLOT10.B3(VI_7_C_LF[2]) SLOT10.C3(VI_7_C_LF[3])
SL10_FPVI_7_C_LS: SLOT10.D12(VI_7_C_LS)
SL10_FPVI_7_D_HF: SLOT10.A60(VI_7_D_HF[1]) SLOT10.B60(VI_7_D_HF[2]) SLOT10.C60(VI_7_D_HF[3])
SL10_FPVI_7_D_HS: SLOT10.A8(VI_7_D_HS)
SL10_FPVI_7_D_LF: SLOT10.A58(VI_7_D_LF[1]) SLOT10.B58(VI_7_D_LF[2]) SLOT10.C58(VI_7_D_LF[3])
SL10_FPVI_7_D_LS: SLOT10.A6(VI_7_D_LS)
SL10_FPVI_8_A_HF: SLOT10.A48(VI_8_A_HF[1]) SLOT10.B48(VI_8_A_HF[2]) SLOT10.C48(VI_8_A_HF[3])
SL10_FPVI_8_A_HS: SLOT10.G2(VI_8_A_HS)
SL10_FPVI_8_A_LF: SLOT10.A46(VI_8_A_LF[1]) SLOT10.B46(VI_8_A_LF[2]) SLOT10.C46(VI_8_A_LF[3])
SL10_FPVI_8_A_LS: SLOT10.F1(VI_8_A_LS)
SL10_FPVI_8_ALTA_HF: SLOT10.A34(VI_8_ALTA_HF[1]) SLOT10.B34(VI_8_ALTA_HF[2]) SLOT10.B36(VI_8_ALTA_HF[3])
SL10_FPVI_8_ALTA_HS: SLOT10.D2(VI_8_ALTA_HS)
SL10_FPVI_8_ALTA_LF: SLOT10.A32(VI_8_ALTA_LF[1]) SLOT10.B32(VI_8_ALTA_LF[2]) SLOT10.C32(VI_8_ALTA_LF[3])
SL10_FPVI_8_ALTA_LS: SLOT10.B1(VI_8_ALTA_LS)
SL10_FPVI_8_ALTB_HF: SLOT10.B30(VI_8_ALTB_HF[1]) SLOT10.C30(VI_8_ALTB_HF[2]) SLOT10.D32(VI_8_ALTB_HF[3])
SL10_FPVI_8_ALTB_HS: SLOT10.C2(VI_8_ALTB_HS)
SL10_FPVI_8_ALTB_LF: SLOT10.A28(VI_8_ALTB_LF[1]) SLOT10.B28(VI_8_ALTB_LF[2]) SLOT10.C28(VI_8_ALTB_LF[3])
SL10_FPVI_8_ALTB_LS: SLOT10.A1(VI_8_ALTB_LS)
SL10_FPVI_8_B_HF: SLOT10.B44(VI_8_B_HF[1]) SLOT10.C44(VI_8_B_HF[2]) SLOT10.D46(VI_8_B_HF[3])
SL10_FPVI_8_B_HS: SLOT10.G4(VI_8_B_HS)
SL10_FPVI_8_B_LF: SLOT10.A42(VI_8_B_LF[1]) SLOT10.A44(VI_8_B_LF[2]) SLOT10.B42(VI_8_B_LF[3])
SL10_FPVI_8_B_LS: SLOT10.E1(VI_8_B_LS)
SL10_FPVI_8_C_HF: SLOT10.C42(VI_8_C_HF[1]) SLOT10.D42(VI_8_C_HF[2]) SLOT10.E42(VI_8_C_HF[3])
SL10_FPVI_8_C_HS: SLOT10.F2(VI_8_C_HS)
SL10_FPVI_8_C_LF: SLOT10.A40(VI_8_C_LF[1]) SLOT10.B40(VI_8_C_LF[2]) SLOT10.C40(VI_8_C_LF[3])
SL10_FPVI_8_C_LS: SLOT10.D1(VI_8_C_LS)
SL10_FPVI_8_D_HF: SLOT10.A38(VI_8_D_HF[1]) SLOT10.B38(VI_8_D_HF[2]) SLOT10.C38(VI_8_D_HF[3])
SL10_FPVI_8_D_HS: SLOT10.E2(VI_8_D_HS)
SL10_FPVI_8_D_LF: SLOT10.C36(VI_8_D_LF[1]) SLOT10.D36(VI_8_D_LF[2]) SLOT10.E36(VI_8_D_LF[3])
SL10_FPVI_8_D_LS: SLOT10.C1(VI_8_D_LS)
SL13_DP_0: K4.3 SLOT13.C61
SL13_DP_1: K6.3 SLOT13.D61
SL13_DP_2: K7.3 SLOT13.E61
SL13_DP_3: K10.3 SLOT13.F61
SL13_DP_4: K14.3 SLOT13.A59
SL13_DP_5: K15.2 SLOT13.B59
SL13_DP_6: K17.3 SLOT13.C59
SL13_DP_7: K18.3 SLOT13.D59
SL13_DP_8: K20.3 SLOT13.E59
SL13_DP_9: K21.3 SLOT13.F59
SL13_DP_10: K22.3 SLOT13.Z59
SL13_DP_11: K23.2 SLOT13.Z57
SL13_DP_12: K24.2 SLOT13.A57
SL13_DP_13: K26.3 SLOT13.B57
SL13_DP_14: K28.3 SLOT13.C57
SL13_DP_15: K29.3 SLOT13.D57
SL13_DP_16: K31.3 SLOT13.E57
SL13_DP_17: K32.3 SLOT13.F57
SL13_DP_18: K34.3 SLOT13.A55
SL13_DP_19: K35.3 SLOT13.B55
SL13_DP_20: K37.3 SLOT13.C55
SL13_DP_21: K39.3 SLOT13.D55
SL13_DP_22: K40.3 SLOT13.E55
SL13_DP_23: K41.3 SLOT13.F55
SL13_DP_24: K42.3 SLOT13.Z55
SL13_DP_25: K43.3 SLOT13.Z53
SL13_DP_26: K45.3 SLOT13.A53
SL13_DP_27: K46.3 SLOT13.B53
SL13_DP_28: K48.3 SLOT13.C53
SL13_DP_29: K50.3 SLOT13.D53
SL13_DP_30: SLOT13.E53 UNK3K4.3
SL13_DP_31: SLOT13.F53 UNK3K6.3
SL13_DP_32: SLOT13.A51 UNK3K7.3
SL13_DP_33: SLOT13.B51 UNK3K10.3
SL13_DP_34: SLOT13.C51 UNK3K14.3
SL13_DP_35: SLOT13.D51 UNK3K15.2
SL13_DP_36: SLOT13.E51 UNK3K17.3
SL13_DP_37: SLOT13.F51 UNK3K18.3
SL13_DP_38: SLOT13.A49 UNK3K20.3
SL13_DP_39: SLOT13.B49 UNK3K21.3
SL13_DP_40: SLOT13.C49 UNK3K22.3
SL13_DP_41: SLOT13.D49 UNK3K23.2
SL13_DP_42: SLOT13.E49 UNK3K24.2
SL13_DP_43: SLOT13.F49 UNK3K26.3
SL13_DP_44: SLOT13.Z49 UNK3K28.3
SL13_DP_45: SLOT13.Z47 UNK3K29.3
SL13_DP_46: SLOT13.A47 UNK3K31.3
SL13_DP_47: SLOT13.B47 UNK3K32.3
SL13_DP_48: SLOT13.C47 UNK3K34.3
SL13_DP_49: SLOT13.D47 UNK3K35.3
SL13_DP_50: SLOT13.E47 UNK3K37.3
SL13_DP_51: SLOT13.F47 UNK3K39.3
SL13_DP_52: SLOT13.A45 UNK3K40.3
SL13_DP_53: SLOT13.B45 UNK3K41.3
SL13_DP_54: SLOT13.C45 UNK3K42.3
SL13_DP_55: SLOT13.D45 UNK3K43.3
SL13_DP_56: SLOT13.E45 UNK3K45.3
SL13_DP_57: SLOT13.F45 UNK3K46.3
SL13_DP_58: SLOT13.Z45 UNK3K48.3
SL13_DP_59: SLOT13.Z43 UNK3K50.3
SL13_DP_60: SLOT13.A43 UNK5K4.3
SL13_DP_61: SLOT13.B43 UNK5K6.3
SL13_DP_62: SLOT13.C43 UNK5K7.3
SL13_DP_63: SLOT13.D43 UNK5K10.3
SL13_DP_64: SLOT13.A37 UNK5K14.3
SL13_DP_65: SLOT13.B37 UNK5K15.2
SL13_DP_66: SLOT13.C37 UNK5K17.3
SL13_DP_67: SLOT13.D37 UNK5K18.3
SL13_DP_68: SLOT13.E37 UNK5K20.3
SL13_DP_69: SLOT13.F37 UNK5K21.3
SL13_DP_70: SLOT13.A35 UNK5K22.3
SL13_DP_71: SLOT13.B35 UNK5K23.2
SL13_DP_72: SLOT13.C35 UNK5K24.2
SL13_DP_73: SLOT13.D35 UNK5K26.3
SL13_DP_74: SLOT13.E35 UNK5K28.3
SL13_DP_75: SLOT13.F35 UNK5K29.3
SL13_DP_76: SLOT13.Z35 UNK5K31.3
SL13_DP_77: SLOT13.Z33 UNK5K32.3
SL13_DP_78: SLOT13.A33 UNK5K34.3
SL13_DP_79: SLOT13.B33 UNK5K35.3
SL13_DP_80: SLOT13.C33 UNK5K37.3
SL13_DP_81: SLOT13.D33 UNK5K39.3
SL13_DP_82: SLOT13.E33 UNK5K40.3
SL13_DP_83: SLOT13.F33 UNK5K41.3
SL13_DP_84: SLOT13.A31 UNK5K42.3
SL13_DP_85: SLOT13.B31 UNK5K43.3
SL13_DP_86: SLOT13.C31 UNK5K45.3
SL13_DP_87: SLOT13.D31 UNK5K46.3
SL13_DP_88: SLOT13.E31 UNK5K48.3
SL13_DP_89: SLOT13.F31 UNK5K50.3
SL13_DP_90: SLOT13.Z31 UNK7K4.3
SL13_DP_91: SLOT13.Z29 UNK7K6.3
SL13_DP_92: SLOT13.A29 UNK7K7.3
SL13_DP_93: SLOT13.B29 UNK7K10.3
SL13_DP_94: SLOT13.C29 UNK7K14.3
SL13_DP_95: SLOT13.D29 UNK7K15.2
SL13_DP_96: SLOT13.E29 UNK7K17.3
SL13_DP_97: SLOT13.F29 UNK7K18.3
SL13_DP_98: SLOT13.A27 UNK7K20.3
SL13_DP_99: SLOT13.B27 UNK7K21.3
SL13_DP_100: SLOT13.C27 UNK7K22.3
SL13_DP_101: SLOT13.D27 UNK7K23.2
SL13_DP_102: SLOT13.E27 UNK7K24.2
SL13_DP_103: SLOT13.F27 UNK7K26.3
SL13_DP_104: SLOT13.Z27 UNK7K28.3
SL13_DP_105: SLOT13.Z25 UNK7K29.3
SL13_DP_106: SLOT13.A25 UNK7K31.3
SL13_DP_107: SLOT13.B25 UNK7K32.3
SL13_DP_108: SLOT13.C25 UNK7K34.3
SL13_DP_109: SLOT13.D25 UNK7K35.3
SL13_DP_110: SLOT13.E25 UNK7K37.3
SL13_DP_111: SLOT13.F25 UNK7K39.3
SL13_DP_112: SLOT13.A23 UNK7K40.3
SL13_DP_113: SLOT13.B23 UNK7K41.3
SL13_DP_114: SLOT13.C23 UNK7K42.3
SL13_DP_115: SLOT13.D23 UNK7K43.3
SL13_DP_116: SLOT13.E23 UNK7K45.3
SL13_DP_117: SLOT13.F23 UNK7K46.3
SL13_DP_118: SLOT13.Z23 UNK7K48.3
SL13_DP_119: SLOT13.Z21 UNK7K50.3
SL13_DP_120: SLOT13.A21
SL13_DP_121: SLOT13.B21 TP_OUT+_1.1(TP) U1.1(OUT+)
SL13_DP_122: SLOT13.C21 TP_OUT-_1.1(TP) U1.6(OUT-)
SL13_DP_123: SLOT13.D21 TP_OUT+_2.1(TP) U2.1(OUT+)
SL13_DP_124: SLOT13.E21 TP_OUT-_2.1(TP) U2.6(OUT-)
SL13_DP_125: R15.1 SLOT13.F21 U3.2(ENABLE)
SL13_DP_126: R17.1 SLOT13.B19 U4.2(ENABLE)
SL13_DP_127: SLOT13.C19 UNK3TP_OUT+_1.1 UNK3U1.1
SL13_DP_128: SLOT13.E43 UNK3TP_OUT-_1.1 UNK3U1.6
SL13_DP_129: SLOT13.F43 UNK3TP_OUT+_2.1 UNK3U2.1
SL13_DP_130: SLOT13.A41 UNK3TP_OUT-_2.1 UNK3U2.6
SL13_DP_131: SLOT13.B41 UNK3R15.1 UNK3U3.2
SL13_DP_132: SLOT13.C41 UNK3R17.1 UNK3U4.2
SL13_DP_133: SLOT13.D41 UNK5TP_OUT+_1.1 UNK5U1.1
SL13_DP_134: SLOT13.E41 UNK5TP_OUT-_1.1 UNK5U1.6
SL13_DP_135: SLOT13.F41 UNK5TP_OUT+_2.1 UNK5U2.1
SL13_DP_136: SLOT13.Z41 UNK5TP_OUT-_2.1 UNK5U2.6
SL13_DP_137: SLOT13.Z39 UNK5R15.1 UNK5U3.2
SL13_DP_138: SLOT13.A39 UNK5R17.1 UNK5U4.2
SL13_DP_139: SLOT13.B39 UNK7TP_OUT+_1.1 UNK7U1.1
SL13_DP_140: SLOT13.C39 UNK7TP_OUT-_1.1 UNK7U1.6
SL13_DP_141: SLOT13.D39 UNK7TP_OUT+_2.1 UNK7U2.1
SL13_DP_142: SLOT13.E39 UNK7TP_OUT-_2.1 UNK7U2.6
SL13_DP_143: SLOT13.F39 UNK7R15.1 UNK7U3.2
SL13_DP_144: SLOT13.A17 UNK7R17.1 UNK7U4.2
SL13_DP_145: SLOT13.B17
SL13_DP_146: SLOT13.C17
SL13_DP_147: SLOT13.D17
SL13_DP_148: SLOT13.E17
SL13_DP_149: SLOT13.F17
SL13_DP_150: SLOT13.A15
SL13_DP_151: SLOT13.B15
SL13_DP_152: SLOT13.C15
SL13_DP_153: SLOT13.D15
SL13_DP_154: SLOT13.E15
SL13_DP_155: SLOT13.F15
SL13_DP_156: SLOT13.Z15
SL13_DP_157: SLOT13.Z13
SL13_DP_158: SLOT13.A13
SL13_DP_159: SLOT13.B13
SL13_DP_160: SLOT13.C13
SL13_DP_161: SLOT13.D13
SL13_DP_162: SLOT13.E13
SL13_DP_163: SLOT13.F13
SL13_DP_164: SLOT13.A11
SL13_DP_165: SLOT13.B11
SL13_DP_166: SLOT13.C11
SL13_DP_167: SLOT13.D11
SL13_DP_168: SLOT13.E11
SL13_DP_169: SLOT13.F11
SL13_DP_170: SLOT13.Z11
SL13_DP_171: SLOT13.Z9
SL13_DP_172: SLOT13.A9
SL13_DP_173: SLOT13.B9
SL13_DP_174: SLOT13.C9
SL13_DP_175: SLOT13.D9
SL13_DP_176: SLOT13.E9
SL13_DP_177: SLOT13.F9
SL13_DP_178: SLOT13.A7
SL13_DP_179: SLOT13.B7
SL13_DP_180: SLOT13.C7
SL13_DP_181: SLOT13.D7
SL13_DP_182: SLOT13.E7
SL13_DP_183: SLOT13.F7
SL13_DP_184: SLOT13.Z7
SL13_DP_185: SLOT13.Z5
SL13_DP_186: SLOT13.A5
SL13_DP_187: SLOT13.B5
SL13_DP_188: SLOT13.C5
SL13_DP_189: SLOT13.D5
SL13_DP_190: SLOT13.E5
SL13_DP_191: SLOT13.F5
SL13_GND_SENSE: SLOT13.F19 ST2.2
SL14_PMVI_1_BP: SLOT14.B35
SL14_PMVI_1_HF: SLOT14.F35 UNK2K15.4
SL14_PMVI_1_HS: SLOT14.C35 UNK2K15.5
SL14_PMVI_1_LS: SLOT14.A35 UNK2SH17.1
SL14_PMVI_2_BP: SLOT14.B33
SL14_PMVI_2_HF: SLOT14.F33 UNK4K15.4
SL14_PMVI_2_HS: SLOT14.C33 UNK4K15.5
SL14_PMVI_2_LS: SLOT14.A33 UNK4SH17.1
SL14_PMVI_3_BP: SLOT14.B31
SL14_PMVI_3_HF: SLOT14.F31 UNK6K15.4
SL14_PMVI_3_HS: SLOT14.C31 UNK6K15.5
SL14_PMVI_3_LS: SLOT14.A31 UNK6SH17.1
SL14_PMVI_4_BP: SLOT14.B29
SL14_PMVI_4_HF: SLOT14.F29 UNK8K15.4
SL14_PMVI_4_HS: SLOT14.C29 UNK8K15.5
SL14_PMVI_4_LS: SLOT14.A29 UNK8SH17.1
SL14_PMVI_5_BP: SLOT14.B27
SL14_PMVI_5_HF: SLOT14.F27
SL14_PMVI_5_HS: SLOT14.C27
SL14_PMVI_5_LS: SLOT14.A27
SL14_PMVI_6_BP: SLOT14.B25
SL14_PMVI_6_HF: SLOT14.F25
SL14_PMVI_6_HS: SLOT14.C25
SL14_PMVI_6_LS: SLOT14.A25
SL14_PMVI_7_BP: SLOT14.B23
SL14_PMVI_7_HF: SLOT14.F23
SL14_PMVI_7_HS: SLOT14.C23
SL14_PMVI_7_LS: SLOT14.A23
SL14_PMVI_8_BP: SLOT14.B21
SL14_PMVI_8_HF: SLOT14.F21
SL14_PMVI_8_HS: SLOT14.C21
SL14_PMVI_8_LS: SLOT14.A21
SL14_PMVI_9_BP: SLOT14.D37
SL14_PMVI_9_HF: SLOT14.F37
SL14_PMVI_9_HS: SLOT14.E37
SL14_PMVI_9_LS: SLOT14.C37
SL14_PMVI_10_BP: SLOT14.D33
SL14_PMVI_10_HF: SLOT14.E35 UNK2R7.1 UNK2SHORT3.1
SL14_PMVI_10_HS: SLOT14.E33 UNK2SHORT3.2
SL14_PMVI_10_LS: SLOT14.B37 UNK2SH18.1
SL14_PMVI_11_BP: SLOT14.D29
SL14_PMVI_11_HF: SLOT14.E31 UNK2R8.1 UNK2SHORT4.1
SL14_PMVI_11_HS: SLOT14.E29 UNK2SHORT4.2
SL14_PMVI_11_LS: SLOT14.A37 UNK2SH19.1
SL14_PMVI_12_BP: SLOT14.D25
SL14_PMVI_12_HF: SLOT14.E27 UNK2SHORT1.1 UNK2TP_IN-_1.1 UNK2U1.4
SL14_PMVI_12_HS: SLOT14.E25 UNK2SHORT1.2
SL14_PMVI_12_LS: SLOT14.B19 UNK2SH20.1
SL14_PMVI_13_BP: SLOT14.D21
SL14_PMVI_13_HF: SLOT14.E23 UNK2SHORT2.1 UNK2TP_IN-_2.1 UNK2U2.4
SL14_PMVI_13_HS: SLOT14.E21 UNK2SHORT2.2
SL14_PMVI_13_LS: SLOT14.A19 UNK2SH21.1
SL14_PMVI_14_BP: SLOT14.D19
SL14_PMVI_14_HF: SLOT14.F19 UNK2SHORT9.1 UNK2TP_OUT_1.1 UNK2U3.5
SL14_PMVI_14_HS: SLOT14.E19 UNK2SHORT9.2
SL14_PMVI_14_LS: SLOT14.C19 UNK2SH22.1
SL14_PMVI_15_BP: SLOT14.D17
SL14_PMVI_15_HF: SLOT14.F17 UNK2C72.1 UNK2R15.2 UNK2SHORT6.2 UNK2U3.1
SL14_PMVI_15_HS: SLOT14.E17 UNK2SHORT6.1
SL14_PMVI_15_LS: SLOT14.A17 UNK2SH23.1
SL14_PMVI_16_BP: SLOT14.C17
SL14_PMVI_16_HF: SLOT14.E15 UNK2SHORT11.2 UNK2TP_REF_1.1 UNK2U3.3
SL14_PMVI_16_HS: SLOT14.D15 UNK2SHORT11.1
SL14_PMVI_16_LS: SLOT14.B17 UNK2SH24.1
SL14_PMVI_17_BP: SLOT14.B15
SL14_PMVI_17_HF: SLOT14.F15 UNK2SHORT10.1 UNK2TP_OUT_2.1 UNK2U4.5
SL14_PMVI_17_HS: SLOT14.C15 UNK2SHORT10.2
SL14_PMVI_17_LS: SLOT14.A15 UNK2SH25.1
SL14_PMVI_18_BP: SLOT14.D13
SL14_PMVI_18_HF: SLOT14.F13 UNK2C73.1 UNK2R17.2 UNK2SHORT7.2 UNK2U4.1
SL14_PMVI_18_HS: SLOT14.E13 UNK2SHORT7.1
SL14_PMVI_18_LS: SLOT14.A13 UNK2SH26.1
SL14_PMVI_19_BP: SLOT14.D11
SL14_PMVI_19_HF: SLOT14.F11 UNK2SHORT8.2 UNK2TP_REF_2.1 UNK2U4.3
SL14_PMVI_19_HS: SLOT14.E11 UNK2SHORT8.1
SL14_PMVI_19_LS: SLOT14.B13 UNK2SH27.1
SL14_PMVI_20_BP: SLOT14.C11
SL14_PMVI_20_HF: SLOT14.E9 UNK4R7.1 UNK4SHORT3.1
SL14_PMVI_20_HS: SLOT14.D9 UNK4SHORT3.2
SL14_PMVI_20_LS: SLOT14.C13 UNK4SH18.1
SL14_PMVI_21_BP: SLOT14.B9
SL14_PMVI_21_HF: SLOT14.F9 UNK4R8.1 UNK4SHORT4.1
SL14_PMVI_21_HS: SLOT14.C9 UNK4SHORT4.2
SL14_PMVI_21_LS: SLOT14.B11 UNK4SH19.1
SL14_PMVI_22_BP: SLOT14.D7
SL14_PMVI_22_HF: SLOT14.F7 UNK4SHORT1.1 UNK4TP_IN-_1.1 UNK4U1.4
SL14_PMVI_22_HS: SLOT14.E7 UNK4SHORT1.2
SL14_PMVI_22_LS: SLOT14.A11 UNK4SH20.1
SL14_PMVI_23_BP: SLOT14.D5
SL14_PMVI_23_HF: SLOT14.F5 UNK4SHORT2.1 UNK4TP_IN-_2.1 UNK4U2.4
SL14_PMVI_23_HS: SLOT14.E5 UNK4SHORT2.2
SL14_PMVI_23_LS: SLOT14.A9 UNK4SH21.1
SL14_PMVI_24_BP: SLOT14.D3
SL14_PMVI_24_HF: SLOT14.F3 UNK4SHORT9.1 UNK4TP_OUT_1.1 UNK4U3.5
SL14_PMVI_24_HS: SLOT14.E3 UNK4SHORT9.2
SL14_PMVI_24_LS: SLOT14.A7 UNK4SH22.1
SL14_PMVI_25_BP: SLOT14.D1
SL14_PMVI_25_HF: SLOT14.F1 UNK4C72.1 UNK4R15.2 UNK4SHORT6.2 UNK4U3.1
SL14_PMVI_25_HS: SLOT14.E1 UNK4SHORT6.1
SL14_PMVI_25_LS: SLOT14.B7 UNK4SH23.1
SL14_PMVI_26_BP: SLOT14.C3
SL14_PMVI_26_HF: SLOT14.G4 UNK4SHORT11.2 UNK4TP_REF_1.1 UNK4U3.3
SL14_PMVI_26_HS: SLOT14.C1 UNK4SHORT11.1
SL14_PMVI_26_LS: SLOT14.C7 UNK4SH24.1
SL14_PMVI_27_BP: SLOT14.D2
SL14_PMVI_27_HF: SLOT14.F2 UNK4SHORT10.1 UNK4TP_OUT_2.1 UNK4U4.5
SL14_PMVI_27_HS: SLOT14.C4 UNK4SHORT10.2
SL14_PMVI_27_LS: SLOT14.C5 UNK4SH25.1
SL14_PMVI_28_BP: SLOT14.B3
SL14_PMVI_28_HF: SLOT14.A4 UNK4C73.1 UNK4R17.2 UNK4SHORT7.2 UNK4U4.1
SL14_PMVI_28_HS: SLOT14.B1 UNK4SHORT7.1
SL14_PMVI_28_LS: SLOT14.B5 UNK4SH26.1
SL14_PMVI_29_BP: SLOT14.A3
SL14_PMVI_29_HF: SLOT14.B2 UNK4SHORT8.2 UNK4TP_REF_2.1 UNK4U4.3
SL14_PMVI_29_HS: SLOT14.A1 UNK4SHORT8.1
SL14_PMVI_29_LS: SLOT14.A5 UNK4SH27.1
SL14_PMVI_30_BP: SLOT14.A60
SL14_PMVI_30_HF: SLOT14.B62 UNK6R7.1 UNK6SHORT3.1
SL14_PMVI_30_HS: SLOT14.A61 UNK6SHORT3.2
SL14_PMVI_30_LS: SLOT14.B58 UNK6SH18.1
SL14_PMVI_31_BP: SLOT14.A59
SL14_PMVI_31_HF: SLOT14.C62 UNK6R8.1 UNK6SHORT4.1
SL14_PMVI_31_HS: SLOT14.B61 UNK6SHORT4.2
SL14_PMVI_31_LS: SLOT14.A57 UNK6SH19.1
SL14_PMVI_32_BP: SLOT14.E60
SL14_PMVI_32_HF: SLOT14.F62 UNK6SHORT1.1 UNK6TP_IN-_1.1 UNK6U1.4
SL14_PMVI_32_HS: SLOT14.F61 UNK6SHORT1.2
SL14_PMVI_32_LS: SLOT14.C60 UNK6SH20.1
SL14_PMVI_33_BP: SLOT14.D61
SL14_PMVI_33_HF: SLOT14.E62 UNK6SHORT2.1 UNK6TP_IN-_2.1 UNK6U2.4
SL14_PMVI_33_HS: SLOT14.E61 UNK6SHORT2.2
SL14_PMVI_33_LS: SLOT14.C61 UNK6SH21.1
SL14_PMVI_34_BP: SLOT14.C59
SL14_PMVI_34_HF: SLOT14.F59 UNK6SHORT9.1 UNK6TP_OUT_1.1 UNK6U3.5
SL14_PMVI_34_HS: SLOT14.D59 UNK6SHORT9.2
SL14_PMVI_34_LS: SLOT14.B59 UNK6SH22.1
SL14_PMVI_35_BP: SLOT14.F58
SL14_PMVI_35_HF: SLOT14.G60 UNK6C72.1 UNK6R15.2 UNK6SHORT6.2 UNK6U3.1
SL14_PMVI_35_HS: SLOT14.E59 UNK6SHORT6.1
SL14_PMVI_35_LS: SLOT14.D58 UNK6SH23.1
SL14_PMVI_36_BP: SLOT14.C57
SL14_PMVI_36_HF: SLOT14.E57 UNK6SHORT11.2 UNK6TP_REF_1.1 UNK6U3.3
SL14_PMVI_36_HS: SLOT14.D57 UNK6SHORT11.1
SL14_PMVI_36_LS: SLOT14.B57 UNK6SH24.1
SL14_PMVI_37_BP: SLOT14.E56
SL14_PMVI_37_HF: SLOT14.F57 UNK6SHORT10.1 UNK6TP_OUT_2.1 UNK6U4.5
SL14_PMVI_37_HS: SLOT14.G56 UNK6SHORT10.2
SL14_PMVI_37_LS: SLOT14.C56 UNK6SH25.1
SL14_PMVI_38_BP: SLOT14.D55
SL14_PMVI_38_HF: SLOT14.F55 UNK6C73.1 UNK6R17.2 UNK6SHORT7.2 UNK6U4.1
SL14_PMVI_38_HS: SLOT14.E55 UNK6SHORT7.1
SL14_PMVI_38_LS: SLOT14.B55 UNK6SH26.1
SL14_PMVI_39_BP: SLOT14.B54
SL14_PMVI_39_HF: SLOT14.E52 UNK6SHORT8.2 UNK6TP_REF_2.1 UNK6U4.3
SL14_PMVI_39_HS: SLOT14.C55 UNK6SHORT8.1
SL14_PMVI_39_LS: SLOT14.A55 UNK6SH27.1
SL14_PMVI_40_BP: SLOT14.D54
SL14_PMVI_40_HF: SLOT14.G52 UNK8R7.1 UNK8SHORT3.1
SL14_PMVI_40_HS: SLOT14.F54 UNK8SHORT3.2
SL14_PMVI_40_LS: SLOT14.A56 UNK8SH18.1
SL14_PMVI_41_BP: SLOT14.B53
SL14_PMVI_41_HF: SLOT14.F53 UNK8R8.1 UNK8SHORT4.1
SL14_PMVI_41_HS: SLOT14.C53 UNK8SHORT4.2
SL14_PMVI_41_LS: SLOT14.A53 UNK8SH19.1
SL14_PMVI_42_BP: SLOT14.D53
SL14_PMVI_42_HF: SLOT14.F51 UNK8SHORT1.1 UNK8TP_IN-_1.1 UNK8U1.4
SL14_PMVI_42_HS: SLOT14.E53 UNK8SHORT1.2
SL14_PMVI_42_LS: SLOT14.A52 UNK8SH20.1
SL14_PMVI_43_BP: SLOT14.C51
SL14_PMVI_43_HF: SLOT14.E51 UNK8SHORT2.1 UNK8TP_IN-_2.1 UNK8U2.4
SL14_PMVI_43_HS: SLOT14.D51 UNK8SHORT2.2
SL14_PMVI_43_LS: SLOT14.C52 UNK8SH21.1
SL14_PMVI_44_BP: SLOT14.D50
SL14_PMVI_44_HF: SLOT14.F49 UNK8SHORT9.1 UNK8TP_OUT_1.1 UNK8U3.5
SL14_PMVI_44_HS: SLOT14.F50 UNK8SHORT9.2
SL14_PMVI_44_LS: SLOT14.A51 UNK8SH22.1
SL14_PMVI_45_BP: SLOT14.B50
SL14_PMVI_45_HF: SLOT14.E49 UNK8C72.1 UNK8R15.2 UNK8SHORT6.2 UNK8U3.1
SL14_PMVI_45_HS: SLOT14.D49 UNK8SHORT6.1
SL14_PMVI_45_LS: SLOT14.B51 UNK8SH23.1
SL14_PMVI_46_BP: SLOT14.B49
SL14_PMVI_46_HF: SLOT14.G48 UNK8SHORT11.2 UNK8TP_REF_1.1 UNK8U3.3
SL14_PMVI_46_HS: SLOT14.C49 UNK8SHORT11.1
SL14_PMVI_46_LS: SLOT14.A49 UNK8SH24.1
SL14_PMVI_47_BP: SLOT14.D47
SL14_PMVI_47_HF: SLOT14.F47 UNK8SHORT10.1 UNK8TP_OUT_2.1 UNK8U4.5
SL14_PMVI_47_HS: SLOT14.E47 UNK8SHORT10.2
SL14_PMVI_47_LS: SLOT14.A48 UNK8SH25.1
SL14_PMVI_48_BP: SLOT14.C45
SL14_PMVI_48_HF: SLOT14.F45 UNK8C73.1 UNK8R17.2 UNK8SHORT7.2 UNK8U4.1
SL14_PMVI_48_HS: SLOT14.D46 UNK8SHORT7.1
SL14_PMVI_48_LS: SLOT14.C48 UNK8SH26.1
SL14_PMVI_49_BP: SLOT14.C47
SL14_PMVI_49_HF: SLOT14.F46 UNK8SHORT8.2 UNK8TP_REF_2.1 UNK8U4.3
SL14_PMVI_49_HS: SLOT14.E45 UNK8SHORT8.1
SL14_PMVI_49_LS: SLOT14.E48 UNK8SH27.1
SL14_PMVI_50_BP: SLOT14.B46
SL14_PMVI_50_HF: SLOT14.G44
SL14_PMVI_50_HS: SLOT14.B45
SL14_PMVI_50_LS: SLOT14.B47
SL14_PMVI_51_BP: SLOT14.D45
SL14_PMVI_51_HF: SLOT14.F41
SL14_PMVI_51_HS: SLOT14.E43
SL14_PMVI_51_LS: SLOT14.A47
SL14_PMVI_52_BP: SLOT14.D43
SL14_PMVI_52_HF: SLOT14.F43
SL14_PMVI_52_HS: SLOT14.F42
SL14_PMVI_52_LS: SLOT14.A45
SL14_PMVI_53_BP: SLOT14.D42
SL14_PMVI_53_HF: SLOT14.G40
SL14_PMVI_53_HS: SLOT14.E41
SL14_PMVI_53_LS: SLOT14.A44
SL14_PMVI_54_BP: SLOT14.C41
SL14_PMVI_54_HF: SLOT14.F39
SL14_PMVI_54_HS: SLOT14.D41
SL14_PMVI_54_LS: SLOT14.C44
SL14_PMVI_55_BP: SLOT14.B41
SL14_PMVI_55_HF: SLOT14.F38
SL14_PMVI_55_HS: SLOT14.B39
SL14_PMVI_55_LS: SLOT14.E44
SL14_PMVI_56_BP: SLOT14.C39
SL14_PMVI_56_HF: SLOT14.E39
SL14_PMVI_56_HS: SLOT14.D39
SL14_PMVI_56_LS: SLOT14.C43
SL14_PMVI_57_BP: SLOT14.A41
SL14_PMVI_57_HF: SLOT14.E40
SL14_PMVI_57_HS: SLOT14.A39
SL14_PMVI_57_LS: SLOT14.B43
SL14_PMVI_58_BP: SLOT14.B42
SL14_PMVI_58_HF: SLOT14.C40
SL14_PMVI_58_HS: SLOT14.A40
SL14_PMVI_58_LS: SLOT14.A43
SL14_PMVI_59_BP: SLOT14.C36
SL14_PMVI_59_HF: SLOT14.G36
SL14_PMVI_59_HS: SLOT14.E36
SL14_PMVI_59_LS: SLOT14.D38
SL14_PMVI_60_BP: SLOT14.D34
SL14_PMVI_60_HF: SLOT14.G32
SL14_PMVI_60_HS: SLOT14.E32
SL14_PMVI_60_LS: SLOT14.B38
SL14_PMVI_61_BP: SLOT14.E24
SL14_PMVI_61_HF: SLOT14.E28
SL14_PMVI_61_HS: SLOT14.F26
SL14_PMVI_61_LS: SLOT14.A36
SL14_PMVI_62_BP: SLOT14.F18
SL14_PMVI_62_HF: SLOT14.G20
SL14_PMVI_62_HS: SLOT14.E16
SL14_PMVI_62_LS: SLOT14.B10
SL14_PMVI_63_BP: SLOT14.E12
SL14_PMVI_63_HF: SLOT14.F14
SL14_PMVI_63_HS: SLOT14.D10
SL14_PMVI_63_LS: SLOT14.A8
SL14_PMVI_64_BP: SLOT14.E8
SL14_PMVI_64_HF: SLOT14.G8
SL14_PMVI_64_HS: SLOT14.F6
SL14_PMVI_64_LS: SLOT14.C8
SL14_PMVI_65_BP: SLOT14.B34
SL14_PMVI_65_HF: SLOT14.F34
SL14_PMVI_65_HS: SLOT14.C32
SL14_PMVI_65_LS: SLOT14.A32
SL14_PMVI_66_BP: SLOT14.D30
SL14_PMVI_66_HF: SLOT14.F30
SL14_PMVI_66_HS: SLOT14.C28
SL14_PMVI_66_LS: SLOT14.B30
SL14_PMVI_67_BP: SLOT14.B26
SL14_PMVI_67_HF: SLOT14.G28
SL14_PMVI_67_HS: SLOT14.D26
SL14_PMVI_67_LS: SLOT14.A28
SL14_PMVI_68_BP: SLOT14.C24
SL14_PMVI_68_HF: SLOT14.G24
SL14_PMVI_68_HS: SLOT14.B22
SL14_PMVI_68_LS: SLOT14.A24
SL14_PMVI_69_BP: SLOT14.C20
SL14_PMVI_69_HF: SLOT14.F22
SL14_PMVI_69_HS: SLOT14.D22
SL14_PMVI_69_LS: SLOT14.A20
SL14_PMVI_70_BP: SLOT14.D18
SL14_PMVI_70_HF: SLOT14.G16
SL14_PMVI_70_HS: SLOT14.E20
SL14_PMVI_70_LS: SLOT14.B18
SL14_PMVI_71_BP: SLOT14.C16
SL14_PMVI_71_HF: SLOT14.G12
SL14_PMVI_71_HS: SLOT14.B14
SL14_PMVI_71_LS: SLOT14.A16
SL14_PMVI_72_BP: SLOT14.C12
SL14_PMVI_72_HF: SLOT14.F10
SL14_PMVI_72_HS: SLOT14.D14
SL14_PMVI_72_LS: SLOT14.A12
SL17_VI100_1_A_HF: SLOT17.D35(1_A_HF) UNK5K1.2
SL17_VI100_1_A_HG: SLOT17.B35(1_A_HG)
SL17_VI100_1_A_HS: SLOT17.C35(1_A_HS) UNK5K1.7
SL17_VI100_1_B_HG: SLOT17.C59(1_B_HG)
SL17_VI100_1_LS: SLOT17.A35(1_LS) UNK5SH1.1
SL17_VI100_2_A_HF: SITE5.2_F(SRS_F) SLOT17.D33(2_A_HF) UNK5C49.2 UNK5K5.4 UNK5TP_SRS_F.1
SL17_VI100_2_A_HG: SLOT17.B33(2_A_HG)
SL17_VI100_2_A_HS: SITE5.2_S(SRS_S) SLOT17.C33(2_A_HS) UNK5K6.4 UNK5TP_SRS_S.1
SL17_VI100_2_B_HF: SITE5.29_F(VDD1_F) SLOT17.E33(2_B_HF) UNK5K44.4
SL17_VI100_2_B_HG: SLOT17.C57(2_B_HG)
SL17_VI100_2_B_HS: SITE5.29_S(VDD1_S) SLOT17.C58(2_B_HS) UNK5K45.4 UNK5TP_VDD1_S.1
SL17_VI100_2_LS: SLOT17.A33(2_LS) UNK5SH2.1
SL17_VI100_3_A_HF: SITE5.5_F(VSR_F) SLOT17.D31(3_A_HF) UNK5K8.4 UNK5K9.4 UNK5TP_VSR_F.1
SL17_VI100_3_A_HG: SLOT17.B31(3_A_HG)
SL17_VI100_3_A_HS: SITE5.5_S(VSR_S) SLOT17.C31(3_A_HS) UNK5K10.4 UNK5TP_VSR_S.1
SL17_VI100_3_B_HG: SLOT17.C55(3_B_HG)
SL17_VI100_3_B_HS: SITE5.10_S(IS2N_S) SLOT17.C56(3_B_HS) UNK5K18.4 UNK5TP_IS2N_S.1
SL17_VI100_3_LS: SLOT17.A31(3_LS) UNK5SH3.1
SL17_VI100_4_A_HG: SLOT17.B29(4_A_HG)
SL17_VI100_4_A_HS: SITE5.4_S(SRG_S) SLOT17.C29(4_A_HS) UNK5K7.4 UNK5TP_SRG_S.1
SL17_VI100_4_B_HG: SLOT17.C53(4_B_HG)
SL17_VI100_4_B_HS: SITE5.17_S(C1B_S) SLOT17.C54(4_B_HS) UNK5K28.4 UNK5TP_C1B_S.1
SL17_VI100_4_LS: SLOT17.A29(4_LS) UNK5SH4.1
SL17_VI100_5_A_HF: SITE5.6_F(VCC_F) SLOT17.D27(5_A_HF) UNK5K11.4 UNK5K12.4 UNK5K13.4 UNK5TP_VCC_F.1
SL17_VI100_5_A_HG: SLOT17.B27(5_A_HG)
SL17_VI100_5_A_HS: SITE5.6_S(VCC_S) SLOT17.C27(5_A_HS) UNK5TP_VCC_S.1
SL17_VI100_5_B_HF: SLOT17.E27(5_B_HF)
SL17_VI100_5_B_HG: SLOT17.C51(5_B_HG)
SL17_VI100_5_B_HS: SLOT17.C52(5_B_HS)
SL17_VI100_5_LS: SLOT17.A27(5_LS) UNK5SH5.1
SL17_VI100_6_A_HF: SITE5.7_F(OPTO_F) SLOT17.D25(6_A_HF) UNK5TP_OPTO_F.1
SL17_VI100_6_A_HG: SLOT17.B25(6_A_HG)
SL17_VI100_6_A_HS: SITE5.7_S(OPTO_S) SLOT17.C25(6_A_HS) UNK5K14.4 UNK5TP_OPTO_S.1
SL17_VI100_6_B_HF: SITE5.30_F(GB2_F) SLOT17.E25(6_B_HF)
SL17_VI100_6_B_HG: SLOT17.C49(6_B_HG)
SL17_VI100_6_B_HS: SITE5.30_S(GB2_S) SLOT17.C50(6_B_HS) UNK5K46.4 UNK5TP_GB2_S.1
SL17_VI100_6_LS: SLOT17.A25(6_LS) UNK5SH6.1
SL17_VI100_7_A_HF: SITE5.13_F(STB_F) SLOT17.D23(7_A_HF) UNK5TP_STB_F.1
SL17_VI100_7_A_HG: SLOT17.B23(7_A_HG)
SL17_VI100_7_A_HS: SITE5.13_S(STB_S) SLOT17.C23(7_A_HS) UNK5K22.4 UNK5TP_STB_S.1
SL17_VI100_7_B_HF: SITE5.31_F(VO2_F) SLOT17.E23(7_B_HF) UNK5K47.4
SL17_VI100_7_B_HG: SLOT17.C47(7_B_HG)
SL17_VI100_7_B_HS: SITE5.31_S(VO2_S) SLOT17.C48(7_B_HS) UNK5K48.4 UNK5TP_VO2_S.1
SL17_VI100_7_LS: SLOT17.A23(7_LS) UNK5SH7.1
SL17_VI100_8_A_HF: SLOT17.D21(8_A_HF) UNK5K23.4
SL17_VI100_8_A_HG: SLOT17.B21(8_A_HG)
SL17_VI100_8_A_HS: SLOT17.C21(8_A_HS) UNK5K23.5
SL17_VI100_8_B_HF: SITE5.20_F(C2B_F) SLOT17.E21(8_B_HF) UNK5C61.2 UNK5TP_C2B_F.1
SL17_VI100_8_B_HG: SLOT17.C45(8_B_HG)
SL17_VI100_8_B_HS: SITE5.20_S(C2B_S) SLOT17.C46(8_B_HS) UNK5K32.4 UNK5TP_C2B_S.1
SL17_VI100_8_LS: SLOT17.A21(8_LS) UNK5SH8.1
SL17_VI100_9_A_HF: SLOT17.D39(9_A_HF) UNK5K24.4
SL17_VI100_9_A_HG: SLOT17.B39(9_A_HG)
SL17_VI100_9_A_HS: SLOT17.C39(9_A_HS) UNK5K24.5
SL17_VI100_9_B_HF: SITE5.21_F(C3B_F) SLOT17.E39(9_B_HF) UNK5K33.4 UNK5TP_C3B_F.1
SL17_VI100_9_B_HG: SLOT17.C61(9_B_HG)
SL17_VI100_9_B_HS: SITE5.21_S(C3B_S) SLOT17.F37(9_B_HS) UNK5K34.4 UNK5TP_C3B_S.1
SL17_VI100_9_LS: SLOT17.A39(9_LS) UNK5SH9.1
SL17_VI100_10_A_HF: SITE5.16_F(VDD0_F) SLOT17.D17(10_A_HF) UNK5K25.4 UNK5TP_VDD0_F.1
SL17_VI100_10_A_HG: SLOT17.B17(10_A_HG)
SL17_VI100_10_A_HS: SITE5.16_S(VDD0_S) SLOT17.C17(10_A_HS) UNK5K26.4 UNK5TP_VDD0_S.1
SL17_VI100_10_B_HF: SITE5.25_F(GA2_F) SLOT17.E17(10_B_HF)
SL17_VI100_10_B_HG: SLOT17.C43(10_B_HG)
SL17_VI100_10_B_HS: SITE5.25_S(GA2_S) SLOT17.C44(10_B_HS) UNK5K40.4 UNK5TP_GA2_S.1
SL17_VI100_10_LS: SLOT17.A17(10_LS) UNK5SH10.1
SL17_VI100_11_A_HF: SITE5.18_F(C1A_F) SLOT17.D15(11_A_HF) UNK5C63.2 UNK5TP_C1A_F.1
SL17_VI100_11_A_HG: SLOT17.B15(11_A_HG)
SL17_VI100_11_A_HS: SITE5.18_S(C1A_S) SLOT17.C15(11_A_HS) UNK5K29.4 UNK5TP_C1A_S.1
SL17_VI100_11_B_HF: SITE5.26_F(GA1_F) SLOT17.E15(11_B_HF)
SL17_VI100_11_B_HG: SLOT17.C41(11_B_HG)
SL17_VI100_11_B_HS: SITE5.26_S(GA1_S) SLOT17.C42(11_B_HS) UNK5K41.4 UNK5TP_GA1_S.1
SL17_VI100_11_LS: SLOT17.A15(11_LS) UNK5SH11.1
SL17_VI100_12_A_HF: SITE5.19_F(C2A_F) SLOT17.D13(12_A_HF) UNK5K30.4 UNK5TP_C2A_F.1
SL17_VI100_12_A_HG: SLOT17.B13(12_A_HG)
SL17_VI100_12_A_HS: SITE5.19_S(C2A_S) SLOT17.C13(12_A_HS) UNK5K31.4 UNK5TP_C2A_S.1
SL17_VI100_12_B_HF: SITE5.27_F(GB1_F) SLOT17.E13(12_B_HF)
SL17_VI100_12_B_HG: SLOT17.B61(12_B_HG)
SL17_VI100_12_B_HS: SITE5.27_S(GB1_S) SLOT17.B59(12_B_HS) UNK5K42.4 UNK5TP_GB1_S.1
SL17_VI100_12_LS: SLOT17.A13(12_LS) UNK5SH12.1
SL17_VI100_13_A_HF: SITE5.22_F(C3A_F) SLOT17.D11(13_A_HF) UNK5C64.2 UNK5TP_C3A_F.1
SL17_VI100_13_A_HG: SLOT17.B11(13_A_HG)
SL17_VI100_13_A_HS: SITE5.22_S(C3A_S) SLOT17.C11(13_A_HS) UNK5K35.4 UNK5TP_C3A_S.1
SL17_VI100_13_B_HF: SITE5.32_F(VDD2_F) SLOT17.E11(13_B_HF) UNK5K49.4
SL17_VI100_13_B_HG: SLOT17.B51(13_B_HG)
SL17_VI100_13_B_HS: SITE5.32_S(VDD2_S) SLOT17.B49(13_B_HS) UNK5K50.4 UNK5TP_VDD2_S.1
SL17_VI100_13_LS: SLOT17.A11(13_LS) UNK5SH13.1
SL17_VI100_14_A_HF: SITE5.23_F(VDDI_F) SLOT17.D9(14_A_HF) UNK5K36.4 UNK5TP_VDDI_F.1
SL17_VI100_14_A_HG: SLOT17.B9(14_A_HG)
SL17_VI100_14_A_HS: SITE5.23_S(VDDI_S) SLOT17.C9(14_A_HS) UNK5K37.4 UNK5TP_VDDI_S.1
SL17_VI100_14_B_HG: SLOT17.B47(14_B_HG)
SL17_VI100_14_B_HS: SITE5.12_S(IS1N_S) SLOT17.B45(14_B_HS) UNK5K21.4 UNK5TP_IS1N_S.1
SL17_VI100_14_LS: SLOT17.A9(14_LS) UNK5SH14.1
SL17_VI100_15_A_HF: SITE5.24_F(VIN_F) SLOT17.D7(15_A_HF) UNK5K38.4 UNK5TP_VIN_F.1
SL17_VI100_15_A_HG: SLOT17.B7(15_A_HG)
SL17_VI100_15_A_HS: SITE5.24_S(VIN_S) SLOT17.C7(15_A_HS) UNK5K39.4 UNK5TP_VIN_S.1
SL17_VI100_15_B_HG: SLOT17.A41(15_B_HG)
SL17_VI100_15_B_HS: SITE5.11_S(IS1P_S) SLOT17.B19(15_B_HS) UNK5K20.4
SL17_VI100_15_LS: SLOT17.A7(15_LS) UNK5SH15.1
SL17_VI100_16_A_HF: SITE5.28_F(VO1_F) SLOT17.D5(16_A_HF)
SL17_VI100_16_A_HG: SLOT17.B5(16_A_HG)
SL17_VI100_16_A_HS: SITE5.28_S(VO1_S) SLOT17.C5(16_A_HS) UNK5K43.4 UNK5TP_VO1_S.1
SL17_VI100_16_B_HG: SLOT17.C3(16_B_HG)
SL17_VI100_16_B_HS: SITE5.9_S(IS2P_S) SLOT17.B1(16_B_HS) UNK5K17.4 UNK5TP_IS2P_S.1
SL17_VI100_16_LS: SLOT17.A5(16_LS) UNK5SH16.1
SL17_VI100_17_A_HF: SLOT17.F35(17_A_HF) UNK7K1.2
SL17_VI100_17_A_HG: SLOT17.D59(17_A_HG)
SL17_VI100_17_A_HS: SLOT17.E60(17_A_HS) UNK7K1.7
SL17_VI100_17_B_HF: SLOT17.F59(17_B_HF)
SL17_VI100_17_B_HG: SLOT17.E59(17_B_HG)
SL17_VI100_17_B_HS: SLOT17.G60(17_B_HS)
SL17_VI100_17_LS: SLOT17.D60(17_LS) UNK7SH1.1
SL17_VI100_18_A_HF: SITE7.2_F(SRS_F) SLOT17.F33(18_A_HF) UNK7C49.2 UNK7K5.4 UNK7TP_SRS_F.1
SL17_VI100_18_A_HG: SLOT17.D57(18_A_HG)
SL17_VI100_18_A_HS: SITE7.2_S(SRS_S) SLOT17.E58(18_A_HS) UNK7K6.4 UNK7TP_SRS_S.1
SL17_VI100_18_B_HF: SITE7.29_F(VDD1_F) SLOT17.F57(18_B_HF) UNK7K44.4
SL17_VI100_18_B_HG: SLOT17.E57(18_B_HG)
SL17_VI100_18_B_HS: SITE7.29_S(VDD1_S) SLOT17.G58(18_B_HS) UNK7K45.4 UNK7TP_VDD1_S.1
SL17_VI100_18_LS: SLOT17.D58(18_LS) UNK7SH2.1
SL17_VI100_19_A_HF: SITE7.5_F(VSR_F) SLOT17.F31(19_A_HF) UNK7K8.4 UNK7K9.4 UNK7TP_VSR_F.1
SL17_VI100_19_A_HG: SLOT17.D55(19_A_HG)
SL17_VI100_19_A_HS: SITE7.5_S(VSR_S) SLOT17.E56(19_A_HS) UNK7K10.4 UNK7TP_VSR_S.1
SL17_VI100_19_B_HG: SLOT17.E55(19_B_HG)
SL17_VI100_19_B_HS: SITE7.10_S(IS2N_S) SLOT17.G56(19_B_HS) UNK7K18.4 UNK7TP_IS2N_S.1
SL17_VI100_19_LS: SLOT17.D56(19_LS) UNK7SH3.1
SL17_VI100_20_A_HG: SLOT17.D53(20_A_HG)
SL17_VI100_20_A_HS: SITE7.4_S(SRG_S) SLOT17.E54(20_A_HS) UNK7K7.4 UNK7TP_SRG_S.1
SL17_VI100_20_B_HG: SLOT17.E53(20_B_HG)
SL17_VI100_20_B_HS: SITE7.17_S(C1B_S) SLOT17.G54(20_B_HS) UNK7K28.4 UNK7TP_C1B_S.1
SL17_VI100_20_LS: SLOT17.D54(20_LS) UNK7SH4.1
SL17_VI100_21_A_HF: SITE7.6_F(VCC_F) SLOT17.F27(21_A_HF) UNK7K11.4 UNK7K12.4 UNK7K13.4 UNK7TP_VCC_F.1
SL17_VI100_21_A_HG: SLOT17.D51(21_A_HG)
SL17_VI100_21_A_HS: SITE7.6_S(VCC_S) SLOT17.E52(21_A_HS) UNK7TP_VCC_S.1
SL17_VI100_21_B_HF: SLOT17.F51(21_B_HF)
SL17_VI100_21_B_HG: SLOT17.E51(21_B_HG)
SL17_VI100_21_B_HS: SLOT17.G52(21_B_HS)
SL17_VI100_21_LS: SLOT17.D52(21_LS) UNK7SH5.1
SL17_VI100_22_A_HF: SITE7.7_F(OPTO_F) SLOT17.F25(22_A_HF) UNK7TP_OPTO_F.1
SL17_VI100_22_A_HG: SLOT17.D49(22_A_HG)
SL17_VI100_22_A_HS: SITE7.7_S(OPTO_S) SLOT17.E50(22_A_HS) UNK7K14.4 UNK7TP_OPTO_S.1
SL17_VI100_22_B_HF: SITE7.30_F(GB2_F) SLOT17.F49(22_B_HF)
SL17_VI100_22_B_HG: SLOT17.E49(22_B_HG)
SL17_VI100_22_B_HS: SITE7.30_S(GB2_S) SLOT17.G50(22_B_HS) UNK7K46.4 UNK7TP_GB2_S.1
SL17_VI100_22_LS: SLOT17.D50(22_LS) UNK7SH6.1
SL17_VI100_23_A_HF: SITE7.13_F(STB_F) SLOT17.F23(23_A_HF) UNK7TP_STB_F.1
SL17_VI100_23_A_HG: SLOT17.D47(23_A_HG)
SL17_VI100_23_A_HS: SITE7.13_S(STB_S) SLOT17.E48(23_A_HS) UNK7K22.4 UNK7TP_STB_S.1
SL17_VI100_23_B_HF: SITE7.31_F(VO2_F) SLOT17.F47(23_B_HF) UNK7K47.4
SL17_VI100_23_B_HG: SLOT17.E47(23_B_HG)
SL17_VI100_23_B_HS: SITE7.31_S(VO2_S) SLOT17.G48(23_B_HS) UNK7K48.4 UNK7TP_VO2_S.1
SL17_VI100_23_LS: SLOT17.D48(23_LS) UNK7SH7.1
SL17_VI100_24_A_HF: SLOT17.F21(24_A_HF) UNK7K23.4
SL17_VI100_24_A_HG: SLOT17.D45(24_A_HG)
SL17_VI100_24_A_HS: SLOT17.E46(24_A_HS) UNK7K23.5
SL17_VI100_24_B_HF: SITE7.20_F(C2B_F) SLOT17.F45(24_B_HF) UNK7C61.2 UNK7TP_C2B_F.1
SL17_VI100_24_B_HG: SLOT17.E45(24_B_HG)
SL17_VI100_24_B_HS: SITE7.20_S(C2B_S) SLOT17.G46(24_B_HS) UNK7K32.4 UNK7TP_C2B_S.1
SL17_VI100_24_LS: SLOT17.D46(24_LS) UNK7SH8.1
SL17_VI100_25_A_HF: SLOT17.F39(25_A_HF) UNK7K24.4
SL17_VI100_25_A_HG: SLOT17.D61(25_A_HG)
SL17_VI100_25_A_HS: SLOT17.C62(25_A_HS) UNK7K24.5
SL17_VI100_25_B_HF: SITE7.21_F(C3B_F) SLOT17.F61(25_B_HF) UNK7K33.4 UNK7TP_C3B_F.1
SL17_VI100_25_B_HG: SLOT17.E61(25_B_HG)
SL17_VI100_25_B_HS: SITE7.21_S(C3B_S) SLOT17.F62(25_B_HS) UNK7K34.4 UNK7TP_C3B_S.1
SL17_VI100_25_LS: SLOT17.B62(25_LS) UNK7SH9.1
SL17_VI100_26_A_HF: SITE7.16_F(VDD0_F) SLOT17.F17(26_A_HF) UNK7K25.4 UNK7TP_VDD0_F.1
SL17_VI100_26_A_HG: SLOT17.D43(26_A_HG)
SL17_VI100_26_A_HS: SITE7.16_S(VDD0_S) SLOT17.E44(26_A_HS) UNK7K26.4 UNK7TP_VDD0_S.1
SL17_VI100_26_B_HF: SITE7.25_F(GA2_F) SLOT17.F43(26_B_HF)
SL17_VI100_26_B_HG: SLOT17.E43(26_B_HG)
SL17_VI100_26_B_HS: SITE7.25_S(GA2_S) SLOT17.G44(26_B_HS) UNK7K40.4 UNK7TP_GA2_S.1
SL17_VI100_26_LS: SLOT17.D44(26_LS) UNK7SH10.1
SL17_VI100_27_A_HF: SITE7.18_F(C1A_F) SLOT17.F15(27_A_HF) UNK7C63.2 UNK7TP_C1A_F.1
SL17_VI100_27_A_HG: SLOT17.D41(27_A_HG)
SL17_VI100_27_A_HS: SITE7.18_S(C1A_S) SLOT17.E42(27_A_HS) UNK7K29.4 UNK7TP_C1A_S.1
SL17_VI100_27_B_HF: SITE7.26_F(GA1_F) SLOT17.F41(27_B_HF)
SL17_VI100_27_B_HG: SLOT17.E41(27_B_HG)
SL17_VI100_27_B_HS: SITE7.26_S(GA1_S) SLOT17.G42(27_B_HS) UNK7K41.4 UNK7TP_GA1_S.1
SL17_VI100_27_LS: SLOT17.D42(27_LS) UNK7SH11.1
SL17_VI100_28_A_HF: SITE7.19_F(C2A_F) SLOT17.F13(28_A_HF) UNK7K30.4 UNK7TP_C2A_F.1
SL17_VI100_28_A_HG: SLOT17.A61(28_A_HG)
SL17_VI100_28_A_HS: SITE7.19_S(C2A_S) SLOT17.A60(28_A_HS) UNK7K31.4 UNK7TP_C2A_S.1
SL17_VI100_28_B_HF: SITE7.27_F(GB1_F) SLOT17.A57(28_B_HF)
SL17_VI100_28_B_HG: SLOT17.B57(28_B_HG)
SL17_VI100_28_B_HS: SITE7.27_S(GB1_S) SLOT17.A56(28_B_HS) UNK7K42.4 UNK7TP_GB1_S.1
SL17_VI100_28_LS: SLOT17.A58(28_LS) UNK7SH12.1
SL17_VI100_29_A_HF: SITE7.22_F(C3A_F) SLOT17.F11(29_A_HF) UNK7C64.2 UNK7TP_C3A_F.1
SL17_VI100_29_A_HG: SLOT17.B53(29_A_HG)
SL17_VI100_29_A_HS: SITE7.22_S(C3A_S) SLOT17.B55(29_A_HS) UNK7K35.4 UNK7TP_C3A_S.1
SL17_VI100_29_B_HF: SITE7.32_F(VDD2_F) SLOT17.A51(29_B_HF) UNK7K49.4
SL17_VI100_29_B_HG: SLOT17.A53(29_B_HG)
SL17_VI100_29_B_HS: SITE7.32_S(VDD2_S) SLOT17.A52(29_B_HS) UNK7K50.4 UNK7TP_VDD2_S.1
SL17_VI100_29_LS: SLOT17.A55(29_LS) UNK7SH13.1
SL17_VI100_30_A_HF: SITE7.23_F(VDDI_F) SLOT17.F9(30_A_HF) UNK7K36.4 UNK7TP_VDDI_F.1
SL17_VI100_30_A_HG: SLOT17.A47(30_A_HG)
SL17_VI100_30_A_HS: SITE7.23_S(VDDI_S) SLOT17.A48(30_A_HS) UNK7K37.4 UNK7TP_VDDI_S.1
SL17_VI100_30_B_HG: SLOT17.B43(30_B_HG)
SL17_VI100_30_B_HS: SITE7.12_S(IS1N_S) SLOT17.A44(30_B_HS) UNK7K21.4 UNK7TP_IS1N_S.1
SL17_VI100_30_LS: SLOT17.A46(30_LS) UNK7SH14.1
SL17_VI100_31_A_HF: SITE7.24_F(VIN_F) SLOT17.F7(31_A_HF) UNK7K38.4 UNK7TP_VIN_F.1
SL17_VI100_31_A_HG: SLOT17.B41(31_A_HG)
SL17_VI100_31_A_HS: SITE7.24_S(VIN_S) SLOT17.B3(31_A_HS) UNK7K39.4 UNK7TP_VIN_S.1
SL17_VI100_31_B_HG: SLOT17.C19(31_B_HG)
SL17_VI100_31_B_HS: SITE7.11_S(IS1P_S) SLOT17.E19(31_B_HS) UNK7K20.4
SL17_VI100_31_LS: SLOT17.A3(31_LS) UNK7SH15.1
SL17_VI100_32_A_HF: SITE7.28_F(VO1_F) SLOT17.F5(32_A_HF)
SL17_VI100_32_A_HG: SLOT17.D3(32_A_HG)
SL17_VI100_32_A_HS: SITE7.28_S(VO1_S) SLOT17.D1(32_A_HS) UNK7K43.4 UNK7TP_VO1_S.1
SL17_VI100_32_B_HG: SLOT17.E3(32_B_HG)
SL17_VI100_32_B_HS: SITE7.9_S(IS2P_S) SLOT17.F1(32_B_HS) UNK7K17.4 UNK7TP_IS2P_S.1
SL17_VI100_32_LS: SLOT17.C1(32_LS) UNK7SH16.1
SL18_VI100_1_A_HF: SLOT18.D35(1_A_HF) UNK6K1.2
SL18_VI100_1_A_HG: SLOT18.B35(1_A_HG)
SL18_VI100_1_A_HS: SLOT18.C35(1_A_HS) UNK6K1.7
SL18_VI100_1_B_HG: SLOT18.C59(1_B_HG)
SL18_VI100_1_LS: SLOT18.A35(1_LS) UNK6SH1.1
SL18_VI100_2_A_HF: SITE6.2_F(SRS_F) SLOT18.D33(2_A_HF) UNK6C49.2 UNK6K5.4 UNK6TP_SRS_F.1
SL18_VI100_2_A_HG: SLOT18.B33(2_A_HG)
SL18_VI100_2_A_HS: SITE6.2_S(SRS_S) SLOT18.C33(2_A_HS) UNK6K6.4 UNK6TP_SRS_S.1
SL18_VI100_2_B_HF: SITE6.29_F(VDD1_F) SLOT18.E33(2_B_HF) UNK6K44.4
SL18_VI100_2_B_HG: SLOT18.C57(2_B_HG)
SL18_VI100_2_B_HS: SITE6.29_S(VDD1_S) SLOT18.C58(2_B_HS) UNK6K45.4 UNK6TP_VDD1_S.1
SL18_VI100_2_LS: SLOT18.A33(2_LS) UNK6SH2.1
SL18_VI100_3_A_HF: SITE6.5_F(VSR_F) SLOT18.D31(3_A_HF) UNK6K8.4 UNK6K9.4 UNK6TP_VSR_F.1
SL18_VI100_3_A_HG: SLOT18.B31(3_A_HG)
SL18_VI100_3_A_HS: SITE6.5_S(VSR_S) SLOT18.C31(3_A_HS) UNK6K10.4 UNK6TP_VSR_S.1
SL18_VI100_3_B_HG: SLOT18.C55(3_B_HG)
SL18_VI100_3_B_HS: SITE6.10_S(IS2N_S) SLOT18.C56(3_B_HS) UNK6K18.4 UNK6TP_IS2N_S.1
SL18_VI100_3_LS: SLOT18.A31(3_LS) UNK6SH3.1
SL18_VI100_4_A_HG: SLOT18.B29(4_A_HG)
SL18_VI100_4_A_HS: SITE6.4_S(SRG_S) SLOT18.C29(4_A_HS) UNK6K7.4 UNK6TP_SRG_S.1
SL18_VI100_4_B_HG: SLOT18.C53(4_B_HG)
SL18_VI100_4_B_HS: SITE6.17_S(C1B_S) SLOT18.C54(4_B_HS) UNK6K28.4 UNK6TP_C1B_S.1
SL18_VI100_4_LS: SLOT18.A29(4_LS) UNK6SH4.1
SL18_VI100_5_A_HF: SITE6.6_F(VCC_F) SLOT18.D27(5_A_HF) UNK6K11.4 UNK6K12.4 UNK6K13.4 UNK6TP_VCC_F.1
SL18_VI100_5_A_HG: SLOT18.B27(5_A_HG)
SL18_VI100_5_A_HS: SITE6.6_S(VCC_S) SLOT18.C27(5_A_HS) UNK6TP_VCC_S.1
SL18_VI100_5_B_HF: SLOT18.E27(5_B_HF)
SL18_VI100_5_B_HG: SLOT18.C51(5_B_HG)
SL18_VI100_5_B_HS: SLOT18.C52(5_B_HS)
SL18_VI100_5_LS: SLOT18.A27(5_LS) UNK6SH5.1
SL18_VI100_6_A_HF: SITE6.7_F(OPTO_F) SLOT18.D25(6_A_HF) UNK6TP_OPTO_F.1
SL18_VI100_6_A_HG: SLOT18.B25(6_A_HG)
SL18_VI100_6_A_HS: SITE6.7_S(OPTO_S) SLOT18.C25(6_A_HS) UNK6K14.4 UNK6TP_OPTO_S.1
SL18_VI100_6_B_HF: SITE6.30_F(GB2_F) SLOT18.E25(6_B_HF)
SL18_VI100_6_B_HG: SLOT18.C49(6_B_HG)
SL18_VI100_6_B_HS: SITE6.30_S(GB2_S) SLOT18.C50(6_B_HS) UNK6K46.4 UNK6TP_GB2_S.1
SL18_VI100_6_LS: SLOT18.A25(6_LS) UNK6SH6.1
SL18_VI100_7_A_HF: SITE6.13_F(STB_F) SLOT18.D23(7_A_HF) UNK6TP_STB_F.1
SL18_VI100_7_A_HG: SLOT18.B23(7_A_HG)
SL18_VI100_7_A_HS: SITE6.13_S(STB_S) SLOT18.C23(7_A_HS) UNK6K22.4 UNK6TP_STB_S.1
SL18_VI100_7_B_HF: SITE6.31_F(VO2_F) SLOT18.E23(7_B_HF) UNK6K47.4
SL18_VI100_7_B_HG: SLOT18.C47(7_B_HG)
SL18_VI100_7_B_HS: SITE6.31_S(VO2_S) SLOT18.C48(7_B_HS) UNK6K48.4 UNK6TP_VO2_S.1
SL18_VI100_7_LS: SLOT18.A23(7_LS) UNK6SH7.1
SL18_VI100_8_A_HF: SLOT18.D21(8_A_HF) UNK6K23.4
SL18_VI100_8_A_HG: SLOT18.B21(8_A_HG)
SL18_VI100_8_A_HS: SLOT18.C21(8_A_HS) UNK6K23.5
SL18_VI100_8_B_HF: SITE6.20_F(C2B_F) SLOT18.E21(8_B_HF) UNK6C61.2 UNK6TP_C2B_F.1
SL18_VI100_8_B_HG: SLOT18.C45(8_B_HG)
SL18_VI100_8_B_HS: SITE6.20_S(C2B_S) SLOT18.C46(8_B_HS) UNK6K32.4 UNK6TP_C2B_S.1
SL18_VI100_8_LS: SLOT18.A21(8_LS) UNK6SH8.1
SL18_VI100_9_A_HF: SLOT18.D39(9_A_HF) UNK6K24.4
SL18_VI100_9_A_HG: SLOT18.B39(9_A_HG)
SL18_VI100_9_A_HS: SLOT18.C39(9_A_HS) UNK6K24.5
SL18_VI100_9_B_HF: SITE6.21_F(C3B_F) SLOT18.E39(9_B_HF) UNK6K33.4 UNK6TP_C3B_F.1
SL18_VI100_9_B_HG: SLOT18.C61(9_B_HG)
SL18_VI100_9_B_HS: SITE6.21_S(C3B_S) SLOT18.F37(9_B_HS) UNK6K34.4 UNK6TP_C3B_S.1
SL18_VI100_9_LS: SLOT18.A39(9_LS) UNK6SH9.1
SL18_VI100_10_A_HF: SITE6.16_F(VDD0_F) SLOT18.D17(10_A_HF) UNK6K25.4 UNK6TP_VDD0_F.1
SL18_VI100_10_A_HG: SLOT18.B17(10_A_HG)
SL18_VI100_10_A_HS: SITE6.16_S(VDD0_S) SLOT18.C17(10_A_HS) UNK6K26.4 UNK6TP_VDD0_S.1
SL18_VI100_10_B_HF: SITE6.25_F(GA2_F) SLOT18.E17(10_B_HF)
SL18_VI100_10_B_HG: SLOT18.C43(10_B_HG)
SL18_VI100_10_B_HS: SITE6.25_S(GA2_S) SLOT18.C44(10_B_HS) UNK6K40.4 UNK6TP_GA2_S.1
SL18_VI100_10_LS: SLOT18.A17(10_LS) UNK6SH10.1
SL18_VI100_11_A_HF: SITE6.18_F(C1A_F) SLOT18.D15(11_A_HF) UNK6C63.2 UNK6TP_C1A_F.1
SL18_VI100_11_A_HG: SLOT18.B15(11_A_HG)
SL18_VI100_11_A_HS: SITE6.18_S(C1A_S) SLOT18.C15(11_A_HS) UNK6K29.4 UNK6TP_C1A_S.1
SL18_VI100_11_B_HF: SITE6.26_F(GA1_F) SLOT18.E15(11_B_HF)
SL18_VI100_11_B_HG: SLOT18.C41(11_B_HG)
SL18_VI100_11_B_HS: SITE6.26_S(GA1_S) SLOT18.C42(11_B_HS) UNK6K41.4 UNK6TP_GA1_S.1
SL18_VI100_11_LS: SLOT18.A15(11_LS) UNK6SH11.1
SL18_VI100_12_A_HF: SITE6.19_F(C2A_F) SLOT18.D13(12_A_HF) UNK6K30.4 UNK6TP_C2A_F.1
SL18_VI100_12_A_HG: SLOT18.B13(12_A_HG)
SL18_VI100_12_A_HS: SITE6.19_S(C2A_S) SLOT18.C13(12_A_HS) UNK6K31.4 UNK6TP_C2A_S.1
SL18_VI100_12_B_HF: SITE6.27_F(GB1_F) SLOT18.E13(12_B_HF)
SL18_VI100_12_B_HG: SLOT18.B61(12_B_HG)
SL18_VI100_12_B_HS: SITE6.27_S(GB1_S) SLOT18.B59(12_B_HS) UNK6K42.4 UNK6TP_GB1_S.1
SL18_VI100_12_LS: SLOT18.A13(12_LS) UNK6SH12.1
SL18_VI100_13_A_HF: SITE6.22_F(C3A_F) SLOT18.D11(13_A_HF) UNK6C64.2 UNK6TP_C3A_F.1
SL18_VI100_13_A_HG: SLOT18.B11(13_A_HG)
SL18_VI100_13_A_HS: SITE6.22_S(C3A_S) SLOT18.C11(13_A_HS) UNK6K35.4 UNK6TP_C3A_S.1
SL18_VI100_13_B_HF: SITE6.32_F(VDD2_F) SLOT18.E11(13_B_HF) UNK6K49.4
SL18_VI100_13_B_HG: SLOT18.B51(13_B_HG)
SL18_VI100_13_B_HS: SITE6.32_S(VDD2_S) SLOT18.B49(13_B_HS) UNK6K50.4 UNK6TP_VDD2_S.1
SL18_VI100_13_LS: SLOT18.A11(13_LS) UNK6SH13.1
SL18_VI100_14_A_HF: SITE6.23_F(VDDI_F) SLOT18.D9(14_A_HF) UNK6K36.4 UNK6TP_VDDI_F.1
SL18_VI100_14_A_HG: SLOT18.B9(14_A_HG)
SL18_VI100_14_A_HS: SITE6.23_S(VDDI_S) SLOT18.C9(14_A_HS) UNK6K37.4 UNK6TP_VDDI_S.1
SL18_VI100_14_B_HG: SLOT18.B47(14_B_HG)
SL18_VI100_14_B_HS: SITE6.12_S(IS1N_S) SLOT18.B45(14_B_HS) UNK6K21.4 UNK6TP_IS1N_S.1
SL18_VI100_14_LS: SLOT18.A9(14_LS) UNK6SH14.1
SL18_VI100_15_A_HF: SITE6.24_F(VIN_F) SLOT18.D7(15_A_HF) UNK6K38.4 UNK6TP_VIN_F.1
SL18_VI100_15_A_HG: SLOT18.B7(15_A_HG)
SL18_VI100_15_A_HS: SITE6.24_S(VIN_S) SLOT18.C7(15_A_HS) UNK6K39.4 UNK6TP_VIN_S.1
SL18_VI100_15_B_HG: SLOT18.A41(15_B_HG)
SL18_VI100_15_B_HS: SITE6.11_S(IS1P_S) SLOT18.B19(15_B_HS) UNK6K20.4
SL18_VI100_15_LS: SLOT18.A7(15_LS) UNK6SH15.1
SL18_VI100_16_A_HF: SITE6.28_F(VO1_F) SLOT18.D5(16_A_HF)
SL18_VI100_16_A_HG: SLOT18.B5(16_A_HG)
SL18_VI100_16_A_HS: SITE6.28_S(VO1_S) SLOT18.C5(16_A_HS) UNK6K43.4 UNK6TP_VO1_S.1
SL18_VI100_16_B_HG: SLOT18.C3(16_B_HG)
SL18_VI100_16_B_HS: SITE6.9_S(IS2P_S) SLOT18.B1(16_B_HS) UNK6K17.4 UNK6TP_IS2P_S.1
SL18_VI100_16_LS: SLOT18.A5(16_LS) UNK6SH16.1
SL18_VI100_17_A_HF: SLOT18.F35(17_A_HF) UNK8K1.2
SL18_VI100_17_A_HG: SLOT18.D59(17_A_HG)
SL18_VI100_17_A_HS: SLOT18.E60(17_A_HS) UNK8K1.7
SL18_VI100_17_B_HF: SLOT18.F59(17_B_HF)
SL18_VI100_17_B_HG: SLOT18.E59(17_B_HG)
SL18_VI100_17_B_HS: SLOT18.G60(17_B_HS)
SL18_VI100_17_LS: SLOT18.D60(17_LS) UNK8SH1.1
SL18_VI100_18_A_HF: SITE8.2_F(SRS_F) SLOT18.F33(18_A_HF) UNK8C49.2 UNK8K5.4 UNK8TP_SRS_F.1
SL18_VI100_18_A_HG: SLOT18.D57(18_A_HG)
SL18_VI100_18_A_HS: SITE8.2_S(SRS_S) SLOT18.E58(18_A_HS) UNK8K6.4 UNK8TP_SRS_S.1
SL18_VI100_18_B_HF: SITE8.29_F(VDD1_F) SLOT18.F57(18_B_HF) UNK8K44.4
SL18_VI100_18_B_HG: SLOT18.E57(18_B_HG)
SL18_VI100_18_B_HS: SITE8.29_S(VDD1_S) SLOT18.G58(18_B_HS) UNK8K45.4 UNK8TP_VDD1_S.1
SL18_VI100_18_LS: SLOT18.D58(18_LS) UNK8SH2.1
SL18_VI100_19_A_HF: SITE8.5_F(VSR_F) SLOT18.F31(19_A_HF) UNK8K8.4 UNK8K9.4 UNK8TP_VSR_F.1
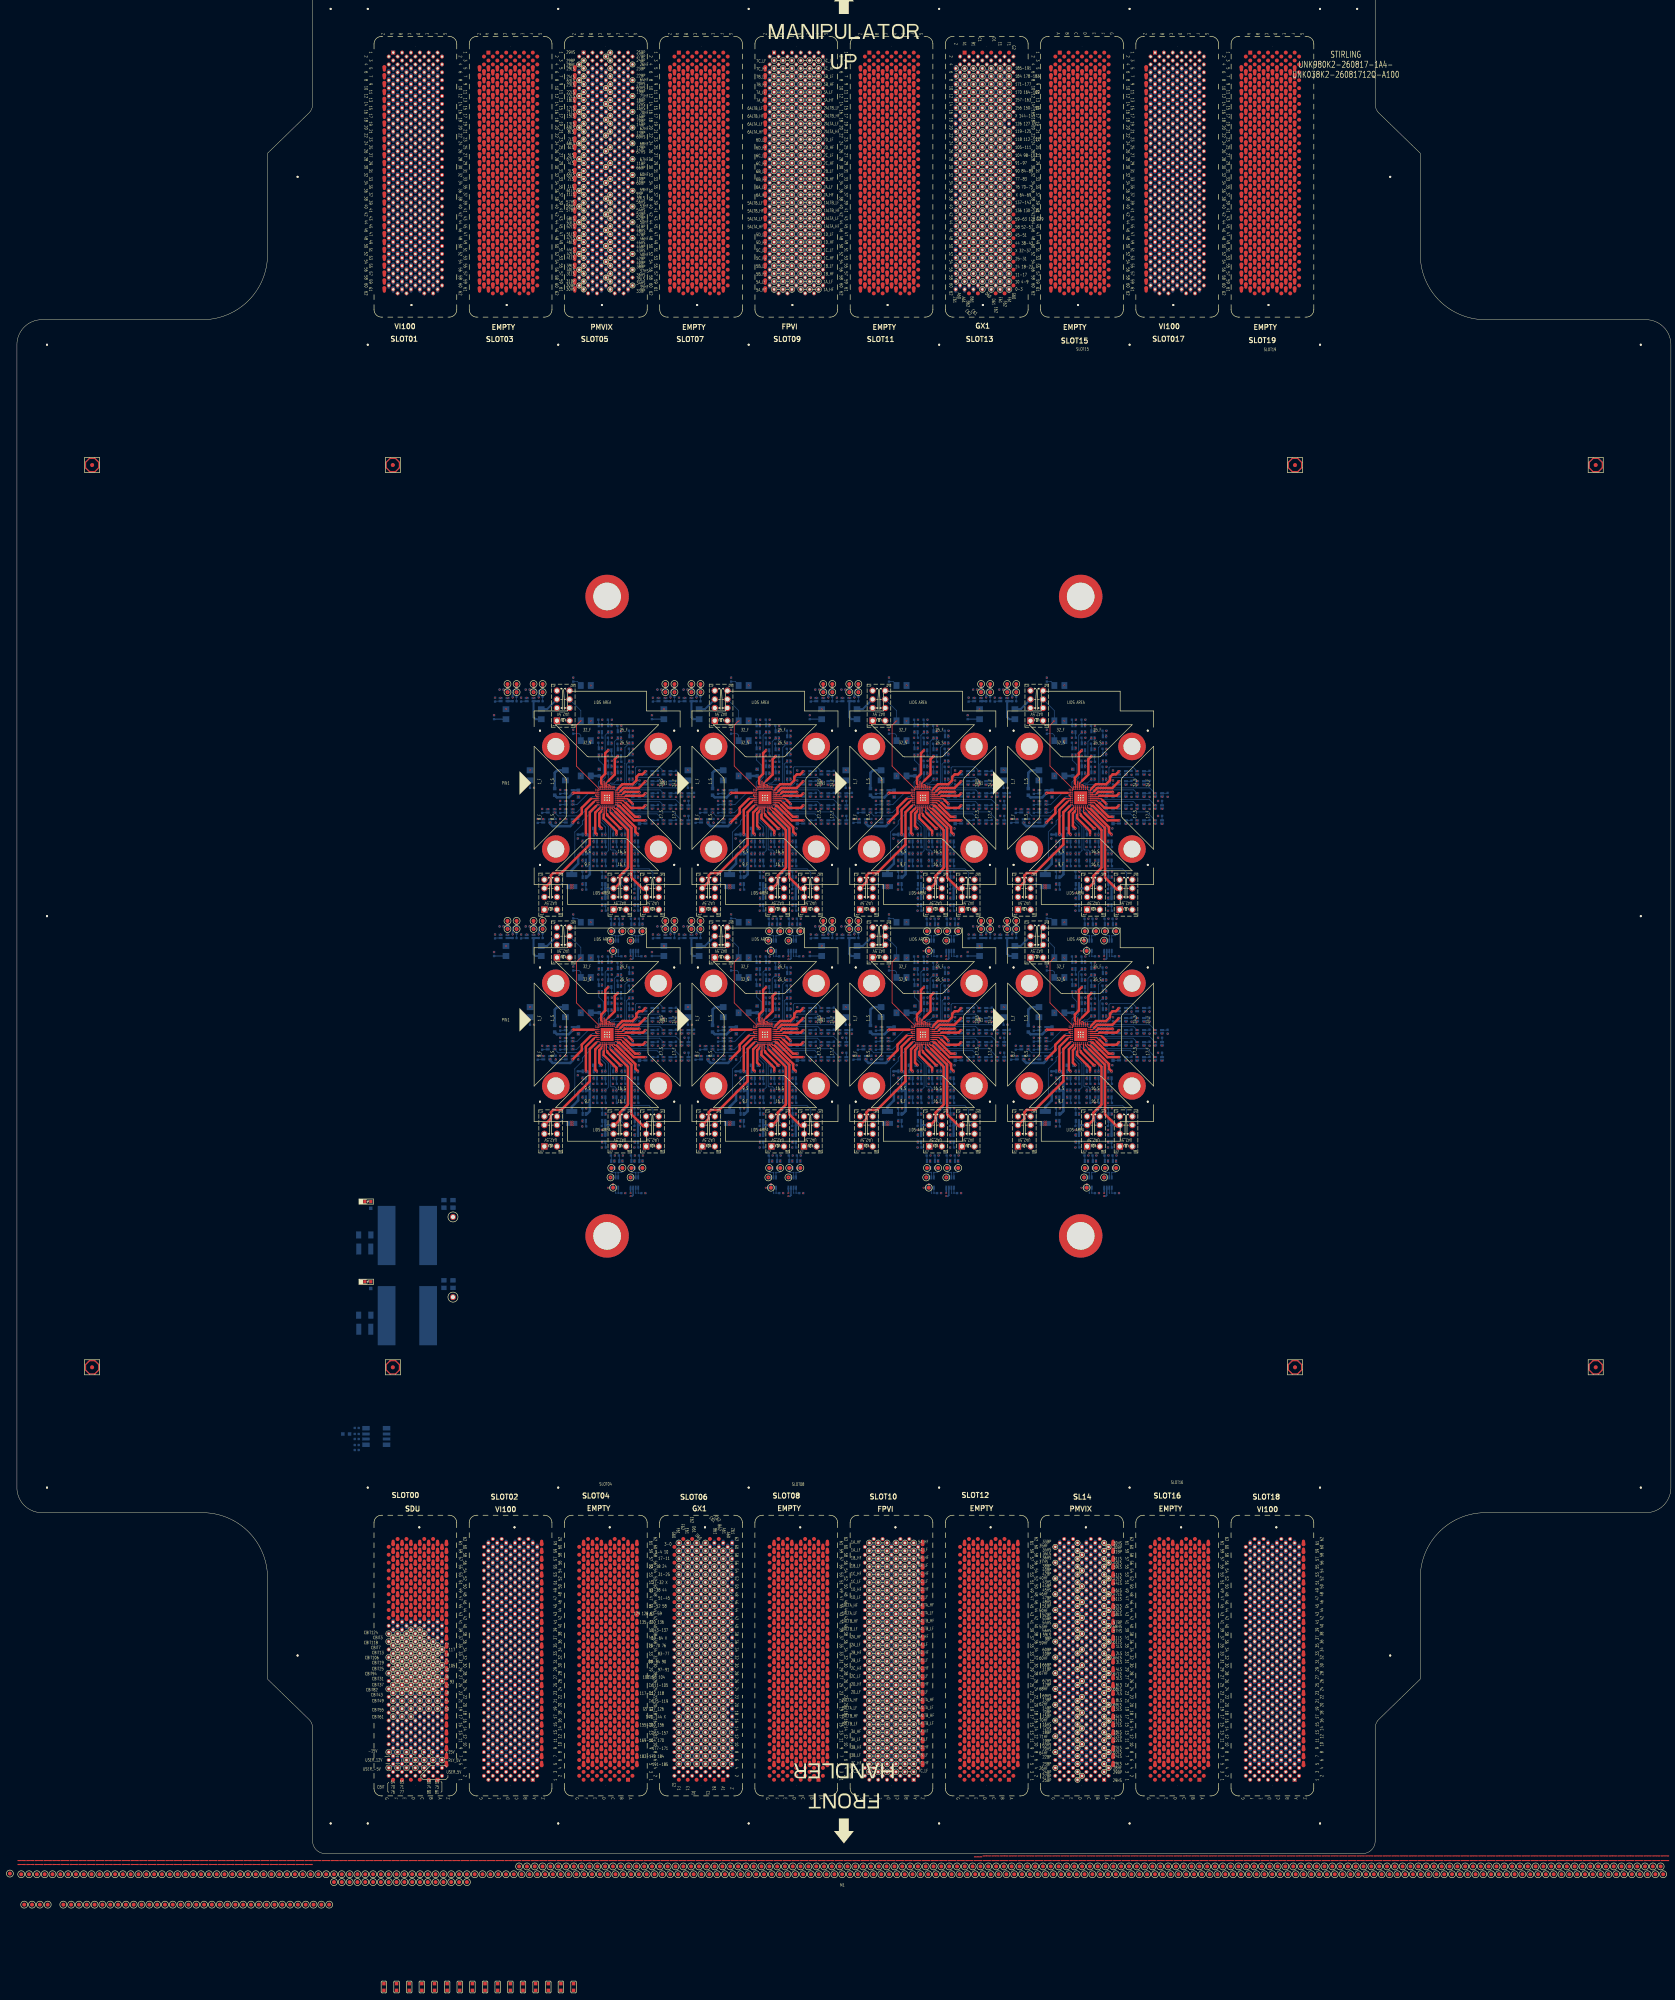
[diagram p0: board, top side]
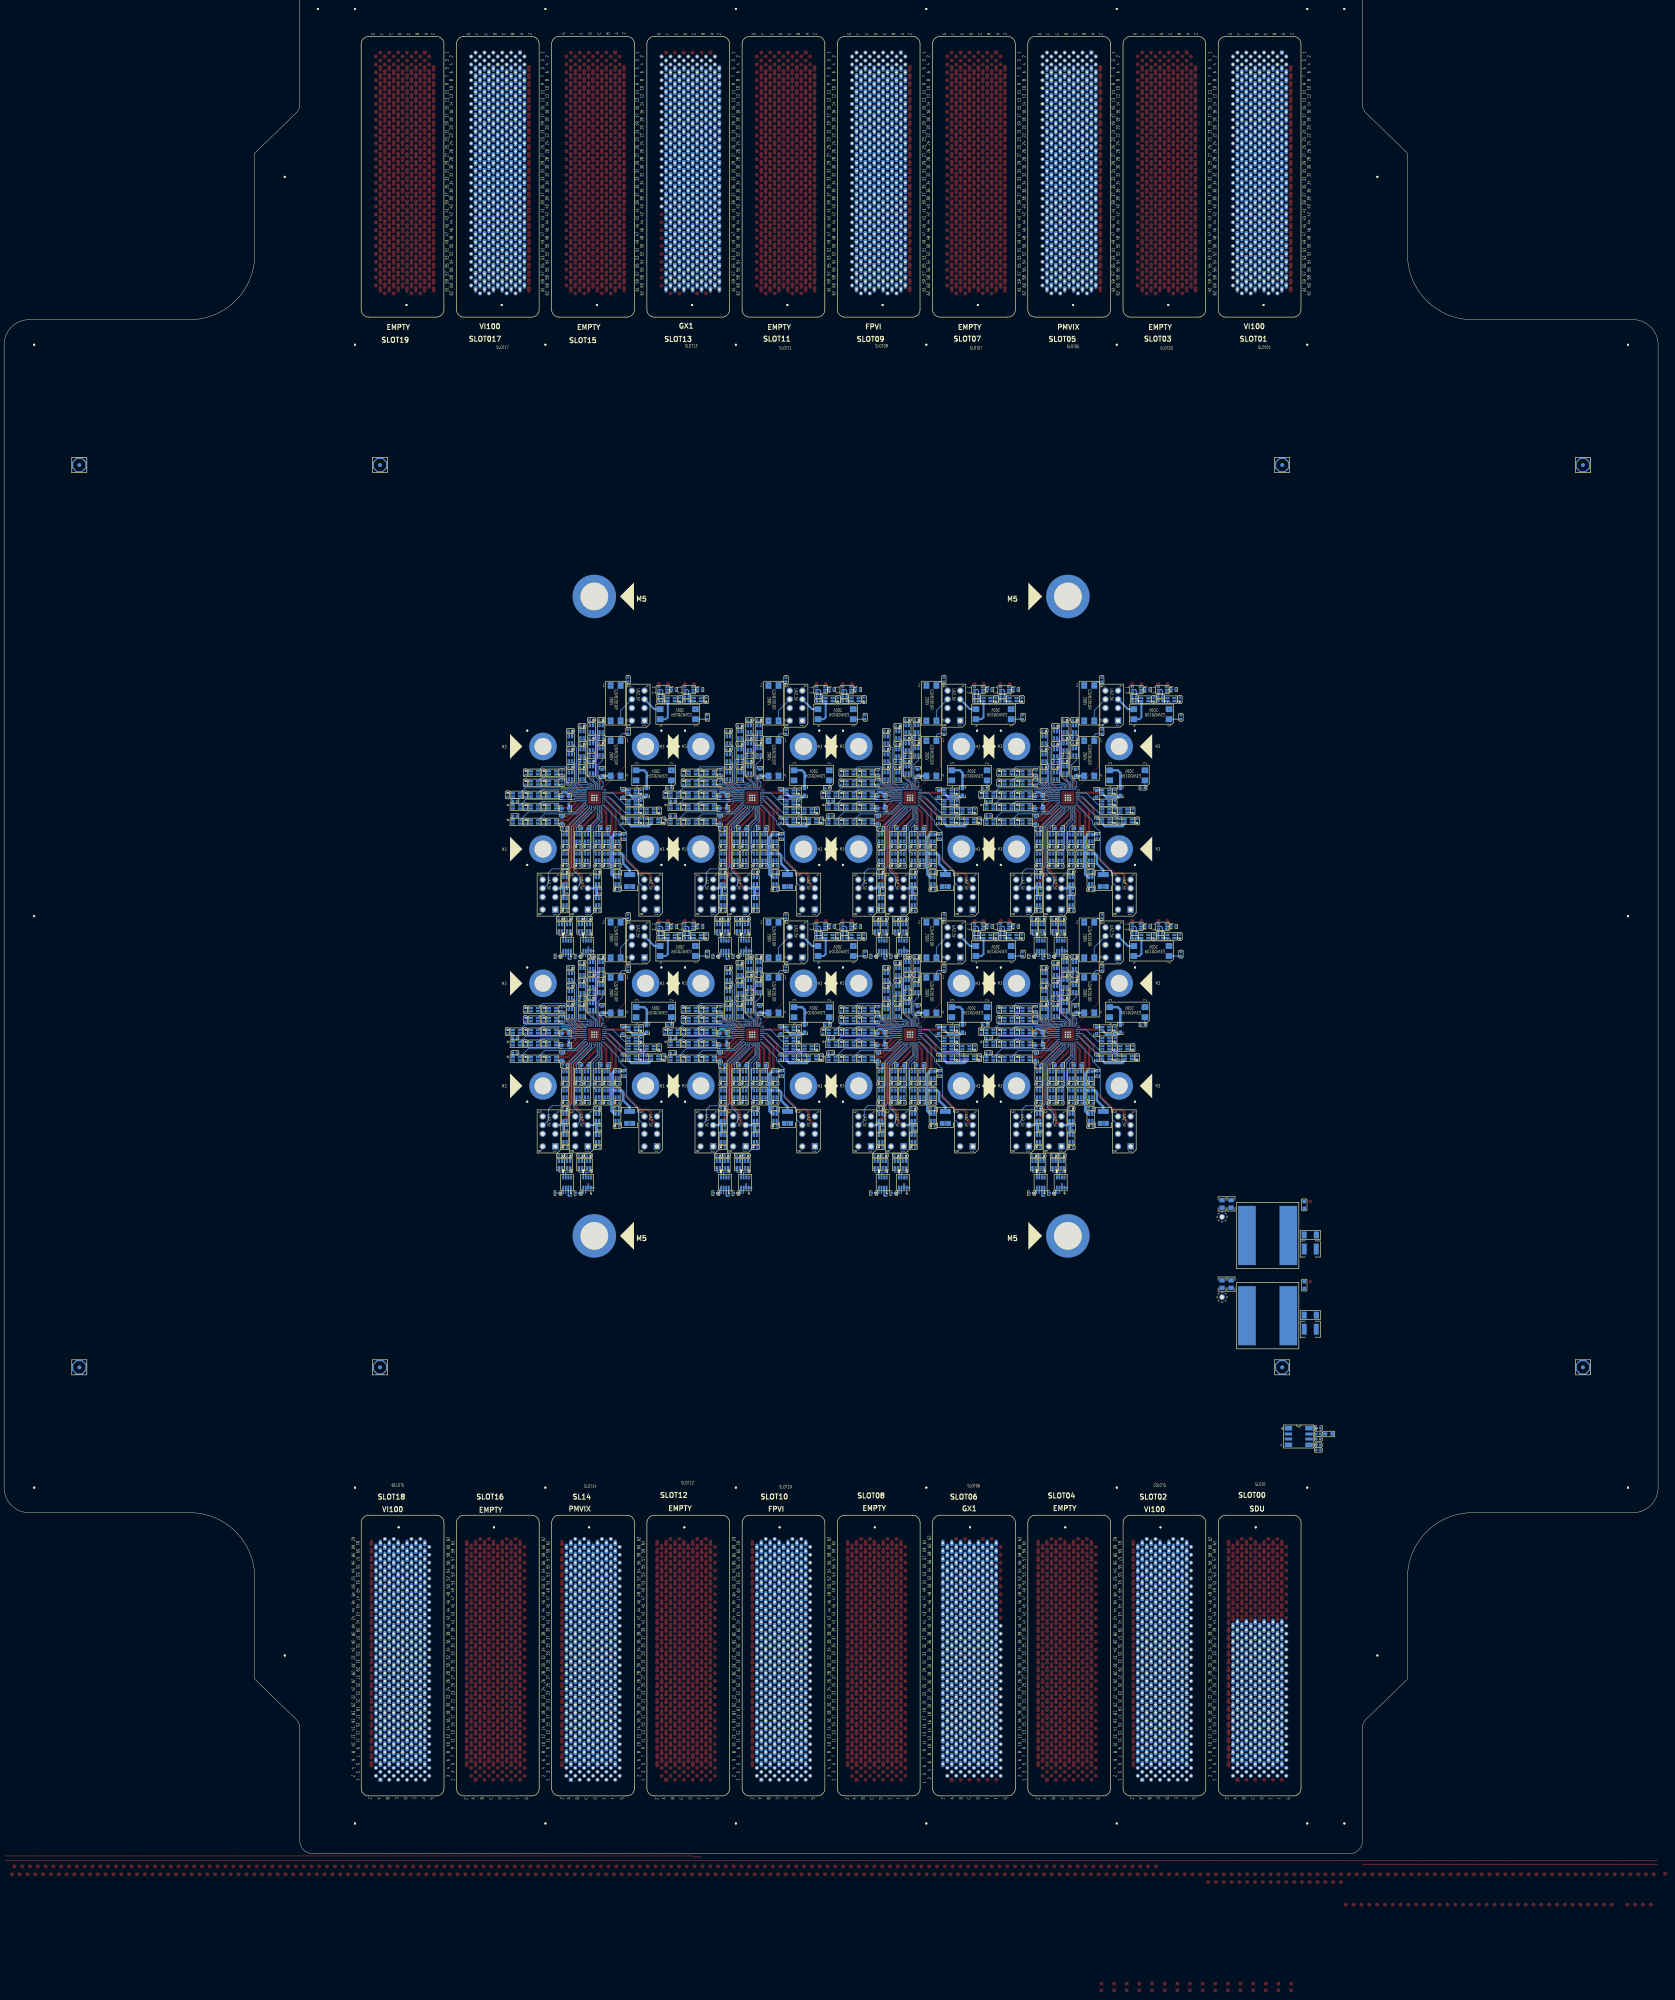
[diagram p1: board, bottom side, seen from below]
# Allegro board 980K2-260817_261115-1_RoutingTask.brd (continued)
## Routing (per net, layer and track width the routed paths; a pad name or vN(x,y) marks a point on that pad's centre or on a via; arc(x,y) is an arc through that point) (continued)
CBIT_10:
  vias: v1(134.51,264.66) v1(134.51,204.66) v1(214.51,264.66) v1(214.51,204.66)
CBIT_11:
  vias: v1(143.26,256.43) v1(143.26,196.43) v1(223.26,256.43) v1(223.26,196.43)
CBIT_12:
  vias: v1(143.26,251.6) v1(143.26,191.6) v1(223.26,251.6) v1(223.26,191.6)
CBIT_13:
  vias: v1(143.26,245.63) v1(143.26,185.63) v1(223.26,245.63) v1(223.26,185.63)
CBIT_14:
  vias: v1(146.06,251.6) v1(146.06,191.6) v1(226.06,251.6) v1(226.06,191.6)
CBIT_16:
  vias: v1(146.06,256.43) v1(146.06,196.43) v1(226.06,256.43) v1(226.06,196.43)
CBIT_17:
  vias: v1(148.22,256.43) v1(148.22,196.43) v1(228.22,256.43) v1(228.22,196.43)
CBIT_18:
  vias: v1(148.22,251.6) v1(148.22,191.6) v1(228.22,251.6) v1(228.22,191.6)
CBIT_19:
  vias: v1(151.01,256.43) v1(151.01,196.43) v1(231.01,256.43) v1(231.01,196.43)
CBIT_20:
  vias: v1(151.01,251.6) v1(151.01,191.6) v1(231.01,251.6) v1(231.01,191.6)
CBIT_21:
  vias: v1(153.17,256.43) v1(153.17,196.43) v1(233.17,256.43) v1(233.17,196.43)
CBIT_22:
  vias: v1(153.17,251.6) v1(153.17,191.6) v1(233.17,251.6) v1(233.17,191.6)
CBIT_25:
  vias: v1(156.47,256.43) v1(156.47,196.43) v1(236.47,256.43) v1(236.47,196.43)
CBIT_26:
  vias: v1(156.47,251.6) v1(156.47,191.6) v1(236.47,251.6) v1(236.47,191.6)
CBIT_27:
  vias: v1(161.02,260.87) v1(161.02,200.87) v1(241.02,260.87) v1(241.02,200.87)
CBIT_28:
  vias: v1(165.59,260.87) v1(165.59,200.87) v1(245.59,260.87) v1(245.59,200.87)
CBIT_29:
  vias: v1(170.17,260.87) v1(170.17,200.87) v1(250.17,260.87) v1(250.17,200.87)
CBIT_30:
  vias: v1(161.02,264.68) v1(161.02,204.68) v1(241.02,264.68) v1(241.02,204.68)
CBIT_31:
  vias: v1(165.59,264.68) v1(165.59,204.68) v1(245.59,264.68) v1(245.59,204.68)
CBIT_32:
  vias: v1(170.17,264.68) v1(170.17,204.68) v1(250.17,264.68) v1(250.17,204.68)
CBIT_33:
  vias: v1(161.02,267.72) v1(161.02,207.72) v1(241.02,267.72) v1(241.02,207.72)
CBIT_34:
  vias: v1(165.59,267.72) v1(165.59,207.72) v1(245.59,267.72) v1(245.59,207.72)
CBIT_35:
  vias: v1(170.17,267.72) v1(170.17,207.72) v1(250.17,267.72) v1(250.17,207.72)
CBIT_36:
  vias: v1(161.02,270.77) v1(161.02,210.77) v1(241.02,270.77) v1(241.02,210.77)
CBIT_37:
  vias: v1(165.59,270.77) v1(165.59,210.77) v1(245.59,270.77) v1(245.59,210.77)
CBIT_38:
  vias: v1(161.02,273.31) v1(161.02,213.31) v1(241.02,273.31) v1(241.02,213.31)
CBIT_39:
  vias: v1(165.59,273.31) v1(165.59,213.31) v1(245.59,273.31) v1(245.59,213.31)
CBIT_40:
  vias: v1(156.08,273.93) v1(156.08,213.93) v1(236.07,273.93) v1(236.07,213.93)
CBIT_41:
  vias: v1(156.08,278.5) v1(156.08,218.5) v1(236.07,278.5) v1(236.07,218.5)
CBIT_42:
  vias: v1(156.08,283.07) v1(156.08,223.07) v1(236.07,283.07) v1(236.07,223.07)
CBIT_43:
  vias: v1(153.15,273.93) v1(153.15,213.93) v1(233.15,273.93) v1(233.15,213.93)
CBIT_44:
  vias: v1(153.15,279.77) v1(153.15,219.77) v1(233.15,279.77) v1(233.15,219.77)
CBIT_45:
  vias: v1(153.15,284.34) v1(153.15,224.34) v1(233.15,284.34) v1(233.15,224.34)
CBIT_46:
  vias: v1(150.74,275.45) v1(150.74,215.45) v1(230.74,275.45) v1(230.74,215.45)
CBIT_47:
  vias: v1(150.74,281.29) v1(150.74,221.29) v1(230.74,281.29) v1(230.74,221.29)
CBIT_48:
  vias: v1(150.74,285.86) v1(150.74,225.86) v1(230.74,285.86) v1(230.74,225.86)
CBIT_49:
  vias: v1(148.33,285.86) v1(148.33,225.86) v1(228.33,285.86) v1(228.33,225.86)
CBIT_50:
  vias: v1(148.33,280.02) v1(148.33,220.02) v1(228.33,280.02) v1(228.33,220.02)
CBIT_51:
  vias: v1(149.22,247.38) v1(149.22,187.38) v1(229.22,247.38) v1(229.22,187.38)
CBIT_52:
  vias: v1(148.22,240.3) v1(148.22,180.3) v1(228.22,240.3) v1(228.22,180.3)
CBIT_53:
  vias: v1(157.47,247.38) v1(157.47,187.38) v1(237.47,247.38) v1(237.47,187.38)
CBIT_54:
  vias: v1(156.47,240.3) v1(156.47,180.3) v1(236.47,240.3) v1(236.47,180.3)
CBIT_55:
  vias: v1(122.57,292.85) v1(122.57,232.85) v1(202.57,292.85) v1(202.57,232.85)
CBIT_56:
  vias: v1(123.92,289.94) v1(123.92,229.94) v1(203.92,289.94) v1(203.92,229.94)
CBIT_57:
  vias: v1(158.52,235.44) v1(158.52,175.44) v1(238.51,235.44) v1(238.51,175.44)
CBIT_58:
  vias: v1(156.48,235.44) v1(156.48,175.44) v1(236.48,235.44) v1(236.48,175.44)
CBIT_59:
  vias: v1(153.44,235.44) v1(153.44,175.44) v1(233.43,235.44) v1(233.43,175.44)
CBIT_60:
  vias: v1(151.4,235.44) v1(151.4,175.44) v1(231.4,235.44) v1(231.4,175.44)
CBIT_62:
  vias: v1(185.41,281.97) v1(185.41,221.97) v1(265.41,281.97) v1(265.41,221.97)
CBIT_63:
  vias: v1(170.02,274.45) v1(170.02,214.45) v1(250.02,274.45) v1(250.02,214.45)
CBIT_64:
  vias: v1(185.41,295.94) v1(185.41,235.94) v1(265.41,295.94) v1(265.41,235.94)
CBIT_65:
  vias: v1(179.08,269.49) v1(179.08,209.49) v1(259.08,269.49) v1(259.08,209.49)
CBIT_66:
  vias: v1(179.08,266.69) v1(179.08,206.69) v1(259.08,266.69) v1(259.08,206.69)
CBIT_67:
  vias: v1(179.08,264.66) v1(179.08,204.66) v1(259.08,264.66) v1(259.08,204.66)
CBIT_68:
  vias: v1(179.08,262.12) v1(179.08,202.12) v1(259.08,262.12) v1(259.08,202.12)
CBIT_69:
  vias: v1(173.36,262.12) v1(173.36,202.12) v1(253.36,262.12) v1(253.36,202.12)
CBIT_70:
  vias: v1(174.51,264.66) v1(174.51,204.66) v1(254.51,264.66) v1(254.51,204.66)
CBIT_71:
  vias: v1(183.26,256.43) v1(183.26,196.43) v1(263.26,256.43) v1(263.26,196.43)
CBIT_72:
  vias: v1(183.26,251.6) v1(183.26,191.6) v1(263.26,251.6) v1(263.26,191.6)
CBIT_73:
  vias: v1(183.26,245.63) v1(183.26,185.63) v1(263.26,245.63) v1(263.26,185.63)
CBIT_74:
  vias: v1(186.06,251.6) v1(186.06,191.6) v1(266.06,251.6) v1(266.06,191.6)
CBIT_76:
  vias: v1(186.06,256.43) v1(186.06,196.43) v1(266.06,256.43) v1(266.06,196.43)
CBIT_77:
  vias: v1(188.22,256.43) v1(188.22,196.43) v1(268.22,256.43) v1(268.22,196.43)
CBIT_78:
  vias: v1(188.22,251.6) v1(188.22,191.6) v1(268.22,251.6) v1(268.22,191.6)
CBIT_79:
  vias: v1(191.01,256.43) v1(191.01,196.43) v1(271.01,256.43) v1(271.01,196.43)
CBIT_80:
  vias: v1(191.01,251.6) v1(191.01,191.6) v1(271.01,251.6) v1(271.01,191.6)
CBIT_81:
  vias: v1(193.17,256.43) v1(193.17,196.43) v1(273.17,256.43) v1(273.17,196.43)
CBIT_82:
  vias: v1(193.17,251.6) v1(193.17,191.6) v1(273.17,251.6) v1(273.17,191.6)
CBIT_85:
  vias: v1(196.47,256.43) v1(196.47,196.43) v1(276.47,256.43) v1(276.47,196.43)
CBIT_86:
  vias: v1(196.47,251.6) v1(196.47,191.6) v1(276.47,251.6) v1(276.47,191.6)
CBIT_87:
  vias: v1(201.02,260.87) v1(201.02,200.87) v1(281.02,260.87) v1(281.02,200.87)
CBIT_88:
  vias: v1(205.59,260.87) v1(205.59,200.87) v1(285.59,260.87) v1(285.59,200.87)
CBIT_89:
  vias: v1(210.17,260.87) v1(210.17,200.87) v1(290.17,260.87) v1(290.17,200.87)
CBIT_90:
  vias: v1(201.02,264.68) v1(201.02,204.68) v1(281.02,264.68) v1(281.02,204.68)
CBIT_91:
  vias: v1(205.59,264.68) v1(205.59,204.68) v1(285.59,264.68) v1(285.59,204.68)
CBIT_92:
  vias: v1(210.17,264.68) v1(210.17,204.68) v1(290.17,264.68) v1(290.17,204.68)
CBIT_93:
  vias: v1(201.02,267.72) v1(201.02,207.72) v1(281.02,267.72) v1(281.02,207.72)
CBIT_94:
  vias: v1(205.59,267.72) v1(205.59,207.72) v1(285.59,267.72) v1(285.59,207.72)
CBIT_95:
  vias: v1(210.17,267.72) v1(210.17,207.72) v1(290.17,267.72) v1(290.17,207.72)
CBIT_96:
  vias: v1(201.02,270.77) v1(201.02,210.77) v1(281.02,270.77) v1(281.02,210.77)
CBIT_97:
  vias: v1(205.59,270.77) v1(205.59,210.77) v1(285.59,270.77) v1(285.59,210.77)
CBIT_98:
  vias: v1(201.02,273.31) v1(201.02,213.31) v1(281.02,273.31) v1(281.02,213.31)
CBIT_99:
  vias: v1(205.59,273.31) v1(205.59,213.31) v1(285.59,273.31) v1(285.59,213.31)
CBIT_100:
  vias: v1(196.08,273.93) v1(196.08,213.93) v1(276.07,273.93) v1(276.07,213.93)
CBIT_101:
  vias: v1(196.08,278.5) v1(196.08,218.5) v1(276.07,278.5) v1(276.07,218.5)
CBIT_102:
  vias: v1(196.08,283.07) v1(196.08,223.07) v1(276.07,283.07) v1(276.07,223.07)
CBIT_103:
  vias: v1(193.15,273.93) v1(193.15,213.93) v1(273.15,273.93) v1(273.15,213.93)
CBIT_104:
  vias: v1(193.15,279.77) v1(193.15,219.77) v1(273.15,279.77) v1(273.15,219.77)
CBIT_105:
  vias: v1(193.15,284.34) v1(193.15,224.34) v1(273.15,284.34) v1(273.15,224.34)
CBIT_106:
  vias: v1(190.74,275.45) v1(190.74,215.45) v1(270.74,275.45) v1(270.74,215.45)
CBIT_107:
  vias: v1(190.74,281.29) v1(190.74,221.29) v1(270.74,281.29) v1(270.74,221.29)
CBIT_108:
  vias: v1(190.74,285.86) v1(190.74,225.86) v1(270.74,285.86) v1(270.74,225.86)
CBIT_109:
  vias: v1(188.33,285.86) v1(188.33,225.86) v1(268.33,285.86) v1(268.33,225.86)
CBIT_110:
  vias: v1(188.33,280.02) v1(188.33,220.02) v1(268.33,280.02) v1(268.33,220.02)
CBIT_111:
  vias: v1(189.22,247.38) v1(189.22,187.38) v1(269.22,247.38) v1(269.22,187.38)
CBIT_112:
  vias: v1(188.22,240.3) v1(188.22,180.3) v1(268.22,240.3) v1(268.22,180.3)
CBIT_113:
  vias: v1(197.47,247.38) v1(197.47,187.38) v1(277.47,247.38) v1(277.47,187.38)
CBIT_114:
  vias: v1(196.47,240.3) v1(196.47,180.3) v1(276.47,240.3) v1(276.47,180.3)
CBIT_115:
  vias: v1(162.57,292.85) v1(162.57,232.85) v1(242.57,292.85) v1(242.57,232.85)
CBIT_116:
  vias: v1(163.92,289.94) v1(163.92,229.94) v1(243.92,289.94) v1(243.92,229.94)
CBIT_117:
  vias: v1(198.51,235.44) v1(198.51,175.44) v1(278.51,235.44) v1(278.51,175.44)
CBIT_118:
  vias: v1(196.48,235.44) v1(196.48,175.44) v1(276.48,235.44) v1(276.48,175.44)
CBIT_119:
  vias: v1(193.43,235.44) v1(193.43,175.44) v1(273.43,235.44) v1(273.43,175.44)
CBIT_120:
  vias: v1(191.4,235.44) v1(191.4,175.44) v1(271.4,235.44) v1(271.4,175.44)
CBIT_127:
  vias: v1(129.17,292.85) v1(129.17,232.85) v1(209.17,292.85) v1(209.17,232.85)
CBIT_128:
  vias: v1(169.17,292.85) v1(169.17,232.85) v1(249.17,292.85) v1(249.17,232.85)
DUT1_GND: length 7.8
  BOTTOM w0.203: 125.61,292.84 v1(125.61,292.85)
  BOTTOM w0.305: R14.1 132.21,294.59 132.52,294.89 U2.2 ; R11.1 125.61,294.59 125.92,294.89 U1.2
  BOTTOM w0.381: R14.1 v1(132.21,292.85) ; U4.4 v1(149.73,228.7) ; v1(125.61,292.85) R11.1 ; U3.4 v1(155.49,227.33)
  vias: v1(122.3,294.89) v1(128.92,294.89) v1(136.53,261.22) v1(140.36,245.44) v1(140.36,244.98) v1(140.36,244.53) v1(140.82,245.44) v1(140.82,244.98) v1(140.82,244.53) v1(142.11,257.18) v1(142.28,267.69) v1(142.24,261.22) v1(144.26,248.79) v1(147.33,282.7) v1(147.43,274.72) v1(148.22,242.05) v1(149.84,278.13) v1(152.25,276.61) v1(154.17,227.33) v1(156.47,242.05) v1(157.57,259.72) v1(157.73,274.41) v1(157.73,271.87) v1(159.25,227.33) v2(147.05,268.24) v2(147.45,268.24)
DUT2_GND: length 7.8
  BOTTOM w0.203: 165.61,292.84 v1(165.61,292.85)
  BOTTOM w0.305: UNK2R14.1 172.21,294.59 172.52,294.89 UNK2U2.2 ; UNK2R11.1 165.61,294.59 165.92,294.89 UNK2U1.2
  BOTTOM w0.381: UNK2R14.1 v1(172.21,292.85) ; UNK2U4.4 v1(189.73,228.7) ; v1(165.61,292.85) UNK2R11.1 ; UNK2U3.4 v1(195.49,227.33)
  vias: v1(162.3,294.89) v1(168.92,294.89) v1(176.52,261.22) v1(180.36,245.44) v1(180.36,244.98) v1(180.36,244.53) v1(180.82,245.44) v1(180.82,244.98) v1(180.82,244.53) v1(182.11,257.18) v1(182.28,267.69) v1(182.24,261.22) v1(184.26,248.79) v1(187.33,282.7) v1(187.43,274.72) v1(188.22,242.05) v1(189.84,278.13) v1(192.25,276.61) v1(194.17,227.33) v1(196.47,242.05) v1(197.57,259.72) v1(197.73,274.41) v1(197.73,271.87) v1(199.25,227.33) v2(187.05,268.24) v2(187.45,268.24)
DUT3_GND: length 7.8
  BOTTOM w0.203: 205.61,292.84 v1(205.61,292.85)
  BOTTOM w0.305: UNK3U2.2 212.52,294.89 212.21,294.59 UNK3R14.1 ; UNK3R11.1 205.61,294.59 205.92,294.89 UNK3U1.2
  BOTTOM w0.381: UNK3U4.4 v1(229.73,228.7) ; v1(205.61,292.85) UNK3R11.1 ; UNK3R14.1 v1(212.21,292.85) ; UNK3U3.4 v1(235.49,227.33)
  vias: v1(202.3,294.89) v1(208.92,294.89) v1(216.52,261.22) v1(220.36,245.44) v1(220.36,244.98) v1(220.36,244.53) v1(220.82,245.44) v1(220.82,244.98) v1(220.82,244.53) v1(222.11,257.18) v1(222.28,267.69) v1(222.24,261.22) v1(224.26,248.79) v1(227.33,282.7) v1(227.43,274.72) v1(228.22,242.05) v1(229.84,278.13) v1(232.25,276.61) v1(234.17,227.33) v1(236.47,242.05) v1(237.57,259.72) v1(237.73,274.41) v1(237.73,271.87) v1(239.25,227.33) v2(227.05,268.24) v2(227.45,268.24)
DUT4_GND: length 7.8
  BOTTOM w0.203: 245.61,292.84 v1(245.61,292.85)
  BOTTOM w0.305: UNK4R14.1 252.21,294.59 252.52,294.89 UNK4U2.2 ; UNK4R11.1 245.61,294.59 245.92,294.89 UNK4U1.2
  BOTTOM w0.381: UNK4U4.4 v1(269.73,228.7) ; UNK4R14.1 v1(252.21,292.85) ; UNK4U3.4 v1(275.49,227.33) ; v1(245.61,292.85) UNK4R11.1
  vias: v1(242.3,294.89) v1(248.92,294.89) v1(256.52,261.22) v1(260.36,245.44) v1(260.36,244.98) v1(260.36,244.53) v1(260.82,245.44) v1(260.82,244.98) v1(260.82,244.53) v1(262.11,257.18) v1(262.28,267.69) v1(262.24,261.22) v1(264.26,248.79) v1(267.33,282.7) v1(267.43,274.72) v1(268.22,242.05) v1(269.84,278.13) v1(272.25,276.61) v1(274.17,227.33) v1(276.47,242.05) v1(277.57,259.72) v1(277.73,274.41) v1(277.73,271.87) v1(279.25,227.33) v2(267.05,268.24) v2(267.45,268.24)
DUT5_GND: length 7.8
  BOTTOM w0.203: 125.61,232.84 v1(125.61,232.85)
  BOTTOM w0.305: UNK5R14.1 132.21,234.59 132.52,234.89 UNK5U2.2 ; UNK5R11.1 125.61,234.59 125.92,234.89 UNK5U1.2
  BOTTOM w0.381: v1(125.61,232.85) UNK5R11.1 ; UNK5R14.1 v1(132.21,232.85) ; UNK5U3.4 v1(155.49,167.33) ; UNK5U4.4 v1(149.73,168.7)
  vias: v1(122.3,234.89) v1(128.92,234.89) v1(136.53,201.22) v1(140.36,185.44) v1(140.36,184.98) v1(140.36,184.53) v1(140.82,185.44) v1(140.82,184.98) v1(140.82,184.53) v1(142.11,197.18) v1(142.28,207.69) v1(142.24,201.22) v1(144.26,188.79) v1(147.33,222.7) v1(147.43,214.72) v1(148.22,182.05) v1(149.84,218.13) v1(152.25,216.61) v1(154.17,167.33) v1(156.47,182.05) v1(157.57,199.72) v1(157.73,214.41) v1(157.73,211.87) v1(159.25,167.33) v2(147.05,208.24) v2(147.45,208.24)
DUT6_GND: length 7.8
  BOTTOM w0.203: 165.61,232.84 v1(165.61,232.85)
  BOTTOM w0.305: UNK6R14.1 172.21,234.59 172.52,234.89 UNK6U2.2 ; UNK6U1.2 165.92,234.89 165.61,234.59 UNK6R11.1
  BOTTOM w0.381: UNK6R14.1 v1(172.21,232.85) ; UNK6U3.4 v1(195.49,167.33) ; v1(165.61,232.85) UNK6R11.1 ; UNK6U4.4 v1(189.73,168.7)
  vias: v1(162.3,234.89) v1(168.92,234.89) v1(176.52,201.22) v1(180.36,185.44) v1(180.36,184.98) v1(180.36,184.53) v1(180.82,185.44) v1(180.82,184.98) v1(180.82,184.53) v1(182.11,197.18) v1(182.28,207.69) v1(182.24,201.22) v1(184.26,188.79) v1(187.33,222.7) v1(187.43,214.72) v1(188.22,182.05) v1(189.84,218.13) v1(192.25,216.61) v1(194.17,167.33) v1(196.47,182.05) v1(197.57,199.72) v1(197.73,214.41) v1(197.73,211.87) v1(199.25,167.33) v2(187.05,208.24) v2(187.45,208.24)
DUT7_GND: length 7.8
  BOTTOM w0.203: 205.61,232.84 v1(205.61,232.85)
  BOTTOM w0.305: UNK7U2.2 212.52,234.89 212.21,234.59 UNK7R14.1 ; UNK7U1.2 205.92,234.89 205.61,234.59 UNK7R11.1
  BOTTOM w0.381: UNK7R14.1 v1(212.21,232.85) ; UNK7U3.4 v1(235.49,167.33) ; v1(205.61,232.85) UNK7R11.1 ; UNK7U4.4 v1(229.73,168.7)
  vias: v1(202.3,234.89) v1(208.92,234.89) v1(216.52,201.22) v1(220.36,185.44) v1(220.36,184.98) v1(220.36,184.53) v1(220.82,185.44) v1(220.82,184.98) v1(220.82,184.53) v1(222.11,197.18) v1(222.28,207.69) v1(222.24,201.22) v1(224.26,188.79) v1(227.33,222.7) v1(227.43,214.72) v1(228.22,182.05) v1(229.84,218.13) v1(232.25,216.61) v1(234.17,167.33) v1(236.47,182.05) v1(237.57,199.72) v1(237.73,214.41) v1(237.73,211.87) v1(239.25,167.33) v2(227.05,208.24) v2(227.45,208.24)
DUT8_GND: length 7.8
  BOTTOM w0.203: 245.61,232.84 v1(245.61,232.85)
  BOTTOM w0.305: UNK8R14.1 252.21,234.59 252.52,234.89 UNK8U2.2 ; UNK8R11.1 245.61,234.59 245.92,234.89 UNK8U1.2
  BOTTOM w0.381: v1(245.61,232.85) UNK8R11.1 ; UNK8U4.4 v1(269.73,168.7) ; UNK8U3.4 v1(275.49,167.33) ; UNK8R14.1 v1(252.21,232.85)
  vias: v1(242.3,234.89) v1(248.92,234.89) v1(256.52,201.22) v1(260.36,185.44) v1(260.36,184.98) v1(260.36,184.53) v1(260.82,185.44) v1(260.82,184.98) v1(260.82,184.53) v1(262.11,197.18) v1(262.28,207.69) v1(262.24,201.22) v1(264.26,188.79) v1(267.33,222.7) v1(267.43,214.72) v1(268.22,182.05) v1(269.84,218.13) v1(272.25,216.61) v1(274.17,167.33) v1(276.47,182.05) v1(277.57,199.72) v1(277.73,214.41) v1(277.73,211.87) v1(279.25,167.33) v2(267.05,208.24) v2(267.45,208.24)
S1_C1B_F: length 8.9
  TOP w0.305: 152.36,265.43 SITE1.17_F
  TOP w0.635: v1(159.27,261.77) 156.32,261.77 152.65,265.43 152.36,265.43
  vias: v1(130.92,292.85)
S1_IS1N_F: length 7
  TOP w0.305: SITE1.12_F 149.35,264.94 149.35,263.53 149.61,263.28
  TOP w0.635: 149.61,263.28 149.61,263.02 152.91,259.72 v1(153.17,259.72)
  vias: v1(157.71,233.69)
S1_IS1P_F: length 8.2
  TOP w0.305: 148.66,263.21 148.8,263.35 SITE1.11_F
  TOP w0.635: v1(151.91,258.18) 151.91,259.06 148.66,262.31 148.66,263.21
  vias: v1(156.48,233.69)
S1_IS2N_F: length 5.8
  TOP w0.305: SITE1.10_F 148.3,264.51 148.08,264.29 148.08,264.03
  TOP w0.635: v1(148.22,259.72) 147.57,260.36 147.57,263.53 148.08,264.03
  vias: v1(152.63,233.69)
S1_IS2P_F: length 7.5
  TOP w0.305: 147.57,264.76 SITE1.9_F
  TOP w0.635: 147.57,264.76 146.56,263.75 146.56,258.58 v1(146.96,258.18)
  vias: v1(151.4,233.69)
S1_SCL_F: length 30.3
  TOP w0.305: 151.64,263.91 150.8,264.74 SITE1.15_F
  TOP w0.635: 151.64,263.91 155.72,259.82 155.72,247.28 158.71,244.3 159.44,244.3
  BOTTOM w0.559: K53.3 157.37,244.55 ; 157.37,244.55 K24.3 ; 157.37,244.55 K54.4
S1_SDA_F: length 29.7
  TOP w0.305: 150.56,263.59 150.3,263.85 SITE1.14_F
  TOP w0.635: 150.56,263.59 154.82,259.33 154.82,249.75 152.78,247.71 152.78,245.9 151.18,244.3
  BOTTOM w0.559: 149.12,244.55 K51.3 ; 149.12,244.55 K23.3 ; 149.12,244.55 K52.4
S1_SRD_F: length 5
  BOTTOM w0.508: K56.3 134.34,289.94 K1.3
  vias: v2(138.97,271.91) v2(142.88,273.02) v2(146.65,269.64) v2(146.65,269.24) v2(147.05,269.64) v2(147.05,269.24)
S1_SRD_S: length 27.2
  TOP w0.203: SITE1.1_S 147.45,269.84 141.76,275.53 141.76,285.88 v1(142.88,286.99)
  BOTTOM w0.203: K1.6 142.88,289.59 v1(142.88,286.99)
S1_SRG_F: length 0.7
  TOP w0.305: v2(146.65,268.24) 146.65,268.04 146.95,267.74 SITE1.4_F
  vias: v1(124.32,292.85)
S2_C1B_F: length 8.9
  TOP w0.305: 192.36,265.43 SITE2.17_F
  TOP w0.635: 192.36,265.43 192.65,265.43 196.32,261.77 v1(199.27,261.77)
  vias: v1(170.92,292.85)
S2_IS1N_F: length 7
  TOP w0.305: SITE2.12_F 189.35,264.94 189.35,263.53 189.61,263.28
  TOP w0.635: v1(193.17,259.72) 192.91,259.72 189.61,263.02 189.61,263.28
  vias: v1(197.71,233.69)
S2_IS1P_F: length 8.2
  TOP w0.305: SITE2.11_F 188.8,263.35 188.66,263.21
  TOP w0.635: v1(191.91,258.18) 191.91,259.06 188.66,262.31 188.66,263.21
  vias: v1(196.48,233.69)
S2_IS2N_F: length 5.8
  TOP w0.305: 188.08,264.03 188.08,264.29 188.3,264.51 SITE2.10_F
  TOP w0.635: v1(188.22,259.72) 187.57,260.36 187.57,263.53 188.08,264.03
  vias: v1(192.63,233.69)
S2_IS2P_F: length 7.5
  TOP w0.305: 187.57,264.76 SITE2.9_F
  TOP w0.635: v1(186.96,258.18) 186.56,258.58 186.56,263.75 187.57,264.76
  vias: v1(191.4,233.69)
S2_SCL_F: length 30.3
  TOP w0.305: SITE2.15_F 190.8,264.74 191.64,263.91
  TOP w0.635: 191.64,263.91 195.72,259.82 195.72,247.28 198.71,244.3 199.44,244.3
  BOTTOM w0.559: 197.37,244.55 UNK2K54.4 ; 197.37,244.55 UNK2K24.3 ; 197.37,244.55 UNK2K53.3
S2_SDA_F: length 29.7
  TOP w0.305: 190.56,263.59 190.3,263.85 SITE2.14_F
  TOP w0.635: 190.56,263.59 194.82,259.33 194.82,249.75 192.78,247.71 192.78,245.9 191.18,244.3
  BOTTOM w0.559: UNK2K52.4 189.12,244.55 ; 189.12,244.55 UNK2K51.3 ; 189.12,244.55 UNK2K23.3
S2_SRD_F: length 5
  BOTTOM w0.508: UNK2K1.3 174.34,289.94 UNK2K56.3
  vias: v2(178.97,271.91) v2(182.87,273.02) v2(187.05,269.24)
S2_SRD_S: length 27.2
  TOP w0.203: SITE2.1_S 187.45,269.84 181.76,275.53 181.76,285.88 v1(182.87,286.99)
  BOTTOM w0.203: UNK2K1.6 182.87,289.59 v1(182.87,286.99)
S2_SRG_F: length 0.7
  TOP w0.305: SITE2.4_F 186.95,267.74 186.65,268.04 v2(186.65,268.24)
  vias: v1(164.32,292.85)
S3_C1B_F: length 8.9
  TOP w0.305: 232.36,265.43 SITE3.17_F
  TOP w0.635: v1(239.27,261.77) 236.32,261.77 232.65,265.43 232.36,265.43
  vias: v1(210.92,292.85)
S3_IS1N_F: length 7
  TOP w0.305: SITE3.12_F 229.35,264.94 229.35,263.53 229.61,263.28
  TOP w0.635: v1(233.17,259.72) 232.91,259.72 229.61,263.02 229.61,263.28
  vias: v1(237.71,233.69)
S3_IS1P_F: length 8.2
  TOP w0.305: SITE3.11_F 228.8,263.35 228.66,263.21
  TOP w0.635: v1(231.91,258.18) 231.91,259.06 228.66,262.31 228.66,263.21
  vias: v1(236.48,233.69)
S3_IS2N_F: length 5.8
  TOP w0.305: SITE3.10_F 228.3,264.51 228.08,264.29 228.08,264.03
  TOP w0.635: 228.08,264.03 227.57,263.53 227.57,260.36 v1(228.22,259.72)
  vias: v1(232.63,233.69)
S3_IS2P_F: length 7.5
  TOP w0.305: 227.57,264.76 SITE3.9_F
  TOP w0.635: 227.57,264.76 226.56,263.75 226.56,258.58 v1(226.96,258.18)
  vias: v1(231.4,233.69)
S3_SCL_F: length 30.3
  TOP w0.305: SITE3.15_F 230.8,264.74 231.64,263.91
  TOP w0.635: 239.44,244.3 238.71,244.3 235.72,247.28 235.72,259.82 231.64,263.91
  BOTTOM w0.559: 237.37,244.55 UNK3K54.4 ; 237.37,244.55 UNK3K24.3 ; 237.37,244.55 UNK3K53.3
S3_SDA_F: length 29.7
  TOP w0.305: 230.56,263.59 230.3,263.85 SITE3.14_F
  TOP w0.635: 230.56,263.59 234.82,259.33 234.82,249.75 232.78,247.71 232.78,245.9 231.18,244.3
  BOTTOM w0.559: UNK3K52.4 229.12,244.55 ; 229.12,244.55 UNK3K23.3 ; 229.12,244.55 UNK3K51.3
S3_SRD_F: length 5
  BOTTOM w0.508: UNK3K1.3 214.34,289.94 UNK3K56.3
  vias: v2(218.97,271.91) v2(222.87,273.02) v2(227.05,269.24)
S3_SRD_S: length 27.2
  TOP w0.203: SITE3.1_S 227.45,269.84 221.76,275.53 221.76,285.88 v1(222.87,286.99)
  BOTTOM w0.203: v1(222.87,286.99) 222.87,289.59 UNK3K1.6
S3_SRG_F: length 0.7
  TOP w0.305: SITE3.4_F 226.95,267.74 226.65,268.04 v2(226.65,268.24)
  vias: v1(204.32,292.85)
S4_C1B_F: length 8.9
  TOP w0.305: 272.36,265.43 SITE4.17_F
  TOP w0.635: 272.36,265.43 272.65,265.43 276.32,261.77 v1(279.27,261.77)
  vias: v1(250.92,292.85)
S4_IS1N_F: length 7
  TOP w0.305: 269.61,263.28 269.35,263.53 269.35,264.94 SITE4.12_F
  TOP w0.635: 269.61,263.28 269.61,263.02 272.91,259.72 v1(273.17,259.72)
  vias: v1(277.71,233.69)
S4_IS1P_F: length 8.2
  TOP w0.305: SITE4.11_F 268.8,263.35 268.66,263.21
  TOP w0.635: 268.66,263.21 268.66,262.31 271.91,259.06 v1(271.91,258.18)
  vias: v1(276.48,233.69)
S4_IS2N_F: length 5.8
  TOP w0.305: 268.08,264.03 268.08,264.29 268.3,264.51 SITE4.10_F
  TOP w0.635: 268.08,264.03 267.57,263.53 267.57,260.36 v1(268.22,259.72)
  vias: v1(272.63,233.69)
S4_IS2P_F: length 7.5
  TOP w0.305: 267.57,264.76 SITE4.9_F
  TOP w0.635: v1(266.96,258.18) 266.56,258.58 266.56,263.75 267.57,264.76
  vias: v1(271.4,233.69)
S4_SCL_F: length 30.3
  TOP w0.305: SITE4.15_F 270.8,264.74 271.64,263.91
  TOP w0.635: 279.44,244.3 278.71,244.3 275.72,247.28 275.72,259.82 271.64,263.91
  BOTTOM w0.559: UNK4K24.3 277.37,244.55 ; 277.37,244.55 UNK4K53.3 ; 277.37,244.55 UNK4K54.4
S4_SDA_F: length 29.7
  TOP w0.305: 270.56,263.59 270.3,263.85 SITE4.14_F
  TOP w0.635: 270.56,263.59 274.82,259.33 274.82,249.75 272.78,247.71 272.78,245.9 271.18,244.3
  BOTTOM w0.559: UNK4K52.4 269.12,244.55 ; 269.12,244.55 UNK4K51.3 ; 269.12,244.55 UNK4K23.3
S4_SRD_F: length 5
  BOTTOM w0.508: UNK4K1.3 254.34,289.94 UNK4K56.3
  vias: v2(258.97,271.91) v2(262.87,273.02) v2(267.05,269.24)
S4_SRD_S: length 27.2
  TOP w0.203: SITE4.1_S 267.45,269.84 261.76,275.53 261.76,285.88 v1(262.87,286.99)
  BOTTOM w0.203: v1(262.87,286.99) 262.87,289.59 UNK4K1.6
S4_SRG_F: length 0.7
  TOP w0.305: SITE4.4_F 266.95,267.74 266.65,268.04 v2(266.65,268.24)
  vias: v1(244.32,292.85)
S5_C1B_F: length 8.9
  TOP w0.305: 152.36,205.43 SITE5.17_F
  TOP w0.635: v1(159.27,201.77) 156.32,201.77 152.65,205.43 152.36,205.43
  vias: v1(130.92,232.85)
S5_IS1N_F: length 7
  TOP w0.305: SITE5.12_F 149.35,204.94 149.35,203.53 149.61,203.28
  TOP w0.635: v1(153.17,199.72) 152.91,199.72 149.61,203.02 149.61,203.28
  vias: v1(157.71,173.69)
S5_IS1P_F: length 8.2
  TOP w0.305: 148.66,203.21 148.8,203.35 SITE5.11_F
  TOP w0.635: v1(151.91,198.18) 151.91,199.06 148.66,202.31 148.66,203.21
  vias: v1(156.48,173.69)
S5_IS2N_F: length 5.8
  TOP w0.305: SITE5.10_F 148.3,204.51 148.08,204.29 148.08,204.03
  TOP w0.635: 148.08,204.03 147.57,203.53 147.57,200.36 v1(148.22,199.72)
  vias: v1(152.63,173.69)
S5_IS2P_F: length 7.5
  TOP w0.305: 147.57,204.76 SITE5.9_F
  TOP w0.635: v1(146.96,198.18) 146.56,198.58 146.56,203.75 147.57,204.76
  vias: v1(151.4,173.69)
S5_SCL_F: length 30.3
  TOP w0.305: SITE5.15_F 150.8,204.74 151.64,203.91
  TOP w0.635: 159.44,184.3 158.71,184.3 155.72,187.28 155.72,199.82 151.64,203.91
  BOTTOM w0.559: UNK5K24.3 157.37,184.55 ; 157.37,184.55 UNK5K54.4 ; 157.37,184.55 UNK5K53.3
S5_SDA_F: length 29.7
  TOP w0.305: SITE5.14_F 150.3,203.85 150.56,203.59
  TOP w0.635: 151.18,184.3 152.78,185.9 152.78,187.71 154.82,189.75 154.82,199.33 150.56,203.59
  BOTTOM w0.559: 149.12,184.55 UNK5K23.3 ; 149.12,184.55 UNK5K52.4 ; 149.12,184.55 UNK5K51.3
S5_SRD_F: length 5
  BOTTOM w0.508: UNK5K56.3 134.34,229.94 UNK5K1.3
  vias: v2(138.97,211.91) v2(142.88,213.02) v2(147.05,209.24)
S5_SRD_S: length 27.2
  TOP w0.203: v1(142.88,226.99) 141.76,225.88 141.76,215.53 147.45,209.84 SITE5.1_S
  BOTTOM w0.203: v1(142.88,226.99) 142.88,229.59 UNK5K1.6
S5_SRG_F: length 0.7
  TOP w0.305: v2(146.65,208.24) 146.65,208.04 146.95,207.74 SITE5.4_F
  vias: v1(124.32,232.85)
S6_C1B_F: length 8.9
  TOP w0.305: 192.36,205.43 SITE6.17_F
  TOP w0.635: 192.36,205.43 192.65,205.43 196.32,201.77 v1(199.27,201.77)
  vias: v1(170.92,232.85)
S6_IS1N_F: length 7
  TOP w0.305: SITE6.12_F 189.35,204.94 189.35,203.53 189.61,203.28
  TOP w0.635: v1(193.17,199.72) 192.91,199.72 189.61,203.02 189.61,203.28
  vias: v1(197.71,173.69)
S6_IS1P_F: length 8.2
  TOP w0.305: SITE6.11_F 188.8,203.35 188.66,203.21
  TOP w0.635: 188.66,203.21 188.66,202.31 191.91,199.06 v1(191.91,198.18)
  vias: v1(196.48,173.69)
S6_IS2N_F: length 5.8
  TOP w0.305: SITE6.10_F 188.3,204.51 188.08,204.29 188.08,204.03
  TOP w0.635: 188.08,204.03 187.57,203.53 187.57,200.36 v1(188.22,199.72)
  vias: v1(192.63,173.69)
S6_IS2P_F: length 7.5
  TOP w0.305: 187.57,204.76 SITE6.9_F
  TOP w0.635: v1(186.96,198.18) 186.56,198.58 186.56,203.75 187.57,204.76
  vias: v1(191.4,173.69)
S6_SCL_F: length 30.3
  TOP w0.305: SITE6.15_F 190.8,204.74 191.64,203.91
  TOP w0.635: 191.64,203.91 195.72,199.82 195.72,187.28 198.71,184.3 199.44,184.3
  BOTTOM w0.559: 197.37,184.55 UNK6K54.4 ; 197.37,184.55 UNK6K24.3 ; 197.37,184.55 UNK6K53.3
S6_SDA_F: length 29.7
  TOP w0.305: 190.56,203.59 190.3,203.85 SITE6.14_F
  TOP w0.635: 191.18,184.3 192.78,185.9 192.78,187.71 194.82,189.75 194.82,199.33 190.56,203.59
  BOTTOM w0.559: 189.12,184.55 UNK6K51.3 ; 189.12,184.55 UNK6K52.4 ; 189.12,184.55 UNK6K23.3
S6_SRD_F: length 5
  BOTTOM w0.508: UNK6K56.3 174.34,229.94 UNK6K1.3
  vias: v2(178.97,211.91) v2(182.87,213.02) v2(187.05,209.24)
S6_SRD_S: length 27.2
  TOP w0.203: v1(182.87,226.99) 181.76,225.88 181.76,215.53 187.45,209.84 SITE6.1_S
  BOTTOM w0.203: UNK6K1.6 182.87,229.59 v1(182.87,226.99)
S6_SRG_F: length 0.7
  TOP w0.305: SITE6.4_F 186.95,207.74 186.65,208.04 v2(186.65,208.24)
  vias: v1(164.32,232.85)
S7_C1B_F: length 8.9
  TOP w0.305: 232.36,205.43 SITE7.17_F
  TOP w0.635: v1(239.27,201.77) 236.32,201.77 232.65,205.43 232.36,205.43
  vias: v1(210.92,232.85)
S7_IS1N_F: length 7
  TOP w0.305: SITE7.12_F 229.35,204.94 229.35,203.53 229.61,203.28
  TOP w0.635: v1(233.17,199.72) 232.91,199.72 229.61,203.02 229.61,203.28
  vias: v1(237.71,173.69)
S7_IS1P_F: length 8.2
  TOP w0.305: 228.66,203.21 228.8,203.35 SITE7.11_F
  TOP w0.635: 228.66,203.21 228.66,202.31 231.91,199.06 v1(231.91,198.18)
  vias: v1(236.48,173.69)
S7_IS2N_F: length 5.8
  TOP w0.305: SITE7.10_F 228.3,204.51 228.08,204.29 228.08,204.03
  TOP w0.635: v1(228.22,199.72) 227.57,200.36 227.57,203.53 228.08,204.03
  vias: v1(232.63,173.69)
S7_IS2P_F: length 7.5
  TOP w0.305: 227.57,204.76 SITE7.9_F
  TOP w0.635: 227.57,204.76 226.56,203.75 226.56,198.58 v1(226.96,198.18)
  vias: v1(231.4,173.69)
S7_SCL_F: length 30.3
  TOP w0.305: 231.64,203.91 230.8,204.74 SITE7.15_F
  TOP w0.635: 231.64,203.91 235.72,199.82 235.72,187.28 238.71,184.3 239.44,184.3
  BOTTOM w0.559: 237.37,184.55 UNK7K54.4 ; 237.37,184.55 UNK7K24.3 ; 237.37,184.55 UNK7K53.3
S7_SDA_F: length 29.7
  TOP w0.305: 230.56,203.59 230.3,203.85 SITE7.14_F
  TOP w0.635: 230.56,203.59 234.82,199.33 234.82,189.75 232.78,187.71 232.78,185.9 231.18,184.3
  BOTTOM w0.559: 229.12,184.55 UNK7K23.3 ; 229.12,184.55 UNK7K51.3 ; 229.12,184.55 UNK7K52.4
S7_SRD_F: length 5
  BOTTOM w0.508: UNK7K1.3 214.34,229.94 UNK7K56.3
  vias: v2(218.97,211.91) v2(222.87,213.02) v2(227.05,209.24)
S7_SRD_S: length 27.2
  TOP w0.203: SITE7.1_S 227.45,209.84 221.76,215.53 221.76,225.88 v1(222.87,226.99)
  BOTTOM w0.203: UNK7K1.6 222.87,229.59 v1(222.87,226.99)
S7_SRG_F: length 0.7
  TOP w0.305: SITE7.4_F 226.95,207.74 226.65,208.04 v2(226.65,208.24)
  vias: v1(204.32,232.85)
S8_C1B_F: length 8.9
  TOP w0.305: 272.36,205.43 SITE8.17_F
  TOP w0.635: 272.36,205.43 272.65,205.43 276.32,201.77 v1(279.27,201.77)
  vias: v1(250.92,232.85)
S8_IS1N_F: length 7
  TOP w0.305: 269.61,203.28 269.35,203.53 269.35,204.94 SITE8.12_F
  TOP w0.635: 269.61,203.28 269.61,203.02 272.91,199.72 v1(273.17,199.72)
  vias: v1(277.71,173.69)
S8_IS1P_F: length 8.2
  TOP w0.305: 268.66,203.21 268.8,203.35 SITE8.11_F
  TOP w0.635: 268.66,203.21 268.66,202.31 271.91,199.06 v1(271.91,198.18)
  vias: v1(276.48,173.69)
S8_IS2N_F: length 5.8
  TOP w0.305: SITE8.10_F 268.3,204.51 268.08,204.29 268.08,204.03
  TOP w0.635: 268.08,204.03 267.57,203.53 267.57,200.36 v1(268.22,199.72)
  vias: v1(272.63,173.69)
S8_IS2P_F: length 7.5
  TOP w0.305: 267.57,204.76 SITE8.9_F
  TOP w0.635: 267.57,204.76 266.56,203.75 266.56,198.58 v1(266.96,198.18)
  vias: v1(271.4,173.69)
S8_SCL_F: length 30.3
  TOP w0.305: SITE8.15_F 270.8,204.74 271.64,203.91
  TOP w0.635: 271.64,203.91 275.72,199.82 275.72,187.28 278.71,184.3 279.44,184.3
  BOTTOM w0.559: UNK8K24.3 277.37,184.55 ; 277.37,184.55 UNK8K53.3 ; 277.37,184.55 UNK8K54.4
S8_SDA_F: length 29.7
  TOP w0.305: 270.56,203.59 270.3,203.85 SITE8.14_F
  TOP w0.635: 270.56,203.59 274.82,199.33 274.82,189.75 272.78,187.71 272.78,185.9 271.18,184.3
  BOTTOM w0.559: UNK8K52.4 269.12,184.55 ; 269.12,184.55 UNK8K51.3 ; 269.12,184.55 UNK8K23.3
S8_SRD_F: length 5
  BOTTOM w0.508: UNK8K56.3 254.34,229.94 UNK8K1.3
  vias: v2(258.97,211.91) v2(262.87,213.02) v2(267.05,209.24)
S8_SRD_S: length 27.2
  TOP w0.203: SITE8.1_S 267.45,209.84 261.76,215.53 261.76,225.88 v1(262.87,226.99)
  BOTTOM w0.203: v1(262.87,226.99) 262.87,229.59 UNK8K1.6
S8_SRG_F: length 0.7
  TOP w0.305: SITE8.4_F 266.95,207.74 266.65,208.04 v2(266.65,208.24)
  vias: v1(244.32,232.85)
SDUP5V_FILTER: length 20.8
  BOTTOM w0.381: U2.5 v1(129.92,294.89) ; UNK7U2.5 v1(209.92,234.89) ; U1.5 v1(123.3,294.89) ; UNK8U1.5 v1(243.3,234.89) ; UNK4U2.5 v1(249.92,294.89) ; UNK4U1.5 v1(243.3,294.89) ; UNK2U1.5 v1(163.3,294.89) ; UNK5U2.5 v1(129.92,234.89) ; UNK6U2.5 v1(169.92,234.89) ; UNK5U1.5 v1(123.3,234.89) ; UNK3U2.5 v1(209.92,294.89) ; UNK7U1.5 v1(203.3,234.89) ; UNK6U1.5 v1(163.3,234.89) ; UNK8U2.5 v1(249.92,234.89) ; UNK2U2.5 v1(169.92,294.89) ; UNK3U1.5 v1(203.3,294.89)
SDUR5V_FILTER:
  vias: v1(120.9,288.4) v1(120.9,228.4) v1(121.16,292.85) v1(121.16,232.85) v1(127.76,292.85) v1(127.76,232.85) v1(131.02,269.99) v1(131.02,209.99) v1(131.95,262.12) v1(131.95,202.12) v1(133.1,264.66) v1(133.1,204.66) v1(137.67,269.49) v1(137.67,266.69) v1(137.67,264.66) v1(137.67,262.12) v1(137.67,209.49) v1(137.67,206.69) v1(137.67,204.66) v1(137.67,202.12) v1(140.97,297.93) v1(140.97,284.73) v1(140.97,237.93) v1(140.97,224.73) v1(143.26,255.02) v1(143.26,250.19) v1(143.26,244.22) v1(143.26,195.02) v1(143.26,190.19) v1(143.26,184.22) v1(146.06,255.02) v1(146.06,250.19) v1(146.06,195.02) v1(146.06,190.19) v1(148.22,255.02) v1(148.22,250.19) v1(148.22,238.89) v1(148.22,195.02) v1(148.22,190.19) v1(148.22,178.89) v1(148.33,287.27) v1(148.33,281.43) v1(148.33,227.27) v1(148.33,221.43) v1(149.22,248.79) v1(149.22,188.79) v1(150.74,287.27) v1(150.74,282.7) v1(150.74,276.86) v1(150.74,227.27) v1(150.74,222.7) v1(150.74,216.86) v1(151.01,255.02) v1(151.01,250.19) v1(151.01,195.02) v1(151.01,190.19) v1(151.5,236.86) v1(151.5,176.86) v1(153.15,285.75) v1(153.15,281.18) v1(153.15,275.34) v1(153.17,255.02) v1(153.17,250.19) v1(153.15,225.75) v1(153.15,221.18) v1(153.15,215.34) v1(153.17,195.02) v1(153.17,190.19) v1(153.54,236.86) v1(153.54,176.86) v1(156.08,284.48) v1(156.08,279.91) v1(156.08,275.34) v1(156.08,224.48) v1(156.08,219.91) v1(156.08,215.34) v1(156.47,255.02) v1(156.47,250.19) v1(156.47,238.89) v1(156.47,195.02) v1(156.47,190.19) v1(156.47,178.89) v1(156.58,236.86) v1(156.58,176.86) v1(157.47,248.79) v1(157.47,188.79) v1(158.62,236.86) v1(158.62,176.86) v1(160.9,288.4) v1(160.9,228.4) v1(161.16,292.85) v1(161.16,232.85) v1(162.43,273.31) v1(162.43,270.77) v1(162.43,267.72) v1(162.43,264.68) v1(162.43,260.87) v1(162.43,213.31) v1(162.43,210.77) v1(162.43,207.72) v1(162.43,204.68) v1(162.43,200.87) v1(167,273.31) v1(167,270.77) v1(167,267.72) v1(167,264.68) v1(167,260.87) v1(167,213.31) v1(167,210.77) v1(167,207.72) v1(167,204.68) v1(167,200.87) v1(167.76,292.85) v1(167.76,232.85) v1(169.17,266.7) v1(169.17,262.89) v1(169.17,206.7) v1(169.17,202.89) v1(171.02,269.99) v1(171.02,209.99) v1(171.58,267.72) v1(171.58,207.72) v1(171.95,262.12) v1(171.95,202.12) v1(173.1,264.66) v1(173.1,204.66) v1(177.67,269.49) v1(177.67,266.69) v1(177.67,264.66) v1(177.67,262.12) v1(177.67,209.49) v1(177.67,206.69) v1(177.67,204.66) v1(177.67,202.12) v1(180.97,297.93) v1(180.97,284.73) v1(180.97,237.93) v1(180.97,224.73) v1(183.26,255.02) v1(183.26,250.19) v1(183.26,244.22) v1(183.26,195.02) v1(183.26,190.19) v1(183.26,184.22) v1(186.06,255.02) v1(186.06,250.19) v1(186.06,195.02) v1(186.06,190.19) v1(188.22,255.02) v1(188.22,250.19) v1(188.22,238.89) v1(188.22,195.02) v1(188.22,190.19) v1(188.22,178.89) v1(188.33,287.27) v1(188.33,281.43) v1(188.33,227.27) v1(188.33,221.43) v1(189.22,248.79) v1(189.22,188.79) v1(190.74,287.27) v1(190.74,282.7) v1(190.74,276.86) v1(190.74,227.27) v1(190.74,222.7) v1(190.74,216.86) v1(191.01,255.02) v1(191.01,250.19) v1(191.01,195.02) v1(191.01,190.19) v1(191.5,236.86) v1(191.5,176.86) v1(193.15,285.75) v1(193.15,281.18) v1(193.15,275.34) v1(193.17,255.02) v1(193.17,250.19) v1(193.15,225.75) v1(193.15,221.18) v1(193.15,215.34) v1(193.17,195.02) v1(193.17,190.19) v1(193.54,236.86) v1(193.54,176.86) v1(196.08,284.48) v1(196.08,279.91) v1(196.08,275.34) v1(196.08,224.48) v1(196.08,219.91) v1(196.08,215.34) v1(196.47,255.02) v1(196.47,250.19) v1(196.47,238.89) v1(196.47,195.02) v1(196.47,190.19) v1(196.47,178.89) v1(196.58,236.86) v1(196.58,176.86) v1(197.47,248.79) v1(197.47,188.79) v1(198.62,236.86) v1(198.62,176.86) v1(200.9,288.4) v1(200.9,228.4) v1(201.16,292.85) v1(201.16,232.85) v1(202.43,273.31) v1(202.43,270.77) v1(202.43,267.72) v1(202.43,264.68) v1(202.43,260.87) v1(202.43,213.31) v1(202.43,210.77) v1(202.43,207.72) v1(202.43,204.68) v1(202.43,200.87) v1(207,273.31) v1(207,270.77) v1(207,267.72) v1(207,264.68) v1(207,260.87) v1(207,213.31) v1(207,210.77) v1(207,207.72) v1(207,204.68) v1(207,200.87) v1(207.76,292.85) v1(207.76,232.85) v1(209.17,266.7) v1(209.17,262.89) v1(209.17,206.7) v1(209.17,202.89) v1(211.02,269.99) v1(211.02,209.99) v1(211.58,267.72) v1(211.58,207.72) v1(211.95,262.12) v1(211.95,202.12) v1(213.1,264.66) v1(213.1,204.66) v1(217.67,269.49) v1(217.67,266.69) v1(217.67,264.66) v1(217.67,262.12) v1(217.67,209.49) v1(217.67,206.69) v1(217.67,204.66) v1(217.67,202.12) v1(220.97,297.93) v1(220.97,284.73) v1(220.97,237.93) v1(220.97,224.73) v1(223.26,255.02) v1(223.26,250.19) v1(223.26,244.22) v1(223.26,195.02) v1(223.26,190.19) v1(223.26,184.22) v1(226.06,255.02) v1(226.06,250.19) v1(226.06,195.02) v1(226.06,190.19) v1(228.22,255.02) v1(228.22,250.19) v1(228.22,238.89) v1(228.22,195.02) v1(228.22,190.19) v1(228.22,178.89) v1(228.33,287.27) v1(228.33,281.43) v1(228.33,227.27) v1(228.33,221.43) v1(229.22,248.79) v1(229.22,188.79) v1(230.74,287.27) v1(230.74,282.7) v1(230.74,276.86) v1(230.74,227.27) v1(230.74,222.7) v1(230.74,216.86) v1(231.01,255.02) v1(231.01,250.19) v1(231.01,195.02) v1(231.01,190.19) v1(231.5,236.86) v1(231.5,176.86) v1(233.15,285.75) v1(233.15,281.18) v1(233.15,275.34) v1(233.17,255.02) v1(233.17,250.19) v1(233.15,225.75) v1(233.15,221.18) v1(233.15,215.34) v1(233.17,195.02) v1(233.17,190.19) v1(233.53,236.86) v1(233.53,176.86) v1(236.07,284.48) v1(236.07,279.91) v1(236.07,275.34) v1(236.07,224.48) v1(236.07,219.91) v1(236.07,215.34) v1(236.47,255.02) v1(236.47,250.19) v1(236.47,238.89) v1(236.47,195.02) v1(236.47,190.19) v1(236.47,178.89) v1(236.58,236.86) v1(236.58,176.86) v1(237.47,248.79) v1(237.47,188.79) v1(238.61,236.86) v1(238.61,176.86) v1(240.9,288.4) v1(240.9,228.4) v1(241.16,292.85) v1(241.16,232.85) v1(242.43,273.31) v1(242.43,270.77) v1(242.43,267.72) v1(242.43,264.68) v1(242.43,260.87) v1(242.43,213.31) v1(242.43,210.77) v1(242.43,207.72) v1(242.43,204.68) v1(242.43,200.87) v1(247,273.31) v1(247,270.77) v1(247,267.72) v1(247,264.68) v1(247,260.87) v1(247,213.31) v1(247,210.77) v1(247,207.72) v1(247,204.68) v1(247,200.87) v1(247.76,292.85) v1(247.76,232.85) v1(249.17,266.7) v1(249.17,262.89) v1(249.17,206.7) v1(249.17,202.89) v1(251.02,269.99) v1(251.02,209.99) v1(251.58,267.72) v1(251.58,207.72) v1(251.95,262.12) v1(251.95,202.12) v1(253.1,264.66) v1(253.1,204.66) v1(257.67,269.49) v1(257.67,266.69) v1(257.67,264.66) v1(257.67,262.12) v1(257.67,209.49) v1(257.67,206.69) v1(257.67,204.66) v1(257.67,202.12) v1(260.97,297.93) v1(260.97,284.73) v1(260.97,237.93) v1(260.97,224.73) v1(263.26,255.02) v1(263.26,250.19) v1(263.26,244.22) v1(263.26,195.02) v1(263.26,190.19) v1(263.26,184.22) v1(266.06,255.02) v1(266.06,250.19) v1(266.06,195.02) v1(266.06,190.19) v1(268.22,255.02) v1(268.22,250.19) v1(268.22,238.89) v1(268.22,195.02) v1(268.22,190.19) v1(268.22,178.89) v1(268.33,287.27) v1(268.33,281.43) v1(268.33,227.27) v1(268.33,221.43) v1(269.22,248.79) v1(269.22,188.79) v1(270.74,287.27) v1(270.74,282.7) v1(270.74,276.86) v1(270.74,227.27) v1(270.74,222.7) v1(270.74,216.86) v1(271.01,255.02) v1(271.01,250.19) v1(271.01,195.02) v1(271.01,190.19) v1(271.5,236.86) v1(271.5,176.86) v1(273.15,285.75) v1(273.15,281.18) v1(273.15,275.34) v1(273.17,255.02) v1(273.17,250.19) v1(273.15,225.75) v1(273.15,221.18) v1(273.15,215.34) v1(273.17,195.02) v1(273.17,190.19) v1(273.53,236.86) v1(273.53,176.86) v1(276.07,284.48) v1(276.07,279.91) v1(276.07,275.34) v1(276.07,224.48) v1(276.07,219.91) v1(276.07,215.34) v1(276.47,255.02) v1(276.47,250.19) v1(276.47,238.89) v1(276.47,195.02) v1(276.47,190.19) v1(276.47,178.89) v1(276.58,236.86) v1(276.58,176.86) v1(277.47,248.79) v1(277.47,188.79) v1(278.61,236.86) v1(278.61,176.86) v1(282.43,273.31) v1(282.43,270.77) v1(282.43,267.72) v1(282.43,264.68) v1(282.43,260.87) v1(282.43,213.31) v1(282.43,210.77) v1(282.43,207.72) v1(282.43,204.68) v1(282.43,200.87) v1(287,273.31) v1(287,270.77) v1(287,267.72) v1(287,264.68) v1(287,260.87) v1(287,213.31) v1(287,210.77) v1(287,207.72) v1(287,204.68) v1(287,200.87) v1(289.17,266.7) v1(289.17,262.89) v1(289.17,206.7) v1(289.17,202.89) v1(291.58,267.72) v1(291.58,207.72)
SL01_VI100_2_A_HF: length 11.5
  TOP w0.305: SITE1.2_F 146.18,268.74
  TOP w0.635: 146.18,268.74 140.98,268.74 v1(140.83,268.59)
  BOTTOM w0.635: v1(140.83,268.59) 139.83,267.59 136.82,267.59 C49.2
SL01_VI100_2_A_HS: length 7.8
  BOTTOM w0.203: v1(140.83,265.79) 141.97,265.79 144.92,268.74 v2(147.45,268.74)
SL01_VI100_2_B_HF: length 9.3
  TOP w0.305: 149.94,271.84 149.31,271.21 149.31,271.02 149.29,271 149.29,270.58 149.31,270.56 149.31,270.3 149.3,270.29 SITE1.29_F
  TOP w0.635: v1(152.25,278.02) 151.49,277.25 151.49,273.39 149.94,271.84
SL01_VI100_2_B_HS: length 14.3
  BOTTOM w0.203: v2(149.3,269.59) 149.21,269.68 149.21,270.84 151.38,273.02 151.38,281.72 v1(152.25,282.59)
SL01_VI100_3_A_HF: length 16.3
  TOP w0.305: SITE1.5_F 145.45,267.24
  TOP w0.635: 145.45,267.24 143.13,264.92 143.13,263.52 v1(140.83,261.22)
  BOTTOM w0.635: v1(135.11,261.22) 135.11,260.93 135.75,260.3 140.19,260.3 140.83,260.93 v1(140.83,261.22)
SL01_VI100_3_A_HS: length 13.4
  BOTTOM w0.203: v1(136.26,263.76) 137.13,262.89 142.62,262.89 146.97,267.24 v2(147.45,267.24)
SL01_VI100_3_B_HS: length 13
  BOTTOM w0.203: v2(148.3,265.39) 148.3,261.78 149.86,260.22 149.86,254.09 v1(149.12,253.35)
SL01_VI100_4_A_HS: length 8.3
  BOTTOM w0.203: v2(147.45,267.74) 145.82,267.74 141.84,263.76 v1(140.83,263.76)
SL01_VI100_4_B_HS: length 13.8
  BOTTOM w0.203: v2(151.65,265.74) 153.98,263.42 162.2,263.42 v1(163.84,261.77)
SL01_VI100_5_A_HF: length 23.1
  TOP w0.305: SITE1.6_F 146.47,266.74 146.18,266.45
  TOP w0.635: 146.18,266.45 144.16,264.43 v1(144.16,258.18)
  BOTTOM w0.508: 144.39,253.35 K12.4
  BOTTOM w0.635: 145.18,253.35 144.39,253.35 ; 145.18,253.35 145.18,257.54 144.54,258.18 v1(144.16,258.18) ; 145.18,253.35 145.18,248.1 144.45,247.38 144.21,247.38
SL01_VI100_5_A_HS:
  vias: v2(147.45,266.74)
SL01_VI100_6_A_HF:
  vias: v2(147.05,266.24)
SL01_VI100_6_A_HS:
  vias: v1(146.96,253.35) v2(147.45,266.24)
SL01_VI100_6_B_HF: length 1.7
  TOP w0.305: SITE1.30_F v2(148.8,271.66)
SL01_VI100_6_B_HS: length 4.5
  BOTTOM w0.203: v2(148.8,269.59) 148.8,271.01 149.84,272.05 K46.4
SL01_VI100_7_A_HF:
  vias: v2(149.8,264.99)
SL01_VI100_7_A_HS:
  vias: v1(154.07,253.35) v2(149.8,265.39)
SL01_VI100_7_B_HF: length 10.4
  TOP w0.305: SITE1.31_F 148.3,270.29 148.29,270.3 148.29,270.82 148.07,271.04
  TOP w0.635: v1(149.84,279.54) 149.08,278.78 149.08,273.58 148.07,272.57 148.07,271.04
SL01_VI100_7_B_HS: length 15.2
  BOTTOM w0.203: v1(149.84,284.11) 149.05,283.33 149.05,272.6 148.3,271.84 v2(148.3,269.59)
SL01_VI100_8_B_HF: length 5.7
  TOP w0.305: SITE1.20_F 154.73,267.24 155.04,266.93
  TOP w0.635: v1(156.03,265.94) 155.04,266.93
  BOTTOM w0.635: v1(156.03,265.94) C61.2
SL01_VI100_8_B_HS: length 17.5
  BOTTOM w0.203: v1(168.42,265.58) 166.93,267.06 154.7,267.06 154.53,267.24 v2(151.65,267.24)
SL01_VI100_9_B_HF: length 7.6
  TOP w0.305: 154.28,267.99 154.03,267.74 SITE1.21_F
  TOP w0.635: v1(159.27,268.62) 158.64,267.99 154.28,267.99
SL01_VI100_9_B_HS: length 13.3
  BOTTOM w0.203: v1(163.84,268.62) 162.97,269.49 156.34,269.49 154.58,267.74 v2(151.65,267.74)
SL01_VI100_10_A_HF: length 9.6
  TOP w0.305: SITE1.16_F 151.55,264.74 151.98,264.74
  TOP w0.635: v1(157.37,258.18) 156.72,258.83 156.72,260.01 151.98,264.74
SL01_VI100_10_A_HS: length 15.2
  BOTTOM w0.203: v1(157.37,253.35) 157.37,254.05 157.17,254.25 156.08,254.25 155.83,254.51 155.83,260.6 151.3,265.13 v2(151.3,265.39)
SL01_VI100_10_B_HF: length 0.4
  TOP w0.305: SITE1.25_F v2(151.3,270.39)
SL01_VI100_10_B_HS: length 5.7
  BOTTOM w0.203: v1(155.17,272.17) 155.17,270.87 153.95,269.65 151.36,269.65 v2(151.3,269.59)
SL01_VI100_11_A_HF: length 7.2
  TOP w0.305: 153.62,265.67 153.05,266.24 SITE1.18_F
  TOP w0.635: v1(157.73,262.67) 156.62,262.67 153.62,265.67
SL01_VI100_11_A_HS: length 18.6
  BOTTOM w0.203: v1(168.42,261.77) 166.28,263.91 154.31,263.91 151.97,266.24 v2(151.65,266.24)
SL01_VI100_11_B_HF: length 0.4
  TOP w0.305: SITE1.26_F v2(150.8,270.39)
SL01_VI100_11_B_HS: length 10.5
  BOTTOM w0.203: v2(150.8,269.59) 150.8,269.67 151.16,270.03 151.57,270.03 151.7,270.16 153.88,270.16 154.43,270.7 154.43,276 v1(155.17,276.75)
SL01_VI100_12_A_HF: length 8.2
  TOP w0.305: 154.31,266.19 154.13,266.19 153.59,266.74 SITE1.19_F
  TOP w0.635: 154.31,266.19 155.58,264.92 158.62,264.92 v1(159.27,265.58)
SL01_VI100_12_A_HS: length 12.7
  BOTTOM w0.203: v1(163.84,265.58) 162.84,266.58 154.43,266.58 154.27,266.74 v2(151.65,266.74)
SL01_VI100_12_B_HF: length 1.1
  TOP w0.305: v2(149.8,270.79) 150,270.79 150.3,270.49 SITE1.27_F
SL01_VI100_12_B_HS: length 15.4
  BOTTOM w0.152: 150.71,270.8 150.44,270.53 150.44,269.73 v2(150.3,269.59)
  BOTTOM w0.203: 150.71,270.8 153.5,270.8 154.03,271.32 154.03,276.17 154.05,276.2 154.05,280.2 v1(155.17,281.32)
SL01_VI100_13_A_HF: length 8.4
  TOP w0.305: 153.66,268.65 153.26,268.25 152.44,268.25 152.44,268.24 SITE1.22_F
  TOP w0.635: 153.66,268.65 153.99,268.98 157.62,268.98 v1(157.73,268.86)
  BOTTOM w0.635: C64.2 156.03,268.22 156.67,268.86 v1(157.73,268.86)
SL01_VI100_13_A_HS: length 18.1
  BOTTOM w0.203: v2(151.65,268.24) 154.45,268.24 156.21,270 167.04,270 v1(168.42,268.62)
SL01_VI100_13_B_HF: length 0.4
  TOP w0.305: SITE1.32_F v2(147.8,270.39)
  vias: v1(147.43,284.11)
SL01_VI100_13_B_HS: length 9.9
  BOTTOM w0.203: v2(147.8,269.59) 147.8,269.86 147.33,270.33 147.33,271.45 148.59,272.71 148.59,275.84 147.43,277.01 v1(147.43,278.27)
SL01_VI100_14_A_HF: length 8.4
  TOP w0.305: SITE1.23_F 152.52,268.74 152.97,269.19
  TOP w0.635: v1(159.27,271.67) 157.57,269.97 153.75,269.97 152.97,269.19
SL01_VI100_14_A_HS: length 14.9
  BOTTOM w0.203: v1(163.84,271.67) 162.85,272.67 157.43,272.67 157.12,272.36 157.12,271.23 156.59,270.7 156.27,270.7 154.31,268.74 v2(151.65,268.74)
SL01_VI100_14_B_HS: length 9.2
  BOTTOM w0.203: v1(154.07,258.18) 154.07,259.95 149.3,264.72 v2(149.3,265.39)
SL01_VI100_15_A_HF: length 10
  TOP w0.305: SITE1.24_F 152.05,269.58 152.28,269.81
  TOP w0.635: 152.28,269.81 153.39,270.92 155.98,270.92 156.98,271.92 156.98,272.77 157.62,273.41 158.47,273.41 v1(159.27,274.21)
SL01_VI100_15_A_HS: length 17.3
  BOTTOM w0.203: v2(151.65,269.24) 154.18,269.24 156.08,271.14 156.46,271.14 156.72,271.4 156.72,275.08 156.97,275.34 162.72,275.34 v1(163.84,274.21)
SL01_VI100_15_B_HS: length 13.9
  BOTTOM w0.203: v1(151.91,253.35) 151.91,253.85 151.51,254.25 150.57,254.25 150.36,254.46 150.36,260.61 148.8,262.17 v2(148.8,265.39)
SL01_VI100_16_A_HF: length 0.4
  TOP w0.305: SITE1.28_F v2(149.8,270.39)
SL01_VI100_16_A_HS: length 4.1
  BOTTOM w0.152: v2(149.8,269.59) 149.8,269.74 150.14,270.08 150.14,270.86 150.25,270.97
  BOTTOM w0.203: 150.25,270.97 150.49,271.2 151.28,271.2 v1(152.25,272.17)
SL01_VI100_16_B_HS: length 7.8
  BOTTOM w0.203: v2(147.8,265.39) 147.8,261.39 149.12,260.08 v1(149.12,258.18)
SL01_VI100_18_A_HF: length 11.5
  TOP w0.305: SITE3.2_F 226.18,268.74
  TOP w0.635: v1(220.83,268.59) 220.98,268.74 226.18,268.74
  BOTTOM w0.635: v1(220.83,268.59) 219.83,267.59 216.82,267.59 UNK3C49.2
SL01_VI100_18_A_HS: length 7.8
  BOTTOM w0.203: v2(227.45,268.74) 224.92,268.74 221.97,265.79 v1(220.83,265.79)
SL01_VI100_18_B_HF: length 9.3
  TOP w0.305: 229.94,271.84 229.31,271.21 229.31,271.02 229.29,271 229.29,270.58 229.31,270.56 229.31,270.3 229.3,270.29 SITE3.29_F
  TOP w0.635: 229.94,271.84 231.49,273.39 231.49,277.25 v1(232.25,278.02)
SL01_VI100_18_B_HS: length 14.3
  BOTTOM w0.203: v2(229.3,269.59) 229.21,269.68 229.21,270.84 231.38,273.02 231.38,281.72 v1(232.25,282.59)
SL01_VI100_19_A_HF: length 16.3
  TOP w0.305: SITE3.5_F 225.45,267.24
  TOP w0.635: v1(220.83,261.22) 223.13,263.52 223.13,264.92 225.45,267.24
  BOTTOM w0.635: v1(220.83,261.22) 220.83,260.93 220.19,260.3 215.75,260.3 215.11,260.93 v1(215.11,261.22)
SL01_VI100_19_A_HS: length 13.4
  BOTTOM w0.203: v1(216.26,263.76) 217.13,262.89 222.62,262.89 226.97,267.24 v2(227.45,267.24)
SL01_VI100_19_B_HS: length 13
  BOTTOM w0.203: v1(229.12,253.35) 229.86,254.09 229.86,260.22 228.3,261.78 v2(228.3,265.39)
SL01_VI100_20_A_HS: length 8.3
  BOTTOM w0.203: v2(227.45,267.74) 225.82,267.74 221.84,263.76 v1(220.83,263.76)
SL01_VI100_20_B_HS: length 13.8
  BOTTOM w0.203: v2(231.65,265.74) 233.97,263.42 242.19,263.42 v1(243.84,261.77)
SL01_VI100_21_A_HF: length 23.1
  TOP w0.305: 226.18,266.45 226.47,266.74 SITE3.6_F
  TOP w0.635: v1(224.16,258.18) 224.16,264.43 226.18,266.45
  BOTTOM w0.508: 224.38,253.35 UNK3K12.4
  BOTTOM w0.635: v1(224.16,258.18) 224.54,258.18 225.18,257.54 225.18,253.35 ; 225.18,253.35 225.18,248.1 224.45,247.38 224.21,247.38 ; 225.18,253.35 224.38,253.35
SL01_VI100_21_A_HS:
  vias: v2(227.45,266.74)
SL01_VI100_22_A_HF:
  vias: v2(227.05,266.24)
SL01_VI100_22_A_HS:
  vias: v1(226.96,253.35) v2(227.45,266.24)
SL01_VI100_22_B_HF: length 1.7
  TOP w0.305: SITE3.30_F v2(228.8,271.66)
SL01_VI100_22_B_HS: length 4.5
  BOTTOM w0.203: v2(228.8,269.59) 228.8,271.01 229.84,272.05 UNK3K46.4
SL01_VI100_23_A_HF:
  vias: v2(229.8,264.99)
SL01_VI100_23_A_HS:
  vias: v1(234.07,253.35) v2(229.8,265.39)
SL01_VI100_23_B_HF: length 10.4
  TOP w0.305: SITE3.31_F 228.3,270.29 228.29,270.3 228.29,270.82 228.07,271.04
  TOP w0.635: 228.07,271.04 228.07,272.57 229.08,273.58 229.08,278.78 v1(229.84,279.54)
SL01_VI100_23_B_HS: length 15.2
  BOTTOM w0.203: v1(229.84,284.11) 229.05,283.33 229.05,272.6 228.3,271.84 v2(228.3,269.59)
SL01_VI100_24_B_HF: length 5.7
  TOP w0.305: SITE3.20_F 234.73,267.24 235.04,266.93
  TOP w0.635: v1(236.03,265.94) 235.04,266.93
  BOTTOM w0.635: v1(236.03,265.94) UNK3C61.2
SL01_VI100_24_B_HS: length 17.5
  BOTTOM w0.203: v1(248.42,265.58) 246.93,267.06 234.7,267.06 234.53,267.24 v2(231.65,267.24)
SL01_VI100_25_B_HF: length 7.6
  TOP w0.305: SITE3.21_F 234.03,267.74 234.28,267.99
  TOP w0.635: v1(239.27,268.62) 238.64,267.99 234.28,267.99
SL01_VI100_25_B_HS: length 13.3
  BOTTOM w0.203: v1(243.84,268.62) 242.97,269.49 236.34,269.49 234.58,267.74 v2(231.65,267.74)
SL01_VI100_26_A_HF: length 9.6
  TOP w0.305: SITE3.16_F 231.55,264.74 231.98,264.74
  TOP w0.635: 231.98,264.74 236.72,260.01 236.72,258.83 v1(237.37,258.18)
SL01_VI100_26_A_HS: length 15.2
  BOTTOM w0.203: v2(231.3,265.39) 231.3,265.13 235.83,260.6 235.83,254.51 236.08,254.25 237.17,254.25 237.37,254.05 v1(237.37,253.35)
SL01_VI100_26_B_HF: length 0.4
  TOP w0.305: SITE3.25_F v2(231.3,270.39)
SL01_VI100_26_B_HS: length 5.7
  BOTTOM w0.203: v2(231.3,269.59) 231.36,269.65 233.95,269.65 235.17,270.87 v1(235.17,272.17)
SL01_VI100_27_A_HF: length 7.2
  TOP w0.305: SITE3.18_F 233.05,266.24 233.62,265.67
  TOP w0.635: 233.62,265.67 236.62,262.67 v1(237.73,262.67)
SL01_VI100_27_A_HS: length 18.6
  BOTTOM w0.203: v2(231.65,266.24) 231.97,266.24 234.3,263.91 246.28,263.91 v1(248.42,261.77)
SL01_VI100_27_B_HF: length 0.4
  TOP w0.305: SITE3.26_F v2(230.8,270.39)
SL01_VI100_27_B_HS: length 10.5
  BOTTOM w0.203: v2(230.8,269.59) 230.8,269.67 231.16,270.03 231.57,270.03 231.7,270.16 233.88,270.16 234.43,270.7 234.43,276 v1(235.17,276.75)
SL01_VI100_28_A_HF: length 8.2
  TOP w0.305: SITE3.19_F 233.59,266.74 234.13,266.19 234.3,266.19
  TOP w0.635: 234.3,266.19 235.57,264.92 238.62,264.92 v1(239.27,265.58)
SL01_VI100_28_A_HS: length 12.7
  BOTTOM w0.203: v1(243.84,265.58) 242.84,266.58 234.43,266.58 234.27,266.74 v2(231.65,266.74)
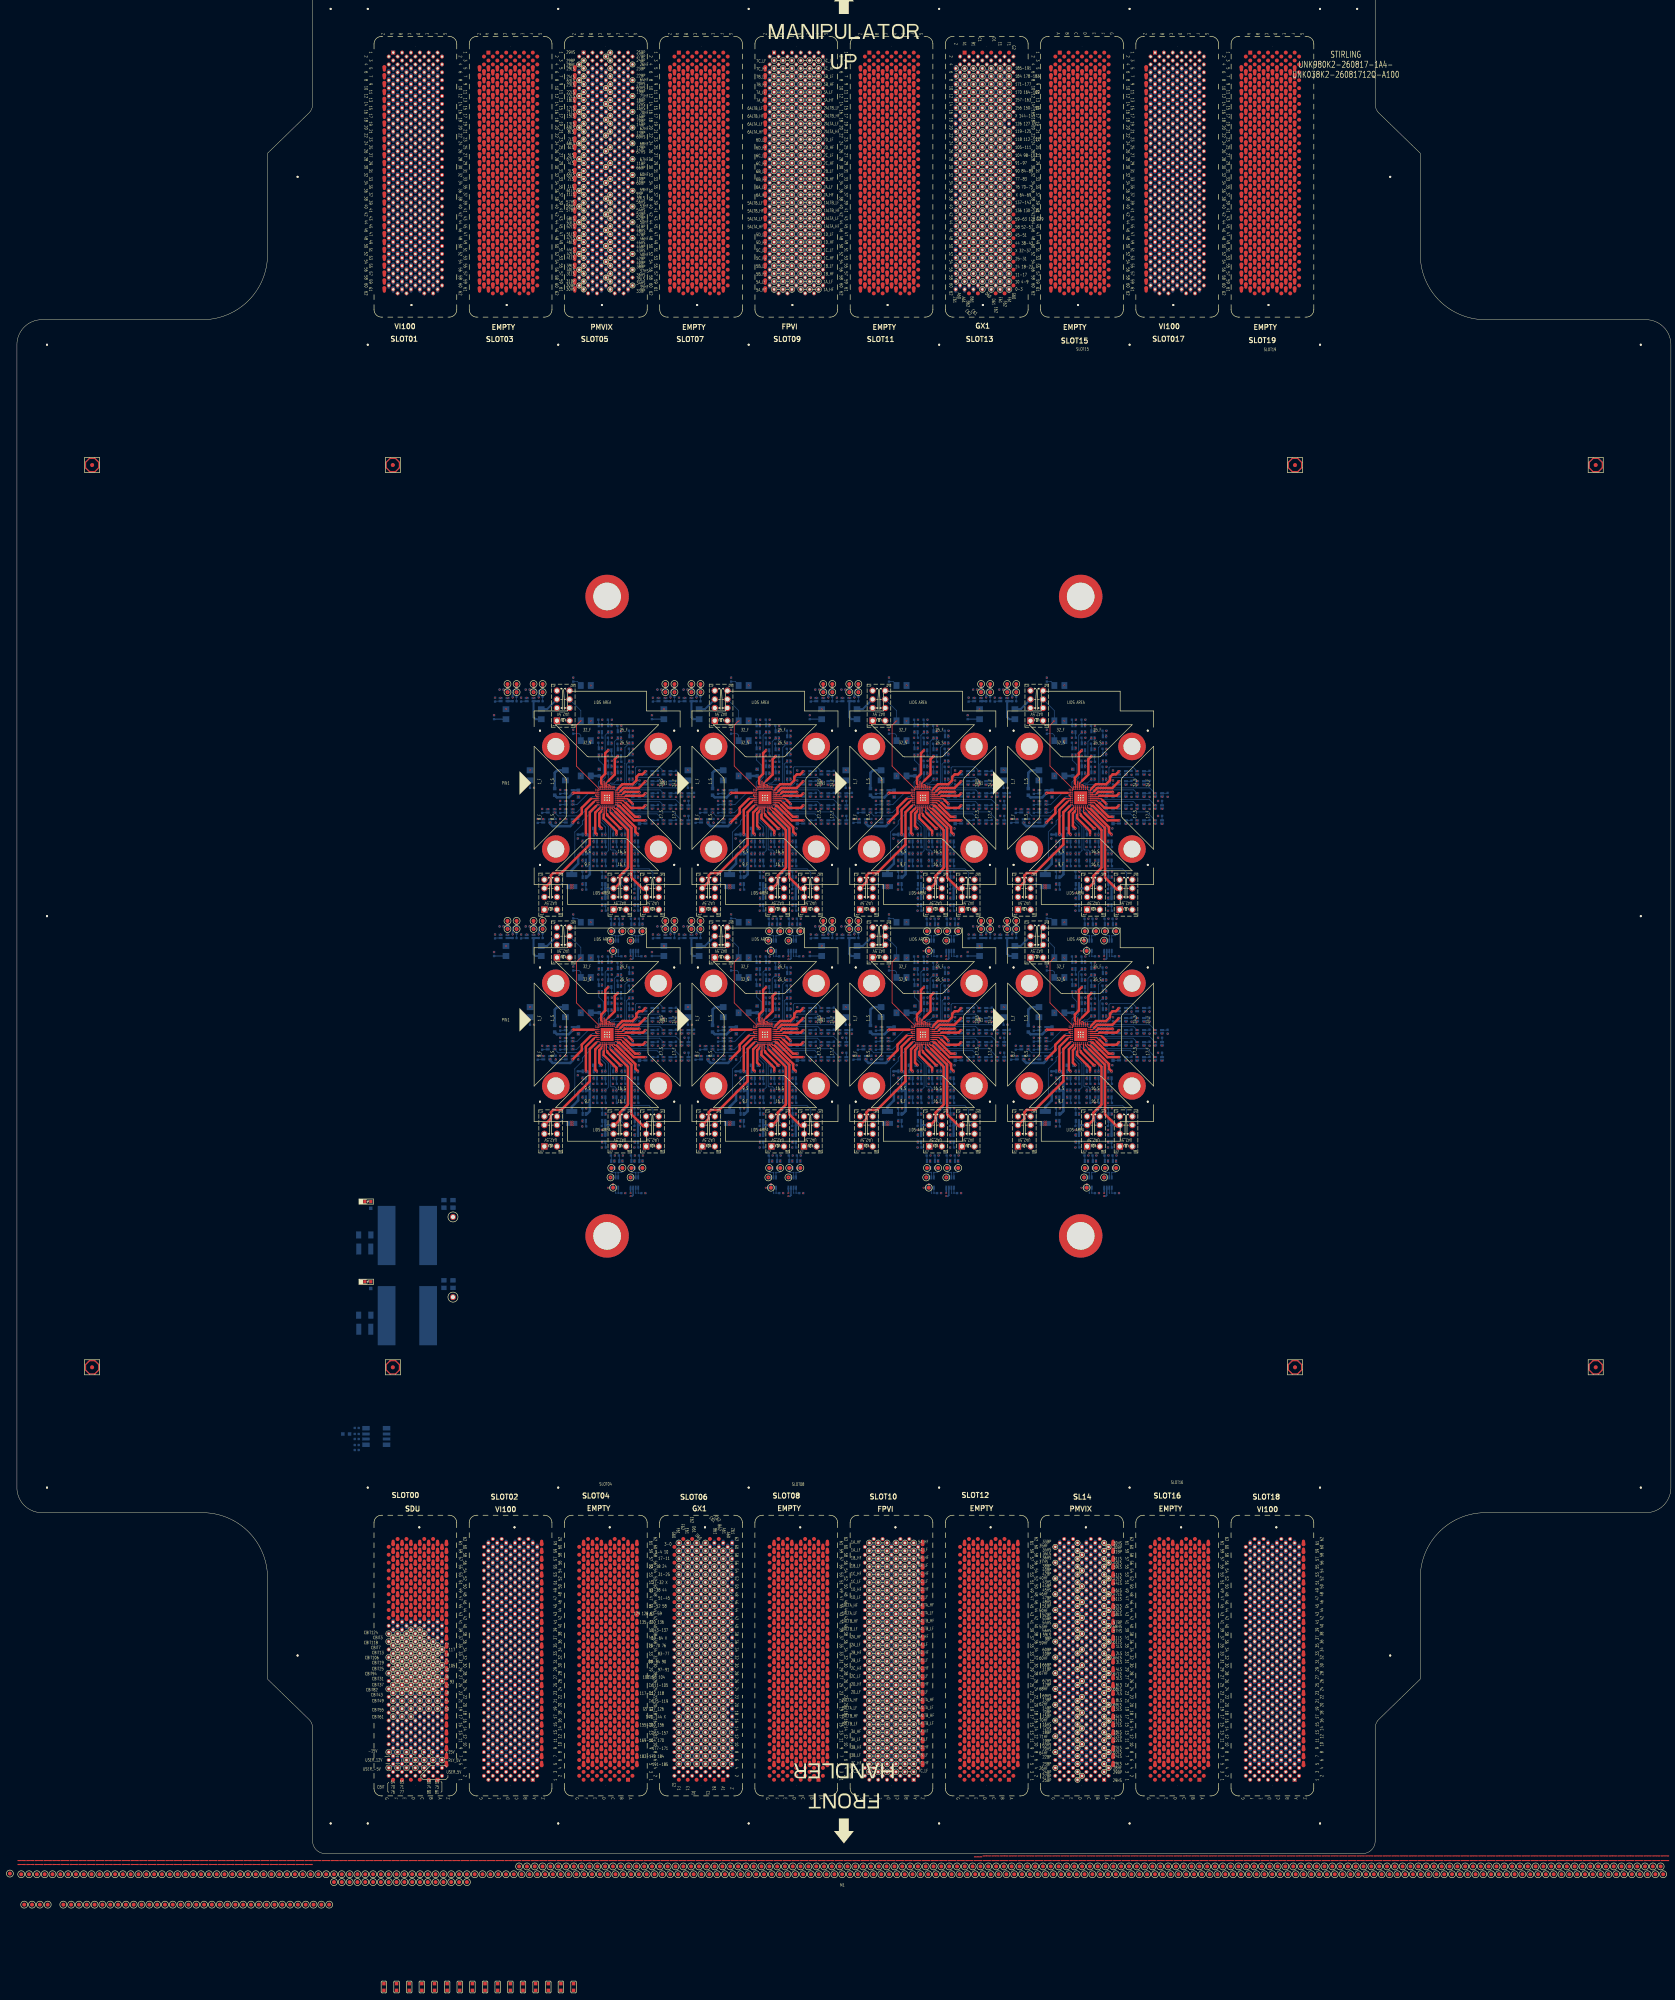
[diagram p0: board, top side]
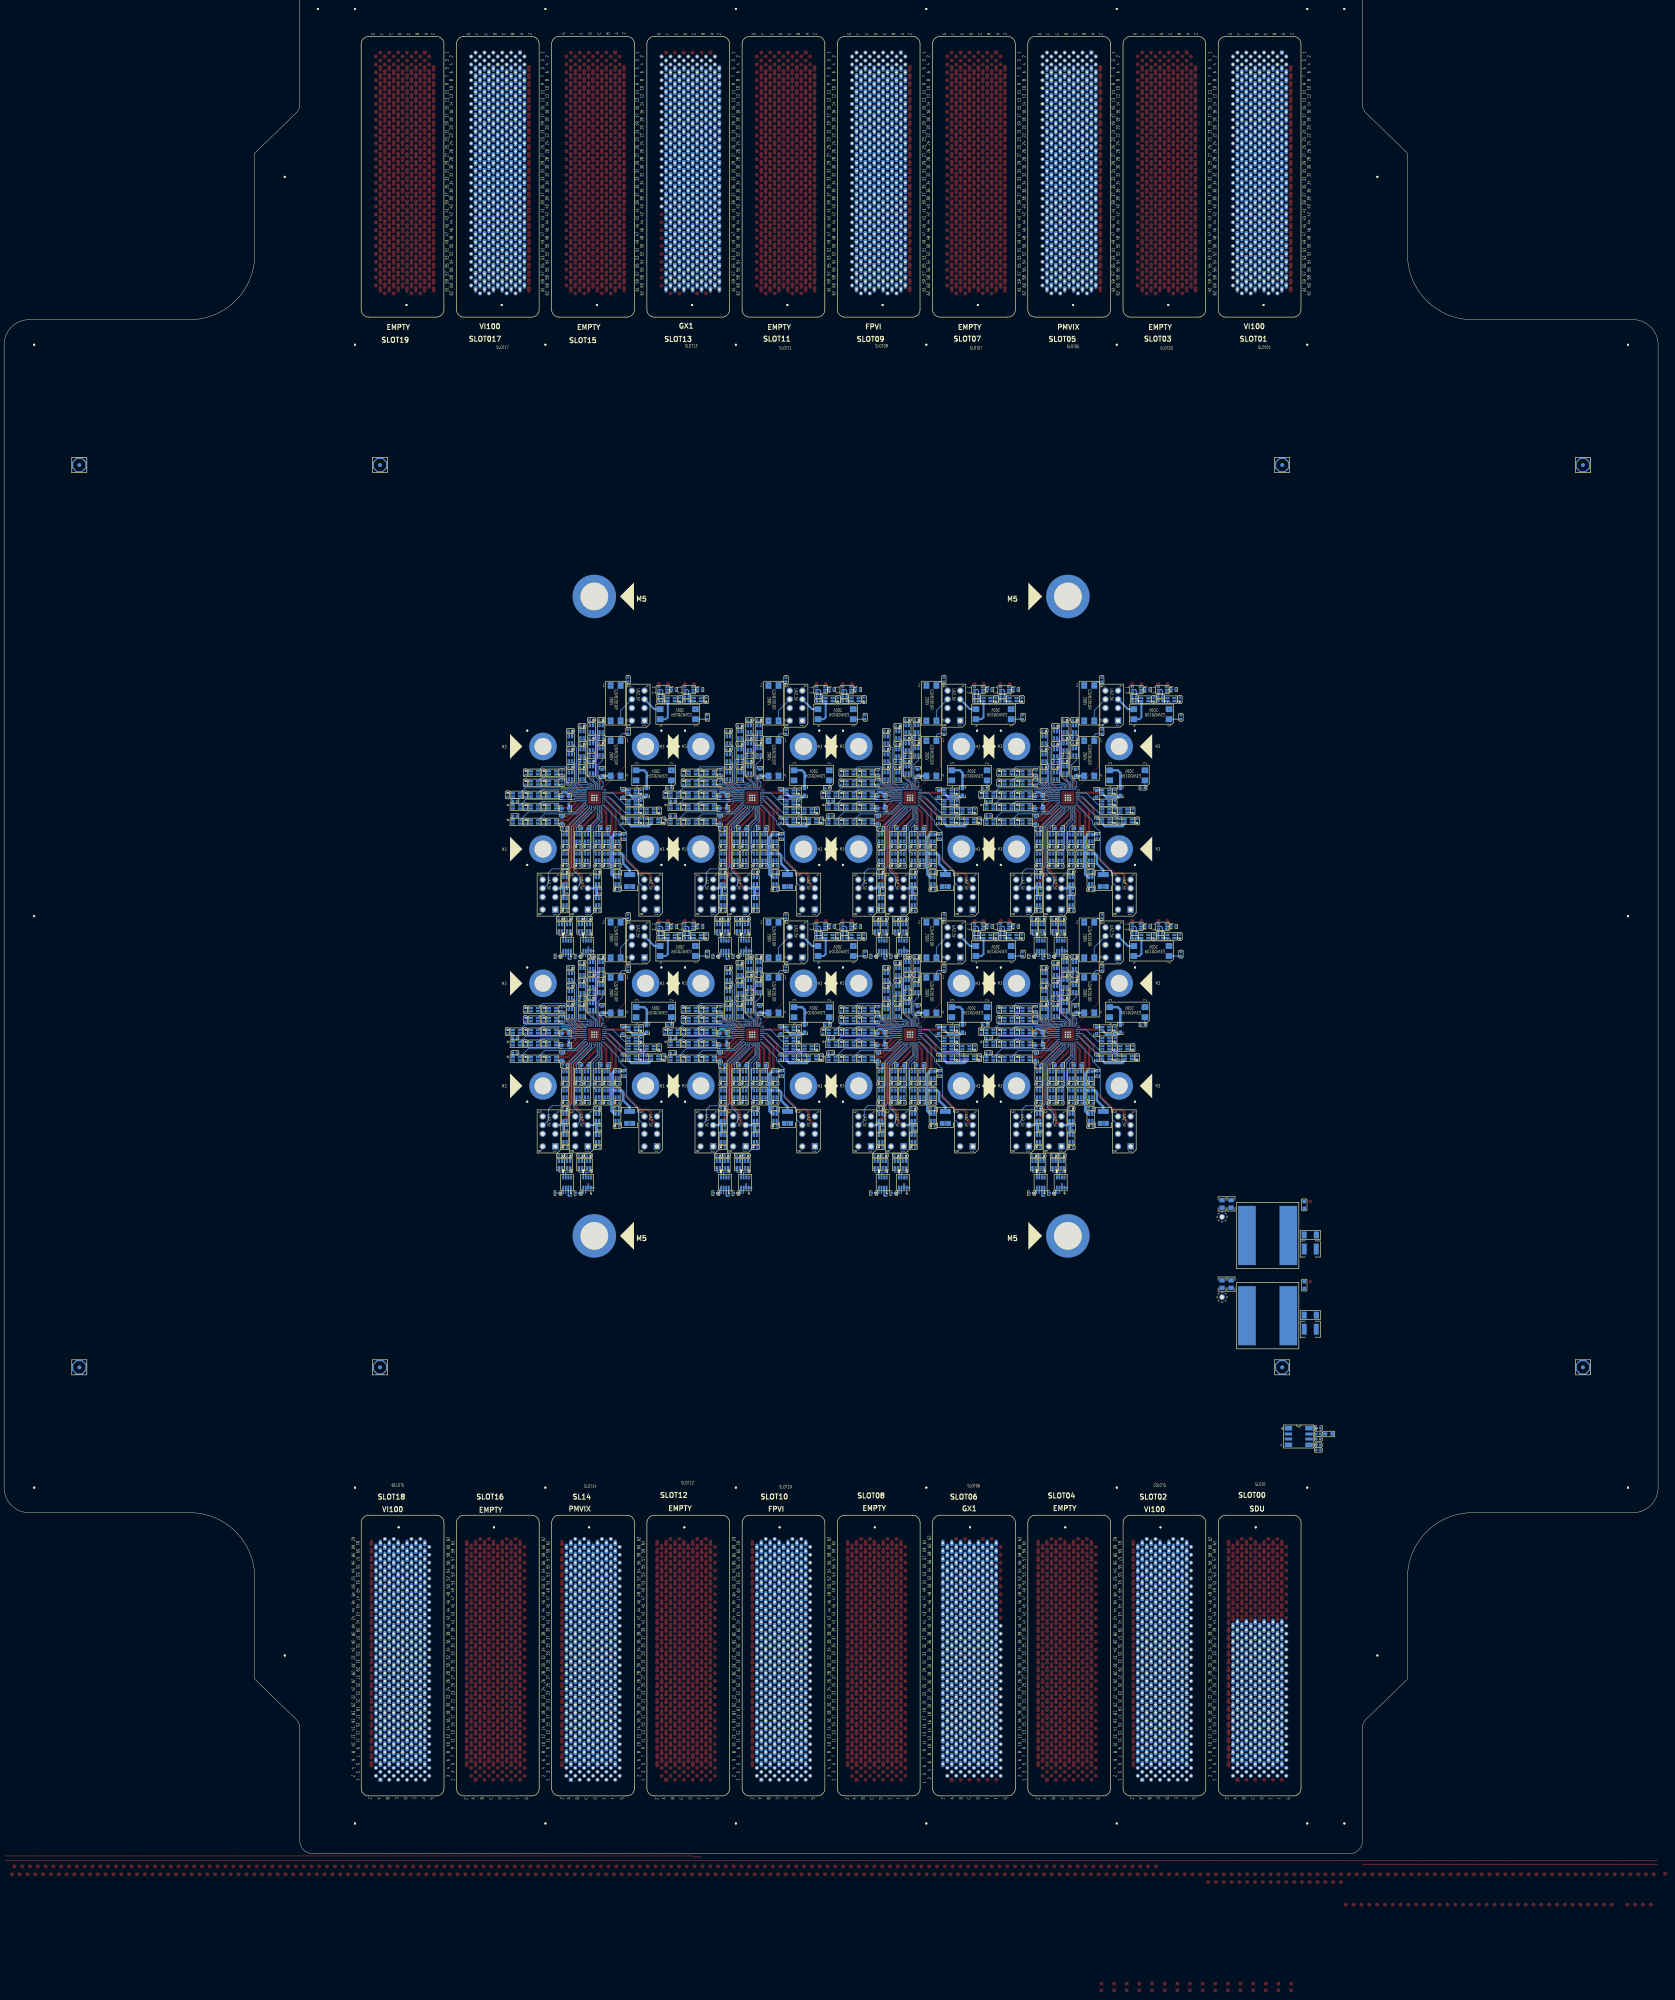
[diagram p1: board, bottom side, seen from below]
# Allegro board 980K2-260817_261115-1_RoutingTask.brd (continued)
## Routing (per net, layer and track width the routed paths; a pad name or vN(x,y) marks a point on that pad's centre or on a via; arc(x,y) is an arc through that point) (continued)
SL01_VI100_28_B_HF: length 1.1
  TOP w0.305: v2(229.8,270.79) 230,270.79 230.3,270.49 SITE3.27_F
SL01_VI100_28_B_HS: length 15.4
  BOTTOM w0.152: v2(230.3,269.59) 230.44,269.73 230.44,270.53 230.71,270.8
  BOTTOM w0.203: 230.71,270.8 233.5,270.8 234.03,271.32 234.03,276.17 234.05,276.2 234.05,280.2 v1(235.17,281.32)
SL01_VI100_29_A_HF: length 8.4
  TOP w0.305: 233.66,268.65 233.26,268.25 232.44,268.25 232.44,268.24 SITE3.22_F
  TOP w0.635: 233.66,268.65 233.99,268.98 237.62,268.98 v1(237.73,268.86)
  BOTTOM w0.635: v1(237.73,268.86) 236.67,268.86 236.03,268.22 UNK3C64.2
SL01_VI100_29_A_HS: length 18.1
  BOTTOM w0.203: v1(248.42,268.62) 247.04,270 236.21,270 234.45,268.24 v2(231.65,268.24)
SL01_VI100_29_B_HF: length 0.4
  TOP w0.305: SITE3.32_F v2(227.8,270.39)
  vias: v1(227.43,284.11)
SL01_VI100_29_B_HS: length 9.9
  BOTTOM w0.203: v2(227.8,269.59) 227.8,269.86 227.33,270.33 227.33,271.45 228.59,272.71 228.59,275.84 227.43,277.01 v1(227.43,278.27)
SL01_VI100_30_A_HF: length 8.4
  TOP w0.305: SITE3.23_F 232.52,268.74 232.97,269.19
  TOP w0.635: v1(239.27,271.67) 237.57,269.97 233.75,269.97 232.97,269.19
SL01_VI100_30_A_HS: length 14.9
  BOTTOM w0.203: v2(231.65,268.74) 234.31,268.74 236.27,270.7 236.59,270.7 237.12,271.23 237.12,272.36 237.43,272.67 242.85,272.67 v1(243.84,271.67)
SL01_VI100_30_B_HS: length 9.2
  BOTTOM w0.203: v2(229.3,265.39) 229.3,264.72 234.07,259.95 v1(234.07,258.18)
SL01_VI100_31_A_HF: length 10
  TOP w0.305: SITE3.24_F 232.05,269.58 232.28,269.81
  TOP w0.635: v1(239.27,274.21) 238.47,273.41 237.62,273.41 236.98,272.77 236.98,271.92 235.98,270.92 233.39,270.92 232.28,269.81
SL01_VI100_31_A_HS: length 17.3
  BOTTOM w0.203: v2(231.65,269.24) 234.18,269.24 236.08,271.14 236.46,271.14 236.72,271.4 236.72,275.08 236.97,275.34 242.72,275.34 v1(243.84,274.21)
SL01_VI100_31_B_HS: length 13.9
  BOTTOM w0.203: v2(228.8,265.39) 228.8,262.17 230.36,260.61 230.36,254.46 230.57,254.25 231.51,254.25 231.91,253.85 v1(231.91,253.35)
SL01_VI100_32_A_HF: length 0.4
  TOP w0.305: SITE3.28_F v2(229.8,270.39)
SL01_VI100_32_A_HS: length 4.1
  BOTTOM w0.152: v2(229.8,269.59) 229.8,269.74 230.14,270.08 230.14,270.86 230.25,270.97
  BOTTOM w0.203: v1(232.25,272.17) 231.28,271.2 230.49,271.2 230.25,270.97
SL01_VI100_32_B_HS: length 7.8
  BOTTOM w0.203: v1(229.12,258.18) 229.12,260.08 227.8,261.39 v2(227.8,265.39)
SL02_VI100_2_A_HF: length 11.5
  TOP w0.305: SITE2.2_F 186.18,268.74
  TOP w0.635: 186.18,268.74 180.98,268.74 v1(180.83,268.59)
  BOTTOM w0.635: UNK2C49.2 176.82,267.59 179.83,267.59 v1(180.83,268.59)
SL02_VI100_2_A_HS: length 7.8
  BOTTOM w0.203: v1(180.83,265.79) 181.97,265.79 184.92,268.74 v2(187.45,268.74)
SL02_VI100_2_B_HF: length 9.3
  TOP w0.305: SITE2.29_F 189.3,270.29 189.31,270.3 189.31,270.56 189.29,270.58 189.29,271 189.31,271.02 189.31,271.21 189.94,271.84
  TOP w0.635: v1(192.25,278.02) 191.49,277.25 191.49,273.39 189.94,271.84
SL02_VI100_2_B_HS: length 14.3
  BOTTOM w0.203: v1(192.25,282.59) 191.38,281.72 191.38,273.02 189.21,270.84 189.21,269.68 v2(189.3,269.59)
SL02_VI100_3_A_HF: length 16.3
  TOP w0.305: SITE2.5_F 185.45,267.24
  TOP w0.635: v1(180.83,261.22) 183.13,263.52 183.13,264.92 185.45,267.24
  BOTTOM w0.635: v1(180.83,261.22) 180.83,260.93 180.19,260.3 175.75,260.3 175.11,260.93 v1(175.11,261.22)
SL02_VI100_3_A_HS: length 13.4
  BOTTOM w0.203: v2(187.45,267.24) 186.97,267.24 182.62,262.89 177.13,262.89 v1(176.26,263.76)
SL02_VI100_3_B_HS: length 13
  BOTTOM w0.203: v1(189.12,253.35) 189.86,254.09 189.86,260.22 188.3,261.78 v2(188.3,265.39)
SL02_VI100_4_A_HS: length 8.3
  BOTTOM w0.203: v1(180.83,263.76) 181.84,263.76 185.82,267.74 v2(187.45,267.74)
SL02_VI100_4_B_HS: length 13.8
  BOTTOM w0.203: v2(191.65,265.74) 193.97,263.42 202.19,263.42 v1(203.84,261.77)
SL02_VI100_5_A_HF: length 23.1
  TOP w0.305: SITE2.6_F 186.47,266.74 186.18,266.45
  TOP w0.635: v1(184.16,258.18) 184.16,264.43 186.18,266.45
  BOTTOM w0.508: 184.38,253.35 UNK2K12.4
  BOTTOM w0.635: 185.18,253.35 185.18,248.1 184.45,247.38 184.21,247.38 ; 185.18,253.35 185.18,257.54 184.54,258.18 v1(184.16,258.18) ; 185.18,253.35 184.38,253.35
SL02_VI100_5_A_HS:
  vias: v2(187.45,266.74)
SL02_VI100_6_A_HF:
  vias: v2(187.05,266.24)
SL02_VI100_6_A_HS:
  vias: v1(186.96,253.35) v2(187.45,266.24)
SL02_VI100_6_B_HF: length 1.7
  TOP w0.305: SITE2.30_F v2(188.8,271.66)
SL02_VI100_6_B_HS: length 4.5
  BOTTOM w0.203: UNK2K46.4 189.84,272.05 188.8,271.01 v2(188.8,269.59)
SL02_VI100_7_A_HF:
  vias: v2(189.8,264.99)
SL02_VI100_7_A_HS:
  vias: v1(194.07,253.35) v2(189.8,265.39)
SL02_VI100_7_B_HF: length 10.4
  TOP w0.305: SITE2.31_F 188.3,270.29 188.29,270.3 188.29,270.82 188.07,271.04
  TOP w0.635: 188.07,271.04 188.07,272.57 189.08,273.58 189.08,278.78 v1(189.84,279.54)
SL02_VI100_7_B_HS: length 15.2
  BOTTOM w0.203: v1(189.84,284.11) 189.05,283.33 189.05,272.6 188.3,271.84 v2(188.3,269.59)
SL02_VI100_8_B_HF: length 5.7
  TOP w0.305: 195.04,266.93 194.73,267.24 SITE2.20_F
  TOP w0.635: v1(196.03,265.94) 195.04,266.93
  BOTTOM w0.635: v1(196.03,265.94) UNK2C61.2
SL02_VI100_8_B_HS: length 17.5
  BOTTOM w0.203: v2(191.65,267.24) 194.53,267.24 194.7,267.06 206.93,267.06 v1(208.42,265.58)
SL02_VI100_9_B_HF: length 7.6
  TOP w0.305: SITE2.21_F 194.03,267.74 194.28,267.99
  TOP w0.635: v1(199.27,268.62) 198.64,267.99 194.28,267.99
SL02_VI100_9_B_HS: length 13.3
  BOTTOM w0.203: v1(203.84,268.62) 202.97,269.49 196.34,269.49 194.58,267.74 v2(191.65,267.74)
SL02_VI100_10_A_HF: length 9.6
  TOP w0.305: SITE2.16_F 191.55,264.74 191.98,264.74
  TOP w0.635: 191.98,264.74 196.72,260.01 196.72,258.83 v1(197.37,258.18)
SL02_VI100_10_A_HS: length 15.2
  BOTTOM w0.203: v2(191.3,265.39) 191.3,265.13 195.83,260.6 195.83,254.51 196.08,254.25 197.17,254.25 197.37,254.05 v1(197.37,253.35)
SL02_VI100_10_B_HF: length 0.4
  TOP w0.305: SITE2.25_F v2(191.3,270.39)
SL02_VI100_10_B_HS: length 5.7
  BOTTOM w0.203: v1(195.17,272.17) 195.17,270.87 193.95,269.65 191.36,269.65 v2(191.3,269.59)
SL02_VI100_11_A_HF: length 7.2
  TOP w0.305: SITE2.18_F 193.05,266.24 193.62,265.67
  TOP w0.635: 193.62,265.67 196.62,262.67 v1(197.73,262.67)
SL02_VI100_11_A_HS: length 18.6
  BOTTOM w0.203: v2(191.65,266.24) 191.97,266.24 194.3,263.91 206.28,263.91 v1(208.42,261.77)
SL02_VI100_11_B_HF: length 0.4
  TOP w0.305: SITE2.26_F v2(190.8,270.39)
SL02_VI100_11_B_HS: length 10.5
  BOTTOM w0.203: v1(195.17,276.75) 194.43,276 194.43,270.7 193.88,270.16 191.7,270.16 191.57,270.03 191.16,270.03 190.8,269.67 v2(190.8,269.59)
SL02_VI100_12_A_HF: length 8.2
  TOP w0.305: 194.3,266.19 194.13,266.19 193.59,266.74 SITE2.19_F
  TOP w0.635: v1(199.27,265.58) 198.62,264.92 195.57,264.92 194.3,266.19
SL02_VI100_12_A_HS: length 12.7
  BOTTOM w0.203: v1(203.84,265.58) 202.84,266.58 194.43,266.58 194.27,266.74 v2(191.65,266.74)
SL02_VI100_12_B_HF: length 1.1
  TOP w0.305: v2(189.8,270.79) 190,270.79 190.3,270.49 SITE2.27_F
SL02_VI100_12_B_HS: length 15.4
  BOTTOM w0.152: v2(190.3,269.59) 190.44,269.73 190.44,270.53 190.71,270.8
  BOTTOM w0.203: v1(195.17,281.32) 194.05,280.2 194.05,276.2 194.03,276.17 194.03,271.32 193.5,270.8 190.71,270.8
SL02_VI100_13_A_HF: length 8.4
  TOP w0.305: 193.66,268.65 193.26,268.25 192.44,268.25 192.44,268.24 SITE2.22_F
  TOP w0.635: v1(197.73,268.86) 197.62,268.98 193.99,268.98 193.66,268.65
  BOTTOM w0.635: UNK2C64.2 196.03,268.22 196.67,268.86 v1(197.73,268.86)
SL02_VI100_13_A_HS: length 18.1
  BOTTOM w0.203: v2(191.65,268.24) 194.45,268.24 196.21,270 207.04,270 v1(208.42,268.62)
SL02_VI100_13_B_HF: length 0.4
  TOP w0.305: SITE2.32_F v2(187.8,270.39)
  vias: v1(187.43,284.11)
SL02_VI100_13_B_HS: length 9.9
  BOTTOM w0.203: v1(187.43,278.27) 187.43,277.01 188.59,275.84 188.59,272.71 187.33,271.45 187.33,270.33 187.8,269.86 v2(187.8,269.59)
SL02_VI100_14_A_HF: length 8.4
  TOP w0.305: 192.97,269.19 192.52,268.74 SITE2.23_F
  TOP w0.635: 192.97,269.19 193.75,269.97 197.57,269.97 v1(199.27,271.67)
SL02_VI100_14_A_HS: length 14.9
  BOTTOM w0.203: v2(191.65,268.74) 194.31,268.74 196.27,270.7 196.59,270.7 197.12,271.23 197.12,272.36 197.43,272.67 202.85,272.67 v1(203.84,271.67)
SL02_VI100_14_B_HS: length 9.2
  BOTTOM w0.203: v1(194.07,258.18) 194.07,259.95 189.3,264.72 v2(189.3,265.39)
SL02_VI100_15_A_HF: length 10
  TOP w0.305: SITE2.24_F 192.05,269.58 192.28,269.81
  TOP w0.635: v1(199.27,274.21) 198.47,273.41 197.62,273.41 196.98,272.77 196.98,271.92 195.98,270.92 193.39,270.92 192.28,269.81
SL02_VI100_15_A_HS: length 17.3
  BOTTOM w0.203: v1(203.84,274.21) 202.72,275.34 196.97,275.34 196.72,275.08 196.72,271.4 196.46,271.14 196.08,271.14 194.18,269.24 v2(191.65,269.24)
SL02_VI100_15_B_HS: length 13.9
  BOTTOM w0.203: v2(188.8,265.39) 188.8,262.17 190.36,260.61 190.36,254.46 190.57,254.25 191.51,254.25 191.91,253.85 v1(191.91,253.35)
SL02_VI100_16_A_HF: length 0.4
  TOP w0.305: SITE2.28_F v2(189.8,270.39)
SL02_VI100_16_A_HS: length 4.1
  BOTTOM w0.152: 190.25,270.97 190.14,270.86 190.14,270.08 189.8,269.74 v2(189.8,269.59)
  BOTTOM w0.203: v1(192.25,272.17) 191.28,271.2 190.49,271.2 190.25,270.97
SL02_VI100_16_B_HS: length 7.8
  BOTTOM w0.203: v1(189.12,258.18) 189.12,260.08 187.8,261.39 v2(187.8,265.39)
SL02_VI100_18_A_HF: length 11.5
  TOP w0.305: SITE4.2_F 266.18,268.74
  TOP w0.635: 266.18,268.74 260.98,268.74 v1(260.83,268.59)
  BOTTOM w0.635: v1(260.83,268.59) 259.83,267.59 256.82,267.59 UNK4C49.2
SL02_VI100_18_A_HS: length 7.8
  BOTTOM w0.203: v2(267.45,268.74) 264.92,268.74 261.97,265.79 v1(260.83,265.79)
SL02_VI100_18_B_HF: length 9.3
  TOP w0.305: 269.94,271.84 269.31,271.21 269.31,271.02 269.29,271 269.29,270.58 269.31,270.56 269.31,270.3 269.3,270.29 SITE4.29_F
  TOP w0.635: 269.94,271.84 271.49,273.39 271.49,277.25 v1(272.25,278.02)
SL02_VI100_18_B_HS: length 14.3
  BOTTOM w0.203: v1(272.25,282.59) 271.38,281.72 271.38,273.02 269.21,270.84 269.21,269.68 v2(269.3,269.59)
SL02_VI100_19_A_HF: length 16.3
  TOP w0.305: SITE4.5_F 265.45,267.24
  TOP w0.635: 265.45,267.24 263.13,264.92 263.13,263.52 v1(260.83,261.22)
  BOTTOM w0.635: v1(260.83,261.22) 260.83,260.93 260.19,260.3 255.75,260.3 255.11,260.93 v1(255.11,261.22)
SL02_VI100_19_A_HS: length 13.4
  BOTTOM w0.203: v2(267.45,267.24) 266.97,267.24 262.62,262.89 257.13,262.89 v1(256.26,263.76)
SL02_VI100_19_B_HS: length 13
  BOTTOM w0.203: v2(268.3,265.39) 268.3,261.78 269.86,260.22 269.86,254.09 v1(269.12,253.35)
SL02_VI100_20_A_HS: length 8.3
  BOTTOM w0.203: v1(260.83,263.76) 261.84,263.76 265.82,267.74 v2(267.45,267.74)
SL02_VI100_20_B_HS: length 13.8
  BOTTOM w0.203: v2(271.65,265.74) 273.97,263.42 282.19,263.42 v1(283.84,261.77)
SL02_VI100_21_A_HF: length 23.1
  TOP w0.305: 266.18,266.45 266.47,266.74 SITE4.6_F
  TOP w0.635: v1(264.16,258.18) 264.16,264.43 266.18,266.45
  BOTTOM w0.508: 264.38,253.35 UNK4K12.4
  BOTTOM w0.635: 264.21,247.38 264.45,247.38 265.17,248.1 265.17,253.35 ; 265.17,253.35 265.17,257.54 264.54,258.18 v1(264.16,258.18) ; 265.17,253.35 264.38,253.35
SL02_VI100_21_A_HS:
  vias: v2(267.45,266.74)
SL02_VI100_22_A_HF:
  vias: v2(267.05,266.24)
SL02_VI100_22_A_HS:
  vias: v1(266.96,253.35) v2(267.45,266.24)
SL02_VI100_22_B_HF: length 1.7
  TOP w0.305: SITE4.30_F v2(268.8,271.66)
SL02_VI100_22_B_HS: length 4.5
  BOTTOM w0.203: UNK4K46.4 269.84,272.05 268.8,271.01 v2(268.8,269.59)
SL02_VI100_23_A_HF:
  vias: v2(269.8,264.99)
SL02_VI100_23_A_HS:
  vias: v1(274.07,253.35) v2(269.8,265.39)
SL02_VI100_23_B_HF: length 10.4
  TOP w0.305: 268.07,271.04 268.29,270.82 268.29,270.3 268.3,270.29 SITE4.31_F
  TOP w0.635: v1(269.84,279.54) 269.08,278.78 269.08,273.58 268.07,272.57 268.07,271.04
SL02_VI100_23_B_HS: length 15.2
  BOTTOM w0.203: v1(269.84,284.11) 269.05,283.33 269.05,272.6 268.3,271.84 v2(268.3,269.59)
SL02_VI100_24_B_HF: length 5.7
  TOP w0.305: 275.04,266.93 274.73,267.24 SITE4.20_F
  TOP w0.635: v1(276.03,265.94) 275.04,266.93
  BOTTOM w0.635: v1(276.03,265.94) UNK4C61.2
SL02_VI100_24_B_HS: length 17.5
  BOTTOM w0.203: v2(271.65,267.24) 274.53,267.24 274.7,267.06 286.93,267.06 v1(288.42,265.58)
SL02_VI100_25_B_HF: length 7.6
  TOP w0.305: SITE4.21_F 274.03,267.74 274.28,267.99
  TOP w0.635: 274.28,267.99 278.64,267.99 v1(279.27,268.62)
SL02_VI100_25_B_HS: length 13.3
  BOTTOM w0.203: v2(271.65,267.74) 274.58,267.74 276.34,269.49 282.97,269.49 v1(283.84,268.62)
SL02_VI100_26_A_HF: length 9.6
  TOP w0.305: 271.98,264.74 271.55,264.74 SITE4.16_F
  TOP w0.635: 271.98,264.74 276.72,260.01 276.72,258.83 v1(277.37,258.18)
SL02_VI100_26_A_HS: length 15.2
  BOTTOM w0.203: v1(277.37,253.35) 277.37,254.05 277.17,254.25 276.08,254.25 275.83,254.51 275.83,260.6 271.3,265.13 v2(271.3,265.39)
SL02_VI100_26_B_HF: length 0.4
  TOP w0.305: SITE4.25_F v2(271.3,270.39)
SL02_VI100_26_B_HS: length 5.7
  BOTTOM w0.203: v1(275.17,272.17) 275.17,270.87 273.95,269.65 271.36,269.65 v2(271.3,269.59)
SL02_VI100_27_A_HF: length 7.2
  TOP w0.305: 273.62,265.67 273.05,266.24 SITE4.18_F
  TOP w0.635: 273.62,265.67 276.62,262.67 v1(277.73,262.67)
SL02_VI100_27_A_HS: length 18.6
  BOTTOM w0.203: v2(271.65,266.24) 271.97,266.24 274.3,263.91 286.28,263.91 v1(288.42,261.77)
SL02_VI100_27_B_HF: length 0.4
  TOP w0.305: SITE4.26_F v2(270.8,270.39)
SL02_VI100_27_B_HS: length 10.5
  BOTTOM w0.203: v2(270.8,269.59) 270.8,269.67 271.16,270.03 271.57,270.03 271.7,270.16 273.88,270.16 274.43,270.7 274.43,276 v1(275.17,276.75)
SL02_VI100_28_A_HF: length 8.2
  TOP w0.305: 274.3,266.19 274.13,266.19 273.59,266.74 SITE4.19_F
  TOP w0.635: v1(279.27,265.58) 278.62,264.92 275.57,264.92 274.3,266.19
SL02_VI100_28_A_HS: length 12.7
  BOTTOM w0.203: v1(283.84,265.58) 282.84,266.58 274.43,266.58 274.27,266.74 v2(271.65,266.74)
SL02_VI100_28_B_HF: length 1.1
  TOP w0.305: SITE4.27_F 270.3,270.49 270,270.79 v2(269.8,270.79)
SL02_VI100_28_B_HS: length 15.4
  BOTTOM w0.152: 270.71,270.8 270.44,270.53 270.44,269.73 v2(270.3,269.59)
  BOTTOM w0.203: 270.71,270.8 273.5,270.8 274.03,271.32 274.03,276.17 274.05,276.2 274.05,280.2 v1(275.17,281.32)
SL02_VI100_29_A_HF: length 8.4
  TOP w0.305: SITE4.22_F 272.44,268.24 272.44,268.25 273.26,268.25 273.66,268.65
  TOP w0.635: v1(277.73,268.86) 277.62,268.98 273.99,268.98 273.66,268.65
  BOTTOM w0.635: UNK4C64.2 276.03,268.22 276.67,268.86 v1(277.73,268.86)
SL02_VI100_29_A_HS: length 18.1
  BOTTOM w0.203: v1(288.42,268.62) 287.04,270 276.21,270 274.45,268.24 v2(271.65,268.24)
SL02_VI100_29_B_HF: length 0.4
  TOP w0.305: SITE4.32_F v2(267.8,270.39)
  vias: v1(267.43,284.11)
SL02_VI100_29_B_HS: length 9.9
  BOTTOM w0.203: v1(267.43,278.27) 267.43,277.01 268.59,275.84 268.59,272.71 267.33,271.45 267.33,270.33 267.8,269.86 v2(267.8,269.59)
SL02_VI100_30_A_HF: length 8.4
  TOP w0.305: 272.97,269.19 272.52,268.74 SITE4.23_F
  TOP w0.635: v1(279.27,271.67) 277.57,269.97 273.75,269.97 272.97,269.19
SL02_VI100_30_A_HS: length 14.9
  BOTTOM w0.203: v1(283.84,271.67) 282.85,272.67 277.43,272.67 277.12,272.36 277.12,271.23 276.59,270.7 276.27,270.7 274.31,268.74 v2(271.65,268.74)
SL02_VI100_30_B_HS: length 9.2
  BOTTOM w0.203: v2(269.3,265.39) 269.3,264.72 274.07,259.95 v1(274.07,258.18)
SL02_VI100_31_A_HF: length 10
  TOP w0.305: SITE4.24_F 272.05,269.58 272.28,269.81
  TOP w0.635: 272.28,269.81 273.39,270.92 275.98,270.92 276.98,271.92 276.98,272.77 277.62,273.41 278.47,273.41 v1(279.27,274.21)
SL02_VI100_31_A_HS: length 17.3
  BOTTOM w0.203: v1(283.84,274.21) 282.72,275.34 276.97,275.34 276.72,275.08 276.72,271.4 276.46,271.14 276.08,271.14 274.18,269.24 v2(271.65,269.24)
SL02_VI100_31_B_HS: length 13.9
  BOTTOM w0.203: v2(268.8,265.39) 268.8,262.17 270.36,260.61 270.36,254.46 270.57,254.25 271.51,254.25 271.91,253.85 v1(271.91,253.35)
SL02_VI100_32_A_HF: length 0.4
  TOP w0.305: SITE4.28_F v2(269.8,270.39)
SL02_VI100_32_A_HS: length 4.1
  BOTTOM w0.152: 270.25,270.97 270.14,270.86 270.14,270.08 269.8,269.74 v2(269.8,269.59)
  BOTTOM w0.203: v1(272.25,272.17) 271.28,271.2 270.49,271.2 270.25,270.97
SL02_VI100_32_B_HS: length 7.8
  BOTTOM w0.203: v1(269.12,258.18) 269.12,260.08 267.8,261.39 v2(267.8,265.39)
SL05_PMVI_10_HF:
  vias: v1(148.21,243.34)
SL05_PMVI_11_HF:
  vias: v1(156.46,243.34)
SL05_PMVI_12_HF: length 0.3
  BOTTOM w0.203: U1.4 v1(124.31,294.24)
SL05_PMVI_13_HF:
  vias: v1(130.91,294.24)
SL05_PMVI_14_HF:
  vias: v1(155.49,231.3)
SL05_PMVI_15_HF: length 2.2
  BOTTOM w0.203: C72.1 R15.2 U3.1
SL05_PMVI_16_HF: length 2.7
  BOTTOM w0.381: v1(155.49,226.57) 155.94,226.57 156.14,226.77 U3.3
SL05_PMVI_17_HF:
  vias: v1(150.41,231.3)
SL05_PMVI_18_HF: length 2.2
  BOTTOM w0.203: C73.1 R17.2 U4.1
SL05_PMVI_19_HF: length 0.9
  BOTTOM w0.381: TP_REF_2.1 v1(151.06,229.62)
SL05_PMVI_20_HF:
  vias: v1(228.21,243.34)
SL05_PMVI_21_HF:
  vias: v1(236.46,243.34)
SL05_PMVI_22_HF: length 0.3
  BOTTOM w0.203: UNK3U1.4 v1(204.31,294.24)
SL05_PMVI_23_HF:
  vias: v1(210.91,294.24)
SL05_PMVI_24_HF:
  vias: v1(235.49,231.3)
SL05_PMVI_25_HF: length 2.2
  BOTTOM w0.203: UNK3C72.1 UNK3R15.2 UNK3U3.1
SL05_PMVI_26_HF: length 2.7
  BOTTOM w0.381: UNK3U3.3 236.14,226.77 235.94,226.57 v1(235.49,226.57)
SL05_PMVI_27_HF:
  vias: v1(230.41,231.3)
SL05_PMVI_28_HF: length 2.2
  BOTTOM w0.203: UNK3C73.1 UNK3R17.2 UNK3U4.1
SL05_PMVI_29_HF: length 0.9
  BOTTOM w0.381: UNK3TP_REF_2.1 v1(231.06,229.62)
SL05_PMVI_30_HF:
  vias: v1(148.21,183.34)
SL05_PMVI_31_HF:
  vias: v1(156.46,183.34)
SL05_PMVI_32_HF: length 0.3
  BOTTOM w0.203: UNK5U1.4 v1(124.31,234.24)
SL05_PMVI_33_HF:
  vias: v1(130.91,234.24)
SL05_PMVI_34_HF:
  vias: v1(155.49,171.3)
SL05_PMVI_35_HF: length 2.2
  BOTTOM w0.203: UNK5U3.1 UNK5R15.2 UNK5C72.1
SL05_PMVI_36_HF: length 2.7
  BOTTOM w0.381: UNK5U3.3 156.14,166.77 155.94,166.57 v1(155.49,166.57)
SL05_PMVI_37_HF:
  vias: v1(150.41,171.3)
SL05_PMVI_38_HF: length 2.2
  BOTTOM w0.203: UNK5C73.1 UNK5R17.2 UNK5U4.1
SL05_PMVI_39_HF: length 0.9
  BOTTOM w0.381: UNK5TP_REF_2.1 v1(151.06,169.62)
SL05_PMVI_40_HF:
  vias: v1(228.21,183.34)
SL05_PMVI_41_HF:
  vias: v1(236.46,183.34)
SL05_PMVI_42_HF: length 0.3
  BOTTOM w0.203: UNK7U1.4 v1(204.31,234.24)
SL05_PMVI_43_HF:
  vias: v1(210.91,234.24)
SL05_PMVI_44_HF:
  vias: v1(235.49,171.3)
SL05_PMVI_45_HF: length 2.2
  BOTTOM w0.203: UNK7C72.1 UNK7R15.2 UNK7U3.1
SL05_PMVI_46_HF: length 2.7
  BOTTOM w0.381: v1(235.49,166.57) 235.94,166.57 236.14,166.77 UNK7U3.3
SL05_PMVI_47_HF:
  vias: v1(230.41,171.3)
SL05_PMVI_48_HF: length 2.2
  BOTTOM w0.203: UNK7C73.1 UNK7R17.2 UNK7U4.1
SL05_PMVI_49_HF: length 0.9
  BOTTOM w0.381: UNK7TP_REF_2.1 v1(231.06,169.62)
SL06_DP_0:
  vias: v1(185.41,286.99)
SL06_DP_1:
  vias: v1(180.83,266.69)
SL06_DP_2:
  vias: v1(180.83,264.66)
SL06_DP_3:
  vias: v1(176.26,264.66)
SL06_DP_4:
  vias: v1(186.06,253.35)
SL06_DP_6:
  vias: v1(188.22,258.18)
SL06_DP_7:
  vias: v1(188.22,253.35)
SL06_DP_8:
  vias: v1(191.01,253.35)
SL06_DP_9:
  vias: v1(193.17,258.18)
SL06_DP_10:
  vias: v1(193.17,253.35)
SL06_DP_13:
  vias: v1(196.47,253.35)
SL06_DP_14:
  vias: v1(203.84,260.87)
SL06_DP_15:
  vias: v1(208.42,260.87)
SL06_DP_16:
  vias: v1(203.84,264.68)
SL06_DP_17:
  vias: v1(208.42,264.68)
SL06_DP_18:
  vias: v1(203.84,267.72)
SL06_DP_19:
  vias: v1(208.42,267.72)
SL06_DP_20:
  vias: v1(203.84,270.77)
SL06_DP_22:
  vias: v1(196.08,272.17)
SL06_DP_23:
  vias: v1(196.08,276.75)
SL06_DP_24:
  vias: v1(196.08,281.32)
SL06_DP_25:
  vias: v1(193.15,272.17)
SL06_DP_26:
  vias: v1(193.15,282.59)
SL06_DP_27:
  vias: v1(190.74,273.7)
SL06_DP_28:
  vias: v1(190.74,284.11)
SL06_DP_29:
  vias: v1(188.33,278.27)
SL06_DP_30:
  vias: v1(265.41,286.99)
SL06_DP_31:
  vias: v1(260.83,266.69)
SL06_DP_32:
  vias: v1(260.83,264.66)
SL06_DP_33:
  vias: v1(256.26,264.66)
SL06_DP_34:
  vias: v1(266.06,253.35)
SL06_DP_36:
  vias: v1(268.22,258.18)
SL06_DP_37:
  vias: v1(268.22,253.35)
SL06_DP_38:
  vias: v1(271.01,253.35)
SL06_DP_39:
  vias: v1(273.17,258.18)
SL06_DP_40:
  vias: v1(273.17,253.35)
SL06_DP_43:
  vias: v1(276.47,253.35)
SL06_DP_44:
  vias: v1(283.84,260.87)
SL06_DP_45:
  vias: v1(288.42,260.87)
SL06_DP_46:
  vias: v1(283.84,264.68)
SL06_DP_47:
  vias: v1(288.42,264.68)
SL06_DP_48:
  vias: v1(283.84,267.72)
SL06_DP_49:
  vias: v1(288.42,267.72)
SL06_DP_50:
  vias: v1(283.84,270.77)
SL06_DP_52:
  vias: v1(276.07,272.17)
SL06_DP_53:
  vias: v1(276.07,276.75)
SL06_DP_54:
  vias: v1(276.07,281.32)
SL06_DP_55:
  vias: v1(273.15,272.17)
SL06_DP_56:
  vias: v1(273.15,282.59)
SL06_DP_57:
  vias: v1(270.74,273.7)
SL06_DP_58:
  vias: v1(270.74,284.11)
SL06_DP_59:
  vias: v1(268.33,278.27)
SL06_DP_60:
  vias: v1(185.41,226.99)
SL06_DP_61:
  vias: v1(180.83,206.69)
SL06_DP_62:
  vias: v1(180.83,204.66)
SL06_DP_63:
  vias: v1(176.26,204.66)
SL06_DP_64:
  vias: v1(186.06,193.35)
SL06_DP_66:
  vias: v1(188.22,198.18)
SL06_DP_67:
  vias: v1(188.22,193.35)
SL06_DP_68:
  vias: v1(191.01,193.35)
SL06_DP_69:
  vias: v1(193.17,198.18)
SL06_DP_70:
  vias: v1(193.17,193.35)
SL06_DP_73:
  vias: v1(196.47,193.35)
SL06_DP_74:
  vias: v1(203.84,200.87)
SL06_DP_75:
  vias: v1(208.42,200.87)
SL06_DP_76:
  vias: v1(203.84,204.68)
SL06_DP_77:
  vias: v1(208.42,204.68)
SL06_DP_78:
  vias: v1(203.84,207.72)
SL06_DP_79:
  vias: v1(208.42,207.72)
SL06_DP_80:
  vias: v1(203.84,210.77)
SL06_DP_82:
  vias: v1(196.08,212.18)
SL06_DP_83:
  vias: v1(196.08,216.75)
SL06_DP_84:
  vias: v1(196.08,221.32)
SL06_DP_85:
  vias: v1(193.15,212.18)
SL06_DP_86:
  vias: v1(193.15,222.59)
SL06_DP_87:
  vias: v1(190.74,213.7)
SL06_DP_88:
  vias: v1(190.74,224.11)
SL06_DP_89:
  vias: v1(188.33,218.27)
SL06_DP_90:
  vias: v1(265.41,226.99)
SL06_DP_91:
  vias: v1(260.83,206.69)
SL06_DP_92:
  vias: v1(260.83,204.66)
SL06_DP_93:
  vias: v1(256.26,204.66)
SL06_DP_94:
  vias: v1(266.06,193.35)
SL06_DP_96:
  vias: v1(268.22,198.18)
SL06_DP_97:
  vias: v1(268.22,193.35)
SL06_DP_98:
  vias: v1(271.01,193.35)
SL06_DP_99:
  vias: v1(273.17,198.18)
SL06_DP_100:
  vias: v1(273.17,193.35)
SL06_DP_103:
  vias: v1(276.47,193.35)
SL06_DP_104:
  vias: v1(283.84,200.87)
SL06_DP_105:
  vias: v1(288.42,200.87)
SL06_DP_106:
  vias: v1(283.84,204.68)
SL06_DP_107:
  vias: v1(288.42,204.68)
SL06_DP_108:
  vias: v1(283.84,207.72)
SL06_DP_109:
  vias: v1(288.42,207.72)
SL06_DP_110:
  vias: v1(283.84,210.77)
SL06_DP_112:
  vias: v1(276.07,212.18)
SL06_DP_113:
  vias: v1(276.07,216.75)
SL06_DP_114:
  vias: v1(276.07,221.32)
SL06_DP_115:
  vias: v1(273.15,212.18)
SL06_DP_116:
  vias: v1(273.15,222.59)
SL06_DP_117:
  vias: v1(270.74,213.7)
SL06_DP_118:
  vias: v1(270.74,224.11)
SL06_DP_119:
  vias: v1(268.33,218.27)
SL06_DP_121: length 0.8
  TOP w0.381: UNK2TP_OUT+_1.1 v1(166.61,295.54)
SL06_DP_122: length 0.8
  TOP w0.381: UNK2TP_OUT-_1.1 v1(164.31,295.54)
SL06_DP_123: length 0.8
  TOP w0.381: UNK2TP_OUT+_2.1 v1(173.22,295.54)
SL06_DP_124: length 0.8
  TOP w0.381: UNK2TP_OUT-_2.1 v1(170.91,295.54)
SL06_DP_125: length 1.4
  BOTTOM w0.203: UNK2R15.1 196.79,227.38 UNK2U3.2
SL06_DP_126: length 1.4
  BOTTOM w0.203: UNK2R17.1 191.71,227.38 UNK2U4.2
SL06_DP_127: length 0.8
  TOP w0.381: UNK4TP_OUT+_1.1 v1(246.61,295.54)
SL06_DP_128: length 0.8
  TOP w0.381: UNK4TP_OUT-_1.1 v1(244.31,295.54)
SL06_DP_129: length 0.8
  TOP w0.381: UNK4TP_OUT+_2.1 v1(253.21,295.54)
SL06_DP_130: length 0.8
  TOP w0.381: UNK4TP_OUT-_2.1 v1(250.91,295.54)
SL06_DP_131: length 1.4
  BOTTOM w0.203: UNK4R15.1 276.79,227.38 UNK4U3.2
SL06_DP_132: length 1.4
  BOTTOM w0.203: UNK4R17.1 271.71,227.38 UNK4U4.2
SL06_DP_133: length 0.8
  TOP w0.381: UNK6TP_OUT+_1.1 v1(166.61,235.54)
SL06_DP_134: length 0.8
  TOP w0.381: UNK6TP_OUT-_1.1 v1(164.31,235.54)
SL06_DP_135: length 0.8
  TOP w0.381: UNK6TP_OUT+_2.1 v1(173.22,235.54)
SL06_DP_136: length 0.8
  TOP w0.381: UNK6TP_OUT-_2.1 v1(170.91,235.54)
SL06_DP_137: length 1.4
  BOTTOM w0.203: UNK6U3.2 196.79,167.38 UNK6R15.1
SL06_DP_138: length 1.4
  BOTTOM w0.203: UNK6R17.1 191.71,167.38 UNK6U4.2
SL06_DP_139: length 0.8
  TOP w0.381: UNK8TP_OUT+_1.1 v1(246.61,235.54)
SL06_DP_140: length 0.8
  TOP w0.381: UNK8TP_OUT-_1.1 v1(244.31,235.54)
SL06_DP_141: length 0.8
  TOP w0.381: UNK8TP_OUT+_2.1 v1(253.21,235.54)
SL06_DP_142: length 0.8
  TOP w0.381: UNK8TP_OUT-_2.1 v1(250.91,235.54)
SL06_DP_143: length 1.4
  BOTTOM w0.203: UNK8R15.1 276.79,167.38 UNK8U3.2
SL06_DP_144: length 1.4
  BOTTOM w0.203: UNK8R17.1 271.71,167.38 UNK8U4.2
SL13_DP_0:
  vias: v1(145.42,286.99)
SL13_DP_1:
  vias: v1(140.83,266.69)
SL13_DP_2:
  vias: v1(140.83,264.66)
SL13_DP_3:
  vias: v1(136.26,264.66)
SL13_DP_4:
  vias: v1(146.06,253.35)
SL13_DP_6:
  vias: v1(148.22,258.18)
SL13_DP_7:
  vias: v1(148.22,253.35)
SL13_DP_8:
  vias: v1(151.01,253.35)
SL13_DP_9:
  vias: v1(153.17,258.18)
SL13_DP_10:
  vias: v1(153.17,253.35)
SL13_DP_13:
  vias: v1(156.47,253.35)
SL13_DP_14:
  vias: v1(163.84,260.87)
SL13_DP_15:
  vias: v1(168.42,260.87)
SL13_DP_16:
  vias: v1(163.84,264.68)
SL13_DP_17:
  vias: v1(168.42,264.68)
SL13_DP_18:
  vias: v1(163.84,267.72)
SL13_DP_19:
  vias: v1(168.42,267.72)
SL13_DP_20:
  vias: v1(163.84,270.77)
SL13_DP_22:
  vias: v1(156.08,272.17)
SL13_DP_23:
  vias: v1(156.08,276.75)
SL13_DP_24:
  vias: v1(156.08,281.32)
SL13_DP_25:
  vias: v1(153.15,272.17)
SL13_DP_26:
  vias: v1(153.15,282.59)
SL13_DP_27:
  vias: v1(150.74,273.7)
SL13_DP_28:
  vias: v1(150.74,284.11)
SL13_DP_29:
  vias: v1(148.33,278.27)
SL13_DP_30:
  vias: v1(225.41,286.99)
SL13_DP_31:
  vias: v1(220.83,266.69)
SL13_DP_32:
  vias: v1(220.83,264.66)
SL13_DP_33:
  vias: v1(216.26,264.66)
SL13_DP_34:
  vias: v1(226.06,253.35)
SL13_DP_36:
  vias: v1(228.22,258.18)
SL13_DP_37:
  vias: v1(228.22,253.35)
SL13_DP_38:
  vias: v1(231.01,253.35)
SL13_DP_39:
  vias: v1(233.17,258.18)
SL13_DP_40:
  vias: v1(233.17,253.35)
SL13_DP_43:
  vias: v1(236.47,253.35)
SL13_DP_44:
  vias: v1(243.84,260.87)
SL13_DP_45:
  vias: v1(248.42,260.87)
SL13_DP_46:
  vias: v1(243.84,264.68)
SL13_DP_47:
  vias: v1(248.42,264.68)
SL13_DP_48:
  vias: v1(243.84,267.72)
SL13_DP_49:
  vias: v1(248.42,267.72)
SL13_DP_50:
  vias: v1(243.84,270.77)
SL13_DP_52:
  vias: v1(236.07,272.17)
SL13_DP_53:
  vias: v1(236.07,276.75)
SL13_DP_54:
  vias: v1(236.07,281.32)
SL13_DP_55:
  vias: v1(233.15,272.17)
SL13_DP_56:
  vias: v1(233.15,282.59)
SL13_DP_57:
  vias: v1(230.74,273.7)
SL13_DP_58:
  vias: v1(230.74,284.11)
SL13_DP_59:
  vias: v1(228.33,278.27)
SL13_DP_60:
  vias: v1(145.42,226.99)
SL13_DP_61:
  vias: v1(140.83,206.69)
SL13_DP_62:
  vias: v1(140.83,204.66)
SL13_DP_63:
  vias: v1(136.26,204.66)
SL13_DP_64:
  vias: v1(146.06,193.35)
SL13_DP_66:
  vias: v1(148.22,198.18)
SL13_DP_67:
  vias: v1(148.22,193.35)
SL13_DP_68:
  vias: v1(151.01,193.35)
SL13_DP_69:
  vias: v1(153.17,198.18)
SL13_DP_70:
  vias: v1(153.17,193.35)
SL13_DP_73:
  vias: v1(156.47,193.35)
SL13_DP_74:
  vias: v1(163.84,200.87)
SL13_DP_75:
  vias: v1(168.42,200.87)
SL13_DP_76:
  vias: v1(163.84,204.68)
SL13_DP_77:
  vias: v1(168.42,204.68)
SL13_DP_78:
  vias: v1(163.84,207.72)
SL13_DP_79:
  vias: v1(168.42,207.72)
SL13_DP_80:
  vias: v1(163.84,210.77)
SL13_DP_82:
  vias: v1(156.08,212.18)
SL13_DP_83:
  vias: v1(156.08,216.75)
SL13_DP_84:
  vias: v1(156.08,221.32)
SL13_DP_85:
  vias: v1(153.15,212.18)
SL13_DP_86:
  vias: v1(153.15,222.59)
SL13_DP_87:
  vias: v1(150.74,213.7)
SL13_DP_88:
  vias: v1(150.74,224.11)
SL13_DP_89:
  vias: v1(148.33,218.27)
SL13_DP_90:
  vias: v1(225.41,226.99)
SL13_DP_91:
  vias: v1(220.83,206.69)
SL13_DP_92:
  vias: v1(220.83,204.66)
SL13_DP_93:
  vias: v1(216.26,204.66)
SL13_DP_94:
  vias: v1(226.06,193.35)
SL13_DP_96:
  vias: v1(228.22,198.18)
SL13_DP_97:
  vias: v1(228.22,193.35)
SL13_DP_98:
  vias: v1(231.01,193.35)
SL13_DP_99:
  vias: v1(233.17,198.18)
SL13_DP_100:
  vias: v1(233.17,193.35)
SL13_DP_103:
  vias: v1(236.47,193.35)
SL13_DP_104:
  vias: v1(243.84,200.87)
SL13_DP_105:
  vias: v1(248.42,200.87)
SL13_DP_106:
  vias: v1(243.84,204.68)
SL13_DP_107:
  vias: v1(248.42,204.68)
SL13_DP_108:
  vias: v1(243.84,207.72)
SL13_DP_109:
  vias: v1(248.42,207.72)
SL13_DP_110:
  vias: v1(243.84,210.77)
SL13_DP_112:
  vias: v1(236.07,212.18)
SL13_DP_113:
  vias: v1(236.07,216.75)
SL13_DP_114:
  vias: v1(236.07,221.32)
SL13_DP_115:
  vias: v1(233.15,212.18)
SL13_DP_116:
  vias: v1(233.15,222.59)
SL13_DP_117:
  vias: v1(230.74,213.7)
SL13_DP_118:
  vias: v1(230.74,224.11)
SL13_DP_119:
  vias: v1(228.33,218.27)
SL13_DP_121: length 0.8
  TOP w0.381: TP_OUT+_1.1 v1(126.61,295.54)
SL13_DP_122: length 0.8
  TOP w0.381: TP_OUT-_1.1 v1(124.31,295.54)
SL13_DP_123: length 0.8
  TOP w0.381: TP_OUT+_2.1 v1(133.22,295.54)
SL13_DP_124: length 0.8
  TOP w0.381: TP_OUT-_2.1 v1(130.91,295.54)
SL13_DP_125: length 1.4
  BOTTOM w0.203: R15.1 156.79,227.38 U3.2
SL13_DP_126: length 1.4
  BOTTOM w0.203: U4.2 151.71,227.38 R17.1
SL13_DP_127: length 0.8
  TOP w0.381: UNK3TP_OUT+_1.1 v1(206.61,295.54)
SL13_DP_128: length 0.8
  TOP w0.381: UNK3TP_OUT-_1.1 v1(204.31,295.54)
SL13_DP_129: length 0.8
  TOP w0.381: UNK3TP_OUT+_2.1 v1(213.21,295.54)
SL13_DP_130: length 0.8
  TOP w0.381: UNK3TP_OUT-_2.1 v1(210.91,295.54)
SL13_DP_131: length 1.4
  BOTTOM w0.203: UNK3U3.2 236.79,227.38 UNK3R15.1
SL13_DP_132: length 1.4
  BOTTOM w0.203: UNK3U4.2 231.71,227.38 UNK3R17.1
SL13_DP_133: length 0.8
  TOP w0.381: UNK5TP_OUT+_1.1 v1(126.61,235.54)
SL13_DP_134: length 0.8
  TOP w0.381: UNK5TP_OUT-_1.1 v1(124.31,235.54)
SL13_DP_135: length 0.8
  TOP w0.381: UNK5TP_OUT+_2.1 v1(133.22,235.54)
SL13_DP_136: length 0.8
  TOP w0.381: UNK5TP_OUT-_2.1 v1(130.91,235.54)
SL13_DP_137: length 1.4
  BOTTOM w0.203: UNK5U3.2 156.79,167.38 UNK5R15.1
SL13_DP_138: length 1.4
  BOTTOM w0.203: UNK5U4.2 151.71,167.38 UNK5R17.1
SL13_DP_139: length 0.8
  TOP w0.381: UNK7TP_OUT+_1.1 v1(206.61,235.54)
SL13_DP_140: length 0.8
  TOP w0.381: UNK7TP_OUT-_1.1 v1(204.31,235.54)
SL13_DP_141: length 0.8
  TOP w0.381: UNK7TP_OUT+_2.1 v1(213.21,235.54)
SL13_DP_142: length 0.8
  TOP w0.381: UNK7TP_OUT-_2.1 v1(210.91,235.54)
SL13_DP_143: length 1.4
  BOTTOM w0.203: UNK7R15.1 236.79,167.38 UNK7U3.2
SL13_DP_144: length 1.4
  BOTTOM w0.203: UNK7U4.2 231.71,167.38 UNK7R17.1
SL14_PMVI_10_HF:
  vias: v1(188.21,243.34)
SL14_PMVI_11_HF:
  vias: v1(196.46,243.34)
SL14_PMVI_12_HF: length 0.3
  BOTTOM w0.203: UNK2U1.4 v1(164.31,294.24)
SL14_PMVI_13_HF:
  vias: v1(170.91,294.24)
SL14_PMVI_14_HF:
  vias: v1(195.49,231.3)
SL14_PMVI_15_HF: length 2.2
  BOTTOM w0.203: UNK2C72.1 UNK2R15.2 UNK2U3.1
SL14_PMVI_16_HF: length 2.7
  BOTTOM w0.381: v1(195.49,226.57) 195.94,226.57 196.14,226.77 UNK2U3.3
SL14_PMVI_17_HF:
  vias: v1(190.41,231.3)
SL14_PMVI_18_HF: length 2.2
  BOTTOM w0.203: UNK2U4.1 UNK2R17.2 UNK2C73.1
SL14_PMVI_19_HF: length 0.9
  BOTTOM w0.381: UNK2TP_REF_2.1 v1(191.06,229.62)
SL14_PMVI_20_HF:
  vias: v1(268.21,243.34)
SL14_PMVI_21_HF:
  vias: v1(276.46,243.34)
SL14_PMVI_22_HF: length 0.3
  BOTTOM w0.203: UNK4U1.4 v1(244.31,294.24)
SL14_PMVI_23_HF:
  vias: v1(250.91,294.24)
SL14_PMVI_24_HF:
  vias: v1(275.49,231.3)
SL14_PMVI_25_HF: length 2.2
  BOTTOM w0.203: UNK4C72.1 UNK4R15.2 UNK4U3.1
SL14_PMVI_26_HF: length 2.7
  BOTTOM w0.381: UNK4U3.3 276.14,226.77 275.94,226.57 v1(275.49,226.57)
SL14_PMVI_27_HF:
  vias: v1(270.41,231.3)
SL14_PMVI_28_HF: length 2.2
  BOTTOM w0.203: UNK4C73.1 UNK4R17.2 UNK4U4.1
SL14_PMVI_29_HF: length 0.9
  BOTTOM w0.381: UNK4TP_REF_2.1 v1(271.06,229.62)
SL14_PMVI_30_HF:
  vias: v1(188.21,183.34)
SL14_PMVI_31_HF:
  vias: v1(196.46,183.34)
SL14_PMVI_32_HF: length 0.3
  BOTTOM w0.203: UNK6U1.4 v1(164.31,234.24)
SL14_PMVI_33_HF:
  vias: v1(170.91,234.24)
SL14_PMVI_34_HF:
  vias: v1(195.49,171.3)
SL14_PMVI_35_HF: length 2.2
  BOTTOM w0.203: UNK6U3.1 UNK6R15.2 UNK6C72.1
SL14_PMVI_36_HF: length 2.7
  BOTTOM w0.381: v1(195.49,166.57) 195.94,166.57 196.14,166.77 UNK6U3.3
SL14_PMVI_37_HF:
  vias: v1(190.41,171.3)
SL14_PMVI_38_HF: length 2.2
  BOTTOM w0.203: UNK6C73.1 UNK6R17.2 UNK6U4.1
SL14_PMVI_39_HF: length 0.9
  BOTTOM w0.381: UNK6TP_REF_2.1 v1(191.06,169.62)
SL14_PMVI_40_HF:
  vias: v1(268.21,183.34)
SL14_PMVI_41_HF:
  vias: v1(276.46,183.34)
SL14_PMVI_42_HF: length 0.3
  BOTTOM w0.203: UNK8U1.4 v1(244.31,234.24)
SL14_PMVI_43_HF:
  vias: v1(250.91,234.24)
SL14_PMVI_44_HF:
  vias: v1(275.49,171.3)
SL14_PMVI_45_HF: length 2.2
  BOTTOM w0.203: UNK8C72.1 UNK8R15.2 UNK8U3.1
SL14_PMVI_46_HF: length 2.7
  BOTTOM w0.381: UNK8U3.3 276.14,166.77 275.94,166.57 v1(275.49,166.57)
SL14_PMVI_47_HF:
  vias: v1(270.41,171.3)
SL14_PMVI_48_HF: length 2.2
  BOTTOM w0.203: UNK8C73.1 UNK8R17.2 UNK8U4.1
SL14_PMVI_49_HF: length 0.9
  BOTTOM w0.381: UNK8TP_REF_2.1 v1(271.06,169.62)
SL17_VI100_2_A_HF: length 11.5
  TOP w0.305: SITE5.2_F 146.18,208.74
  TOP w0.635: 146.18,208.74 140.98,208.74 v1(140.83,208.59)
  BOTTOM w0.635: UNK5C49.2 136.82,207.59 139.83,207.59 v1(140.83,208.59)
SL17_VI100_2_A_HS: length 7.8
  BOTTOM w0.203: v1(140.83,205.79) 141.97,205.79 144.92,208.74 v2(147.45,208.74)
SL17_VI100_2_B_HF: length 9.3
  TOP w0.305: SITE5.29_F 149.3,210.29 149.31,210.3 149.31,210.56 149.29,210.58 149.29,211 149.31,211.02 149.31,211.21 149.94,211.84
  TOP w0.635: v1(152.25,218.02) 151.49,217.25 151.49,213.39 149.94,211.84
SL17_VI100_2_B_HS: length 14.3
  BOTTOM w0.203: v2(149.3,209.59) 149.21,209.68 149.21,210.84 151.38,213.02 151.38,221.72 v1(152.25,222.59)
SL17_VI100_3_A_HF: length 16.3
  TOP w0.305: SITE5.5_F 145.45,207.24
  TOP w0.635: v1(140.83,201.22) 143.13,203.52 143.13,204.92 145.45,207.24
  BOTTOM w0.635: v1(135.11,201.22) 135.11,200.93 135.75,200.3 140.19,200.3 140.83,200.93 v1(140.83,201.22)
SL17_VI100_3_A_HS: length 13.4
  BOTTOM w0.203: v2(147.45,207.24) 146.97,207.24 142.62,202.89 137.13,202.89 v1(136.26,203.76)
SL17_VI100_3_B_HS: length 13
  BOTTOM w0.203: v1(149.12,193.35) 149.86,194.09 149.86,200.22 148.3,201.78 v2(148.3,205.39)
SL17_VI100_4_A_HS: length 8.3
  BOTTOM w0.203: v2(147.45,207.74) 145.82,207.74 141.84,203.76 v1(140.83,203.76)
SL17_VI100_4_B_HS: length 13.8
  BOTTOM w0.203: v2(151.65,205.74) 153.98,203.42 162.2,203.42 v1(163.84,201.77)
SL17_VI100_5_A_HF: length 23.1
  TOP w0.305: SITE5.6_F 146.47,206.74 146.18,206.45
  TOP w0.635: 146.18,206.45 144.16,204.43 v1(144.16,198.18)
  BOTTOM w0.508: 144.39,193.35 UNK5K12.4
  BOTTOM w0.635: 145.18,193.35 145.18,188.1 144.45,187.38 144.21,187.38 ; 145.18,193.35 145.18,197.54 144.54,198.18 v1(144.16,198.18) ; 145.18,193.35 144.39,193.35
SL17_VI100_5_A_HS:
  vias: v2(147.45,206.74)
SL17_VI100_6_A_HF:
  vias: v2(147.05,206.24)
SL17_VI100_6_A_HS:
  vias: v1(146.96,193.35) v2(147.45,206.24)
SL17_VI100_6_B_HF: length 1.7
  TOP w0.305: SITE5.30_F v2(148.8,211.66)
SL17_VI100_6_B_HS: length 4.5
  BOTTOM w0.203: UNK5K46.4 149.84,212.05 148.8,211.01 v2(148.8,209.59)
SL17_VI100_7_A_HF:
  vias: v2(149.8,204.99)
SL17_VI100_7_A_HS:
  vias: v1(154.07,193.35) v2(149.8,205.39)
SL17_VI100_7_B_HF: length 10.4
  TOP w0.305: 148.07,211.04 148.29,210.82 148.29,210.3 148.3,210.29 SITE5.31_F
  TOP w0.635: v1(149.84,219.54) 149.08,218.78 149.08,213.58 148.07,212.57 148.07,211.04
SL17_VI100_7_B_HS: length 15.2
  BOTTOM w0.203: v1(149.84,224.11) 149.05,223.33 149.05,212.6 148.3,211.84 v2(148.3,209.59)
SL17_VI100_8_B_HF: length 5.7
  TOP w0.305: 155.04,206.93 154.73,207.24 SITE5.20_F
  TOP w0.635: v1(156.03,205.94) 155.04,206.93
  BOTTOM w0.635: v1(156.03,205.94) UNK5C61.2
SL17_VI100_8_B_HS: length 17.5
  BOTTOM w0.203: v1(168.42,205.58) 166.93,207.06 154.7,207.06 154.53,207.24 v2(151.65,207.24)
SL17_VI100_9_B_HF: length 7.6
  TOP w0.305: 154.28,207.99 154.03,207.74 SITE5.21_F
  TOP w0.635: v1(159.27,208.62) 158.64,207.99 154.28,207.99
SL17_VI100_9_B_HS: length 13.3
  BOTTOM w0.203: v1(163.84,208.62) 162.97,209.49 156.34,209.49 154.58,207.74 v2(151.65,207.74)
SL17_VI100_10_A_HF: length 9.6
  TOP w0.305: 151.98,204.74 151.55,204.74 SITE5.16_F
  TOP w0.635: v1(157.37,198.18) 156.72,198.83 156.72,200.01 151.98,204.74
SL17_VI100_10_A_HS: length 15.2
  BOTTOM w0.203: v2(151.3,205.39) 151.3,205.13 155.83,200.6 155.83,194.51 156.08,194.25 157.17,194.25 157.37,194.05 v1(157.37,193.35)
SL17_VI100_10_B_HF: length 0.4
  TOP w0.305: SITE5.25_F v2(151.3,210.39)
SL17_VI100_10_B_HS: length 5.7
  BOTTOM w0.203: v2(151.3,209.59) 151.36,209.65 153.95,209.65 155.17,210.87 v1(155.17,212.18)
SL17_VI100_11_A_HF: length 7.2
  TOP w0.305: 153.62,205.67 153.05,206.24 SITE5.18_F
  TOP w0.635: v1(157.73,202.67) 156.62,202.67 153.62,205.67
SL17_VI100_11_A_HS: length 18.6
  BOTTOM w0.203: v1(168.42,201.77) 166.28,203.91 154.31,203.91 151.97,206.24 v2(151.65,206.24)
SL17_VI100_11_B_HF: length 0.4
  TOP w0.305: SITE5.26_F v2(150.8,210.39)
SL17_VI100_11_B_HS: length 10.5
  BOTTOM w0.203: v1(155.17,216.75) 154.43,216 154.43,210.7 153.88,210.16 151.7,210.16 151.57,210.03 151.16,210.03 150.8,209.67 v2(150.8,209.59)
SL17_VI100_12_A_HF: length 8.2
  TOP w0.305: SITE5.19_F 153.59,206.74 154.13,206.19 154.31,206.19
  TOP w0.635: v1(159.27,205.58) 158.62,204.92 155.58,204.92 154.31,206.19
SL17_VI100_12_A_HS: length 12.7
  BOTTOM w0.203: v2(151.65,206.74) 154.27,206.74 154.43,206.58 162.84,206.58 v1(163.84,205.58)
SL17_VI100_12_B_HF: length 1.1
  TOP w0.305: v2(149.8,210.79) 150,210.79 150.3,210.49 SITE5.27_F
SL17_VI100_12_B_HS: length 15.4
  BOTTOM w0.152: 150.71,210.8 150.44,210.53 150.44,209.73 v2(150.3,209.59)
  BOTTOM w0.203: v1(155.17,221.32) 154.05,220.2 154.05,216.2 154.03,216.17 154.03,211.32 153.5,210.8 150.71,210.8
SL17_VI100_13_A_HF: length 8.4
  TOP w0.305: 153.66,208.65 153.26,208.25 152.44,208.25 152.44,208.24 SITE5.22_F
  TOP w0.635: 153.66,208.65 153.99,208.98 157.62,208.98 v1(157.73,208.86)
  BOTTOM w0.635: UNK5C64.2 156.03,208.22 156.67,208.86 v1(157.73,208.86)
SL17_VI100_13_A_HS: length 18.1
  BOTTOM w0.203: v2(151.65,208.24) 154.45,208.24 156.21,210 167.04,210 v1(168.42,208.62)
SL17_VI100_13_B_HF: length 0.4
  TOP w0.305: SITE5.32_F v2(147.8,210.39)
  vias: v1(147.43,224.11)
SL17_VI100_13_B_HS: length 9.9
  BOTTOM w0.203: v1(147.43,218.27) 147.43,217.01 148.59,215.84 148.59,212.71 147.33,211.45 147.33,210.33 147.8,209.86 v2(147.8,209.59)
SL17_VI100_14_A_HF: length 8.4
  TOP w0.305: SITE5.23_F 152.52,208.74 152.97,209.19
  TOP w0.635: 152.97,209.19 153.75,209.97 157.57,209.97 v1(159.27,211.67)
SL17_VI100_14_A_HS: length 14.9
  BOTTOM w0.203: v1(163.84,211.67) 162.85,212.67 157.43,212.67 157.12,212.36 157.12,211.23 156.59,210.7 156.27,210.7 154.31,208.74 v2(151.65,208.74)
SL17_VI100_14_B_HS: length 9.2
  BOTTOM w0.203: v1(154.07,198.18) 154.07,199.95 149.3,204.72 v2(149.3,205.39)
SL17_VI100_15_A_HF: length 10
  TOP w0.305: 152.28,209.81 152.05,209.58 SITE5.24_F
  TOP w0.635: v1(159.27,214.21) 158.47,213.41 157.62,213.41 156.98,212.77 156.98,211.92 155.98,210.92 153.39,210.92 152.28,209.81
SL17_VI100_15_A_HS: length 17.3
  BOTTOM w0.203: v1(163.84,214.21) 162.72,215.34 156.97,215.34 156.72,215.08 156.72,211.4 156.46,211.15 156.08,211.15 154.18,209.24 v2(151.65,209.24)
SL17_VI100_15_B_HS: length 13.9
  BOTTOM w0.203: v1(151.91,193.35) 151.91,193.85 151.51,194.25 150.57,194.25 150.36,194.46 150.36,200.61 148.8,202.17 v2(148.8,205.39)
SL17_VI100_16_A_HF: length 0.4
  TOP w0.305: SITE5.28_F v2(149.8,210.39)
SL17_VI100_16_A_HS: length 4.1
  BOTTOM w0.152: 150.25,210.97 150.14,210.86 150.14,210.08 149.8,209.74 v2(149.8,209.59)
  BOTTOM w0.203: v1(152.25,212.18) 151.28,211.2 150.49,211.2 150.25,210.97
SL17_VI100_16_B_HS: length 7.8
  BOTTOM w0.203: v2(147.8,205.39) 147.8,201.39 149.12,200.08 v1(149.12,198.18)
SL17_VI100_18_A_HF: length 11.5
  TOP w0.305: SITE7.2_F 226.18,208.74
  TOP w0.635: 226.18,208.74 220.98,208.74 v1(220.83,208.59)
  BOTTOM w0.635: v1(220.83,208.59) 219.83,207.59 216.82,207.59 UNK7C49.2
SL17_VI100_18_A_HS: length 7.8
  BOTTOM w0.203: v1(220.83,205.79) 221.97,205.79 224.92,208.74 v2(227.45,208.74)
SL17_VI100_18_B_HF: length 9.3
  TOP w0.305: SITE7.29_F 229.3,210.29 229.31,210.3 229.31,210.56 229.29,210.58 229.29,211 229.31,211.02 229.31,211.21 229.94,211.84
  TOP w0.635: v1(232.25,218.02) 231.49,217.25 231.49,213.39 229.94,211.84
SL17_VI100_18_B_HS: length 14.3
  BOTTOM w0.203: v2(229.3,209.59) 229.21,209.68 229.21,210.84 231.38,213.02 231.38,221.72 v1(232.25,222.59)
SL17_VI100_19_A_HF: length 16.3
  TOP w0.305: SITE7.5_F 225.45,207.24
  TOP w0.635: v1(220.83,201.22) 223.13,203.52 223.13,204.92 225.45,207.24
  BOTTOM w0.635: v1(215.11,201.22) 215.11,200.93 215.75,200.3 220.19,200.3 220.83,200.93 v1(220.83,201.22)
SL17_VI100_19_A_HS: length 13.4
  BOTTOM w0.203: v2(227.45,207.24) 226.97,207.24 222.62,202.89 217.13,202.89 v1(216.26,203.76)
SL17_VI100_19_B_HS: length 13
  BOTTOM w0.203: v2(228.3,205.39) 228.3,201.78 229.86,200.22 229.86,194.09 v1(229.12,193.35)
SL17_VI100_20_A_HS: length 8.3
  BOTTOM w0.203: v2(227.45,207.74) 225.82,207.74 221.84,203.76 v1(220.83,203.76)
SL17_VI100_20_B_HS: length 13.8
  BOTTOM w0.203: v1(243.84,201.77) 242.19,203.42 233.97,203.42 v2(231.65,205.74)
SL17_VI100_21_A_HF: length 23.1
  TOP w0.305: 226.18,206.45 226.47,206.74 SITE7.6_F
  TOP w0.635: v1(224.16,198.18) 224.16,204.43 226.18,206.45
  BOTTOM w0.508: 224.38,193.35 UNK7K12.4
  BOTTOM w0.635: 225.18,193.35 225.18,197.54 224.54,198.18 v1(224.16,198.18) ; 225.18,193.35 224.38,193.35 ; 225.18,193.35 225.18,188.1 224.45,187.38 224.21,187.38
SL17_VI100_21_A_HS:
  vias: v2(227.45,206.74)
SL17_VI100_22_A_HF:
  vias: v2(227.05,206.24)
SL17_VI100_22_A_HS:
  vias: v1(226.96,193.35) v2(227.45,206.24)
SL17_VI100_22_B_HF: length 1.7
  TOP w0.305: SITE7.30_F v2(228.8,211.66)
SL17_VI100_22_B_HS: length 4.5
  BOTTOM w0.203: UNK7K46.4 229.84,212.05 228.8,211.01 v2(228.8,209.59)
SL17_VI100_23_A_HF:
  vias: v2(229.8,204.99)
SL17_VI100_23_A_HS:
  vias: v1(234.07,193.35) v2(229.8,205.39)
SL17_VI100_23_B_HF: length 10.4
  TOP w0.305: 228.07,211.04 228.29,210.82 228.29,210.3 228.3,210.29 SITE7.31_F
  TOP w0.635: v1(229.84,219.54) 229.08,218.78 229.08,213.58 228.07,212.57 228.07,211.04
SL17_VI100_23_B_HS: length 15.2
  BOTTOM w0.203: v1(229.84,224.11) 229.05,223.33 229.05,212.6 228.3,211.84 v2(228.3,209.59)
SL17_VI100_24_B_HF: length 5.7
  TOP w0.305: 235.04,206.93 234.73,207.24 SITE7.20_F
  TOP w0.635: v1(236.03,205.94) 235.04,206.93
  BOTTOM w0.635: v1(236.03,205.94) UNK7C61.2
SL17_VI100_24_B_HS: length 17.5
  BOTTOM w0.203: v1(248.42,205.58) 246.93,207.06 234.7,207.06 234.53,207.24 v2(231.65,207.24)
SL17_VI100_25_B_HF: length 7.6
  TOP w0.305: 234.28,207.99 234.03,207.74 SITE7.21_F
  TOP w0.635: 234.28,207.99 238.64,207.99 v1(239.27,208.62)
SL17_VI100_25_B_HS: length 13.3
  BOTTOM w0.203: v1(243.84,208.62) 242.97,209.49 236.34,209.49 234.58,207.74 v2(231.65,207.74)
SL17_VI100_26_A_HF: length 9.6
  TOP w0.305: 231.98,204.74 231.55,204.74 SITE7.16_F
  TOP w0.635: v1(237.37,198.18) 236.72,198.83 236.72,200.01 231.98,204.74
SL17_VI100_26_A_HS: length 15.2
  BOTTOM w0.203: v1(237.37,193.35) 237.37,194.05 237.17,194.25 236.08,194.25 235.83,194.51 235.83,200.6 231.3,205.13 v2(231.3,205.39)
SL17_VI100_26_B_HF: length 0.4
  TOP w0.305: SITE7.25_F v2(231.3,210.39)
SL17_VI100_26_B_HS: length 5.7
  BOTTOM w0.203: v2(231.3,209.59) 231.36,209.65 233.95,209.65 235.17,210.87 v1(235.17,212.18)
SL17_VI100_27_A_HF: length 7.2
  TOP w0.305: 233.62,205.67 233.05,206.24 SITE7.18_F
  TOP w0.635: v1(237.73,202.67) 236.62,202.67 233.62,205.67
SL17_VI100_27_A_HS: length 18.6
  BOTTOM w0.203: v2(231.65,206.24) 231.97,206.24 234.3,203.91 246.28,203.91 v1(248.42,201.77)
SL17_VI100_27_B_HF: length 0.4
  TOP w0.305: SITE7.26_F v2(230.8,210.39)
SL17_VI100_27_B_HS: length 10.5
  BOTTOM w0.203: v2(230.8,209.59) 230.8,209.67 231.16,210.03 231.57,210.03 231.7,210.16 233.88,210.16 234.43,210.7 234.43,216 v1(235.17,216.75)
SL17_VI100_28_A_HF: length 8.2
  TOP w0.305: SITE7.19_F 233.59,206.74 234.13,206.19 234.3,206.19
  TOP w0.635: v1(239.27,205.58) 238.62,204.92 235.57,204.92 234.3,206.19
SL17_VI100_28_A_HS: length 12.7
  BOTTOM w0.203: v1(243.84,205.58) 242.84,206.58 234.43,206.58 234.27,206.74 v2(231.65,206.74)
SL17_VI100_28_B_HF: length 1.1
  TOP w0.305: SITE7.27_F 230.3,210.49 230,210.79 v2(229.8,210.79)
SL17_VI100_28_B_HS: length 15.4
  BOTTOM w0.152: 230.71,210.8 230.44,210.53 230.44,209.73 v2(230.3,209.59)
  BOTTOM w0.203: v1(235.17,221.32) 234.05,220.2 234.05,216.2 234.03,216.17 234.03,211.32 233.5,210.8 230.71,210.8
SL17_VI100_29_A_HF: length 8.4
  TOP w0.305: SITE7.22_F 232.44,208.24 232.44,208.25 233.26,208.25 233.66,208.65
  TOP w0.635: 233.66,208.65 233.99,208.98 237.62,208.98 v1(237.73,208.86)
  BOTTOM w0.635: v1(237.73,208.86) 236.67,208.86 236.03,208.22 UNK7C64.2
SL17_VI100_29_A_HS: length 18.1
  BOTTOM w0.203: v2(231.65,208.24) 234.45,208.24 236.21,210 247.04,210 v1(248.42,208.62)
SL17_VI100_29_B_HF: length 0.4
  TOP w0.305: SITE7.32_F v2(227.8,210.39)
  vias: v1(227.43,224.11)
SL17_VI100_29_B_HS: length 9.9
  BOTTOM w0.203: v2(227.8,209.59) 227.8,209.86 227.33,210.33 227.33,211.45 228.59,212.71 228.59,215.84 227.43,217.01 v1(227.43,218.27)
SL17_VI100_30_A_HF: length 8.4
  TOP w0.305: 232.97,209.19 232.52,208.74 SITE7.23_F
  TOP w0.635: 232.97,209.19 233.75,209.97 237.57,209.97 v1(239.27,211.67)
SL17_VI100_30_A_HS: length 14.9
  BOTTOM w0.203: v2(231.65,208.74) 234.31,208.74 236.27,210.7 236.59,210.7 237.12,211.23 237.12,212.36 237.43,212.67 242.85,212.67 v1(243.84,211.67)
SL17_VI100_30_B_HS: length 9.2
  BOTTOM w0.203: v2(229.3,205.39) 229.3,204.72 234.07,199.95 v1(234.07,198.18)
SL17_VI100_31_A_HF: length 10
  TOP w0.305: SITE7.24_F 232.05,209.58 232.28,209.81
  TOP w0.635: 232.28,209.81 233.39,210.92 235.98,210.92 236.98,211.92 236.98,212.77 237.62,213.41 238.47,213.41 v1(239.27,214.21)
SL17_VI100_31_A_HS: length 17.3
  BOTTOM w0.203: v2(231.65,209.24) 234.18,209.24 236.08,211.15 236.46,211.15 236.72,211.4 236.72,215.08 236.97,215.34 242.72,215.34 v1(243.84,214.21)
SL17_VI100_31_B_HS: length 13.9
  BOTTOM w0.203: v1(231.91,193.35) 231.91,193.85 231.51,194.25 230.57,194.25 230.36,194.46 230.36,200.61 228.8,202.17 v2(228.8,205.39)
SL17_VI100_32_A_HF: length 0.4
  TOP w0.305: SITE7.28_F v2(229.8,210.39)
SL17_VI100_32_A_HS: length 4.1
  BOTTOM w0.152: 230.25,210.97 230.14,210.86 230.14,210.08 229.8,209.74 v2(229.8,209.59)
  BOTTOM w0.203: 230.25,210.97 230.49,211.2 231.28,211.2 v1(232.25,212.18)
SL17_VI100_32_B_HS: length 7.8
  BOTTOM w0.203: v2(227.8,205.39) 227.8,201.39 229.12,200.08 v1(229.12,198.18)
SL18_VI100_2_A_HF: length 11.5
  TOP w0.305: SITE6.2_F 186.18,208.74
  TOP w0.635: v1(180.83,208.59) 180.98,208.74 186.18,208.74
  BOTTOM w0.635: UNK6C49.2 176.82,207.59 179.83,207.59 v1(180.83,208.59)
SL18_VI100_2_A_HS: length 7.8
  BOTTOM w0.203: v2(187.45,208.74) 184.92,208.74 181.97,205.79 v1(180.83,205.79)
SL18_VI100_2_B_HF: length 9.3
  TOP w0.305: SITE6.29_F 189.3,210.29 189.31,210.3 189.31,210.56 189.29,210.58 189.29,211 189.31,211.02 189.31,211.21 189.94,211.84
  TOP w0.635: v1(192.25,218.02) 191.49,217.25 191.49,213.39 189.94,211.84
SL18_VI100_2_B_HS: length 14.3
  BOTTOM w0.203: v2(189.3,209.59) 189.21,209.68 189.21,210.84 191.38,213.02 191.38,221.72 v1(192.25,222.59)
SL18_VI100_3_A_HF: length 16.3
  TOP w0.305: SITE6.5_F 185.45,207.24
  TOP w0.635: 185.45,207.24 183.13,204.92 183.13,203.52 v1(180.83,201.22)
  BOTTOM w0.635: v1(175.11,201.22) 175.11,200.93 175.75,200.3 180.19,200.3 180.83,200.93 v1(180.83,201.22)
SL18_VI100_3_A_HS: length 13.4
  BOTTOM w0.203: v2(187.45,207.24) 186.97,207.24 182.62,202.89 177.13,202.89 v1(176.26,203.76)
SL18_VI100_3_B_HS: length 13
  BOTTOM w0.203: v1(189.12,193.35) 189.86,194.09 189.86,200.22 188.3,201.78 v2(188.3,205.39)
SL18_VI100_4_A_HS: length 8.3
  BOTTOM w0.203: v2(187.45,207.74) 185.82,207.74 181.84,203.76 v1(180.83,203.76)
SL18_VI100_4_B_HS: length 13.8
  BOTTOM w0.203: v2(191.65,205.74) 193.97,203.42 202.19,203.42 v1(203.84,201.77)
SL18_VI100_5_A_HF: length 23.1
  TOP w0.305: 186.18,206.45 186.47,206.74 SITE6.6_F
  TOP w0.635: v1(184.16,198.18) 184.16,204.43 186.18,206.45
  BOTTOM w0.508: 184.38,193.35 UNK6K12.4
  BOTTOM w0.635: 185.18,193.35 184.38,193.35 ; 185.18,193.35 185.18,188.1 184.45,187.38 184.21,187.38 ; 185.18,193.35 185.18,197.54 184.54,198.18 v1(184.16,198.18)
SL18_VI100_5_A_HS:
  vias: v2(187.45,206.74)
SL18_VI100_6_A_HF:
  vias: v2(187.05,206.24)
SL18_VI100_6_A_HS:
  vias: v1(186.96,193.35) v2(187.45,206.24)
SL18_VI100_6_B_HF: length 1.7
  TOP w0.305: SITE6.30_F v2(188.8,211.66)
SL18_VI100_6_B_HS: length 4.5
  BOTTOM w0.203: UNK6K46.4 189.84,212.05 188.8,211.01 v2(188.8,209.59)
SL18_VI100_7_A_HF:
  vias: v2(189.8,204.99)
SL18_VI100_7_A_HS:
  vias: v1(194.07,193.35) v2(189.8,205.39)
SL18_VI100_7_B_HF: length 10.4
  TOP w0.305: 188.07,211.04 188.29,210.82 188.29,210.3 188.3,210.29 SITE6.31_F
  TOP w0.635: 188.07,211.04 188.07,212.57 189.08,213.58 189.08,218.78 v1(189.84,219.54)
SL18_VI100_7_B_HS: length 15.2
  BOTTOM w0.203: v2(188.3,209.59) 188.3,211.84 189.05,212.6 189.05,223.33 v1(189.84,224.11)
SL18_VI100_8_B_HF: length 5.7
  TOP w0.305: 195.04,206.93 194.73,207.24 SITE6.20_F
  TOP w0.635: v1(196.03,205.94) 195.04,206.93
  BOTTOM w0.635: v1(196.03,205.94) UNK6C61.2
SL18_VI100_8_B_HS: length 17.5
  BOTTOM w0.203: v2(191.65,207.24) 194.53,207.24 194.7,207.06 206.93,207.06 v1(208.42,205.58)
SL18_VI100_9_B_HF: length 7.6
  TOP w0.305: SITE6.21_F 194.03,207.74 194.28,207.99
  TOP w0.635: 194.28,207.99 198.64,207.99 v1(199.27,208.62)
SL18_VI100_9_B_HS: length 13.3
  BOTTOM w0.203: v1(203.84,208.62) 202.97,209.49 196.34,209.49 194.58,207.74 v2(191.65,207.74)
SL18_VI100_10_A_HF: length 9.6
  TOP w0.305: SITE6.16_F 191.55,204.74 191.98,204.74
  TOP w0.635: 191.98,204.74 196.72,200.01 196.72,198.83 v1(197.37,198.18)
SL18_VI100_10_A_HS: length 15.2
  BOTTOM w0.203: v2(191.3,205.39) 191.3,205.13 195.83,200.6 195.83,194.51 196.08,194.25 197.17,194.25 197.37,194.05 v1(197.37,193.35)
SL18_VI100_10_B_HF: length 0.4
  TOP w0.305: SITE6.25_F v2(191.3,210.39)
SL18_VI100_10_B_HS: length 5.7
  BOTTOM w0.203: v1(195.17,212.18) 195.17,210.87 193.95,209.65 191.36,209.65 v2(191.3,209.59)
SL18_VI100_11_A_HF: length 7.2
  TOP w0.305: SITE6.18_F 193.05,206.24 193.62,205.67
  TOP w0.635: 193.62,205.67 196.62,202.67 v1(197.73,202.67)
SL18_VI100_11_A_HS: length 18.6
  BOTTOM w0.203: v2(191.65,206.24) 191.97,206.24 194.3,203.91 206.28,203.91 v1(208.42,201.77)
SL18_VI100_11_B_HF: length 0.4
  TOP w0.305: SITE6.26_F v2(190.8,210.39)
SL18_VI100_11_B_HS: length 10.5
  BOTTOM w0.203: v1(195.17,216.75) 194.43,216 194.43,210.7 193.88,210.16 191.7,210.16 191.57,210.03 191.16,210.03 190.8,209.67 v2(190.8,209.59)
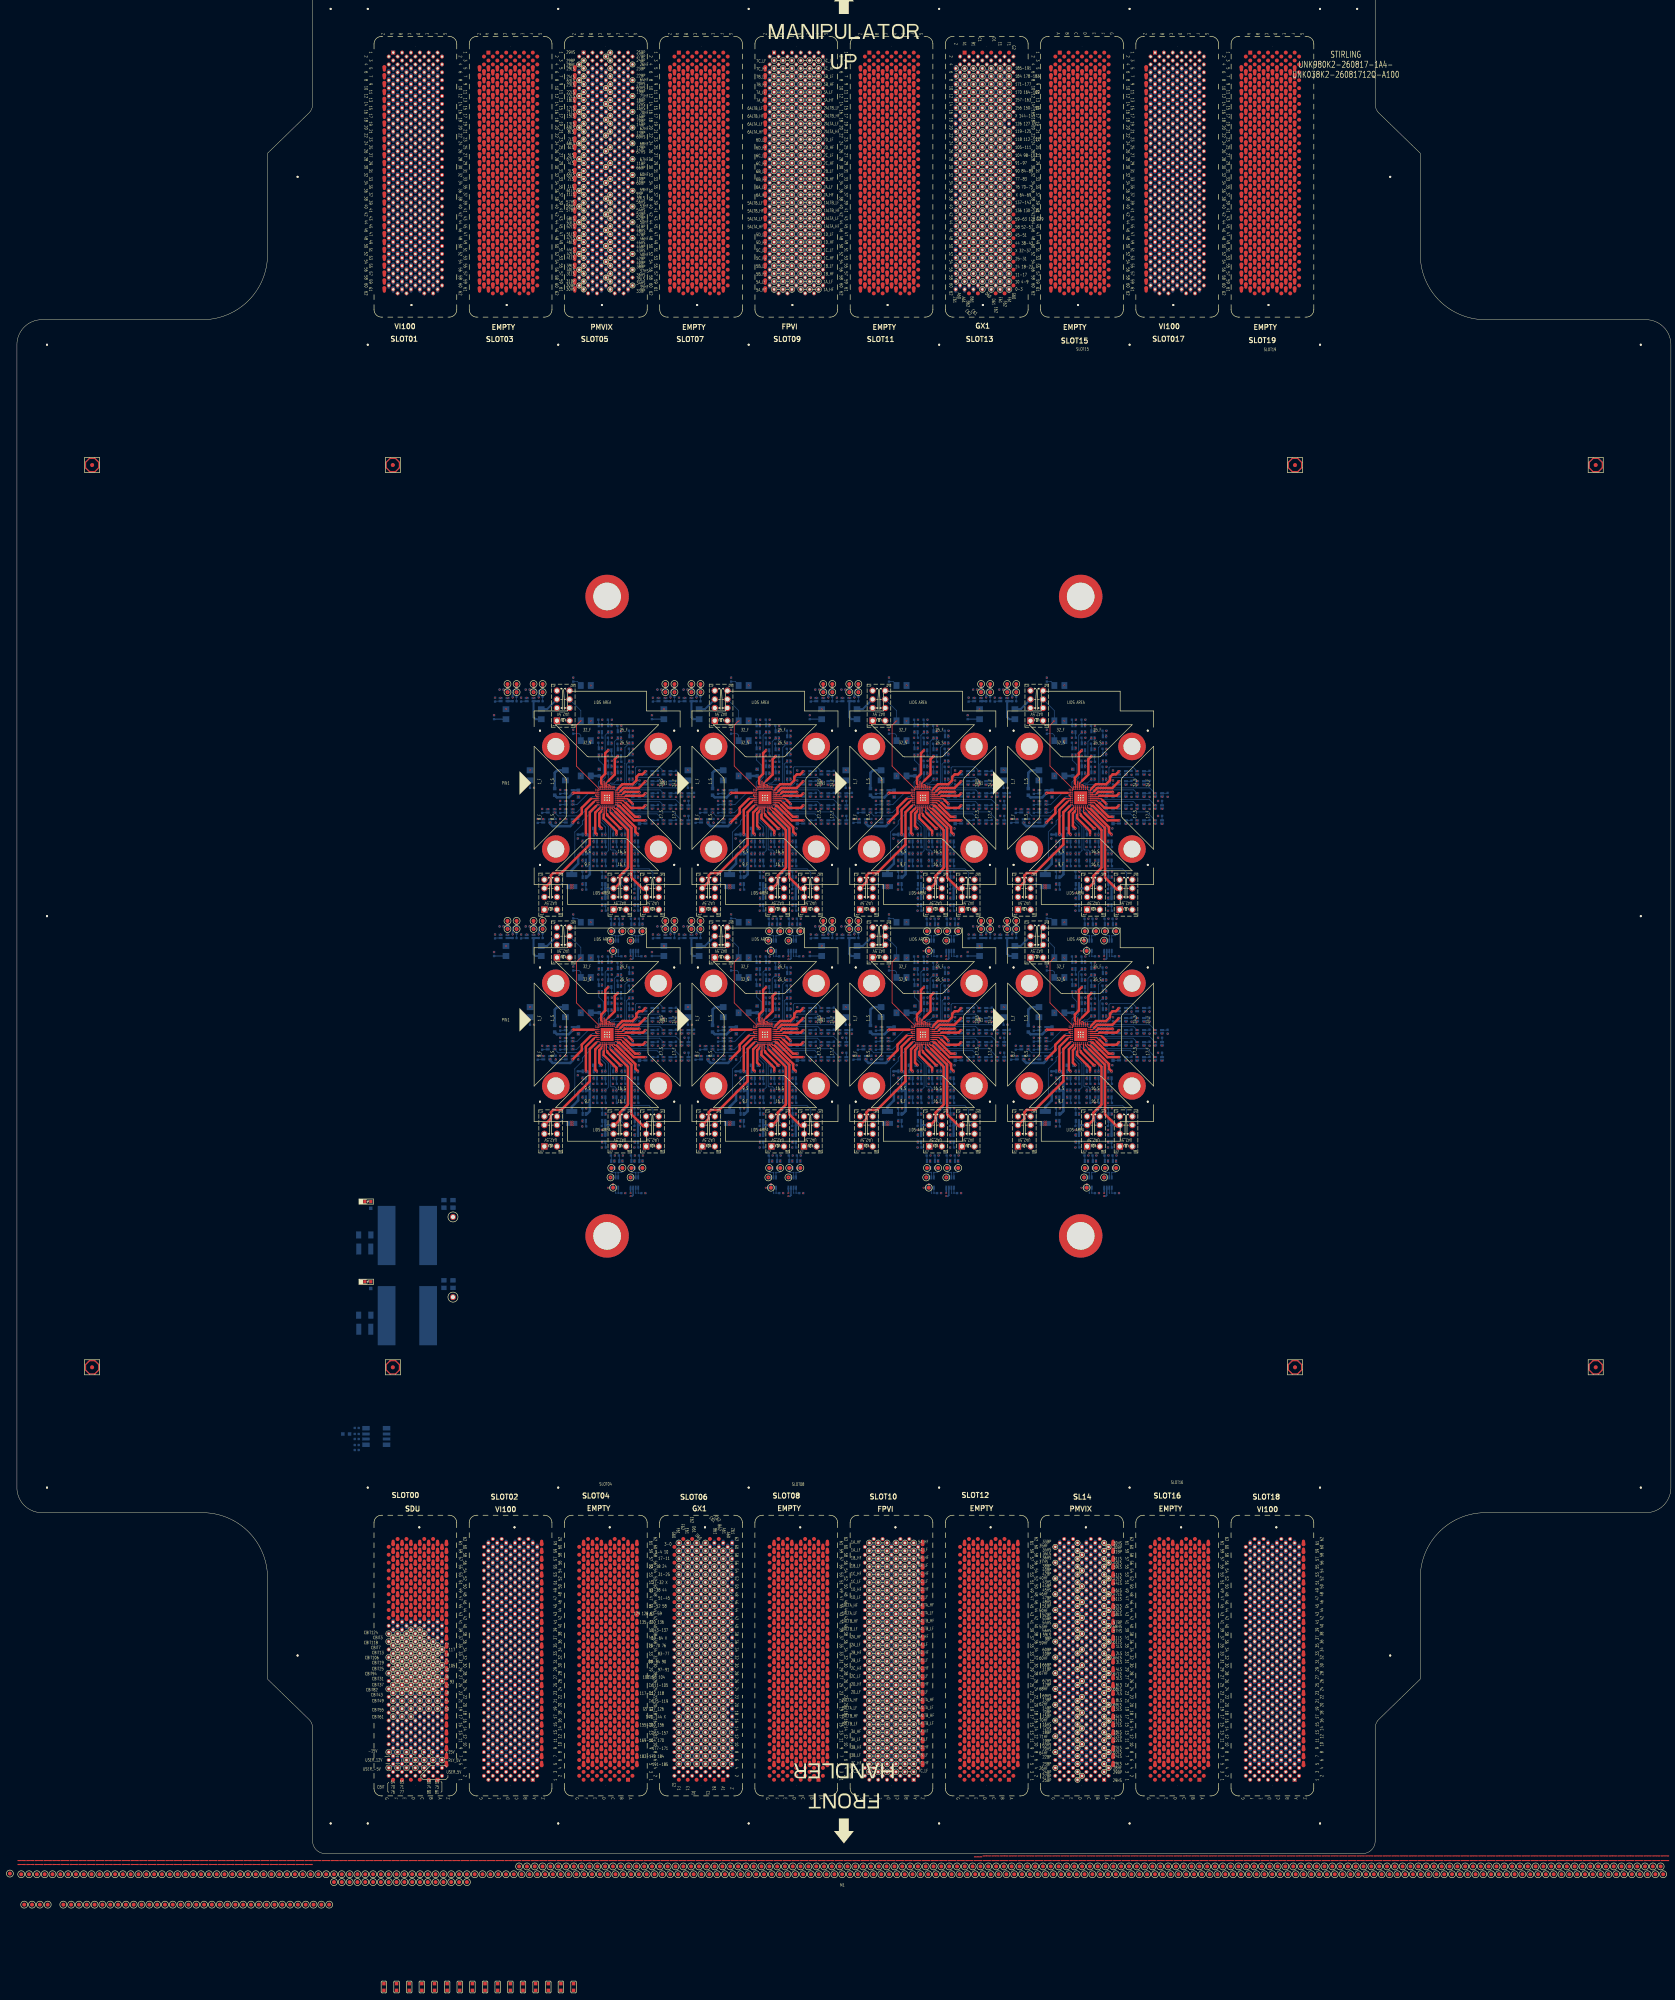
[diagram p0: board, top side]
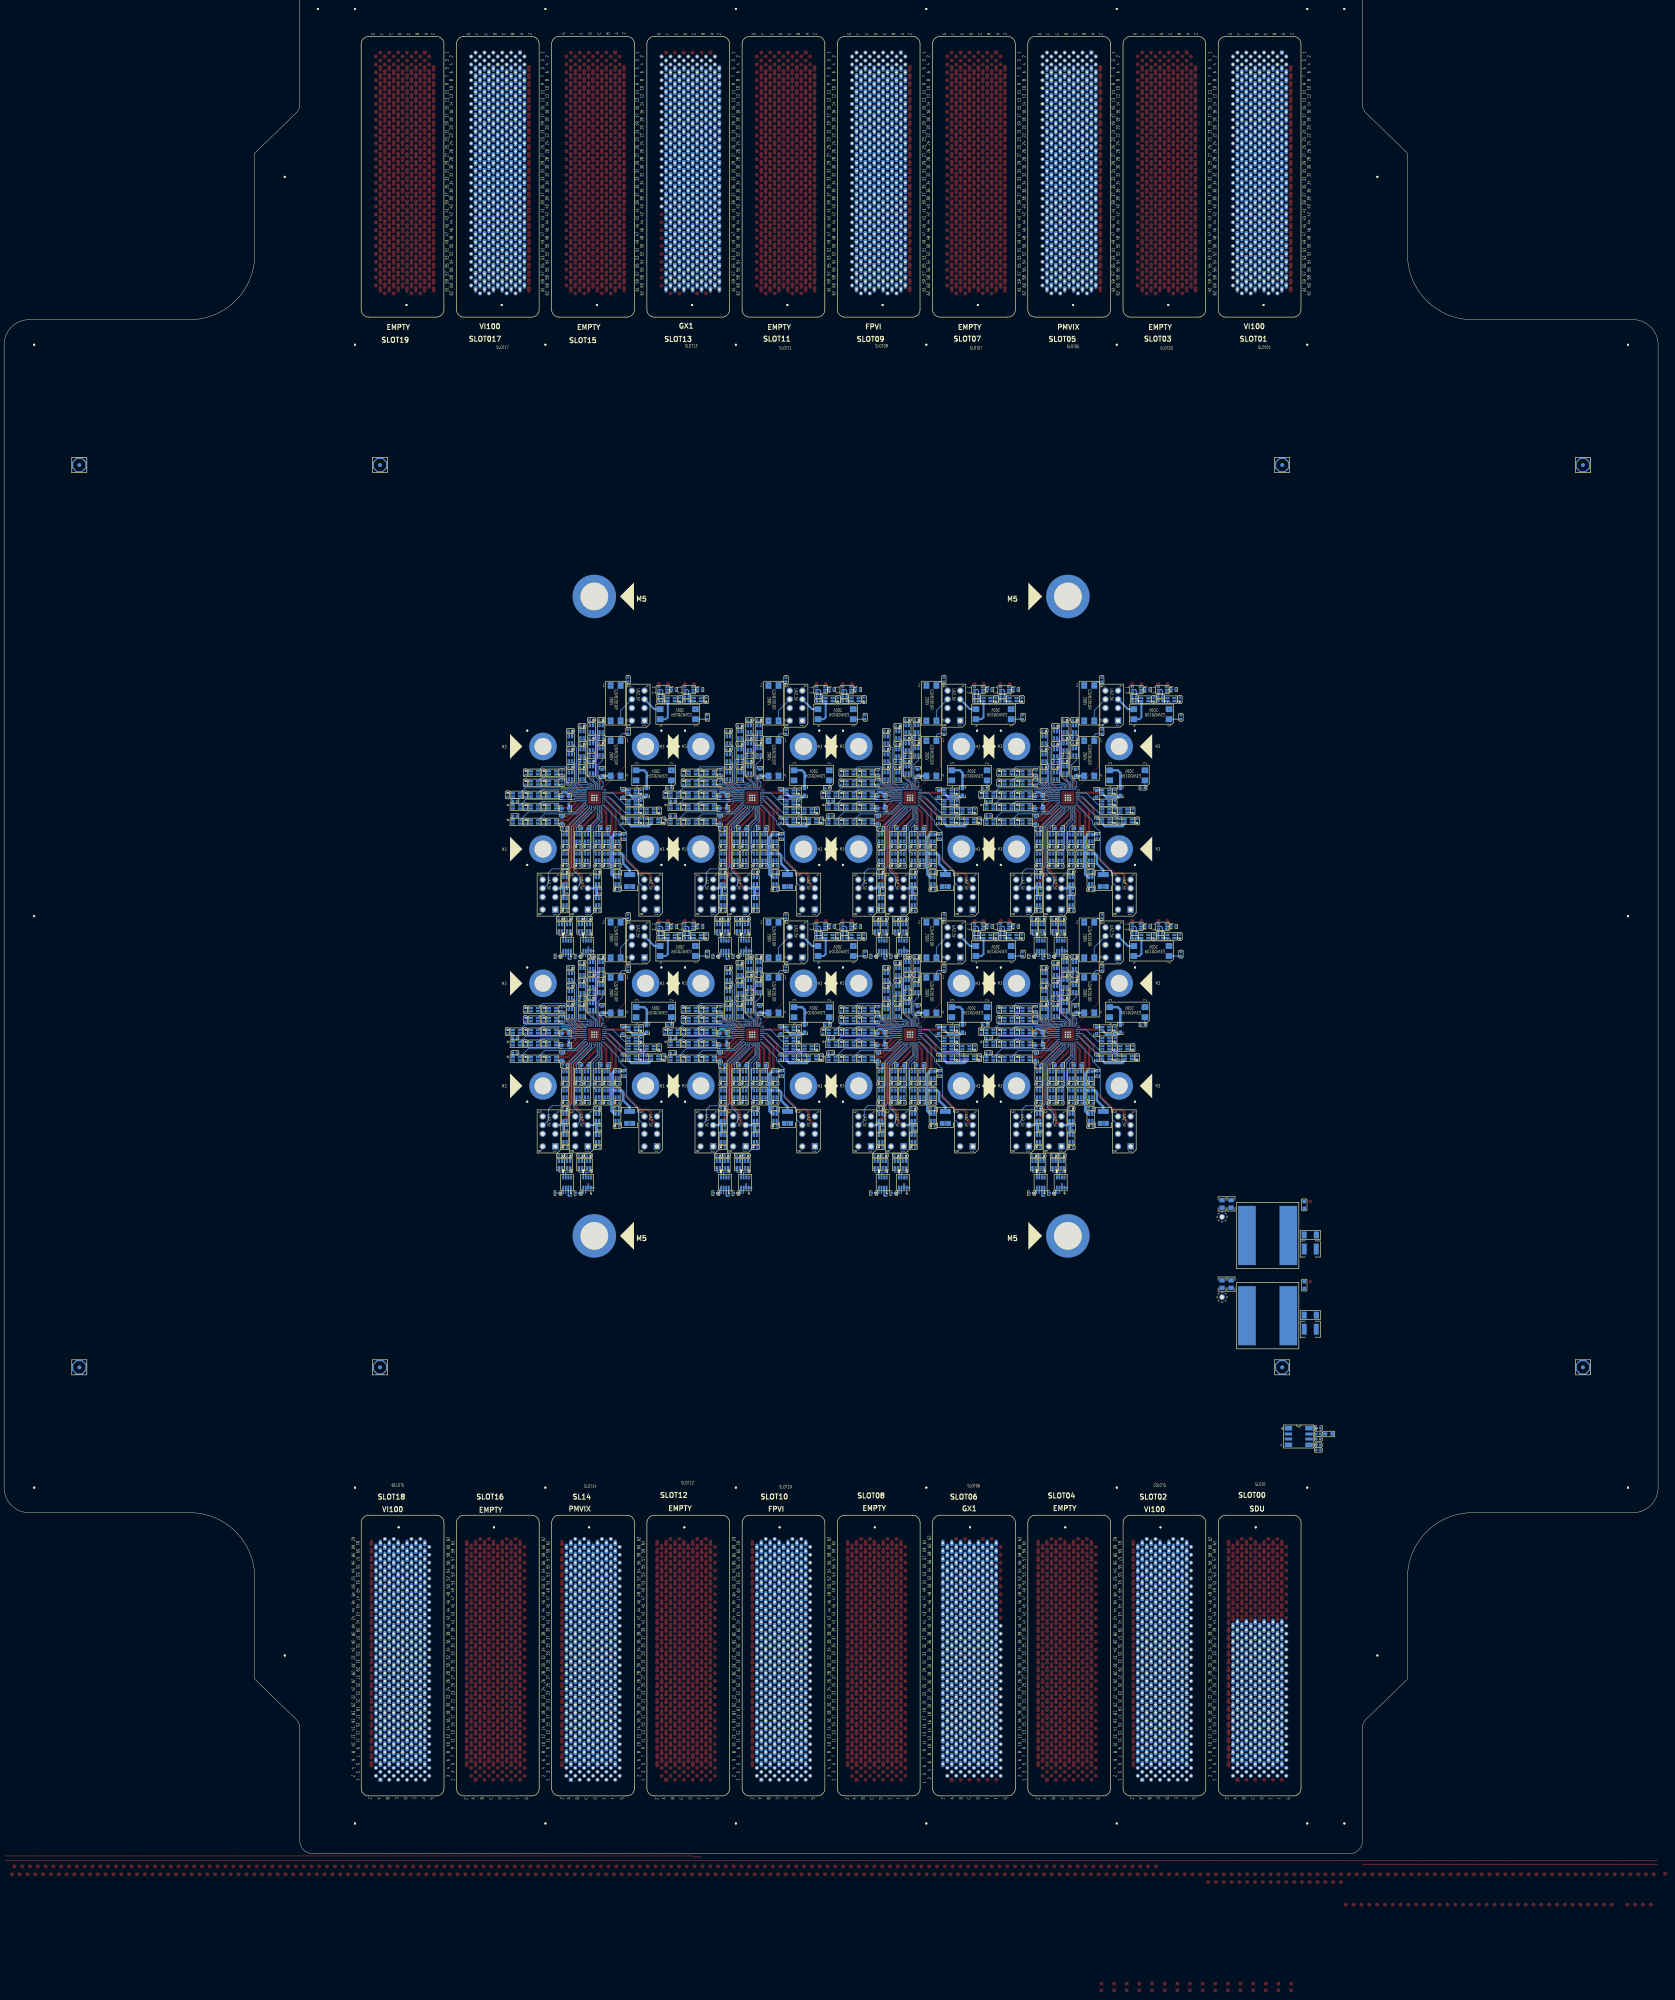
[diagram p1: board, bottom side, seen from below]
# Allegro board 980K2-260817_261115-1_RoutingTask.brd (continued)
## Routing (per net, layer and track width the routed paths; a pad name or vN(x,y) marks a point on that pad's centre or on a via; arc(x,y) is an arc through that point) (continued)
SL18_VI100_12_A_HF: length 8.2
  TOP w0.305: 194.3,206.19 194.13,206.19 193.59,206.74 SITE6.19_F
  TOP w0.635: 194.3,206.19 195.57,204.92 198.62,204.92 v1(199.27,205.58)
SL18_VI100_12_A_HS: length 12.7
  BOTTOM w0.203: v2(191.65,206.74) 194.27,206.74 194.43,206.58 202.84,206.58 v1(203.84,205.58)
SL18_VI100_12_B_HF: length 1.1
  TOP w0.305: v2(189.8,210.79) 190,210.79 190.3,210.49 SITE6.27_F
SL18_VI100_12_B_HS: length 15.4
  BOTTOM w0.152: 190.71,210.8 190.44,210.53 190.44,209.73 v2(190.3,209.59)
  BOTTOM w0.203: v1(195.17,221.32) 194.05,220.2 194.05,216.2 194.03,216.17 194.03,211.32 193.5,210.8 190.71,210.8
SL18_VI100_13_A_HF: length 8.4
  TOP w0.305: SITE6.22_F 192.44,208.24 192.44,208.25 193.26,208.25 193.66,208.65
  TOP w0.635: 193.66,208.65 193.99,208.98 197.62,208.98 v1(197.73,208.86)
  BOTTOM w0.635: UNK6C64.2 196.03,208.22 196.67,208.86 v1(197.73,208.86)
SL18_VI100_13_A_HS: length 18.1
  BOTTOM w0.203: v2(191.65,208.24) 194.45,208.24 196.21,210 207.04,210 v1(208.42,208.62)
SL18_VI100_13_B_HF: length 0.4
  TOP w0.305: SITE6.32_F v2(187.8,210.39)
  vias: v1(187.43,224.11)
SL18_VI100_13_B_HS: length 9.9
  BOTTOM w0.203: v2(187.8,209.59) 187.8,209.86 187.33,210.33 187.33,211.45 188.59,212.71 188.59,215.84 187.43,217.01 v1(187.43,218.27)
SL18_VI100_14_A_HF: length 8.4
  TOP w0.305: 192.97,209.19 192.52,208.74 SITE6.23_F
  TOP w0.635: v1(199.27,211.67) 197.57,209.97 193.75,209.97 192.97,209.19
SL18_VI100_14_A_HS: length 14.9
  BOTTOM w0.203: v2(191.65,208.74) 194.31,208.74 196.27,210.7 196.59,210.7 197.12,211.23 197.12,212.36 197.43,212.67 202.85,212.67 v1(203.84,211.67)
SL18_VI100_14_B_HS: length 9.2
  BOTTOM w0.203: v2(189.3,205.39) 189.3,204.72 194.07,199.95 v1(194.07,198.18)
SL18_VI100_15_A_HF: length 10
  TOP w0.305: 192.28,209.81 192.05,209.58 SITE6.24_F
  TOP w0.635: 192.28,209.81 193.39,210.92 195.98,210.92 196.98,211.92 196.98,212.77 197.62,213.41 198.47,213.41 v1(199.27,214.21)
SL18_VI100_15_A_HS: length 17.3
  BOTTOM w0.203: v1(203.84,214.21) 202.72,215.34 196.97,215.34 196.72,215.08 196.72,211.4 196.46,211.15 196.08,211.15 194.18,209.24 v2(191.65,209.24)
SL18_VI100_15_B_HS: length 13.9
  BOTTOM w0.203: v2(188.8,205.39) 188.8,202.17 190.36,200.61 190.36,194.46 190.57,194.25 191.51,194.25 191.91,193.85 v1(191.91,193.35)
SL18_VI100_16_A_HF: length 0.4
  TOP w0.305: SITE6.28_F v2(189.8,210.39)
SL18_VI100_16_A_HS: length 4.1
  BOTTOM w0.152: v2(189.8,209.59) 189.8,209.74 190.14,210.08 190.14,210.86 190.25,210.97
  BOTTOM w0.203: v1(192.25,212.18) 191.28,211.2 190.49,211.2 190.25,210.97
SL18_VI100_16_B_HS: length 7.8
  BOTTOM w0.203: v2(187.8,205.39) 187.8,201.39 189.12,200.08 v1(189.12,198.18)
SL18_VI100_18_A_HF: length 11.5
  TOP w0.305: SITE8.2_F 266.18,208.74
  TOP w0.635: v1(260.83,208.59) 260.98,208.74 266.18,208.74
  BOTTOM w0.635: v1(260.83,208.59) 259.83,207.59 256.82,207.59 UNK8C49.2
SL18_VI100_18_A_HS: length 7.8
  BOTTOM w0.203: v1(260.83,205.79) 261.97,205.79 264.92,208.74 v2(267.45,208.74)
SL18_VI100_18_B_HF: length 9.3
  TOP w0.305: SITE8.29_F 269.3,210.29 269.31,210.3 269.31,210.56 269.29,210.58 269.29,211 269.31,211.02 269.31,211.21 269.94,211.84
  TOP w0.635: v1(272.25,218.02) 271.49,217.25 271.49,213.39 269.94,211.84
SL18_VI100_18_B_HS: length 14.3
  BOTTOM w0.203: v1(272.25,222.59) 271.38,221.72 271.38,213.02 269.21,210.84 269.21,209.68 v2(269.3,209.59)
SL18_VI100_19_A_HF: length 16.3
  TOP w0.305: SITE8.5_F 265.45,207.24
  TOP w0.635: v1(260.83,201.22) 263.13,203.52 263.13,204.92 265.45,207.24
  BOTTOM w0.635: v1(255.11,201.22) 255.11,200.93 255.75,200.3 260.19,200.3 260.83,200.93 v1(260.83,201.22)
SL18_VI100_19_A_HS: length 13.4
  BOTTOM w0.203: v1(256.26,203.76) 257.13,202.89 262.62,202.89 266.97,207.24 v2(267.45,207.24)
SL18_VI100_19_B_HS: length 13
  BOTTOM w0.203: v2(268.3,205.39) 268.3,201.78 269.86,200.22 269.86,194.09 v1(269.12,193.35)
SL18_VI100_20_A_HS: length 8.3
  BOTTOM w0.203: v1(260.83,203.76) 261.84,203.76 265.82,207.74 v2(267.45,207.74)
SL18_VI100_20_B_HS: length 13.8
  BOTTOM w0.203: v1(283.84,201.77) 282.19,203.42 273.97,203.42 v2(271.65,205.74)
SL18_VI100_21_A_HF: length 23.1
  TOP w0.305: SITE8.6_F 266.47,206.74 266.18,206.45
  TOP w0.635: 266.18,206.45 264.16,204.43 v1(264.16,198.18)
  BOTTOM w0.508: 264.38,193.35 UNK8K12.4
  BOTTOM w0.635: v1(264.16,198.18) 264.54,198.18 265.17,197.54 265.17,193.35 ; 265.17,193.35 265.17,188.1 264.45,187.38 264.21,187.38 ; 265.17,193.35 264.38,193.35
SL18_VI100_21_A_HS:
  vias: v2(267.45,206.74)
SL18_VI100_22_A_HF:
  vias: v2(267.05,206.24)
SL18_VI100_22_A_HS:
  vias: v1(266.96,193.35) v2(267.45,206.24)
SL18_VI100_22_B_HF: length 1.7
  TOP w0.305: SITE8.30_F v2(268.8,211.66)
SL18_VI100_22_B_HS: length 4.5
  BOTTOM w0.203: UNK8K46.4 269.84,212.05 268.8,211.01 v2(268.8,209.59)
SL18_VI100_23_A_HF:
  vias: v2(269.8,204.99)
SL18_VI100_23_A_HS:
  vias: v1(274.07,193.35) v2(269.8,205.39)
SL18_VI100_23_B_HF: length 10.4
  TOP w0.305: SITE8.31_F 268.3,210.29 268.29,210.3 268.29,210.82 268.07,211.04
  TOP w0.635: v1(269.84,219.54) 269.08,218.78 269.08,213.58 268.07,212.57 268.07,211.04
SL18_VI100_23_B_HS: length 15.2
  BOTTOM w0.203: v2(268.3,209.59) 268.3,211.84 269.05,212.6 269.05,223.33 v1(269.84,224.11)
SL18_VI100_24_B_HF: length 5.7
  TOP w0.305: SITE8.20_F 274.73,207.24 275.04,206.93
  TOP w0.635: v1(276.03,205.94) 275.04,206.93
  BOTTOM w0.635: v1(276.03,205.94) UNK8C61.2
SL18_VI100_24_B_HS: length 17.5
  BOTTOM w0.203: v2(271.65,207.24) 274.53,207.24 274.7,207.06 286.93,207.06 v1(288.42,205.58)
SL18_VI100_25_B_HF: length 7.6
  TOP w0.305: 274.28,207.99 274.03,207.74 SITE8.21_F
  TOP w0.635: 274.28,207.99 278.64,207.99 v1(279.27,208.62)
SL18_VI100_25_B_HS: length 13.3
  BOTTOM w0.203: v2(271.65,207.74) 274.58,207.74 276.34,209.49 282.97,209.49 v1(283.84,208.62)
SL18_VI100_26_A_HF: length 9.6
  TOP w0.305: SITE8.16_F 271.55,204.74 271.98,204.74
  TOP w0.635: 271.98,204.74 276.72,200.01 276.72,198.83 v1(277.37,198.18)
SL18_VI100_26_A_HS: length 15.2
  BOTTOM w0.203: v1(277.37,193.35) 277.37,194.05 277.17,194.25 276.08,194.25 275.83,194.51 275.83,200.6 271.3,205.13 v2(271.3,205.39)
SL18_VI100_26_B_HF: length 0.4
  TOP w0.305: SITE8.25_F v2(271.3,210.39)
SL18_VI100_26_B_HS: length 5.7
  BOTTOM w0.203: v2(271.3,209.59) 271.36,209.65 273.95,209.65 275.17,210.87 v1(275.17,212.18)
SL18_VI100_27_A_HF: length 7.2
  TOP w0.305: SITE8.18_F 273.05,206.24 273.62,205.67
  TOP w0.635: v1(277.73,202.67) 276.62,202.67 273.62,205.67
SL18_VI100_27_A_HS: length 18.6
  BOTTOM w0.203: v1(288.42,201.77) 286.28,203.91 274.3,203.91 271.97,206.24 v2(271.65,206.24)
SL18_VI100_27_B_HF: length 0.4
  TOP w0.305: SITE8.26_F v2(270.8,210.39)
SL18_VI100_27_B_HS: length 10.5
  BOTTOM w0.203: v2(270.8,209.59) 270.8,209.67 271.16,210.03 271.57,210.03 271.7,210.16 273.88,210.16 274.43,210.7 274.43,216 v1(275.17,216.75)
SL18_VI100_28_A_HF: length 8.2
  TOP w0.305: 274.3,206.19 274.13,206.19 273.59,206.74 SITE8.19_F
  TOP w0.635: 274.3,206.19 275.57,204.92 278.62,204.92 v1(279.27,205.58)
SL18_VI100_28_A_HS: length 12.7
  BOTTOM w0.203: v1(283.84,205.58) 282.84,206.58 274.43,206.58 274.27,206.74 v2(271.65,206.74)
SL18_VI100_28_B_HF: length 1.1
  TOP w0.305: v2(269.8,210.79) 270,210.79 270.3,210.49 SITE8.27_F
SL18_VI100_28_B_HS: length 15.4
  BOTTOM w0.152: 270.71,210.8 270.44,210.53 270.44,209.73 v2(270.3,209.59)
  BOTTOM w0.203: v1(275.17,221.32) 274.05,220.2 274.05,216.2 274.03,216.17 274.03,211.32 273.5,210.8 270.71,210.8
SL18_VI100_29_A_HF: length 8.4
  TOP w0.305: SITE8.22_F 272.44,208.24 272.44,208.25 273.26,208.25 273.66,208.65
  TOP w0.635: 273.66,208.65 273.99,208.98 277.62,208.98 v1(277.73,208.86)
  BOTTOM w0.635: UNK8C64.2 276.03,208.22 276.67,208.86 v1(277.73,208.86)
SL18_VI100_29_A_HS: length 18.1
  BOTTOM w0.203: v2(271.65,208.24) 274.45,208.24 276.21,210 287.04,210 v1(288.42,208.62)
SL18_VI100_29_B_HF: length 0.4
  TOP w0.305: SITE8.32_F v2(267.8,210.39)
  vias: v1(267.43,224.11)
SL18_VI100_29_B_HS: length 9.9
  BOTTOM w0.203: v2(267.8,209.59) 267.8,209.86 267.33,210.33 267.33,211.45 268.59,212.71 268.59,215.84 267.43,217.01 v1(267.43,218.27)
SL18_VI100_30_A_HF: length 8.4
  TOP w0.305: 272.97,209.19 272.52,208.74 SITE8.23_F
  TOP w0.635: v1(279.27,211.67) 277.57,209.97 273.75,209.97 272.97,209.19
SL18_VI100_30_A_HS: length 14.9
  BOTTOM w0.203: v1(283.84,211.67) 282.85,212.67 277.43,212.67 277.12,212.36 277.12,211.23 276.59,210.7 276.27,210.7 274.31,208.74 v2(271.65,208.74)
SL18_VI100_30_B_HS: length 9.2
  BOTTOM w0.203: v1(274.07,198.18) 274.07,199.95 269.3,204.72 v2(269.3,205.39)
SL18_VI100_31_A_HF: length 10
  TOP w0.305: SITE8.24_F 272.05,209.58 272.28,209.81
  TOP w0.635: 272.28,209.81 273.39,210.92 275.98,210.92 276.98,211.92 276.98,212.77 277.62,213.41 278.47,213.41 v1(279.27,214.21)
SL18_VI100_31_A_HS: length 17.3
  BOTTOM w0.203: v1(283.84,214.21) 282.72,215.34 276.97,215.34 276.72,215.08 276.72,211.4 276.46,211.15 276.08,211.15 274.18,209.24 v2(271.65,209.24)
SL18_VI100_31_B_HS: length 13.9
  BOTTOM w0.203: v1(271.91,193.35) 271.91,193.85 271.51,194.25 270.57,194.25 270.36,194.46 270.36,200.61 268.8,202.17 v2(268.8,205.39)
SL18_VI100_32_A_HF: length 0.4
  TOP w0.305: SITE8.28_F v2(269.8,210.39)
SL18_VI100_32_A_HS: length 4.1
  BOTTOM w0.152: 270.25,210.97 270.14,210.86 270.14,210.08 269.8,209.74 v2(269.8,209.59)
  BOTTOM w0.203: v1(272.25,212.18) 271.28,211.2 270.49,211.2 270.25,210.97
SL18_VI100_32_B_HS: length 7.8
  BOTTOM w0.203: v1(269.12,198.18) 269.12,200.08 267.8,201.39 v2(267.8,205.39)
N17260776: length 2.2
  BOTTOM w0.635: C48.1 K2.3
N17261204: length 6.9
  BOTTOM w0.635: K3.3 136.91,274.45 136.27,273.81 C49.1
N17261720: length 1.5
  BOTTOM w0.508: C50.1 K5.3
N17263068: length 1.5
  BOTTOM w0.203: RK7.1 137.77,263.76 K7.1
N17264482: length 1.5
  BOTTOM w0.203: C53.1 142.14,262.02 K8.3
N17264547: length 1.5
  BOTTOM w0.203: C54.1 136.42,262.02 K9.3
N17266096: length 6.9
  BOTTOM w0.508: 142.67,253.35 K12.3
  BOTTOM w0.635: C59.1 140.59,249.17 142.22,250.8 142.22,252.9 142.67,253.35
N17266582: length 1.5
  BOTTOM w0.203: R1.1 143.36,248.69 K13.3
N17267238: length 25.6
  BOTTOM w0.203: K15.6 138.34,246.04 138.34,248.58 141.35,251.59 141.35,258.83 143.32,260.79 143.32,261.61 v2(147.45,265.74)
N17270245: length 1.5
  BOTTOM w0.203: C69.1 K19.3
N17493363: length 1.5
  BOTTOM w0.203: RK5.1 137.77,268.59 K5.1
N17493593: length 1.5
  BOTTOM w0.203: RK6.1 137.77,265.79 K6.1
N17493900: length 1.5
  BOTTOM w0.203: K8.1 137.77,261.22 RK8.1
N17494047: length 1.5
  BOTTOM w0.203: K9.1 132.05,261.22 RK9.1
N17494316: length 1.5
  BOTTOM w0.203: K10.1 133.2,263.76 RK10.1
N17494507: length 1.5
  BOTTOM w0.203: RK11.1 144.16,255.12 K11.1
N17494587: length 1.3
  BOTTOM w0.508: C58.1 K11.3
N17494912: length 1.5
  BOTTOM w0.203: RK12.1 144.16,250.29 K12.1
N17495143: length 1.5
  BOTTOM w0.203: K13.1 144.16,244.32 RK13.1
N17495451: length 1.5
  BOTTOM w0.203: RK14.1 146.96,250.29 K14.1
N17495920: length 1.5
  BOTTOM w0.203: RK19.1 151.91,255.12 K19.1
N17496065: length 1.5
  BOTTOM w0.203: RK20.1 151.91,250.29 K20.1
N17496168: length 1.5
  BOTTOM w0.203: K21.1 154.07,255.12 RK21.1
N17508143: length 3.4
  BOTTOM w0.203: RK2.1 142.47,283.73 142.88,283.32 K2.1
N17508406: length 1.9
  BOTTOM w0.203: K3.1 RK3.1
N17508530: length 2.4
  BOTTOM w0.203: K4.1 142.88,296.1 142.04,296.93 RK4.1
N17654577: length 1.3
  BOTTOM w0.203: K51.4 148.32,244.45 R7.2
N17654648: length 1.3
  BOTTOM w0.203: K53.4 156.57,244.45 R8.2
N17654652: length 1.5
  BOTTOM w0.203: RK53.1 156.57,248.69 K53.1
N17654805: length 2.3
  BOTTOM w0.203: R19.1 R11.2 v1(126.61,294.24)
N17654898: length 2.3
  BOTTOM w0.203: v1(133.22,294.24) R14.2 R20.1
N17655019: length 1.5
  BOTTOM w0.203: RK59.1 121.26,291.95 K55.1
N17655025: length 1.3
  BOTTOM w0.508: R19.2 K55.4
N17655029: length 3
  BOTTOM w0.305: RK60.1 123.92,287.4
N17655138: length 3.4
  BOTTOM w0.203: TP_IN-_3.1 158.52,232.74 158.31,232.54 R16.1 157.41,231.32 U3.8
N17655140: length 3.4
  BOTTOM w0.203: U3.7 156.81,231.32 R16.2 155.89,232.54 155.68,232.74 TP_IN+_3.1
N17655324: length 3.4
  BOTTOM w0.203: U4.7 151.73,231.32 R18.2 150.81,232.54 150.6,232.74 TP_IN+_4.1
N17655339: length 3.4
  BOTTOM w0.203: U4.8 152.33,231.32 R18.1 153.23,232.54 153.44,232.74 TP_IN-_4.1
N17655440: length 7.5
  BOTTOM w0.508: 132.87,287.4 131.43,287.4 130.92,287.91 K61.4 R20.2
N17655462: length 1.5
  BOTTOM w0.203: K54.1 157.37,238.99 RK54.1
N17655480: length 1.5
  BOTTOM w0.203: RK51.1 148.32,248.69 K51.1
N17655494: length 1.5
  BOTTOM w0.203: RK52.1 149.12,238.99 K52.1
N17702527: length 27.9
  TOP w0.305: SITE1.8_F 146.71,265.4
  TOP w0.635: K15.3 135.29,246.19 135.29,247.82 135.89,248.41 137.92,248.41 145.16,255.65 145.16,263.85 146.71,265.4
N18407736: length 1.5
  BOTTOM w0.203: C60.1 K16.3
N18407764: length 1.5
  BOTTOM w0.203: K17.1 149.12,255.12 RK17.1
N18407893: length 1.5
  BOTTOM w0.203: K16.1 146.96,255.12 RK16.1
N18407930: length 1.5
  BOTTOM w0.203: K18.1 149.12,250.29 RK18.1
N18409262: length 1.5
  BOTTOM w0.203: K22.1 154.07,250.29 RK22.1
N18420672: length 24.1
  BOTTOM w0.203: v2(150.3,265.39) 150.3,264.48 154.81,259.97 154.81,249.07 153.24,247.49 153.24,245.44 154.38,244.3
N18420953: length 28.6
  BOTTOM w0.203: 162.64,244.3 161.15,245.78 161.15,248.53 160.21,249.48 155.8,249.48 155.32,249.96 155.32,260.22 150.8,264.74 v2(150.8,265.39)
N18432405: length 1.5
  BOTTOM w0.203: C62.1 K25.3
N18432504: length 1.5
  BOTTOM w0.203: RK25.1 157.37,255.12 K25.1
N18432522: length 1.5
  BOTTOM w0.203: K26.1 157.37,250.29 RK26.1
N18432973: length 1.5
  BOTTOM w0.203: C63.1 K27.3
N18433005: length 1.5
  BOTTOM w0.203: RK28.1 166.9,261.77 K28.1
N18433172: length 1.5
  BOTTOM w0.203: K27.1 162.33,261.77 RK27.1
N18433200: length 1.1
  BOTTOM w0.203: RK29.1 K29.1
N18433570: length 1.5
  BOTTOM w0.203: C61.1 K30.3
N18433598: length 1.5
  BOTTOM w0.203: RK31.1 166.9,265.58 K31.1
N18433748: length 1.5
  BOTTOM w0.203: K30.1 162.33,265.58 RK30.1
N18433778: length 1.1
  BOTTOM w0.203: RK32.1 K32.1
N18434722: length 1.5
  BOTTOM w0.203: RK39.1 166.9,274.21 K39.1
N18434762: length 1.5
  BOTTOM w0.203: RK38.1 162.33,274.21 K38.1
N18434888: length 1.5
  BOTTOM w0.203: C74.1 K38.3
N18465960: length 1.5
  BOTTOM w0.203: RK35.1 171.48,268.62 K35.1
N18465976: length 1.5
  BOTTOM w0.203: RK34.1 166.9,268.62 K34.1
N18465984: length 1.5
  BOTTOM w0.203: RK33.1 162.33,268.62 K33.1
N18466028: length 1.5
  BOTTOM w0.203: C64.1 K33.3
N18511830: length 1.5
  BOTTOM w0.203: K37.1 166.9,271.67 RK37.1
N18511832: length 1.5
  BOTTOM w0.203: RK36.1 162.33,271.67 K36.1
N18511862: length 1.5
  BOTTOM w0.203: C65.1 K36.3
N18556624: length 1.5
  BOTTOM w0.203: RK40.1 155.17,275.24 K40.1
N18556932: length 1.5
  BOTTOM w0.203: RK41.1 155.17,279.81 K41.1
N18557107: length 1.5
  BOTTOM w0.203: K42.1 155.17,284.38 RK42.1
N18557324: length 1.5
  BOTTOM w0.203: RK43.1 152.25,275.24 K43.1
N18568668: length 1.5
  BOTTOM w0.203: K45.1 152.25,285.65 RK45.1
N18568680: length 1.5
  BOTTOM w0.203: K44.1 152.25,281.08 RK44.1
N18568712: length 1.5
  BOTTOM w0.203: C66.1 153.05,276.71 K44.3
N18580009: length 1.5
  BOTTOM w0.203: K46.1 149.84,276.76 RK46.1
N18580265: length 1.5
  BOTTOM w0.203: K47.3 150.64,278.23 C67.1
N18580347: length 1.5
  BOTTOM w0.203: K48.1 149.84,287.17 RK48.1
N18580359: length 1.5
  BOTTOM w0.203: K47.1 149.84,282.6 RK47.1
N18580906: length 1.5
  BOTTOM w0.203: K49.3 148.23,282.8 C68.1
N18580988: length 1.5
  BOTTOM w0.203: K50.1 147.43,281.33 RK50.1
N18581000: length 1.5
  BOTTOM w0.203: K49.1 147.43,287.17 RK49.1
N18705535: length 1.5
  BOTTOM w0.203: K57.1 157.71,236.75 157.61,236.86
N18705626: length 1.5
  BOTTOM w0.203: 155.58,236.86 155.68,236.75 K58.1
N18705736: length 1.5
  BOTTOM w0.203: 152.53,236.86 152.63,236.75 K59.1
N18705861: length 1.5
  BOTTOM w0.203: K60.1 150.6,236.75 150.5,236.86
N18706153: length 1.5
  BOTTOM w0.203: K61.1 127.86,291.95 RK61.1
N18706312: length 2.2
  BOTTOM w0.635: UNK2C48.1 UNK2K2.3
N18706321: length 6.9
  BOTTOM w0.635: UNK2K3.3 176.91,274.45 176.27,273.81 UNK2C49.1
N18706330: length 1.5
  BOTTOM w0.508: UNK2C50.1 UNK2K5.3
N18706363: length 1.5
  BOTTOM w0.203: UNK2RK7.1 177.77,263.76 UNK2K7.1
N18706370: length 1.5
  BOTTOM w0.203: UNK2C53.1 182.14,262.02 UNK2K8.3
N18706379: length 1.5
  BOTTOM w0.203: UNK2K9.3 176.42,262.02 UNK2C54.1
N18706409: length 6.9
  BOTTOM w0.508: 182.67,253.35 UNK2K12.3
  BOTTOM w0.635: 182.67,253.35 182.22,252.9 182.22,250.8 180.59,249.17 UNK2C59.1
N18706416: length 1.5
  BOTTOM w0.203: UNK2R1.1 183.36,248.69 UNK2K13.3
N18706434: length 25.6
  BOTTOM w0.203: UNK2K15.6 178.34,246.04 178.34,248.58 181.35,251.59 181.35,258.83 183.32,260.79 183.32,261.61 v2(187.45,265.74)
N18706452: length 1.5
  BOTTOM w0.203: UNK2RK5.1 177.77,268.59 UNK2K5.1
N18706454: length 1.5
  BOTTOM w0.203: UNK2RK6.1 177.77,265.79 UNK2K6.1
N18706456: length 1.5
  BOTTOM w0.203: UNK2K8.1 177.77,261.22 UNK2RK8.1
N18706457: length 1.5
  BOTTOM w0.203: UNK2RK9.1 172.05,261.22 UNK2K9.1
N18706458: length 1.5
  BOTTOM w0.203: UNK2RK10.1 173.2,263.76 UNK2K10.1
N18706459: length 1.5
  BOTTOM w0.203: UNK2RK11.1 184.16,255.12 UNK2K11.1
N18706462: length 1.3
  BOTTOM w0.508: UNK2C58.1 UNK2K11.3
N18706465: length 1.5
  BOTTOM w0.203: UNK2K12.1 184.16,250.29 UNK2RK12.1
N18706467: length 1.5
  BOTTOM w0.203: UNK2K13.1 184.16,244.32 UNK2RK13.1
N18706470: length 1.5
  BOTTOM w0.203: UNK2RK14.1 186.96,250.29 UNK2K14.1
N18706472: length 3.4
  BOTTOM w0.203: UNK2K2.1 182.87,283.32 182.47,283.73 UNK2RK2.1
N18706473: length 1.9
  BOTTOM w0.203: UNK2K3.1 UNK2RK3.1
N18706474: length 2.4
  BOTTOM w0.203: UNK2K4.1 182.87,296.1 182.04,296.93 UNK2RK4.1
N18706494: length 27.9
  TOP w0.305: SITE2.8_F 186.71,265.4
  TOP w0.635: UNK2K15.3 175.29,246.19 175.29,247.82 175.89,248.41 177.92,248.41 185.16,255.65 185.16,263.85 186.71,265.4
N18706506: length 1.5
  BOTTOM w0.203: UNK2C60.1 UNK2K16.3
N18706519: length 1.5
  BOTTOM w0.203: UNK2RK17.1 189.12,255.12 UNK2K17.1
N18706533: length 1.5
  BOTTOM w0.203: UNK2K16.1 186.96,255.12 UNK2RK16.1
N18706537: length 1.5
  BOTTOM w0.203: UNK2RK18.1 189.12,250.29 UNK2K18.1
N18707687: length 1.5
  BOTTOM w0.203: UNK2C69.1 UNK2K19.3
N18707714: length 1.5
  BOTTOM w0.203: UNK2K19.1 191.91,255.12 UNK2RK19.1
N18707716: length 1.5
  BOTTOM w0.203: UNK2RK20.1 191.91,250.29 UNK2K20.1
N18707717: length 1.5
  BOTTOM w0.203: UNK2K21.1 194.07,255.12 UNK2RK21.1
N18707742: length 1.5
  BOTTOM w0.203: UNK2K22.1 194.07,250.29 UNK2RK22.1
N18707748: length 24.1
  BOTTOM w0.203: v2(190.3,265.39) 190.3,264.48 194.81,259.97 194.81,249.07 193.24,247.49 193.24,245.44 194.38,244.3
N18707762: length 28.6
  BOTTOM w0.203: v2(190.8,265.39) 190.8,264.74 195.32,260.22 195.32,249.96 195.8,249.48 200.21,249.48 201.15,248.53 201.15,245.78 202.64,244.3
N18707772: length 1.5
  BOTTOM w0.203: UNK2C62.1 UNK2K25.3
N18707790: length 1.5
  BOTTOM w0.203: UNK2K25.1 197.37,255.12 UNK2RK25.1
N18707794: length 1.5
  BOTTOM w0.203: UNK2K26.1 197.37,250.29 UNK2RK26.1
N18707799: length 1.5
  BOTTOM w0.203: UNK2C63.1 UNK2K27.3
N18707815: length 1.5
  BOTTOM w0.203: UNK2K28.1 206.9,261.77 UNK2RK28.1
N18707836: length 1.5
  BOTTOM w0.203: UNK2K27.1 202.33,261.77 UNK2RK27.1
N18707838: length 1.1
  BOTTOM w0.203: UNK2RK29.1 UNK2K29.1
N18707843: length 1.5
  BOTTOM w0.203: UNK2C61.1 UNK2K30.3
N18707857: length 1.5
  BOTTOM w0.203: UNK2RK31.1 206.9,265.58 UNK2K31.1
N18707877: length 1.5
  BOTTOM w0.203: UNK2RK30.1 202.33,265.58 UNK2K30.1
N18707880: length 1.1
  BOTTOM w0.203: UNK2RK32.1 UNK2K32.1
N18707882: length 1.5
  BOTTOM w0.203: UNK2RK35.1 211.48,268.62 UNK2K35.1
N18707884: length 1.5
  BOTTOM w0.203: UNK2RK34.1 206.9,268.62 UNK2K34.1
N18707886: length 1.5
  BOTTOM w0.203: UNK2RK33.1 202.33,268.62 UNK2K33.1
N18707889: length 1.5
  BOTTOM w0.203: UNK2C64.1 UNK2K33.3
N18707924: length 1.5
  BOTTOM w0.203: UNK2RK37.1 206.9,271.67 UNK2K37.1
N18707925: length 1.5
  BOTTOM w0.203: UNK2RK36.1 202.33,271.67 UNK2K36.1
N18707931: length 1.5
  BOTTOM w0.203: UNK2C65.1 UNK2K36.3
N18709217: length 1.5
  BOTTOM w0.203: UNK2K39.1 206.9,274.21 UNK2RK39.1
N18709218: length 1.5
  BOTTOM w0.203: UNK2K38.1 202.33,274.21 UNK2RK38.1
N18709224: length 1.5
  BOTTOM w0.203: UNK2C74.1 UNK2K38.3
N18709243: length 1.5
  BOTTOM w0.203: UNK2RK40.1 195.17,275.24 UNK2K40.1
N18709256: length 1.5
  BOTTOM w0.203: UNK2RK41.1 195.17,279.81 UNK2K41.1
N18709269: length 1.5
  BOTTOM w0.203: UNK2K42.1 195.17,284.38 UNK2RK42.1
N18709281: length 1.5
  BOTTOM w0.203: UNK2RK43.1 192.25,275.24 UNK2K43.1
N18709294: length 1.5
  BOTTOM w0.203: UNK2RK45.1 192.25,285.65 UNK2K45.1
N18709295: length 1.5
  BOTTOM w0.203: UNK2K44.1 192.25,281.08 UNK2RK44.1
N18709305: length 1.5
  BOTTOM w0.203: UNK2C66.1 193.05,276.71 UNK2K44.3
N18709323: length 1.5
  BOTTOM w0.203: UNK2K46.1 189.84,276.76 UNK2RK46.1
N18709339: length 1.5
  BOTTOM w0.203: UNK2C67.1 190.64,278.23 UNK2K47.3
N18709352: length 1.5
  BOTTOM w0.203: UNK2RK48.1 189.84,287.17 UNK2K48.1
N18709353: length 1.5
  BOTTOM w0.203: UNK2RK47.1 189.84,282.6 UNK2K47.1
N18709363: length 1.5
  BOTTOM w0.203: UNK2K49.3 188.23,282.8 UNK2C68.1
N18709376: length 1.5
  BOTTOM w0.203: UNK2K50.1 187.43,281.33 UNK2RK50.1
N18709377: length 1.5
  BOTTOM w0.203: UNK2RK49.1 187.43,287.17 UNK2K49.1
N18710191: length 1.3
  BOTTOM w0.203: UNK2R7.2 188.32,244.45 UNK2K51.4
N18710203: length 1.3
  BOTTOM w0.203: UNK2R8.2 196.57,244.45 UNK2K53.4
N18710205: length 1.5
  BOTTOM w0.203: UNK2RK53.1 196.57,248.69 UNK2K53.1
N18710227: length 2.3
  BOTTOM w0.203: UNK2R19.1 UNK2R11.2 v1(166.61,294.24)
N18710239: length 2.3
  BOTTOM w0.203: v1(173.22,294.24) UNK2R14.2 UNK2R20.1
N18710249: length 1.5
  BOTTOM w0.203: UNK2K55.1 161.26,291.95 UNK2RK59.1
N18710252: length 1.3
  BOTTOM w0.508: UNK2R19.2 UNK2K55.4
N18710254: length 3
  BOTTOM w0.305: UNK2RK60.1 163.92,287.4
N18710271: length 3.4
  BOTTOM w0.203: UNK2TP_IN-_3.1 198.51,232.74 198.31,232.54 UNK2R16.1 197.41,231.32 UNK2U3.8
N18710272: length 3.4
  BOTTOM w0.203: UNK2TP_IN+_3.1 195.68,232.74 195.89,232.54 UNK2R16.2 196.81,231.32 UNK2U3.7
N18710300: length 3.4
  BOTTOM w0.203: UNK2TP_IN+_4.1 190.6,232.74 190.81,232.54 UNK2R18.2 191.73,231.32 UNK2U4.7
N18710304: length 3.4
  BOTTOM w0.203: UNK2U4.8 192.33,231.32 UNK2R18.1 193.23,232.54 193.43,232.74 UNK2TP_IN-_4.1
N18710315: length 7.5
  BOTTOM w0.508: UNK2R20.2 UNK2K61.4 170.92,287.91 171.43,287.4 172.87,287.4
N18710316: length 1.5
  BOTTOM w0.203: UNK2K54.1 197.37,238.99 UNK2RK54.1
N18710320: length 1.5
  BOTTOM w0.203: UNK2K51.1 188.32,248.69 UNK2RK51.1
N18710322: length 1.5
  BOTTOM w0.203: UNK2K52.1 189.12,238.99 UNK2RK52.1
N18710386: length 1.5
  BOTTOM w0.203: 197.61,236.86 197.71,236.75 UNK2K57.1
N18710387: length 1.5
  BOTTOM w0.203: 195.58,236.86 195.68,236.75 UNK2K58.1
N18710388: length 1.5
  BOTTOM w0.203: UNK2K59.1 192.63,236.75 192.53,236.86
N18710389: length 1.5
  BOTTOM w0.203: 190.5,236.86 190.6,236.75 UNK2K60.1
N18710392: length 1.5
  BOTTOM w0.203: UNK2RK61.1 167.86,291.95 UNK2K61.1
N18711523: length 2.2
  BOTTOM w0.635: UNK3C48.1 UNK3K2.3
N18711532: length 6.9
  BOTTOM w0.635: UNK3K3.3 216.91,274.45 216.27,273.81 UNK3C49.1
N18711541: length 1.5
  BOTTOM w0.508: UNK3C50.1 UNK3K5.3
N18711574: length 1.5
  BOTTOM w0.203: UNK3RK7.1 217.77,263.76 UNK3K7.1
N18711581: length 1.5
  BOTTOM w0.203: UNK3C53.1 222.14,262.02 UNK3K8.3
N18711590: length 1.5
  BOTTOM w0.203: UNK3K9.3 216.42,262.02 UNK3C54.1
N18711620: length 6.9
  BOTTOM w0.508: 222.67,253.35 UNK3K12.3
  BOTTOM w0.635: 222.67,253.35 222.22,252.9 222.22,250.8 220.59,249.17 UNK3C59.1
N18711627: length 1.5
  BOTTOM w0.203: UNK3K13.3 223.36,248.69 UNK3R1.1
N18711645: length 25.6
  BOTTOM w0.203: UNK3K15.6 218.34,246.04 218.34,248.58 221.35,251.59 221.35,258.83 223.32,260.79 223.32,261.61 v2(227.45,265.74)
N18711663: length 1.5
  BOTTOM w0.203: UNK3RK5.1 217.77,268.59 UNK3K5.1
N18711665: length 1.5
  BOTTOM w0.203: UNK3RK6.1 217.77,265.79 UNK3K6.1
N18711667: length 1.5
  BOTTOM w0.203: UNK3RK8.1 217.77,261.22 UNK3K8.1
N18711668: length 1.5
  BOTTOM w0.203: UNK3RK9.1 212.05,261.22 UNK3K9.1
N18711669: length 1.5
  BOTTOM w0.203: UNK3K10.1 213.2,263.76 UNK3RK10.1
N18711670: length 1.5
  BOTTOM w0.203: UNK3RK11.1 224.16,255.12 UNK3K11.1
N18711673: length 1.3
  BOTTOM w0.508: UNK3C58.1 UNK3K11.3
N18711676: length 1.5
  BOTTOM w0.203: UNK3RK12.1 224.16,250.29 UNK3K12.1
N18711678: length 1.5
  BOTTOM w0.203: UNK3K13.1 224.16,244.32 UNK3RK13.1
N18711681: length 1.5
  BOTTOM w0.203: UNK3RK14.1 226.96,250.29 UNK3K14.1
N18711683: length 3.4
  BOTTOM w0.203: UNK3RK2.1 222.47,283.73 222.87,283.32 UNK3K2.1
N18711684: length 1.9
  BOTTOM w0.203: UNK3K3.1 UNK3RK3.1
N18711685: length 2.4
  BOTTOM w0.203: UNK3RK4.1 222.04,296.93 222.87,296.1 UNK3K4.1
N18711705: length 27.9
  TOP w0.305: SITE3.8_F 226.71,265.4
  TOP w0.635: UNK3K15.3 215.29,246.19 215.29,247.82 215.89,248.41 217.92,248.41 225.16,255.65 225.16,263.85 226.71,265.4
N18711717: length 1.5
  BOTTOM w0.203: UNK3C60.1 UNK3K16.3
N18711730: length 1.5
  BOTTOM w0.203: UNK3K17.1 229.12,255.12 UNK3RK17.1
N18711744: length 1.5
  BOTTOM w0.203: UNK3RK16.1 226.96,255.12 UNK3K16.1
N18711748: length 1.5
  BOTTOM w0.203: UNK3RK18.1 229.12,250.29 UNK3K18.1
N18712898: length 1.5
  BOTTOM w0.203: UNK3C69.1 UNK3K19.3
N18712925: length 1.5
  BOTTOM w0.203: UNK3K19.1 231.91,255.12 UNK3RK19.1
N18712927: length 1.5
  BOTTOM w0.203: UNK3K20.1 231.91,250.29 UNK3RK20.1
N18712928: length 1.5
  BOTTOM w0.203: UNK3RK21.1 234.07,255.12 UNK3K21.1
N18712953: length 1.5
  BOTTOM w0.203: UNK3RK22.1 234.07,250.29 UNK3K22.1
N18712959: length 24.1
  BOTTOM w0.203: 234.38,244.3 233.24,245.44 233.24,247.49 234.81,249.07 234.81,259.97 230.3,264.48 v2(230.3,265.39)
N18712973: length 28.6
  BOTTOM w0.203: 242.64,244.3 241.15,245.78 241.15,248.53 240.21,249.48 235.8,249.48 235.32,249.96 235.32,260.22 230.8,264.74 v2(230.8,265.39)
N18712983: length 1.5
  BOTTOM w0.203: UNK3C62.1 UNK3K25.3
N18713001: length 1.5
  BOTTOM w0.203: UNK3K25.1 237.37,255.12 UNK3RK25.1
N18713005: length 1.5
  BOTTOM w0.203: UNK3RK26.1 237.37,250.29 UNK3K26.1
N18713010: length 1.5
  BOTTOM w0.203: UNK3C63.1 UNK3K27.3
N18713026: length 1.5
  BOTTOM w0.203: UNK3RK28.1 246.9,261.77 UNK3K28.1
N18713047: length 1.5
  BOTTOM w0.203: UNK3RK27.1 242.33,261.77 UNK3K27.1
N18713049: length 1.1
  BOTTOM w0.203: UNK3RK29.1 UNK3K29.1
N18713054: length 1.5
  BOTTOM w0.203: UNK3C61.1 UNK3K30.3
N18713068: length 1.5
  BOTTOM w0.203: UNK3K31.1 246.9,265.58 UNK3RK31.1
N18713088: length 1.5
  BOTTOM w0.203: UNK3RK30.1 242.33,265.58 UNK3K30.1
N18713091: length 1.1
  BOTTOM w0.203: UNK3RK32.1 UNK3K32.1
N18713093: length 1.5
  BOTTOM w0.203: UNK3RK35.1 251.48,268.62 UNK3K35.1
N18713095: length 1.5
  BOTTOM w0.203: UNK3K34.1 246.9,268.62 UNK3RK34.1
N18713097: length 1.5
  BOTTOM w0.203: UNK3RK33.1 242.33,268.62 UNK3K33.1
N18713100: length 1.5
  BOTTOM w0.203: UNK3C64.1 UNK3K33.3
N18713135: length 1.5
  BOTTOM w0.203: UNK3RK37.1 246.9,271.67 UNK3K37.1
N18713136: length 1.5
  BOTTOM w0.203: UNK3RK36.1 242.33,271.67 UNK3K36.1
N18713142: length 1.5
  BOTTOM w0.203: UNK3C65.1 UNK3K36.3
N18714428: length 1.5
  BOTTOM w0.203: UNK3K39.1 246.9,274.21 UNK3RK39.1
N18714429: length 1.5
  BOTTOM w0.203: UNK3K38.1 242.33,274.21 UNK3RK38.1
N18714435: length 1.5
  BOTTOM w0.203: UNK3C74.1 UNK3K38.3
N18714454: length 1.5
  BOTTOM w0.203: UNK3RK40.1 235.17,275.24 UNK3K40.1
N18714467: length 1.5
  BOTTOM w0.203: UNK3K41.1 235.17,279.81 UNK3RK41.1
N18714480: length 1.5
  BOTTOM w0.203: UNK3RK42.1 235.17,284.38 UNK3K42.1
N18714492: length 1.5
  BOTTOM w0.203: UNK3RK43.1 232.25,275.24 UNK3K43.1
N18714505: length 1.5
  BOTTOM w0.203: UNK3RK45.1 232.25,285.65 UNK3K45.1
N18714506: length 1.5
  BOTTOM w0.203: UNK3K44.1 232.25,281.08 UNK3RK44.1
N18714516: length 1.5
  BOTTOM w0.203: UNK3C66.1 233.05,276.71 UNK3K44.3
N18714534: length 1.5
  BOTTOM w0.203: UNK3RK46.1 229.84,276.76 UNK3K46.1
N18714550: length 1.5
  BOTTOM w0.203: UNK3K47.3 230.64,278.23 UNK3C67.1
N18714563: length 1.5
  BOTTOM w0.203: UNK3K48.1 229.84,287.17 UNK3RK48.1
N18714564: length 1.5
  BOTTOM w0.203: UNK3K47.1 229.84,282.6 UNK3RK47.1
N18714574: length 1.5
  BOTTOM w0.203: UNK3K49.3 228.23,282.8 UNK3C68.1
N18714587: length 1.5
  BOTTOM w0.203: UNK3K50.1 227.43,281.33 UNK3RK50.1
N18714588: length 1.5
  BOTTOM w0.203: UNK3K49.1 227.43,287.17 UNK3RK49.1
N18715402: length 1.3
  BOTTOM w0.203: UNK3K51.4 228.32,244.45 UNK3R7.2
N18715414: length 1.3
  BOTTOM w0.203: UNK3K53.4 236.57,244.45 UNK3R8.2
N18715416: length 1.5
  BOTTOM w0.203: UNK3K53.1 236.57,248.69 UNK3RK53.1
N18715438: length 2.3
  BOTTOM w0.203: v1(206.61,294.24) UNK3R11.2 UNK3R19.1
N18715450: length 2.3
  BOTTOM w0.203: UNK3R20.1 UNK3R14.2 v1(213.21,294.24)
N18715460: length 1.5
  BOTTOM w0.203: UNK3K55.1 201.26,291.95 UNK3RK59.1
N18715463: length 1.3
  BOTTOM w0.508: UNK3R19.2 UNK3K55.4
N18715465: length 3
  BOTTOM w0.305: UNK3RK60.1 203.92,287.4
N18715482: length 3.4
  BOTTOM w0.203: UNK3TP_IN-_3.1 238.51,232.74 238.31,232.54 UNK3R16.1 237.41,231.32 UNK3U3.8
N18715483: length 3.4
  BOTTOM w0.203: UNK3U3.7 236.81,231.32 UNK3R16.2 235.89,232.54 235.68,232.74 UNK3TP_IN+_3.1
N18715511: length 3.4
  BOTTOM w0.203: UNK3TP_IN+_4.1 230.6,232.74 230.81,232.54 UNK3R18.2 231.73,231.32 UNK3U4.7
N18715515: length 3.4
  BOTTOM w0.203: UNK3TP_IN-_4.1 233.43,232.74 233.23,232.54 UNK3R18.1 232.33,231.32 UNK3U4.8
N18715526: length 7.5
  BOTTOM w0.508: UNK3R20.2 UNK3K61.4 210.92,287.91 211.43,287.4 212.87,287.4
N18715527: length 1.5
  BOTTOM w0.203: UNK3K54.1 237.37,238.99 UNK3RK54.1
N18715531: length 1.5
  BOTTOM w0.203: UNK3RK51.1 228.32,248.69 UNK3K51.1
N18715533: length 1.5
  BOTTOM w0.203: UNK3K52.1 229.12,238.99 UNK3RK52.1
N18715597: length 1.5
  BOTTOM w0.203: UNK3K57.1 237.71,236.75 237.61,236.86
N18715598: length 1.5
  BOTTOM w0.203: 235.58,236.86 235.68,236.75 UNK3K58.1
N18715599: length 1.5
  BOTTOM w0.203: 232.53,236.86 232.63,236.75 UNK3K59.1
N18715600: length 1.5
  BOTTOM w0.203: UNK3K60.1 230.6,236.75 230.5,236.86
N18715603: length 1.5
  BOTTOM w0.203: UNK3RK61.1 207.86,291.95 UNK3K61.1
N18716734: length 2.2
  BOTTOM w0.635: UNK4C48.1 UNK4K2.3
N18716743: length 6.9
  BOTTOM w0.635: UNK4C49.1 256.27,273.81 256.91,274.45 UNK4K3.3
N18716752: length 1.5
  BOTTOM w0.508: UNK4C50.1 UNK4K5.3
N18716785: length 1.5
  BOTTOM w0.203: UNK4K7.1 257.77,263.76 UNK4RK7.1
N18716792: length 1.5
  BOTTOM w0.203: UNK4C53.1 262.14,262.02 UNK4K8.3
N18716801: length 1.5
  BOTTOM w0.203: UNK4C54.1 256.42,262.02 UNK4K9.3
N18716831: length 6.9
  BOTTOM w0.508: 262.67,253.35 UNK4K12.3
  BOTTOM w0.635: UNK4C59.1 260.59,249.17 262.22,250.8 262.22,252.9 262.67,253.35
N18716838: length 1.5
  BOTTOM w0.203: UNK4R1.1 263.36,248.69 UNK4K13.3
N18716856: length 25.6
  BOTTOM w0.203: v2(267.45,265.74) 263.32,261.61 263.32,260.79 261.35,258.83 261.35,251.59 258.34,248.58 258.34,246.04 UNK4K15.6
N18716874: length 1.5
  BOTTOM w0.203: UNK4K5.1 257.77,268.59 UNK4RK5.1
N18716876: length 1.5
  BOTTOM w0.203: UNK4RK6.1 257.77,265.79 UNK4K6.1
N18716878: length 1.5
  BOTTOM w0.203: UNK4RK8.1 257.77,261.22 UNK4K8.1
N18716879: length 1.5
  BOTTOM w0.203: UNK4K9.1 252.05,261.22 UNK4RK9.1
N18716880: length 1.5
  BOTTOM w0.203: UNK4K10.1 253.2,263.76 UNK4RK10.1
N18716881: length 1.5
  BOTTOM w0.203: UNK4RK11.1 264.16,255.12 UNK4K11.1
N18716884: length 1.3
  BOTTOM w0.508: UNK4C58.1 UNK4K11.3
N18716887: length 1.5
  BOTTOM w0.203: UNK4RK12.1 264.16,250.29 UNK4K12.1
N18716889: length 1.5
  BOTTOM w0.203: UNK4RK13.1 264.16,244.32 UNK4K13.1
N18716892: length 1.5
  BOTTOM w0.203: UNK4RK14.1 266.96,250.29 UNK4K14.1
N18716894: length 3.4
  BOTTOM w0.203: UNK4RK2.1 262.47,283.73 262.87,283.32 UNK4K2.1
N18716895: length 1.9
  BOTTOM w0.203: UNK4K3.1 UNK4RK3.1
N18716896: length 2.4
  BOTTOM w0.203: UNK4RK4.1 262.04,296.93 262.87,296.1 UNK4K4.1
N18716916: length 27.9
  TOP w0.305: SITE4.8_F 266.71,265.4
  TOP w0.635: 266.71,265.4 265.16,263.85 265.16,255.65 257.92,248.41 255.89,248.41 255.29,247.82 255.29,246.19 UNK4K15.3
N18716928: length 1.5
  BOTTOM w0.203: UNK4C60.1 UNK4K16.3
N18716941: length 1.5
  BOTTOM w0.203: UNK4K17.1 269.12,255.12 UNK4RK17.1
N18716955: length 1.5
  BOTTOM w0.203: UNK4K16.1 266.96,255.12 UNK4RK16.1
N18716959: length 1.5
  BOTTOM w0.203: UNK4K18.1 269.12,250.29 UNK4RK18.1
N18718109: length 1.5
  BOTTOM w0.203: UNK4C69.1 UNK4K19.3
N18718136: length 1.5
  BOTTOM w0.203: UNK4RK19.1 271.91,255.12 UNK4K19.1
N18718138: length 1.5
  BOTTOM w0.203: UNK4K20.1 271.91,250.29 UNK4RK20.1
N18718139: length 1.5
  BOTTOM w0.203: UNK4K21.1 274.07,255.12 UNK4RK21.1
N18718164: length 1.5
  BOTTOM w0.203: UNK4RK22.1 274.07,250.29 UNK4K22.1
N18718170: length 24.1
  BOTTOM w0.203: 274.38,244.3 273.24,245.44 273.24,247.49 274.81,249.07 274.81,259.97 270.3,264.48 v2(270.3,265.39)
N18718184: length 28.6
  BOTTOM w0.203: 282.64,244.3 281.15,245.78 281.15,248.53 280.21,249.48 275.8,249.48 275.32,249.96 275.32,260.22 270.8,264.74 v2(270.8,265.39)
N18718194: length 1.5
  BOTTOM w0.203: UNK4C62.1 UNK4K25.3
N18718212: length 1.5
  BOTTOM w0.203: UNK4K25.1 277.37,255.12 UNK4RK25.1
N18718216: length 1.5
  BOTTOM w0.203: UNK4RK26.1 277.37,250.29 UNK4K26.1
N18718221: length 1.5
  BOTTOM w0.203: UNK4C63.1 UNK4K27.3
N18718237: length 1.5
  BOTTOM w0.203: UNK4RK28.1 286.9,261.77 UNK4K28.1
N18718258: length 1.5
  BOTTOM w0.203: UNK4K27.1 282.33,261.77 UNK4RK27.1
N18718260: length 1.1
  BOTTOM w0.203: UNK4RK29.1 UNK4K29.1
N18718265: length 1.5
  BOTTOM w0.203: UNK4C61.1 UNK4K30.3
N18718279: length 1.5
  BOTTOM w0.203: UNK4RK31.1 286.9,265.58 UNK4K31.1
N18718299: length 1.5
  BOTTOM w0.203: UNK4K30.1 282.33,265.58 UNK4RK30.1
N18718302: length 1.1
  BOTTOM w0.203: UNK4RK32.1 UNK4K32.1
N18718304: length 1.5
  BOTTOM w0.203: UNK4RK35.1 291.48,268.62 UNK4K35.1
N18718306: length 1.5
  BOTTOM w0.203: UNK4RK34.1 286.9,268.62 UNK4K34.1
N18718308: length 1.5
  BOTTOM w0.203: UNK4RK33.1 282.33,268.62 UNK4K33.1
N18718311: length 1.5
  BOTTOM w0.203: UNK4C64.1 UNK4K33.3
N18718346: length 1.5
  BOTTOM w0.203: UNK4RK37.1 286.9,271.67 UNK4K37.1
N18718347: length 1.5
  BOTTOM w0.203: UNK4K36.1 282.33,271.67 UNK4RK36.1
N18718353: length 1.5
  BOTTOM w0.203: UNK4C65.1 UNK4K36.3
N18719639: length 1.5
  BOTTOM w0.203: UNK4RK39.1 286.9,274.21 UNK4K39.1
N18719640: length 1.5
  BOTTOM w0.203: UNK4K38.1 282.33,274.21 UNK4RK38.1
N18719646: length 1.5
  BOTTOM w0.203: UNK4C74.1 UNK4K38.3
N18719665: length 1.5
  BOTTOM w0.203: UNK4K40.1 275.17,275.24 UNK4RK40.1
N18719678: length 1.5
  BOTTOM w0.203: UNK4RK41.1 275.17,279.81 UNK4K41.1
N18719691: length 1.5
  BOTTOM w0.203: UNK4K42.1 275.17,284.38 UNK4RK42.1
N18719703: length 1.5
  BOTTOM w0.203: UNK4RK43.1 272.25,275.24 UNK4K43.1
N18719716: length 1.5
  BOTTOM w0.203: UNK4RK45.1 272.25,285.65 UNK4K45.1
N18719717: length 1.5
  BOTTOM w0.203: UNK4RK44.1 272.25,281.08 UNK4K44.1
N18719727: length 1.5
  BOTTOM w0.203: UNK4K44.3 273.05,276.71 UNK4C66.1
N18719745: length 1.5
  BOTTOM w0.203: UNK4K46.1 269.84,276.76 UNK4RK46.1
N18719761: length 1.5
  BOTTOM w0.203: UNK4C67.1 270.64,278.23 UNK4K47.3
N18719774: length 1.5
  BOTTOM w0.203: UNK4RK48.1 269.84,287.17 UNK4K48.1
N18719775: length 1.5
  BOTTOM w0.203: UNK4RK47.1 269.84,282.6 UNK4K47.1
N18719785: length 1.5
  BOTTOM w0.203: UNK4C68.1 268.23,282.8 UNK4K49.3
N18719798: length 1.5
  BOTTOM w0.203: UNK4K50.1 267.43,281.33 UNK4RK50.1
N18719799: length 1.5
  BOTTOM w0.203: UNK4RK49.1 267.43,287.17 UNK4K49.1
N18720613: length 1.3
  BOTTOM w0.203: UNK4K51.4 268.32,244.45 UNK4R7.2
N18720625: length 1.3
  BOTTOM w0.203: UNK4K53.4 276.57,244.45 UNK4R8.2
N18720627: length 1.5
  BOTTOM w0.203: UNK4K53.1 276.57,248.69 UNK4RK53.1
N18720649: length 2.3
  BOTTOM w0.203: UNK4R19.1 UNK4R11.2 v1(246.61,294.24)
N18720661: length 2.3
  BOTTOM w0.203: v1(253.21,294.24) UNK4R14.2 UNK4R20.1
N18720671: length 1.5
  BOTTOM w0.203: UNK4K55.1 241.26,291.95 UNK4RK59.1
N18720674: length 1.3
  BOTTOM w0.508: UNK4R19.2 UNK4K55.4
N18720676: length 3
  BOTTOM w0.305: UNK4RK60.1 243.92,287.4
N18720693: length 3.4
  BOTTOM w0.203: UNK4TP_IN-_3.1 278.51,232.74 278.31,232.54 UNK4R16.1 277.41,231.32 UNK4U3.8
N18720694: length 3.4
  BOTTOM w0.203: UNK4U3.7 276.81,231.32 UNK4R16.2 275.89,232.54 275.68,232.74 UNK4TP_IN+_3.1
N18720722: length 3.4
  BOTTOM w0.203: UNK4TP_IN+_4.1 270.6,232.74 270.81,232.54 UNK4R18.2 271.73,231.32 UNK4U4.7
N18720726: length 3.4
  BOTTOM w0.203: UNK4U4.8 272.33,231.32 UNK4R18.1 273.23,232.54 273.43,232.74 UNK4TP_IN-_4.1
N18720737: length 7.5
  BOTTOM w0.508: UNK4R20.2 UNK4K61.4 250.92,287.91 251.43,287.4 252.87,287.4
N18720738: length 1.5
  BOTTOM w0.203: UNK4RK54.1 277.37,238.99 UNK4K54.1
N18720742: length 1.5
  BOTTOM w0.203: UNK4RK51.1 268.32,248.69 UNK4K51.1
N18720744: length 1.5
  BOTTOM w0.203: UNK4K52.1 269.12,238.99 UNK4RK52.1
N18720808: length 1.5
  BOTTOM w0.203: 277.61,236.86 277.71,236.75 UNK4K57.1
N18720809: length 1.5
  BOTTOM w0.203: 275.58,236.86 275.68,236.75 UNK4K58.1
N18720810: length 1.5
  BOTTOM w0.203: 272.53,236.86 272.63,236.75 UNK4K59.1
N18720811: length 1.5
  BOTTOM w0.203: 270.5,236.86 270.6,236.75 UNK4K60.1
N18720814: length 1.5
  BOTTOM w0.203: UNK4K61.1 247.86,291.95 UNK4RK61.1
N18721945: length 2.2
  BOTTOM w0.635: UNK5C48.1 UNK5K2.3
N18721954: length 6.9
  BOTTOM w0.635: UNK5C49.1 136.27,213.81 136.91,214.45 UNK5K3.3
N18721963: length 1.5
  BOTTOM w0.508: UNK5C50.1 UNK5K5.3
N18721996: length 1.5
  BOTTOM w0.203: UNK5RK7.1 137.77,203.76 UNK5K7.1
N18722003: length 1.5
  BOTTOM w0.203: UNK5C53.1 142.14,202.02 UNK5K8.3
N18722012: length 1.5
  BOTTOM w0.203: UNK5C54.1 136.42,202.02 UNK5K9.3
N18722042: length 6.9
  BOTTOM w0.508: 142.67,193.35 UNK5K12.3
  BOTTOM w0.635: UNK5C59.1 140.59,189.17 142.22,190.8 142.22,192.9 142.67,193.35
N18722049: length 1.5
  BOTTOM w0.203: UNK5R1.1 143.36,188.69 UNK5K13.3
N18722067: length 25.6
  BOTTOM w0.203: UNK5K15.6 138.34,186.04 138.34,188.58 141.35,191.59 141.35,198.83 143.32,200.79 143.32,201.61 v2(147.45,205.74)
N18722085: length 1.5
  BOTTOM w0.203: UNK5K5.1 137.77,208.59 UNK5RK5.1
N18722087: length 1.5
  BOTTOM w0.203: UNK5RK6.1 137.77,205.79 UNK5K6.1
N18722089: length 1.5
  BOTTOM w0.203: UNK5RK8.1 137.77,201.22 UNK5K8.1
N18722090: length 1.5
  BOTTOM w0.203: UNK5K9.1 132.05,201.22 UNK5RK9.1
N18722091: length 1.5
  BOTTOM w0.203: UNK5RK10.1 133.2,203.76 UNK5K10.1
N18722092: length 1.5
  BOTTOM w0.203: UNK5RK11.1 144.16,195.12 UNK5K11.1
N18722095: length 1.3
  BOTTOM w0.508: UNK5C58.1 UNK5K11.3
N18722098: length 1.5
  BOTTOM w0.203: UNK5RK12.1 144.16,190.29 UNK5K12.1
N18722100: length 1.5
  BOTTOM w0.203: UNK5K13.1 144.16,184.32 UNK5RK13.1
N18722103: length 1.5
  BOTTOM w0.203: UNK5K14.1 146.96,190.29 UNK5RK14.1
N18722105: length 3.4
  BOTTOM w0.203: UNK5RK2.1 142.47,223.73 142.88,223.32 UNK5K2.1
N18722106: length 1.9
  BOTTOM w0.203: UNK5K3.1 UNK5RK3.1
N18722107: length 2.4
  BOTTOM w0.203: UNK5RK4.1 142.04,236.93 142.88,236.1 UNK5K4.1
N18722127: length 27.9
  TOP w0.305: SITE5.8_F 146.71,205.4
  TOP w0.635: 146.71,205.4 145.16,203.85 145.16,195.65 137.92,188.41 135.89,188.41 135.29,187.82 135.29,186.19 UNK5K15.3
N18722139: length 1.5
  BOTTOM w0.203: UNK5C60.1 UNK5K16.3
N18722152: length 1.5
  BOTTOM w0.203: UNK5K17.1 149.12,195.12 UNK5RK17.1
N18722166: length 1.5
  BOTTOM w0.203: UNK5K16.1 146.96,195.12 UNK5RK16.1
N18722170: length 1.5
  BOTTOM w0.203: UNK5RK18.1 149.12,190.29 UNK5K18.1
N18723320: length 1.5
  BOTTOM w0.203: UNK5C69.1 UNK5K19.3
N18723347: length 1.5
  BOTTOM w0.203: UNK5K19.1 151.91,195.12 UNK5RK19.1
N18723349: length 1.5
  BOTTOM w0.203: UNK5K20.1 151.91,190.29 UNK5RK20.1
N18723350: length 1.5
  BOTTOM w0.203: UNK5K21.1 154.07,195.12 UNK5RK21.1
N18723375: length 1.5
  BOTTOM w0.203: UNK5K22.1 154.07,190.29 UNK5RK22.1
N18723381: length 24.1
  BOTTOM w0.203: v2(150.3,205.39) 150.3,204.48 154.81,199.97 154.81,189.07 153.24,187.49 153.24,185.44 154.38,184.3
N18723395: length 28.6
  BOTTOM w0.203: 162.64,184.3 161.15,185.78 161.15,188.53 160.21,189.48 155.8,189.48 155.32,189.96 155.32,200.22 150.8,204.74 v2(150.8,205.39)
N18723405: length 1.5
  BOTTOM w0.203: UNK5C62.1 UNK5K25.3
N18723423: length 1.5
  BOTTOM w0.203: UNK5RK25.1 157.37,195.12 UNK5K25.1
N18723427: length 1.5
  BOTTOM w0.203: UNK5K26.1 157.37,190.29 UNK5RK26.1
N18723432: length 1.5
  BOTTOM w0.203: UNK5C63.1 UNK5K27.3
N18723448: length 1.5
  BOTTOM w0.203: UNK5K28.1 166.9,201.77 UNK5RK28.1
N18723469: length 1.5
  BOTTOM w0.203: UNK5RK27.1 162.33,201.77 UNK5K27.1
N18723471: length 1.1
  BOTTOM w0.203: UNK5RK29.1 UNK5K29.1
N18723476: length 1.5
  BOTTOM w0.203: UNK5C61.1 UNK5K30.3
N18723490: length 1.5
  BOTTOM w0.203: UNK5RK31.1 166.9,205.58 UNK5K31.1
N18723510: length 1.5
  BOTTOM w0.203: UNK5K30.1 162.33,205.58 UNK5RK30.1
N18723513: length 1.1
  BOTTOM w0.203: UNK5RK32.1 UNK5K32.1
N18723515: length 1.5
  BOTTOM w0.203: UNK5RK35.1 171.48,208.62 UNK5K35.1
N18723517: length 1.5
  BOTTOM w0.203: UNK5RK34.1 166.9,208.62 UNK5K34.1
N18723519: length 1.5
  BOTTOM w0.203: UNK5K33.1 162.33,208.62 UNK5RK33.1
N18723522: length 1.5
  BOTTOM w0.203: UNK5C64.1 UNK5K33.3
N18723557: length 1.5
  BOTTOM w0.203: UNK5RK37.1 166.9,211.67 UNK5K37.1
N18723558: length 1.5
  BOTTOM w0.203: UNK5RK36.1 162.33,211.67 UNK5K36.1
N18723564: length 1.5
  BOTTOM w0.203: UNK5C65.1 UNK5K36.3
N18724850: length 1.5
  BOTTOM w0.203: UNK5RK39.1 166.9,214.21 UNK5K39.1
N18724851: length 1.5
  BOTTOM w0.203: UNK5K38.1 162.33,214.21 UNK5RK38.1
N18724857: length 1.5
  BOTTOM w0.203: UNK5C74.1 UNK5K38.3
N18724876: length 1.5
  BOTTOM w0.203: UNK5RK40.1 155.17,215.24 UNK5K40.1
N18724889: length 1.5
  BOTTOM w0.203: UNK5K41.1 155.17,219.81 UNK5RK41.1
N18724902: length 1.5
  BOTTOM w0.203: UNK5K42.1 155.17,224.38 UNK5RK42.1
N18724914: length 1.5
  BOTTOM w0.203: UNK5RK43.1 152.25,215.24 UNK5K43.1
N18724927: length 1.5
  BOTTOM w0.203: UNK5K45.1 152.25,225.65 UNK5RK45.1
N18724928: length 1.5
  BOTTOM w0.203: UNK5RK44.1 152.25,221.08 UNK5K44.1
N18724938: length 1.5
  BOTTOM w0.203: UNK5K44.3 153.05,216.71 UNK5C66.1
N18724956: length 1.5
  BOTTOM w0.203: UNK5RK46.1 149.84,216.76 UNK5K46.1
N18724972: length 1.5
  BOTTOM w0.203: UNK5C67.1 150.64,218.23 UNK5K47.3
N18724985: length 1.5
  BOTTOM w0.203: UNK5K48.1 149.84,227.17 UNK5RK48.1
N18724986: length 1.5
  BOTTOM w0.203: UNK5RK47.1 149.84,222.6 UNK5K47.1
N18724996: length 1.5
  BOTTOM w0.203: UNK5K49.3 148.23,222.8 UNK5C68.1
N18725009: length 1.5
  BOTTOM w0.203: UNK5RK50.1 147.43,221.33 UNK5K50.1
N18725010: length 1.5
  BOTTOM w0.203: UNK5K49.1 147.43,227.17 UNK5RK49.1
N18725824: length 1.3
  BOTTOM w0.203: UNK5R7.2 148.32,184.45 UNK5K51.4
N18725836: length 1.3
  BOTTOM w0.203: UNK5K53.4 156.57,184.45 UNK5R8.2
N18725838: length 1.5
  BOTTOM w0.203: UNK5K53.1 156.57,188.69 UNK5RK53.1
N18725860: length 2.3
  BOTTOM w0.203: UNK5R19.1 UNK5R11.2 v1(126.61,234.24)
N18725872: length 2.3
  BOTTOM w0.203: UNK5R20.1 UNK5R14.2 v1(133.22,234.24)
N18725882: length 1.5
  BOTTOM w0.203: UNK5K55.1 121.26,231.95 UNK5RK59.1
N18725885: length 1.3
  BOTTOM w0.508: UNK5R19.2 UNK5K55.4
N18725887: length 3
  BOTTOM w0.305: UNK5RK60.1 UNK5K56.1
N18725904: length 3.4
  BOTTOM w0.203: UNK5U3.8 157.41,171.32 UNK5R16.1 158.31,172.54 158.52,172.74 UNK5TP_IN-_3.1
N18725905: length 3.4
  BOTTOM w0.203: UNK5U3.7 156.81,171.32 UNK5R16.2 155.89,172.54 155.68,172.74 UNK5TP_IN+_3.1
N18725933: length 3.4
  BOTTOM w0.203: UNK5TP_IN+_4.1 150.6,172.74 150.81,172.54 UNK5R18.2 151.73,171.32 UNK5U4.7
N18725937: length 3.4
  BOTTOM w0.203: UNK5TP_IN-_4.1 153.44,172.74 153.23,172.54 UNK5R18.1 152.33,171.32 UNK5U4.8
N18725948: length 7.5
  BOTTOM w0.508: UNK5K56.4 131.43,227.4 130.92,227.91 UNK5K61.4 UNK5R20.2
N18725949: length 1.5
  BOTTOM w0.203: UNK5K54.1 157.37,178.99 UNK5RK54.1
N18725953: length 1.5
  BOTTOM w0.203: UNK5RK51.1 148.32,188.69 UNK5K51.1
N18725955: length 1.5
  BOTTOM w0.203: UNK5RK52.1 149.12,178.99 UNK5K52.1
N18726019: length 1.5
  BOTTOM w0.203: UNK5K57.1 157.71,176.76 UNK5RK55.2
N18726020: length 1.5
  BOTTOM w0.203: UNK5RK56.2 155.68,176.76 UNK5K58.1
N18726021: length 1.5
  BOTTOM w0.203: UNK5K59.1 152.63,176.76 UNK5RK57.2
N18726022: length 1.5
  BOTTOM w0.203: UNK5K60.1 150.6,176.76 UNK5RK58.2
N18726025: length 1.5
  BOTTOM w0.203: UNK5K61.1 127.86,231.95 UNK5RK61.1
N18727156: length 2.2
  BOTTOM w0.635: UNK6C48.1 UNK6K2.3
N18727165: length 6.9
  BOTTOM w0.635: UNK6C49.1 176.27,213.81 176.91,214.45 UNK6K3.3
N18727174: length 1.5
  BOTTOM w0.508: UNK6C50.1 UNK6K5.3
N18727207: length 1.5
  BOTTOM w0.203: UNK6RK7.1 177.77,203.76 UNK6K7.1
N18727214: length 1.5
  BOTTOM w0.203: UNK6C53.1 182.14,202.02 UNK6K8.3
N18727223: length 1.5
  BOTTOM w0.203: UNK6C54.1 176.42,202.02 UNK6K9.3
N18727253: length 6.9
  BOTTOM w0.508: 182.67,193.35 UNK6K12.3
  BOTTOM w0.635: UNK6C59.1 180.59,189.17 182.22,190.8 182.22,192.9 182.67,193.35
N18727260: length 1.5
  BOTTOM w0.203: UNK6K13.3 183.36,188.69 UNK6R1.1
N18727278: length 25.6
  BOTTOM w0.203: UNK6K15.6 178.34,186.04 178.34,188.58 181.35,191.59 181.35,198.83 183.32,200.79 183.32,201.61 v2(187.45,205.74)
N18727296: length 1.5
  BOTTOM w0.203: UNK6RK5.1 177.77,208.59 UNK6K5.1
N18727298: length 1.5
  BOTTOM w0.203: UNK6K6.1 177.77,205.79 UNK6RK6.1
N18727300: length 1.5
  BOTTOM w0.203: UNK6K8.1 177.77,201.22 UNK6RK8.1
N18727301: length 1.5
  BOTTOM w0.203: UNK6K9.1 172.05,201.22 UNK6RK9.1
N18727302: length 1.5
  BOTTOM w0.203: UNK6RK10.1 173.2,203.76 UNK6K10.1
N18727303: length 1.5
  BOTTOM w0.203: UNK6RK11.1 184.16,195.12 UNK6K11.1
N18727306: length 1.3
  BOTTOM w0.508: UNK6C58.1 UNK6K11.3
N18727309: length 1.5
  BOTTOM w0.203: UNK6K12.1 184.16,190.29 UNK6RK12.1
N18727311: length 1.5
  BOTTOM w0.203: UNK6K13.1 184.16,184.32 UNK6RK13.1
N18727314: length 1.5
  BOTTOM w0.203: UNK6RK14.1 186.96,190.29 UNK6K14.1
N18727316: length 3.4
  BOTTOM w0.203: UNK6K2.1 182.87,223.32 182.47,223.73 UNK6RK2.1
N18727317: length 1.9
  BOTTOM w0.203: UNK6K3.1 UNK6RK3.1
N18727318: length 2.4
  BOTTOM w0.203: UNK6RK4.1 182.04,236.93 182.87,236.1 UNK6K4.1
N18727338: length 27.9
  TOP w0.305: SITE6.8_F 186.71,205.4
  TOP w0.635: UNK6K15.3 175.29,186.19 175.29,187.82 175.89,188.41 177.92,188.41 185.16,195.65 185.16,203.85 186.71,205.4
N18727350: length 1.5
  BOTTOM w0.203: UNK6C60.1 UNK6K16.3
N18727363: length 1.5
  BOTTOM w0.203: UNK6RK17.1 189.12,195.12 UNK6K17.1
N18727377: length 1.5
  BOTTOM w0.203: UNK6RK16.1 186.96,195.12 UNK6K16.1
N18727381: length 1.5
  BOTTOM w0.203: UNK6K18.1 189.12,190.29 UNK6RK18.1
N18728531: length 1.5
  BOTTOM w0.203: UNK6C69.1 UNK6K19.3
N18728558: length 1.5
  BOTTOM w0.203: UNK6RK19.1 191.91,195.12 UNK6K19.1
N18728560: length 1.5
  BOTTOM w0.203: UNK6RK20.1 191.91,190.29 UNK6K20.1
N18728561: length 1.5
  BOTTOM w0.203: UNK6K21.1 194.07,195.12 UNK6RK21.1
N18728586: length 1.5
  BOTTOM w0.203: UNK6RK22.1 194.07,190.29 UNK6K22.1
N18728592: length 24.1
  BOTTOM w0.203: 194.38,184.3 193.24,185.44 193.24,187.49 194.81,189.07 194.81,199.97 190.3,204.48 v2(190.3,205.39)
N18728606: length 28.6
  BOTTOM w0.203: v2(190.8,205.39) 190.8,204.74 195.32,200.22 195.32,189.96 195.8,189.48 200.21,189.48 201.15,188.53 201.15,185.78 202.64,184.3
N18728616: length 1.5
  BOTTOM w0.203: UNK6C62.1 UNK6K25.3
N18728634: length 1.5
  BOTTOM w0.203: UNK6RK25.1 197.37,195.12 UNK6K25.1
N18728638: length 1.5
  BOTTOM w0.203: UNK6RK26.1 197.37,190.29 UNK6K26.1
N18728643: length 1.5
  BOTTOM w0.203: UNK6C63.1 UNK6K27.3
N18728659: length 1.5
  BOTTOM w0.203: UNK6K28.1 206.9,201.77 UNK6RK28.1
N18728680: length 1.5
  BOTTOM w0.203: UNK6RK27.1 202.33,201.77 UNK6K27.1
N18728682: length 1.1
  BOTTOM w0.203: UNK6RK29.1 UNK6K29.1
N18728687: length 1.5
  BOTTOM w0.203: UNK6C61.1 UNK6K30.3
N18728701: length 1.5
  BOTTOM w0.203: UNK6RK31.1 206.9,205.58 UNK6K31.1
N18728721: length 1.5
  BOTTOM w0.203: UNK6K30.1 202.33,205.58 UNK6RK30.1
N18728724: length 1.1
  BOTTOM w0.203: UNK6RK32.1 UNK6K32.1
N18728726: length 1.5
  BOTTOM w0.203: UNK6K35.1 211.48,208.62 UNK6RK35.1
N18728728: length 1.5
  BOTTOM w0.203: UNK6K34.1 206.9,208.62 UNK6RK34.1
N18728730: length 1.5
  BOTTOM w0.203: UNK6RK33.1 202.33,208.62 UNK6K33.1
N18728733: length 1.5
  BOTTOM w0.203: UNK6C64.1 UNK6K33.3
N18728768: length 1.5
  BOTTOM w0.203: UNK6RK37.1 206.9,211.67 UNK6K37.1
N18728769: length 1.5
  BOTTOM w0.203: UNK6RK36.1 202.33,211.67 UNK6K36.1
N18728775: length 1.5
  BOTTOM w0.203: UNK6C65.1 UNK6K36.3
N18730061: length 1.5
  BOTTOM w0.203: UNK6K39.1 206.9,214.21 UNK6RK39.1
N18730062: length 1.5
  BOTTOM w0.203: UNK6RK38.1 202.33,214.21 UNK6K38.1
N18730068: length 1.5
  BOTTOM w0.203: UNK6C74.1 UNK6K38.3
N18730087: length 1.5
  BOTTOM w0.203: UNK6RK40.1 195.17,215.24 UNK6K40.1
N18730100: length 1.5
  BOTTOM w0.203: UNK6RK41.1 195.17,219.81 UNK6K41.1
N18730113: length 1.5
  BOTTOM w0.203: UNK6RK42.1 195.17,224.38 UNK6K42.1
N18730125: length 1.5
  BOTTOM w0.203: UNK6RK43.1 192.25,215.24 UNK6K43.1
N18730138: length 1.5
  BOTTOM w0.203: UNK6RK45.1 192.25,225.65 UNK6K45.1
N18730139: length 1.5
  BOTTOM w0.203: UNK6RK44.1 192.25,221.08 UNK6K44.1
N18730149: length 1.5
  BOTTOM w0.203: UNK6C66.1 193.05,216.71 UNK6K44.3
N18730167: length 1.5
  BOTTOM w0.203: UNK6K46.1 189.84,216.76 UNK6RK46.1
N18730183: length 1.5
  BOTTOM w0.203: UNK6C67.1 190.64,218.23 UNK6K47.3
N18730196: length 1.5
  BOTTOM w0.203: UNK6RK48.1 189.84,227.17 UNK6K48.1
N18730197: length 1.5
  BOTTOM w0.203: UNK6K47.1 189.84,222.6 UNK6RK47.1
N18730207: length 1.5
  BOTTOM w0.203: UNK6C68.1 188.23,222.8 UNK6K49.3
N18730220: length 1.5
  BOTTOM w0.203: UNK6RK50.1 187.43,221.33 UNK6K50.1
N18730221: length 1.5
  BOTTOM w0.203: UNK6RK49.1 187.43,227.17 UNK6K49.1
N18731035: length 1.3
  BOTTOM w0.203: UNK6K51.4 188.32,184.45 UNK6R7.2
N18731047: length 1.3
  BOTTOM w0.203: UNK6R8.2 196.57,184.45 UNK6K53.4
N18731049: length 1.5
  BOTTOM w0.203: UNK6K53.1 196.57,188.69 UNK6RK53.1
N18731071: length 2.3
  BOTTOM w0.203: v1(166.61,234.24) UNK6R11.2 UNK6R19.1
N18731083: length 2.3
  BOTTOM w0.203: v1(173.22,234.24) UNK6R14.2 UNK6R20.1
N18731093: length 1.5
  BOTTOM w0.203: UNK6K55.1 161.26,231.95 UNK6RK59.1
N18731096: length 1.3
  BOTTOM w0.508: UNK6R19.2 UNK6K55.4
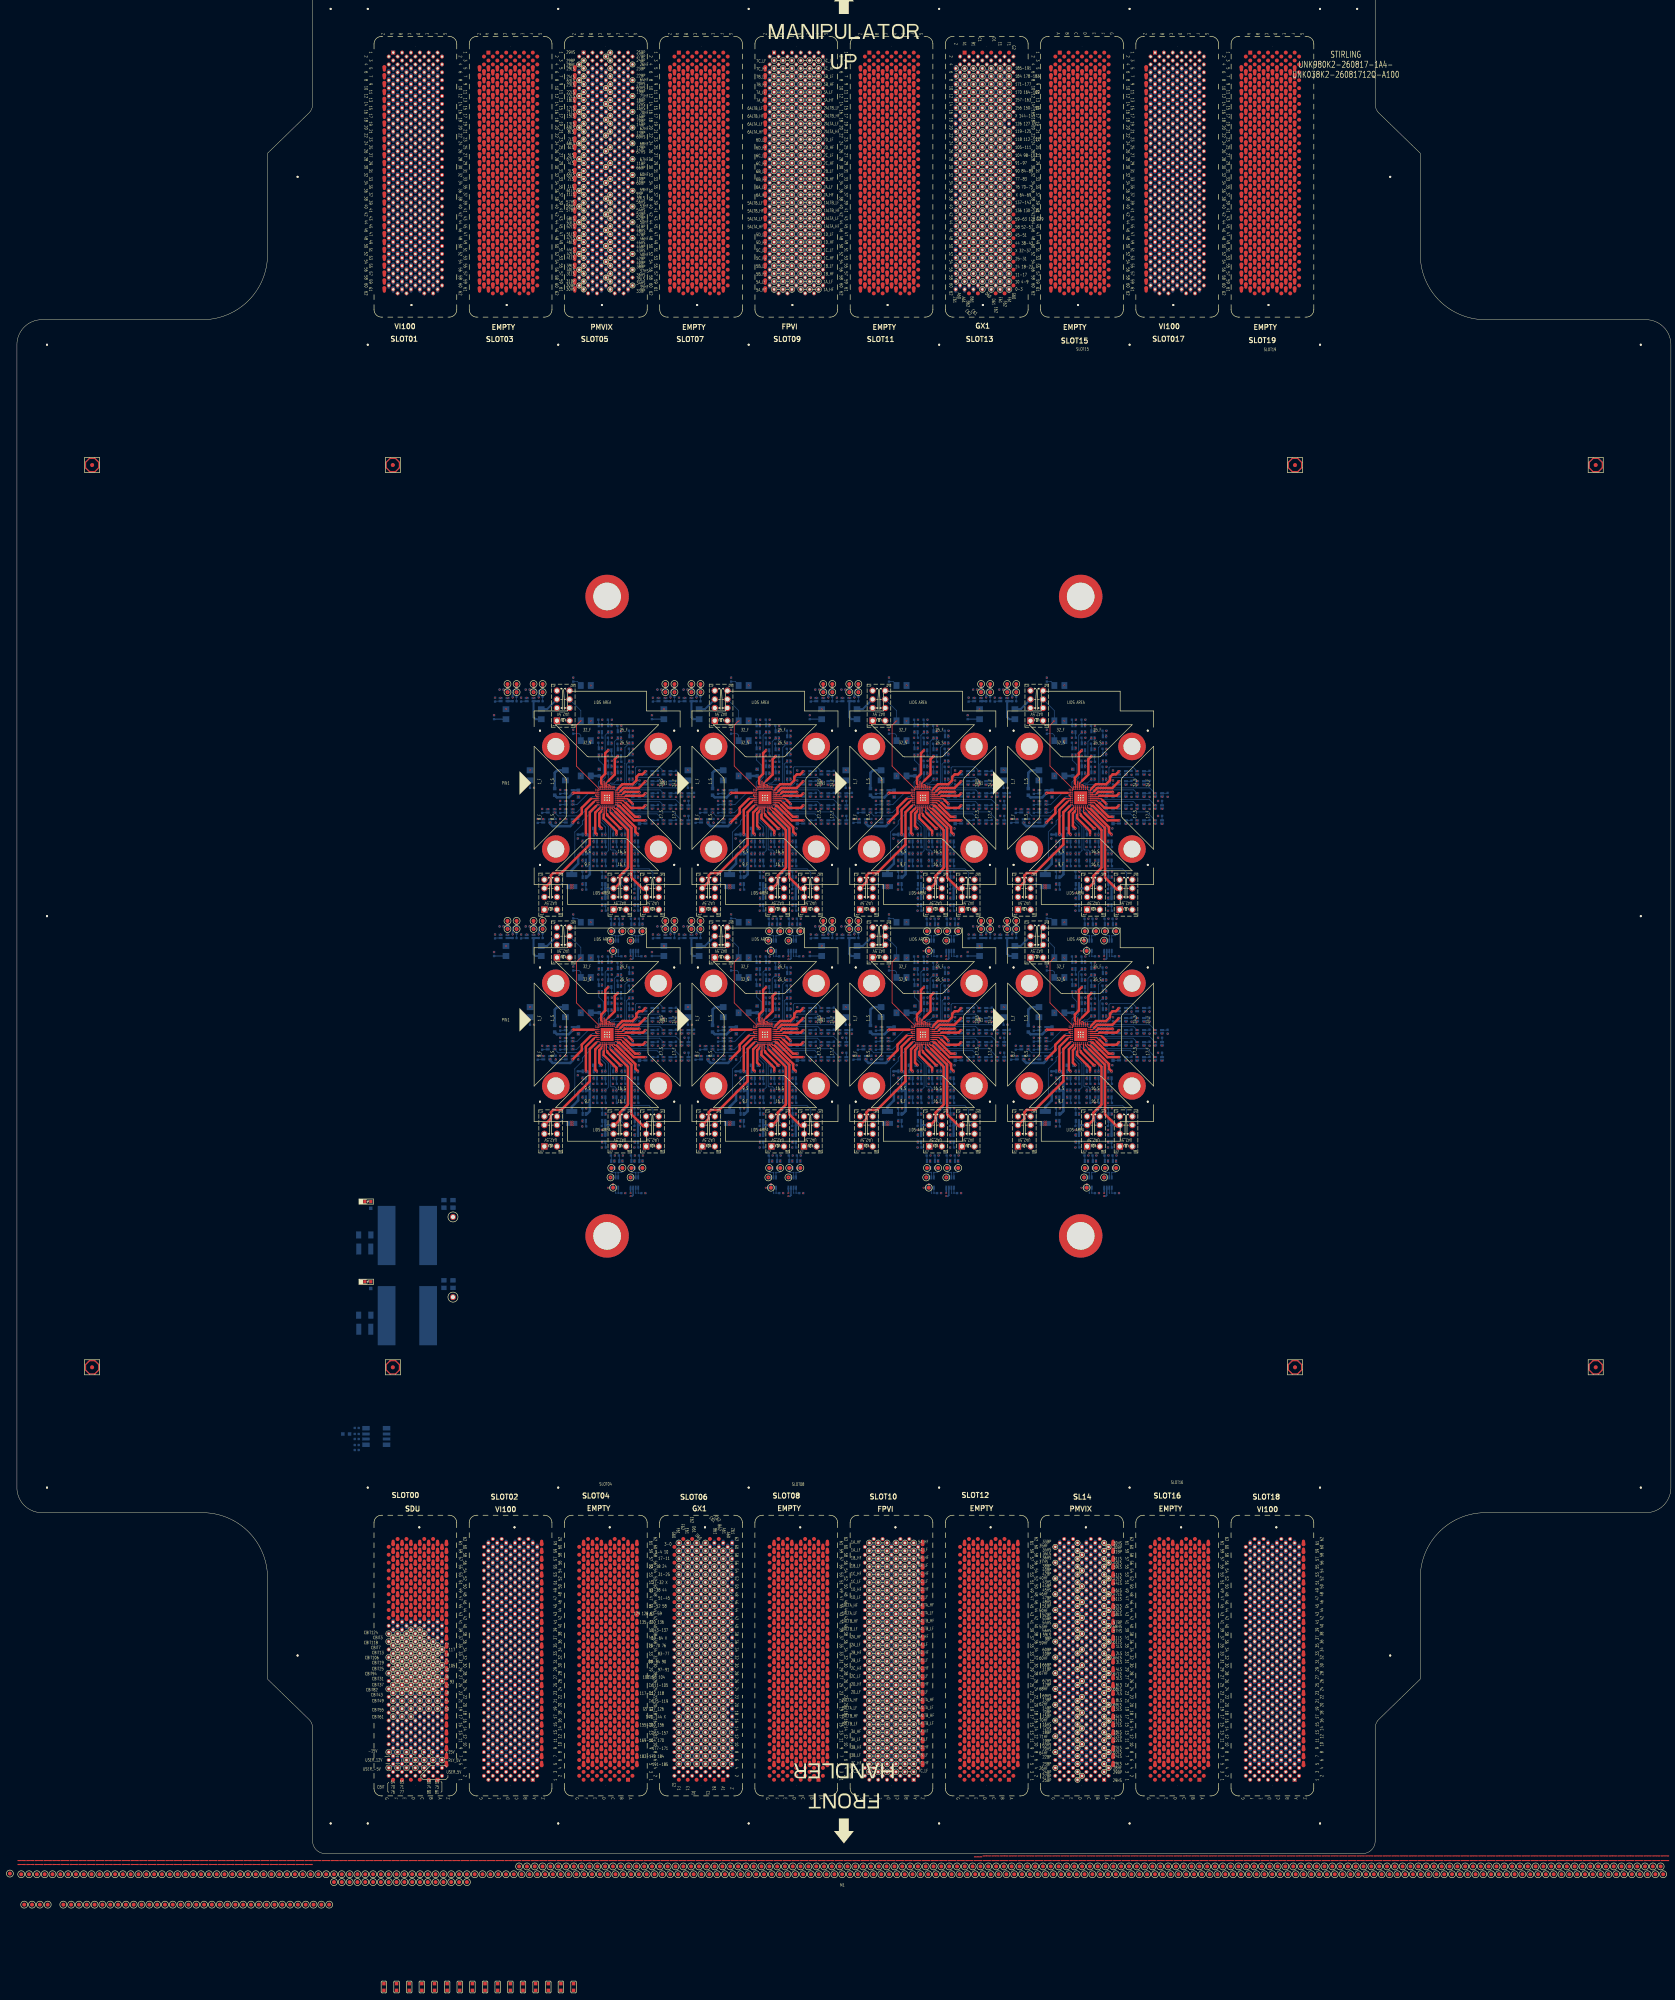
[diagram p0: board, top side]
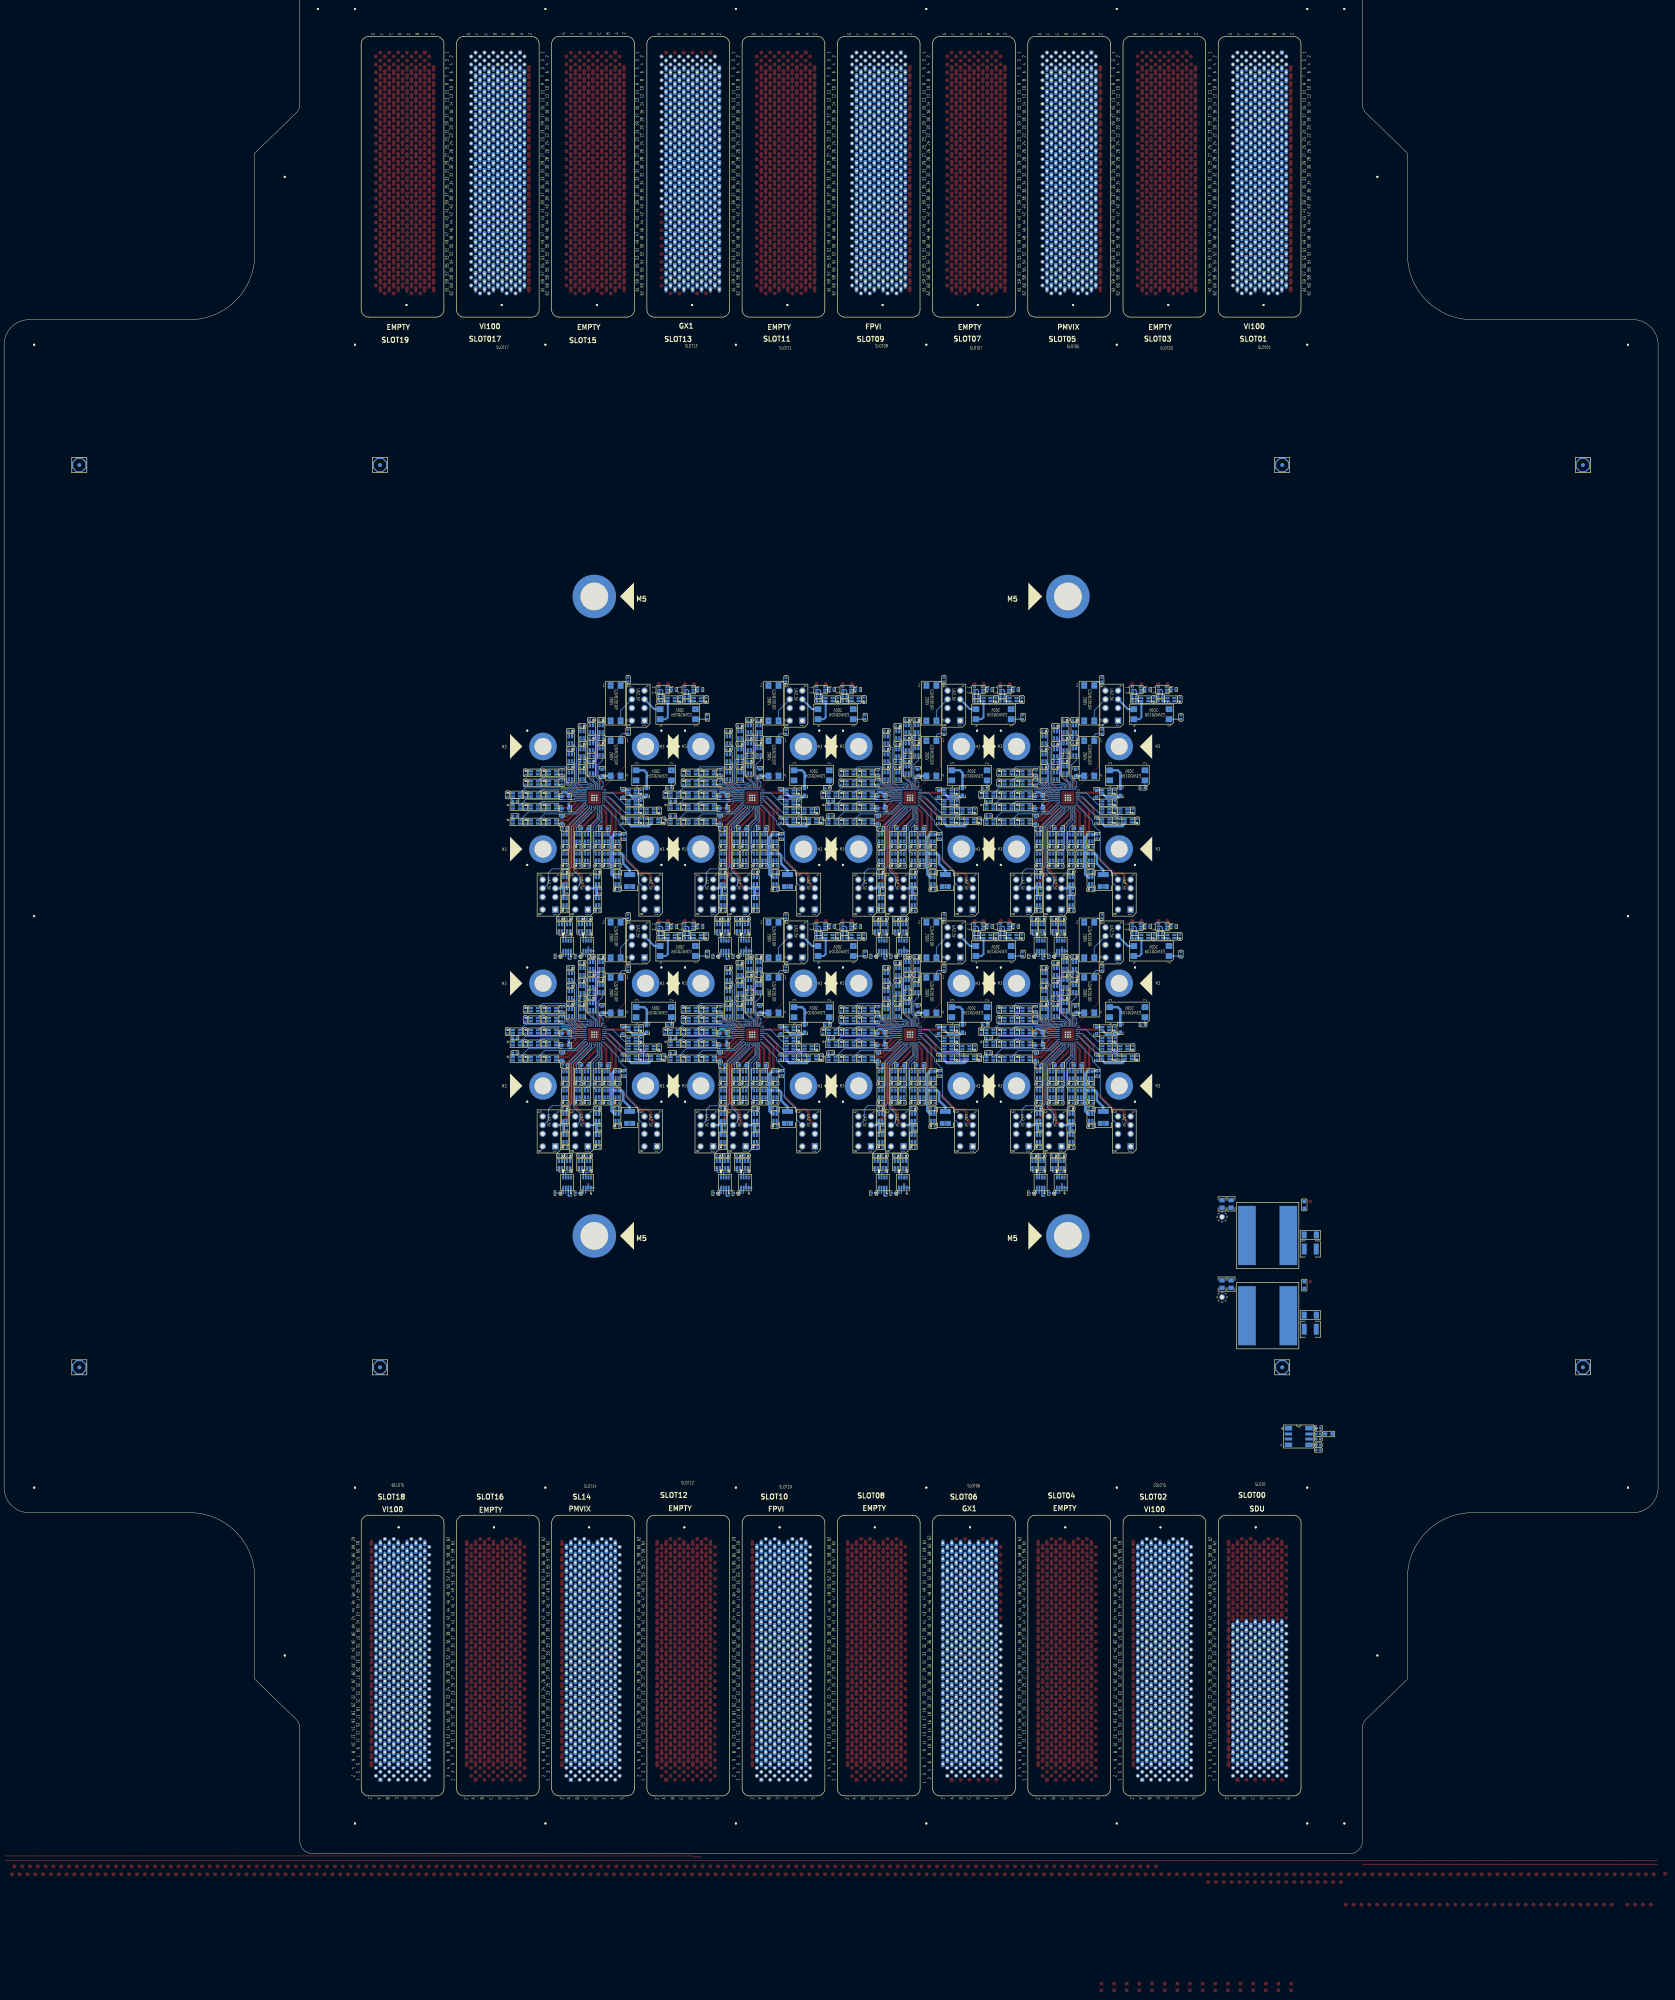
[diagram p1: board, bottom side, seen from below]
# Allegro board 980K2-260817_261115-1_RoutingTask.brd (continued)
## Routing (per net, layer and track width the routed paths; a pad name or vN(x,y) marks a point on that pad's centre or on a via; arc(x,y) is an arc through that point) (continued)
N18731098: length 3
  BOTTOM w0.305: UNK6RK60.1 UNK6K56.1
N18731115: length 3.4
  BOTTOM w0.203: UNK6TP_IN-_3.1 198.51,172.74 198.31,172.54 UNK6R16.1 197.41,171.32 UNK6U3.8
N18731116: length 3.4
  BOTTOM w0.203: UNK6TP_IN+_3.1 195.68,172.74 195.89,172.54 UNK6R16.2 196.81,171.32 UNK6U3.7
N18731144: length 3.4
  BOTTOM w0.203: UNK6TP_IN+_4.1 190.6,172.74 190.81,172.54 UNK6R18.2 191.73,171.32 UNK6U4.7
N18731148: length 3.4
  BOTTOM w0.203: UNK6U4.8 192.33,171.32 UNK6R18.1 193.23,172.54 193.43,172.74 UNK6TP_IN-_4.1
N18731159: length 7.5
  BOTTOM w0.508: UNK6K56.4 171.43,227.4 170.92,227.91 UNK6K61.4 UNK6R20.2
N18731160: length 1.5
  BOTTOM w0.203: UNK6RK54.1 197.37,178.99 UNK6K54.1
N18731164: length 1.5
  BOTTOM w0.203: UNK6K51.1 188.32,188.69 UNK6RK51.1
N18731166: length 1.5
  BOTTOM w0.203: UNK6RK52.1 189.12,178.99 UNK6K52.1
N18731230: length 1.5
  BOTTOM w0.203: UNK6RK55.2 197.71,176.76 UNK6K57.1
N18731231: length 1.5
  BOTTOM w0.203: UNK6K58.1 195.68,176.76 UNK6RK56.2
N18731232: length 1.5
  BOTTOM w0.203: UNK6RK57.2 192.63,176.76 UNK6K59.1
N18731233: length 1.5
  BOTTOM w0.203: UNK6RK58.2 190.6,176.76 UNK6K60.1
N18731236: length 1.5
  BOTTOM w0.203: UNK6RK61.1 167.86,231.95 UNK6K61.1
N18732367: length 2.2
  BOTTOM w0.635: UNK7C48.1 UNK7K2.3
N18732376: length 6.9
  BOTTOM w0.635: UNK7C49.1 216.27,213.81 216.91,214.45 UNK7K3.3
N18732385: length 1.5
  BOTTOM w0.508: UNK7C50.1 UNK7K5.3
N18732418: length 1.5
  BOTTOM w0.203: UNK7K7.1 217.77,203.76 UNK7RK7.1
N18732425: length 1.5
  BOTTOM w0.203: UNK7C53.1 222.14,202.02 UNK7K8.3
N18732434: length 1.5
  BOTTOM w0.203: UNK7K9.3 216.42,202.02 UNK7C54.1
N18732464: length 6.9
  BOTTOM w0.508: 222.67,193.35 UNK7K12.3
  BOTTOM w0.635: 222.67,193.35 222.22,192.9 222.22,190.8 220.59,189.17 UNK7C59.1
N18732471: length 1.5
  BOTTOM w0.203: UNK7R1.1 223.36,188.69 UNK7K13.3
N18732489: length 25.6
  BOTTOM w0.203: UNK7K15.6 218.34,186.04 218.34,188.58 221.35,191.59 221.35,198.83 223.32,200.79 223.32,201.61 v2(227.45,205.74)
N18732507: length 1.5
  BOTTOM w0.203: UNK7RK5.1 217.77,208.59 UNK7K5.1
N18732509: length 1.5
  BOTTOM w0.203: UNK7K6.1 217.77,205.79 UNK7RK6.1
N18732511: length 1.5
  BOTTOM w0.203: UNK7RK8.1 217.77,201.22 UNK7K8.1
N18732512: length 1.5
  BOTTOM w0.203: UNK7RK9.1 212.05,201.22 UNK7K9.1
N18732513: length 1.5
  BOTTOM w0.203: UNK7K10.1 213.2,203.76 UNK7RK10.1
N18732514: length 1.5
  BOTTOM w0.203: UNK7K11.1 224.16,195.12 UNK7RK11.1
N18732517: length 1.3
  BOTTOM w0.508: UNK7C58.1 UNK7K11.3
N18732520: length 1.5
  BOTTOM w0.203: UNK7RK12.1 224.16,190.29 UNK7K12.1
N18732522: length 1.5
  BOTTOM w0.203: UNK7RK13.1 224.16,184.32 UNK7K13.1
N18732525: length 1.5
  BOTTOM w0.203: UNK7RK14.1 226.96,190.29 UNK7K14.1
N18732527: length 3.4
  BOTTOM w0.203: UNK7K2.1 222.87,223.32 222.47,223.73 UNK7RK2.1
N18732528: length 1.9
  BOTTOM w0.203: UNK7K3.1 UNK7RK3.1
N18732529: length 2.4
  BOTTOM w0.203: UNK7RK4.1 222.04,236.93 222.87,236.1 UNK7K4.1
N18732549: length 27.9
  TOP w0.305: SITE7.8_F 226.71,205.4
  TOP w0.635: 226.71,205.4 225.16,203.85 225.16,195.65 217.92,188.41 215.89,188.41 215.29,187.82 215.29,186.19 UNK7K15.3
N18732561: length 1.5
  BOTTOM w0.203: UNK7C60.1 UNK7K16.3
N18732574: length 1.5
  BOTTOM w0.203: UNK7K17.1 229.12,195.12 UNK7RK17.1
N18732588: length 1.5
  BOTTOM w0.203: UNK7K16.1 226.96,195.12 UNK7RK16.1
N18732592: length 1.5
  BOTTOM w0.203: UNK7RK18.1 229.12,190.29 UNK7K18.1
N18733742: length 1.5
  BOTTOM w0.203: UNK7C69.1 UNK7K19.3
N18733769: length 1.5
  BOTTOM w0.203: UNK7K19.1 231.91,195.12 UNK7RK19.1
N18733771: length 1.5
  BOTTOM w0.203: UNK7K20.1 231.91,190.29 UNK7RK20.1
N18733772: length 1.5
  BOTTOM w0.203: UNK7RK21.1 234.07,195.12 UNK7K21.1
N18733797: length 1.5
  BOTTOM w0.203: UNK7K22.1 234.07,190.29 UNK7RK22.1
N18733803: length 24.1
  BOTTOM w0.203: v2(230.3,205.39) 230.3,204.48 234.81,199.97 234.81,189.07 233.24,187.49 233.24,185.44 234.38,184.3
N18733817: length 28.6
  BOTTOM w0.203: v2(230.8,205.39) 230.8,204.74 235.32,200.22 235.32,189.96 235.8,189.48 240.21,189.48 241.15,188.53 241.15,185.78 242.64,184.3
N18733827: length 1.5
  BOTTOM w0.203: UNK7C62.1 UNK7K25.3
N18733845: length 1.5
  BOTTOM w0.203: UNK7K25.1 237.37,195.12 UNK7RK25.1
N18733849: length 1.5
  BOTTOM w0.203: UNK7K26.1 237.37,190.29 UNK7RK26.1
N18733854: length 1.5
  BOTTOM w0.203: UNK7C63.1 UNK7K27.3
N18733870: length 1.5
  BOTTOM w0.203: UNK7K28.1 246.9,201.77 UNK7RK28.1
N18733891: length 1.5
  BOTTOM w0.203: UNK7RK27.1 242.33,201.77 UNK7K27.1
N18733893: length 1.1
  BOTTOM w0.203: UNK7RK29.1 UNK7K29.1
N18733898: length 1.5
  BOTTOM w0.203: UNK7C61.1 UNK7K30.3
N18733912: length 1.5
  BOTTOM w0.203: UNK7K31.1 246.9,205.58 UNK7RK31.1
N18733932: length 1.5
  BOTTOM w0.203: UNK7RK30.1 242.33,205.58 UNK7K30.1
N18733935: length 1.1
  BOTTOM w0.203: UNK7RK32.1 UNK7K32.1
N18733937: length 1.5
  BOTTOM w0.203: UNK7RK35.1 251.48,208.62 UNK7K35.1
N18733939: length 1.5
  BOTTOM w0.203: UNK7RK34.1 246.9,208.62 UNK7K34.1
N18733941: length 1.5
  BOTTOM w0.203: UNK7RK33.1 242.33,208.62 UNK7K33.1
N18733944: length 1.5
  BOTTOM w0.203: UNK7C64.1 UNK7K33.3
N18733979: length 1.5
  BOTTOM w0.203: UNK7RK37.1 246.9,211.67 UNK7K37.1
N18733980: length 1.5
  BOTTOM w0.203: UNK7K36.1 242.33,211.67 UNK7RK36.1
N18733986: length 1.5
  BOTTOM w0.203: UNK7C65.1 UNK7K36.3
N18735272: length 1.5
  BOTTOM w0.203: UNK7K39.1 246.9,214.21 UNK7RK39.1
N18735273: length 1.5
  BOTTOM w0.203: UNK7RK38.1 242.33,214.21 UNK7K38.1
N18735279: length 1.5
  BOTTOM w0.203: UNK7C74.1 UNK7K38.3
N18735298: length 1.5
  BOTTOM w0.203: UNK7RK40.1 235.17,215.24 UNK7K40.1
N18735311: length 1.5
  BOTTOM w0.203: UNK7K41.1 235.17,219.81 UNK7RK41.1
N18735324: length 1.5
  BOTTOM w0.203: UNK7RK42.1 235.17,224.38 UNK7K42.1
N18735336: length 1.5
  BOTTOM w0.203: UNK7K43.1 232.25,215.24 UNK7RK43.1
N18735349: length 1.5
  BOTTOM w0.203: UNK7RK45.1 232.25,225.65 UNK7K45.1
N18735350: length 1.5
  BOTTOM w0.203: UNK7RK44.1 232.25,221.08 UNK7K44.1
N18735360: length 1.5
  BOTTOM w0.203: UNK7K44.3 233.05,216.71 UNK7C66.1
N18735378: length 1.5
  BOTTOM w0.203: UNK7RK46.1 229.84,216.76 UNK7K46.1
N18735394: length 1.5
  BOTTOM w0.203: UNK7K47.3 230.64,218.23 UNK7C67.1
N18735407: length 1.5
  BOTTOM w0.203: UNK7RK48.1 229.84,227.17 UNK7K48.1
N18735408: length 1.5
  BOTTOM w0.203: UNK7RK47.1 229.84,222.6 UNK7K47.1
N18735418: length 1.5
  BOTTOM w0.203: UNK7C68.1 228.23,222.8 UNK7K49.3
N18735431: length 1.5
  BOTTOM w0.203: UNK7K50.1 227.43,221.33 UNK7RK50.1
N18735432: length 1.5
  BOTTOM w0.203: UNK7RK49.1 227.43,227.17 UNK7K49.1
N18736246: length 1.3
  BOTTOM w0.203: UNK7K51.4 228.32,184.45 UNK7R7.2
N18736258: length 1.3
  BOTTOM w0.203: UNK7R8.2 236.57,184.45 UNK7K53.4
N18736260: length 1.5
  BOTTOM w0.203: UNK7K53.1 236.57,188.69 UNK7RK53.1
N18736282: length 2.3
  BOTTOM w0.203: UNK7R19.1 UNK7R11.2 v1(206.61,234.24)
N18736294: length 2.3
  BOTTOM w0.203: v1(213.21,234.24) UNK7R14.2 UNK7R20.1
N18736304: length 1.5
  BOTTOM w0.203: UNK7K55.1 201.26,231.95 UNK7RK59.1
N18736307: length 1.3
  BOTTOM w0.508: UNK7R19.2 UNK7K55.4
N18736309: length 3
  BOTTOM w0.305: UNK7RK60.1 UNK7K56.1
N18736326: length 3.4
  BOTTOM w0.203: UNK7U3.8 237.41,171.32 UNK7R16.1 238.31,172.54 238.51,172.74 UNK7TP_IN-_3.1
N18736327: length 3.4
  BOTTOM w0.203: UNK7U3.7 236.81,171.32 UNK7R16.2 235.89,172.54 235.68,172.74 UNK7TP_IN+_3.1
N18736355: length 3.4
  BOTTOM w0.203: UNK7TP_IN+_4.1 230.6,172.74 230.81,172.54 UNK7R18.2 231.73,171.32 UNK7U4.7
N18736359: length 3.4
  BOTTOM w0.203: UNK7U4.8 232.33,171.32 UNK7R18.1 233.23,172.54 233.43,172.74 UNK7TP_IN-_4.1
N18736370: length 7.5
  BOTTOM w0.508: UNK7K56.4 211.43,227.4 210.92,227.91 UNK7K61.4 UNK7R20.2
N18736371: length 1.5
  BOTTOM w0.203: UNK7RK54.1 237.37,178.99 UNK7K54.1
N18736375: length 1.5
  BOTTOM w0.203: UNK7K51.1 228.32,188.69 UNK7RK51.1
N18736377: length 1.5
  BOTTOM w0.203: UNK7K52.1 229.12,178.99 UNK7RK52.1
N18736441: length 1.5
  BOTTOM w0.203: UNK7K57.1 237.71,176.76 UNK7RK55.2
N18736442: length 1.5
  BOTTOM w0.203: UNK7K58.1 235.68,176.76 UNK7RK56.2
N18736443: length 1.5
  BOTTOM w0.203: UNK7RK57.2 232.63,176.76 UNK7K59.1
N18736444: length 1.5
  BOTTOM w0.203: UNK7K60.1 230.6,176.76 UNK7RK58.2
N18736447: length 1.5
  BOTTOM w0.203: UNK7RK61.1 207.86,231.95 UNK7K61.1
N18737578: length 2.2
  BOTTOM w0.635: UNK8C48.1 UNK8K2.3
N18737587: length 6.9
  BOTTOM w0.635: UNK8C49.1 256.27,213.81 256.91,214.45 UNK8K3.3
N18737596: length 1.5
  BOTTOM w0.508: UNK8C50.1 UNK8K5.3
N18737629: length 1.5
  BOTTOM w0.203: UNK8K7.1 257.77,203.76 UNK8RK7.1
N18737636: length 1.5
  BOTTOM w0.203: UNK8C53.1 262.14,202.02 UNK8K8.3
N18737645: length 1.5
  BOTTOM w0.203: UNK8C54.1 256.42,202.02 UNK8K9.3
N18737675: length 6.9
  BOTTOM w0.508: 262.67,193.35 UNK8K12.3
  BOTTOM w0.635: 262.67,193.35 262.22,192.9 262.22,190.8 260.59,189.17 UNK8C59.1
N18737682: length 1.5
  BOTTOM w0.203: UNK8K13.3 263.36,188.69 UNK8R1.1
N18737700: length 25.6
  BOTTOM w0.203: v2(267.45,205.74) 263.32,201.61 263.32,200.79 261.35,198.83 261.35,191.59 258.34,188.58 258.34,186.04 UNK8K15.6
N18737718: length 1.5
  BOTTOM w0.203: UNK8RK5.1 257.77,208.59 UNK8K5.1
N18737720: length 1.5
  BOTTOM w0.203: UNK8K6.1 257.77,205.79 UNK8RK6.1
N18737722: length 1.5
  BOTTOM w0.203: UNK8K8.1 257.77,201.22 UNK8RK8.1
N18737723: length 1.5
  BOTTOM w0.203: UNK8K9.1 252.05,201.22 UNK8RK9.1
N18737724: length 1.5
  BOTTOM w0.203: UNK8RK10.1 253.2,203.76 UNK8K10.1
N18737725: length 1.5
  BOTTOM w0.203: UNK8RK11.1 264.16,195.12 UNK8K11.1
N18737728: length 1.3
  BOTTOM w0.508: UNK8C58.1 UNK8K11.3
N18737731: length 1.5
  BOTTOM w0.203: UNK8RK12.1 264.16,190.29 UNK8K12.1
N18737733: length 1.5
  BOTTOM w0.203: UNK8RK13.1 264.16,184.32 UNK8K13.1
N18737736: length 1.5
  BOTTOM w0.203: UNK8RK14.1 266.96,190.29 UNK8K14.1
N18737738: length 3.4
  BOTTOM w0.203: UNK8RK2.1 262.47,223.73 262.87,223.32 UNK8K2.1
N18737739: length 1.9
  BOTTOM w0.203: UNK8K3.1 UNK8RK3.1
N18737740: length 2.4
  BOTTOM w0.203: UNK8K4.1 262.87,236.1 262.04,236.93 UNK8RK4.1
N18737760: length 27.9
  TOP w0.305: SITE8.8_F 266.71,205.4
  TOP w0.635: UNK8K15.3 255.29,186.19 255.29,187.82 255.89,188.41 257.92,188.41 265.16,195.65 265.16,203.85 266.71,205.4
N18737772: length 1.5
  BOTTOM w0.203: UNK8C60.1 UNK8K16.3
N18737785: length 1.5
  BOTTOM w0.203: UNK8RK17.1 269.12,195.12 UNK8K17.1
N18737799: length 1.5
  BOTTOM w0.203: UNK8K16.1 266.96,195.12 UNK8RK16.1
N18737803: length 1.5
  BOTTOM w0.203: UNK8RK18.1 269.12,190.29 UNK8K18.1
N18738953: length 1.5
  BOTTOM w0.203: UNK8C69.1 UNK8K19.3
N18738980: length 1.5
  BOTTOM w0.203: UNK8K19.1 271.91,195.12 UNK8RK19.1
N18738982: length 1.5
  BOTTOM w0.203: UNK8RK20.1 271.91,190.29 UNK8K20.1
N18738983: length 1.5
  BOTTOM w0.203: UNK8K21.1 274.07,195.12 UNK8RK21.1
N18739008: length 1.5
  BOTTOM w0.203: UNK8K22.1 274.07,190.29 UNK8RK22.1
N18739014: length 24.1
  BOTTOM w0.203: 274.38,184.3 273.24,185.44 273.24,187.49 274.81,189.07 274.81,199.97 270.3,204.48 v2(270.3,205.39)
N18739028: length 28.6
  BOTTOM w0.203: 282.64,184.3 281.15,185.78 281.15,188.53 280.21,189.48 275.8,189.48 275.32,189.96 275.32,200.22 270.8,204.74 v2(270.8,205.39)
N18739038: length 1.5
  BOTTOM w0.203: UNK8C62.1 UNK8K25.3
N18739056: length 1.5
  BOTTOM w0.203: UNK8RK25.1 277.37,195.12 UNK8K25.1
N18739060: length 1.5
  BOTTOM w0.203: UNK8RK26.1 277.37,190.29 UNK8K26.1
N18739065: length 1.5
  BOTTOM w0.203: UNK8C63.1 UNK8K27.3
N18739081: length 1.5
  BOTTOM w0.203: UNK8RK28.1 286.9,201.77 UNK8K28.1
N18739102: length 1.5
  BOTTOM w0.203: UNK8K27.1 282.33,201.77 UNK8RK27.1
N18739104: length 1.1
  BOTTOM w0.203: UNK8RK29.1 UNK8K29.1
N18739109: length 1.5
  BOTTOM w0.203: UNK8C61.1 UNK8K30.3
N18739123: length 1.5
  BOTTOM w0.203: UNK8K31.1 286.9,205.58 UNK8RK31.1
N18739143: length 1.5
  BOTTOM w0.203: UNK8K30.1 282.33,205.58 UNK8RK30.1
N18739146: length 1.1
  BOTTOM w0.203: UNK8RK32.1 UNK8K32.1
N18739148: length 1.5
  BOTTOM w0.203: UNK8K35.1 291.48,208.62 UNK8RK35.1
N18739150: length 1.5
  BOTTOM w0.203: UNK8RK34.1 286.9,208.62 UNK8K34.1
N18739152: length 1.5
  BOTTOM w0.203: UNK8K33.1 282.33,208.62 UNK8RK33.1
N18739155: length 1.5
  BOTTOM w0.203: UNK8C64.1 UNK8K33.3
N18739190: length 1.5
  BOTTOM w0.203: UNK8RK37.1 286.9,211.67 UNK8K37.1
N18739191: length 1.5
  BOTTOM w0.203: UNK8RK36.1 282.33,211.67 UNK8K36.1
N18739197: length 1.5
  BOTTOM w0.203: UNK8C65.1 UNK8K36.3
N18740483: length 1.5
  BOTTOM w0.203: UNK8RK39.1 286.9,214.21 UNK8K39.1
N18740484: length 1.5
  BOTTOM w0.203: UNK8RK38.1 282.33,214.21 UNK8K38.1
N18740490: length 1.5
  BOTTOM w0.203: UNK8C74.1 UNK8K38.3
N18740509: length 1.5
  BOTTOM w0.203: UNK8K40.1 275.17,215.24 UNK8RK40.1
N18740522: length 1.5
  BOTTOM w0.203: UNK8RK41.1 275.17,219.81 UNK8K41.1
N18740535: length 1.5
  BOTTOM w0.203: UNK8K42.1 275.17,224.38 UNK8RK42.1
N18740547: length 1.5
  BOTTOM w0.203: UNK8K43.1 272.25,215.24 UNK8RK43.1
N18740560: length 1.5
  BOTTOM w0.203: UNK8K45.1 272.25,225.65 UNK8RK45.1
N18740561: length 1.5
  BOTTOM w0.203: UNK8RK44.1 272.25,221.08 UNK8K44.1
N18740571: length 1.5
  BOTTOM w0.203: UNK8K44.3 273.05,216.71 UNK8C66.1
N18740589: length 1.5
  BOTTOM w0.203: UNK8RK46.1 269.84,216.76 UNK8K46.1
N18740605: length 1.5
  BOTTOM w0.203: UNK8C67.1 270.64,218.23 UNK8K47.3
N18740618: length 1.5
  BOTTOM w0.203: UNK8K48.1 269.84,227.17 UNK8RK48.1
N18740619: length 1.5
  BOTTOM w0.203: UNK8K47.1 269.84,222.6 UNK8RK47.1
N18740629: length 1.5
  BOTTOM w0.203: UNK8C68.1 268.23,222.8 UNK8K49.3
N18740642: length 1.5
  BOTTOM w0.203: UNK8RK50.1 267.43,221.33 UNK8K50.1
N18740643: length 1.5
  BOTTOM w0.203: UNK8RK49.1 267.43,227.17 UNK8K49.1
N18741457: length 1.3
  BOTTOM w0.203: UNK8R7.2 268.32,184.45 UNK8K51.4
N18741469: length 1.3
  BOTTOM w0.203: UNK8K53.4 276.57,184.45 UNK8R8.2
N18741471: length 1.5
  BOTTOM w0.203: UNK8K53.1 276.57,188.69 UNK8RK53.1
N18741493: length 2.3
  BOTTOM w0.203: v1(246.61,234.24) UNK8R11.2 UNK8R19.1
N18741505: length 2.3
  BOTTOM w0.203: v1(253.21,234.24) UNK8R14.2 UNK8R20.1
N18741515: length 1.5
  BOTTOM w0.203: UNK8K55.1 241.26,231.95 UNK8RK59.1
N18741518: length 1.3
  BOTTOM w0.508: UNK8R19.2 UNK8K55.4
N18741520: length 3
  BOTTOM w0.305: UNK8RK60.1 UNK8K56.1
N18741537: length 3.4
  BOTTOM w0.203: UNK8TP_IN-_3.1 278.51,172.74 278.31,172.54 UNK8R16.1 277.41,171.32 UNK8U3.8
N18741538: length 3.4
  BOTTOM w0.203: UNK8U3.7 276.81,171.32 UNK8R16.2 275.89,172.54 275.68,172.74 UNK8TP_IN+_3.1
N18741566: length 3.4
  BOTTOM w0.203: UNK8TP_IN+_4.1 270.6,172.74 270.81,172.54 UNK8R18.2 271.73,171.32 UNK8U4.7
N18741570: length 3.4
  BOTTOM w0.203: UNK8U4.8 272.33,171.32 UNK8R18.1 273.23,172.54 273.43,172.74 UNK8TP_IN-_4.1
N18741581: length 7.5
  BOTTOM w0.508: UNK8K56.4 251.43,227.4 250.92,227.91 UNK8K61.4 UNK8R20.2
N18741582: length 1.5
  BOTTOM w0.203: UNK8RK54.1 277.37,178.99 UNK8K54.1
N18741586: length 1.5
  BOTTOM w0.203: UNK8K51.1 268.32,188.69 UNK8RK51.1
N18741588: length 1.5
  BOTTOM w0.203: UNK8K52.1 269.12,178.99 UNK8RK52.1
N18741652: length 1.5
  BOTTOM w0.203: UNK8K57.1 277.71,176.76 UNK8RK55.2
N18741653: length 1.5
  BOTTOM w0.203: UNK8K58.1 275.68,176.76 UNK8RK56.2
N18741654: length 1.5
  BOTTOM w0.203: UNK8K59.1 272.63,176.76 UNK8RK57.2
N18741655: length 1.5
  BOTTOM w0.203: UNK8K60.1 270.6,176.76 UNK8RK58.2
N18741658: length 1.5
  BOTTOM w0.203: UNK8RK61.1 247.86,231.95 UNK8K61.1

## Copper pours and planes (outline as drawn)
GND on L02_GND: 74.68,440.23 75.62,441.6 75.95,443.23 75.95,471.81 76.58,473.33 78.11,473.96 341,473.96 342.52,473.33 343.15,471.81 343.15,443.23 343.48,441.6 344.42,440.23 354.58,430.35 354.58,405.13 359.72,392.74 372.11,387.6 412.75,387.6 416.52,386.04 418.08,382.27 418.08,92.71 416.52,88.94 412.75,87.38 372.11,87.38 359.72,82.24 354.58,69.85 354.58,44.63 344.42,34.76 343.48,33.38 343.15,31.75 343.15,3.18 342.52,1.65 341,1.02 78.11,1.02 76.58,1.65 75.95,3.18 75.95,31.75 75.62,33.38 74.68,34.76 64.52,44.63 64.52,69.85 59.38,82.24 46.99,87.38 6.35,87.38 2.58,88.94 1.02,92.71 1.02,382.27 2.58,386.04 6.35,387.6 46.99,387.6 59.38,392.74 64.52,405.13 64.52,430.35
S1_SRD_F on BOTTOM: 144.15,273.94 142.11,273.94 140.97,272.8 138.18,272.8 138.05,272.67 138.05,270.38 138.18,270.26 143.13,270.26 144.29,269.09 147.12,269.09 147.2,269.17 147.2,269.75 146.93,270.02 146.93,271.03 146.18,271.78 144.53,271.78 144.3,272 144.3,273.79
